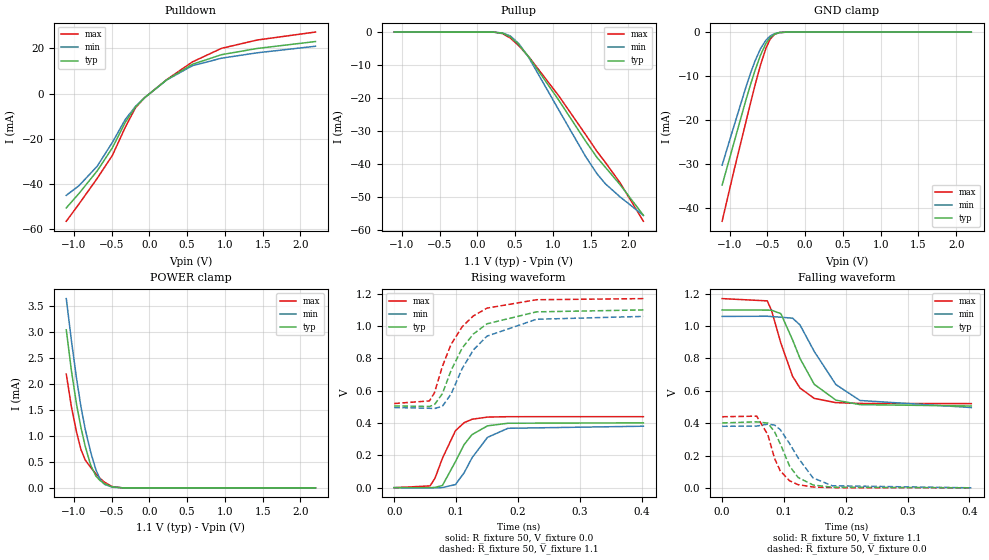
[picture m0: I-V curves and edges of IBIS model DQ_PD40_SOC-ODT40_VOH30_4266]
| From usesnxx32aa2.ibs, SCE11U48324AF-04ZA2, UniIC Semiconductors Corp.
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| DQ_PD40_SOC-ODT40_VOH30_4266
| (40 Ohm Pulldown, 40 Ohm System ODT Setting, VOH=VDDQ/3.0, 3200-4266Mbps)
[Model]   DQ_PD40_SOC-ODT40_VOH30_4266
Model_type   I/O
Vinl = 123.333mV
Vinh = 243.333mV
Vmeas = 183.333mV
Vref = 0.0mV
Cref = 0.0pF
Rref = 40.000Ohm
|   typ   min   max
|C_comp   0.797pF   0.747pF   0.847pF
C_comp_pullup   0.3985pF   0.3735pF   0.4235pF
C_comp_pulldown   0.3985pF   0.3735pF   0.4235pF
| Note: C_comp changes when the ODT circuit is enabled.
[Model Spec]
| Input threshold voltage corners
Vinl   0.1233V   0.1167V   0.1350V
Vinh   0.2433V   0.2367V   0.2550V
| Measurement voltage corners
Vmeas   0.1833V   0.1767V   0.1950V
| Timing spec test load voltage corners
Vref   0.0000V   0.0000V   0.0000V
| Dynamic Overshoot Parameters from LPDDR4 Specification
D_overshoot_ampl_h   0.30   NA   NA
D_overshoot_ampl_l   0.30   NA   NA
D_overshoot_area_h   0.1n   NA   NA
D_overshoot_area_l   0.1n   NA   NA
[Receiver Thresholds]
Vth   = 0.1833V
Vth_min  = 0.1800V
Vth_max  = 0.1866V
Vinh_ac  = 0.060V
Vinh_dc  = 0.060V
Vinl_ac  = -0.060V
Vinl_dc  = -0.060V
Tslew_ac = 5.000ns |Not specified, so set to high value
Threshold_sensitivity = 0.1667
Reference_supply Pullup_ref
[Voltage Range]   1.1000V   1.0600V   1.1700V
[Pullup Reference]   1.1000V   1.0600V   1.1700V
| Junction Temperature (Ambient temp is 35C typ 95C min -40C max)
[Temperature Range]   50.0   110.0   -40.0
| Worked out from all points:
|   slope of the pulldown table from 0 to 0.165 V, typ, clamps not added: 36.9 ohm
|   slope of the pullup table from 0 to 0.165 V, typ, clamps not added: 13 kohm
|   GND clamp passes 1 mA (typ) near -0.45 V on its own axis
|   POWER clamp passes 1 mA (typ) near -0.88 V on its own axis
|   rising waveform, R_fixture 50, V_fixture 0.0: 20-80 % time 34.1ps typ, 38.1ps min, 29.6ps max; typ from 0.001 V to 0.401 V
|   falling waveform, R_fixture 50, V_fixture 1.1: 20-80 % time 45ps typ, 56.8ps min, 35.2ps max; typ from 1.1 V to 0.506 V
|   rising waveform, R_fixture 50, V_fixture 1.1: 20-80 % time 54.7ps typ, 58ps min, 50.4ps max; typ from 0.506 V to 1.1 V
|   falling waveform, R_fixture 50, V_fixture 0.0: 20-80 % time 30.5ps typ, 38.6ps min, 25.1ps max; typ from 0.402 V to 0.001 V
[Pulldown]
|   Voltage   I(typ)   I(min)   I(max)
-1.1V     -50.63mA   -45.08mA   -56.55mA
-931.7mV  -44.24mA   -40.8mA    -48.89mA
-690.8mV  -34.25mA   -32.2mA    -37.57mA
-489.5mV  -24.03mA   -21.64mA   -27.4mA
-317.9mV  -12.7mA    -11.44mA   -14.85mA
-182.6mV  -5.878mA   -5.686mA   -6.271mA
-63.8mV   -1.902mA   -1.889mA   -1.878mA
229.9mV   6.074mA    5.999mA    6.158mA
569.8mV   12.93mA    12.3mA     13.98mA
955.9mV   17.19mA    15.64mA    20mA
1.428V    19.94mA    18.02mA    23.68mA
2.2V      23.01mA    20.92mA    27.21mA
[GND Clamp]
|   Voltage   I(typ)   I(min)   I(max)
-1.1V     -34.88mA   -30.34mA   -43.13mA
-938.3mV  -24.92mA   -21.15mA   -31.24mA
-786.5mV  -15.59mA   -12.65mA   -20.59mA
-723.8mV  -11.98mA   -9.381mA   -16.18mA
-664.4mV  -8.768mA   -6.598mA   -12.12mA
-591.8mV  -5.271mA   -3.798mA   -7.524mA
-519.2mV  -2.572mA   -1.839mA   -3.672mA
-466.4mV  -1.299mA   -945.1uA   -1.693mA
-407mV    -503.4uA   -374.2uA   -541.5uA
-341mV    -134.1uA   -102.3uA   -114.6uA
-232.1mV  -7.507uA   -7.153uA   -3.987uA
2.2V      0A         0A         0A
[Pullup]
|   Voltage   I(typ)   I(min)   I(max)
-1.1V     6.284uA    9.684uA    2.832uA
226.6mV   -42.49uA   -43.11uA   -42.83uA
335.5mV   -341.1uA   -283.4uA   -469.8uA
437.8mV   -1.438mA   -1.179mA   -1.809mA
550mV     -3.801mA   -3.492mA   -4.138mA
682mV     -7.523mA   -7.706mA   -7.473mA
1.078V    -20.57mA   -23.52mA   -19.26mA
1.434V    -32.99mA   -37.64mA   -31.01mA
1.586V    -37.97mA   -42.9mA    -36.14mA
1.698V    -40.96mA   -45.96mA   -39.5mA
1.893V    -46.24mA   -49.93mA   -45.68mA
2.2V      -55.46mA   -55.5mA    -57.28mA
[POWER Clamp]
|   Voltage   I(typ)   I(min)   I(max)
-1.1V     3.036mA    3.636mA    2.186mA
-1.031V   2.241mA    2.818mA    1.547mA
-964.7mV  1.61mA     2.107mA    1.073mA
-905.3mV  1.155mA    1.555mA    732.4uA
-849.2mV  799.3uA    1.126mA    535.5uA
-776.6mV  434.2uA    683.5uA    390.2uA
-707.3mV  225.6uA    345.4uA    267.6uA
-654.5mV  142.7uA    170.5uA    185.9uA
-595.1mV  80.77uA    68.3uA     109.3uA
-492.8mV  18.95uA    11.55uA    24.07uA
-360.8mV  1.023uA    778nA      803.1nA
2.2V      0A         0A         0A
[Ramp]
|   typ   min   max
| 20% - 80%
dV/dt_r   240.53m/34.08p   228.08m/38.10p   263.57m/29.60p
dV/dt_f   356.25m/45.04p   337.96m/56.80p   389.47m/35.24p
| 25% - 75%
|dV/dt_r   200.44m/27.14p   190.07m/30.34p   219.65m/23.43p
|dV/dt_f   296.88m/35.94p   281.63m/45.36p   324.56m/28.04p
R_load = 50
[Rising Waveform]
R_fixture = 50
V_fixture = 0.0
|   Time   V(typ)   V(min)   V(max)
0s        552uV      472.8uV    402uV
58ps      324.9uV    -47.1uV    11.28mV
66ps      2.285mV    -594.8uV   58.93mV
78ps      13.98mV    984.2uV    182.4mV
99ps      161mV      19.65mV    352.3mV
113ps     266.6mV    92mV       402.2mV
126ps     329.2mV    186mV      423.8mV
151ps     382.9mV    311.9mV    437.1mV
184ps     399mV      367.7mV    439.5mV
403ps     401.4mV    380.6mV    439.7mV
[Falling Waveform]
R_fixture   = 50
V_fixture   = 1.1
V_fixture_min = 1.06
V_fixture_max = 1.17
|   Time   V(typ)   V(min)   V(max)
0s        1.1V       1.06V      1.17V
73ps      1.099V     1.061V     1.156V
80ps      1.098V     1.059V     1.096V
95ps      1.077V     1.055V     894.7mV
114ps     914.4mV    1.049V     689.6mV
126ps     799.7mV    1.007V     617.1mV
149ps     640.4mV    843.4mV    553.2mV
184ps     542.5mV    638.7mV    527mV
223ps     514.6mV    540.3mV    521.9mV
403ps     506.2mV    496.7mV    520.9mV
[Rising Waveform]
R_fixture   = 50
V_fixture   = 1.1
V_fixture_min = 1.06
V_fixture_max = 1.17
|   Time   V(typ)   V(min)   V(max)
0s        506.1mV    496.4mV    520.9mV
57ps      502.9mV    491.6mV    537.1mV
65ps      513mV      489.4mV    586.4mV
78ps      582.2mV    504.2mV    751.5mV
92ps      725.8mV    579.7mV    887.1mV
110ps     864.4mV    737.4mV    996.2mV
128ps     950.8mV    852.1mV    1.063V
150ps     1.014V     937.6mV    1.111V
230ps     1.088V     1.042V     1.163V
403ps     1.1V       1.06V      1.17V
[Falling Waveform]
R_fixture = 50
V_fixture = 0.0
|   Time   V(typ)   V(min)   V(max)
0s        401.5mV    380.8mV    439.8mV
56ps      408.2mV    382.1mV    443.5mV
74ps      400.5mV    394.3mV    328.1mV
85ps      345.4mV    388.2mV    180.8mV
94ps      273mV      360.3mV    105.9mV
109ps     135.8mV    274.6mV    44.05mV
123ps     64.01mV    185.3mV    19.98mV
147ps     18mV       62mV       5.51mV
178ps     4.155mV    13.24mV    1.377mV
403ps     604uV      548.3uV    424.2uV
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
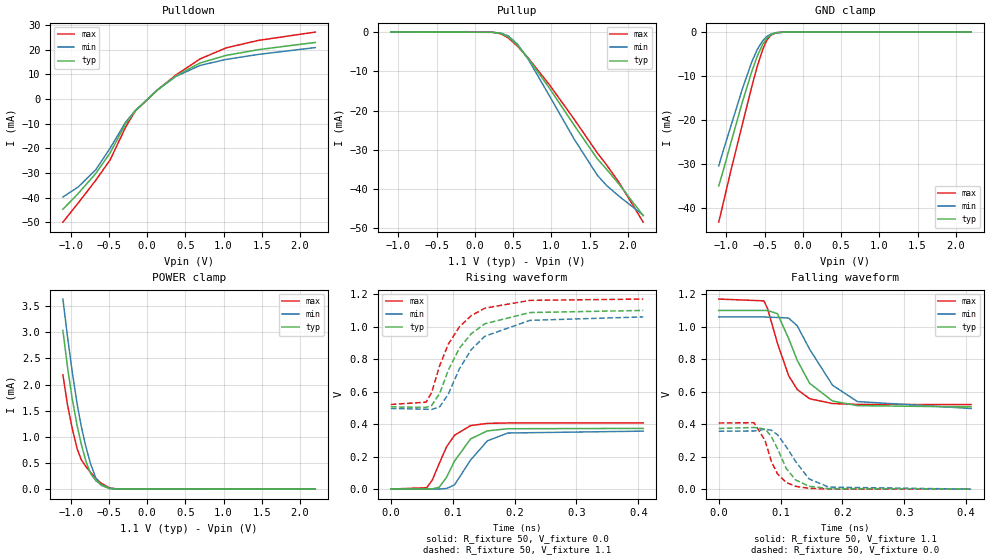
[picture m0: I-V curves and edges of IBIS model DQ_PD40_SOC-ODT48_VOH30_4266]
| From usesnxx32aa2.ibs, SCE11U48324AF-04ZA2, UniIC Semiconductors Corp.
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| DQ_PD40_SOC-ODT48_VOH30_4266
| (40 Ohm Pulldown, 48 Ohm System ODT Setting, VOH=VDDQ/3.0, 3200-4266Mbps)
[Model]   DQ_PD40_SOC-ODT48_VOH30_4266
Model_type   I/O
Vinl = 123.333mV
Vinh = 243.333mV
Vmeas = 183.333mV
Vref = 0.0mV
Cref = 0.0pF
Rref = 48.000Ohm
|   typ   min   max
|C_comp   0.797pF   0.747pF   0.847pF
C_comp_pullup   0.3985pF   0.3735pF   0.4235pF
C_comp_pulldown   0.3985pF   0.3735pF   0.4235pF
| Note: C_comp changes when the ODT circuit is enabled.
[Model Spec]
| Input threshold voltage corners
Vinl   0.1233V   0.1167V   0.1350V
Vinh   0.2433V   0.2367V   0.2550V
| Measurement voltage corners
Vmeas   0.1833V   0.1767V   0.1950V
| Timing spec test load voltage corners
Vref   0.0000V   0.0000V   0.0000V
| Dynamic Overshoot Parameters from LPDDR4 Specification
D_overshoot_ampl_h   0.30   NA   NA
D_overshoot_ampl_l   0.30   NA   NA
D_overshoot_area_h   0.1n   NA   NA
D_overshoot_area_l   0.1n   NA   NA
[Receiver Thresholds]
Vth   = 0.1833V
Vth_min  = 0.1800V
Vth_max  = 0.1866V
Vinh_ac  = 0.060V
Vinh_dc  = 0.060V
Vinl_ac  = -0.060V
Vinl_dc  = -0.060V
Tslew_ac = 5.000ns |Not specified, so set to high value
Threshold_sensitivity = 0.1667
Reference_supply Pullup_ref
[Voltage Range]   1.1000V   1.0600V   1.1700V
[Pullup Reference]   1.1000V   1.0600V   1.1700V
| Junction Temperature (Ambient temp is 35C typ 95C min -40C max)
[Temperature Range]   50.0   110.0   -40.0
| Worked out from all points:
|   slope of the pulldown table from 0 to 0.165 V, typ, clamps not added: 36.9 ohm
|   slope of the pullup table from 0 to 0.165 V, typ, clamps not added: 15.6 kohm
|   GND clamp passes 1 mA (typ) near -0.45 V on its own axis
|   POWER clamp passes 1 mA (typ) near -0.88 V on its own axis
|   rising waveform, R_fixture 50, V_fixture 0.0: 20-80 % time 35.5ps typ, 39.8ps min, 31.3ps max; typ from 0 V to 0.374 V
|   falling waveform, R_fixture 50, V_fixture 1.1: 20-80 % time 44.9ps typ, 56.6ps min, 35.1ps max; typ from 1.1 V to 0.506 V
|   rising waveform, R_fixture 50, V_fixture 1.1: 20-80 % time 54.9ps typ, 58.4ps min, 50.5ps max; typ from 0.506 V to 1.1 V
|   falling waveform, R_fixture 50, V_fixture 0.0: 20-80 % time 30.3ps typ, 38.5ps min, 24.9ps max; typ from 0.374 V to 0.001 V
[Pulldown]
|   Voltage   I(typ)   I(min)   I(max)
-1.1V     -44.75mA   -39.77mA   -50mA
-902mV    -38.42mA   -35.75mA   -42.29mA
-671mV    -30.26mA   -28.72mA   -33.02mA
-482.9mV  -21.87mA   -19.96mA   -24.7mA
-278.3mV  -9.972mA   -9.272mA   -11.31mA
-156.2mV  -4.822mA   -4.735mA   -4.963mA
137.5mV   3.741mA    3.714mA    3.748mA
375.1mV   9.367mA    9.149mA    9.729mA
695.2mV   14.68mA    13.69mA    16.33mA
1.035V    17.75mA    16.11mA    20.81mA
1.458V    20.08mA    18.15mA    23.85mA
2.2V      23.01mA    20.92mA    27.21mA
[GND Clamp]
|   Voltage   I(typ)   I(min)   I(max)
-1.1V     -34.88mA   -30.35mA   -43.13mA
-1.047V   -31.79mA   -27.25mA   -39.23mA
-941.6mV  -25.13mA   -21.34mA   -31.48mA
-789.8mV  -15.79mA   -12.83mA   -20.82mA
-667.7mV  -8.939mA   -6.742mA   -12.34mA
-595.1mV  -5.415mA   -3.908mA   -7.721mA
-525.8mV  -2.776mA   -1.982mA   -3.978mA
-473mV    -1.427mA   -1.034mA   -1.891mA
-416.9mV  -602.3uA   -443.1uA   -664.2uA
-350.9mV  -167uA     -127uA     -146.8uA
-235.4mV  -8.314uA   -7.865uA   -4.406uA
2.2V      0A         0A         0A
[Pullup]
|   Voltage   I(typ)   I(min)   I(max)
-1.1V     5.237uA    8.07uA     2.361uA
229.9mV   -37.74uA   -38.67uA   -38.87uA
345.4mV   -338.1uA   -276.7uA   -463.3uA
441.1mV   -1.249mA   -1.027mA   -1.564mA
556.6mV   -3.33mA    -3.082mA   -3.598mA
698.5mV   -6.745mA   -6.992mA   -6.645mA
975.7mV   -14.36mA   -16.29mA   -13.47mA
1.302V    -23.86mA   -27.41mA   -22.33mA
1.599V    -32.26mA   -36.44mA   -30.76mA
1.718V    -34.88mA   -39.02mA   -33.75mA
1.89V     -38.9mA    -41.91mA   -38.47mA
2.2V      -46.77mA   -46.64mA   -48.43mA
[POWER Clamp]
|   Voltage   I(typ)   I(min)   I(max)
-1.1V     3.036mA    3.636mA    2.186mA
-1.041V   2.347mA    2.931mA    1.626mA
-977.9mV  1.724mA    2.242mA    1.161mA
-911.9mV  1.201mA    1.612mA    764.9uA
-859.1mV  857.7uA    1.196mA    561.5uA
-799.7mV  537uA      814.2uA    433.5uA
-740.3mV  306uA      494.6uA    324.3uA
-667.7mV  159.9uA    206.1uA    205.2uA
-598.4mV  83.69uA    71.98uA    113.1uA
-489.5mV  17.77uA    10.88uA    22.46uA
-367.4mV  1.206uA    882.7nA    945.9nA
2.2V      0A         0A         0A
[Ramp]
|   typ   min   max
| 20% - 80%
dV/dt_r   223.90m/35.46p   213.85m/39.83p   244.14m/31.25p
dV/dt_f   356.25m/44.91p   337.96m/56.63p   389.46m/35.14p
| 25% - 75%
|dV/dt_r   186.58m/28.28p   178.21m/31.81p   203.45m/24.74p
|dV/dt_f   296.88m/35.84p   281.63m/45.22p   324.55m/27.97p
R_load = 50
[Rising Waveform]
R_fixture = 50
V_fixture = 0.0
|   Time   V(typ)   V(min)   V(max)
0s        456.7uV    387.9uV    333.9uV
58ps      167.4uV    71.29uV    8.2mV
67ps      1.536mV    -515.2uV   55.39mV
78ps      10.94mV    268.4uV    155.1mV
90ps      71.57mV    3.334mV    259.2mV
103ps     172.9mV    26.05mV    331.8mV
129ps     309.1mV    179.2mV    391.1mV
156ps     358.2mV    296.8mV    404.6mV
189ps     371.6mV    345.2mV    407mV
408ps     373.6mV    356.8mV    407.2mV
[Falling Waveform]
R_fixture   = 50
V_fixture   = 1.1
V_fixture_min = 1.06
V_fixture_max = 1.17
|   Time   V(typ)   V(min)   V(max)
0s        1.1V       1.06V      1.17V
73ps      1.1V       1.06V      1.159V
79ps      1.1V       1.059V     1.111V
95ps      1.08V      1.057V     896.9mV
113ps     926.9mV    1.053V     698.6mV
127ps     792.4mV    1.005V     613.2mV
147ps     651.4mV    861mV      556.6mV
184ps     542.7mV    639.8mV    527.1mV
224ps     514.3mV    539.4mV    521.9mV
408ps     506.2mV    496.7mV    520.9mV
[Rising Waveform]
R_fixture   = 50
V_fixture   = 1.1
V_fixture_min = 1.06
V_fixture_max = 1.17
|   Time   V(typ)   V(min)   V(max)
0s        506.1mV    496.4mV    520.9mV
57ps      502.9mV    491.8mV    535.3mV
66ps      514.7mV    489.7mV    593.9mV
79ps      589mV      506.5mV    760.5mV
93ps      732.6mV    585.3mV    892.6mV
111ps     868mV      741.6mV    999.6mV
130ps     956.5mV    858.8mV    1.068V
152ps     1.018V     941.2mV    1.114V
225ps     1.087V     1.039V     1.162V
408ps     1.1V       1.06V      1.17V
[Falling Waveform]
R_fixture = 50
V_fixture = 0.0
|   Time   V(typ)   V(min)   V(max)
0s        373.7mV    356.9mV    407.3mV
57ps      379.9mV    358.4mV    409.5mV
75ps      370.5mV    368.6mV    298.9mV
85ps      324.8mV    363.4mV    171.1mV
95ps      249.6mV    335.5mV    94.45mV
109ps     128.8mV    262.5mV    41.88mV
124ps     57.68mV    172.2mV    17.96mV
146ps     18.11mV    63.28mV    5.508mV
178ps     3.943mV    12.94mV    1.272mV
408ps     517.9uV    474uV      357.5uV
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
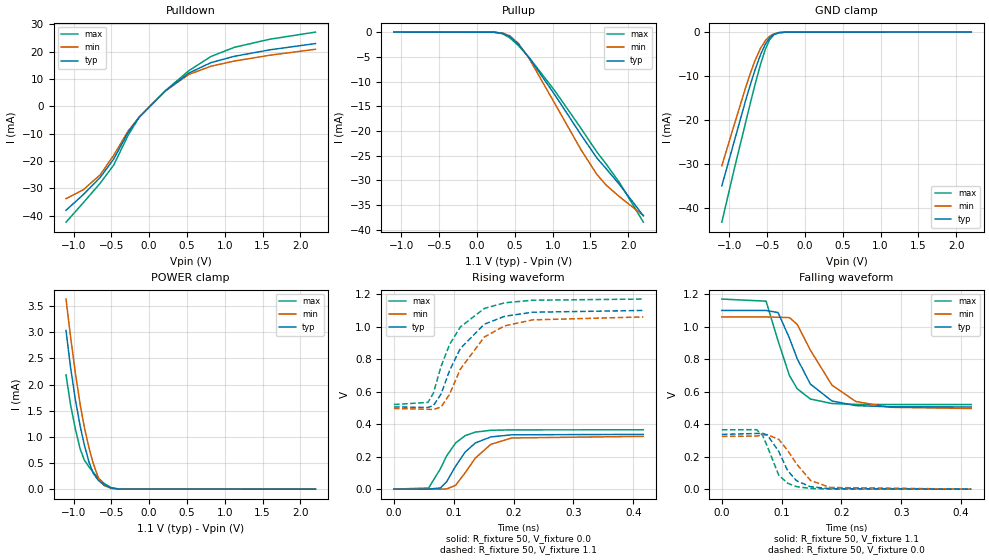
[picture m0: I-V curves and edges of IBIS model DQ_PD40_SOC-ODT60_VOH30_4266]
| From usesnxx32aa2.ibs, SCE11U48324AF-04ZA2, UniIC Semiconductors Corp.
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| DQ_PD40_SOC-ODT60_VOH30_4266
| (40 Ohm Pulldown, 60 Ohm System ODT Setting, VOH=VDDQ/3.0, 3200-4266Mbps)
[Model]   DQ_PD40_SOC-ODT60_VOH30_4266
Model_type   I/O
Vinl = 123.333mV
Vinh = 243.333mV
Vmeas = 183.333mV
Vref = 0.0mV
Cref = 0.0pF
Rref = 60.000Ohm
|   typ   min   max
|C_comp   0.797pF   0.747pF   0.847pF
C_comp_pullup   0.3985pF   0.3735pF   0.4235pF
C_comp_pulldown   0.3985pF   0.3735pF   0.4235pF
| Note: C_comp changes when the ODT circuit is enabled.
[Model Spec]
| Input threshold voltage corners
Vinl   0.1233V   0.1167V   0.1350V
Vinh   0.2433V   0.2367V   0.2550V
| Measurement voltage corners
Vmeas   0.1833V   0.1767V   0.1950V
| Timing spec test load voltage corners
Vref   0.0000V   0.0000V   0.0000V
| Dynamic Overshoot Parameters from LPDDR4 Specification
D_overshoot_ampl_h   0.30   NA   NA
D_overshoot_ampl_l   0.30   NA   NA
D_overshoot_area_h   0.1n   NA   NA
D_overshoot_area_l   0.1n   NA   NA
[Receiver Thresholds]
Vth   = 0.1833V
Vth_min  = 0.1800V
Vth_max  = 0.1866V
Vinh_ac  = 0.060V
Vinh_dc  = 0.060V
Vinl_ac  = -0.060V
Vinl_dc  = -0.060V
Tslew_ac = 5.000ns |Not specified, so set to high value
Threshold_sensitivity = 0.1667
Reference_supply Pullup_ref
[Voltage Range]   1.1000V   1.0600V   1.1700V
[Pullup Reference]   1.1000V   1.0600V   1.1700V
| Junction Temperature (Ambient temp is 35C typ 95C min -40C max)
[Temperature Range]   50.0   110.0   -40.0
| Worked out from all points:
|   slope of the pulldown table from 0 to 0.165 V, typ, clamps not added: 36.9 ohm
|   slope of the pullup table from 0 to 0.165 V, typ, clamps not added: 19.5 kohm
|   GND clamp passes 1 mA (typ) near -0.45 V on its own axis
|   POWER clamp passes 1 mA (typ) near -0.88 V on its own axis
|   rising waveform, R_fixture 50, V_fixture 0.0: 20-80 % time 38.7ps typ, 42.6ps min, 34ps max; typ from 0 V to 0.337 V
|   falling waveform, R_fixture 50, V_fixture 1.1: 20-80 % time 44.8ps typ, 56.5ps min, 35ps max; typ from 1.1 V to 0.506 V
|   rising waveform, R_fixture 50, V_fixture 1.1: 20-80 % time 55.1ps typ, 59ps min, 50.6ps max; typ from 0.506 V to 1.1 V
|   falling waveform, R_fixture 50, V_fixture 0.0: 20-80 % time 29.9ps typ, 38.5ps min, 24.7ps max; typ from 0.337 V to 0 V
[Pulldown]
|   Voltage   I(typ)   I(min)   I(max)
-1.1V     -38.06mA   -33.82mA   -42.42mA
-872.3mV  -32.35mA   -30.55mA   -35.34mA
-647.9mV  -26.03mA   -25.08mA   -28.14mA
-469.7mV  -19.32mA   -17.94mA   -21.52mA
-278.3mV  -9.551mA   -9.031mA   -10.59mA
-133.1mV  -3.99mA    -3.961mA   -4.019mA
213.4mV   5.67mA     5.605mA    5.735mA
523.6mV   12.17mA    11.67mA    13.04mA
817.3mV   16.02mA    14.71mA    18.26mA
1.127V    18.34mA    16.61mA    21.63mA
1.599V    20.72mA    18.74mA    24.61mA
2.2V      23.01mA    20.92mA    27.21mA
[GND Clamp]
|   Voltage   I(typ)   I(min)   I(max)
-1.1V     -34.88mA   -30.34mA   -43.13mA
-941.6mV  -25.13mA   -21.34mA   -31.48mA
-786.5mV  -15.59mA   -12.65mA   -20.59mA
-720.5mV  -11.79mA   -9.218mA   -15.95mA
-661.1mV  -8.597mA   -6.455mA   -11.9mA
-588.5mV  -5.128mA   -3.689mA   -7.328mA
-522.5mV  -2.673mA   -1.908mA   -3.822mA
-469.7mV  -1.361mA   -989uA     -1.79mA
-413.6mV  -565.3uA   -419uA     -621.8uA
-347.6mV  -154.7uA   -117.8uA   -135.4uA
-251.9mV  -13.27uA   -12.05uA   -7.883uA
2.2V      0A         0A         0A
[Pullup]
|   Voltage   I(typ)   I(min)   I(max)
-1.1V     4.189uA    6.456uA    1.888uA
226.6mV   -28.16uA   -28.72uA   -28.57uA
338.8mV   -240.5uA   -199uA     -331.4uA
434.5mV   -926.4uA   -757uA     -1.172mA
546.7mV   -2.491mA   -2.281mA   -2.719mA
688.6mV   -5.181mA   -5.337mA   -5.127mA
1.032V    -12.75mA   -14.54mA   -11.93mA
1.375V    -20.76mA   -23.78mA   -19.46mA
1.586V    -25.47mA   -28.79mA   -24.26mA
1.708V    -27.61mA   -30.94mA   -26.67mA
1.887V    -30.87mA   -33.32mA   -30.49mA
2.2V      -37.14mA   -37.08mA   -38.43mA
[POWER Clamp]
|   Voltage   I(typ)   I(min)   I(max)
-1.1V     3.036mA    3.636mA    2.186mA
-1.041V   2.347mA    2.931mA    1.626mA
-977.9mV  1.724mA    2.242mA    1.161mA
-911.9mV  1.201mA    1.612mA    765uA
-855.8mV  838.1uA    1.172mA    552.2uA
-793.1mV  506.1uA    776.1uA    421uA
-740.3mV  306.1uA    494.5uA    324.3uA
-671mV    164.5uA    215.9uA    210.2uA
-598.4mV  83.67uA    71.97uA    113uA
-502.7mV  22.59uA    14.08uA    29.27uA
-397.1mV  2.384uA    1.603uA    2.113uA
2.2V      0A         0A         0A
[Ramp]
|   typ   min   max
| 20% - 80%
dV/dt_r   202.04m/38.70p   194.78m/42.60p   219.09m/34.00p
dV/dt_f   356.26m/44.80p   337.98m/56.46p   389.46m/35.05p
| 25% - 75%
|dV/dt_r   168.37m/30.87p   162.32m/34.03p   182.58m/26.96p
|dV/dt_f   296.88m/35.75p   281.65m/45.09p   324.55m/27.89p
R_load = 50
[Rising Waveform]
R_fixture = 50
V_fixture = 0.0
|   Time   V(typ)   V(min)   V(max)
0s        358.8uV    298.7uV    264.1uV
58ps      85.48uV    119uV      7.079mV
78ps      7.978mV    -35.59uV   127.3mV
88ps      45.03mV    1.331mV    204mV
103ps     140.8mV    23.2mV     283.8mV
119ps     227.9mV    100.5mV    329.2mV
136ps     284mV      190.9mV    351.1mV
162ps     321.6mV    275.8mV    362.3mV
197ps     334.6mV    315.2mV    365mV
417ps     337.1mV    324.9mV    365.4mV
[Falling Waveform]
R_fixture   = 50
V_fixture   = 1.1
V_fixture_min = 1.06
V_fixture_max = 1.17
|   Time   V(typ)   V(min)   V(max)
0s        1.1V       1.06V      1.17V
74ps      1.1V       1.06V      1.157V
94ps      1.087V     1.058V     912.5mV
113ps     929.3mV    1.056V     699.5mV
126ps     803.1mV    1.014V     618.1mV
148ps     647mV      855.8mV    555.1mV
184ps     542.9mV    640.7mV    527.1mV
224ps     514.4mV    539.6mV    521.9mV
281ps     507.2mV    503.9mV    521mV
417ps     506.2mV    496.7mV    520.9mV
[Rising Waveform]
R_fixture   = 50
V_fixture   = 1.1
V_fixture_min = 1.06
V_fixture_max = 1.17
|   Time   V(typ)   V(min)   V(max)
0s        506.1mV    496.4mV    520.9mV
57ps      502.9mV    491.9mV    534.1mV
66ps      514.1mV    489.8mV    591.5mV
79ps      587mV      506.2mV    757.5mV
93ps      729.8mV    583.7mV    889.9mV
111ps     865.6mV    738.4mV    998mV
151ps     1.015V     936mV      1.112V
185ps     1.064V     1.005V     1.147V
232ps     1.089V     1.042V     1.163V
417ps     1.1V       1.06V      1.17V
[Falling Waveform]
R_fixture = 50
V_fixture = 0.0
|   Time   V(typ)   V(min)   V(max)
0s        337.2mV    325mV      365.5mV
58ps      343mV      327mV      366.5mV
68ps      344.1mV    332.5mV    332mV
76ps      333.7mV    335.3mV    263.8mV
95ps      233.6mV    307mV      87.28mV
110ps     114.8mV    238.7mV    36.71mV
125ps     51.58mV    155.6mV    15.81mV
148ps     15.49mV    54.34mV    4.619mV
181ps     3.261mV    10.79mV    1.047mV
417ps     428.1uV    394.6uV    289.9uV
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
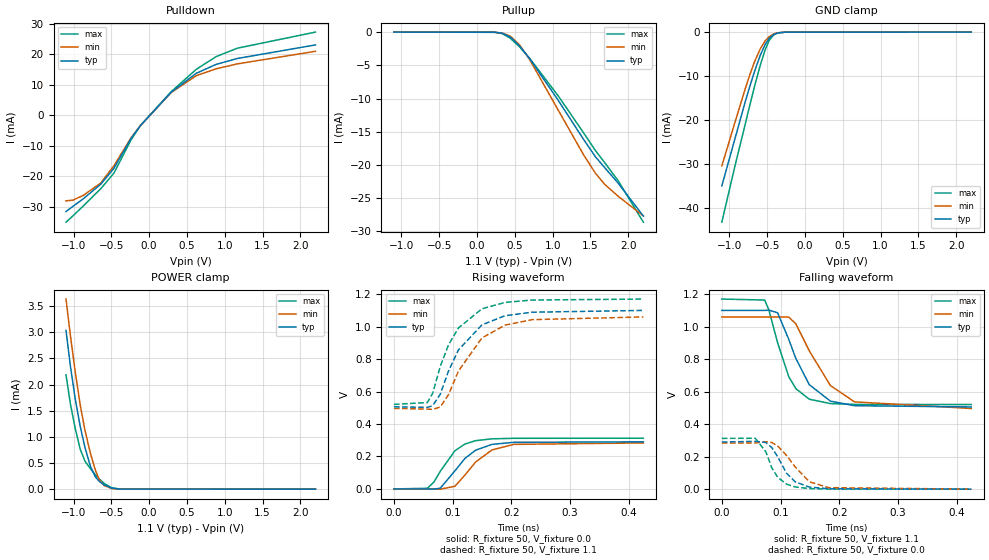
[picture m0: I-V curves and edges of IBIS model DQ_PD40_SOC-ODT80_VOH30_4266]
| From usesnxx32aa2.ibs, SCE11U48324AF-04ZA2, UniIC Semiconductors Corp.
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| DQ_PD40_SOC-ODT80_VOH30_4266
| (40 Ohm Pulldown, 80 Ohm System ODT Setting, VOH=VDDQ/3.0, 3200-4266Mbps)
[Model]   DQ_PD40_SOC-ODT80_VOH30_4266
Model_type   I/O
Vinl = 123.333mV
Vinh = 243.333mV
Vmeas = 183.333mV
Vref = 0.0mV
Cref = 0.0pF
Rref = 80.000Ohm
|   typ   min   max
|C_comp   0.797pF   0.747pF   0.847pF
C_comp_pullup   0.3985pF   0.3735pF   0.4235pF
C_comp_pulldown   0.3985pF   0.3735pF   0.4235pF
| Note: C_comp changes when the ODT circuit is enabled.
[Model Spec]
| Input threshold voltage corners
Vinl   0.1233V   0.1167V   0.1350V
Vinh   0.2433V   0.2367V   0.2550V
| Measurement voltage corners
Vmeas   0.1833V   0.1767V   0.1950V
| Timing spec test load voltage corners
Vref   0.0000V   0.0000V   0.0000V
| Dynamic Overshoot Parameters from LPDDR4 Specification
D_overshoot_ampl_h   0.30   NA   NA
D_overshoot_ampl_l   0.30   NA   NA
D_overshoot_area_h   0.1n   NA   NA
D_overshoot_area_l   0.1n   NA   NA
[Receiver Thresholds]
Vth   = 0.1833V
Vth_min  = 0.1800V
Vth_max  = 0.1866V
Vinh_ac  = 0.060V
Vinh_dc  = 0.060V
Vinl_ac  = -0.060V
Vinl_dc  = -0.060V
Tslew_ac = 5.000ns |Not specified, so set to high value
Threshold_sensitivity = 0.1667
Reference_supply Pullup_ref
[Voltage Range]   1.1000V   1.0600V   1.1700V
[Pullup Reference]   1.1000V   1.0600V   1.1700V
| Junction Temperature (Ambient temp is 35C typ 95C min -40C max)
[Temperature Range]   50.0   110.0   -40.0
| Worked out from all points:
|   slope of the pulldown table from 0 to 0.165 V, typ, clamps not added: 36.9 ohm
|   slope of the pullup table from 0 to 0.165 V, typ, clamps not added: 26 kohm
|   GND clamp passes 1 mA (typ) near -0.45 V on its own axis
|   POWER clamp passes 1 mA (typ) near -0.88 V on its own axis
|   rising waveform, R_fixture 50, V_fixture 0.0: 20-80 % time 42.1ps typ, 45.2ps min, 36.8ps max; typ from 0 V to 0.29 V
|   falling waveform, R_fixture 50, V_fixture 1.1: 20-80 % time 44.7ps typ, 56.3ps min, 35ps max; typ from 1.1 V to 0.506 V
|   rising waveform, R_fixture 50, V_fixture 1.1: 20-80 % time 55.3ps typ, 59.5ps min, 50.7ps max; typ from 0.506 V to 1.1 V
|   falling waveform, R_fixture 50, V_fixture 0.0: 20-80 % time 30.3ps typ, 39ps min, 25.2ps max; typ from 0.29 V to 0 V
[Pulldown]
|   Voltage   I(typ)   I(min)   I(max)
-1.1V     -31.52mA   -28.01mA   -35mA
-1.011V   -29.86mA   -27.81mA   -33mA
-872.3mV  -27.36mA   -26.24mA   -29.72mA
-641.3mV  -22.59mA   -22.22mA   -24.08mA
-466.4mV  -17.39mA   -16.53mA   -18.96mA
-235.4mV  -7.426mA   -7.242mA   -7.866mA
-113.3mV  -3.331mA   -3.326mA   -3.314mA
289.3mV   7.482mA    7.359mA    7.654mA
622.6mV   13.72mA    12.94mA    15.01mA
886.6mV   16.64mA    15.2mA     19.19mA
1.167V    18.57mA    16.81mA    21.94mA
2.2V      23.01mA    20.92mA    27.21mA
[GND Clamp]
|   Voltage   I(typ)   I(min)   I(max)
-1.1V     -34.88mA   -30.35mA   -43.13mA
-938.3mV  -24.92mA   -21.15mA   -31.24mA
-793.1mV  -15.98mA   -13.01mA   -21.06mA
-727.1mV  -12.16mA   -9.546mA   -16.41mA
-667.7mV  -8.939mA   -6.743mA   -12.34mA
-591.8mV  -5.272mA   -3.798mA   -7.524mA
-525.8mV  -2.773mA   -1.977mA   -3.976mA
-473mV    -1.423mA   -1.032mA   -1.891mA
-416.9mV  -597.6uA   -441.4uA   -666.1uA
-360.8mV  -205.8uA   -155.5uA   -188.7uA
-261.8mV  -17.63uA   -15.56uA   -10.94uA
2.2V      0A         0A         0A
[Pullup]
|   Voltage   I(typ)   I(min)   I(max)
-1.1V     3.142uA    4.844uA    1.416uA
229.9mV   -22.58uA   -22.99uA   -23.29uA
332.2mV   -161.5uA   -135.6uA   -221.5uA
437.8mV   -720.8uA   -590.6uA   -907.1uA
556.6mV   -1.993mA   -1.844mA   -2.153mA
691.9mV   -3.931mA   -4.057mA   -3.886mA
1.075V    -10.29mA   -11.77mA   -9.621mA
1.411V    -16.18mA   -18.5mA    -15.19mA
1.566V    -18.77mA   -21.24mA   -17.83mA
1.688V    -20.39mA   -22.91mA   -19.64mA
1.867V    -22.74mA   -24.71mA   -22.38mA
2.2V      -27.69mA   -27.67mA   -28.61mA
[POWER Clamp]
|   Voltage   I(typ)   I(min)   I(max)
-1.1V     3.036mA    3.636mA    2.186mA
-1.041V   2.347mA    2.931mA    1.626mA
-977.9mV  1.724mA    2.243mA    1.161mA
-911.9mV  1.201mA    1.612mA    764.9uA
-849.2mV  799.3uA    1.127mA    535.5uA
-776.6mV  434.2uA    683.5uA    390.2uA
-710.6mV  232.2uA    359.2uA    273.1uA
-657.8mV  146.8uA    178.8uA    190.7uA
-595.1mV  80.78uA    68.29uA    109.3uA
-492.8mV  18.89uA    11.55uA    24.07uA
-383.9mV  1.738uA    1.217uA    1.471uA
2.2V      0A         0A         0A
[Ramp]
|   typ   min   max
| 20% - 80%
dV/dt_r   174.06m/42.09p   170.01m/45.16p   187.44m/36.77p
dV/dt_f   356.25m/44.68p   337.97m/56.30p   389.46m/34.97p
| 25% - 75%
|dV/dt_r   145.05m/33.59p   141.68m/36.05p   156.20m/29.14p
|dV/dt_f   296.88m/35.66p   281.65m/44.96p   324.55m/27.84p
R_load = 50
[Rising Waveform]
R_fixture = 50
V_fixture = 0.0
|   Time   V(typ)   V(min)   V(max)
0s        261.1uV    209.1uV    195.1uV
57ps      -182.7uV   324uV      3.944mV
68ps      -926.9uV   -621.4uV   41.94mV
79ps      4.783mV    -1.343mV   108.8mV
104ps     111.7mV    16.52mV    235.8mV
121ps     188mV      85.57mV    276.8mV
139ps     238.6mV    165.1mV    297.4mV
167ps     274.4mV    240.2mV    308.8mV
204ps     287.4mV    274.6mV    312mV
425ps     290.4mV    283.6mV    312.6mV
[Falling Waveform]
R_fixture   = 50
V_fixture   = 1.1
V_fixture_min = 1.06
V_fixture_max = 1.17
|   Time   V(typ)   V(min)   V(max)
0s        1.1V       1.06V      1.17V
73ps      1.1V       1.06V      1.164V
80ps      1.102V     1.059V     1.105V
95ps      1.086V     1.06V      901.7mV
114ps     922.3mV    1.059V     692.8mV
126ps     805.3mV    1.018V     619mV
149ps     643.1mV    851.2mV    553.8mV
185ps     541.9mV    637.9mV    526.8mV
226ps     513.9mV    537.4mV    521.8mV
425ps     506.2mV    496.7mV    520.9mV
[Rising Waveform]
R_fixture   = 50
V_fixture   = 1.1
V_fixture_min = 1.06
V_fixture_max = 1.17
|   Time   V(typ)   V(min)   V(max)
0s        506.1mV    496.4mV    520.9mV
57ps      502.8mV    492.1mV    532.4mV
66ps      512.8mV    489.8mV    588.7mV
79ps      584.1mV    504.9mV    755.1mV
93ps      726.5mV    580.9mV    887.9mV
110ps     856.9mV    726.9mV    992.1mV
150ps     1.011V     930.5mV    1.11V
189ps     1.067V     1.009V     1.149V
235ps     1.089V     1.043V     1.164V
425ps     1.1V       1.06V      1.17V
[Falling Waveform]
R_fixture = 50
V_fixture = 0.0
|   Time   V(typ)   V(min)   V(max)
0s        290.4mV    283.7mV    312.7mV
57ps      294.6mV    284.8mV    313.3mV
75ps      287.6mV    291.8mV    230.2mV
85ps      256.6mV    287.4mV    132.1mV
95ps      201mV      266.7mV    74mV
110ps     99.62mV    208.7mV    31.57mV
125ps     45.43mV    136.8mV    13.76mV
149ps     13.16mV    46.22mV    3.833mV
182ps     2.793mV    9.541mV    842.8uV
425ps     335.1uV    312.9uV    222.2uV
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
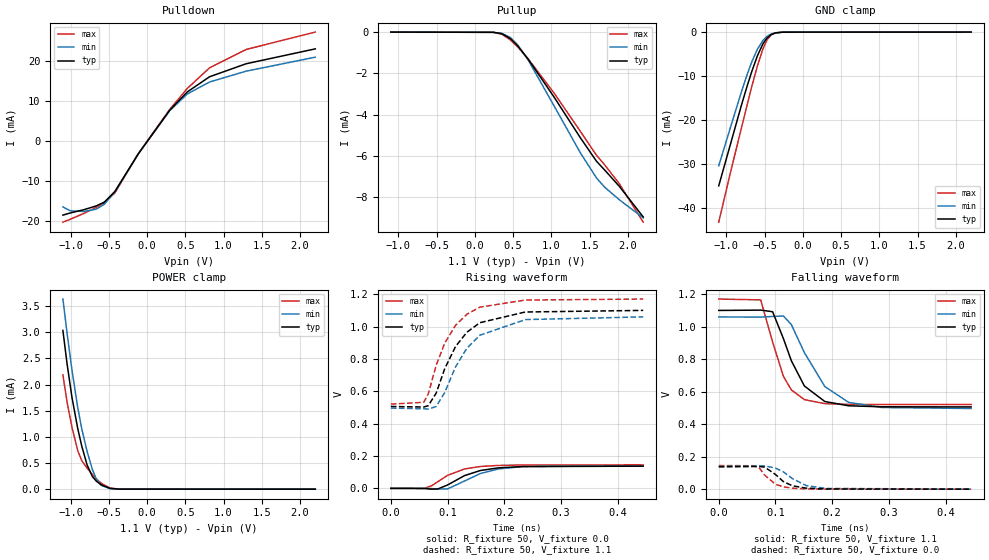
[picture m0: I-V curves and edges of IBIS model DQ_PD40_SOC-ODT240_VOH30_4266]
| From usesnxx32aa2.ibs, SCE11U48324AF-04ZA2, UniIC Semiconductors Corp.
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| DQ_PD40_SOC-ODT240_VOH30_4266
| (40 Ohm Pulldown, 240 Ohm System ODT Setting, VOH=VDDQ/3.0, 3200-4266Mbps)
[Model]   DQ_PD40_SOC-ODT240_VOH30_4266
Model_type   I/O
Vinl = 123.333mV
Vinh = 243.333mV
Vmeas = 183.333mV
Vref = 0.0mV
Cref = 0.0pF
Rref = 240.000Ohm
|   typ   min   max
|C_comp   0.797pF   0.747pF   0.847pF
C_comp_pullup   0.3985pF   0.3735pF   0.4235pF
C_comp_pulldown   0.3985pF   0.3735pF   0.4235pF
| Note: C_comp changes when the ODT circuit is enabled.
[Model Spec]
| Input threshold voltage corners
Vinl   0.1233V   0.1167V   0.1350V
Vinh   0.2433V   0.2367V   0.2550V
| Measurement voltage corners
Vmeas   0.1833V   0.1767V   0.1950V
| Timing spec test load voltage corners
Vref   0.0000V   0.0000V   0.0000V
| Dynamic Overshoot Parameters from LPDDR4 Specification
D_overshoot_ampl_h   0.30   NA   NA
D_overshoot_ampl_l   0.30   NA   NA
D_overshoot_area_h   0.1n   NA   NA
D_overshoot_area_l   0.1n   NA   NA
[Receiver Thresholds]
Vth   = 0.1833V
Vth_min  = 0.1800V
Vth_max  = 0.1866V
Vinh_ac  = 0.060V
Vinh_dc  = 0.060V
Vinl_ac  = -0.060V
Vinl_dc  = -0.060V
Tslew_ac = 5.000ns |Not specified, so set to high value
Threshold_sensitivity = 0.1667
Reference_supply Pullup_ref
[Voltage Range]   1.1000V   1.0600V   1.1700V
[Pullup Reference]   1.1000V   1.0600V   1.1700V
| Junction Temperature (Ambient temp is 35C typ 95C min -40C max)
[Temperature Range]   50.0   110.0   -40.0
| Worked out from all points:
|   slope of the pulldown table from 0 to 0.165 V, typ, clamps not added: 37 ohm
|   slope of the pullup table from 0 to 0.165 V, typ, clamps not added: 80.5 kohm
|   GND clamp passes 1 mA (typ) near -0.45 V on its own axis
|   POWER clamp passes 1 mA (typ) near -0.88 V on its own axis
|   rising waveform, R_fixture 50, V_fixture 0.0: 20-80 % time 54.2ps typ, 56.9ps min, 47.6ps max; typ from 0 V to 0.137 V
|   falling waveform, R_fixture 50, V_fixture 1.1: 20-80 % time 44.5ps typ, 55.9ps min, 34.8ps max; typ from 1.1 V to 0.506 V
|   rising waveform, R_fixture 50, V_fixture 1.1: 20-80 % time 55.6ps typ, 60.3ps min, 50.9ps max; typ from 0.506 V to 1.1 V
|   falling waveform, R_fixture 50, V_fixture 0.0: 20-80 % time 29.7ps typ, 37.9ps min, 25.6ps max; typ from 0.137 V to 0 V
[Pulldown]
|   Voltage   I(typ)   I(min)   I(max)
-1.1V     -18.63mA   -16.57mA   -20.4mA
-1.004V   -18.09mA   -17.55mA   -19.67mA
-829.4mV  -17.29mA   -17.71mA   -18.23mA
-667.7mV  -16.35mA   -17.15mA   -16.75mA
-558.8mV  -15.38mA   -15.93mA   -15.59mA
-420.2mV  -12.71mA   -12.75mA   -13.08mA
-113.3mV  -3.258mA   -3.277mA   -3.214mA
295.9mV   7.634mA    7.504mA    7.817mA
526.9mV   12.23mA    11.72mA    13.11mA
817.3mV   16.02mA    14.71mA    18.26mA
1.296V    19.28mA    17.43mA    22.86mA
2.2V      23.01mA    20.92mA    27.21mA
[GND Clamp]
|   Voltage   I(typ)   I(min)   I(max)
-1.1V     -34.88mA   -30.33mA   -43.13mA
-938.3mV  -24.92mA   -21.15mA   -31.24mA
-803mV    -16.57mA   -13.55mA   -21.76mA
-727.1mV  -12.16mA   -9.546mA   -16.41mA
-667.7mV  -8.939mA   -6.742mA   -12.34mA
-595.1mV  -5.415mA   -3.908mA   -7.721mA
-522.5mV  -2.672mA   -1.906mA   -3.823mA
-469.7mV  -1.36mA    -991.6uA   -1.79mA
-413.6mV  -565.6uA   -417.5uA   -621.3uA
-357.5mV  -191.4uA   -145.5uA   -173.5uA
-258.5mV  -16.16uA   -14.27uA   -9.827uA
2.2V      0A         0A         0A
[Pullup]
|   Voltage   I(typ)   I(min)   I(max)
-1.1V     1.047uA    1.615uA    471.8nA
239.8mV   -9.276uA   -9.187uA   -9.966uA
352mV     -74.44uA   -61.05uA   -102.7uA
464.2mV   -314.6uA   -264uA     -380.9uA
563.2mV   -685.4uA   -637.7uA   -737.4uA
698.5mV   -1.328mA   -1.371mA   -1.312mA
1.032V    -3.138mA   -3.566mA   -2.945mA
1.378V    -5.127mA   -5.857mA   -4.815mA
1.589V    -6.266mA   -7.078mA   -5.978mA
1.698V    -6.702mA   -7.534mA   -6.451mA
1.887V    -7.482mA   -8.134mA   -7.355mA
2.2V      -8.971mA   -9.016mA   -9.226mA
[POWER Clamp]
|   Voltage   I(typ)   I(min)   I(max)
-1.1V     3.036mA    3.636mA    2.186mA
-1.044V   2.383mA    2.969mA    1.654mA
-981.2mV  1.754mA    2.277mA    1.183mA
-905.3mV  1.155mA    1.554mA    732.6uA
-852.5mV  818.5uA    1.149mA    544uA
-783.2mV  462.1uA    720.1uA    402.5uA
-713.9mV  239.2uA    373.1uA    278.6uA
-661.1mV  151.1uA    187.6uA    195.5uA
-598.4mV  83.66uA    71.97uA    113.1uA
-482.9mV  15.72uA    9.5uA      19.49uA
-360.8mV  1.024uA    770.9nA    797nA
2.2V      0A         0A         0A
[Ramp]
|   typ   min   max
| 20% - 80%
dV/dt_r   82.42m/54.16p   84.18m/56.89p   87.18m/47.58p
dV/dt_f   356.26m/44.46p   338.03m/55.93p   389.46m/34.79p
| 25% - 75%
|dV/dt_r   68.68m/43.14p   70.15m/45.39p   72.65m/37.77p
|dV/dt_f   296.88m/35.52p   281.69m/44.71p   324.55m/27.71p
R_load = 50
[Rising Waveform]
R_fixture = 50
V_fixture = 0.0
|   Time   V(typ)   V(min)   V(max)
0s        63.94uV    30.42uV    54.25uV
60ps      -1.158mV   289.1uV    1.076mV
72ps      -4.876mV   -1.418mV   16.22mV
83ps      -3.362mV   -4.179mV   41.51mV
100ps     20.98mV    -3.552mV   80.37mV
130ps     79.04mV    45.68mV    120.1mV
158ps     110.5mV    91.85mV    135.3mV
190ps     127mV      120.3mV    141.9mV
233ps     134.7mV    134.8mV    144.5mV
445ps     137.4mV    140.3mV    145.4mV
[Falling Waveform]
R_fixture   = 50
V_fixture   = 1.1
V_fixture_min = 1.06
V_fixture_max = 1.17
|   Time   V(typ)   V(min)   V(max)
0s        1.1V       1.06V      1.17V
74ps      1.102V     1.059V     1.165V
95ps      1.092V     1.063V     905.7mV
114ps     927mV      1.066V     694.7mV
128ps     790.7mV    1.013V     610.9mV
151ps     635mV      840.5mV    551.2mV
187ps     539.6mV    631.6mV    526.4mV
229ps     513.2mV    534.2mV    521.7mV
287ps     507.1mV    502.8mV    521mV
445ps     506.2mV    496.6mV    520.9mV
[Rising Waveform]
R_fixture   = 50
V_fixture   = 1.1
V_fixture_min = 1.06
V_fixture_max = 1.17
|   Time   V(typ)   V(min)   V(max)
0s        506.1mV    496.4mV    520.9mV
58ps      502.8mV    492mV      531.8mV
66ps      511mV      490.1mV    583.4mV
80ps      588.7mV    506.1mV    760.2mV
95ps      739.5mV    592.3mV    897.5mV
114ps     876mV      750.2mV    1.007V
134ps     964.6mV    865.3mV    1.076V
157ps     1.024V     946.5mV    1.12V
237ps     1.09V      1.043V     1.164V
445ps     1.1V       1.06V      1.17V
[Falling Waveform]
R_fixture = 50
V_fixture = 0.0
|   Time   V(typ)   V(min)   V(max)
0s        137.5mV    140.4mV    145.4mV
62ps      139.4mV    141.7mV    144.3mV
72ps      139.6mV    143.1mV    128.7mV
81ps      135.8mV    142.9mV    86.5mV
100ps     90.59mV    130.1mV    30.41mV
114ps     46.69mV    106.6mV    14.28mV
130ps     20.88mV    64.95mV    6.078mV
154ps     6.468mV    22.4mV     1.757mV
189ps     1.313mV    4.653mV    355.9uV
445ps     130.9uV    129.1uV    79.28uV
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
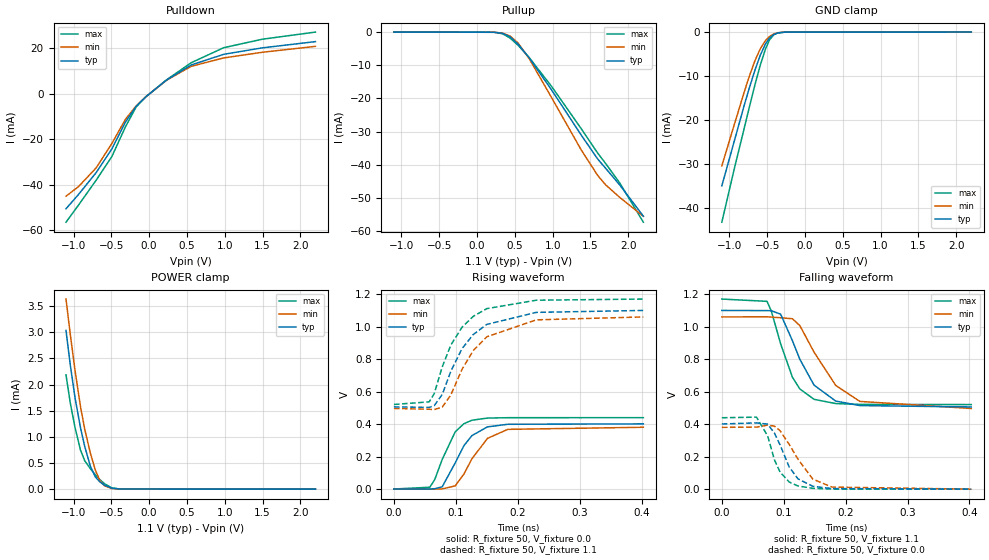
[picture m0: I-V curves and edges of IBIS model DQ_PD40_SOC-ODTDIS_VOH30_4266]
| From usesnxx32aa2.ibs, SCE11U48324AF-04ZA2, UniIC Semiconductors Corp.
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| DQ_PD40_SOC-ODTDIS_VOH30_4266
| (40 Ohm Pulldown, SOC ODT disabled setting, VOH=VDDQ/3.0 cal. point, 3200-4266Mbps)
[Model]   DQ_PD40_SOC-ODTDIS_VOH30_4266
Model_type   I/O
Vinl = 123.333mV
Vinh = 243.333mV
Vmeas = 183.333mV
Vref = 0.0mV
Cref = 0.0pF
|   typ   min   max
|C_comp   0.797pF   0.747pF   0.847pF
C_comp_pullup   0.3985pF   0.3735pF   0.4235pF
C_comp_pulldown   0.3985pF   0.3735pF   0.4235pF
| Note: C_comp changes when the ODT circuit is enabled.
[Model Spec]
| Input threshold voltage corners
Vinl   0.1233V   0.1167V   0.1350V
Vinh   0.2433V   0.2367V   0.2550V
| Measurement voltage corners
Vmeas   0.1833V   0.1767V   0.1950V
| Timing spec test load voltage corners
Vref   0.0000V   0.0000V   0.0000V
| Dynamic Overshoot Parameters from LPDDR4 Specification
D_overshoot_ampl_h   0.30   NA   NA
D_overshoot_ampl_l   0.30   NA   NA
D_overshoot_area_h   0.1n   NA   NA
D_overshoot_area_l   0.1n   NA   NA
[Receiver Thresholds]
Vth   = 0.1833V
Vth_min  = 0.1800V
Vth_max  = 0.1866V
Vinh_ac  = 0.060V
Vinh_dc  = 0.060V
Vinl_ac  = -0.060V
Vinl_dc  = -0.060V
Tslew_ac = 5.000ns |Not specified, so set to high value
Threshold_sensitivity = 0.1667
Reference_supply Pullup_ref
[Voltage Range]   1.1000V   1.0600V   1.1700V
[Pullup Reference]   1.1000V   1.0600V   1.1700V
| Junction Temperature (Ambient temp is 35C typ 95C min -40C max)
[Temperature Range]   50.0   110.0   -40.0
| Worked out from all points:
|   slope of the pulldown table from 0 to 0.165 V, typ, clamps not added: 36.9 ohm
|   slope of the pullup table from 0 to 0.165 V, typ, clamps not added: 13 kohm
|   GND clamp passes 1 mA (typ) near -0.45 V on its own axis
|   POWER clamp passes 1 mA (typ) near -0.88 V on its own axis
|   rising waveform, R_fixture 50, V_fixture 0.0: 20-80 % time 34.1ps typ, 38.1ps min, 29.6ps max; typ from 0.001 V to 0.401 V
|   falling waveform, R_fixture 50, V_fixture 1.1: 20-80 % time 45ps typ, 56.8ps min, 35.2ps max; typ from 1.1 V to 0.506 V
|   rising waveform, R_fixture 50, V_fixture 1.1: 20-80 % time 54.7ps typ, 58ps min, 50.4ps max; typ from 0.506 V to 1.1 V
|   falling waveform, R_fixture 50, V_fixture 0.0: 20-80 % time 30.5ps typ, 38.6ps min, 25.1ps max; typ from 0.402 V to 0.001 V
[Pulldown]
|   Voltage   I(typ)   I(min)   I(max)
-1.1V     -50.62mA   -45.08mA   -56.55mA
-938.3mV  -44.49mA   -41mA      -49.2mA
-700.7mV  -34.69mA   -32.61mA   -38.03mA
-492.8mV  -24.23mA   -21.84mA   -27.6mA
-314.6mV  -12.49mA   -11.27mA   -14.6mA
-172.7mV  -5.499mA   -5.344mA   -5.806mA
-44mV     -1.312mA   -1.304mA   -1.289mA
229.9mV   6.075mA    5.999mA    6.158mA
556.6mV   12.72mA    12.13mA    13.72mA
985.6mV   17.41mA    15.82mA    20.32mA
1.497V    20.26mA    18.32mA    24.07mA
2.2V      23.01mA    20.92mA    27.21mA
[GND Clamp]
|   Voltage   I(typ)   I(min)   I(max)
-1.1V     -34.88mA   -30.34mA   -43.13mA
-935mV    -24.71mA   -20.97mA   -31mA
-799.7mV  -16.37mA   -13.37mA   -21.52mA
-730.4mV  -12.35mA   -9.712mA   -16.64mA
-661.1mV  -8.597mA   -6.455mA   -11.9mA
-591.8mV  -5.271mA   -3.798mA   -7.524mA
-522.5mV  -2.671mA   -1.905mA   -3.824mA
-469.7mV  -1.359mA   -993.7uA   -1.79mA
-413.6mV  -565uA     -419uA     -621.3uA
-357.5mV  -191.7uA   -146uA     -173.7uA
-265.1mV  -19.39uA   -17.02uA   -12.35uA
2.2V      0A         0A         0A
[Pullup]
|   Voltage   I(typ)   I(min)   I(max)
-1.1V     6.284uA    9.684uA    2.832uA
226.6mV   -42.01uA   -43.23uA   -42.77uA
338.8mV   -360.8uA   -300.3uA   -496.4uA
437.8mV   -1.438mA   -1.181mA   -1.809mA
543.4mV   -3.636mA   -3.318mA   -3.984mA
688.6mV   -7.724mA   -7.945mA   -7.651mA
985.6mV   -17.42mA   -19.73mA   -16.35mA
1.378V    -31.03mA   -35.51mA   -29.11mA
1.596V    -38.25mA   -43.2mA    -36.46mA
1.698V    -40.96mA   -45.96mA   -39.5mA
1.887V    -46.05mA   -49.8mA    -45.45mA
2.2V      -55.46mA   -55.5mA    -57.28mA
[POWER Clamp]
|   Voltage   I(typ)   I(min)   I(max)
-1.1V     3.036mA    3.636mA    2.186mA
-1.044V   2.383mA    2.969mA    1.654mA
-981.2mV  1.754mA    2.277mA    1.183mA
-908.6mV  1.178mA    1.583mA    748.5uA
-852.5mV  818.6uA    1.149mA    543.6uA
-776.6mV  434.2uA    683.6uA    390.2uA
-710.6mV  232.3uA    359.1uA    273.1uA
-651.2mV  138.6uA    162.3uA    181.2uA
-591.8mV  77.92uA    64.88uA    105.5uA
-492.8mV  18.91uA    11.57uA    24.03uA
-377.3mV  1.489uA    1.071uA    1.229uA
2.2V      0A         0A         0A
[Ramp]
|   typ   min   max
| 20% - 80%
dV/dt_r   240.53m/34.08p   228.08m/38.10p   263.57m/29.60p
dV/dt_f   356.25m/45.04p   337.96m/56.80p   389.47m/35.24p
| 25% - 75%
|dV/dt_r   200.44m/27.14p   190.07m/30.34p   219.65m/23.43p
|dV/dt_f   296.88m/35.94p   281.63m/45.36p   324.56m/28.04p
R_load = 50
[Rising Waveform]
R_fixture = 50
V_fixture = 0.0
|   Time   V(typ)   V(min)   V(max)
0s        552uV      472.8uV    402uV
58ps      324.9uV    -47.1uV    11.28mV
66ps      2.285mV    -594.8uV   58.93mV
78ps      13.98mV    984.2uV    182.4mV
99ps      161mV      19.65mV    352.3mV
113ps     266.6mV    92mV       402.2mV
126ps     329.2mV    186mV      423.8mV
151ps     382.9mV    311.9mV    437.1mV
184ps     399mV      367.7mV    439.5mV
403ps     401.4mV    380.6mV    439.7mV
[Falling Waveform]
R_fixture   = 50
V_fixture   = 1.1
V_fixture_min = 1.06
V_fixture_max = 1.17
|   Time   V(typ)   V(min)   V(max)
0s        1.1V       1.06V      1.17V
73ps      1.099V     1.061V     1.156V
80ps      1.098V     1.059V     1.096V
95ps      1.077V     1.055V     894.7mV
114ps     914.4mV    1.049V     689.6mV
126ps     799.7mV    1.007V     617.1mV
149ps     640.4mV    843.4mV    553.2mV
184ps     542.5mV    638.7mV    527mV
223ps     514.6mV    540.3mV    521.9mV
403ps     506.2mV    496.7mV    520.9mV
[Rising Waveform]
R_fixture   = 50
V_fixture   = 1.1
V_fixture_min = 1.06
V_fixture_max = 1.17
|   Time   V(typ)   V(min)   V(max)
0s        506.1mV    496.4mV    520.9mV
57ps      502.9mV    491.6mV    537.1mV
65ps      513mV      489.4mV    586.4mV
78ps      582.2mV    504.2mV    751.5mV
92ps      725.8mV    579.7mV    887.1mV
110ps     864.4mV    737.4mV    996.2mV
128ps     950.8mV    852.1mV    1.063V
150ps     1.014V     937.6mV    1.111V
230ps     1.088V     1.042V     1.163V
403ps     1.1V       1.06V      1.17V
[Falling Waveform]
R_fixture = 50
V_fixture = 0.0
|   Time   V(typ)   V(min)   V(max)
0s        401.5mV    380.8mV    439.8mV
56ps      408.2mV    382.1mV    443.5mV
74ps      400.5mV    394.3mV    328.1mV
85ps      345.4mV    388.2mV    180.8mV
94ps      273mV      360.3mV    105.9mV
109ps     135.8mV    274.6mV    44.05mV
123ps     64.01mV    185.3mV    19.98mV
147ps     18mV       62mV       5.51mV
178ps     4.155mV    13.24mV    1.377mV
403ps     604uV      548.3uV    424.2uV
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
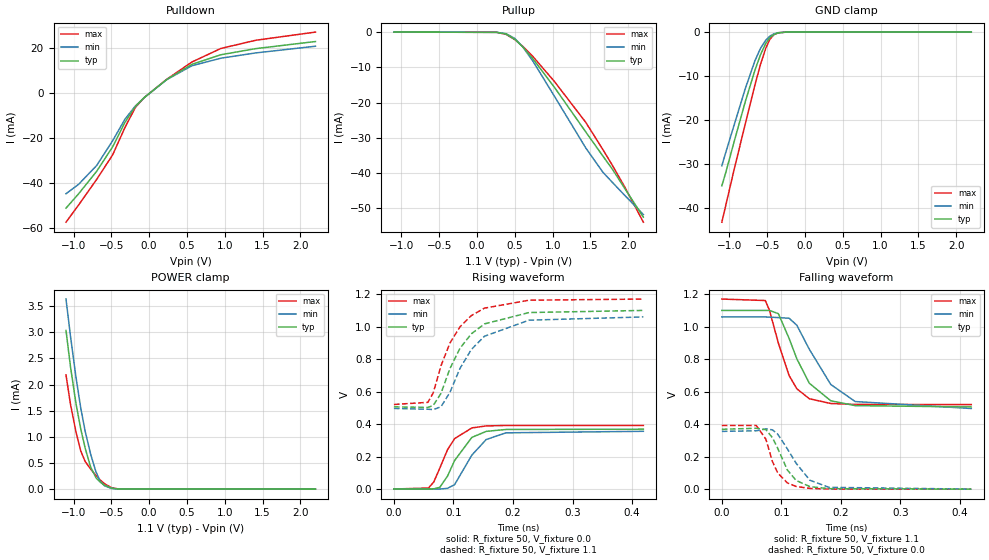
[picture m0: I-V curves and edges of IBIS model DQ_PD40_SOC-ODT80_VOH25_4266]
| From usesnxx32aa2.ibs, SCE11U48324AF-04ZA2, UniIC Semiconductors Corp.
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| DQ_PD40_SOC-ODT80_VOH25_4266
| (40 Ohm Pulldown, 80 Ohm System ODT Setting, VOH=VDDQ/2.5, 3200-4266Mbps)
[Model]   DQ_PD40_SOC-ODT80_VOH25_4266
Model_type   I/O
Vinl = 160.000mV
Vinh = 280.000mV
Vmeas = 220.000mV
Vref = 0.0mV
Cref = 0.0pF
Rref = 80.000Ohm
|   typ   min   max
|C_comp   0.797pF   0.747pF   0.847pF
C_comp_pullup   0.3985pF   0.3735pF   0.4235pF
C_comp_pulldown   0.3985pF   0.3735pF   0.4235pF
| Note: C_comp changes when the ODT circuit is enabled.
[Model Spec]
| Input threshold voltage corners
Vinl   0.1600V   0.1520V   0.1740V
Vinh   0.2800V   0.2720V   0.2940V
| Measurement voltage corners
Vmeas   0.2200V   0.2120V   0.2340V
| Timing spec test load voltage corners
Vref   0.0000V   0.0000V   0.0000V
| Dynamic Overshoot Parameters from LPDDR4 Specification
D_overshoot_ampl_h   0.30   NA   NA
D_overshoot_ampl_l   0.30   NA   NA
D_overshoot_area_h   0.1n   NA   NA
D_overshoot_area_l   0.1n   NA   NA
[Receiver Thresholds]
Vth   = 0.2200V
Vth_min  = 0.2167V
Vth_max  = 0.2233V
Vinh_ac  = 0.060V
Vinh_dc  = 0.060V
Vinl_ac  = -0.060V
Vinl_dc  = -0.060V
Tslew_ac = 5.000ns |Not specified, so set to high value
Threshold_sensitivity = 0.2000
Reference_supply Pullup_ref
[Voltage Range]   1.1000V   1.0600V   1.1700V
[Pullup Reference]   1.1000V   1.0600V   1.1700V
| Junction Temperature (Ambient temp is 35C typ 95C min -40C max)
[Temperature Range]   50.0   110.0   -40.0
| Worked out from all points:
|   slope of the pulldown table from 0 to 0.165 V, typ, clamps not added: 36.9 ohm
|   slope of the pullup table from 0 to 0.165 V, typ, clamps not added: 17.5 kohm
|   GND clamp passes 1 mA (typ) near -0.45 V on its own axis
|   POWER clamp passes 1 mA (typ) near -0.88 V on its own axis
|   rising waveform, R_fixture 50, V_fixture 0.0: 20-80 % time 34.1ps typ, 37.7ps min, 31ps max; typ from 0.001 V to 0.369 V
|   falling waveform, R_fixture 50, V_fixture 1.1: 20-80 % time 44.9ps typ, 56.9ps min, 35.1ps max; typ from 1.1 V to 0.506 V
|   rising waveform, R_fixture 50, V_fixture 1.1: 20-80 % time 55ps typ, 58.7ps min, 50.3ps max; typ from 0.506 V to 1.1 V
|   falling waveform, R_fixture 50, V_fixture 0.0: 20-80 % time 30.7ps typ, 38.7ps min, 24.5ps max; typ from 0.369 V to 0.001 V
[Pulldown]
|   Voltage   I(typ)   I(min)   I(max)
-1.1V     -51.08mA   -44.67mA   -57.33mA
-935mV    -44.77mA   -40.55mA   -49.76mA
-694.1mV  -34.69mA   -32.1mA    -38.29mA
-482.9mV  -23.8mA    -21.1mA    -27.39mA
-321.2mV  -12.98mA   -11.57mA   -15.28mA
-182.6mV  -5.895mA   -5.674mA   -6.313mA
-63.8mV   -1.905mA   -1.887mA   -1.882mA
229.9mV   6.074mA    5.998mA    6.158mA
566.5mV   12.87mA    12.26mA    13.92mA
949.3mV   17.14mA    15.6mA     19.93mA
1.411V    19.86mA    17.95mA    23.58mA
2.2V      23.01mA    20.92mA    27.21mA
[GND Clamp]
|   Voltage   I(typ)   I(min)   I(max)
-1.1V     -34.89mA   -30.33mA   -43.14mA
-1.05V    -32mA      -27.43mA   -39.48mA
-938.3mV  -24.93mA   -21.15mA   -31.25mA
-789.8mV  -15.79mA   -12.83mA   -20.84mA
-661.1mV  -8.6mA     -6.453mA   -11.91mA
-588.5mV  -5.13mA    -3.689mA   -7.336mA
-519.2mV  -2.574mA   -1.836mA   -3.676mA
-466.4mV  -1.298mA   -944.6uA   -1.695mA
-413.6mV  -568.2uA   -418.6uA   -621.4uA
-354.2mV  -178.5uA   -135.2uA   -160.3uA
-251.9mV  -13.31uA   -11.94uA   -7.942uA
2.2V      0A         0A         0A
[Pullup]
|   Voltage   I(typ)   I(min)   I(max)
-1.1V     4.112uA    7.441uA    1.363uA
259.6mV   -60.68uA   -59.84uA   -61.42uA
385mV     -550uA     -457uA     -658uA
500.5mV   -2.042mA   -1.832mA   -2.144mA
602.8mV   -4.15mA    -4.129mA   -4.001mA
738.1mV   -7.554mA   -8.212mA   -6.91mA
1.022V    -15.61mA   -18.14mA   -13.97mA
1.438V    -28.31mA   -32.85mA   -25.59mA
1.665V    -35.16mA   -39.75mA   -33.34mA
1.794V    -39mA      -42.7mA    -37.92mA
1.956V    -44.42mA   -46.36mA   -44.02mA
2.2V      -52.46mA   -51.74mA   -53.91mA
[POWER Clamp]
|   Voltage   I(typ)   I(min)   I(max)
-1.1V     3.036mA    3.636mA    2.186mA
-1.041V   2.347mA    2.931mA    1.626mA
-968mV    1.637mA    2.141mA    1.095mA
-905.3mV  1.155mA    1.555mA    732.4uA
-845.9mV  780.3uA    1.104mA    527.6uA
-773.3mV  421uA      665.6uA    384.1uA
-704mV    219uA      332uA      262.2uA
-647.9mV  134.6uA    154.5uA    176.6uA
-591.8mV  77.94uA    64.82uA    105.5uA
-496.1mV  20.16uA    12.38uA    25.75uA
-397.1mV  2.407uA    1.595uA    2.12uA
2.2V      0A         0A         0A
[Ramp]
|   typ   min   max
| 20% - 80%
dV/dt_r   220.85m/34.09p   213.18m/37.70p   234.91m/31.01p
dV/dt_f   356.25m/44.92p   337.98m/56.85p   389.47m/35.10p
| 25% - 75%
|dV/dt_r   184.04m/27.13p   177.65m/30.05p   195.75m/24.59p
|dV/dt_f   296.88m/35.85p   281.65m/45.40p   324.56m/27.94p
R_load = 50
[Rising Waveform]
R_fixture = 50
V_fixture = 0.0
|   Time   V(typ)   V(min)   V(max)
0s        572.9uV    457uV      423.1uV
58ps      250.1uV    60.4uV     6.266mV
67ps      1.69mV     -579.3uV   43.99mV
77ps      10.44mV    247.6uV    128.4mV
90ps      79.63mV    4.381mV    242.1mV
102ps     176.2mV    27.66mV    310.7mV
131ps     318.5mV    209.6mV    376.7mV
155ps     355.2mV    305mV      388.8mV
188ps     366.9mV    346.3mV    391.6mV
419ps     368.7mV    355.8mV    391.9mV
[Falling Waveform]
R_fixture   = 50
V_fixture   = 1.1
V_fixture_min = 1.06
V_fixture_max = 1.17
|   Time   V(typ)   V(min)   V(max)
0s        1.1V       1.06V      1.17V
73ps      1.1V       1.06V      1.161V
80ps      1.1V       1.059V     1.101V
95ps      1.08V      1.056V     898.5mV
113ps     928mV      1.052V     699.4mV
126ps     802.3mV    1.009V     618mV
147ps     652mV      860.8mV    556.7mV
183ps     544.2mV    644.4mV    527.4mV
224ps     514.4mV    539.5mV    521.8mV
419ps     506.2mV    496.7mV    520.9mV
[Rising Waveform]
R_fixture   = 50
V_fixture   = 1.1
V_fixture_min = 1.06
V_fixture_max = 1.17
|   Time   V(typ)   V(min)   V(max)
0s        506.1mV    496.4mV    520.9mV
57ps      502.8mV    491.7mV    534.1mV
66ps      514.6mV    489.5mV    592.1mV
79ps      588.7mV    506.6mV    758.3mV
94ps      741mV      594.8mV    898.7mV
111ps     867.2mV    743.1mV    999.2mV
130ps     956mV      859.2mV    1.068V
152ps     1.017V     940.9mV    1.114V
227ps     1.087V     1.04V      1.163V
419ps     1.1V       1.06V      1.17V
[Falling Waveform]
R_fixture = 50
V_fixture = 0.0
|   Time   V(typ)   V(min)   V(max)
0s        368.8mV    355.9mV    392mV
58ps      375.1mV    359.8mV    392mV
74ps      366.8mV    371mV      307.8mV
85ps      317mV      365.5mV    170.3mV
94ps      250.6mV    338.3mV    99.56mV
110ps     118.9mV    248.8mV    39.17mV
125ps     53.47mV    158.7mV    16.84mV
148ps     16.06mV    55.2mV     4.974mV
180ps     3.634mV    11.82mV    1.24mV
419ps     621.5uV    528.7uV    445.4uV
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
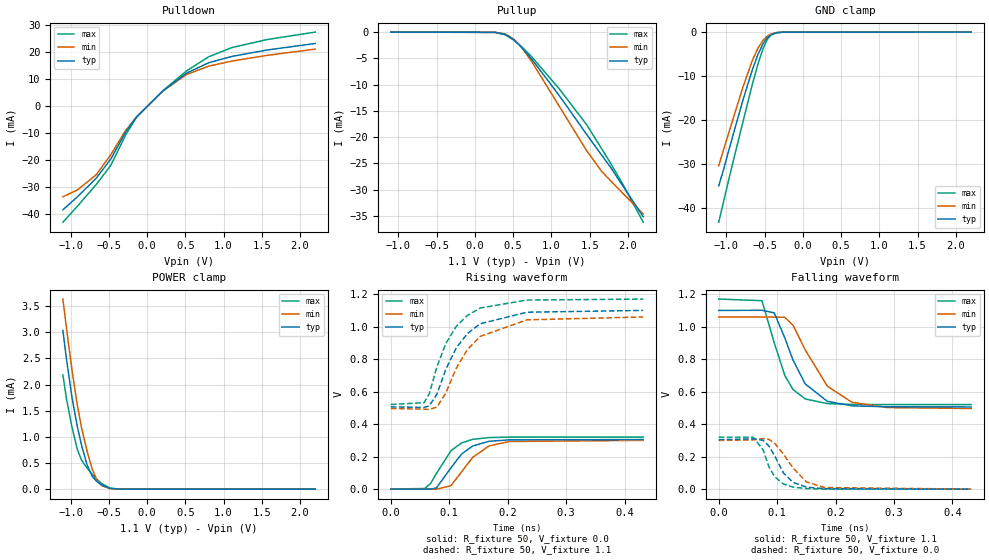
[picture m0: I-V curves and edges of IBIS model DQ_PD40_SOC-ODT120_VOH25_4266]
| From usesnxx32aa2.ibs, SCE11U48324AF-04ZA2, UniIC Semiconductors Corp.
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| DQ_PD40_SOC-ODT120_VOH25_4266
| (40 Ohm Pulldown, 120 Ohm System ODT Setting, VOH=VDDQ/2.5, 3200-4266Mbps)
[Model]   DQ_PD40_SOC-ODT120_VOH25_4266
Model_type   I/O
Vinl = 160.000mV
Vinh = 280.000mV
Vmeas = 220.000mV
Vref = 0.0mV
Cref = 0.0pF
Rref = 120.000Ohm
|   typ   min   max
|C_comp   0.797pF   0.747pF   0.847pF
C_comp_pullup   0.3985pF   0.3735pF   0.4235pF
C_comp_pulldown   0.3985pF   0.3735pF   0.4235pF
| Note: C_comp changes when the ODT circuit is enabled.
[Model Spec]
| Input threshold voltage corners
Vinl   0.1600V   0.1520V   0.1740V
Vinh   0.2800V   0.2720V   0.2940V
| Measurement voltage corners
Vmeas   0.2200V   0.2120V   0.2340V
| Timing spec test load voltage corners
Vref   0.0000V   0.0000V   0.0000V
| Dynamic Overshoot Parameters from LPDDR4 Specification
D_overshoot_ampl_h   0.30   NA   NA
D_overshoot_ampl_l   0.30   NA   NA
D_overshoot_area_h   0.1n   NA   NA
D_overshoot_area_l   0.1n   NA   NA
[Receiver Thresholds]
Vth   = 0.2200V
Vth_min  = 0.2167V
Vth_max  = 0.2233V
Vinh_ac  = 0.060V
Vinh_dc  = 0.060V
Vinl_ac  = -0.060V
Vinl_dc  = -0.060V
Tslew_ac = 5.000ns |Not specified, so set to high value
Threshold_sensitivity = 0.2000
Reference_supply Pullup_ref
[Voltage Range]   1.1000V   1.0600V   1.1700V
[Pullup Reference]   1.1000V   1.0600V   1.1700V
| Junction Temperature (Ambient temp is 35C typ 95C min -40C max)
[Temperature Range]   50.0   110.0   -40.0
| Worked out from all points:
|   slope of the pulldown table from 0 to 0.165 V, typ, clamps not added: 36.9 ohm
|   slope of the pullup table from 0 to 0.165 V, typ, clamps not added: 26.5 kohm
|   GND clamp passes 1 mA (typ) near -0.45 V on its own axis
|   POWER clamp passes 1 mA (typ) near -0.88 V on its own axis
|   rising waveform, R_fixture 50, V_fixture 0.0: 20-80 % time 38.9ps typ, 42.3ps min, 35.5ps max; typ from 0 V to 0.305 V
|   falling waveform, R_fixture 50, V_fixture 1.1: 20-80 % time 44.7ps typ, 56.5ps min, 35ps max; typ from 1.1 V to 0.506 V
|   rising waveform, R_fixture 50, V_fixture 1.1: 20-80 % time 55.2ps typ, 59.4ps min, 50.5ps max; typ from 0.506 V to 1.1 V
|   falling waveform, R_fixture 50, V_fixture 0.0: 20-80 % time 30ps typ, 38.4ps min, 24.3ps max; typ from 0.305 V to 0 V
[Pulldown]
|   Voltage   I(typ)   I(min)   I(max)
-1.1V     -38.36mA   -33.55mA   -42.94mA
-908.6mV  -33.54mA   -31.02mA   -37mA
-661.1mV  -26.62mA   -25.34mA   -28.93mA
-473mV    -19.6mA    -18.02mA   -21.92mA
-278.3mV  -9.59mA    -9.008mA   -10.68mA
-136.4mV  -4.103mA   -4.06mA    -4.148mA
206.8mV   5.507mA    5.446mA    5.565mA
517mV     12.06mA    11.58mA    12.9mA
807.4mV   15.92mA    14.64mA    18.12mA
1.111V    18.24mA    16.52mA    21.49mA
1.566V    20.58mA    18.61mA    24.44mA
2.2V      23.01mA    20.92mA    27.21mA
[GND Clamp]
|   Voltage   I(typ)   I(min)   I(max)
-1.1V     -34.88mA   -30.33mA   -43.14mA
-1.047V   -31.8mA    -27.25mA   -39.23mA
-941.6mV  -25.14mA   -21.33mA   -31.48mA
-786.5mV  -15.6mA    -12.65mA   -20.6mA
-661.1mV  -8.601mA   -6.453mA   -11.91mA
-588.5mV  -5.129mA   -3.689mA   -7.334mA
-519.2mV  -2.572mA   -1.836mA   -3.674mA
-463.1mV  -1.235mA   -899.6uA   -1.601mA
-413.6mV  -564.8uA   -417.1uA   -621.3uA
-344.3mV  -143.8uA   -109.5uA   -124.4uA
-238.7mV  -9.08uA    -8.383uA   -5.005uA
2.2V      0A         0A         0A
[Pullup]
|   Voltage   I(typ)   I(min)   I(max)
-1.1V     2.741uA    4.961uA    908.6nA
266.2mV   -46.36uA   -44.63uA   -47.92uA
398.2mV   -442uA     -366.7uA   -523.5uA
507.1mV   -1.445mA   -1.306mA   -1.506mA
606.1mV   -2.831mA   -2.827mA   -2.721mA
741.4mV   -5.122mA   -5.585mA   -4.678mA
1.098V    -11.99mA   -14.01mA   -10.72mA
1.461V    -19.48mA   -22.58mA   -17.63mA
1.655V    -23.39mA   -26.48mA   -22.16mA
1.771V    -25.67mA   -28.25mA   -24.89mA
1.933V    -29.26mA   -30.67mA   -28.95mA
2.2V      -35.14mA   -34.59mA   -36.18mA
[POWER Clamp]
|   Voltage   I(typ)   I(min)   I(max)
-1.1V     3.036mA    3.636mA    2.186mA
-1.054V   2.493mA    3.085mA    1.737mA
-981.2mV  1.754mA    2.277mA    1.183mA
-911.9mV  1.201mA    1.612mA    764.9uA
-855.8mV  837.9uA    1.172mA    552.3uA
-783.2mV  462uA      720.1uA    402.5uA
-713.9mV  239.3uA    373.1uA    278.6uA
-657.8mV  146.8uA    178.9uA    190.7uA
-595.1mV  80.8uA     68.31uA    109.2uA
-486.2mV  16.73uA    10.16uA    20.95uA
-367.4mV  1.185uA    872.9nA    944.8nA
2.2V      0A         0A         0A
[Ramp]
|   typ   min   max
| 20% - 80%
dV/dt_r   182.76m/38.89p   179.81m/42.32p   192.01m/35.49p
dV/dt_f   356.26m/44.72p   338.00m/56.52p   389.46m/34.95p
| 25% - 75%
|dV/dt_r   152.30m/31.00p   149.84m/33.75p   160.01m/28.19p
|dV/dt_f   296.88m/35.68p   281.67m/45.18p   324.55m/27.83p
R_load = 50
[Rising Waveform]
R_fixture = 50
V_fixture = 0.0
|   Time   V(typ)   V(min)   V(max)
0s        372.8uV    287.9uV    278.3uV
58ps      1.738uV    198.1uV    3.491mV
68ps      -6.571uV   -489.5uV   34.31mV
78ps      7.093mV    -495.2uV   95.82mV
103ps     130.7mV    20.92mV    236.6mV
121ps     215.5mV    105.8mV    284.1mV
140ps     265mV      194.9mV    306.3mV
168ps     294.2mV    265.6mV    317.1mV
203ps     303.2mV    293mV      319.9mV
432ps     305mV      300mV      320.3mV
[Falling Waveform]
R_fixture   = 50
V_fixture   = 1.1
V_fixture_min = 1.06
V_fixture_max = 1.17
|   Time   V(typ)   V(min)   V(max)
0s        1.1V       1.06V      1.17V
74ps      1.101V     1.06V      1.16V
95ps      1.085V     1.059V     901.4mV
113ps     931.8mV    1.058V     700.7mV
127ps     796mV      1.01V      614.2mV
148ps     647.9mV    857.4mV    555.4mV
186ps     540.4mV    633.7mV    526.6mV
228ps     513.3mV    534.9mV    521.7mV
289ps     507mV      502.4mV    521mV
432ps     506.2mV    496.7mV    520.9mV
[Rising Waveform]
R_fixture   = 50
V_fixture   = 1.1
V_fixture_min = 1.06
V_fixture_max = 1.17
|   Time   V(typ)   V(min)   V(max)
0s        506.1mV    496.4mV    520.9mV
57ps      502.8mV    492mV      532.1mV
66ps      513.4mV    489.8mV    588.5mV
79ps      585.1mV    505.7mV    754.3mV
94ps      736.5mV    590.8mV    895.1mV
112ps     869.4mV    744.5mV    1.002V
131ps     957.3mV    858.7mV    1.069V
153ps     1.018V     940.1mV    1.115V
233ps     1.089V     1.042V     1.164V
432ps     1.1V       1.06V      1.17V
[Falling Waveform]
R_fixture = 50
V_fixture = 0.0
|   Time   V(typ)   V(min)   V(max)
0s        305.1mV    300.1mV    320.4mV
59ps      309.8mV    303.5mV    320.2mV
76ps      301mV      311.6mV    241.9mV
86ps      265.8mV    306.4mV    136.9mV
96ps      203.4mV    281.9mV    75.89mV
111ps     98.84mV    214.8mV    31.98mV
127ps     42.49mV    131.3mV    13.09mV
150ps     12.91mV    45.39mV    3.908mV
181ps     3.051mV    10.4mV     991.4uV
432ps     437.4uV    379uV      305.8uV
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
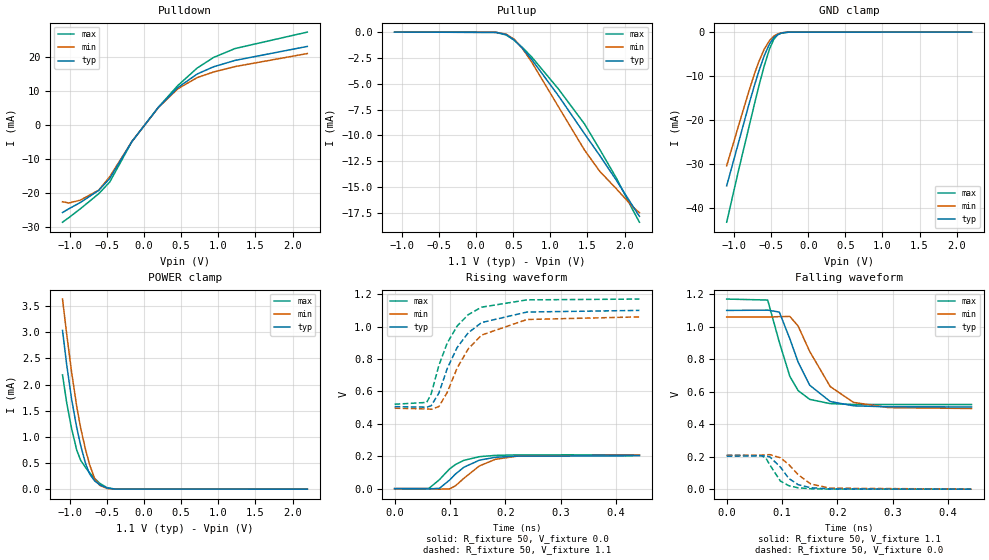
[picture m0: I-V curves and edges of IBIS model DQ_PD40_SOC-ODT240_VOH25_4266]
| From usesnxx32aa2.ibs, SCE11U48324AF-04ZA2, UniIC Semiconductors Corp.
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| DQ_PD40_SOC-ODT240_VOH25_4266
| (40 Ohm Pulldown, 240 Ohm System ODT Setting, VOH=VDDQ/2.5, 3200-4266Mbps)
[Model]   DQ_PD40_SOC-ODT240_VOH25_4266
Model_type   I/O
Vinl = 160.000mV
Vinh = 280.000mV
Vmeas = 220.000mV
Vref = 0.0mV
Cref = 0.0pF
Rref = 240.000Ohm
|   typ   min   max
|C_comp   0.797pF   0.747pF   0.847pF
C_comp_pullup   0.3985pF   0.3735pF   0.4235pF
C_comp_pulldown   0.3985pF   0.3735pF   0.4235pF
| Note: C_comp changes when the ODT circuit is enabled.
[Model Spec]
| Input threshold voltage corners
Vinl   0.1600V   0.1520V   0.1740V
Vinh   0.2800V   0.2720V   0.2940V
| Measurement voltage corners
Vmeas   0.2200V   0.2120V   0.2340V
| Timing spec test load voltage corners
Vref   0.0000V   0.0000V   0.0000V
| Dynamic Overshoot Parameters from LPDDR4 Specification
D_overshoot_ampl_h   0.30   NA   NA
D_overshoot_ampl_l   0.30   NA   NA
D_overshoot_area_h   0.1n   NA   NA
D_overshoot_area_l   0.1n   NA   NA
[Receiver Thresholds]
Vth   = 0.2200V
Vth_min  = 0.2167V
Vth_max  = 0.2233V
Vinh_ac  = 0.060V
Vinh_dc  = 0.060V
Vinl_ac  = -0.060V
Vinl_dc  = -0.060V
Tslew_ac = 5.000ns |Not specified, so set to high value
Threshold_sensitivity = 0.2000
Reference_supply Pullup_ref
[Voltage Range]   1.1000V   1.0600V   1.1700V
[Pullup Reference]   1.1000V   1.0600V   1.1700V
| Junction Temperature (Ambient temp is 35C typ 95C min -40C max)
[Temperature Range]   50.0   110.0   -40.0
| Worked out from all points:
|   slope of the pulldown table from 0 to 0.165 V, typ, clamps not added: 37 ohm
|   slope of the pullup table from 0 to 0.165 V, typ, clamps not added: 54 kohm
|   GND clamp passes 1 mA (typ) near -0.45 V on its own axis
|   POWER clamp passes 1 mA (typ) near -0.88 V on its own axis
|   rising waveform, R_fixture 50, V_fixture 0.0: 20-80 % time 45.9ps typ, 49.8ps min, 42.3ps max; typ from 0 V to 0.203 V
|   falling waveform, R_fixture 50, V_fixture 1.1: 20-80 % time 44.5ps typ, 56.1ps min, 34.8ps max; typ from 1.1 V to 0.506 V
|   rising waveform, R_fixture 50, V_fixture 1.1: 20-80 % time 55.5ps typ, 60ps min, 50.7ps max; typ from 0.506 V to 1.1 V
|   falling waveform, R_fixture 50, V_fixture 0.0: 20-80 % time 30ps typ, 38.5ps min, 24.6ps max; typ from 0.203 V to 0 V
[Pulldown]
|   Voltage   I(typ)   I(min)   I(max)
-1.1V     -25.68mA   -22.53mA   -28.52mA
-1.014V   -24.58mA   -22.89mA   -27.17mA
-862.4mV  -22.78mA   -22.08mA   -24.64mA
-611.6mV  -19.18mA   -19.12mA   -20.17mA
-463.1mV  -15.68mA   -15.18mA   -16.74mA
-166.1mV  -4.908mA   -4.896mA   -4.943mA
193.6mV   5.178mA    5.123mA    5.223mA
454.3mV   10.94mA    10.59mA    11.54mA
715mV     14.92mA    13.87mA    16.67mA
936.1mV   17.04mA    15.52mA    19.78mA
1.226V    18.91mA    17.1mA     22.39mA
2.2V      23.01mA    20.92mA    27.21mA
[GND Clamp]
|   Voltage   I(typ)   I(min)   I(max)
-1.1V     -34.88mA   -30.33mA   -43.14mA
-941.6mV  -25.14mA   -21.33mA   -31.48mA
-803mV    -16.57mA   -13.55mA   -21.77mA
-727.1mV  -12.17mA   -9.543mA   -16.42mA
-667.7mV  -8.943mA   -6.74mA    -12.35mA
-595.1mV  -5.418mA   -3.907mA   -7.728mA
-522.5mV  -2.673mA   -1.908mA   -3.826mA
-466.4mV  -1.297mA   -945.2uA   -1.694mA
-413.6mV  -565.7uA   -419.4uA   -621.5uA
-357.5mV  -191.6uA   -144.1uA   -173.8uA
-261.8mV  -17.63uA   -15.46uA   -10.98uA
2.2V      0A         0A         0A
[Pullup]
|   Voltage   I(typ)   I(min)   I(max)
-1.1V     1.371uA    2.481uA    454.5nA
269.5mV   -24.65uA   -23.68uA   -25.92uA
404.8mV   -242.8uA   -201.7uA   -285.4uA
510.4mV   -747.7uA   -678.3uA   -775.9uA
622.6mV   -1.56mA    -1.582mA   -1.483mA
748mV     -2.647mA   -2.903mA   -2.409mA
1.108V    -6.162mA   -7.223mA   -5.503mA
1.461V    -9.856mA   -11.44mA   -8.909mA
1.665V    -11.95mA   -13.48mA   -11.36mA
1.887V    -14.33mA   -15.16mA   -14.11mA
2.114V    -16.89mA   -16.95mA   -17.27mA
2.2V      -17.84mA   -17.49mA   -18.41mA
[POWER Clamp]
|   Voltage   I(typ)   I(min)   I(max)
-1.1V     3.036mA    3.636mA    2.186mA
-1.044V   2.383mA    2.969mA    1.654mA
-977.9mV  1.724mA    2.242mA    1.161mA
-908.6mV  1.178mA    1.582mA    748.4uA
-855.8mV  838uA      1.172mA    552.9uA
-789.8mV  491.1uA    757.2uA    414.8uA
-737mV    296.6uA    478.4uA    318.4uA
-667.7mV  159.9uA    206.1uA    205.2uA
-598.4mV  83.65uA    71.98uA    113.1uA
-499.4mV  21.31uA    13.18uA    27.45uA
-393.8mV  2.21uA     1.495uA    1.93uA
2.2V      0A         0A         0A
[Ramp]
|   typ   min   max
| 20% - 80%
dV/dt_r   121.61m/45.90p   123.92m/49.79p   125.39m/42.30p
dV/dt_f   356.25m/44.51p   338.02m/56.11p   389.46m/34.85p
| 25% - 75%
|dV/dt_r   101.34m/36.55p   103.27m/39.73p   104.49m/33.63p
|dV/dt_f   296.88m/35.54p   281.69m/44.83p   324.55m/27.76p
R_load = 50
[Rising Waveform]
R_fixture = 50
V_fixture = 0.0
|   Time   V(typ)   V(min)   V(max)
0s        170.9uV    116.3uV    132.5uV
62ps      -1.369mV   37.3uV     1.741mV
81ps      2.105mV    -3.132mV   55.7mV
99ps      52.27mV    -1.735mV   121.1mV
110ps     90.45mV    17.75mV    149.2mV
125ps     132mV      63.88mV    174.6mV
153ps     175.7mV    140.2mV    197.3mV
182ps     193.5mV    181.1mV    205.3mV
221ps     200.7mV    200.5mV    208.3mV
442ps     202.9mV    206.6mV    209.1mV
[Falling Waveform]
R_fixture   = 50
V_fixture   = 1.1
V_fixture_min = 1.06
V_fixture_max = 1.17
|   Time   V(typ)   V(min)   V(max)
0s        1.1V       1.06V      1.17V
74ps      1.102V     1.059V     1.164V
95ps      1.09V      1.062V     905mV
114ps     925.9mV    1.063V     694.6mV
129ps     781.6mV    1.004V     606.7mV
150ps     639.3mV    846.6mV    552.6mV
187ps     539.5mV    631.2mV    526.5mV
229ps     513.1mV    534.1mV    521.7mV
292ps     506.9mV    502mV      520.9mV
442ps     506.2mV    496.6mV    520.9mV
[Rising Waveform]
R_fixture   = 50
V_fixture   = 1.1
V_fixture_min = 1.06
V_fixture_max = 1.17
|   Time   V(typ)   V(min)   V(max)
0s        506.1mV    496.4mV    520.9mV
58ps      502.8mV    491.9mV    532.2mV
66ps      511.4mV    489.9mV    584.3mV
80ps      590.1mV    506.5mV    761.1mV
95ps      741mV      594mV      898.6mV
113ps     871.6mV    745.4mV    1.004V
133ps     961.9mV    862.8mV    1.074V
157ps     1.025V     947.8mV    1.12V
239ps     1.09V      1.044V     1.165V
442ps     1.1V       1.06V      1.17V
[Falling Waveform]
R_fixture = 50
V_fixture = 0.0
|   Time   V(typ)   V(min)   V(max)
0s        202.9mV    206.7mV    209.2mV
62ps      205.5mV    209.2mV    207.7mV
71ps      204.6mV    211.8mV    190.4mV
78ps      198.5mV    212.6mV    148.7mV
97ps      135.9mV    193.6mV    49.97mV
112ps     66.59mV    152mV      21.67mV
129ps     27.93mV    89.46mV    8.544mV
152ps     8.788mV    31.51mV    2.569mV
187ps     1.786mV    6.304mV    548.1uV
442ps     239.6uV    215.5uV    158.7uV
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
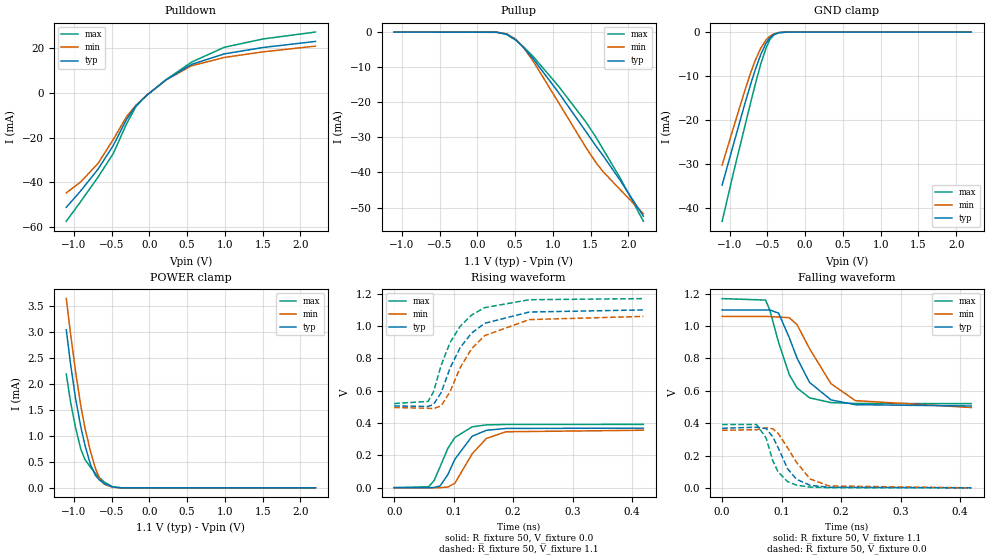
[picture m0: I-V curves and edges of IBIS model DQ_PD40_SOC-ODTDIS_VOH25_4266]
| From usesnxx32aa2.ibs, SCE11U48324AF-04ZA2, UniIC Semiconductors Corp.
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| DQ_PD40_SOC-ODTDIS_VOH25_4266
| (40 Ohm Pulldown, SOC ODT disabled setting, VOH=VDDQ/2.5 cal. point, 3200-4266Mbps)
[Model]   DQ_PD40_SOC-ODTDIS_VOH25_4266
Model_type   I/O
Vinl = 160.000mV
Vinh = 280.000mV
Vmeas = 220.000mV
Vref = 0.0mV
Cref = 0.0pF
|   typ   min   max
|C_comp   0.797pF   0.747pF   0.847pF
C_comp_pullup   0.3985pF   0.3735pF   0.4235pF
C_comp_pulldown   0.3985pF   0.3735pF   0.4235pF
| Note: C_comp changes when the ODT circuit is enabled.
[Model Spec]
| Input threshold voltage corners
Vinl   0.1600V   0.1520V   0.1740V
Vinh   0.2800V   0.2720V   0.2940V
| Measurement voltage corners
Vmeas   0.2200V   0.2120V   0.2340V
| Timing spec test load voltage corners
Vref   0.0000V   0.0000V   0.0000V
| Dynamic Overshoot Parameters from LPDDR4 Specification
D_overshoot_ampl_h   0.30   NA   NA
D_overshoot_ampl_l   0.30   NA   NA
D_overshoot_area_h   0.1n   NA   NA
D_overshoot_area_l   0.1n   NA   NA
[Receiver Thresholds]
Vth   = 0.2200V
Vth_min  = 0.2167V
Vth_max  = 0.2233V
Vinh_ac  = 0.060V
Vinh_dc  = 0.060V
Vinl_ac  = -0.060V
Vinl_dc  = -0.060V
Tslew_ac = 5.000ns |Not specified, so set to high value
Threshold_sensitivity = 0.2000
Reference_supply Pullup_ref
[Voltage Range]   1.1000V   1.0600V   1.1700V
[Pullup Reference]   1.1000V   1.0600V   1.1700V
| Junction Temperature (Ambient temp is 35C typ 95C min -40C max)
[Temperature Range]   50.0   110.0   -40.0
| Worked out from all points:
|   slope of the pulldown table from 0 to 0.165 V, typ, clamps not added: 36.8 ohm
|   slope of the pullup table from 0 to 0.165 V, typ, clamps not added: 17.4 kohm
|   GND clamp passes 1 mA (typ) near -0.45 V on its own axis
|   POWER clamp passes 1 mA (typ) near -0.88 V on its own axis
|   rising waveform, R_fixture 50, V_fixture 0.0: 20-80 % time 34.1ps typ, 37.7ps min, 31ps max; typ from 0.001 V to 0.369 V
|   falling waveform, R_fixture 50, V_fixture 1.1: 20-80 % time 44.9ps typ, 56.9ps min, 35.1ps max; typ from 1.1 V to 0.506 V
|   rising waveform, R_fixture 50, V_fixture 1.1: 20-80 % time 55ps typ, 58.7ps min, 50.3ps max; typ from 0.506 V to 1.1 V
|   falling waveform, R_fixture 50, V_fixture 0.0: 20-80 % time 30.7ps typ, 38.7ps min, 24.5ps max; typ from 0.369 V to 0.001 V
[Pulldown]
|   Voltage   I(typ)   I(min)   I(max)
-1.1V     -51.08mA   -44.66mA   -57.33mA
-915.2mV  -43.99mA   -39.94mA   -48.81mA
-680.9mV  -34.11mA   -31.54mA   -37.67mA
-479.6mV  -23.59mA   -20.9mA    -27.18mA
-298.1mV  -11.57mA   -10.41mA   -13.54mA
-176mV    -5.64mA    -5.443mA   -5.998mA
-44mV     -1.314mA   -1.301mA   -1.292mA
223.3mV   5.913mA    5.841mA    5.989mA
559.9mV   12.77mA    12.17mA    13.79mA
992.2mV   17.45mA    15.86mA    20.39mA
1.504V    20.3mA     18.35mA    24.11mA
2.2V      23.01mA    20.92mA    27.21mA
[GND Clamp]
|   Voltage   I(typ)   I(min)   I(max)
-1.1V     -34.89mA   -30.35mA   -43.14mA
-935mV    -24.72mA   -20.96mA   -31.01mA
-789.8mV  -15.79mA   -12.83mA   -20.84mA
-720.5mV  -11.8mA    -9.214mA   -15.96mA
-661.1mV  -8.6mA     -6.453mA   -11.91mA
-588.5mV  -5.13mA    -3.689mA   -7.335mA
-519.2mV  -2.573mA   -1.839mA   -3.674mA
-469.7mV  -1.36mA    -990.4uA   -1.791mA
-413.6mV  -566.5uA   -417.1uA   -622.6uA
-344.3mV  -143.9uA   -110.1uA   -124.3uA
-228.8mV  -6.701uA   -6.589uA   -3.536uA
2.2V      0A         0A         0A
[Pullup]
|   Voltage   I(typ)   I(min)   I(max)
-1.1V     4.112uA    7.441uA    1.363uA
259.6mV   -60.43uA   -59.44uA   -61.41uA
388.3mV   -575.6uA   -478.1uA   -688.8uA
513.7mV   -2.281mA   -2.075mA   -2.361mA
616mV     -4.459mA   -4.485mA   -4.266mA
744.7mV   -7.731mA   -8.43mA    -7.062mA
1.075V    -17.18mA   -20.03mA   -15.38mA
1.441V    -28.41mA   -32.96mA   -25.69mA
1.566V    -32.29mA   -37.01mA   -29.76mA
1.665V    -35.16mA   -39.75mA   -33.34mA
1.89V     -42.15mA   -44.83mA   -41.48mA
2.2V      -52.46mA   -51.75mA   -53.91mA
[POWER Clamp]
|   Voltage   I(typ)   I(min)   I(max)
-1.1V     3.036mA    3.636mA    2.186mA
-1.044V   2.383mA    2.969mA    1.654mA
-977.9mV  1.724mA    2.242mA    1.161mA
-908.6mV  1.178mA    1.583mA    748.4uA
-852.5mV  818.5uA    1.149mA    543.8uA
-779.9mV  448uA      701.8uA    396.3uA
-713.9mV  239.2uA    373.1uA    278.6uA
-657.8mV  146.8uA    178.8uA    190.7uA
-595.1mV  80.75uA    68.31uA    109.2uA
-489.5mV  17.8uA     10.88uA    22.46uA
-380.6mV  1.613uA    1.129uA    1.341uA
2.2V      0A         0A         0A
[Ramp]
|   typ   min   max
| 20% - 80%
dV/dt_r   220.85m/34.09p   213.18m/37.70p   234.91m/31.01p
dV/dt_f   356.25m/44.92p   337.98m/56.85p   389.47m/35.10p
| 25% - 75%
|dV/dt_r   184.04m/27.13p   177.65m/30.05p   195.75m/24.59p
|dV/dt_f   296.88m/35.85p   281.65m/45.40p   324.56m/27.94p
R_load = 50
[Rising Waveform]
R_fixture = 50
V_fixture = 0.0
|   Time   V(typ)   V(min)   V(max)
0s        572.9uV    457uV      423.1uV
58ps      250.1uV    60.4uV     6.266mV
67ps      1.69mV     -579.3uV   43.99mV
77ps      10.44mV    247.6uV    128.4mV
90ps      79.63mV    4.381mV    242.1mV
102ps     176.2mV    27.66mV    310.7mV
131ps     318.5mV    209.6mV    376.7mV
155ps     355.2mV    305mV      388.8mV
188ps     366.9mV    346.3mV    391.6mV
419ps     368.7mV    355.8mV    391.9mV
[Falling Waveform]
R_fixture   = 50
V_fixture   = 1.1
V_fixture_min = 1.06
V_fixture_max = 1.17
|   Time   V(typ)   V(min)   V(max)
0s        1.1V       1.06V      1.17V
73ps      1.1V       1.06V      1.161V
80ps      1.1V       1.059V     1.101V
95ps      1.08V      1.056V     898.5mV
113ps     928mV      1.052V     699.4mV
126ps     802.3mV    1.009V     618mV
147ps     652mV      860.8mV    556.7mV
183ps     544.2mV    644.4mV    527.4mV
224ps     514.4mV    539.5mV    521.8mV
419ps     506.2mV    496.7mV    520.9mV
[Rising Waveform]
R_fixture   = 50
V_fixture   = 1.1
V_fixture_min = 1.06
V_fixture_max = 1.17
|   Time   V(typ)   V(min)   V(max)
0s        506.1mV    496.4mV    520.9mV
57ps      502.8mV    491.7mV    534.1mV
66ps      514.6mV    489.5mV    592.1mV
79ps      588.7mV    506.6mV    758.3mV
94ps      741mV      594.8mV    898.7mV
111ps     867.2mV    743.1mV    999.2mV
130ps     956mV      859.2mV    1.068V
152ps     1.017V     940.9mV    1.114V
227ps     1.087V     1.04V      1.163V
419ps     1.1V       1.06V      1.17V
[Falling Waveform]
R_fixture = 50
V_fixture = 0.0
|   Time   V(typ)   V(min)   V(max)
0s        368.8mV    355.9mV    392mV
58ps      375.1mV    359.8mV    392mV
74ps      366.8mV    371mV      307.8mV
85ps      317mV      365.5mV    170.3mV
94ps      250.6mV    338.3mV    99.56mV
110ps     118.9mV    248.8mV    39.17mV
125ps     53.47mV    158.7mV    16.84mV
148ps     16.06mV    55.2mV     4.974mV
180ps     3.634mV    11.82mV    1.24mV
419ps     621.5uV    528.7uV    445.4uV
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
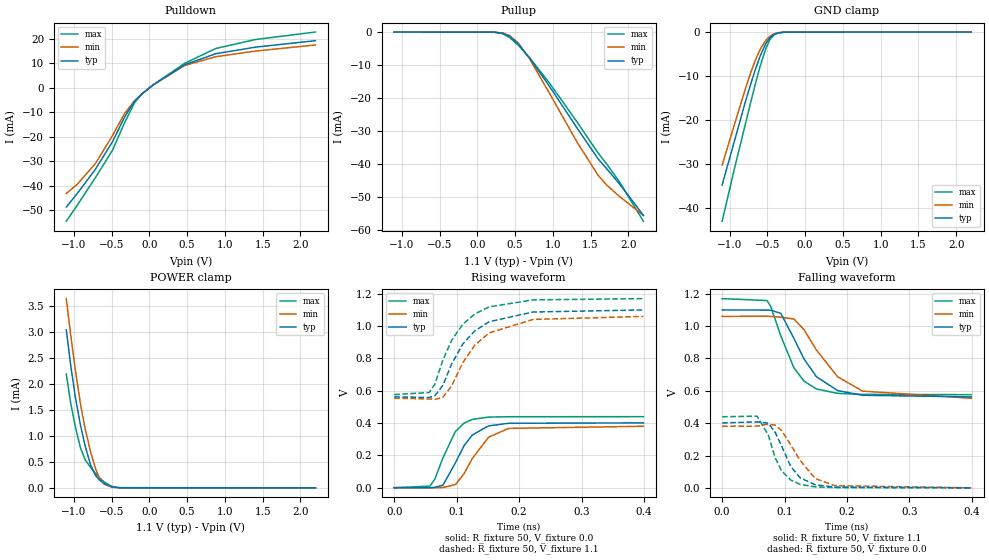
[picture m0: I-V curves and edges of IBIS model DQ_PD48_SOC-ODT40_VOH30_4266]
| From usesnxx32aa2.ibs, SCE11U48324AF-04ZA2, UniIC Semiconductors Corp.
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| DQ_PD48_SOC-ODT40_VOH30_4266
| (48 Ohm Pulldown, 40 Ohm System ODT Setting, VOH=VDDQ/3.0, 3200-4266Mbps)
[Model]   DQ_PD48_SOC-ODT40_VOH30_4266
Model_type   I/O
Vinl = 123.333mV
Vinh = 243.333mV
Vmeas = 183.333mV
Vref = 0.0mV
Cref = 0.0pF
Rref = 40.000Ohm
|   typ   min   max
|C_comp   0.797pF   0.747pF   0.847pF
C_comp_pullup   0.3985pF   0.3735pF   0.4235pF
C_comp_pulldown   0.3985pF   0.3735pF   0.4235pF
| Note: C_comp changes when the ODT circuit is enabled.
[Model Spec]
| Input threshold voltage corners
Vinl   0.1233V   0.1167V   0.1350V
Vinh   0.2433V   0.2367V   0.2550V
| Measurement voltage corners
Vmeas   0.1833V   0.1767V   0.1950V
| Timing spec test load voltage corners
Vref   0.0000V   0.0000V   0.0000V
| Dynamic Overshoot Parameters from LPDDR4 Specification
D_overshoot_ampl_h   0.30   NA   NA
D_overshoot_ampl_l   0.30   NA   NA
D_overshoot_area_h   0.1n   NA   NA
D_overshoot_area_l   0.1n   NA   NA
[Receiver Thresholds]
Vth   = 0.1833V
Vth_min  = 0.1800V
Vth_max  = 0.1866V
Vinh_ac  = 0.060V
Vinh_dc  = 0.060V
Vinl_ac  = -0.060V
Vinl_dc  = -0.060V
Tslew_ac = 5.000ns |Not specified, so set to high value
Threshold_sensitivity = 0.1667
Reference_supply Pullup_ref
[Voltage Range]   1.1000V   1.0600V   1.1700V
[Pullup Reference]   1.1000V   1.0600V   1.1700V
| Junction Temperature (Ambient temp is 35C typ 95C min -40C max)
[Temperature Range]   50.0   110.0   -40.0
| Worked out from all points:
|   slope of the pulldown table from 0 to 0.165 V, typ, clamps not added: 43.8 ohm
|   slope of the pullup table from 0 to 0.165 V, typ, clamps not added: 13 kohm
|   GND clamp passes 1 mA (typ) near -0.45 V on its own axis
|   POWER clamp passes 1 mA (typ) near -0.88 V on its own axis
|   rising waveform, R_fixture 50, V_fixture 0.0: 20-80 % time 34.3ps typ, 38.4ps min, 29.7ps max; typ from 0.001 V to 0.401 V
|   falling waveform, R_fixture 50, V_fixture 1.1: 20-80 % time 48.6ps typ, 60.9ps min, 38.4ps max; typ from 1.1 V to 0.563 V
|   rising waveform, R_fixture 50, V_fixture 1.1: 20-80 % time 54.4ps typ, 57.3ps min, 50.7ps max; typ from 0.562 V to 1.1 V
|   falling waveform, R_fixture 50, V_fixture 0.0: 20-80 % time 31.8ps typ, 39.3ps min, 26.8ps max; typ from 0.402 V to 0.001 V
[Pulldown]
|   Voltage   I(typ)   I(min)   I(max)
-1.1V     -48.63mA   -43.1mA    -54.44mA
-961.4mV  -43.38mA   -39.57mA   -48.2mA
-713.9mV  -33.22mA   -30.9mA    -36.63mA
-486.2mV  -21.92mA   -19.41mA   -25.37mA
-327.8mV  -11.9mA    -10.49mA   -14.22mA
-199.1mV  -5.655mA   -5.373mA   -6.24mA
-103.4mV  -2.659mA   -2.626mA   -2.674mA
48.4mV    1.126mA    1.123mA    1.124mA
467.5mV   9.39mA     9.064mA    9.962mA
880mV     13.87mA    12.66mA    16.02mA
1.405V    16.56mA    14.96mA    19.68mA
2.2V      19.2mA     17.45mA    22.72mA
[GND Clamp]
|   Voltage   I(typ)   I(min)   I(max)
-1.1V     -34.88mA   -30.35mA   -43.13mA
-941.6mV  -25.13mA   -21.34mA   -31.48mA
-793.1mV  -15.98mA   -13.01mA   -21.06mA
-723.8mV  -11.98mA   -9.381mA   -16.18mA
-664.4mV  -8.768mA   -6.598mA   -12.12mA
-595.1mV  -5.416mA   -3.908mA   -7.721mA
-522.5mV  -2.674mA   -1.905mA   -3.823mA
-469.7mV  -1.362mA   -986.5uA   -1.792mA
-416.9mV  -600uA     -442uA     -665.6uA
-360.8mV  -206uA     -155uA     -189uA
-265.1mV  -19.66uA   -16.92uA   -12.32uA
2.2V      0A         0A         0A
[Pullup]
|   Voltage   I(typ)   I(min)   I(max)
-1.1V     6.284uA    9.684uA    2.832uA
226.6mV   -42.43uA   -42.99uA   -42.86uA
338.8mV   -361.7uA   -298.3uA   -496.4uA
431.2mV   -1.334mA   -1.088mA   -1.697mA
546.7mV   -3.719mA   -3.404mA   -4.061mA
695.2mV   -7.926mA   -8.185mA   -7.83mA
955.9mV   -16.41mA   -18.52mA   -15.43mA
1.322V    -29.06mA   -33.32mA   -27.23mA
1.599V    -38.35mA   -43.31mA   -36.57mA
1.718V    -41.46mA   -46.41mA   -40.06mA
1.893V    -46.24mA   -49.93mA   -45.68mA
2.2V      -55.46mA   -55.5mA    -57.28mA
[POWER Clamp]
|   Voltage   I(typ)   I(min)   I(max)
-1.1V     3.036mA    3.636mA    2.186mA
-1.041V   2.347mA    2.931mA    1.626mA
-981.2mV  1.754mA    2.277mA    1.184mA
-911.9mV  1.201mA    1.612mA    764.9uA
-849.2mV  799.5uA    1.126mA    535.7uA
-776.6mV  434.5uA    683.6uA    390.2uA
-713.9mV  239.4uA    373.1uA    278.6uA
-657.8mV  146.8uA    178.8uA    190.7uA
-598.4mV  83.72uA    71.97uA    113.1uA
-499.4mV  21.34uA    13.12uA    27.5uA
-393.8mV  2.215uA    1.484uA    1.93uA
2.2V      0A         0A         0A
[Ramp]
|   typ   min   max
| 20% - 80%
dV/dt_r   240.49m/34.27p   228.04m/38.36p   263.55m/29.73p
dV/dt_f   322.46m/48.60p   303.57m/60.92p   356.23m/38.44p
| 25% - 75%
|dV/dt_r   200.41m/27.27p   190.04m/30.53p   219.62m/23.52p
|dV/dt_f   268.71m/38.78p   252.98m/48.55p   296.85m/30.59p
R_load = 50
[Rising Waveform]
R_fixture = 50
V_fixture = 0.0
|   Time   V(typ)   V(min)   V(max)
0s        617uV      534.7uV    447.3uV
57ps      579.7uV    45.81uV    10.1mV
65ps      2.881mV    -370.2uV   52.71mV
78ps      15.94mV    1.864mV    185mV
98ps      154.1mV    19.35mV    348mV
112ps     261.3mV    87.5mV     400.1mV
125ps     326mV      180.5mV    422.8mV
151ps     382.9mV    312.3mV    437.1mV
183ps     398.8mV    367.2mV    439.5mV
399ps     401.4mV    380.6mV    439.7mV
[Falling Waveform]
R_fixture   = 50
V_fixture   = 1.1
V_fixture_min = 1.06
V_fixture_max = 1.17
|   Time   V(typ)   V(min)   V(max)
0s        1.1V       1.06V      1.17V
72ps      1.099V     1.061V     1.158V
78ps      1.098V     1.06V      1.12V
94ps      1.079V     1.055V     939.2mV
115ps     923.2mV    1.044V     741.8mV
131ps     797.7mV    978.5mV    660.3mV
151ps     687.3mV    852.5mV    611.5mV
185ps     601.5mV    686.8mV    584.4mV
225ps     572.4mV    598.1mV    577.8mV
399ps     562.6mV    554mV      576.3mV
[Rising Waveform]
R_fixture   = 50
V_fixture   = 1.1
V_fixture_min = 1.06
V_fixture_max = 1.17
|   Time   V(typ)   V(min)   V(max)
0s        562.5mV    553.6mV    576.3mV
56ps      558.4mV    549.5mV    589.4mV
65ps      568.1mV    546.4mV    639.4mV
78ps      633.7mV    560.1mV    790.4mV
92ps      765.7mV    630.7mV    912.3mV
110ps     890mV      774.7mV    1.012V
129ps     970.4mV    881.4mV    1.075V
152ps     1.027V     957.7mV    1.119V
222ps     1.087V     1.041V     1.162V
399ps     1.1V       1.06V      1.17V
[Falling Waveform]
R_fixture = 50
V_fixture = 0.0
|   Time   V(typ)   V(min)   V(max)
0s        401.6mV    380.8mV    439.8mV
56ps      408.3mV    382.1mV    443.4mV
74ps      400.1mV    394.4mV    326.3mV
85ps      344mV      388.2mV    185.8mV
95ps      261.2mV    355.2mV    107.3mV
110ps     131.9mV    266.5mV    48.01mV
125ps     62.48mV    169.4mV    21.89mV
149ps     19.48mV    58.78mV    6.577mV
180ps     4.915mV    14.02mV    1.726mV
399ps     666.8uV    606.2uV    467.7uV
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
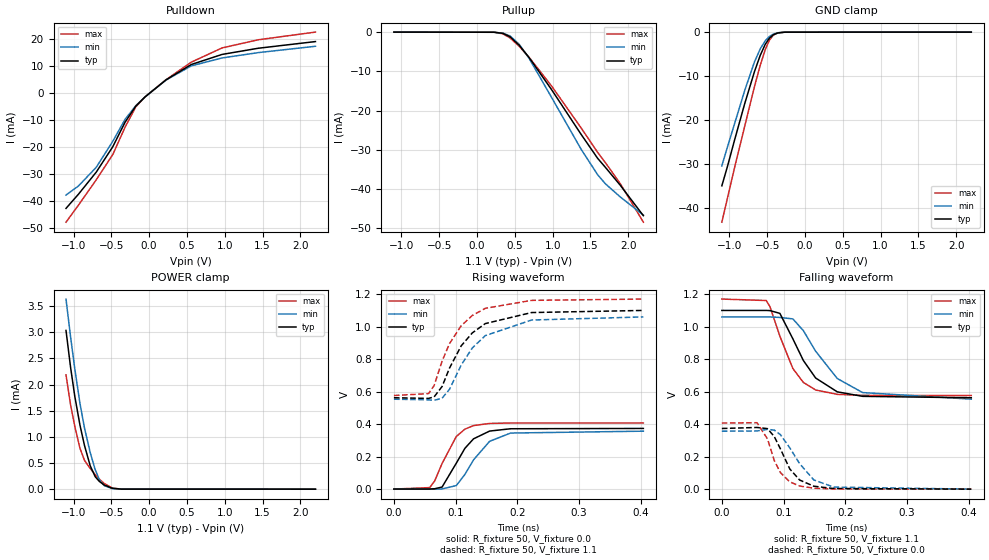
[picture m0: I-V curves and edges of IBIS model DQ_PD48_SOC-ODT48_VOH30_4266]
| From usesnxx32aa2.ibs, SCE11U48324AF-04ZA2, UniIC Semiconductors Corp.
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| DQ_PD48_SOC-ODT48_VOH30_4266
| (48 Ohm Pulldown, 48 Ohm System ODT Setting, VOH=VDDQ/3.0, 3200-4266Mbps)
[Model]   DQ_PD48_SOC-ODT48_VOH30_4266
Model_type   I/O
Vinl = 123.333mV
Vinh = 243.333mV
Vmeas = 183.333mV
Vref = 0.0mV
Cref = 0.0pF
Rref = 48.000Ohm
|   typ   min   max
|C_comp   0.797pF   0.747pF   0.847pF
C_comp_pullup   0.3985pF   0.3735pF   0.4235pF
C_comp_pulldown   0.3985pF   0.3735pF   0.4235pF
| Note: C_comp changes when the ODT circuit is enabled.
[Model Spec]
| Input threshold voltage corners
Vinl   0.1233V   0.1167V   0.1350V
Vinh   0.2433V   0.2367V   0.2550V
| Measurement voltage corners
Vmeas   0.1833V   0.1767V   0.1950V
| Timing spec test load voltage corners
Vref   0.0000V   0.0000V   0.0000V
| Dynamic Overshoot Parameters from LPDDR4 Specification
D_overshoot_ampl_h   0.30   NA   NA
D_overshoot_ampl_l   0.30   NA   NA
D_overshoot_area_h   0.1n   NA   NA
D_overshoot_area_l   0.1n   NA   NA
[Receiver Thresholds]
Vth   = 0.1833V
Vth_min  = 0.1800V
Vth_max  = 0.1866V
Vinh_ac  = 0.060V
Vinh_dc  = 0.060V
Vinl_ac  = -0.060V
Vinl_dc  = -0.060V
Tslew_ac = 5.000ns |Not specified, so set to high value
Threshold_sensitivity = 0.1667
Reference_supply Pullup_ref
[Voltage Range]   1.1000V   1.0600V   1.1700V
[Pullup Reference]   1.1000V   1.0600V   1.1700V
| Junction Temperature (Ambient temp is 35C typ 95C min -40C max)
[Temperature Range]   50.0   110.0   -40.0
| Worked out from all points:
|   slope of the pulldown table from 0 to 0.165 V, typ, clamps not added: 43.8 ohm
|   slope of the pullup table from 0 to 0.165 V, typ, clamps not added: 15.5 kohm
|   GND clamp passes 1 mA (typ) near -0.45 V on its own axis
|   POWER clamp passes 1 mA (typ) near -0.88 V on its own axis
|   rising waveform, R_fixture 50, V_fixture 0.0: 20-80 % time 35.7ps typ, 40.1ps min, 31.4ps max; typ from 0.001 V to 0.374 V
|   falling waveform, R_fixture 50, V_fixture 1.1: 20-80 % time 48.4ps typ, 60.7ps min, 38.3ps max; typ from 1.1 V to 0.563 V
|   rising waveform, R_fixture 50, V_fixture 1.1: 20-80 % time 54.6ps typ, 57.8ps min, 50.8ps max; typ from 0.562 V to 1.1 V
|   falling waveform, R_fixture 50, V_fixture 0.0: 20-80 % time 31.7ps typ, 39.3ps min, 26.6ps max; typ from 0.374 V to 0.001 V
[Pulldown]
|   Voltage   I(typ)   I(min)   I(max)
-1.1V     -42.75mA   -37.8mA    -47.88mA
-935mV    -37.48mA   -34.43mA   -41.54mA
-700.7mV  -29.32mA   -27.52mA   -32.18mA
-479.6mV  -19.79mA   -17.77mA   -22.68mA
-317.9mV  -10.72mA   -9.649mA   -12.56mA
-176mV    -4.739mA   -4.594mA   -5.024mA
-53.9mV   -1.352mA   -1.343mA   -1.333mA
223.3mV   4.975mA    4.912mA    5.047mA
556.6mV   10.67mA    10.16mA    11.54mA
965.8mV   14.43mA    13.12mA    16.85mA
1.444V    16.72mA    15.1mA     19.87mA
2.2V      19.2mA     17.45mA    22.72mA
[GND Clamp]
|   Voltage   I(typ)   I(min)   I(max)
-1.1V     -34.88mA   -30.35mA   -43.13mA
-1.027V   -30.57mA   -26.14mA   -37.76mA
-935mV    -24.71mA   -20.97mA   -31mA
-796.4mV  -16.18mA   -13.19mA   -21.29mA
-667.7mV  -8.939mA   -6.743mA   -12.34mA
-591.8mV  -5.271mA   -3.798mA   -7.524mA
-525.8mV  -2.772mA   -1.979mA   -3.977mA
-469.7mV  -1.358mA   -988.1uA   -1.794mA
-416.9mV  -599.8uA   -441.5uA   -666.2uA
-357.5mV  -193.2uA   -144.8uA   -173.4uA
-265.1mV  -19.58uA   -16.71uA   -12.27uA
2.2V      0A         0A         0A
[Pullup]
|   Voltage   I(typ)   I(min)   I(max)
-1.1V     5.237uA    8.07uA     2.361uA
226.6mV   -35.36uA   -35.86uA   -35.66uA
342.1mV   -317.6uA   -262.2uA   -438.6uA
434.5mV   -1.159mA   -947.9uA   -1.466mA
556.6mV   -3.33mA    -3.082mA   -3.598mA
688.6mV   -6.489mA   -6.687mA   -6.42mA
985.6mV   -14.65mA   -16.63mA   -13.73mA
1.375V    -26.01mA   -29.8mA    -24.37mA
1.596V    -32.18mA   -36.36mA   -30.67mA
1.698V    -34.46mA   -38.65mA   -33.26mA
1.893V    -38.98mA   -41.97mA   -38.57mA
2.2V      -46.77mA   -46.63mA   -48.43mA
[POWER Clamp]
|   Voltage   I(typ)   I(min)   I(max)
-1.1V     3.036mA    3.636mA    2.186mA
-1.041V   2.347mA    2.931mA    1.626mA
-984.5mV  1.783mA    2.311mA    1.206mA
-915.2mV  1.224mA    1.64mA     782uA
-855.8mV  838.2uA    1.172mA    552.3uA
-779.9mV  448.1uA    701.7uA    396.3uA
-713.9mV  239.3uA    373.1uA    278.6uA
-657.8mV  146.8uA    178.9uA    190.7uA
-595.1mV  80.79uA    68.3uA     109.3uA
-486.2mV  16.71uA    10.13uA    20.94uA
-367.4mV  1.19uA     875.5nA    943.7nA
2.2V      0A         0A         0A
[Ramp]
|   typ   min   max
| 20% - 80%
dV/dt_r   223.87m/35.68p   213.82m/40.12p   244.12m/31.38p
dV/dt_f   322.46m/48.44p   303.56m/60.67p   356.22m/38.33p
| 25% - 75%
|dV/dt_r   186.55m/28.43p   178.18m/31.99p   203.43m/24.85p
|dV/dt_f   268.72m/38.61p   252.97m/48.37p   296.85m/30.51p
R_load = 50
[Rising Waveform]
R_fixture = 50
V_fixture = 0.0
|   Time   V(typ)   V(min)   V(max)
0s        512.1uV    441.1uV    372.2uV
58ps      601.1uV    88.12uV    9.379mV
66ps      2.318mV    -248.7uV   50.24mV
78ps      12.81mV    1.13mV     157.8mV
101ps     159.5mV    21.89mV    324mV
115ps     251.2mV    90.63mV    369.4mV
129ps     309.7mV    180.5mV    391.2mV
155ps     357.4mV    294.4mV    404.4mV
189ps     371.6mV    345.2mV    407mV
404ps     373.6mV    356.8mV    407.2mV
[Falling Waveform]
R_fixture   = 50
V_fixture   = 1.1
V_fixture_min = 1.06
V_fixture_max = 1.17
|   Time   V(typ)   V(min)   V(max)
0s        1.1V       1.06V      1.17V
72ps      1.1V       1.06V      1.161V
78ps      1.099V     1.06V      1.123V
94ps      1.082V     1.057V     941.5mV
115ps     925.7mV    1.048V     742.9mV
132ps     792.3mV    976mV      657.2mV
152ps     684.1mV    848.8mV    610.4mV
187ps     599.1mV    681mV      583.7mV
228ps     571.5mV    594.7mV    577.5mV
404ps     562.6mV    554.1mV    576.3mV
[Rising Waveform]
R_fixture   = 50
V_fixture   = 1.1
V_fixture_min = 1.06
V_fixture_max = 1.17
|   Time   V(typ)   V(min)   V(max)
0s        562.5mV    553.6mV    576.3mV
56ps      558.5mV    549.6mV    587.7mV
65ps      567.4mV    546.6mV    636.7mV
78ps      631.5mV    559.5mV    787.7mV
90ps      744.8mV    614.4mV    895.7mV
109ps     882.1mV    763.9mV    1.006V
127ps     961.9mV    869.3mV    1.069V
148ps     1.019V     945mV      1.113V
223ps     1.087V     1.041V     1.162V
404ps     1.1V       1.06V      1.17V
[Falling Waveform]
R_fixture = 50
V_fixture = 0.0
|   Time   V(typ)   V(min)   V(max)
0s        373.7mV    357mV      407.3mV
57ps      380mV      358.4mV    409.3mV
74ps      372.7mV    368.5mV    309mV
85ps      323.5mV    363.6mV    175.8mV
95ps      247.2mV    335.2mV    101.8mV
110ps     125.1mV    255mV      45.59mV
126ps     56.66mV    157.2mV    19.8mV
149ps     18.47mV    57.09mV    6.29mV
181ps     4.432mV    13.13mV    1.563mV
404ps     571.6uV    524.7uV    394.4uV
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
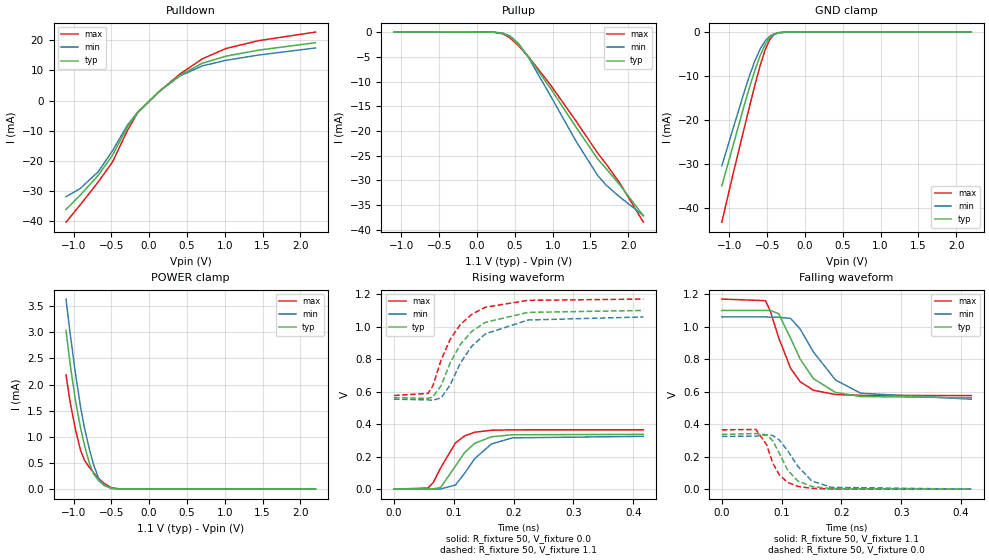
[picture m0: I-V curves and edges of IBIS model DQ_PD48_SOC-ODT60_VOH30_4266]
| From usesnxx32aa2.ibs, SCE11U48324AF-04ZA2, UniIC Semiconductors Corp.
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| DQ_PD48_SOC-ODT60_VOH30_4266
| (48 Ohm Pulldown, 60 Ohm System ODT Setting, VOH=VDDQ/3.0, 3200-4266Mbps)
[Model]   DQ_PD48_SOC-ODT60_VOH30_4266
Model_type   I/O
Vinl = 123.333mV
Vinh = 243.333mV
Vmeas = 183.333mV
Vref = 0.0mV
Cref = 0.0pF
Rref = 60.000Ohm
|   typ   min   max
|C_comp   0.797pF   0.747pF   0.847pF
C_comp_pullup   0.3985pF   0.3735pF   0.4235pF
C_comp_pulldown   0.3985pF   0.3735pF   0.4235pF
| Note: C_comp changes when the ODT circuit is enabled.
[Model Spec]
| Input threshold voltage corners
Vinl   0.1233V   0.1167V   0.1350V
Vinh   0.2433V   0.2367V   0.2550V
| Measurement voltage corners
Vmeas   0.1833V   0.1767V   0.1950V
| Timing spec test load voltage corners
Vref   0.0000V   0.0000V   0.0000V
| Dynamic Overshoot Parameters from LPDDR4 Specification
D_overshoot_ampl_h   0.30   NA   NA
D_overshoot_ampl_l   0.30   NA   NA
D_overshoot_area_h   0.1n   NA   NA
D_overshoot_area_l   0.1n   NA   NA
[Receiver Thresholds]
Vth   = 0.1833V
Vth_min  = 0.1800V
Vth_max  = 0.1866V
Vinh_ac  = 0.060V
Vinh_dc  = 0.060V
Vinl_ac  = -0.060V
Vinl_dc  = -0.060V
Tslew_ac = 5.000ns |Not specified, so set to high value
Threshold_sensitivity = 0.1667
Reference_supply Pullup_ref
[Voltage Range]   1.1000V   1.0600V   1.1700V
[Pullup Reference]   1.1000V   1.0600V   1.1700V
| Junction Temperature (Ambient temp is 35C typ 95C min -40C max)
[Temperature Range]   50.0   110.0   -40.0
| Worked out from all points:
|   slope of the pulldown table from 0 to 0.165 V, typ, clamps not added: 43.8 ohm
|   slope of the pullup table from 0 to 0.165 V, typ, clamps not added: 19.6 kohm
|   GND clamp passes 1 mA (typ) near -0.45 V on its own axis
|   POWER clamp passes 1 mA (typ) near -0.88 V on its own axis
|   rising waveform, R_fixture 50, V_fixture 0.0: 20-80 % time 38.9ps typ, 42.9ps min, 34.1ps max; typ from 0 V to 0.337 V
|   falling waveform, R_fixture 50, V_fixture 1.1: 20-80 % time 48.3ps typ, 60.5ps min, 38.2ps max; typ from 1.1 V to 0.563 V
|   rising waveform, R_fixture 50, V_fixture 1.1: 20-80 % time 54.8ps typ, 58.5ps min, 50.6ps max; typ from 0.562 V to 1.1 V
|   falling waveform, R_fixture 50, V_fixture 0.0: 20-80 % time 31.4ps typ, 39.4ps min, 26.5ps max; typ from 0.337 V to 0 V
[Pulldown]
|   Voltage   I(typ)   I(min)   I(max)
-1.1V     -36.05mA   -31.84mA   -40.29mA
-915.2mV  -31.42mA   -29.19mA   -34.65mA
-674.3mV  -24.77mA   -23.6mA    -26.97mA
-482.9mV  -18.02mA   -16.53mA   -20.26mA
-288.2mV  -8.747mA   -8.13mA    -9.916mA
-152.9mV  -3.951mA   -3.891mA   -4.057mA
134.2mV   3.076mA    3.052mA    3.086mA
408.1mV   8.436mA    8.203mA    8.84mA
705.1mV   12.4mA     11.52mA    13.87mA
1.015V    14.73mA    13.36mA    17.27mA
1.444V    16.72mA    15.1mA     19.87mA
2.2V      19.2mA     17.45mA    22.72mA
[GND Clamp]
|   Voltage   I(typ)   I(min)   I(max)
-1.1V     -34.88mA   -30.35mA   -43.13mA
-944.9mV  -25.34mA   -21.53mA   -31.71mA
-799.7mV  -16.37mA   -13.37mA   -21.52mA
-727.1mV  -12.16mA   -9.546mA   -16.41mA
-664.4mV  -8.768mA   -6.598mA   -12.12mA
-591.8mV  -5.272mA   -3.798mA   -7.524mA
-525.8mV  -2.773mA   -1.979mA   -3.976mA
-473mV    -1.424mA   -1.034mA   -1.893mA
-416.9mV  -597.8uA   -441.8uA   -667.2uA
-354.2mV  -179uA     -135.6uA   -160.9uA
-255.2mV  -14.63uA   -13.07uA   -8.91uA
2.2V      0A         0A         0A
[Pullup]
|   Voltage   I(typ)   I(min)   I(max)
-1.1V     4.189uA    6.459uA    1.888uA
223.3mV   -26.24uA   -27.36uA   -26.24uA
338.8mV   -240.6uA   -199.3uA   -331.6uA
434.5mV   -926.2uA   -757.2uA   -1.172mA
546.7mV   -2.491mA   -2.282mA   -2.719mA
678.7mV   -4.978mA   -5.096mA   -4.948mA
962.5mV   -11.17mA   -12.63mA   -10.48mA
1.312V    -19.28mA   -22.13mA   -18.05mA
1.596V    -25.66mA   -28.99mA   -24.47mA
1.708V    -27.61mA   -30.94mA   -26.67mA
1.887V    -30.87mA   -33.32mA   -30.49mA
2.2V      -37.14mA   -37.08mA   -38.43mA
[POWER Clamp]
|   Voltage   I(typ)   I(min)   I(max)
-1.1V     3.036mA    3.636mA    2.186mA
-1.044V   2.383mA    2.969mA    1.654mA
-977.9mV  1.724mA    2.242mA    1.161mA
-908.6mV  1.178mA    1.583mA    747.7uA
-855.8mV  838uA      1.172mA    552.1uA
-789.8mV  491.2uA    757.5uA    414.8uA
-737mV    296.6uA    478.5uA    318.4uA
-667.7mV  159.9uA    206.1uA    205.2uA
-598.4mV  83.69uA    71.97uA    113.1uA
-496.1mV  20.06uA    12.37uA    25.78uA
-364.1mV  1.103uA    822.4nA    870.4nA
2.2V      0A         0A         0A
[Ramp]
|   typ   min   max
| 20% - 80%
dV/dt_r   202.01m/38.92p   194.75m/42.89p   219.07m/34.15p
dV/dt_f   322.44m/48.30p   303.63m/60.51p   356.22m/38.22p
| 25% - 75%
|dV/dt_r   168.34m/31.05p   162.29m/34.23p   182.56m/27.07p
|dV/dt_f   268.70m/38.52p   253.03m/48.25p   296.85m/30.43p
R_load = 50
[Rising Waveform]
R_fixture = 50
V_fixture = 0.0
|   Time   V(typ)   V(min)   V(max)
0s        404.5uV    343.2uV    295.5uV
57ps      433.5uV    182.9uV    6.548mV
66ps      1.588mV    -159uV     42.03mV
78ps      9.836mV    834.4uV    130.1mV
103ps     142.7mV    25.65mV    284.8mV
118ps     224.5mV    97mV       327.6mV
135ps     281.9mV    187.5mV    350.4mV
163ps     322.4mV    278.2mV    362.5mV
198ps     334.8mV    315.7mV    365.1mV
417ps     337.1mV    324.9mV    365.4mV
[Falling Waveform]
R_fixture   = 50
V_fixture   = 1.1
V_fixture_min = 1.06
V_fixture_max = 1.17
|   Time   V(typ)   V(min)   V(max)
0s        1.1V       1.06V      1.17V
73ps      1.1V       1.06V      1.16V
81ps      1.1V       1.059V     1.096V
95ps      1.08V      1.058V     932.1mV
115ps     928.1mV    1.051V     743.8mV
131ps     800.8mV    985.2mV    661.2mV
153ps     680.8mV    844.8mV    609mV
190ps     595.7mV    672.2mV    582.8mV
232ps     570.4mV    590.7mV    577.4mV
417ps     562.6mV    553.9mV    576.3mV
[Rising Waveform]
R_fixture   = 50
V_fixture   = 1.1
V_fixture_min = 1.06
V_fixture_max = 1.17
|   Time   V(typ)   V(min)   V(max)
0s        562.5mV    553.6mV    576.3mV
57ps      558.8mV    549.3mV    589.3mV
65ps      566.9mV    546.8mV    634.4mV
79ps      637.8mV    561.9mV    795.7mV
94ps      777mV      641.5mV    921.9mV
111ps     890.6mV    774.9mV    1.013V
130ps     970.5mV    879.5mV    1.076V
153ps     1.027V     955.7mV    1.12V
224ps     1.088V     1.041V     1.162V
417ps     1.1V       1.06V      1.17V
[Falling Waveform]
R_fixture = 50
V_fixture = 0.0
|   Time   V(typ)   V(min)   V(max)
0s        337.2mV    325mV      365.5mV
57ps      342.6mV    326.6mV    367.5mV
75ps      335.5mV    335.4mV    273.4mV
85ps      298.1mV    330.8mV    162.1mV
96ps      223mV      302.9mV    89.03mV
110ps     117.6mV    236.9mV    42.26mV
127ps     50.88mV    141.8mV    17.42mV
150ps     16.72mV    51.73mV    5.502mV
183ps     3.859mV    11.53mV    1.291mV
417ps     474uV      435.8uV    319.8uV
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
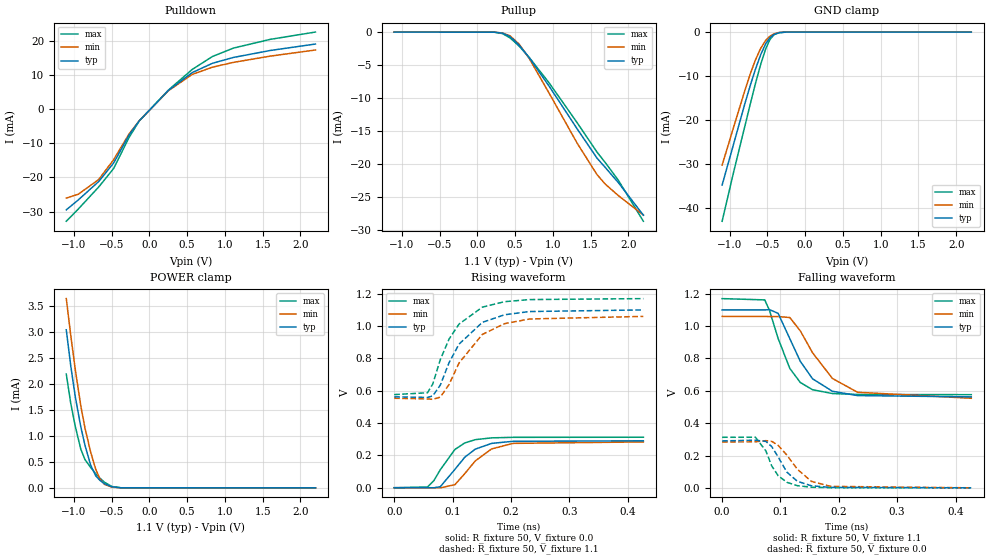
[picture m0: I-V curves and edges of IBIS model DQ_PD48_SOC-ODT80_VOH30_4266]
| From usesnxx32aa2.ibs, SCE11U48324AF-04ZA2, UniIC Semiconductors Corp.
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| DQ_PD48_SOC-ODT80_VOH30_4266
| (48 Ohm Pulldown, 80 Ohm System ODT Setting, VOH=VDDQ/3.0, 3200-4266Mbps)
[Model]   DQ_PD48_SOC-ODT80_VOH30_4266
Model_type   I/O
Vinl = 123.333mV
Vinh = 243.333mV
Vmeas = 183.333mV
Vref = 0.0mV
Cref = 0.0pF
Rref = 80.000Ohm
|   typ   min   max
|C_comp   0.797pF   0.747pF   0.847pF
C_comp_pullup   0.3985pF   0.3735pF   0.4235pF
C_comp_pulldown   0.3985pF   0.3735pF   0.4235pF
| Note: C_comp changes when the ODT circuit is enabled.
[Model Spec]
| Input threshold voltage corners
Vinl   0.1233V   0.1167V   0.1350V
Vinh   0.2433V   0.2367V   0.2550V
| Measurement voltage corners
Vmeas   0.1833V   0.1767V   0.1950V
| Timing spec test load voltage corners
Vref   0.0000V   0.0000V   0.0000V
| Dynamic Overshoot Parameters from LPDDR4 Specification
D_overshoot_ampl_h   0.30   NA   NA
D_overshoot_ampl_l   0.30   NA   NA
D_overshoot_area_h   0.1n   NA   NA
D_overshoot_area_l   0.1n   NA   NA
[Receiver Thresholds]
Vth   = 0.1833V
Vth_min  = 0.1800V
Vth_max  = 0.1866V
Vinh_ac  = 0.060V
Vinh_dc  = 0.060V
Vinl_ac  = -0.060V
Vinl_dc  = -0.060V
Tslew_ac = 5.000ns |Not specified, so set to high value
Threshold_sensitivity = 0.1667
Reference_supply Pullup_ref
[Voltage Range]   1.1000V   1.0600V   1.1700V
[Pullup Reference]   1.1000V   1.0600V   1.1700V
| Junction Temperature (Ambient temp is 35C typ 95C min -40C max)
[Temperature Range]   50.0   110.0   -40.0
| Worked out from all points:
|   slope of the pulldown table from 0 to 0.165 V, typ, clamps not added: 43.9 ohm
|   slope of the pullup table from 0 to 0.165 V, typ, clamps not added: 25.8 kohm
|   GND clamp passes 1 mA (typ) near -0.45 V on its own axis
|   POWER clamp passes 1 mA (typ) near -0.88 V on its own axis
|   rising waveform, R_fixture 50, V_fixture 0.0: 20-80 % time 42.3ps typ, 45.5ps min, 36.9ps max; typ from 0 V to 0.29 V
|   falling waveform, R_fixture 50, V_fixture 1.1: 20-80 % time 48.2ps typ, 60.3ps min, 38.2ps max; typ from 1.1 V to 0.563 V
|   rising waveform, R_fixture 50, V_fixture 1.1: 20-80 % time 55.1ps typ, 59.1ps min, 50.8ps max; typ from 0.562 V to 1.1 V
|   falling waveform, R_fixture 50, V_fixture 0.0: 20-80 % time 31.9ps typ, 39.9ps min, 27.1ps max; typ from 0.29 V to 0 V
[Pulldown]
|   Voltage   I(typ)   I(min)   I(max)
-1.1V     -29.51mA   -26.05mA   -32.86mA
-941.6mV  -26.6mA    -24.92mA   -29.28mA
-671mV    -21.19mA   -20.61mA   -22.8mA
-473mV    -15.74mA   -14.78mA   -17.36mA
-268.4mV  -7.537mA   -7.202mA   -8.239mA
-133.1mV  -3.344mA   -3.325mA   -3.363mA
253mV     5.577mA    5.496mA    5.683mA
566.5mV   10.8mA     10.26mA    11.71mA
837.1mV   13.56mA    12.41mA    15.56mA
1.114V    15.26mA    13.81mA    18.01mA
1.603V    17.31mA    15.65mA    20.58mA
2.2V      19.2mA     17.45mA    22.72mA
[GND Clamp]
|   Voltage   I(typ)   I(min)   I(max)
-1.1V     -34.88mA   -30.34mA   -43.13mA
-948.2mV  -25.55mA   -21.71mA   -31.95mA
-796.4mV  -16.18mA   -13.19mA   -21.29mA
-723.8mV  -11.98mA   -9.382mA   -16.18mA
-661.1mV  -8.597mA   -6.455mA   -11.9mA
-588.5mV  -5.128mA   -3.689mA   -7.329mA
-522.5mV  -2.672mA   -1.906mA   -3.822mA
-466.4mV  -1.296mA   -943.6uA   -1.695mA
-413.6mV  -565.2uA   -416.7uA   -622.2uA
-344.3mV  -145.2uA   -109.1uA   -124uA
-248.6mV  -12.15uA   -10.93uA   -7.038uA
2.2V      0A         0A         0A
[Pullup]
|   Voltage   I(typ)   I(min)   I(max)
-1.1V     3.142uA    4.844uA    1.416uA
229.9mV   -22.65uA   -22.9uA    -23.35uA
335.5mV   -170.6uA   -141.7uA   -234.7uA
437.8mV   -720.4uA   -590.6uA   -907.3uA
556.6mV   -1.993mA   -1.844mA   -2.153mA
688.6mV   -3.881mA   -3.997mA   -3.841mA
955.9mV   -8.251mA   -9.322mA   -7.75mA
1.325V    -14.67mA   -16.84mA   -13.74mA
1.586V    -19.06mA   -21.55mA   -18.15mA
1.695V    -20.47mA   -22.99mA   -19.73mA
1.867V    -22.74mA   -24.71mA   -22.38mA
2.2V      -27.69mA   -27.67mA   -28.61mA
[POWER Clamp]
|   Voltage   I(typ)   I(min)   I(max)
-1.1V     3.036mA    3.636mA    2.186mA
-1.041V   2.347mA    2.932mA    1.626mA
-981.2mV  1.754mA    2.277mA    1.183mA
-908.6mV  1.178mA    1.583mA    748.3uA
-852.5mV  818.7uA    1.149mA    543.7uA
-776.6mV  434.3uA    683.6uA    390.2uA
-710.6mV  232.2uA    359.1uA    273.1uA
-654.5mV  142.7uA    170.4uA    185.9uA
-595.1mV  80.75uA    68.33uA    109.3uA
-496.1mV  20.08uA    12.34uA    25.73uA
-380.6mV  1.618uA    1.133uA    1.341uA
2.2V      0A         0A         0A
[Ramp]
|   typ   min   max
| 20% - 80%
dV/dt_r   174.04m/42.34p   169.99m/45.46p   187.43m/36.93p
dV/dt_f   322.47m/48.21p   303.66m/60.31p   356.22m/38.17p
| 25% - 75%
|dV/dt_r   145.03m/33.79p   141.66m/36.28p   156.19m/29.26p
|dV/dt_f   268.72m/38.42p   253.05m/48.12p   296.85m/30.37p
R_load = 50
[Rising Waveform]
R_fixture = 50
V_fixture = 0.0
|   Time   V(typ)   V(min)   V(max)
0s        297.1uV    244.7uV    219.5uV
57ps      193.3uV    317.9uV    4.989mV
68ps      161.2uV    -283.7uV   44.27mV
79ps      6.636mV    -427.9uV   111.5mV
104ps     113.6mV    18.95mV    236.9mV
121ps     189.2mV    87.73mV    277.3mV
139ps     239.1mV    166.4mV    297.6mV
167ps     274.5mV    240.5mV    308.8mV
204ps     287.5mV    274.6mV    312mV
427ps     290.4mV    283.6mV    312.6mV
[Falling Waveform]
R_fixture   = 50
V_fixture   = 1.1
V_fixture_min = 1.06
V_fixture_max = 1.17
|   Time   V(typ)   V(min)   V(max)
0s        1.1V       1.06V      1.17V
73ps      1.1V       1.06V      1.162V
81ps      1.102V     1.059V     1.099V
96ps      1.079V     1.059V     923.4mV
116ps     922.4mV    1.053V     738.5mV
134ps     782.3mV    970.5mV    651.5mV
155ps     674.2mV    835.3mV    606.6mV
189ps     597.3mV    676.5mV    583.2mV
232ps     570.5mV    591mV      577.4mV
427ps     562.5mV    553.9mV    576.3mV
[Rising Waveform]
R_fixture   = 50
V_fixture   = 1.1
V_fixture_min = 1.06
V_fixture_max = 1.17
|   Time   V(typ)   V(min)   V(max)
0s        562.4mV    553.6mV    576.3mV
57ps      558.7mV    549.5mV    587.6mV
66ps      567.7mV    546.8mV    641mV
79ps      635mV      560.6mV    792.8mV
94ps      773.7mV    638.6mV    919.8mV
111ps     887.9mV    771.2mV    1.012V
151ps     1.023V     948.2mV    1.117V
189ps     1.07V      1.015V     1.151V
232ps     1.09V      1.044V     1.164V
427ps     1.1V       1.06V      1.17V
[Falling Waveform]
R_fixture = 50
V_fixture = 0.0
|   Time   V(typ)   V(min)   V(max)
0s        290.4mV    283.7mV    312.7mV
57ps      294.7mV    284.8mV    313.1mV
75ps      287.2mV    291.9mV    228.3mV
85ps      255.3mV    287.5mV    135.7mV
96ps      191.6mV    263.2mV    75.44mV
111ps     97.1mV     202.3mV    34.33mV
129ps     40.49mV    114.9mV    13.61mV
153ps     12.93mV    40.27mV    4.153mV
186ps     3.049mV    9.334mV    986.9uV
427ps     369.6uV    344.9uV    245uV
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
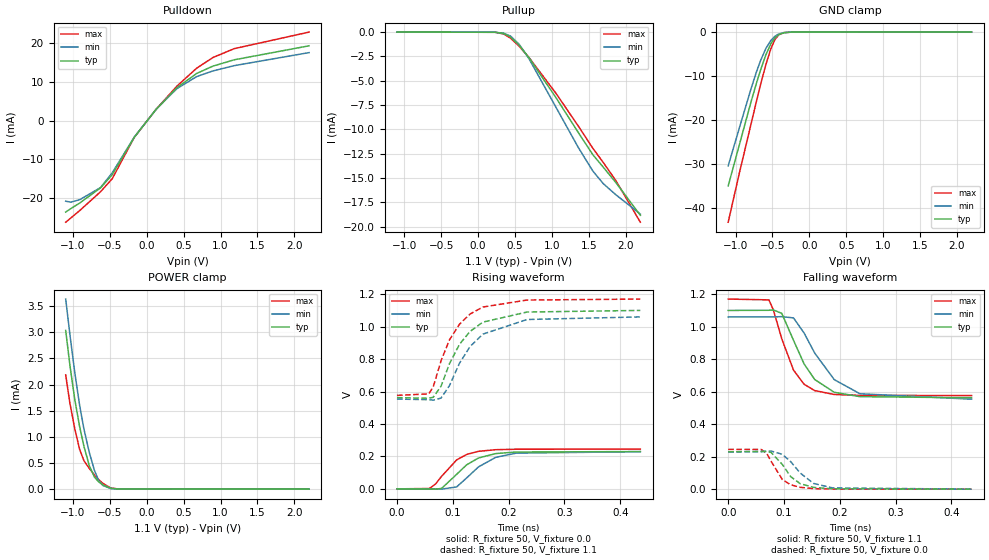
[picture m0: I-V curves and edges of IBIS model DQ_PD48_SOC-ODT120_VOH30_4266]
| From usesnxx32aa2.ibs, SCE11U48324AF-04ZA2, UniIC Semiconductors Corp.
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| DQ_PD48_SOC-ODT120_VOH30_4266
| (48 Ohm Pulldown, 120 Ohm System ODT Setting, VOH=VDDQ/3.0, 3200-4266Mbps)
[Model]   DQ_PD48_SOC-ODT120_VOH30_4266
Model_type   I/O
Vinl = 123.333mV
Vinh = 243.333mV
Vmeas = 183.333mV
Vref = 0.0mV
Cref = 0.0pF
Rref = 120.000Ohm
|   typ   min   max
|C_comp   0.797pF   0.747pF   0.847pF
C_comp_pullup   0.3985pF   0.3735pF   0.4235pF
C_comp_pulldown   0.3985pF   0.3735pF   0.4235pF
| Note: C_comp changes when the ODT circuit is enabled.
[Model Spec]
| Input threshold voltage corners
Vinl   0.1233V   0.1167V   0.1350V
Vinh   0.2433V   0.2367V   0.2550V
| Measurement voltage corners
Vmeas   0.1833V   0.1767V   0.1950V
| Timing spec test load voltage corners
Vref   0.0000V   0.0000V   0.0000V
| Dynamic Overshoot Parameters from LPDDR4 Specification
D_overshoot_ampl_h   0.30   NA   NA
D_overshoot_ampl_l   0.30   NA   NA
D_overshoot_area_h   0.1n   NA   NA
D_overshoot_area_l   0.1n   NA   NA
[Receiver Thresholds]
Vth   = 0.1833V
Vth_min  = 0.1800V
Vth_max  = 0.1866V
Vinh_ac  = 0.060V
Vinh_dc  = 0.060V
Vinl_ac  = -0.060V
Vinl_dc  = -0.060V
Tslew_ac = 5.000ns |Not specified, so set to high value
Threshold_sensitivity = 0.1667
Reference_supply Pullup_ref
[Voltage Range]   1.1000V   1.0600V   1.1700V
[Pullup Reference]   1.1000V   1.0600V   1.1700V
| Junction Temperature (Ambient temp is 35C typ 95C min -40C max)
[Temperature Range]   50.0   110.0   -40.0
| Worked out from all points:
|   slope of the pulldown table from 0 to 0.165 V, typ, clamps not added: 43.9 ohm
|   slope of the pullup table from 0 to 0.165 V, typ, clamps not added: 38.9 kohm
|   GND clamp passes 1 mA (typ) near -0.45 V on its own axis
|   POWER clamp passes 1 mA (typ) near -0.88 V on its own axis
|   rising waveform, R_fixture 50, V_fixture 0.0: 20-80 % time 46ps typ, 50.2ps min, 40.9ps max; typ from 0 V to 0.23 V
|   falling waveform, R_fixture 50, V_fixture 1.1: 20-80 % time 48.1ps typ, 60.1ps min, 38.1ps max; typ from 1.1 V to 0.563 V
|   rising waveform, R_fixture 50, V_fixture 1.1: 20-80 % time 55.2ps typ, 59.5ps min, 50.8ps max; typ from 0.562 V to 1.1 V
|   falling waveform, R_fixture 50, V_fixture 0.0: 20-80 % time 31.5ps typ, 39.1ps min, 26.9ps max; typ from 0.23 V to 0 V
[Pulldown]
|   Voltage   I(typ)   I(min)   I(max)
-1.1V     -23.5mA    -20.7mA    -26.1mA
-1.031V   -22.61mA   -20.96mA   -25.04mA
-908.6mV  -21.16mA   -20.31mA   -23.09mA
-628.1mV  -17.3mA    -17.22mA   -18.29mA
-469.7mV  -13.91mA   -13.43mA   -14.95mA
-169.4mV  -4.248mA   -4.232mA   -4.304mA
127.6mV   2.931mA    2.91mA     2.937mA
408.1mV   8.437mA    8.203mA    8.84mA
675.4mV   12.09mA    11.29mA    13.44mA
896.5mV   13.98mA    12.75mA    16.19mA
1.184V    15.6mA     14.1mA     18.46mA
2.2V      19.2mA     17.45mA    22.72mA
[GND Clamp]
|   Voltage   I(typ)   I(min)   I(max)
-1.1V     -34.88mA   -30.34mA   -43.13mA
-948.2mV  -25.55mA   -21.71mA   -31.95mA
-796.4mV  -16.18mA   -13.19mA   -21.29mA
-720.5mV  -11.79mA   -9.217mA   -15.95mA
-661.1mV  -8.597mA   -6.455mA   -11.9mA
-588.5mV  -5.129mA   -3.689mA   -7.329mA
-522.5mV  -2.67mA    -1.907mA   -3.823mA
-466.4mV  -1.296mA   -944.9uA   -1.694mA
-413.6mV  -566.1uA   -418.5uA   -621.9uA
-344.3mV  -143.3uA   -109.5uA   -124.7uA
-242mV    -9.986uA   -9.216uA   -5.624uA
2.2V      0A         0A         0A
[Pullup]
|   Voltage   I(typ)   I(min)   I(max)
-1.1V     2.095uA    3.229uA    944.4nA
229.9mV   -15.06uA   -15.37uA   -15.54uA
345.4mV   -134.6uA   -110.6uA   -185.9uA
441.1mV   -502uA     -412uA     -628.6uA
556.6mV   -1.343mA   -1.244mA   -1.449mA
688.6mV   -2.62mA    -2.707mA   -2.588mA
1.055V    -6.724mA   -7.711mA   -6.28mA
1.362V    -10.36mA   -11.9mA    -9.692mA
1.556V    -12.6mA    -14.28mA   -11.94mA
1.698V    -13.89mA   -15.58mA   -13.41mA
1.867V    -15.45mA   -16.71mA   -15.25mA
2.2V      -18.83mA   -18.71mA   -19.54mA
[POWER Clamp]
|   Voltage   I(typ)   I(min)   I(max)
-1.1V     3.036mA    3.636mA    2.186mA
-1.044V   2.383mA    2.969mA    1.653mA
-977.9mV  1.724mA    2.242mA    1.161mA
-911.9mV  1.201mA    1.611mA    764.9uA
-852.5mV  818.5uA    1.149mA    543.7uA
-779.9mV  448.2uA    701.7uA    396.3uA
-710.6mV  232.2uA    359.3uA    273.1uA
-654.5mV  142.7uA    170.4uA    185.9uA
-598.4mV  83.7uA     71.97uA    113uA
-489.5mV  17.77uA    10.87uA    22.46uA
-374mV    1.382uA    999.2nA    1.121uA
2.2V      0A         0A         0A
[Ramp]
|   typ   min   max
| 20% - 80%
dV/dt_r   137.86m/46.01p   137.42m/50.19p   147.05m/40.90p
dV/dt_f   322.47m/48.05p   303.67m/60.10p   356.22m/38.04p
| 25% - 75%
|dV/dt_r   114.88m/36.71p   114.52m/40.09p   122.55m/32.44p
|dV/dt_f   268.72m/38.31p   253.06m/47.95p   296.85m/30.29p
R_load = 50
[Rising Waveform]
R_fixture = 50
V_fixture = 0.0
|   Time   V(typ)   V(min)   V(max)
0s        189.9uV    148.5uV    142.9uV
58ps      -162.6uV   393.6uV    2.191mV
69ps      -1.599mV   -499uV     29.52mV
80ps      2.574mV    -1.816mV   77.31mV
107ps     90.05mV    12.26mV    178.7mV
125ps     148.5mV    67.84mV    212.4mV
146ps     190.3mV    135.3mV    231.4mV
177ps     217.6mV    194.4mV    241.5mV
214ps     227.2mV    220.4mV    244.4mV
436ps     230mV      229.2mV    245.2mV
[Falling Waveform]
R_fixture   = 50
V_fixture   = 1.1
V_fixture_min = 1.06
V_fixture_max = 1.17
|   Time   V(typ)   V(min)   V(max)
0s        1.1V       1.06V      1.17V
73ps      1.101V     1.06V      1.165V
81ps      1.103V     1.06V      1.102V
96ps      1.082V     1.062V     925.3mV
117ps     916.2mV    1.054V     732.9mV
136ps     770.7mV    960.9mV    645.6mV
155ps     674.9mV    837.5mV    606.7mV
190ps     596.3mV    674.2mV    582.9mV
236ps     569.5mV    587.3mV    577.2mV
436ps     562.5mV    553.9mV    576.3mV
[Rising Waveform]
R_fixture   = 50
V_fixture   = 1.1
V_fixture_min = 1.06
V_fixture_max = 1.17
|   Time   V(typ)   V(min)   V(max)
0s        562.4mV    553.6mV    576.3mV
57ps      558.6mV    549.7mV    585.5mV
65ps      564.8mV    547mV      628.8mV
79ps      632.5mV    559.5mV    790.1mV
94ps      770.9mV    635.8mV    917.9mV
112ps     891mV      774.4mV    1.015V
131ps     970.6mV    877.5mV    1.078V
154ps     1.028V     953.9mV    1.121V
233ps     1.09V      1.044V     1.164V
436ps     1.1V       1.06V      1.17V
[Falling Waveform]
R_fixture = 50
V_fixture = 0.0
|   Time   V(typ)   V(min)   V(max)
0s        230mV      229.3mV    245.3mV
59ps      232.9mV    230.2mV    244.5mV
69ps      232.9mV    233.2mV    220.6mV
77ps      225.9mV    234.5mV    171mV
97ps      152.4mV    214.7mV    59.13mV
112ps     77.19mV    169.3mV    27.12mV
129ps     34.01mV    99.52mV    11.37mV
153ps     10.95mV    35.25mV    3.46mV
187ps     2.467mV    7.906mV    767uV
436ps     262uV      249.7uV    168.4uV
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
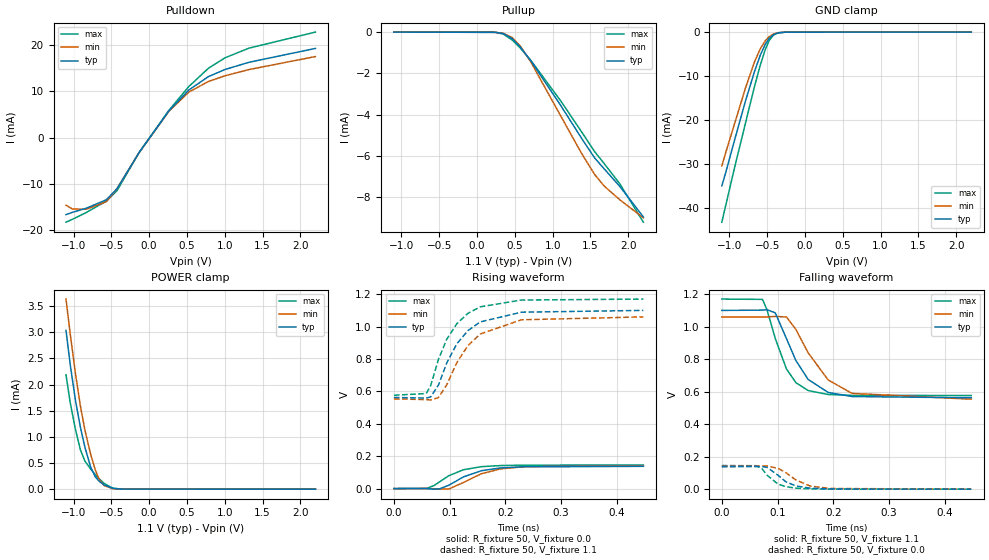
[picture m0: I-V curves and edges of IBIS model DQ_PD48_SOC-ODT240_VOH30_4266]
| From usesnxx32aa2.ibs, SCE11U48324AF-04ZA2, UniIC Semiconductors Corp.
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| DQ_PD48_SOC-ODT240_VOH30_4266
| (48 Ohm Pulldown, 240 Ohm System ODT Setting, VOH=VDDQ/3.0, 3200-4266Mbps)
[Model]   DQ_PD48_SOC-ODT240_VOH30_4266
Model_type   I/O
Vinl = 123.333mV
Vinh = 243.333mV
Vmeas = 183.333mV
Vref = 0.0mV
Cref = 0.0pF
Rref = 240.000Ohm
|   typ   min   max
|C_comp   0.797pF   0.747pF   0.847pF
C_comp_pullup   0.3985pF   0.3735pF   0.4235pF
C_comp_pulldown   0.3985pF   0.3735pF   0.4235pF
| Note: C_comp changes when the ODT circuit is enabled.
[Model Spec]
| Input threshold voltage corners
Vinl   0.1233V   0.1167V   0.1350V
Vinh   0.2433V   0.2367V   0.2550V
| Measurement voltage corners
Vmeas   0.1833V   0.1767V   0.1950V
| Timing spec test load voltage corners
Vref   0.0000V   0.0000V   0.0000V
| Dynamic Overshoot Parameters from LPDDR4 Specification
D_overshoot_ampl_h   0.30   NA   NA
D_overshoot_ampl_l   0.30   NA   NA
D_overshoot_area_h   0.1n   NA   NA
D_overshoot_area_l   0.1n   NA   NA
[Receiver Thresholds]
Vth   = 0.1833V
Vth_min  = 0.1800V
Vth_max  = 0.1866V
Vinh_ac  = 0.060V
Vinh_dc  = 0.060V
Vinl_ac  = -0.060V
Vinl_dc  = -0.060V
Tslew_ac = 5.000ns |Not specified, so set to high value
Threshold_sensitivity = 0.1667
Reference_supply Pullup_ref
[Voltage Range]   1.1000V   1.0600V   1.1700V
[Pullup Reference]   1.1000V   1.0600V   1.1700V
| Junction Temperature (Ambient temp is 35C typ 95C min -40C max)
[Temperature Range]   50.0   110.0   -40.0
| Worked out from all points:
|   slope of the pulldown table from 0 to 0.165 V, typ, clamps not added: 44 ohm
|   slope of the pullup table from 0 to 0.165 V, typ, clamps not added: 80.3 kohm
|   GND clamp passes 1 mA (typ) near -0.45 V on its own axis
|   POWER clamp passes 1 mA (typ) near -0.88 V on its own axis
|   rising waveform, R_fixture 50, V_fixture 0.0: 20-80 % time 54.6ps typ, 57.3ps min, 47.9ps max; typ from 0 V to 0.137 V
|   falling waveform, R_fixture 50, V_fixture 1.1: 20-80 % time 47.9ps typ, 59.9ps min, 38ps max; typ from 1.1 V to 0.563 V
|   rising waveform, R_fixture 50, V_fixture 1.1: 20-80 % time 55.4ps typ, 60.1ps min, 50.9ps max; typ from 0.562 V to 1.1 V
|   falling waveform, R_fixture 50, V_fixture 0.0: 20-80 % time 31.7ps typ, 39.5ps min, 27.6ps max; typ from 0.137 V to 0 V
[Pulldown]
|   Voltage   I(typ)   I(min)   I(max)
-1.1V     -16.6mA    -14.59mA   -18.24mA
-1.014V   -16.11mA   -15.4mA    -17.61mA
-832.7mV  -15.24mA   -15.45mA   -16.16mA
-565.4mV  -13.4mA    -13.8mA    -13.69mA
-423.5mV  -10.99mA   -10.97mA   -11.41mA
-133.1mV  -3.241mA   -3.259mA   -3.21mA
262.9mV   5.775mA    5.687mA    5.893mA
523.6mV   10.22mA    9.779mA    10.97mA
784.3mV   13.13mA    12.08mA    14.93mA
1.005V    14.67mA    13.31mA    17.19mA
1.325V    16.23mA    14.66mA    19.28mA
2.2V      19.2mA     17.45mA    22.72mA
[GND Clamp]
|   Voltage   I(typ)   I(min)   I(max)
-1.1V     -34.88mA   -30.35mA   -43.13mA
-1.047V   -31.79mA   -27.25mA   -39.23mA
-941.6mV  -25.13mA   -21.34mA   -31.48mA
-786.5mV  -15.59mA   -12.65mA   -20.59mA
-667.7mV  -8.94mA    -6.742mA   -12.34mA
-591.8mV  -5.273mA   -3.798mA   -7.523mA
-525.8mV  -2.772mA   -1.977mA   -3.977mA
-473mV    -1.425mA   -1.032mA   -1.891mA
-416.9mV  -597.5uA   -441.6uA   -665.5uA
-354.2mV  -179.1uA   -135.1uA   -159.7uA
-251.9mV  -13.26uA   -12.18uA   -7.885uA
2.2V      0A         0A         0A
[Pullup]
|   Voltage   I(typ)   I(min)   I(max)
-1.1V     1.047uA    1.615uA    471.8nA
239.8mV   -9.315uA   -9.231uA   -9.968uA
345.4mV   -66.89uA   -55.15uA   -92.21uA
464.2mV   -314.7uA   -264uA     -380.9uA
569.8mV   -714uA     -668.3uA   -763.5uA
711.7mV   -1.395mA   -1.451mA   -1.372mA
1.108V    -3.568mA   -4.077mA   -3.344mA
1.388V    -5.184mA   -5.92mA    -4.87mA
1.556V    -6.109mA   -6.911mA   -5.805mA
1.682V    -6.64mA    -7.474mA   -6.383mA
1.887V    -7.482mA   -8.134mA   -7.355mA
2.2V      -8.971mA   -9.014mA   -9.226mA
[POWER Clamp]
|   Voltage   I(typ)   I(min)   I(max)
-1.1V     3.036mA    3.636mA    2.186mA
-1.044V   2.383mA    2.97mA     1.654mA
-974.6mV  1.695mA    2.208mA    1.139mA
-908.6mV  1.178mA    1.583mA    747.8uA
-849.2mV  799.3uA    1.126mA    535.5uA
-773.3mV  420.8uA    665.6uA    384.1uA
-710.6mV  232.3uA    359.1uA    273.1uA
-657.8mV  146.8uA    178.8uA    190.7uA
-595.1mV  80.8uA     68.3uA     109.2uA
-482.9mV  15.75uA    9.494uA    19.52uA
-360.8mV  1.024uA    769.9nA    793.9nA
2.2V      0A         0A         0A
[Ramp]
|   typ   min   max
| 20% - 80%
dV/dt_r   82.40m/54.58p   84.17m/57.34p   87.17m/47.88p
dV/dt_f   322.45m/47.89p   303.69m/59.92p   356.22m/37.96p
| 25% - 75%
|dV/dt_r   68.67m/43.50p   70.14m/45.73p   72.64m/37.99p
|dV/dt_f   268.71m/38.21p   253.08m/47.89p   296.85m/30.20p
R_load = 50
[Rising Waveform]
R_fixture = 50
V_fixture = 0.0
|   Time   V(typ)   V(min)   V(max)
0s        80.08uV    48.31uV    64.6uV
59ps      -449.2uV   398.8uV    1.426mV
72ps      -3.569mV   -898.3uV   18.69mV
82ps      -1.835mV   -2.853mV   41.6mV
99ps      21.48mV    -2.008mV   80.17mV
125ps     72.4mV     38.01mV    116.4mV
157ps     110.3mV    91.68mV    135.3mV
191ps     127.5mV    121.3mV    142.1mV
233ps     134.7mV    134.9mV    144.6mV
448ps     137.4mV    140.3mV    145.4mV
[Falling Waveform]
R_fixture   = 50
V_fixture   = 1.1
V_fixture_min = 1.06
V_fixture_max = 1.17
|   Time   V(typ)   V(min)   V(max)
0s        1.1V       1.06V      1.17V
73ps      1.102V     1.059V     1.168V
81ps      1.105V     1.06V      1.105V
96ps      1.085V     1.063V     927.5mV
116ps     927.1mV    1.06V      740.3mV
133ps     791.9mV    983.1mV    655.7mV
155ps     675.5mV    839.5mV    607mV
191ps     595.3mV    671.8mV    582.7mV
234ps     570mV      589.5mV    577.3mV
448ps     562.6mV    553.8mV    576.3mV
[Rising Waveform]
R_fixture   = 50
V_fixture   = 1.1
V_fixture_min = 1.06
V_fixture_max = 1.17
|   Time   V(typ)   V(min)   V(max)
0s        562.4mV    553.6mV    576.3mV
58ps      558.7mV    549.4mV    586.8mV
66ps      565.8mV    547.1mV    635.6mV
80ps      638.8mV    561.7mV    797.6mV
95ps      776.4mV    641.3mV    922.3mV
113ps     894mV      777.7mV    1.018V
133ps     975.5mV    882.9mV    1.082V
155ps     1.029V     954.3mV    1.122V
229ps     1.089V     1.042V     1.164V
448ps     1.1V       1.06V      1.17V
[Falling Waveform]
R_fixture = 50
V_fixture = 0.0
|   Time   V(typ)   V(min)   V(max)
0s        137.5mV    140.4mV    145.4mV
61ps      139.4mV    141.6mV    144.5mV
72ps      139.4mV    143.2mV    126.8mV
81ps      134.8mV    143mV      86.57mV
101ps     85.45mV    127.8mV    31.28mV
115ps     45.57mV    102mV      15.42mV
133ps     19.66mV    56.35mV    6.266mV
159ps     5.961mV    18.81mV    1.775mV
195ps     1.278mV    4.168mV    378.1uV
448ps     145uV      142.6uV    87.51uV
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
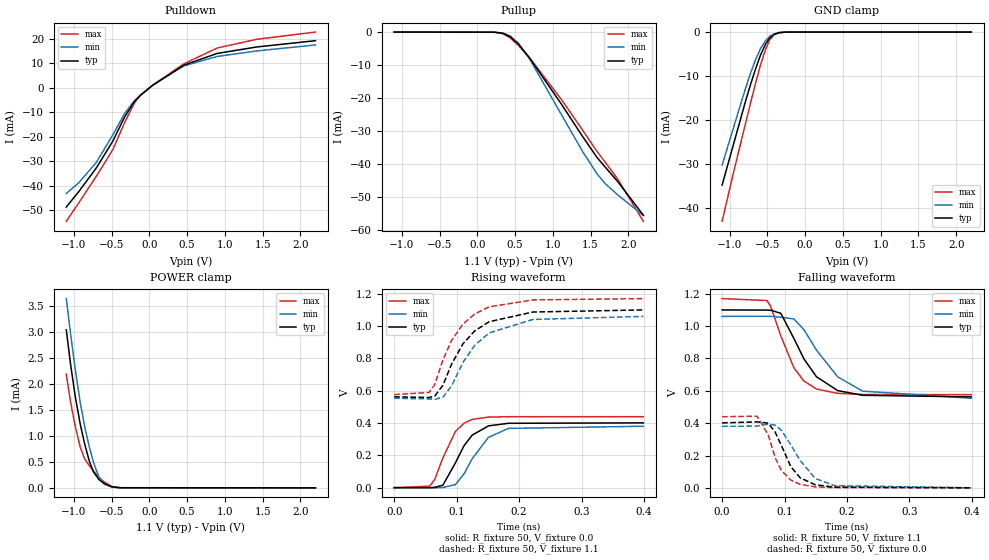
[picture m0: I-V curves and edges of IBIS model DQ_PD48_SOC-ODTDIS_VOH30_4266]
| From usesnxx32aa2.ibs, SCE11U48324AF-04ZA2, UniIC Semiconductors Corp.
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| DQ_PD48_SOC-ODTDIS_VOH30_4266
| (48 Ohm Pulldown, SOC ODT disabled setting, VOH=VDDQ/3.0 cal. point, 3200-4266Mbps)
[Model]   DQ_PD48_SOC-ODTDIS_VOH30_4266
Model_type   I/O
Vinl = 123.333mV
Vinh = 243.333mV
Vmeas = 183.333mV
Vref = 0.0mV
Cref = 0.0pF
|   typ   min   max
|C_comp   0.797pF   0.747pF   0.847pF
C_comp_pullup   0.3985pF   0.3735pF   0.4235pF
C_comp_pulldown   0.3985pF   0.3735pF   0.4235pF
| Note: C_comp changes when the ODT circuit is enabled.
[Model Spec]
| Input threshold voltage corners
Vinl   0.1233V   0.1167V   0.1350V
Vinh   0.2433V   0.2367V   0.2550V
| Measurement voltage corners
Vmeas   0.1833V   0.1767V   0.1950V
| Timing spec test load voltage corners
Vref   0.0000V   0.0000V   0.0000V
| Dynamic Overshoot Parameters from LPDDR4 Specification
D_overshoot_ampl_h   0.30   NA   NA
D_overshoot_ampl_l   0.30   NA   NA
D_overshoot_area_h   0.1n   NA   NA
D_overshoot_area_l   0.1n   NA   NA
[Receiver Thresholds]
Vth   = 0.1833V
Vth_min  = 0.1800V
Vth_max  = 0.1866V
Vinh_ac  = 0.060V
Vinh_dc  = 0.060V
Vinl_ac  = -0.060V
Vinl_dc  = -0.060V
Tslew_ac = 5.000ns |Not specified, so set to high value
Threshold_sensitivity = 0.1667
Reference_supply Pullup_ref
[Voltage Range]   1.1000V   1.0600V   1.1700V
[Pullup Reference]   1.1000V   1.0600V   1.1700V
| Junction Temperature (Ambient temp is 35C typ 95C min -40C max)
[Temperature Range]   50.0   110.0   -40.0
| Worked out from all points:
|   slope of the pulldown table from 0 to 0.165 V, typ, clamps not added: 43.8 ohm
|   slope of the pullup table from 0 to 0.165 V, typ, clamps not added: 13.1 kohm
|   GND clamp passes 1 mA (typ) near -0.45 V on its own axis
|   POWER clamp passes 1 mA (typ) near -0.88 V on its own axis
|   rising waveform, R_fixture 50, V_fixture 0.0: 20-80 % time 34.3ps typ, 38.4ps min, 29.7ps max; typ from 0.001 V to 0.401 V
|   falling waveform, R_fixture 50, V_fixture 1.1: 20-80 % time 48.6ps typ, 60.9ps min, 38.4ps max; typ from 1.1 V to 0.563 V
|   rising waveform, R_fixture 50, V_fixture 1.1: 20-80 % time 54.4ps typ, 57.3ps min, 50.7ps max; typ from 0.562 V to 1.1 V
|   falling waveform, R_fixture 50, V_fixture 0.0: 20-80 % time 31.8ps typ, 39.3ps min, 26.8ps max; typ from 0.402 V to 0.001 V
[Pulldown]
|   Voltage   I(typ)   I(min)   I(max)
-1.1V     -48.63mA   -43.11mA   -54.44mA
-938.3mV  -42.49mA   -38.85mA   -47.12mA
-704mV    -32.79mA   -30.49mA   -36.17mA
-482.9mV  -21.72mA   -19.22mA   -25.17mA
-327.8mV  -11.9mA    -10.49mA   -14.22mA
-195.8mV  -5.533mA   -5.265mA   -6.079mA
-116.6mV  -3.025mA   -2.977mA   -3.066mA
45.1mV    1.049mA    1.046mA    1.047mA
454.3mV   9.185mA    8.882mA    9.718mA
899.8mV   14.01mA    12.77mA    16.23mA
1.425V    16.64mA    15.03mA    19.77mA
2.2V      19.2mA     17.45mA    22.72mA
[GND Clamp]
|   Voltage   I(typ)   I(min)   I(max)
-1.1V     -34.88mA   -30.34mA   -43.13mA
-935mV    -24.71mA   -20.97mA   -31mA
-796.4mV  -16.18mA   -13.19mA   -21.29mA
-720.5mV  -11.79mA   -9.217mA   -15.95mA
-661.1mV  -8.596mA   -6.454mA   -11.9mA
-591.8mV  -5.271mA   -3.797mA   -7.525mA
-522.5mV  -2.67mA    -1.906mA   -3.824mA
-466.4mV  -1.297mA   -942.9uA   -1.696mA
-413.6mV  -564.8uA   -417.3uA   -623.3uA
-347.6mV  -154.3uA   -117.7uA   -134.7uA
-248.6mV  -12.11uA   -10.87uA   -6.998uA
2.2V      0A         0A         0A
[Pullup]
|   Voltage   I(typ)   I(min)   I(max)
-1.1V     6.284uA    9.684uA    2.832uA
223.3mV   -39.19uA   -40.62uA   -39.36uA
335.5mV   -341uA     -283.4uA   -469.1uA
434.5mV   -1.386mA   -1.133mA   -1.752mA
546.7mV   -3.719mA   -3.404mA   -4.061mA
688.6mV   -7.724mA   -7.946mA   -7.651mA
1.118V    -21.94mA   -25.13mA   -20.53mA
1.395V    -31.61mA   -36.14mA   -29.67mA
1.586V    -37.97mA   -42.9mA    -36.14mA
1.695V    -40.88mA   -45.88mA   -39.4mA
1.867V    -45.46mA   -49.42mA   -44.76mA
2.2V      -55.46mA   -55.5mA    -57.28mA
[POWER Clamp]
|   Voltage   I(typ)   I(min)   I(max)
-1.1V     3.036mA    3.636mA    2.186mA
-1.044V   2.383mA    2.969mA    1.654mA
-981.2mV  1.754mA    2.277mA    1.183mA
-915.2mV  1.224mA    1.64mA     781.7uA
-855.8mV  838.1uA    1.172mA    552.5uA
-793.1mV  506.4uA    776.1uA    421uA
-740.3mV  306.1uA    494.5uA    324.3uA
-667.7mV  159.9uA    206.1uA    205.2uA
-598.4mV  83.68uA    71.96uA    113.1uA
-496.1mV  20.06uA    12.36uA    25.74uA
-390.5mV  2.036uA    1.387uA    1.776uA
2.2V      0A         0A         0A
[Ramp]
|   typ   min   max
| 20% - 80%
dV/dt_r   240.49m/34.27p   228.04m/38.36p   263.55m/29.73p
dV/dt_f   322.46m/48.60p   303.57m/60.92p   356.23m/38.44p
| 25% - 75%
|dV/dt_r   200.41m/27.27p   190.04m/30.53p   219.62m/23.52p
|dV/dt_f   268.71m/38.78p   252.98m/48.55p   296.85m/30.59p
R_load = 50
[Rising Waveform]
R_fixture = 50
V_fixture = 0.0
|   Time   V(typ)   V(min)   V(max)
0s        617uV      534.7uV    447.3uV
57ps      579.7uV    45.81uV    10.1mV
65ps      2.881mV    -370.2uV   52.71mV
78ps      15.94mV    1.864mV    185mV
98ps      154.1mV    19.35mV    348mV
112ps     261.3mV    87.5mV     400.1mV
125ps     326mV      180.5mV    422.8mV
151ps     382.9mV    312.3mV    437.1mV
183ps     398.8mV    367.2mV    439.5mV
399ps     401.4mV    380.6mV    439.7mV
[Falling Waveform]
R_fixture   = 50
V_fixture   = 1.1
V_fixture_min = 1.06
V_fixture_max = 1.17
|   Time   V(typ)   V(min)   V(max)
0s        1.1V       1.06V      1.17V
72ps      1.099V     1.061V     1.158V
78ps      1.098V     1.06V      1.12V
94ps      1.079V     1.055V     939.2mV
115ps     923.2mV    1.044V     741.8mV
131ps     797.7mV    978.5mV    660.3mV
151ps     687.3mV    852.5mV    611.5mV
185ps     601.5mV    686.8mV    584.4mV
225ps     572.4mV    598.1mV    577.8mV
399ps     562.6mV    554mV      576.3mV
[Rising Waveform]
R_fixture   = 50
V_fixture   = 1.1
V_fixture_min = 1.06
V_fixture_max = 1.17
|   Time   V(typ)   V(min)   V(max)
0s        562.5mV    553.6mV    576.3mV
56ps      558.4mV    549.5mV    589.4mV
65ps      568.1mV    546.4mV    639.4mV
78ps      633.7mV    560.1mV    790.4mV
92ps      765.7mV    630.7mV    912.3mV
110ps     890mV      774.7mV    1.012V
129ps     970.4mV    881.4mV    1.075V
152ps     1.027V     957.7mV    1.119V
222ps     1.087V     1.041V     1.162V
399ps     1.1V       1.06V      1.17V
[Falling Waveform]
R_fixture = 50
V_fixture = 0.0
|   Time   V(typ)   V(min)   V(max)
0s        401.6mV    380.8mV    439.8mV
56ps      408.3mV    382.1mV    443.4mV
74ps      400.1mV    394.4mV    326.3mV
85ps      344mV      388.2mV    185.8mV
95ps      261.2mV    355.2mV    107.3mV
110ps     131.9mV    266.5mV    48.01mV
125ps     62.48mV    169.4mV    21.89mV
149ps     19.48mV    58.78mV    6.577mV
180ps     4.915mV    14.02mV    1.726mV
399ps     666.8uV    606.2uV    467.7uV
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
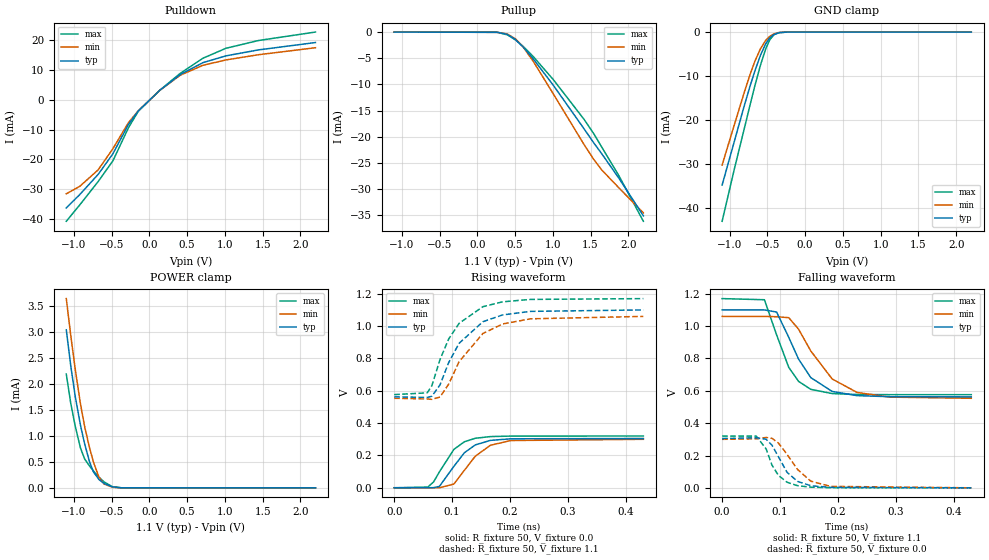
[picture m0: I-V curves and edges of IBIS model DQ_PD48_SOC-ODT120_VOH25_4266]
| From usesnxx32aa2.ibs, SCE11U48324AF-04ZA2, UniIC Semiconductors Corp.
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| DQ_PD48_SOC-ODT120_VOH25_4266
| (48 Ohm Pulldown, 120 Ohm System ODT Setting, VOH=VDDQ/2.5, 3200-4266Mbps)
[Model]   DQ_PD48_SOC-ODT120_VOH25_4266
Model_type   I/O
Vinl = 160.000mV
Vinh = 280.000mV
Vmeas = 220.000mV
Vref = 0.0mV
Cref = 0.0pF
Rref = 120.000Ohm
|   typ   min   max
|C_comp   0.797pF   0.747pF   0.847pF
C_comp_pullup   0.3985pF   0.3735pF   0.4235pF
C_comp_pulldown   0.3985pF   0.3735pF   0.4235pF
| Note: C_comp changes when the ODT circuit is enabled.
[Model Spec]
| Input threshold voltage corners
Vinl   0.1600V   0.1520V   0.1740V
Vinh   0.2800V   0.2720V   0.2940V
| Measurement voltage corners
Vmeas   0.2200V   0.2120V   0.2340V
| Timing spec test load voltage corners
Vref   0.0000V   0.0000V   0.0000V
| Dynamic Overshoot Parameters from LPDDR4 Specification
D_overshoot_ampl_h   0.30   NA   NA
D_overshoot_ampl_l   0.30   NA   NA
D_overshoot_area_h   0.1n   NA   NA
D_overshoot_area_l   0.1n   NA   NA
[Receiver Thresholds]
Vth   = 0.2200V
Vth_min  = 0.2167V
Vth_max  = 0.2233V
Vinh_ac  = 0.060V
Vinh_dc  = 0.060V
Vinl_ac  = -0.060V
Vinl_dc  = -0.060V
Tslew_ac = 5.000ns |Not specified, so set to high value
Threshold_sensitivity = 0.2000
Reference_supply Pullup_ref
[Voltage Range]   1.1000V   1.0600V   1.1700V
[Pullup Reference]   1.1000V   1.0600V   1.1700V
| Junction Temperature (Ambient temp is 35C typ 95C min -40C max)
[Temperature Range]   50.0   110.0   -40.0
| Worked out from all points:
|   slope of the pulldown table from 0 to 0.165 V, typ, clamps not added: 43.9 ohm
|   slope of the pullup table from 0 to 0.165 V, typ, clamps not added: 26.7 kohm
|   GND clamp passes 1 mA (typ) near -0.45 V on its own axis
|   POWER clamp passes 1 mA (typ) near -0.88 V on its own axis
|   rising waveform, R_fixture 50, V_fixture 0.0: 20-80 % time 39.1ps typ, 42.6ps min, 35.7ps max; typ from 0 V to 0.305 V
|   falling waveform, R_fixture 50, V_fixture 1.1: 20-80 % time 48.2ps typ, 60.5ps min, 38.2ps max; typ from 1.1 V to 0.563 V
|   rising waveform, R_fixture 50, V_fixture 1.1: 20-80 % time 55.1ps typ, 59ps min, 50.7ps max; typ from 0.562 V to 1.1 V
|   falling waveform, R_fixture 50, V_fixture 0.0: 20-80 % time 31.6ps typ, 39.3ps min, 26.3ps max; typ from 0.305 V to 0 V
[Pulldown]
|   Voltage   I(typ)   I(min)   I(max)
-1.1V     -36.35mA   -31.58mA   -40.81mA
-921.8mV  -31.85mA   -29.09mA   -35.33mA
-677.6mV  -25.06mA   -23.54mA   -27.46mA
-482.9mV  -18.15mA   -16.45mA   -20.53mA
-275mV    -8.221mA   -7.631mA   -9.314mA
-146.3mV  -3.77mA    -3.708mA   -3.861mA
137.5mV   3.149mA    3.124mA    3.16mA
408.1mV   8.436mA    8.203mA    8.84mA
708.4mV   12.43mA    11.55mA    13.91mA
1.015V    14.73mA    13.36mA    17.27mA
1.444V    16.72mA    15.1mA     19.87mA
2.2V      19.2mA     17.45mA    22.72mA
[GND Clamp]
|   Voltage   I(typ)   I(min)   I(max)
-1.1V     -34.89mA   -30.33mA   -43.14mA
-938.3mV  -24.93mA   -21.15mA   -31.25mA
-803mV    -16.58mA   -13.55mA   -21.77mA
-727.1mV  -12.17mA   -9.543mA   -16.42mA
-667.7mV  -8.943mA   -6.74mA    -12.35mA
-591.8mV  -5.273mA   -3.797mA   -7.531mA
-522.5mV  -2.675mA   -1.905mA   -3.827mA
-469.7mV  -1.359mA   -987.7uA   -1.792mA
-413.6mV  -565.2uA   -416.4uA   -622uA
-344.3mV  -143.7uA   -109.4uA   -124.9uA
-238.7mV  -9.047uA   -8.466uA   -5.015uA
2.2V      0A         0A         0A
[Pullup]
|   Voltage   I(typ)   I(min)   I(max)
-1.1V     2.741uA    4.961uA    908.5nA
266.2mV   -46.12uA   -44.97uA   -47.89uA
398.2mV   -441.6uA   -368.3uA   -523.4uA
507.1mV   -1.446mA   -1.305mA   -1.506mA
606.1mV   -2.831mA   -2.826mA   -2.722mA
744.7mV   -5.181mA   -5.658mA   -4.729mA
1.009V    -10.21mA   -11.87mA   -9.127mA
1.415V    -18.51mA   -21.52mA   -16.7mA
1.543V    -21.19mA   -24.36mA   -19.43mA
1.649V    -23.27mA   -26.37mA   -22mA
1.877V    -27.97mA   -29.81mA   -27.5mA
2.2V      -35.14mA   -34.58mA   -36.18mA
[POWER Clamp]
|   Voltage   I(typ)   I(min)   I(max)
-1.1V     3.036mA    3.636mA    2.186mA
-1.041V   2.347mA    2.931mA    1.626mA
-981.2mV  1.754mA    2.277mA    1.183mA
-911.9mV  1.201mA    1.611mA    763.8uA
-855.8mV  838.1uA    1.172mA    552.3uA
-793.1mV  506.1uA    776uA      421uA
-740.3mV  306.2uA    494.4uA    324.2uA
-667.7mV  159.9uA    206.1uA    205.2uA
-598.4mV  83.66uA    71.98uA    113uA
-489.5mV  17.85uA    10.89uA    22.49uA
-374mV    1.383uA    994nA      1.124uA
2.2V      0A         0A         0A
[Ramp]
|   typ   min   max
| 20% - 80%
dV/dt_r   182.73m/39.11p   179.78m/42.58p   191.99m/35.65p
dV/dt_f   322.45m/48.22p   303.66m/60.53p   356.22m/38.16p
| 25% - 75%
|dV/dt_r   152.28m/31.15p   149.82m/33.95p   160.00m/28.31p
|dV/dt_f   268.71m/38.43p   253.05m/48.29p   296.85m/30.35p
R_load = 50
[Rising Waveform]
R_fixture = 50
V_fixture = 0.0
|   Time   V(typ)   V(min)   V(max)
0s        420uV      331.2uV    311.1uV
58ps      445.1uV    213.1uV    4.626mV
68ps      1.105mV    -153.5uV   36.53mV
78ps      8.915mV    362.9uV    98.53mV
103ps     132.7mV    23.28mV    237.7mV
121ps     216.5mV    107.8mV    284.5mV
140ps     265.4mV    195.9mV    306.4mV
166ps     293.2mV    262.8mV    316.8mV
201ps     303mV      292.4mV    319.8mV
430ps     305mV      300mV      320.3mV
[Falling Waveform]
R_fixture   = 50
V_fixture   = 1.1
V_fixture_min = 1.06
V_fixture_max = 1.17
|   Time   V(typ)   V(min)   V(max)
0s        1.1V       1.06V      1.17V
73ps      1.1V       1.06V      1.163V
94ps      1.087V     1.058V     946.3mV
115ps     930.5mV    1.052V     745mV
132ps     795.5mV    980.7mV    658.2mV
153ps     681.7mV    846.3mV    609.3mV
190ps     596mV      673mV      582.9mV
233ps     570.2mV    589.9mV    577.3mV
289ps     563.7mV    561.1mV    576.4mV
430ps     562.6mV    553.9mV    576.3mV
[Rising Waveform]
R_fixture   = 50
V_fixture   = 1.1
V_fixture_min = 1.06
V_fixture_max = 1.17
|   Time   V(typ)   V(min)   V(max)
0s        562.5mV    553.6mV    576.3mV
57ps      558.8mV    549.4mV    587.3mV
65ps      566.3mV    546.8mV    631.5mV
79ps      635.9mV    561.4mV    792.7mV
94ps      774.4mV    640.6mV    920.1mV
112ps     893.7mV    780.2mV    1.017V
153ps     1.027V     954.2mV    1.12V
187ps     1.069V     1.013V     1.15V
235ps     1.091V     1.045V     1.165V
430ps     1.1V       1.06V      1.17V
[Falling Waveform]
R_fixture = 50
V_fixture = 0.0
|   Time   V(typ)   V(min)   V(max)
0s        305.1mV    300.1mV    320.4mV
59ps      309.9mV    303.5mV    319.9mV
76ps      300.6mV    311.7mV    240.3mV
86ps      264.4mV    306.5mV    141.4mV
97ps      193.5mV    277.7mV    77.76mV
112ps     96.69mV    207.8mV    35.07mV
130ps     40.12mV    114.4mV    13.82mV
153ps     13.35mV    41.53mV    4.44mV
187ps     3.061mV    9.303mV    1.08mV
430ps     483.7uV    418.6uV    337.1uV
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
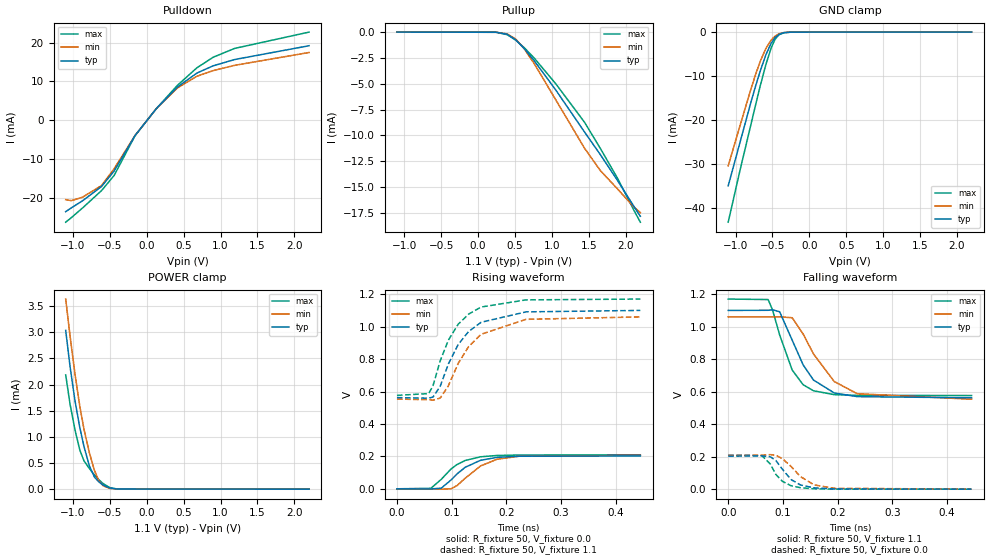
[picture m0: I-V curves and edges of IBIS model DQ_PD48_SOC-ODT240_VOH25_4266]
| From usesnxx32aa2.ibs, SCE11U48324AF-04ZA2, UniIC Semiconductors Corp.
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| DQ_PD48_SOC-ODT240_VOH25_4266
| (48 Ohm Pulldown, 240 Ohm System ODT Setting, VOH=VDDQ/2.5, 3200-4266Mbps)
[Model]   DQ_PD48_SOC-ODT240_VOH25_4266
Model_type   I/O
Vinl = 160.000mV
Vinh = 280.000mV
Vmeas = 220.000mV
Vref = 0.0mV
Cref = 0.0pF
Rref = 240.000Ohm
|   typ   min   max
|C_comp   0.797pF   0.747pF   0.847pF
C_comp_pullup   0.3985pF   0.3735pF   0.4235pF
C_comp_pulldown   0.3985pF   0.3735pF   0.4235pF
| Note: C_comp changes when the ODT circuit is enabled.
[Model Spec]
| Input threshold voltage corners
Vinl   0.1600V   0.1520V   0.1740V
Vinh   0.2800V   0.2720V   0.2940V
| Measurement voltage corners
Vmeas   0.2200V   0.2120V   0.2340V
| Timing spec test load voltage corners
Vref   0.0000V   0.0000V   0.0000V
| Dynamic Overshoot Parameters from LPDDR4 Specification
D_overshoot_ampl_h   0.30   NA   NA
D_overshoot_ampl_l   0.30   NA   NA
D_overshoot_area_h   0.1n   NA   NA
D_overshoot_area_l   0.1n   NA   NA
[Receiver Thresholds]
Vth   = 0.2200V
Vth_min  = 0.2167V
Vth_max  = 0.2233V
Vinh_ac  = 0.060V
Vinh_dc  = 0.060V
Vinl_ac  = -0.060V
Vinl_dc  = -0.060V
Tslew_ac = 5.000ns |Not specified, so set to high value
Threshold_sensitivity = 0.2000
Reference_supply Pullup_ref
[Voltage Range]   1.1000V   1.0600V   1.1700V
[Pullup Reference]   1.1000V   1.0600V   1.1700V
| Junction Temperature (Ambient temp is 35C typ 95C min -40C max)
[Temperature Range]   50.0   110.0   -40.0
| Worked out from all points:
|   slope of the pulldown table from 0 to 0.165 V, typ, clamps not added: 43.9 ohm
|   slope of the pullup table from 0 to 0.165 V, typ, clamps not added: 56.2 kohm
|   GND clamp passes 1 mA (typ) near -0.45 V on its own axis
|   POWER clamp passes 1 mA (typ) near -0.88 V on its own axis
|   rising waveform, R_fixture 50, V_fixture 0.0: 20-80 % time 46.1ps typ, 50.1ps min, 42.5ps max; typ from 0 V to 0.203 V
|   falling waveform, R_fixture 50, V_fixture 1.1: 20-80 % time 48ps typ, 60.2ps min, 38ps max; typ from 1.1 V to 0.563 V
|   rising waveform, R_fixture 50, V_fixture 1.1: 20-80 % time 55.3ps typ, 59.7ps min, 50.7ps max; typ from 0.562 V to 1.1 V
|   falling waveform, R_fixture 50, V_fixture 0.0: 20-80 % time 31.8ps typ, 39.7ps min, 26.6ps max; typ from 0.203 V to 0 V
[Pulldown]
|   Voltage   I(typ)   I(min)   I(max)
-1.1V     -23.65mA   -20.55mA   -26.37mA
-1.024V   -22.68mA   -20.81mA   -25.2mA
-872.3mV  -20.85mA   -19.92mA   -22.71mA
-614.9mV  -17.17mA   -16.92mA   -18.23mA
-443.3mV  -13.17mA   -12.57mA   -14.3mA
-159.5mV  -3.987mA   -3.972mA   -4.027mA
127.6mV   2.931mA    2.91mA     2.937mA
414.7mV   8.546mA    8.304mA    8.967mA
678.7mV   12.13mA    11.32mA    13.49mA
899.8mV   14.01mA    12.77mA    16.23mA
1.19V     15.63mA    14.13mA    18.5mA
2.2V      19.2mA     17.45mA    22.72mA
[GND Clamp]
|   Voltage   I(typ)   I(min)   I(max)
-1.1V     -34.89mA   -30.35mA   -43.14mA
-938.3mV  -24.93mA   -21.15mA   -31.25mA
-793.1mV  -15.99mA   -13.01mA   -21.07mA
-723.8mV  -11.98mA   -9.379mA   -16.19mA
-664.4mV  -8.771mA   -6.596mA   -12.13mA
-588.5mV  -5.131mA   -3.688mA   -7.335mA
-519.2mV  -2.57mA    -1.835mA   -3.675mA
-466.4mV  -1.296mA   -943.1uA   -1.696mA
-413.6mV  -565.1uA   -416.3uA   -621.9uA
-344.3mV  -143.2uA   -110.1uA   -124.3uA
-242mV    -9.996uA   -9.424uA   -5.61uA
2.2V      0A         0A         0A
[Pullup]
|   Voltage   I(typ)   I(min)   I(max)
-1.1V     1.371uA    2.481uA    454.4nA
246.4mV   -15.54uA   -15.59uA   -14.91uA
394.9mV   -211.7uA   -175.7uA   -251.7uA
510.4mV   -747.6uA   -678.5uA   -775.6uA
625.9mV   -1.587mA   -1.613mA   -1.506mA
757.9mV   -2.738mA   -3.016mA   -2.487mA
1.052V    -5.592mA   -6.54mA    -4.991mA
1.444V    -9.68mA    -11.25mA   -8.737mA
1.659V    -11.88mA   -13.42mA   -11.28mA
1.887V    -14.33mA   -15.16mA   -14.11mA
2.114V    -16.89mA   -16.95mA   -17.27mA
2.2V      -17.84mA   -17.48mA   -18.41mA
[POWER Clamp]
|   Voltage   I(typ)   I(min)   I(max)
-1.1V     3.036mA    3.636mA    2.186mA
-1.041V   2.347mA    2.931mA    1.626mA
-974.6mV  1.695mA    2.208mA    1.139mA
-908.6mV  1.178mA    1.583mA    747.9uA
-852.5mV  818.6uA    1.149mA    543.8uA
-779.9mV  448uA      701.7uA    396.3uA
-710.6mV  232.2uA    359.3uA    273.1uA
-651.2mV  138.6uA    162.3uA    181.2uA
-591.8mV  77.92uA    64.82uA    105.6uA
-502.7mV  22.59uA    13.96uA    29.26uA
-397.1mV  2.383uA    1.584uA    2.118uA
2.2V      0A         0A         0A
[Ramp]
|   typ   min   max
| 20% - 80%
dV/dt_r   121.60m/46.13p   123.90m/50.12p   125.38m/42.52p
dV/dt_f   322.47m/48.01p   303.70m/60.18p   356.22m/37.99p
| 25% - 75%
|dV/dt_r   101.33m/36.73p   103.25m/39.99p   104.48m/33.79p
|dV/dt_f   268.72m/38.27p   253.08m/48.03p   296.85m/30.29p
R_load = 50
[Rising Waveform]
R_fixture = 50
V_fixture = 0.0
|   Time   V(typ)   V(min)   V(max)
0s        197.7uV    142.5uV    150.7uV
62ps      -698.1uV   149.9uV    3.125mV
81ps      4.064mV    -2.118mV   58.28mV
99ps      54.76mV    449.6uV    122.7mV
110ps     92.4mV     20.36mV    150.2mV
125ps     133.2mV    66.13mV    175.2mV
153ps     176.1mV    141.3mV    197.5mV
183ps     194mV      182.3mV    205.6mV
223ps     200.9mV    201mV      208.4mV
445ps     202.9mV    206.6mV    209.1mV
[Falling Waveform]
R_fixture   = 50
V_fixture   = 1.1
V_fixture_min = 1.06
V_fixture_max = 1.17
|   Time   V(typ)   V(min)   V(max)
0s        1.1V       1.06V      1.17V
73ps      1.101V     1.06V      1.167V
81ps      1.104V     1.06V      1.104V
94ps      1.092V     1.061V     950.1mV
117ps     917.3mV    1.055V     733.3mV
137ps     765mV      955.2mV    642.9mV
156ps     671.5mV    832.1mV    605.5mV
194ps     592mV      662.3mV    581.8mV
236ps     569.5mV    587.4mV    577.2mV
445ps     562.5mV    553.8mV    576.3mV
[Rising Waveform]
R_fixture   = 50
V_fixture   = 1.1
V_fixture_min = 1.06
V_fixture_max = 1.17
|   Time   V(typ)   V(min)   V(max)
0s        562.4mV    553.6mV    576.3mV
58ps      558.7mV    549.3mV    587.1mV
66ps      566.3mV    547mV      636.5mV
79ps      631.6mV    559.3mV    788.4mV
94ps      769.7mV    635.4mV    916.6mV
112ps     890mV      773.6mV    1.015V
131ps     969.9mV    876.6mV    1.077V
154ps     1.027V     953.2mV    1.121V
236ps     1.091V     1.045V     1.165V
445ps     1.1V       1.06V      1.17V
[Falling Waveform]
R_fixture = 50
V_fixture = 0.0
|   Time   V(typ)   V(min)   V(max)
0s        202.9mV    206.7mV    209.2mV
61ps      205.4mV    209mV      207.9mV
77ps      199.2mV    212.8mV    155.1mV
87ps      176.9mV    208.8mV    91.61mV
99ps      123.1mV    188.3mV    48.57mV
115ps     59.13mV    139.7mV    21.31mV
132ps     26.35mV    77.93mV    8.948mV
157ps     8.221mV    26.46mV    2.63mV
194ps     1.704mV    5.465mV    560.4uV
445ps     264.5uV    237.8uV    175uV
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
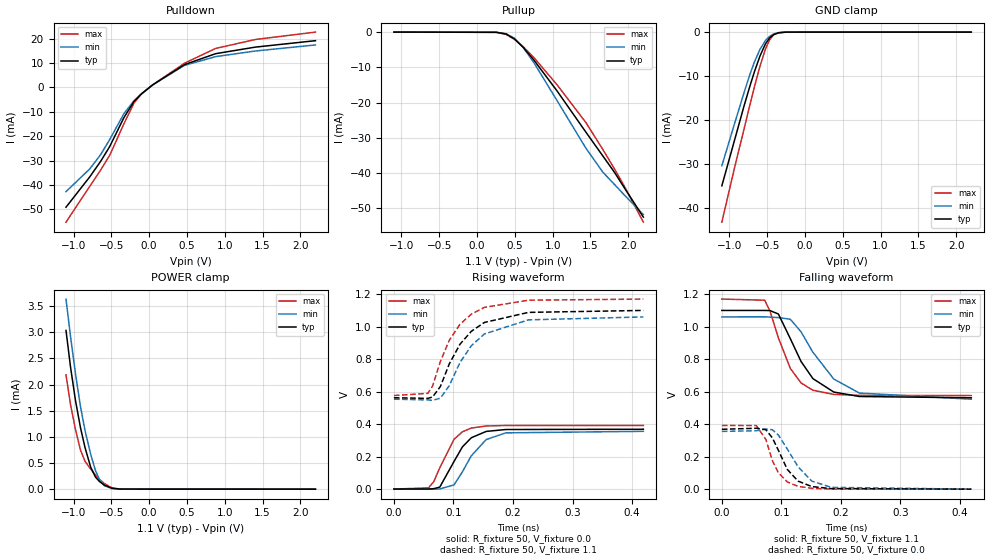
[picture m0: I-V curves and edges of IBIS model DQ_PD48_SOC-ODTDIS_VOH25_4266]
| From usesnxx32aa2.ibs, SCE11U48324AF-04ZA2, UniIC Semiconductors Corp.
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| DQ_PD48_SOC-ODTDIS_VOH25_4266
| (48 Ohm Pulldown, SOC ODT disabled setting, VOH=VDDQ/2.5 cal. point, 3200-4266Mbps)
[Model]   DQ_PD48_SOC-ODTDIS_VOH25_4266
Model_type   I/O
Vinl = 160.000mV
Vinh = 280.000mV
Vmeas = 220.000mV
Vref = 0.0mV
Cref = 0.0pF
|   typ   min   max
|C_comp   0.797pF   0.747pF   0.847pF
C_comp_pullup   0.3985pF   0.3735pF   0.4235pF
C_comp_pulldown   0.3985pF   0.3735pF   0.4235pF
| Note: C_comp changes when the ODT circuit is enabled.
[Model Spec]
| Input threshold voltage corners
Vinl   0.1600V   0.1520V   0.1740V
Vinh   0.2800V   0.2720V   0.2940V
| Measurement voltage corners
Vmeas   0.2200V   0.2120V   0.2340V
| Timing spec test load voltage corners
Vref   0.0000V   0.0000V   0.0000V
| Dynamic Overshoot Parameters from LPDDR4 Specification
D_overshoot_ampl_h   0.30   NA   NA
D_overshoot_ampl_l   0.30   NA   NA
D_overshoot_area_h   0.1n   NA   NA
D_overshoot_area_l   0.1n   NA   NA
[Receiver Thresholds]
Vth   = 0.2200V
Vth_min  = 0.2167V
Vth_max  = 0.2233V
Vinh_ac  = 0.060V
Vinh_dc  = 0.060V
Vinl_ac  = -0.060V
Vinl_dc  = -0.060V
Tslew_ac = 5.000ns |Not specified, so set to high value
Threshold_sensitivity = 0.2000
Reference_supply Pullup_ref
[Voltage Range]   1.1000V   1.0600V   1.1700V
[Pullup Reference]   1.1000V   1.0600V   1.1700V
| Junction Temperature (Ambient temp is 35C typ 95C min -40C max)
[Temperature Range]   50.0   110.0   -40.0
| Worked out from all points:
|   slope of the pulldown table from 0 to 0.165 V, typ, clamps not added: 43.7 ohm
|   slope of the pullup table from 0 to 0.165 V, typ, clamps not added: 18.1 kohm
|   GND clamp passes 1 mA (typ) near -0.45 V on its own axis
|   POWER clamp passes 1 mA (typ) near -0.88 V on its own axis
|   rising waveform, R_fixture 50, V_fixture 0.0: 20-80 % time 34.2ps typ, 37.9ps min, 31.2ps max; typ from 0.001 V to 0.369 V
|   falling waveform, R_fixture 50, V_fixture 1.1: 20-80 % time 48.4ps typ, 61ps min, 38.3ps max; typ from 1.1 V to 0.563 V
|   rising waveform, R_fixture 50, V_fixture 1.1: 20-80 % time 54.7ps typ, 58.1ps min, 50.6ps max; typ from 0.562 V to 1.1 V
|   falling waveform, R_fixture 50, V_fixture 0.0: 20-80 % time 32ps typ, 39.4ps min, 26.4ps max; typ from 0.369 V to 0.001 V
[Pulldown]
|   Voltage   I(typ)   I(min)   I(max)
-1.1V     -49.08mA   -42.68mA   -55.23mA
-786.5mV  -36.67mA   -33.42mA   -40.58mA
-641.3mV  -30.26mA   -27.51mA   -33.81mA
-522.5mV  -24.24mA   -21.38mA   -27.85mA
-334.4mV  -12.38mA   -10.77mA   -14.9mA
-199.1mV  -5.68mA    -5.361mA   -6.295mA
-103.4mV  -2.668mA   -2.622mA   -2.685mA
45.1mV    1.049mA    1.046mA    1.047mA
467.5mV   9.39mA     9.064mA    9.963mA
880mV     13.87mA    12.66mA    16.02mA
1.405V    16.56mA    14.96mA    19.68mA
2.2V      19.2mA     17.45mA    22.72mA
[GND Clamp]
|   Voltage   I(typ)   I(min)   I(max)
-1.1V     -34.89mA   -30.35mA   -43.14mA
-938.3mV  -24.93mA   -21.15mA   -31.25mA
-803mV    -16.57mA   -13.55mA   -21.77mA
-727.1mV  -12.17mA   -9.543mA   -16.42mA
-667.7mV  -8.943mA   -6.741mA   -12.35mA
-595.1mV  -5.418mA   -3.907mA   -7.727mA
-522.5mV  -2.67mA    -1.908mA   -3.825mA
-466.4mV  -1.296mA   -945uA     -1.697mA
-413.6mV  -565uA     -418.7uA   -622.8uA
-350.9mV  -167.2uA   -126.1uA   -147.1uA
-251.9mV  -13.55uA   -12.1uA    -8.035uA
2.2V      0A         0A         0A
[Pullup]
|   Voltage   I(typ)   I(min)   I(max)
-1.1V     4.112uA    7.441uA    1.363uA
256.3mV   -56.73uA   -56.34uA   -56.81uA
385mV     -549.6uA   -458.8uA   -658.1uA
497.2mV   -1.985mA   -1.773mA   -2.091mA
609.4mV   -4.304mA   -4.305mA   -4.133mA
751.3mV   -7.908mA   -8.649mA   -7.214mA
1.055V    -16.59mA   -19.32mA   -14.85mA
1.441V    -28.41mA   -32.96mA   -25.69mA
1.662V    -35.07mA   -39.67mA   -33.22mA
1.824V    -39.95mA   -43.35mA   -39.01mA
1.956V    -44.42mA   -46.36mA   -44.02mA
2.2V      -52.46mA   -51.75mA   -53.91mA
[POWER Clamp]
|   Voltage   I(typ)   I(min)   I(max)
-1.1V     3.036mA    3.636mA    2.186mA
-1.041V   2.347mA    2.931mA    1.626mA
-974.6mV  1.695mA    2.208mA    1.139mA
-908.6mV  1.178mA    1.582mA    748uA
-849.2mV  799.4uA    1.126mA    535.6uA
-773.3mV  421uA      665.7uA    384.1uA
-710.6mV  232.2uA    359.1uA    273.1uA
-654.5mV  142.7uA    170.4uA    185.9uA
-595.1mV  80.76uA    68.31uA    109.2uA
-492.8mV  18.9uA     11.62uA    24.03uA
-383.9mV  1.747uA    1.216uA    1.478uA
2.2V      0A         0A         0A
[Ramp]
|   typ   min   max
| 20% - 80%
dV/dt_r   220.81m/34.25p   213.14m/37.95p   234.88m/31.16p
dV/dt_f   322.45m/48.44p   303.64m/60.98p   356.23m/38.27p
| 25% - 75%
|dV/dt_r   184.01m/27.26p   177.62m/30.23p   195.73m/24.71p
|dV/dt_f   268.71m/38.64p   253.04m/48.62p   296.86m/30.47p
R_load = 50
[Rising Waveform]
R_fixture = 50
V_fixture = 0.0
|   Time   V(typ)   V(min)   V(max)
0s        640uV      516.9uV    470.5uV
58ps      699.9uV    85.29uV    7.425mV
67ps      2.747mV    -292.1uV   46.13mV
77ps      12.23mV    1.048mV    131.1mV
101ps     170.4mV    26.22mV    306.9mV
115ps     259.7mV    106.2mV    352.8mV
130ps     316.3mV    205.1mV    375.9mV
155ps     355.2mV    305.2mV    388.8mV
188ps     366.9mV    346.4mV    391.6mV
419ps     368.7mV    355.8mV    391.9mV
[Falling Waveform]
R_fixture   = 50
V_fixture   = 1.1
V_fixture_min = 1.06
V_fixture_max = 1.17
|   Time   V(typ)   V(min)   V(max)
0s        1.1V       1.06V      1.17V
72ps      1.1V       1.061V     1.163V
81ps      1.099V     1.059V     1.095V
95ps      1.078V     1.056V     931.4mV
115ps     926.7mV    1.046V     743.5mV
133ps     786.4mV    968.9mV    654.1mV
153ps     680.5mV    842.6mV    608.9mV
188ps     598mV      678.1mV    583.5mV
231ps     570.6mV    591.7mV    577.4mV
419ps     562.6mV    553.9mV    576.3mV
[Rising Waveform]
R_fixture   = 50
V_fixture   = 1.1
V_fixture_min = 1.06
V_fixture_max = 1.17
|   Time   V(typ)   V(min)   V(max)
0s        562.5mV    553.6mV    576.3mV
57ps      558.7mV    549.1mV    589.3mV
65ps      567.3mV    546.5mV    634.9mV
78ps      631.2mV    559.5mV    785.8mV
93ps      770.5mV    636.8mV    916.2mV
111ps     892.1mV    779.5mV    1.015V
130ps     971.5mV    883mV      1.077V
152ps     1.026V     955.2mV    1.119V
226ps     1.088V     1.042V     1.163V
419ps     1.1V       1.06V      1.17V
[Falling Waveform]
R_fixture = 50
V_fixture = 0.0
|   Time   V(typ)   V(min)   V(max)
0s        368.8mV    355.9mV    392mV
58ps      375.2mV    359.8mV    391.7mV
74ps      366.4mV    371.1mV    306mV
85ps      315.6mV    365.5mV    175mV
95ps      239.6mV    333.4mV    101.1mV
110ps     121.7mV    247.1mV    45.17mV
128ps     50.08mV    138.7mV    17.66mV
151ps     16.58mV    50.17mV    5.647mV
184ps     3.957mV    11.51mV    1.449mV
419ps     686.6uV    583.4uV    490.7uV
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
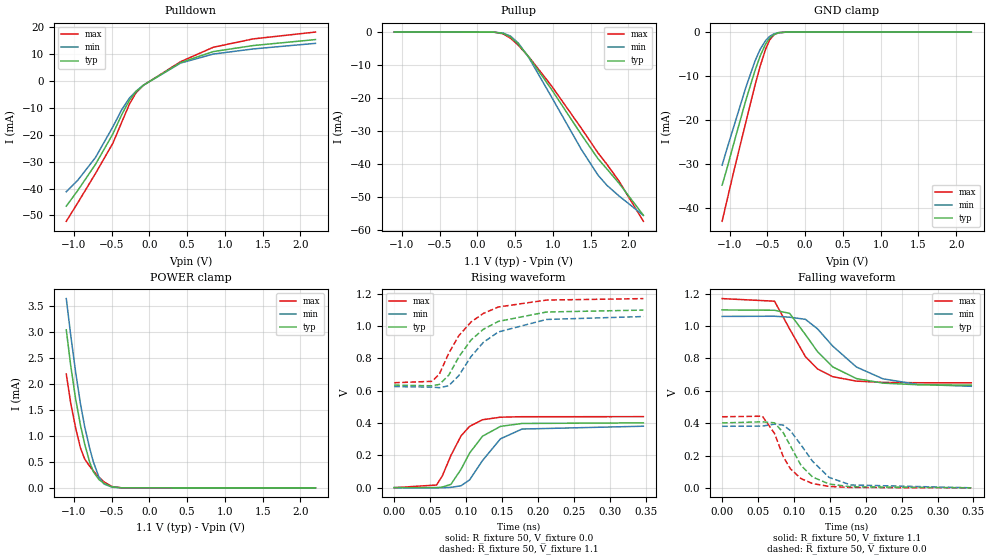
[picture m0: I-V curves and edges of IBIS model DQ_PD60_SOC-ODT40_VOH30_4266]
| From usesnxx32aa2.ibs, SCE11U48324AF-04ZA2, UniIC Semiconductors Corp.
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| DQ_PD60_SOC-ODT40_VOH30_4266
| (60 Ohm Pulldown, 40 Ohm System ODT Setting, VOH=VDDQ/3.0, 3200-4266Mbps)
[Model]   DQ_PD60_SOC-ODT40_VOH30_4266
Model_type   I/O
Vinl = 123.333mV
Vinh = 243.333mV
Vmeas = 183.333mV
Vref = 0.0mV
Cref = 0.0pF
Rref = 40.000Ohm
|   typ   min   max
|C_comp   0.797pF   0.747pF   0.847pF
C_comp_pullup   0.3985pF   0.3735pF   0.4235pF
C_comp_pulldown   0.3985pF   0.3735pF   0.4235pF
| Note: C_comp changes when the ODT circuit is enabled.
[Model Spec]
| Input threshold voltage corners
Vinl   0.1233V   0.1167V   0.1350V
Vinh   0.2433V   0.2367V   0.2550V
| Measurement voltage corners
Vmeas   0.1833V   0.1767V   0.1950V
| Timing spec test load voltage corners
Vref   0.0000V   0.0000V   0.0000V
| Dynamic Overshoot Parameters from LPDDR4 Specification
D_overshoot_ampl_h   0.30   NA   NA
D_overshoot_ampl_l   0.30   NA   NA
D_overshoot_area_h   0.1n   NA   NA
D_overshoot_area_l   0.1n   NA   NA
[Receiver Thresholds]
Vth   = 0.1833V
Vth_min  = 0.1800V
Vth_max  = 0.1866V
Vinh_ac  = 0.060V
Vinh_dc  = 0.060V
Vinl_ac  = -0.060V
Vinl_dc  = -0.060V
Tslew_ac = 5.000ns |Not specified, so set to high value
Threshold_sensitivity = 0.1667
Reference_supply Pullup_ref
[Voltage Range]   1.1000V   1.0600V   1.1700V
[Pullup Reference]   1.1000V   1.0600V   1.1700V
| Junction Temperature (Ambient temp is 35C typ 95C min -40C max)
[Temperature Range]   50.0   110.0   -40.0
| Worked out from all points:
|   slope of the pulldown table from 0 to 0.165 V, typ, clamps not added: 54.7 ohm
|   slope of the pullup table from 0 to 0.165 V, typ, clamps not added: 13 kohm
|   GND clamp passes 1 mA (typ) near -0.45 V on its own axis
|   POWER clamp passes 1 mA (typ) near -0.88 V on its own axis
|   rising waveform, R_fixture 50, V_fixture 0.0: 20-80 % time 34.5ps typ, 38.6ps min, 29.9ps max; typ from 0.001 V to 0.401 V
|   falling waveform, R_fixture 50, V_fixture 1.1: 20-80 % time 53.2ps typ, 65.2ps min, 42.7ps max; typ from 1.1 V to 0.635 V
|   rising waveform, R_fixture 50, V_fixture 1.1: 20-80 % time 53.6ps typ, 56.1ps min, 50.9ps max; typ from 0.635 V to 1.1 V
|   falling waveform, R_fixture 50, V_fixture 0.0: 20-80 % time 34.1ps typ, 41.3ps min, 29.4ps max; typ from 0.402 V to 0.001 V
[Pulldown]
|   Voltage   I(typ)   I(min)   I(max)
-1.1V     -46.55mA   -41.2mA    -52.18mA
-948.2mV  -40.75mA   -36.95mA   -45.34mA
-713.9mV  -31.04mA   -28.5mA    -34.44mA
-482.9mV  -19.69mA   -17.06mA   -23.17mA
-364.1mV  -12.46mA   -10.62mA   -15.25mA
-265.1mV  -7.232mA   -6.429mA   -8.721mA
-176mV    -3.995mA   -3.802mA   -4.37mA
-77mV     -1.588mA   -1.568mA   -1.58mA
414.7mV   6.827mA    6.638mA    7.153mA
847mV     10.89mA    9.975mA    12.5mA
1.375V    13.14mA    11.88mA    15.61mA
2.2V      15.36mA    13.96mA    18.16mA
[GND Clamp]
|   Voltage   I(typ)   I(min)   I(max)
-1.1V     -34.88mA   -30.35mA   -43.13mA
-1.047V   -31.79mA   -27.25mA   -39.23mA
-944.9mV  -25.34mA   -21.53mA   -31.71mA
-786.5mV  -15.59mA   -12.65mA   -20.59mA
-664.4mV  -8.768mA   -6.598mA   -12.12mA
-595.1mV  -5.418mA   -3.908mA   -7.72mA
-522.5mV  -2.674mA   -1.908mA   -3.823mA
-469.7mV  -1.362mA   -986.7uA   -1.79mA
-413.6mV  -567uA     -418uA     -620.7uA
-350.9mV  -166.9uA   -125.9uA   -146.9uA
-238.7mV  -9.051uA   -8.516uA   -4.978uA
2.2V      0A         0A         0A
[Pullup]
|   Voltage   I(typ)   I(min)   I(max)
-1.1V     6.284uA    9.684uA    2.832uA
226.6mV   -42.29uA   -43.33uA   -42.8uA
342.1mV   -380.9uA   -314.4uA   -525uA
441.1mV   -1.491mA   -1.225mA   -1.868mA
546.7mV   -3.719mA   -3.405mA   -4.061mA
685.3mV   -7.623mA   -7.826mA   -7.562mA
982.3mV   -17.31mA   -19.6mA    -16.25mA
1.378V    -31.03mA   -35.51mA   -29.11mA
1.599V    -38.35mA   -43.31mA   -36.57mA
1.718V    -41.46mA   -46.41mA   -40.06mA
1.88V     -45.85mA   -49.67mA   -45.22mA
2.2V      -55.46mA   -55.5mA    -57.28mA
[POWER Clamp]
|   Voltage   I(typ)   I(min)   I(max)
-1.1V     3.036mA    3.636mA    2.186mA
-1.041V   2.347mA    2.931mA    1.626mA
-977.9mV  1.724mA    2.242mA    1.161mA
-911.9mV  1.201mA    1.611mA    764.3uA
-855.8mV  838.1uA    1.172mA    552.2uA
-789.8mV  491.1uA    757.2uA    414.8uA
-740.3mV  306.1uA    494.4uA    324.3uA
-667.7mV  159.9uA    206.1uA    205.2uA
-598.4mV  83.68uA    71.99uA    113uA
-492.8mV  18.93uA    11.63uA    24.06uA
-374mV    1.394uA    1.002uA    1.122uA
2.2V      0A         0A         0A
[Ramp]
|   typ   min   max
| 20% - 80%
dV/dt_r   240.44m/34.52p   227.99m/38.63p   263.51m/29.86p
dV/dt_f   278.92m/53.19p   259.15m/65.20p   312.24m/42.72p
| 25% - 75%
|dV/dt_r   200.37m/27.47p   189.99m/30.75p   219.59m/23.69p
|dV/dt_f   232.44m/42.39p   215.96m/51.99p   260.20m/33.99p
R_load = 50
[Rising Waveform]
R_fixture = 50
V_fixture = 0.0
|   Time   V(typ)   V(min)   V(max)
0s        700.7uV    612.8uV    506.9uV
59ps      883.7uV    -277.5uV   16.78mV
67ps      4.215mV    -540.9uV   73.08mV
79ps      21.23mV    2.48mV     199.9mV
93ps      113.5mV    12.06mV    320.4mV
105ps     214.5mV    48.58mV    379.6mV
123ps     319mV      168.5mV    420.6mV
148ps     379.6mV    302.8mV    436.5mV
178ps     397.7mV    363.1mV    439.4mV
347ps     401.4mV    380.6mV    439.7mV
[Falling Waveform]
R_fixture   = 50
V_fixture   = 1.1
V_fixture_min = 1.06
V_fixture_max = 1.17
|   Time   V(typ)   V(min)   V(max)
0s        1.1V       1.06V      1.17V
73ps      1.098V     1.061V     1.154V
94ps      1.079V     1.055V     982.3mV
116ps     947.7mV    1.042V     811.1mV
133ps     841.3mV    982.5mV    735.1mV
154ps     748.3mV    876.7mV    687.5mV
187ps     675.7mV    747.4mV    660.1mV
224ps     647.6mV    674.3mV    652.1mV
272ps     637.7mV    639.8mV    650mV
347ps     635.1mV    628.1mV    649.6mV
[Rising Waveform]
R_fixture   = 50
V_fixture   = 1.1
V_fixture_min = 1.06
V_fixture_max = 1.17
|   Time   V(typ)   V(min)   V(max)
0s        634.8mV    625.9mV    649.6mV
53ps      630.6mV    622.4mV    658.3mV
63ps      639.3mV    618.8mV    704.4mV
76ps      696.5mV    631.1mV    832.2mV
90ps      809.7mV    693.9mV    940.8mV
107ps     914.1mV    811.6mV    1.025V
124ps     979.7mV    898.6mV    1.078V
145ps     1.029V     963.7mV    1.118V
212ps     1.087V     1.041V     1.161V
347ps     1.099V     1.059V     1.17V
[Falling Waveform]
R_fixture = 50
V_fixture = 0.0
|   Time   V(typ)   V(min)   V(max)
0s        401.6mV    380.8mV    439.8mV
56ps      408.5mV    382.1mV    443.2mV
73ps      402.3mV    394.1mV    337.1mV
85ps      342.4mV    388.1mV    194.3mV
95ps      260.3mV    354.5mV    118.5mV
110ps     138.4mV    264.8mV    57.25mV
126ps     67.16mV    164.4mV    26.79mV
149ps     24.35mV    64.84mV    9.335mV
179ps     7.034mV    18.35mV    2.702mV
347ps     759.6uV    719.9uV    528.5uV
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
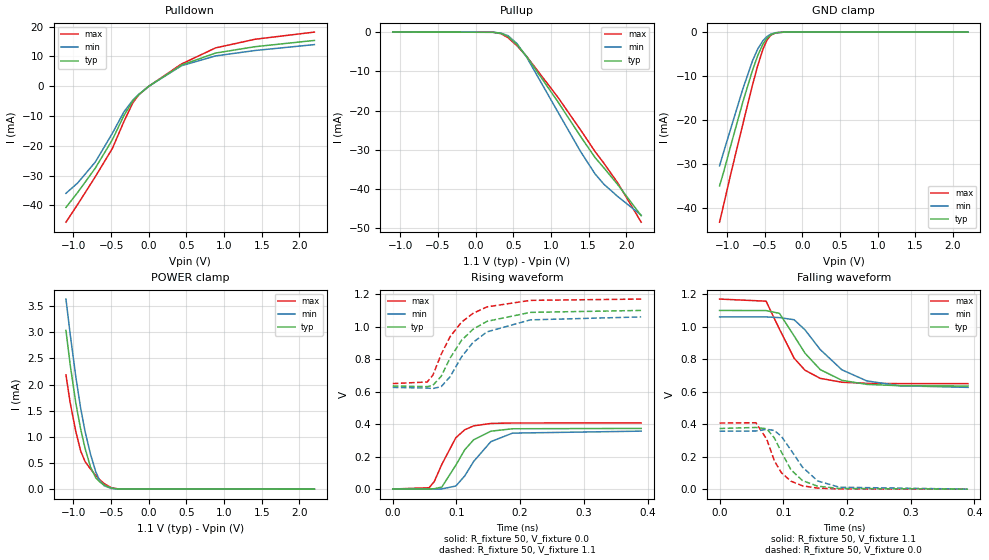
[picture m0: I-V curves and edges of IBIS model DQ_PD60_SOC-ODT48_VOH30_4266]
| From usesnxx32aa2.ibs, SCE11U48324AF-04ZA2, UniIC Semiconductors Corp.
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| DQ_PD60_SOC-ODT48_VOH30_4266
| (60 Ohm Pulldown, 48 Ohm System ODT Setting, VOH=VDDQ/3.0, 3200-4266Mbps)
[Model]   DQ_PD60_SOC-ODT48_VOH30_4266
Model_type   I/O
Vinl = 123.333mV
Vinh = 243.333mV
Vmeas = 183.333mV
Vref = 0.0mV
Cref = 0.0pF
Rref = 48.000Ohm
|   typ   min   max
|C_comp   0.797pF   0.747pF   0.847pF
C_comp_pullup   0.3985pF   0.3735pF   0.4235pF
C_comp_pulldown   0.3985pF   0.3735pF   0.4235pF
| Note: C_comp changes when the ODT circuit is enabled.
[Model Spec]
| Input threshold voltage corners
Vinl   0.1233V   0.1167V   0.1350V
Vinh   0.2433V   0.2367V   0.2550V
| Measurement voltage corners
Vmeas   0.1833V   0.1767V   0.1950V
| Timing spec test load voltage corners
Vref   0.0000V   0.0000V   0.0000V
| Dynamic Overshoot Parameters from LPDDR4 Specification
D_overshoot_ampl_h   0.30   NA   NA
D_overshoot_ampl_l   0.30   NA   NA
D_overshoot_area_h   0.1n   NA   NA
D_overshoot_area_l   0.1n   NA   NA
[Receiver Thresholds]
Vth   = 0.1833V
Vth_min  = 0.1800V
Vth_max  = 0.1866V
Vinh_ac  = 0.060V
Vinh_dc  = 0.060V
Vinl_ac  = -0.060V
Vinl_dc  = -0.060V
Tslew_ac = 5.000ns |Not specified, so set to high value
Threshold_sensitivity = 0.1667
Reference_supply Pullup_ref
[Voltage Range]   1.1000V   1.0600V   1.1700V
[Pullup Reference]   1.1000V   1.0600V   1.1700V
| Junction Temperature (Ambient temp is 35C typ 95C min -40C max)
[Temperature Range]   50.0   110.0   -40.0
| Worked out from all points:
|   slope of the pulldown table from 0 to 0.165 V, typ, clamps not added: 54.8 ohm
|   slope of the pullup table from 0 to 0.165 V, typ, clamps not added: 15.4 kohm
|   GND clamp passes 1 mA (typ) near -0.45 V on its own axis
|   POWER clamp passes 1 mA (typ) near -0.88 V on its own axis
|   rising waveform, R_fixture 50, V_fixture 0.0: 20-80 % time 35.9ps typ, 40.4ps min, 31.6ps max; typ from 0.001 V to 0.374 V
|   falling waveform, R_fixture 50, V_fixture 1.1: 20-80 % time 53ps typ, 65.4ps min, 42.6ps max; typ from 1.1 V to 0.635 V
|   rising waveform, R_fixture 50, V_fixture 1.1: 20-80 % time 54.2ps typ, 57.1ps min, 50.9ps max; typ from 0.635 V to 1.1 V
|   falling waveform, R_fixture 50, V_fixture 0.0: 20-80 % time 34.1ps typ, 41.4ps min, 29.3ps max; typ from 0.374 V to 0.001 V
[Pulldown]
|   Voltage   I(typ)   I(min)   I(max)
-1.1V     -40.65mA   -35.93mA   -45.61mA
-944.9mV  -35.66mA   -32.47mA   -39.67mA
-710.6mV  -27.49mA   -25.45mA   -30.37mA
-482.9mV  -17.92mA   -15.77mA   -20.85mA
-331.1mV  -9.879mA   -8.642mA   -11.9mA
-212.3mV  -4.968mA   -4.669mA   -5.599mA
-133.1mV  -2.807mA   -2.748mA   -2.886mA
0V        -23.83uA   -21.04uA   -16.99uA
434.5mV   7.085mA    6.873mA    7.455mA
886.6mV   11.12mA    10.16mA    12.85mA
1.411V    13.26mA    11.98mA    15.75mA
2.2V      15.36mA    13.96mA    18.16mA
[GND Clamp]
|   Voltage   I(typ)   I(min)   I(max)
-1.1V     -34.88mA   -30.34mA   -43.13mA
-1.05V    -31.99mA   -27.44mA   -39.47mA
-948.2mV  -25.55mA   -21.71mA   -31.95mA
-789.8mV  -15.79mA   -12.83mA   -20.82mA
-661.1mV  -8.597mA   -6.455mA   -11.9mA
-591.8mV  -5.272mA   -3.798mA   -7.524mA
-522.5mV  -2.672mA   -1.906mA   -3.823mA
-469.7mV  -1.359mA   -993.7uA   -1.79mA
-416.9mV  -597.2uA   -441.2uA   -665.6uA
-354.2mV  -178.5uA   -135uA     -159.7uA
-238.7mV  -9.075uA   -8.646uA   -5.057uA
2.2V      0A         0A         0A
[Pullup]
|   Voltage   I(typ)   I(min)   I(max)
-1.1V     5.237uA    8.07uA     2.361uA
229.9mV   -38.08uA   -38.22uA   -38.8uA
335.5mV   -286.3uA   -237.2uA   -391.7uA
431.2mV   -1.119mA   -911.6uA   -1.419mA
550mV     -3.189mA   -2.931mA   -3.468mA
678.7mV   -6.235mA   -6.386mA   -6.196mA
1.091V    -17.68mA   -20.27mA   -16.53mA
1.395V    -26.59mA   -30.44mA   -24.93mA
1.586V    -31.93mA   -36.1mA    -30.4mA
1.702V    -34.53mA   -38.71mA   -33.34mA
1.89V     -38.9mA    -41.91mA   -38.47mA
2.2V      -46.77mA   -46.65mA   -48.43mA
[POWER Clamp]
|   Voltage   I(typ)   I(min)   I(max)
-1.1V     3.036mA    3.636mA    2.186mA
-1.044V   2.383mA    2.969mA    1.654mA
-968mV    1.637mA    2.141mA    1.095mA
-905.3mV  1.155mA    1.554mA    732.7uA
-845.9mV  780.3uA    1.103mA    527.5uA
-773.3mV  420.8uA    665.5uA    384.1uA
-704mV    218.9uA    332uA      262.2uA
-651.2mV  138.6uA    162.3uA    181.2uA
-591.8mV  77.94uA    64.85uA    105.5uA
-496.1mV  20.07uA    12.34uA    25.69uA
-390.5mV  2.043uA    1.408uA    1.76uA
2.2V      0A         0A         0A
[Ramp]
|   typ   min   max
| 20% - 80%
dV/dt_r   223.82m/35.91p   213.78m/40.39p   244.09m/31.56p
dV/dt_f   279.03m/53.02p   259.99m/65.37p   312.25m/42.62p
| 25% - 75%
|dV/dt_r   186.52m/28.61p   178.15m/32.19p   203.41m/24.99p
|dV/dt_f   232.53m/42.26p   216.66m/52.08p   260.20m/33.88p
R_load = 50
[Rising Waveform]
R_fixture = 50
V_fixture = 0.0
|   Time   V(typ)   V(min)   V(max)
0s        582.9uV    507.9uV    422.6uV
57ps      330.3uV    -12.95uV   8.236mV
65ps      2.371mV    -478uV     45.36mV
77ps      12.34mV    1.03mV     151.9mV
99ps      147.2mV    18.81mV    316.1mV
113ps     242mV      81.09mV    365.4mV
127ps     303.8mV    170.3mV    389.3mV
154ps     356.5mV    292.1mV    404.2mV
188ps     371.4mV    344.6mV    407mV
390ps     373.6mV    356.8mV    407.2mV
[Falling Waveform]
R_fixture   = 50
V_fixture   = 1.1
V_fixture_min = 1.06
V_fixture_max = 1.17
|   Time   V(typ)   V(min)   V(max)
0s        1.1V       1.06V      1.17V
73ps      1.099V     1.06V      1.157V
94ps      1.082V     1.056V     984.8mV
117ps     943.4mV    1.043V     806.5mV
134ps     837.5mV    981mV      732.4mV
158ps     736.1mV    859.5mV    682.2mV
192ps     670mV      734.7mV    658.3mV
231ps     645.1mV    666.6mV    651.5mV
283ps     636.9mV    636.5mV    649.8mV
390ps     635mV      626.7mV    649.6mV
[Rising Waveform]
R_fixture   = 50
V_fixture   = 1.1
V_fixture_min = 1.06
V_fixture_max = 1.17
|   Time   V(typ)   V(min)   V(max)
0s        634.8mV    625.9mV    649.6mV
54ps      630.9mV    622.1mV    659.3mV
63ps      638.9mV    619mV      701.8mV
76ps      694.4mV    630.8mV    829.4mV
90ps      806.8mV    691.8mV    938.7mV
108ps     916.3mV    814.3mV    1.028V
126ps     983.9mV    903.1mV    1.082V
148ps     1.033V     968.1mV    1.122V
216ps     1.088V     1.042V     1.162V
390ps     1.1V       1.06V      1.17V
[Falling Waveform]
R_fixture = 50
V_fixture = 0.0
|   Time   V(typ)   V(min)   V(max)
0s        373.7mV    357mV      407.3mV
57ps      380.1mV    358.4mV    409.1mV
74ps      372.2mV    368.6mV    308.1mV
86ps      315.4mV    361.7mV    175mV
97ps      229.3mV    325.4mV    101.8mV
112ps     120.2mV    241.3mV    49.42mV
130ps     53.53mV    136.4mV    21.12mV
154ps     18.68mV    50.97mV    7.067mV
188ps     4.728mV    12.48mV    1.819mV
390ps     645uV      595.3uV    443.6uV
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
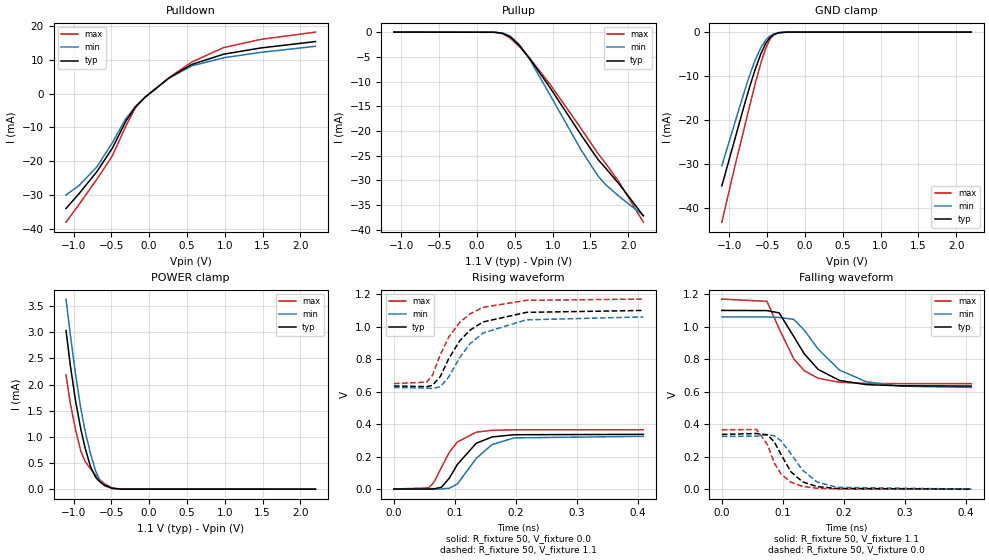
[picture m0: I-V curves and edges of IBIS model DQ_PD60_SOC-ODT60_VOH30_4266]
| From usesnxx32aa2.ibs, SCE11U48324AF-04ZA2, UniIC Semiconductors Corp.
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| DQ_PD60_SOC-ODT60_VOH30_4266
| (60 Ohm Pulldown, 60 Ohm System ODT Setting, VOH=VDDQ/3.0, 3200-4266Mbps)
[Model]   DQ_PD60_SOC-ODT60_VOH30_4266
Model_type   I/O
Vinl = 123.333mV
Vinh = 243.333mV
Vmeas = 183.333mV
Vref = 0.0mV
Cref = 0.0pF
Rref = 60.000Ohm
|   typ   min   max
|C_comp   0.797pF   0.747pF   0.847pF
C_comp_pullup   0.3985pF   0.3735pF   0.4235pF
C_comp_pulldown   0.3985pF   0.3735pF   0.4235pF
| Note: C_comp changes when the ODT circuit is enabled.
[Model Spec]
| Input threshold voltage corners
Vinl   0.1233V   0.1167V   0.1350V
Vinh   0.2433V   0.2367V   0.2550V
| Measurement voltage corners
Vmeas   0.1833V   0.1767V   0.1950V
| Timing spec test load voltage corners
Vref   0.0000V   0.0000V   0.0000V
| Dynamic Overshoot Parameters from LPDDR4 Specification
D_overshoot_ampl_h   0.30   NA   NA
D_overshoot_ampl_l   0.30   NA   NA
D_overshoot_area_h   0.1n   NA   NA
D_overshoot_area_l   0.1n   NA   NA
[Receiver Thresholds]
Vth   = 0.1833V
Vth_min  = 0.1800V
Vth_max  = 0.1866V
Vinh_ac  = 0.060V
Vinh_dc  = 0.060V
Vinl_ac  = -0.060V
Vinl_dc  = -0.060V
Tslew_ac = 5.000ns |Not specified, so set to high value
Threshold_sensitivity = 0.1667
Reference_supply Pullup_ref
[Voltage Range]   1.1000V   1.0600V   1.1700V
[Pullup Reference]   1.1000V   1.0600V   1.1700V
| Junction Temperature (Ambient temp is 35C typ 95C min -40C max)
[Temperature Range]   50.0   110.0   -40.0
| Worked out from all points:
|   slope of the pulldown table from 0 to 0.165 V, typ, clamps not added: 54.8 ohm
|   slope of the pullup table from 0 to 0.165 V, typ, clamps not added: 19.5 kohm
|   GND clamp passes 1 mA (typ) near -0.45 V on its own axis
|   POWER clamp passes 1 mA (typ) near -0.88 V on its own axis
|   rising waveform, R_fixture 50, V_fixture 0.0: 20-80 % time 39.2ps typ, 43.2ps min, 34.3ps max; typ from 0 V to 0.337 V
|   falling waveform, R_fixture 50, V_fixture 1.1: 20-80 % time 52.9ps typ, 65.1ps min, 42.4ps max; typ from 1.1 V to 0.635 V
|   rising waveform, R_fixture 50, V_fixture 1.1: 20-80 % time 54.8ps typ, 58ps min, 51ps max; typ from 0.635 V to 1.1 V
|   falling waveform, R_fixture 50, V_fixture 0.0: 20-80 % time 33.9ps typ, 41.6ps min, 29.2ps max; typ from 0.337 V to 0.001 V
[Pulldown]
|   Voltage   I(typ)   I(min)   I(max)
-1.1V     -33.95mA   -29.97mA   -38mA
-928.4mV  -29.6mA    -27.2mA    -32.8mA
-690.8mV  -23.05mA   -21.64mA   -25.29mA
-486.2mV  -16.1mA    -14.49mA   -18.38mA
-311.3mV  -8.311mA   -7.498mA   -9.723mA
-179.3mV  -3.875mA   -3.754mA   -4.123mA
-57.2mV   -1.146mA   -1.14mA    -1.128mA
266.2mV   4.665mA    4.595mA    4.757mA
563.2mV   8.593mA    8.177mA    9.297mA
985.6mV   11.63mA    10.57mA    13.59mA
1.477V    13.47mA    12.17mA    16mA
2.2V      15.36mA    13.96mA    18.16mA
[GND Clamp]
|   Voltage   I(typ)   I(min)   I(max)
-1.1V     -34.88mA   -30.34mA   -43.13mA
-944.9mV  -25.34mA   -21.53mA   -31.71mA
-786.5mV  -15.59mA   -12.65mA   -20.59mA
-717.2mV  -11.61mA   -9.055mA   -15.72mA
-657.8mV  -8.426mA   -6.313mA   -11.68mA
-585.2mV  -4.986mA   -3.582mA   -7.135mA
-519.2mV  -2.57mA    -1.836mA   -3.672mA
-463.1mV  -1.236mA   -903.7uA   -1.602mA
-410.3mV  -534.5uA   -396.6uA   -581uA
-347.6mV  -155.1uA   -117.2uA   -137uA
-242mV    -10.02uA   -9.32uA    -5.698uA
2.2V      0A         0A         0A
[Pullup]
|   Voltage   I(typ)   I(min)   I(max)
-1.1V     4.189uA    6.456uA    1.888uA
229.9mV   -30.09uA   -30.6uA    -31.02uA
335.5mV   -227.6uA   -188.8uA   -313.1uA
434.5mV   -926.3uA   -757.4uA   -1.172mA
556.6mV   -2.66mA    -2.46mA    -2.874mA
691.9mV   -5.249mA   -5.417mA   -5.187mA
965.8mV   -11.24mA   -12.72mA   -10.55mA
1.378V    -20.83mA   -23.86mA   -19.53mA
1.599V    -25.73mA   -29.06mA   -24.54mA
1.698V    -27.45mA   -30.79mA   -26.48mA
1.877V    -30.67mA   -33.19mA   -30.26mA
2.2V      -37.14mA   -37.09mA   -38.43mA
[POWER Clamp]
|   Voltage   I(typ)   I(min)   I(max)
-1.1V     3.036mA    3.636mA    2.186mA
-1.044V   2.383mA    2.969mA    1.654mA
-974.6mV  1.695mA    2.208mA    1.139mA
-905.3mV  1.155mA    1.554mA    732.7uA
-849.2mV  799.4uA    1.126mA    535.6uA
-776.6mV  434.2uA    683.6uA    390.2uA
-710.6mV  232.2uA    359.2uA    273.1uA
-651.2mV  138.6uA    162.4uA    181.2uA
-591.8mV  77.91uA    64.83uA    105.5uA
-489.5mV  17.77uA    10.9uA     22.46uA
-370.7mV  1.284uA    942.5nA    1.033uA
2.2V      0A         0A         0A
[Ramp]
|   typ   min   max
| 20% - 80%
dV/dt_r   201.98m/39.23p   194.72m/43.20p   219.05m/34.33p
dV/dt_f   279.05m/52.86p   260.14m/65.13p   312.24m/42.44p
| 25% - 75%
|dV/dt_r   168.32m/31.26p   162.27m/34.45p   182.54m/27.26p
|dV/dt_f   232.54m/42.11p   216.78m/51.90p   260.20m/33.77p
R_load = 50
[Rising Waveform]
R_fixture = 50
V_fixture = 0.0
|   Time   V(typ)   V(min)   V(max)
0s        462.5uV    398.5uV    336.8uV
57ps      274.7uV    12.33uV    7.266mV
66ps      1.976mV    -394.6uV   44.45mV
78ps      11.67mV    1.005mV    134mV
91ps      68.14mV    5.555mV    227.6mV
104ps     151.8mV    31.67mV    289.9mV
135ps     282.6mV    189.1mV    350.6mV
161ps     321mV      274.5mV    362.1mV
197ps     334.7mV    315.2mV    365mV
409ps     337.1mV    324.9mV    365.4mV
[Falling Waveform]
R_fixture   = 50
V_fixture   = 1.1
V_fixture_min = 1.06
V_fixture_max = 1.17
|   Time   V(typ)   V(min)   V(max)
0s        1.1V       1.06V      1.17V
74ps      1.099V     1.06V      1.156V
94ps      1.085V     1.057V     987.1mV
118ps     939mV      1.045V     801.9mV
135ps     833.6mV    979.3mV    729.8mV
158ps     736.9mV    861.8mV    682.4mV
193ps     669mV      732.9mV    658mV
237ps     643.4mV    661.1mV    651.1mV
293ps     636.4mV    634.1mV    649.8mV
409ps     634.9mV    626.4mV    649.6mV
[Rising Waveform]
R_fixture   = 50
V_fixture   = 1.1
V_fixture_min = 1.06
V_fixture_max = 1.17
|   Time   V(typ)   V(min)   V(max)
0s        634.8mV    625.9mV    649.6mV
54ps      631mV      622.2mV    658.7mV
63ps      638.6mV    619.2mV    699.7mV
76ps      692.6mV    630.7mV    826.7mV
90ps      803.9mV    690.4mV    936.5mV
108ps     913.8mV    811.1mV    1.027V
125ps     979mV      895.8mV    1.079V
146ps     1.029V     961mV      1.119V
217ps     1.088V     1.042V     1.162V
409ps     1.1V       1.06V      1.17V
[Falling Waveform]
R_fixture = 50
V_fixture = 0.0
|   Time   V(typ)   V(min)   V(max)
0s        337.2mV    325mV      365.5mV
57ps      342.7mV    326.6mV    367.3mV
75ps      335mV      335.4mV    273.1mV
86ps      290.9mV    329.1mV    161.5mV
97ps      214.5mV    298.1mV    94.11mV
113ps     108.2mV    219.1mV    43.63mV
132ps     46.18mV    118.7mV    17.81mV
156ps     16.23mV    44.48mV    6.015mV
189ps     4.242mV    11.47mV    1.584mV
409ps     532.6uV    493.7uV    359.9uV
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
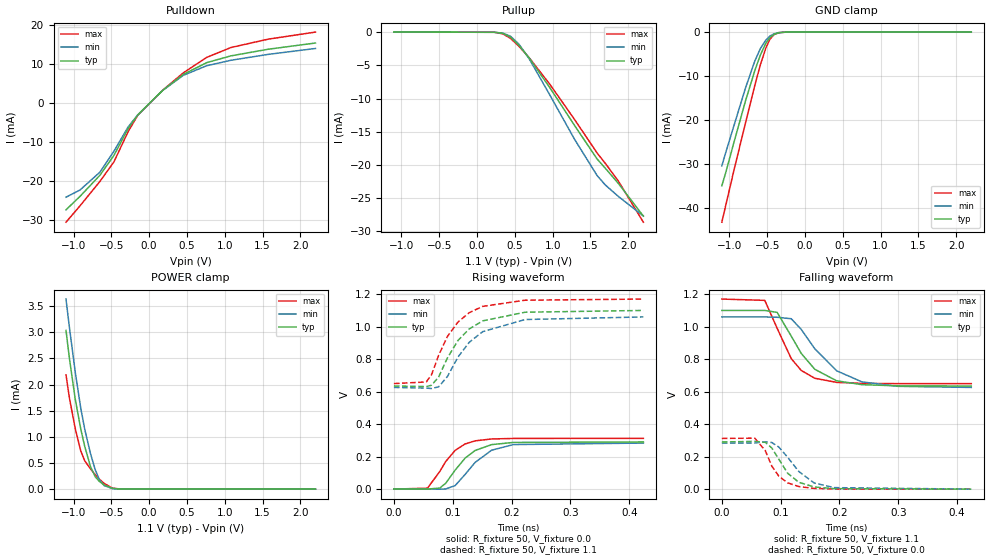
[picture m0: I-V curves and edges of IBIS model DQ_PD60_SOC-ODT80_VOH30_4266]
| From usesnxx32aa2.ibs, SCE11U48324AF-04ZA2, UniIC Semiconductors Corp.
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| DQ_PD60_SOC-ODT80_VOH30_4266
| (60 Ohm Pulldown, 80 Ohm System ODT Setting, VOH=VDDQ/3.0, 3200-4266Mbps)
[Model]   DQ_PD60_SOC-ODT80_VOH30_4266
Model_type   I/O
Vinl = 123.333mV
Vinh = 243.333mV
Vmeas = 183.333mV
Vref = 0.0mV
Cref = 0.0pF
Rref = 80.000Ohm
|   typ   min   max
|C_comp   0.797pF   0.747pF   0.847pF
C_comp_pullup   0.3985pF   0.3735pF   0.4235pF
C_comp_pulldown   0.3985pF   0.3735pF   0.4235pF
| Note: C_comp changes when the ODT circuit is enabled.
[Model Spec]
| Input threshold voltage corners
Vinl   0.1233V   0.1167V   0.1350V
Vinh   0.2433V   0.2367V   0.2550V
| Measurement voltage corners
Vmeas   0.1833V   0.1767V   0.1950V
| Timing spec test load voltage corners
Vref   0.0000V   0.0000V   0.0000V
| Dynamic Overshoot Parameters from LPDDR4 Specification
D_overshoot_ampl_h   0.30   NA   NA
D_overshoot_ampl_l   0.30   NA   NA
D_overshoot_area_h   0.1n   NA   NA
D_overshoot_area_l   0.1n   NA   NA
[Receiver Thresholds]
Vth   = 0.1833V
Vth_min  = 0.1800V
Vth_max  = 0.1866V
Vinh_ac  = 0.060V
Vinh_dc  = 0.060V
Vinl_ac  = -0.060V
Vinl_dc  = -0.060V
Tslew_ac = 5.000ns |Not specified, so set to high value
Threshold_sensitivity = 0.1667
Reference_supply Pullup_ref
[Voltage Range]   1.1000V   1.0600V   1.1700V
[Pullup Reference]   1.1000V   1.0600V   1.1700V
| Junction Temperature (Ambient temp is 35C typ 95C min -40C max)
[Temperature Range]   50.0   110.0   -40.0
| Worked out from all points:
|   slope of the pulldown table from 0 to 0.165 V, typ, clamps not added: 54.9 ohm
|   slope of the pullup table from 0 to 0.165 V, typ, clamps not added: 26 kohm
|   GND clamp passes 1 mA (typ) near -0.45 V on its own axis
|   POWER clamp passes 1 mA (typ) near -0.88 V on its own axis
|   rising waveform, R_fixture 50, V_fixture 0.0: 20-80 % time 42.6ps typ, 45.8ps min, 37.1ps max; typ from 0 V to 0.29 V
|   falling waveform, R_fixture 50, V_fixture 1.1: 20-80 % time 52.6ps typ, 64.9ps min, 42.4ps max; typ from 1.1 V to 0.635 V
|   rising waveform, R_fixture 50, V_fixture 1.1: 20-80 % time 54.9ps typ, 58.7ps min, 51ps max; typ from 0.635 V to 1.1 V
|   falling waveform, R_fixture 50, V_fixture 0.0: 20-80 % time 34.4ps typ, 42.2ps min, 29.8ps max; typ from 0.29 V to 0 V
[Pulldown]
|   Voltage   I(typ)   I(min)   I(max)
-1.1V     -27.4mA    -24.16mA   -30.57mA
-915.2mV  -23.96mA   -22.33mA   -26.39mA
-651.2mV  -18.54mA   -17.74mA   -20.12mA
-466.4mV  -13.46mA   -12.39mA   -15.12mA
-278.3mV  -6.578mA   -6.17mA    -7.377mA
-152.9mV  -3.144mA   -3.103mA   -3.218mA
180.4mV   3.257mA    3.226mA    3.281mA
451mV     7.295mA    7.062mA    7.703mA
761.2mV   10.33mA    9.539mA    11.67mA
1.081V    12.06mA    10.93mA    14.2mA
1.573V    13.76mA    12.44mA    16.34mA
2.2V      15.36mA    13.96mA    18.16mA
[GND Clamp]
|   Voltage   I(typ)   I(min)   I(max)
-1.1V     -34.88mA   -30.35mA   -43.13mA
-1.047V   -31.79mA   -27.25mA   -39.23mA
-938.3mV  -24.92mA   -21.15mA   -31.24mA
-786.5mV  -15.59mA   -12.65mA   -20.59mA
-664.4mV  -8.768mA   -6.598mA   -12.12mA
-591.8mV  -5.271mA   -3.798mA   -7.523mA
-519.2mV  -2.571mA   -1.839mA   -3.672mA
-466.4mV  -1.297mA   -942.7uA   -1.694mA
-410.3mV  -534.1uA   -395.9uA   -581.4uA
-344.3mV  -143.4uA   -109.5uA   -125.1uA
-251.9mV  -13.34uA   -12.06uA   -7.921uA
2.2V      0A         0A         0A
[Pullup]
|   Voltage   I(typ)   I(min)   I(max)
-1.1V     3.142uA    4.844uA    1.416uA
229.9mV   -22.58uA   -23.09uA   -23.3uA
342.1mV   -190.6uA   -157.8uA   -262.8uA
441.1mV   -747.9uA   -614.3uA   -936.2uA
550mV     -1.908mA   -1.754mA   -2.076mA
688.6mV   -3.881mA   -3.997mA   -3.841mA
962.5mV   -8.363mA   -9.458mA   -7.852mA
1.292V    -14.09mA   -16.18mA   -13.19mA
1.589V    -19.11mA   -21.6mA    -18.21mA
1.695V    -20.47mA   -22.99mA   -19.73mA
1.867V    -22.74mA   -24.71mA   -22.38mA
2.2V      -27.69mA   -27.68mA   -28.61mA
[POWER Clamp]
|   Voltage   I(typ)   I(min)   I(max)
-1.1V     3.036mA    3.636mA    2.186mA
-1.054V   2.493mA    3.084mA    1.737mA
-977.9mV  1.724mA    2.242mA    1.161mA
-905.3mV  1.155mA    1.554mA    732.9uA
-852.5mV  818.5uA    1.149mA    543.7uA
-776.6mV  434.2uA    683.5uA    390.2uA
-713.9mV  239.2uA    373.1uA    278.6uA
-657.8mV  146.8uA    178.8uA    190.7uA
-595.1mV  80.79uA    68.31uA    109.2uA
-486.2mV  16.73uA    10.22uA    21.06uA
-374mV    1.381uA    990.6nA    1.129uA
2.2V      0A         0A         0A
[Ramp]
|   typ   min   max
| 20% - 80%
dV/dt_r   174.01m/42.64p   169.96m/45.78p   187.41m/37.08p
dV/dt_f   279.06m/52.68p   260.21m/64.94p   312.24m/42.38p
| 25% - 75%
|dV/dt_r   145.01m/34.03p   141.64m/36.53p   156.18m/29.42p
|dV/dt_f   232.55m/41.99p   216.84m/51.75p   260.20m/33.68p
R_load = 50
[Rising Waveform]
R_fixture = 50
V_fixture = 0.0
|   Time   V(typ)   V(min)   V(max)
0s        342uV      288.5uV    251.4uV
57ps      32.86uV    146.3uV    5.657mV
78ps      6.763mV    -295.2uV   108.7mV
88ps      35.97mV    1.04mV     169.7mV
104ps     116.6mV    21.47mV    238.4mV
121ps     190.8mV    90.4mV     278.1mV
138ps     237.8mV    164.2mV    297.2mV
166ps     274mV      239.4mV    308.7mV
203ps     287.4mV    274.2mV    312mV
424ps     290.4mV    283.6mV    312.6mV
[Falling Waveform]
R_fixture   = 50
V_fixture   = 1.1
V_fixture_min = 1.06
V_fixture_max = 1.17
|   Time   V(typ)   V(min)   V(max)
0s        1.1V       1.06V      1.17V
73ps      1.1V       1.06V      1.162V
94ps      1.088V     1.058V     990.2mV
118ps     941.9mV    1.049V     803.5mV
135ps     835.5mV    983mV      730.6mV
158ps     737.9mV    864.3mV    682.7mV
195ps     667.3mV    729mV      657.4mV
238ps     643.2mV    660.6mV    651.1mV
299ps     636.1mV    633mV      649.7mV
424ps     634.9mV    626.3mV    649.6mV
[Rising Waveform]
R_fixture   = 50
V_fixture   = 1.1
V_fixture_min = 1.06
V_fixture_max = 1.17
|   Time   V(typ)   V(min)   V(max)
0s        634.8mV    625.9mV    649.6mV
55ps      631.2mV    621.9mV    659.7mV
64ps      639.6mV    619.3mV    704.6mV
76ps      690mV      629.8mV    823.5mV
91ps      808.1mV    693.8mV    940.3mV
109ps     915.6mV    813.3mV    1.029V
128ps     986mV      903.8mV    1.086V
151ps     1.036V     969.6mV    1.125V
223ps     1.089V     1.044V     1.163V
424ps     1.1V       1.06V      1.17V
[Falling Waveform]
R_fixture = 50
V_fixture = 0.0
|   Time   V(typ)   V(min)   V(max)
0s        290.5mV    283.7mV    312.7mV
56ps      294.4mV    284.5mV    314mV
74ps      288.4mV    291.9mV    236.4mV
85ps      253.5mV    287.3mV    142mV
97ps      184mV      258.9mV    79.6mV
112ps     97.89mV    195.9mV    39.05mV
131ps     42.34mV    108.4mV    16.05mV
157ps     13.75mV    38.17mV    4.941mV
191ps     3.467mV    9.682mV    1.253mV
424ps     416.3uV    389.6uV    275.9uV
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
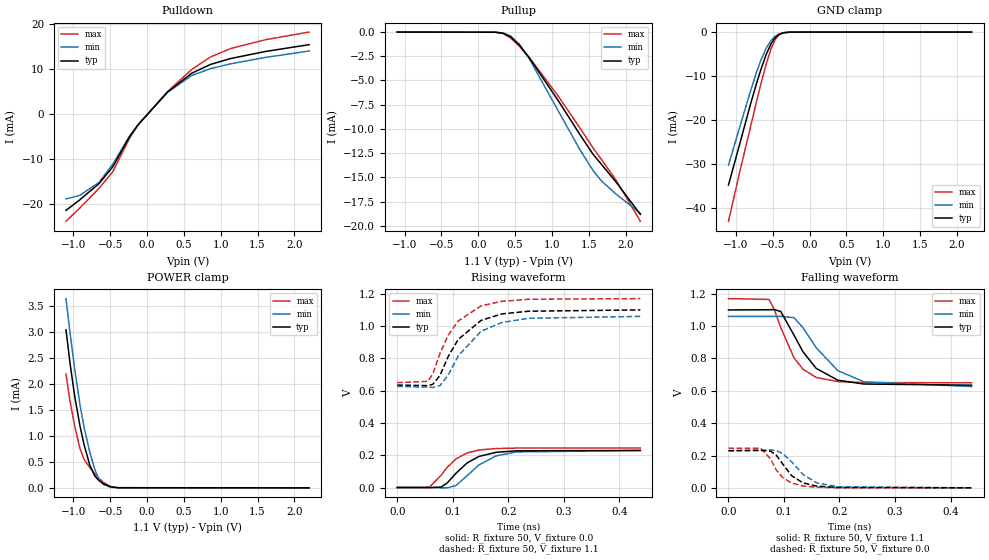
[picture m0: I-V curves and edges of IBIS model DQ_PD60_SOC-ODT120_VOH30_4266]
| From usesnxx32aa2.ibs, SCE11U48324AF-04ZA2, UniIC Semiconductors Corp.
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| DQ_PD60_SOC-ODT120_VOH30_4266
| (60 Ohm Pulldown, 120 Ohm System ODT Setting, VOH=VDDQ/3.0, 3200-4266Mbps)
[Model]   DQ_PD60_SOC-ODT120_VOH30_4266
Model_type   I/O
Vinl = 123.333mV
Vinh = 243.333mV
Vmeas = 183.333mV
Vref = 0.0mV
Cref = 0.0pF
Rref = 120.000Ohm
|   typ   min   max
|C_comp   0.797pF   0.747pF   0.847pF
C_comp_pullup   0.3985pF   0.3735pF   0.4235pF
C_comp_pulldown   0.3985pF   0.3735pF   0.4235pF
| Note: C_comp changes when the ODT circuit is enabled.
[Model Spec]
| Input threshold voltage corners
Vinl   0.1233V   0.1167V   0.1350V
Vinh   0.2433V   0.2367V   0.2550V
| Measurement voltage corners
Vmeas   0.1833V   0.1767V   0.1950V
| Timing spec test load voltage corners
Vref   0.0000V   0.0000V   0.0000V
| Dynamic Overshoot Parameters from LPDDR4 Specification
D_overshoot_ampl_h   0.30   NA   NA
D_overshoot_ampl_l   0.30   NA   NA
D_overshoot_area_h   0.1n   NA   NA
D_overshoot_area_l   0.1n   NA   NA
[Receiver Thresholds]
Vth   = 0.1833V
Vth_min  = 0.1800V
Vth_max  = 0.1866V
Vinh_ac  = 0.060V
Vinh_dc  = 0.060V
Vinl_ac  = -0.060V
Vinl_dc  = -0.060V
Tslew_ac = 5.000ns |Not specified, so set to high value
Threshold_sensitivity = 0.1667
Reference_supply Pullup_ref
[Voltage Range]   1.1000V   1.0600V   1.1700V
[Pullup Reference]   1.1000V   1.0600V   1.1700V
| Junction Temperature (Ambient temp is 35C typ 95C min -40C max)
[Temperature Range]   50.0   110.0   -40.0
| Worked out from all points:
|   slope of the pulldown table from 0 to 0.165 V, typ, clamps not added: 55 ohm
|   slope of the pullup table from 0 to 0.165 V, typ, clamps not added: 39.2 kohm
|   GND clamp passes 1 mA (typ) near -0.45 V on its own axis
|   POWER clamp passes 1 mA (typ) near -0.88 V on its own axis
|   rising waveform, R_fixture 50, V_fixture 0.0: 20-80 % time 46.3ps typ, 50.6ps min, 41ps max; typ from 0 V to 0.23 V
|   falling waveform, R_fixture 50, V_fixture 1.1: 20-80 % time 52.4ps typ, 64.8ps min, 42.2ps max; typ from 1.1 V to 0.635 V
|   rising waveform, R_fixture 50, V_fixture 1.1: 20-80 % time 55ps typ, 59.2ps min, 50.8ps max; typ from 0.635 V to 1.1 V
|   falling waveform, R_fixture 50, V_fixture 0.0: 20-80 % time 34.2ps typ, 41.7ps min, 29.6ps max; typ from 0.23 V to 0 V
[Pulldown]
|   Voltage   I(typ)   I(min)   I(max)
-1.1V     -21.38mA   -18.84mA   -23.8mA
-915.2mV  -19.08mA   -18.08mA   -20.91mA
-651.2mV  -15.44mA   -15.17mA   -16.49mA
-466.4mV  -11.77mA   -11.18mA   -12.85mA
-238.7mV  -5.091mA   -4.958mA   -5.414mA
-119.9mV  -2.378mA   -2.374mA   -2.368mA
279.4mV   4.872mA    4.795mA    4.979mA
606.1mV   9.029mA    8.529mA    9.862mA
863.5mV   10.99mA    10.05mA    12.65mA
1.134V    12.28mA    11.11mA    14.49mA
1.606V    13.85mA    12.53mA    16.46mA
2.2V      15.36mA    13.96mA    18.16mA
[GND Clamp]
|   Voltage   I(typ)   I(min)   I(max)
-1.1V     -34.88mA   -30.34mA   -43.13mA
-944.9mV  -25.34mA   -21.53mA   -31.71mA
-799.7mV  -16.37mA   -13.37mA   -21.52mA
-720.5mV  -11.79mA   -9.217mA   -15.95mA
-661.1mV  -8.596mA   -6.454mA   -11.9mA
-588.5mV  -5.128mA   -3.689mA   -7.329mA
-522.5mV  -2.671mA   -1.907mA   -3.823mA
-466.4mV  -1.296mA   -943.7uA   -1.693mA
-413.6mV  -564uA     -416.5uA   -622.2uA
-354.2mV  -178uA     -134.9uA   -160.1uA
-265.1mV  -19.36uA   -16.78uA   -12.28uA
2.2V      0A         0A         0A
[Pullup]
|   Voltage   I(typ)   I(min)   I(max)
-1.1V     2.095uA    3.229uA    944.4nA
233.2mV   -16.25uA   -16.28uA   -16.91uA
335.5mV   -114uA     -94.74uA   -157uA
437.8mV   -483.5uA   -396.4uA   -608.9uA
559.9mV   -1.371mA   -1.275mA   -1.475mA
695.2mV   -2.689mA   -2.789mA   -2.648mA
1.078V    -6.994mA   -8.033mA   -6.53mA
1.378V    -10.56mA   -12.12mA   -9.881mA
1.556V    -12.6mA    -14.28mA   -11.94mA
1.675V    -13.69mA   -15.4mA    -13.19mA
1.867V    -15.45mA   -16.71mA   -15.25mA
2.2V      -18.83mA   -18.72mA   -19.54mA
[POWER Clamp]
|   Voltage   I(typ)   I(min)   I(max)
-1.1V     3.036mA    3.636mA    2.186mA
-1.044V   2.383mA    2.97mA     1.654mA
-981.2mV  1.754mA    2.277mA    1.184mA
-908.6mV  1.178mA    1.583mA    748.4uA
-852.5mV  818.6uA    1.149mA    543.8uA
-776.6mV  434.3uA    683.6uA    390.2uA
-710.6mV  232.2uA    359.2uA    273.1uA
-657.8mV  146.8uA    178.8uA    190.7uA
-595.1mV  80.75uA    68.33uA    109.3uA
-499.4mV  21.28uA    13.16uA    27.48uA
-397.1mV  2.365uA    1.593uA    2.116uA
2.2V      0A         0A         0A
[Ramp]
|   typ   min   max
| 20% - 80%
dV/dt_r   137.84m/46.34p   137.40m/50.57p   147.04m/41.05p
dV/dt_f   279.05m/52.49p   260.28m/64.80p   312.24m/42.18p
| 25% - 75%
|dV/dt_r   114.87m/36.96p   114.50m/40.38p   122.53m/32.59p
|dV/dt_f   232.54m/41.84p   216.90m/51.54p   260.20m/33.58p
R_load = 50
[Rising Waveform]
R_fixture = 50
V_fixture = 0.0
|   Time   V(typ)   V(min)   V(max)
0s        221.8uV    180.7uV    165.3uV
58ps      -313.2uV   205.8uV    2.887mV
79ps      3.06mV     -1.523mV   76.11mV
90ps      28.4mV     -1.698mV   125.3mV
106ps     89.11mV    12.74mV    177.8mV
126ps     152.7mV    73.95mV    214.4mV
147ps     192.4mV    139.5mV    232.3mV
178ps     218.4mV    196mV      241.7mV
215ps     227.4mV    220.8mV    244.5mV
438ps     230mV      229.2mV    245.2mV
[Falling Waveform]
R_fixture   = 50
V_fixture   = 1.1
V_fixture_min = 1.06
V_fixture_max = 1.17
|   Time   V(typ)   V(min)   V(max)
0s        1.1V       1.06V      1.17V
73ps      1.101V     1.06V      1.165V
82ps      1.102V     1.06V      1.107V
94ps      1.091V     1.06V      992.5mV
118ps     944.4mV    1.052V     804.4mV
134ps     842.7mV    991.2mV    734.2mV
158ps     738.7mV    866.3mV    682.8mV
197ps     665.5mV    724.8mV    656.9mV
244ps     641.9mV    655.8mV    650.8mV
438ps     634.9mV    626.2mV    649.6mV
[Rising Waveform]
R_fixture   = 50
V_fixture   = 1.1
V_fixture_min = 1.06
V_fixture_max = 1.17
|   Time   V(typ)   V(min)   V(max)
0s        634.8mV    625.9mV    649.6mV
55ps      631.2mV    622.2mV    657.9mV
64ps      638.7mV    619.4mV    701.7mV
77ps      694.3mV    631.3mV    830.5mV
92ps      812.6mV    697.5mV    944.7mV
110ps     917.9mV    815.6mV    1.032V
151ps     1.035V     967.7mV    1.125V
188ps     1.075V     1.022V     1.153V
237ps     1.092V     1.048V     1.166V
438ps     1.1V       1.06V      1.17V
[Falling Waveform]
R_fixture = 50
V_fixture = 0.0
|   Time   V(typ)   V(min)   V(max)
0s        230mV      229.3mV    245.3mV
58ps      232.8mV    230mV      245mV
76ps      226.6mV    234.6mV    179.1mV
86ps      202.4mV    231.3mV    111.1mV
98ps      146.3mV    211.3mV    62.53mV
114ps     74.7mV     160mV      29.42mV
134ps     31.06mV    83.77mV    11.59mV
159ps     10.61mV    30.76mV    3.75mV
197ps     2.32mV     6.768mV    823.4uV
438ps     295.2uV    281uV      189.8uV
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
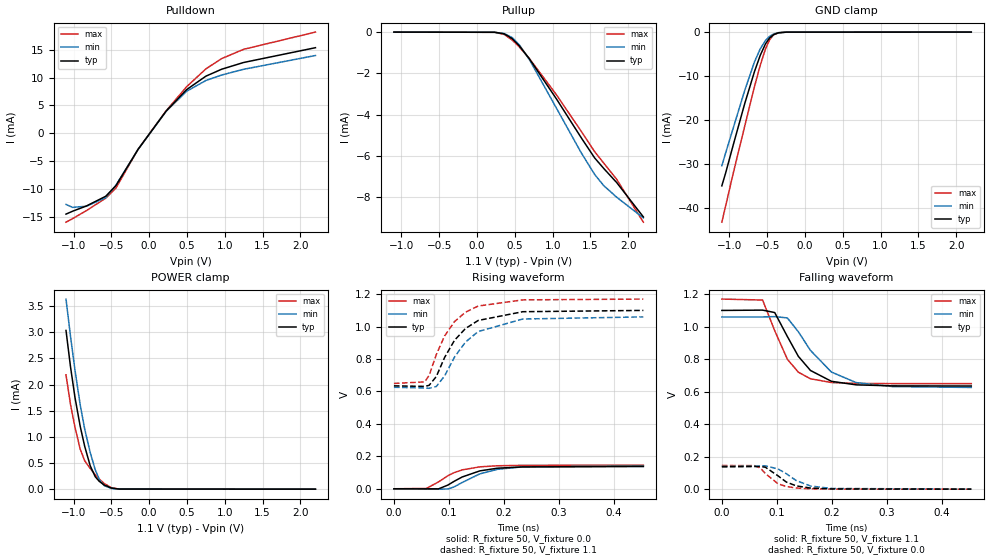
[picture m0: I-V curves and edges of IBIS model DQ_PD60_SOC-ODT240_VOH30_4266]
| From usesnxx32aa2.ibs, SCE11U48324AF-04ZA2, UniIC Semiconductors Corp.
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| DQ_PD60_SOC-ODT240_VOH30_4266
| (60 Ohm Pulldown, 240 Ohm System ODT Setting, VOH=VDDQ/3.0, 3200-4266Mbps)
[Model]   DQ_PD60_SOC-ODT240_VOH30_4266
Model_type   I/O
Vinl = 123.333mV
Vinh = 243.333mV
Vmeas = 183.333mV
Vref = 0.0mV
Cref = 0.0pF
Rref = 240.000Ohm
|   typ   min   max
|C_comp   0.797pF   0.747pF   0.847pF
C_comp_pullup   0.3985pF   0.3735pF   0.4235pF
C_comp_pulldown   0.3985pF   0.3735pF   0.4235pF
| Note: C_comp changes when the ODT circuit is enabled.
[Model Spec]
| Input threshold voltage corners
Vinl   0.1233V   0.1167V   0.1350V
Vinh   0.2433V   0.2367V   0.2550V
| Measurement voltage corners
Vmeas   0.1833V   0.1767V   0.1950V
| Timing spec test load voltage corners
Vref   0.0000V   0.0000V   0.0000V
| Dynamic Overshoot Parameters from LPDDR4 Specification
D_overshoot_ampl_h   0.30   NA   NA
D_overshoot_ampl_l   0.30   NA   NA
D_overshoot_area_h   0.1n   NA   NA
D_overshoot_area_l   0.1n   NA   NA
[Receiver Thresholds]
Vth   = 0.1833V
Vth_min  = 0.1800V
Vth_max  = 0.1866V
Vinh_ac  = 0.060V
Vinh_dc  = 0.060V
Vinl_ac  = -0.060V
Vinl_dc  = -0.060V
Tslew_ac = 5.000ns |Not specified, so set to high value
Threshold_sensitivity = 0.1667
Reference_supply Pullup_ref
[Voltage Range]   1.1000V   1.0600V   1.1700V
[Pullup Reference]   1.1000V   1.0600V   1.1700V
| Junction Temperature (Ambient temp is 35C typ 95C min -40C max)
[Temperature Range]   50.0   110.0   -40.0
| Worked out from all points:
|   slope of the pulldown table from 0 to 0.165 V, typ, clamps not added: 55.1 ohm
|   slope of the pullup table from 0 to 0.165 V, typ, clamps not added: 77.7 kohm
|   GND clamp passes 1 mA (typ) near -0.45 V on its own axis
|   POWER clamp passes 1 mA (typ) near -0.88 V on its own axis
|   rising waveform, R_fixture 50, V_fixture 0.0: 20-80 % time 55.3ps typ, 57.8ps min, 48.2ps max; typ from 0 V to 0.137 V
|   falling waveform, R_fixture 50, V_fixture 1.1: 20-80 % time 52.4ps typ, 64.5ps min, 42.1ps max; typ from 1.1 V to 0.635 V
|   rising waveform, R_fixture 50, V_fixture 1.1: 20-80 % time 55.2ps typ, 60ps min, 50.8ps max; typ from 0.635 V to 1.1 V
|   falling waveform, R_fixture 50, V_fixture 0.0: 20-80 % time 34.5ps typ, 42.5ps min, 30.4ps max; typ from 0.137 V to 0 V
[Pulldown]
|   Voltage   I(typ)   I(min)   I(max)
-1.1V     -14.48mA   -12.74mA   -15.93mA
-1.014V   -13.97mA   -13.27mA   -15.3mA
-829.4mV  -13.02mA   -13.07mA   -13.85mA
-575.3mV  -11.29mA   -11.53mA   -11.63mA
-440mV    -9.389mA   -9.306mA   -9.828mA
-146.3mV  -2.865mA   -2.877mA   -2.849mA
226.6mV   4.028mA    3.978mA    4.083mA
497.2mV   7.857mA    7.557mA    8.379mA
751.3mV   10.26mA    9.484mA    11.57mA
959.2mV   11.5mA     10.46mA    13.41mA
1.25V     12.71mA    11.49mA    15.07mA
2.2V      15.36mA    13.96mA    18.16mA
[GND Clamp]
|   Voltage   I(typ)   I(min)   I(max)
-1.1V     -34.88mA   -30.33mA   -43.13mA
-1.05V    -31.99mA   -27.44mA   -39.47mA
-948.2mV  -25.55mA   -21.71mA   -31.95mA
-796.4mV  -16.18mA   -13.19mA   -21.29mA
-667.7mV  -8.94mA    -6.742mA   -12.34mA
-591.8mV  -5.271mA   -3.798mA   -7.524mA
-522.5mV  -2.672mA   -1.906mA   -3.823mA
-466.4mV  -1.298mA   -945.2uA   -1.694mA
-413.6mV  -566.8uA   -418.4uA   -620.7uA
-350.9mV  -167uA     -126.8uA   -146.8uA
-242mV    -10.02uA   -9.164uA   -5.606uA
2.2V      0A         0A         0A
[Pullup]
|   Voltage   I(typ)   I(min)   I(max)
-1.1V     1.047uA    1.615uA    471.8nA
233.2mV   -8.147uA   -8.219uA   -8.43uA
358.6mV   -82.65uA   -67.24uA   -113.8uA
464.2mV   -314.5uA   -264uA     -381uA
559.9mV   -671.3uA   -622.3uA   -724.5uA
691.9mV   -1.294mA   -1.331mA   -1.282mA
1.048V    -3.231mA   -3.677mA   -3.031mA
1.378V    -5.127mA   -5.857mA   -4.815mA
1.556V    -6.109mA   -6.911mA   -5.805mA
1.675V    -6.614mA   -7.448mA   -6.356mA
1.847V    -7.302mA   -8.014mA   -7.145mA
2.2V      -8.971mA   -9.018mA   -9.226mA
[POWER Clamp]
|   Voltage   I(typ)   I(min)   I(max)
-1.1V     3.036mA    3.636mA    2.186mA
-1.041V   2.347mA    2.931mA    1.626mA
-981.2mV  1.754mA    2.277mA    1.183mA
-911.9mV  1.201mA    1.611mA    764.9uA
-852.5mV  818.5uA    1.149mA    543.6uA
-779.9mV  448.2uA    701.7uA    396.3uA
-713.9mV  239.3uA    373.1uA    278.6uA
-657.8mV  146.8uA    178.9uA    190.7uA
-595.1mV  80.76uA    68.32uA    109.3uA
-499.4mV  21.34uA    13.22uA    27.44uA
-400.4mV  2.587uA    1.704uA    2.312uA
2.2V      0A         0A         0A
[Ramp]
|   typ   min   max
| 20% - 80%
dV/dt_r   82.40m/55.29p   84.16m/57.77p   87.16m/48.24p
dV/dt_f   279.06m/52.40p   260.32m/64.46p   312.24m/42.10p
| 25% - 75%
|dV/dt_r   68.67m/43.96p   70.13m/46.06p   72.64m/38.25p
|dV/dt_f   232.55m/41.80p   216.94m/51.37p   260.20m/33.48p
R_load = 50
[Rising Waveform]
R_fixture = 50
V_fixture = 0.0
|   Time   V(typ)   V(min)   V(max)
0s        98.94uV    68.83uV    77.67uV
59ps      -581.4uV   192.8uV    2.194mV
81ps      -445.8uV   -2.366mV   42.52mV
98ps      22.88mV    -957uV     80.64mV
109ps     45.33mV    11.08mV    98.94mV
124ps     72.85mV    38.87mV    116.5mV
156ps     110.3mV    91.97mV    135.3mV
188ps     126.9mV    120.1mV    141.9mV
233ps     134.8mV    135mV      144.6mV
453ps     137.4mV    140.3mV    145.4mV
[Falling Waveform]
R_fixture   = 50
V_fixture   = 1.1
V_fixture_min = 1.06
V_fixture_max = 1.17
|   Time   V(typ)   V(min)   V(max)
0s        1.1V       1.06V      1.17V
74ps      1.102V     1.06V      1.164V
96ps      1.087V     1.062V     975.6mV
119ps     939.6mV    1.054V     799.7mV
139ps     817.2mV    968.4mV    719.9mV
161ps     730.5mV    853.9mV    679.4mV
199ps     663.9mV    720.8mV    656.4mV
244ps     642mV      656mV      650.8mV
310ps     635.8mV    631.4mV    649.7mV
453ps     634.9mV    626.1mV    649.6mV
[Rising Waveform]
R_fixture   = 50
V_fixture   = 1.1
V_fixture_min = 1.06
V_fixture_max = 1.17
|   Time   V(typ)   V(min)   V(max)
0s        634.8mV    625.9mV    649.6mV
56ps      631.4mV    621.9mV    659.2mV
64ps      638.2mV    619.6mV    699.4mV
77ps      692.3mV    631mV      827.7mV
92ps      809.7mV    695.7mV    942.6mV
110ps     915.6mV    812.2mV    1.031V
130ps     988.6mV    904.9mV    1.089V
153ps     1.038V     969.7mV    1.127V
234ps     1.092V     1.047V     1.165V
453ps     1.1V       1.06V      1.17V
[Falling Waveform]
R_fixture = 50
V_fixture = 0.0
|   Time   V(typ)   V(min)   V(max)
0s        137.5mV    140.4mV    145.4mV
59ps      139.3mV    141.4mV    145.1mV
70ps      139.4mV    143.1mV    130.2mV
79ps      135.3mV    143.3mV    96.47mV
102ps     82.19mV    124.8mV    33.23mV
117ps     44.16mV    95.31mV    16.7mV
135ps     20.47mV    53.32mV    7.34mV
161ps     6.9mV      19.48mV    2.289mV
199ps     1.528mV    4.5mV      493.7uV
453ps     162.8uV    160.2uV    98.54uV
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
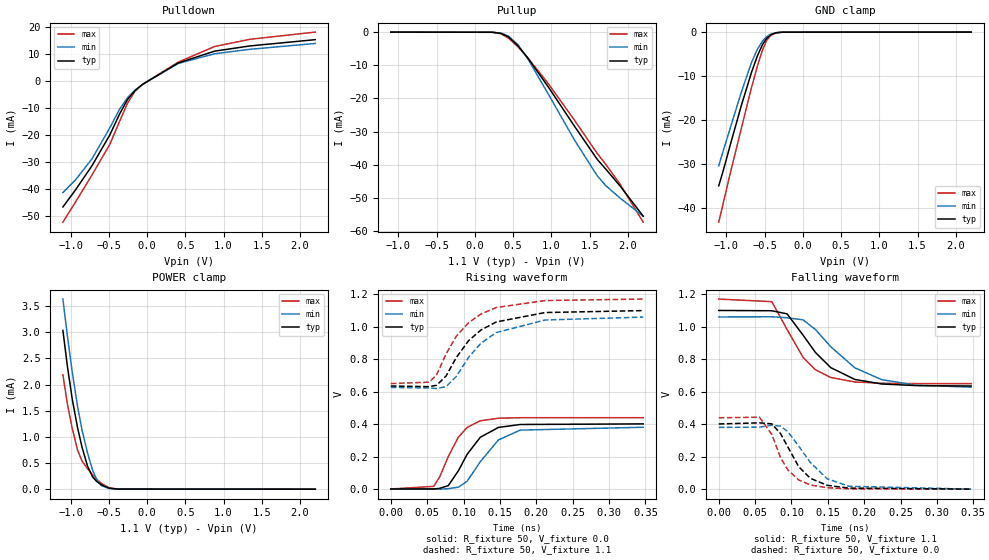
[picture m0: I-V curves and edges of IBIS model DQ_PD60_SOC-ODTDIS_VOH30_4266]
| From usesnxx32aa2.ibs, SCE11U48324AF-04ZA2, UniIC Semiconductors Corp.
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| DQ_PD60_SOC-ODTDIS_VOH30_4266
| (60 Ohm Pulldown, SOC ODT disabled setting, VOH=VDDQ/3.0 cal. point, 3200-4266Mbps)
[Model]   DQ_PD60_SOC-ODTDIS_VOH30_4266
Model_type   I/O
Vinl = 123.333mV
Vinh = 243.333mV
Vmeas = 183.333mV
Vref = 0.0mV
Cref = 0.0pF
|   typ   min   max
|C_comp   0.797pF   0.747pF   0.847pF
C_comp_pullup   0.3985pF   0.3735pF   0.4235pF
C_comp_pulldown   0.3985pF   0.3735pF   0.4235pF
| Note: C_comp changes when the ODT circuit is enabled.
[Model Spec]
| Input threshold voltage corners
Vinl   0.1233V   0.1167V   0.1350V
Vinh   0.2433V   0.2367V   0.2550V
| Measurement voltage corners
Vmeas   0.1833V   0.1767V   0.1950V
| Timing spec test load voltage corners
Vref   0.0000V   0.0000V   0.0000V
| Dynamic Overshoot Parameters from LPDDR4 Specification
D_overshoot_ampl_h   0.30   NA   NA
D_overshoot_ampl_l   0.30   NA   NA
D_overshoot_area_h   0.1n   NA   NA
D_overshoot_area_l   0.1n   NA   NA
[Receiver Thresholds]
Vth   = 0.1833V
Vth_min  = 0.1800V
Vth_max  = 0.1866V
Vinh_ac  = 0.060V
Vinh_dc  = 0.060V
Vinl_ac  = -0.060V
Vinl_dc  = -0.060V
Tslew_ac = 5.000ns |Not specified, so set to high value
Threshold_sensitivity = 0.1667
Reference_supply Pullup_ref
[Voltage Range]   1.1000V   1.0600V   1.1700V
[Pullup Reference]   1.1000V   1.0600V   1.1700V
| Junction Temperature (Ambient temp is 35C typ 95C min -40C max)
[Temperature Range]   50.0   110.0   -40.0
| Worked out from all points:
|   slope of the pulldown table from 0 to 0.165 V, typ, clamps not added: 54.7 ohm
|   slope of the pullup table from 0 to 0.165 V, typ, clamps not added: 13 kohm
|   GND clamp passes 1 mA (typ) near -0.45 V on its own axis
|   POWER clamp passes 1 mA (typ) near -0.88 V on its own axis
|   rising waveform, R_fixture 50, V_fixture 0.0: 20-80 % time 34.5ps typ, 38.6ps min, 29.9ps max; typ from 0.001 V to 0.401 V
|   falling waveform, R_fixture 50, V_fixture 1.1: 20-80 % time 53.2ps typ, 65.2ps min, 42.7ps max; typ from 1.1 V to 0.635 V
|   rising waveform, R_fixture 50, V_fixture 1.1: 20-80 % time 53.6ps typ, 56.1ps min, 50.9ps max; typ from 0.635 V to 1.1 V
|   falling waveform, R_fixture 50, V_fixture 0.0: 20-80 % time 34.1ps typ, 41.3ps min, 29.4ps max; typ from 0.402 V to 0.001 V
[Pulldown]
|   Voltage   I(typ)   I(min)   I(max)
-1.1V     -46.55mA   -41.21mA   -52.18mA
-935mV    -40.23mA   -36.52mA   -44.72mA
-720.5mV  -31.32mA   -28.77mA   -34.74mA
-486.2mV  -19.88mA   -17.25mA   -23.37mA
-357.5mV  -12.07mA   -10.3mA    -14.78mA
-255.2mV  -6.8mA     -6.091mA   -8.146mA
-159.5mV  -3.535mA   -3.397mA   -3.777mA
-57.2mV   -1.174mA   -1.161mA   -1.157mA
408.1mV   6.739mA    6.556mA    7.052mA
883.3mV   11.1mA     10.14mA    12.82mA
1.345V    13.04mA    11.79mA    15.49mA
2.2V      15.36mA    13.96mA    18.16mA
[GND Clamp]
|   Voltage   I(typ)   I(min)   I(max)
-1.1V     -34.88mA   -30.34mA   -43.13mA
-1.047V   -31.79mA   -27.25mA   -39.23mA
-938.3mV  -24.92mA   -21.15mA   -31.24mA
-803mV    -16.57mA   -13.55mA   -21.76mA
-671mV    -9.112mA   -6.888mA   -12.56mA
-595.1mV  -5.416mA   -3.908mA   -7.72mA
-525.8mV  -2.773mA   -1.978mA   -3.977mA
-473mV    -1.425mA   -1.032mA   -1.891mA
-416.9mV  -597.4uA   -440.8uA   -665uA
-350.9mV  -166.1uA   -125.6uA   -146.4uA
-261.8mV  -17.7uA    -15.44uA   -10.91uA
2.2V      0A         0A         0A
[Pullup]
|   Voltage   I(typ)   I(min)   I(max)
-1.1V     6.284uA    9.684uA    2.832uA
229.9mV   -45.24uA   -45.95uA   -46.56uA
342.1mV   -380.8uA   -315.5uA   -525.1uA
437.8mV   -1.438mA   -1.179mA   -1.81mA
559.9mV   -4.055mA   -3.762mA   -4.37mA
691.9mV   -7.825mA   -8.065mA   -7.74mA
969.1mV   -16.86mA   -19.06mA   -15.84mA
1.302V    -28.37mA   -32.54mA   -26.58mA
1.599V    -38.35mA   -43.31mA   -36.57mA
1.708V    -41.21mA   -46.19mA   -39.78mA
1.893V    -46.24mA   -49.93mA   -45.68mA
2.2V      -55.46mA   -55.5mA    -57.28mA
[POWER Clamp]
|   Voltage   I(typ)   I(min)   I(max)
-1.1V     3.036mA    3.636mA    2.186mA
-1.041V   2.347mA    2.931mA    1.626mA
-977.9mV  1.724mA    2.242mA    1.161mA
-908.6mV  1.178mA    1.583mA    748.8uA
-849.2mV  799.4uA    1.126mA    535.5uA
-776.6mV  434.2uA    683.5uA    390.2uA
-710.6mV  232.2uA    359.1uA    273.1uA
-657.8mV  146.8uA    178.8uA    190.7uA
-595.1mV  80.77uA    68.32uA    109.2uA
-496.1mV  20.04uA    12.32uA    25.73uA
-383.9mV  1.757uA    1.209uA    1.465uA
2.2V      0A         0A         0A
[Ramp]
|   typ   min   max
| 20% - 80%
dV/dt_r   240.44m/34.52p   227.99m/38.63p   263.51m/29.86p
dV/dt_f   278.92m/53.19p   259.15m/65.20p   312.24m/42.72p
| 25% - 75%
|dV/dt_r   200.37m/27.47p   189.99m/30.75p   219.59m/23.69p
|dV/dt_f   232.44m/42.39p   215.96m/51.99p   260.20m/33.99p
R_load = 50
[Rising Waveform]
R_fixture = 50
V_fixture = 0.0
|   Time   V(typ)   V(min)   V(max)
0s        700.7uV    612.8uV    506.9uV
59ps      883.7uV    -277.5uV   16.78mV
67ps      4.215mV    -540.9uV   73.08mV
79ps      21.23mV    2.48mV     199.9mV
93ps      113.5mV    12.06mV    320.4mV
105ps     214.5mV    48.58mV    379.6mV
123ps     319mV      168.5mV    420.6mV
148ps     379.6mV    302.8mV    436.5mV
178ps     397.7mV    363.1mV    439.4mV
347ps     401.4mV    380.6mV    439.7mV
[Falling Waveform]
R_fixture   = 50
V_fixture   = 1.1
V_fixture_min = 1.06
V_fixture_max = 1.17
|   Time   V(typ)   V(min)   V(max)
0s        1.1V       1.06V      1.17V
73ps      1.098V     1.061V     1.154V
94ps      1.079V     1.055V     982.3mV
116ps     947.7mV    1.042V     811.1mV
133ps     841.3mV    982.5mV    735.1mV
154ps     748.3mV    876.7mV    687.5mV
187ps     675.7mV    747.4mV    660.1mV
224ps     647.6mV    674.3mV    652.1mV
272ps     637.7mV    639.8mV    650mV
347ps     635.1mV    628.1mV    649.6mV
[Rising Waveform]
R_fixture   = 50
V_fixture   = 1.1
V_fixture_min = 1.06
V_fixture_max = 1.17
|   Time   V(typ)   V(min)   V(max)
0s        634.8mV    625.9mV    649.6mV
53ps      630.6mV    622.4mV    658.3mV
63ps      639.3mV    618.8mV    704.4mV
76ps      696.5mV    631.1mV    832.2mV
90ps      809.7mV    693.9mV    940.8mV
107ps     914.1mV    811.6mV    1.025V
124ps     979.7mV    898.6mV    1.078V
145ps     1.029V     963.7mV    1.118V
212ps     1.087V     1.041V     1.161V
347ps     1.099V     1.059V     1.17V
[Falling Waveform]
R_fixture = 50
V_fixture = 0.0
|   Time   V(typ)   V(min)   V(max)
0s        401.6mV    380.8mV    439.8mV
56ps      408.5mV    382.1mV    443.2mV
73ps      402.3mV    394.1mV    337.1mV
85ps      342.4mV    388.1mV    194.3mV
95ps      260.3mV    354.5mV    118.5mV
110ps     138.4mV    264.8mV    57.25mV
126ps     67.16mV    164.4mV    26.79mV
149ps     24.35mV    64.84mV    9.335mV
179ps     7.034mV    18.35mV    2.702mV
347ps     759.6uV    719.9uV    528.5uV
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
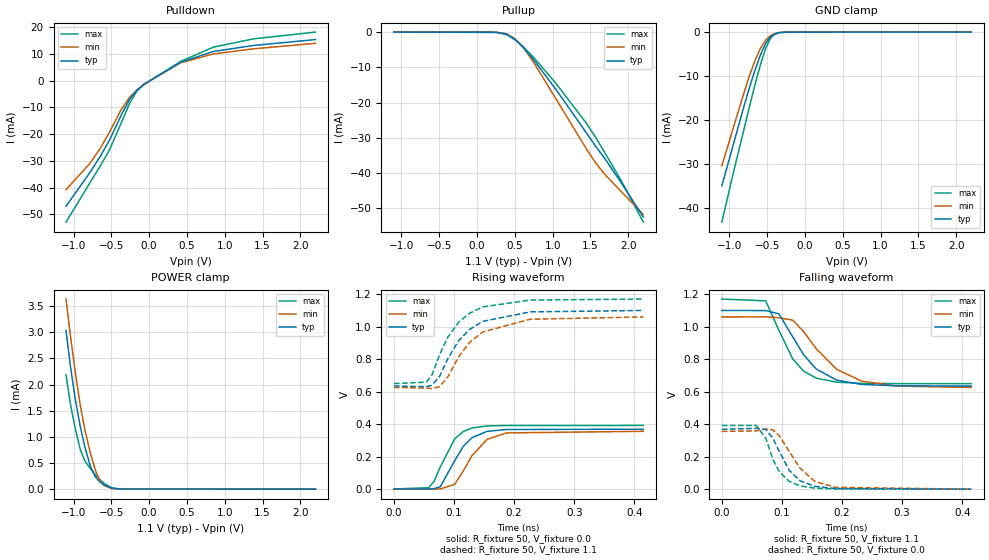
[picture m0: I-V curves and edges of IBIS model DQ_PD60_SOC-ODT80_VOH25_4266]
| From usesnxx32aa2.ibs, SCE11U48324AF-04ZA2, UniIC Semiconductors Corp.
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| DQ_PD60_SOC-ODT80_VOH25_4266
| (60 Ohm Pulldown, 80 Ohm System ODT Setting, VOH=VDDQ/2.5, 3200-4266Mbps)
[Model]   DQ_PD60_SOC-ODT80_VOH25_4266
Model_type   I/O
Vinl = 160.000mV
Vinh = 280.000mV
Vmeas = 220.000mV
Vref = 0.0mV
Cref = 0.0pF
Rref = 80.000Ohm
|   typ   min   max
|C_comp   0.797pF   0.747pF   0.847pF
C_comp_pullup   0.3985pF   0.3735pF   0.4235pF
C_comp_pulldown   0.3985pF   0.3735pF   0.4235pF
| Note: C_comp changes when the ODT circuit is enabled.
[Model Spec]
| Input threshold voltage corners
Vinl   0.1600V   0.1520V   0.1740V
Vinh   0.2800V   0.2720V   0.2940V
| Measurement voltage corners
Vmeas   0.2200V   0.2120V   0.2340V
| Timing spec test load voltage corners
Vref   0.0000V   0.0000V   0.0000V
| Dynamic Overshoot Parameters from LPDDR4 Specification
D_overshoot_ampl_h   0.30   NA   NA
D_overshoot_ampl_l   0.30   NA   NA
D_overshoot_area_h   0.1n   NA   NA
D_overshoot_area_l   0.1n   NA   NA
[Receiver Thresholds]
Vth   = 0.2200V
Vth_min  = 0.2167V
Vth_max  = 0.2233V
Vinh_ac  = 0.060V
Vinh_dc  = 0.060V
Vinl_ac  = -0.060V
Vinl_dc  = -0.060V
Tslew_ac = 5.000ns |Not specified, so set to high value
Threshold_sensitivity = 0.2000
Reference_supply Pullup_ref
[Voltage Range]   1.1000V   1.0600V   1.1700V
[Pullup Reference]   1.1000V   1.0600V   1.1700V
| Junction Temperature (Ambient temp is 35C typ 95C min -40C max)
[Temperature Range]   50.0   110.0   -40.0
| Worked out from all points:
|   slope of the pulldown table from 0 to 0.165 V, typ, clamps not added: 54.7 ohm
|   slope of the pullup table from 0 to 0.165 V, typ, clamps not added: 16.4 kohm
|   GND clamp passes 1 mA (typ) near -0.45 V on its own axis
|   POWER clamp passes 1 mA (typ) near -0.88 V on its own axis
|   rising waveform, R_fixture 50, V_fixture 0.0: 20-80 % time 34.5ps typ, 38.2ps min, 31.3ps max; typ from 0.001 V to 0.369 V
|   falling waveform, R_fixture 50, V_fixture 1.1: 20-80 % time 53.1ps typ, 65.9ps min, 42.5ps max; typ from 1.1 V to 0.635 V
|   rising waveform, R_fixture 50, V_fixture 1.1: 20-80 % time 54.5ps typ, 57.4ps min, 50.7ps max; typ from 0.635 V to 1.1 V
|   falling waveform, R_fixture 50, V_fixture 0.0: 20-80 % time 34.4ps typ, 41.3ps min, 29ps max; typ from 0.369 V to 0.001 V
[Pulldown]
|   Voltage   I(typ)   I(min)   I(max)
-1.1V     -46.99mA   -40.8mA    -52.96mA
-786.5mV  -34.49mA   -31.05mA   -38.36mA
-641.3mV  -28.08mA   -25.11mA   -31.66mA
-525.8mV  -22.32mA   -19.3mA    -25.97mA
-367.4mV  -12.77mA   -10.72mA   -15.73mA
-258.5mV  -6.989mA   -6.176mA   -8.45mA
-162.8mV  -3.638mA   -3.468mA   -3.924mA
-63.8mV   -1.314mA   -1.293mA   -1.298mA
414.7mV   6.826mA    6.638mA    7.153mA
847mV     10.89mA    9.975mA    12.5mA
1.375V    13.14mA    11.88mA    15.61mA
2.2V      15.36mA    13.96mA    18.16mA
[GND Clamp]
|   Voltage   I(typ)   I(min)   I(max)
-1.1V     -34.89mA   -30.34mA   -43.14mA
-935mV    -24.72mA   -20.96mA   -31.01mA
-803mV    -16.58mA   -13.55mA   -21.77mA
-733.7mV  -12.55mA   -9.876mA   -16.88mA
-667.7mV  -8.943mA   -6.74mA    -12.35mA
-591.8mV  -5.274mA   -3.797mA   -7.53mA
-519.2mV  -2.572mA   -1.835mA   -3.676mA
-463.1mV  -1.239mA   -899.6uA   -1.602mA
-410.3mV  -534.6uA   -395.8uA   -582.2uA
-341mV    -134.1uA   -102.7uA   -114.3uA
-242mV    -10.14uA   -9.274uA   -5.696uA
2.2V      0A         0A         0A
[Pullup]
|   Voltage   I(typ)   I(min)   I(max)
-1.1V     4.112uA    7.441uA    1.363uA
259.6mV   -60.64uA   -60.03uA   -61.53uA
388.3mV   -576.1uA   -480.7uA   -688.2uA
500.5mV   -2.042mA   -1.831mA   -2.144mA
609.4mV   -4.304mA   -4.305mA   -4.133mA
731.5mV   -7.378mA   -7.995mA   -6.76mA
1.045V    -16.3mA    -18.97mA   -14.58mA
1.448V    -28.62mA   -33.18mA   -25.89mA
1.573V    -32.49mA   -37.21mA   -29.99mA
1.695V    -36.01mA   -40.47mA   -34.38mA
1.91V     -42.82mA   -45.28mA   -42.24mA
2.2V      -52.46mA   -51.74mA   -53.91mA
[POWER Clamp]
|   Voltage   I(typ)   I(min)   I(max)
-1.1V     3.036mA    3.636mA    2.186mA
-1.041V   2.347mA    2.931mA    1.626mA
-981.2mV  1.754mA    2.277mA    1.183mA
-911.9mV  1.201mA    1.611mA    764.7uA
-852.5mV  818.9uA    1.149mA    543.6uA
-776.6mV  434.4uA    683.5uA    390.2uA
-710.6mV  232.2uA    359.1uA    273.1uA
-657.8mV  146.8uA    178.8uA    190.7uA
-595.1mV  80.84uA    68.31uA    109.3uA
-492.8mV  18.88uA    11.58uA    24.06uA
-380.6mV  1.613uA    1.137uA    1.355uA
2.2V      0A         0A         0A
[Ramp]
|   typ   min   max
| 20% - 80%
dV/dt_r   220.76m/34.45p   213.10m/38.18p   234.84m/31.31p
dV/dt_f   279.06m/53.10p   260.18m/65.93p   312.25m/42.55p
| 25% - 75%
|dV/dt_r   183.97m/27.42p   177.58m/30.41p   195.70m/24.82p
|dV/dt_f   232.55m/42.27p   216.82m/52.42p   260.21m/33.82p
R_load = 50
[Rising Waveform]
R_fixture = 50
V_fixture = 0.0
|   Time   V(typ)   V(min)   V(max)
0s        726.5uV    592.8uV    533uV
58ps      587.8uV    -78.52uV   8.289mV
67ps      3.282mV    -514.6uV   48.79mV
77ps      14.06mV    1.164mV    135mV
101ps     173.3mV    28.69mV    308.2mV
115ps     261.3mV    108.9mV    353.3mV
130ps     316.9mV    206.7mV    376.1mV
155ps     355.3mV    305.8mV    388.8mV
187ps     366.8mV    345.9mV    391.6mV
415ps     368.7mV    355.8mV    391.9mV
[Falling Waveform]
R_fixture   = 50
V_fixture   = 1.1
V_fixture_min = 1.06
V_fixture_max = 1.17
|   Time   V(typ)   V(min)   V(max)
0s        1.1V       1.06V      1.17V
73ps      1.099V     1.061V     1.159V
95ps      1.079V     1.055V     976.9mV
118ps     937.6mV    1.04V      801.6mV
136ps     827.5mV    970.3mV    726.7mV
157ps     739.9mV    864.5mV    683.6mV
191ps     671.3mV    737.7mV    658.6mV
233ps     644.6mV    664.8mV    651.4mV
291ps     636.5mV    634.5mV    649.8mV
415ps     634.9mV    626.4mV    649.6mV
[Rising Waveform]
R_fixture   = 50
V_fixture   = 1.1
V_fixture_min = 1.06
V_fixture_max = 1.17
|   Time   V(typ)   V(min)   V(max)
0s        634.8mV    625.9mV    649.6mV
54ps      630.8mV    622.1mV    658.5mV
63ps      638.8mV    618.9mV    700mV
76ps      694.2mV    630.8mV    827.5mV
90ps      805.9mV    692.7mV    937.6mV
108ps     915.3mV    815.8mV    1.028V
126ps     983.1mV    903.7mV    1.083V
148ps     1.033V     967.9mV    1.122V
227ps     1.091V     1.046V     1.164V
415ps     1.1V       1.06V      1.17V
[Falling Waveform]
R_fixture = 50
V_fixture = 0.0
|   Time   V(typ)   V(min)   V(max)
0s        368.8mV    355.9mV    392mV
57ps      374.7mV    359.2mV    392.6mV
73ps      368.3mV    370.8mV    315.2mV
85ps      313.9mV    365.4mV    183.1mV
96ps      230.2mV    327.7mV    106.3mV
112ps     116.8mV    233.1mV    49.02mV
130ps     52.26mV    130.3mV    20.92mV
155ps     17.58mV    47.19mV    6.762mV
190ps     4.405mV    11.53mV    1.759mV
415ps     771.1uV    658.5uV    552uV
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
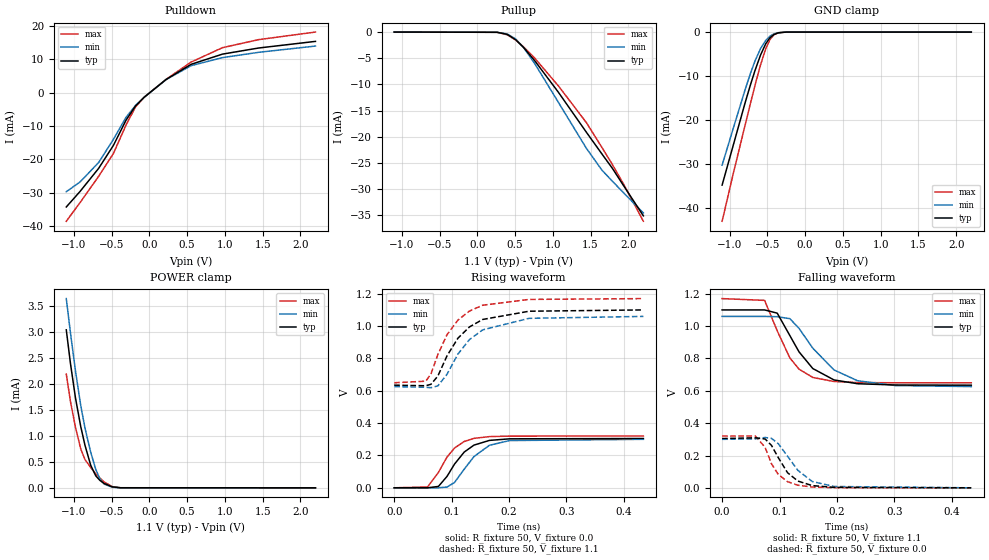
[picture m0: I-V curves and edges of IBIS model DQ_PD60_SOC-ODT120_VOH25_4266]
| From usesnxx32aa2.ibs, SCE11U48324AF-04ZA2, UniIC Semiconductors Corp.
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| DQ_PD60_SOC-ODT120_VOH25_4266
| (60 Ohm Pulldown, 120 Ohm System ODT Setting, VOH=VDDQ/2.5, 3200-4266Mbps)
[Model]   DQ_PD60_SOC-ODT120_VOH25_4266
Model_type   I/O
Vinl = 160.000mV
Vinh = 280.000mV
Vmeas = 220.000mV
Vref = 0.0mV
Cref = 0.0pF
Rref = 120.000Ohm
|   typ   min   max
|C_comp   0.797pF   0.747pF   0.847pF
C_comp_pullup   0.3985pF   0.3735pF   0.4235pF
C_comp_pulldown   0.3985pF   0.3735pF   0.4235pF
| Note: C_comp changes when the ODT circuit is enabled.
[Model Spec]
| Input threshold voltage corners
Vinl   0.1600V   0.1520V   0.1740V
Vinh   0.2800V   0.2720V   0.2940V
| Measurement voltage corners
Vmeas   0.2200V   0.2120V   0.2340V
| Timing spec test load voltage corners
Vref   0.0000V   0.0000V   0.0000V
| Dynamic Overshoot Parameters from LPDDR4 Specification
D_overshoot_ampl_h   0.30   NA   NA
D_overshoot_ampl_l   0.30   NA   NA
D_overshoot_area_h   0.1n   NA   NA
D_overshoot_area_l   0.1n   NA   NA
[Receiver Thresholds]
Vth   = 0.2200V
Vth_min  = 0.2167V
Vth_max  = 0.2233V
Vinh_ac  = 0.060V
Vinh_dc  = 0.060V
Vinl_ac  = -0.060V
Vinl_dc  = -0.060V
Tslew_ac = 5.000ns |Not specified, so set to high value
Threshold_sensitivity = 0.2000
Reference_supply Pullup_ref
[Voltage Range]   1.1000V   1.0600V   1.1700V
[Pullup Reference]   1.1000V   1.0600V   1.1700V
| Junction Temperature (Ambient temp is 35C typ 95C min -40C max)
[Temperature Range]   50.0   110.0   -40.0
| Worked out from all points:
|   slope of the pulldown table from 0 to 0.165 V, typ, clamps not added: 54.8 ohm
|   slope of the pullup table from 0 to 0.165 V, typ, clamps not added: 26.3 kohm
|   GND clamp passes 1 mA (typ) near -0.45 V on its own axis
|   POWER clamp passes 1 mA (typ) near -0.88 V on its own axis
|   rising waveform, R_fixture 50, V_fixture 0.0: 20-80 % time 39.4ps typ, 42.9ps min, 35.8ps max; typ from 0 V to 0.305 V
|   falling waveform, R_fixture 50, V_fixture 1.1: 20-80 % time 52.7ps typ, 65.3ps min, 42.3ps max; typ from 1.1 V to 0.635 V
|   rising waveform, R_fixture 50, V_fixture 1.1: 20-80 % time 55ps typ, 58.6ps min, 50.7ps max; typ from 0.635 V to 1.1 V
|   falling waveform, R_fixture 50, V_fixture 0.0: 20-80 % time 34.1ps typ, 41.5ps min, 29ps max; typ from 0.305 V to 0.001 V
[Pulldown]
|   Voltage   I(typ)   I(min)   I(max)
-1.1V     -34.25mA   -29.68mA   -38.53mA
-918.5mV  -29.62mA   -26.77mA   -32.96mA
-671mV    -22.66mA   -20.92mA   -25.05mA
-476.3mV  -15.81mA   -14mA      -18.23mA
-308mV    -8.225mA   -7.355mA   -9.672mA
-182.6mV  -3.974mA   -3.823mA   -4.259mA
-67.1mV   -1.349mA   -1.337mA   -1.333mA
223.3mV   3.974mA    3.926mA    4.026mA
553.3mV   8.488mA    8.09mA     9.162mA
969.1mV   11.55mA    10.5mA     13.48mA
1.448V    13.38mA    12.09mA    15.89mA
2.2V      15.36mA    13.96mA    18.16mA
[GND Clamp]
|   Voltage   I(typ)   I(min)   I(max)
-1.1V     -34.89mA   -30.35mA   -43.14mA
-944.9mV  -25.34mA   -21.52mA   -31.72mA
-793.1mV  -15.99mA   -13.01mA   -21.07mA
-723.8mV  -11.98mA   -9.378mA   -16.19mA
-664.4mV  -8.772mA   -6.596mA   -12.13mA
-591.8mV  -5.274mA   -3.797mA   -7.531mA
-522.5mV  -2.671mA   -1.905mA   -3.825mA
-466.4mV  -1.297mA   -942.2uA   -1.694mA
-413.6mV  -565.5uA   -417.2uA   -621.5uA
-357.5mV  -191.9uA   -144.5uA   -174.1uA
-258.5mV  -16.12uA   -14.14uA   -9.884uA
2.2V      0A         0A         0A
[Pullup]
|   Voltage   I(typ)   I(min)   I(max)
-1.1V     2.741uA    4.96uA     908.5nA
262.9mV   -43.02uA   -42.45uA   -44.32uA
398.2mV   -442.3uA   -366.6uA   -523.4uA
510.4mV   -1.485mA   -1.346mA   -1.542mA
616mV     -2.987mA   -3.007mA   -2.855mA
761.2mV   -5.48mA    -6.027mA   -4.984mA
1.075V    -11.52mA   -13.45mA   -10.3mA
1.444V    -19.13mA   -22.2mA    -17.29mA
1.652V    -23.33mA   -26.42mA   -22.08mA
1.788V    -26.02mA   -28.49mA   -25.29mA
1.933V    -29.26mA   -30.67mA   -28.95mA
2.2V      -35.14mA   -34.59mA   -36.18mA
[POWER Clamp]
|   Voltage   I(typ)   I(min)   I(max)
-1.1V     3.036mA    3.636mA    2.186mA
-1.044V   2.383mA    2.97mA     1.654mA
-977.9mV  1.724mA    2.243mA    1.161mA
-908.6mV  1.178mA    1.583mA    747.6uA
-852.5mV  818.6uA    1.149mA    544uA
-776.6mV  434.2uA    683.6uA    390.2uA
-710.6mV  232.2uA    359.1uA    273.1uA
-654.5mV  142.7uA    170.4uA    185.9uA
-598.4mV  83.68uA    71.96uA    113.1uA
-492.8mV  18.87uA    11.55uA    24.07uA
-383.9mV  1.745uA    1.209uA    1.464uA
2.2V      0A         0A         0A
[Ramp]
|   typ   min   max
| 20% - 80%
dV/dt_r   182.69m/39.36p   179.75m/42.90p   191.97m/35.84p
dV/dt_f   279.07m/52.72p   260.27m/65.27p   312.24m/42.30p
| 25% - 75%
|dV/dt_r   152.25m/31.32p   149.79m/34.15p   159.97m/28.47p
|dV/dt_f   232.56m/42.02p   216.90m/52.06p   260.20m/33.68p
R_load = 50
[Rising Waveform]
R_fixture = 50
V_fixture = 0.0
|   Time   V(typ)   V(min)   V(max)
0s        479.9uV    385.1uV    354.3uV
58ps      316.8uV    31.9uV     5.381mV
77ps      8.68mV     368.1uV    95.14mV
92ps      70.76mV    4.863mV    190.5mV
105ps     146.6mV    32.95mV    246.1mV
122ps     221.4mV    115.6mV    286.7mV
139ps     264.3mV    193.6mV    305.9mV
166ps     293.4mV    263.3mV    316.8mV
201ps     303mV      292.4mV    319.8mV
434ps     305mV      300mV      320.3mV
[Falling Waveform]
R_fixture   = 50
V_fixture   = 1.1
V_fixture_min = 1.06
V_fixture_max = 1.17
|   Time   V(typ)   V(min)   V(max)
0s        1.1V       1.06V      1.17V
74ps      1.1V       1.06V      1.159V
96ps      1.08V      1.058V     970.9mV
118ps     941.3mV    1.046V     803.3mV
134ps     840.6mV    985.8mV    733.6mV
158ps     737.6mV    863.3mV    682.6mV
195ps     667.1mV    728.8mV    657.5mV
236ps     643.8mV    662.3mV    651.2mV
302ps     636mV      632.5mV    649.7mV
434ps     634.9mV    626.2mV    649.6mV
[Rising Waveform]
R_fixture   = 50
V_fixture   = 1.1
V_fixture_min = 1.06
V_fixture_max = 1.17
|   Time   V(typ)   V(min)   V(max)
0s        634.8mV    625.9mV    649.6mV
55ps      631.2mV    621.8mV    659.4mV
64ps      640.1mV    619.2mV    704.4mV
76ps      690.9mV    630.4mV    823.5mV
92ps      816.3mV    702mV      947mV
111ps     925.3mV    827.3mV    1.037V
131ps     994.6mV    916.2mV    1.093V
154ps     1.041V     976.6mV    1.129V
235ps     1.092V     1.048V     1.165V
434ps     1.1V       1.06V      1.17V
[Falling Waveform]
R_fixture = 50
V_fixture = 0.0
|   Time   V(typ)   V(min)   V(max)
0s        305.1mV    300.1mV    320.4mV
58ps      309.6mV    303.1mV    320.4mV
75ps      302mV      311.6mV    249.8mV
86ps      262.6mV    306.2mV    148.8mV
98ps      186mV      272.7mV    82.6mV
114ps     93.67mV    195.8mV    38.46mV
132ps     42.11mV    108.1mV    16.44mV
157ps     14.26mV    39.5mV     5.303mV
195ps     3.157mV    8.693mV    1.239mV
434ps     542.8uV    470.3uV    379.3uV
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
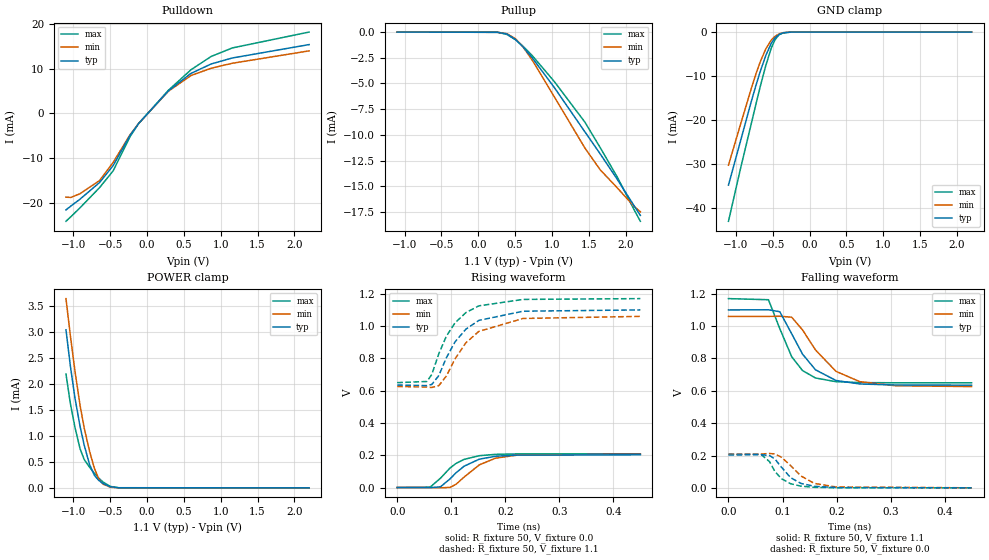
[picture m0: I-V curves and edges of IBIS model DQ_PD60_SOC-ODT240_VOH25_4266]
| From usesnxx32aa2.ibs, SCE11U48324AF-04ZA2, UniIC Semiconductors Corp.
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| DQ_PD60_SOC-ODT240_VOH25_4266
| (60 Ohm Pulldown, 240 Ohm System ODT Setting, VOH=VDDQ/2.5, 3200-4266Mbps)
[Model]   DQ_PD60_SOC-ODT240_VOH25_4266
Model_type   I/O
Vinl = 160.000mV
Vinh = 280.000mV
Vmeas = 220.000mV
Vref = 0.0mV
Cref = 0.0pF
Rref = 240.000Ohm
|   typ   min   max
|C_comp   0.797pF   0.747pF   0.847pF
C_comp_pullup   0.3985pF   0.3735pF   0.4235pF
C_comp_pulldown   0.3985pF   0.3735pF   0.4235pF
| Note: C_comp changes when the ODT circuit is enabled.
[Model Spec]
| Input threshold voltage corners
Vinl   0.1600V   0.1520V   0.1740V
Vinh   0.2800V   0.2720V   0.2940V
| Measurement voltage corners
Vmeas   0.2200V   0.2120V   0.2340V
| Timing spec test load voltage corners
Vref   0.0000V   0.0000V   0.0000V
| Dynamic Overshoot Parameters from LPDDR4 Specification
D_overshoot_ampl_h   0.30   NA   NA
D_overshoot_ampl_l   0.30   NA   NA
D_overshoot_area_h   0.1n   NA   NA
D_overshoot_area_l   0.1n   NA   NA
[Receiver Thresholds]
Vth   = 0.2200V
Vth_min  = 0.2167V
Vth_max  = 0.2233V
Vinh_ac  = 0.060V
Vinh_dc  = 0.060V
Vinl_ac  = -0.060V
Vinl_dc  = -0.060V
Tslew_ac = 5.000ns |Not specified, so set to high value
Threshold_sensitivity = 0.2000
Reference_supply Pullup_ref
[Voltage Range]   1.1000V   1.0600V   1.1700V
[Pullup Reference]   1.1000V   1.0600V   1.1700V
| Junction Temperature (Ambient temp is 35C typ 95C min -40C max)
[Temperature Range]   50.0   110.0   -40.0
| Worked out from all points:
|   slope of the pulldown table from 0 to 0.165 V, typ, clamps not added: 55 ohm
|   slope of the pullup table from 0 to 0.165 V, typ, clamps not added: 53.3 kohm
|   GND clamp passes 1 mA (typ) near -0.45 V on its own axis
|   POWER clamp passes 1 mA (typ) near -0.88 V on its own axis
|   rising waveform, R_fixture 50, V_fixture 0.0: 20-80 % time 46.5ps typ, 50.4ps min, 42.8ps max; typ from 0 V to 0.203 V
|   falling waveform, R_fixture 50, V_fixture 1.1: 20-80 % time 52.4ps typ, 64.7ps min, 42.1ps max; typ from 1.1 V to 0.635 V
|   rising waveform, R_fixture 50, V_fixture 1.1: 20-80 % time 55.4ps typ, 59.6ps min, 50.9ps max; typ from 0.635 V to 1.1 V
|   falling waveform, R_fixture 50, V_fixture 0.0: 20-80 % time 34.5ps typ, 42.2ps min, 29.4ps max; typ from 0.203 V to 0 V
[Pulldown]
|   Voltage   I(typ)   I(min)   I(max)
-1.1V     -21.54mA   -18.69mA   -24.07mA
-1.034V   -20.67mA   -18.75mA   -23.06mA
-911.9mV  -19.17mA   -17.94mA   -21.1mA
-644.6mV  -15.43mA   -14.99mA   -16.57mA
-459.8mV  -11.65mA   -10.95mA   -12.81mA
-232.1mV  -4.935mA   -4.797mA   -5.245mA
-113.3mV  -2.244mA   -2.239mA   -2.234mA
289.3mV   5.026mA    4.942mA    5.144mA
596.2mV   8.931mA    8.451mA    9.734mA
870.1mV   11.03mA    10.08mA    12.71mA
1.157V    12.37mA    11.19mA    14.61mA
2.2V      15.36mA    13.96mA    18.16mA
[GND Clamp]
|   Voltage   I(typ)   I(min)   I(max)
-1.1V     -34.89mA   -30.35mA   -43.14mA
-941.6mV  -25.14mA   -21.33mA   -31.48mA
-793.1mV  -15.99mA   -13.01mA   -21.07mA
-723.8mV  -11.98mA   -9.379mA   -16.19mA
-664.4mV  -8.771mA   -6.596mA   -12.13mA
-591.8mV  -5.273mA   -3.797mA   -7.531mA
-519.2mV  -2.573mA   -1.835mA   -3.675mA
-469.7mV  -1.358mA   -990.4uA   -1.792mA
-413.6mV  -564.1uA   -419.8uA   -621.1uA
-354.2mV  -178.9uA   -136.7uA   -159.7uA
-245.3mV  -11.05uA   -10.31uA   -6.361uA
2.2V      0A         0A         0A
[Pullup]
|   Voltage   I(typ)   I(min)   I(max)
-1.1V     1.371uA    2.481uA    454.5nA
266.2mV   -23.11uA   -22.31uA   -23.98uA
388.3mV   -192.7uA   -159.9uA   -230.6uA
503.8mV   -707.5uA   -637uA     -739.2uA
602.8mV   -1.402mA   -1.398mA   -1.348mA
734.8mV   -2.527mA   -2.755mA   -2.306mA
1.032V    -5.393mA   -6.298mA   -4.813mA
1.448V    -9.715mA   -11.29mA   -8.771mA
1.655V    -11.85mA   -13.4mA    -11.24mA
1.887V    -14.33mA   -15.16mA   -14.11mA
2.114V    -16.89mA   -16.95mA   -17.27mA
2.2V      -17.84mA   -17.49mA   -18.41mA
[POWER Clamp]
|   Voltage   I(typ)   I(min)   I(max)
-1.1V     3.036mA    3.636mA    2.186mA
-1.041V   2.347mA    2.931mA    1.626mA
-977.9mV  1.724mA    2.242mA    1.161mA
-908.6mV  1.178mA    1.583mA    748.7uA
-852.5mV  818.6uA    1.149mA    543.7uA
-779.9mV  448.2uA    701.7uA    396.3uA
-713.9mV  239.2uA    373.3uA    278.6uA
-657.8mV  146.8uA    178.8uA    190.7uA
-598.4mV  83.72uA    71.96uA    113.1uA
-499.4mV  21.32uA    13.27uA    27.46uA
-387.2mV  1.89uA     1.309uA    1.609uA
2.2V      0A         0A         0A
[Ramp]
|   typ   min   max
| 20% - 80%
dV/dt_r   121.58m/46.47p   123.88m/50.45p   125.36m/42.78p
dV/dt_f   279.06m/52.42p   260.32m/64.73p   312.24m/42.13p
| 25% - 75%
|dV/dt_r   101.31m/36.94p   103.24m/40.28p   104.47m/33.94p
|dV/dt_f   232.55m/41.79p   216.93m/51.57p   260.20m/33.57p
R_load = 50
[Rising Waveform]
R_fixture = 50
V_fixture = 0.0
|   Time   V(typ)   V(min)   V(max)
0s        230.6uV    174uV      174.1uV
61ps      -603.8uV   18.1uV     2.878mV
80ps      4.453mV    -1.756mV   57.6mV
98ps      54.56mV    1.247mV    121.9mV
109ps     91.95mV    20.6mV     149.6mV
124ps     132.7mV    65.63mV    174.7mV
152ps     175.8mV    140.6mV    197.3mV
182ps     193.8mV    181.9mV    205.5mV
223ps     201mV      201.2mV    208.4mV
450ps     202.9mV    206.6mV    209.1mV
[Falling Waveform]
R_fixture   = 50
V_fixture   = 1.1
V_fixture_min = 1.06
V_fixture_max = 1.17
|   Time   V(typ)   V(min)   V(max)
0s        1.1V       1.06V      1.17V
74ps      1.101V     1.06V      1.163V
95ps      1.089V     1.061V     984.2mV
117ps     952.5mV    1.055V     810.8mV
137ps     827.1mV    976.7mV    725.3mV
161ps     729.9mV    852.8mV    679.3mV
199ps     663.8mV    720.4mV    656.4mV
243ps     642.2mV    656.6mV    650.8mV
309ps     635.9mV    631.5mV    649.7mV
450ps     634.9mV    626.1mV    649.6mV
[Rising Waveform]
R_fixture   = 50
V_fixture   = 1.1
V_fixture_min = 1.06
V_fixture_max = 1.17
|   Time   V(typ)   V(min)   V(max)
0s        634.8mV    625.9mV    649.6mV
55ps      631.2mV    622.2mV    656.9mV
64ps      638.5mV    619.5mV    700.2mV
77ps      693.5mV    631.1mV    828.9mV
91ps      803.9mV    690.9mV    937.4mV
107ps     902.4mV    796.8mV    1.02V
127ps     980.6mV    896mV      1.083V
151ps     1.035V     966.9mV    1.125V
233ps     1.092V     1.047V     1.165V
450ps     1.1V       1.06V      1.17V
[Falling Waveform]
R_fixture = 50
V_fixture = 0.0
|   Time   V(typ)   V(min)   V(max)
0s        202.9mV    206.7mV    209.2mV
60ps      205.4mV    208.8mV    208mV
76ps      199.8mV    212.8mV    161.9mV
86ps      178.2mV    209.4mV    101.2mV
98ps      128.1mV    189.6mV    56.91mV
115ps     62.97mV    137.7mV    25.59mV
134ps     27.64mV    73.88mV    10.6mV
159ps     9.532mV    27.58mV    3.45mV
199ps     1.99mV     5.763mV    718.8uV
450ps     297.6uV    267.5uV    196.9uV
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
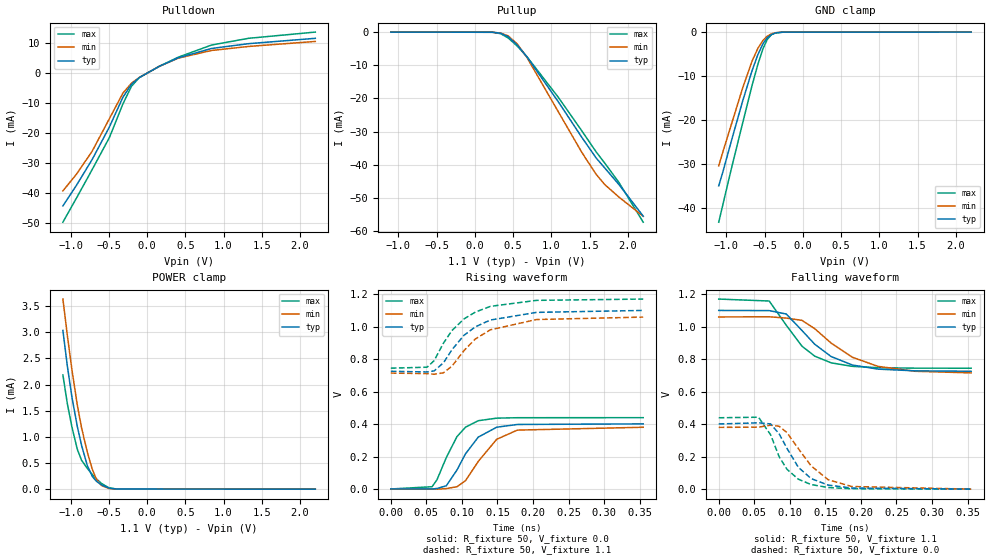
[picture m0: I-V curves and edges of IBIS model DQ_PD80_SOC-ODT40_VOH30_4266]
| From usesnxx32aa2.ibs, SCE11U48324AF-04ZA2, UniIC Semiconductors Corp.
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| DQ_PD80_SOC-ODT40_VOH30_4266
| (80 Ohm Pulldown, 40 Ohm System ODT Setting, VOH=VDDQ/3.0, 3200-4266Mbps)
[Model]   DQ_PD80_SOC-ODT40_VOH30_4266
Model_type   I/O
Vinl = 123.333mV
Vinh = 243.333mV
Vmeas = 183.333mV
Vref = 0.0mV
Cref = 0.0pF
Rref = 40.000Ohm
|   typ   min   max
|C_comp   0.797pF   0.747pF   0.847pF
C_comp_pullup   0.3985pF   0.3735pF   0.4235pF
C_comp_pulldown   0.3985pF   0.3735pF   0.4235pF
| Note: C_comp changes when the ODT circuit is enabled.
[Model Spec]
| Input threshold voltage corners
Vinl   0.1233V   0.1167V   0.1350V
Vinh   0.2433V   0.2367V   0.2550V
| Measurement voltage corners
Vmeas   0.1833V   0.1767V   0.1950V
| Timing spec test load voltage corners
Vref   0.0000V   0.0000V   0.0000V
| Dynamic Overshoot Parameters from LPDDR4 Specification
D_overshoot_ampl_h   0.30   NA   NA
D_overshoot_ampl_l   0.30   NA   NA
D_overshoot_area_h   0.1n   NA   NA
D_overshoot_area_l   0.1n   NA   NA
[Receiver Thresholds]
Vth   = 0.1833V
Vth_min  = 0.1800V
Vth_max  = 0.1866V
Vinh_ac  = 0.060V
Vinh_dc  = 0.060V
Vinl_ac  = -0.060V
Vinl_dc  = -0.060V
Tslew_ac = 5.000ns |Not specified, so set to high value
Threshold_sensitivity = 0.1667
Reference_supply Pullup_ref
[Voltage Range]   1.1000V   1.0600V   1.1700V
[Pullup Reference]   1.1000V   1.0600V   1.1700V
| Junction Temperature (Ambient temp is 35C typ 95C min -40C max)
[Temperature Range]   50.0   110.0   -40.0
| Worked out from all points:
|   slope of the pulldown table from 0 to 0.165 V, typ, clamps not added: 73.8 ohm
|   slope of the pullup table from 0 to 0.165 V, typ, clamps not added: 13 kohm
|   GND clamp passes 1 mA (typ) near -0.45 V on its own axis
|   POWER clamp passes 1 mA (typ) near -0.88 V on its own axis
|   rising waveform, R_fixture 50, V_fixture 0.0: 20-80 % time 34.7ps typ, 39ps min, 29.9ps max; typ from 0.001 V to 0.401 V
|   falling waveform, R_fixture 50, V_fixture 1.1: 20-80 % time 57.3ps typ, 68ps min, 46.6ps max; typ from 1.1 V to 0.726 V
|   rising waveform, R_fixture 50, V_fixture 1.1: 20-80 % time 52.9ps typ, 54ps min, 50.4ps max; typ from 0.725 V to 1.1 V
|   falling waveform, R_fixture 50, V_fixture 0.0: 20-80 % time 37.1ps typ, 43.4ps min, 32.2ps max; typ from 0.402 V to 0.001 V
[Pulldown]
|   Voltage   I(typ)   I(min)   I(max)
-1.1V     -44.43mA   -39.42mA   -49.86mA
-921.8mV  -37.52mA   -33.82mA   -41.78mA
-717.2mV  -28.93mA   -26.17mA   -32.3mA
-492.8mV  -18.13mA   -15.35mA   -21.65mA
-314.6mV  -8.133mA   -6.758mA   -10.35mA
-202.4mV  -3.803mA   -3.466mA   -4.465mA
-100.1mV  -1.589mA   -1.549mA   -1.61mA
160.6mV   2.153mA    2.137mA    2.157mA
411.4mV   5.021mA    4.895mA    5.234mA
843.7mV   8.104mA    7.438mA    9.251mA
1.329V    9.708mA    8.779mA    11.5mA
2.2V      11.49mA    10.45mA    13.57mA
[GND Clamp]
|   Voltage   I(typ)   I(min)   I(max)
-1.1V     -34.88mA   -30.35mA   -43.13mA
-1.047V   -31.79mA   -27.25mA   -39.23mA
-938.3mV  -24.92mA   -21.15mA   -31.24mA
-786.5mV  -15.59mA   -12.65mA   -20.59mA
-664.4mV  -8.768mA   -6.598mA   -12.12mA
-588.5mV  -5.129mA   -3.689mA   -7.328mA
-522.5mV  -2.677mA   -1.906mA   -3.822mA
-466.4mV  -1.302mA   -943.2uA   -1.695mA
-413.6mV  -567.6uA   -419.6uA   -620.4uA
-357.5mV  -191.9uA   -146.1uA   -173.2uA
-255.2mV  -14.58uA   -13.27uA   -8.748uA
2.2V      0A         0A         0A
[Pullup]
|   Voltage   I(typ)   I(min)   I(max)
-1.1V     6.284uA    9.684uA    2.833uA
229.9mV   -45.24uA   -45.98uA   -46.7uA
335.5mV   -340.6uA   -284.5uA   -469uA
434.5mV   -1.385mA   -1.133mA   -1.752mA
553.3mV   -3.885mA   -3.581mA   -4.215mA
678.7mV   -7.423mA   -7.588mA   -7.385mA
1.091V    -21.03mA   -24.05mA   -19.68mA
1.398V    -31.73mA   -36.27mA   -29.78mA
1.586V    -37.97mA   -42.9mA    -36.14mA
1.698V    -40.96mA   -45.96mA   -39.5mA
1.88V     -45.85mA   -49.67mA   -45.22mA
2.2V      -55.46mA   -55.5mA    -57.28mA
[POWER Clamp]
|   Voltage   I(typ)   I(min)   I(max)
-1.1V     3.036mA    3.636mA    2.186mA
-1.041V   2.347mA    2.931mA    1.626mA
-981.2mV  1.754mA    2.277mA    1.183mA
-911.9mV  1.201mA    1.612mA    764.7uA
-855.8mV  838.1uA    1.172mA    552.3uA
-779.9mV  448uA      701.7uA    396.3uA
-713.9mV  239.3uA    373.2uA    278.6uA
-661.1mV  151.1uA    187.6uA    195.5uA
-595.1mV  80.77uA    68.33uA    109.2uA
-499.4mV  21.4uA     13.13uA    27.45uA
-400.4mV  2.614uA    1.705uA    2.313uA
2.2V      0A         0A         0A
[Ramp]
|   typ   min   max
| 20% - 80%
dV/dt_r   240.38m/34.71p   227.94m/38.97p   263.47m/29.90p
dV/dt_f   224.50m/57.31p   206.45m/68.04p   255.27m/46.57p
| 25% - 75%
|dV/dt_r   200.32m/27.63p   189.95m/30.97p   219.55m/23.77p
|dV/dt_f   187.09m/45.61p   172.04m/54.13p   212.73m/37.02p
R_load = 50
[Rising Waveform]
R_fixture = 50
V_fixture = 0.0
|   Time   V(typ)   V(min)   V(max)
0s        806uV      708.5uV    581.8uV
58ps      643uV      -264.5uV   14.47mV
65ps      3.629mV    -603.3uV   57.7mV
78ps      20.02mV    2.787mV    193.8mV
93ps      116.9mV    14.36mV    322.7mV
105ps     216.8mV    51.61mV    380.8mV
123ps     320mV      170.4mV    421mV
149ps     381mV      306.7mV    436.7mV
178ps     397.8mV    363.1mV    439.4mV
355ps     401.4mV    380.6mV    439.7mV
[Falling Waveform]
R_fixture   = 50
V_fixture   = 1.1
V_fixture_min = 1.06
V_fixture_max = 1.17
|   Time   V(typ)   V(min)   V(max)
0s        1.1V       1.06V      1.17V
71ps      1.099V     1.061V     1.158V
95ps      1.078V     1.053V     1.009V
117ps     977mV      1.039V     880.5mV
135ps     892.2mV    988.1mV    818.8mV
158ps     816.6mV    899.4mV    777.8mV
188ps     764.4mV    811.9mV    756mV
224ps     739mV      756mV      747.7mV
276ps     728.5mV    725.8mV    745mV
355ps     725.8mV    715.9mV    744.6mV
[Rising Waveform]
R_fixture   = 50
V_fixture   = 1.1
V_fixture_min = 1.06
V_fixture_max = 1.17
|   Time   V(typ)   V(min)   V(max)
0s        725.4mV    714.2mV    744.5mV
51ps      721mV      710.9mV    750.3mV
61ps      727.9mV    707.1mV    791.2mV
74ps      777.2mV    715.9mV    898.6mV
86ps      857.9mV    756.8mV    976.2mV
103ps     947.3mV    853.1mV    1.048V
119ps     999.3mV    924.8mV    1.09V
140ps     1.041V     980.7mV    1.125V
205ps     1.088V     1.044V     1.162V
355ps     1.1V       1.059V     1.17V
[Falling Waveform]
R_fixture = 50
V_fixture = 0.0
|   Time   V(typ)   V(min)   V(max)
0s        401.6mV    380.8mV    439.8mV
56ps      408.6mV    382.1mV    443.2mV
73ps      401.9mV    394.3mV    335mV
85ps      340.7mV    387.8mV    199.8mV
96ps      251.5mV    348.4mV    122.9mV
112ps     135.1mV    249.8mV    61.81mV
130ps     65.52mV    143.5mV    28.97mV
154ps     25.56mV    58.44mV    10.85mV
187ps     7.571mV    17.05mV    3.16mV
355ps     879.9uV    834.9uV    608.6uV
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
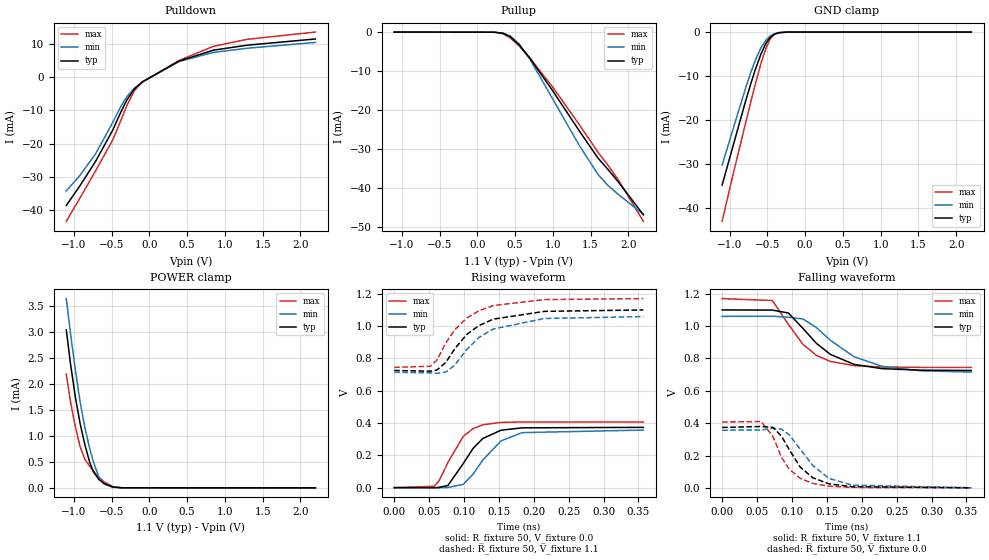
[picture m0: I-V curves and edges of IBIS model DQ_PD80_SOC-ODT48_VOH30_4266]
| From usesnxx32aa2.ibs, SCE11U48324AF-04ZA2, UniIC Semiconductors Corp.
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| DQ_PD80_SOC-ODT48_VOH30_4266
| (80 Ohm Pulldown, 48 Ohm System ODT Setting, VOH=VDDQ/3.0, 3200-4266Mbps)
[Model]   DQ_PD80_SOC-ODT48_VOH30_4266
Model_type   I/O
Vinl = 123.333mV
Vinh = 243.333mV
Vmeas = 183.333mV
Vref = 0.0mV
Cref = 0.0pF
Rref = 48.000Ohm
|   typ   min   max
|C_comp   0.797pF   0.747pF   0.847pF
C_comp_pullup   0.3985pF   0.3735pF   0.4235pF
C_comp_pulldown   0.3985pF   0.3735pF   0.4235pF
| Note: C_comp changes when the ODT circuit is enabled.
[Model Spec]
| Input threshold voltage corners
Vinl   0.1233V   0.1167V   0.1350V
Vinh   0.2433V   0.2367V   0.2550V
| Measurement voltage corners
Vmeas   0.1833V   0.1767V   0.1950V
| Timing spec test load voltage corners
Vref   0.0000V   0.0000V   0.0000V
| Dynamic Overshoot Parameters from LPDDR4 Specification
D_overshoot_ampl_h   0.30   NA   NA
D_overshoot_ampl_l   0.30   NA   NA
D_overshoot_area_h   0.1n   NA   NA
D_overshoot_area_l   0.1n   NA   NA
[Receiver Thresholds]
Vth   = 0.1833V
Vth_min  = 0.1800V
Vth_max  = 0.1866V
Vinh_ac  = 0.060V
Vinh_dc  = 0.060V
Vinl_ac  = -0.060V
Vinl_dc  = -0.060V
Tslew_ac = 5.000ns |Not specified, so set to high value
Threshold_sensitivity = 0.1667
Reference_supply Pullup_ref
[Voltage Range]   1.1000V   1.0600V   1.1700V
[Pullup Reference]   1.1000V   1.0600V   1.1700V
| Junction Temperature (Ambient temp is 35C typ 95C min -40C max)
[Temperature Range]   50.0   110.0   -40.0
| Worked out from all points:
|   slope of the pulldown table from 0 to 0.165 V, typ, clamps not added: 73.9 ohm
|   slope of the pullup table from 0 to 0.165 V, typ, clamps not added: 15.6 kohm
|   GND clamp passes 1 mA (typ) near -0.45 V on its own axis
|   POWER clamp passes 1 mA (typ) near -0.88 V on its own axis
|   rising waveform, R_fixture 50, V_fixture 0.0: 20-80 % time 36.1ps typ, 40.7ps min, 31.6ps max; typ from 0.001 V to 0.374 V
|   falling waveform, R_fixture 50, V_fixture 1.1: 20-80 % time 57.1ps typ, 67.6ps min, 46.4ps max; typ from 1.1 V to 0.726 V
|   rising waveform, R_fixture 50, V_fixture 1.1: 20-80 % time 53.5ps typ, 55ps min, 50.6ps max; typ from 0.725 V to 1.1 V
|   falling waveform, R_fixture 50, V_fixture 0.0: 20-80 % time 37.2ps typ, 43.6ps min, 32.1ps max; typ from 0.374 V to 0.001 V
[Pulldown]
|   Voltage   I(typ)   I(min)   I(max)
-1.1V     -38.53mA   -34.15mA   -43.28mA
-925.1mV  -32.82mA   -29.67mA   -36.55mA
-713.9mV  -25.35mA   -23.09mA   -28.21mA
-486.2mV  -15.96mA   -13.67mA   -18.92mA
-380.6mV  -10.64mA   -8.91mA    -13.17mA
-298.1mV  -6.842mA   -5.853mA   -8.518mA
-199.1mV  -3.563mA   -3.302mA   -4.081mA
-90.2mV   -1.396mA   -1.37mA    -1.397mA
394.9mV   4.856mA    4.742mA    5.045mA
850.3mV   8.134mA    7.462mA    9.296mA
1.296V    9.622mA    8.703mA    11.39mA
2.2V      11.49mA    10.45mA    13.57mA
[GND Clamp]
|   Voltage   I(typ)   I(min)   I(max)
-1.1V     -34.88mA   -30.35mA   -43.13mA
-941.6mV  -25.13mA   -21.34mA   -31.48mA
-793.1mV  -15.98mA   -13.01mA   -21.06mA
-717.2mV  -11.61mA   -9.056mA   -15.72mA
-661.1mV  -8.597mA   -6.455mA   -11.9mA
-585.2mV  -4.99mA    -3.583mA   -7.136mA
-519.2mV  -2.57mA    -1.835mA   -3.672mA
-463.1mV  -1.239mA   -901.9uA   -1.601mA
-413.6mV  -565.8uA   -418.1uA   -622.4uA
-354.2mV  -179.3uA   -135.3uA   -160.7uA
-248.6mV  -12.12uA   -10.94uA   -7.138uA
2.2V      0A         0A         0A
[Pullup]
|   Voltage   I(typ)   I(min)   I(max)
-1.1V     5.237uA    8.07uA     2.361uA
226.6mV   -35.36uA   -35.94uA   -35.68uA
342.1mV   -317.5uA   -261.3uA   -439.1uA
437.8mV   -1.204mA   -986.3uA   -1.515mA
556.6mV   -3.33mA    -3.082mA   -3.599mA
695.2mV   -6.659mA   -6.89mA    -6.57mA
998.8mV   -15.02mA   -17.09mA   -14.08mA
1.349V    -25.23mA   -28.94mA   -23.63mA
1.599V    -32.26mA   -36.44mA   -30.76mA
1.731V    -35.17mA   -39.27mA   -34.08mA
1.867V    -38.32mA   -41.54mA   -37.79mA
2.2V      -46.77mA   -46.65mA   -48.43mA
[POWER Clamp]
|   Voltage   I(typ)   I(min)   I(max)
-1.1V     3.036mA    3.636mA    2.186mA
-1.044V   2.383mA    2.969mA    1.654mA
-981.2mV  1.754mA    2.277mA    1.183mA
-918.5mV  1.248mA    1.669mA    798.5uA
-855.8mV  838uA      1.173mA    552.3uA
-789.8mV  491.2uA    757.6uA    414.8uA
-740.3mV  306.2uA    494.6uA    324.3uA
-667.7mV  159.9uA    206.2uA    205.2uA
-598.4mV  83.65uA    71.96uA    113.1uA
-482.9mV  15.79uA    9.506uA    19.54uA
-364.1mV  1.112uA    824.5nA    869.8nA
2.2V      0A         0A         0A
[Ramp]
|   typ   min   max
| 20% - 80%
dV/dt_r   223.77m/36.09p   213.73m/40.73p   244.05m/31.61p
dV/dt_f   224.55m/57.06p   206.46m/67.57p   255.27m/46.44p
| 25% - 75%
|dV/dt_r   186.47m/28.77p   178.11m/32.44p   203.38m/25.10p
|dV/dt_f   187.12m/45.45p   172.05m/53.85p   212.72m/36.88p
R_load = 50
[Rising Waveform]
R_fixture = 50
V_fixture = 0.0
|   Time   V(typ)   V(min)   V(max)
0s        671.2uV    588.2uV    485.4uV
57ps      299.1uV    -91.7uV    9.032mV
64ps      2.334mV    -486.1uV   40.25mV
77ps      14.11mV    1.665mV    156.7mV
99ps      150.1mV    21.4mV     318mV
113ps     243.8mV    83.85mV    366.1mV
127ps     304.9mV    172mV      389.6mV
153ps     355.8mV    289.7mV    404.1mV
183ps     370.6mV    340.9mV    406.9mV
357ps     373.6mV    356.8mV    407.2mV
[Falling Waveform]
R_fixture   = 50
V_fixture   = 1.1
V_fixture_min = 1.06
V_fixture_max = 1.17
|   Time   V(typ)   V(min)   V(max)
0s        1.1V       1.06V      1.17V
72ps      1.099V     1.061V     1.158V
95ps      1.081V     1.055V     1.011V
116ps     984.8mV    1.044V     886.2mV
135ps     894mV      991.4mV    819.4mV
155ps     825.5mV    912.7mV    781.8mV
189ps     763.5mV    810.8mV    755.7mV
229ps     737.2mV    751.6mV    747.3mV
284ps     727.8mV    723.8mV    744.9mV
357ps     725.8mV    715.9mV    744.6mV
[Rising Waveform]
R_fixture   = 50
V_fixture   = 1.1
V_fixture_min = 1.06
V_fixture_max = 1.17
|   Time   V(typ)   V(min)   V(max)
0s        725.4mV    714.2mV    744.5mV
52ps      721.2mV    710.6mV    751.5mV
61ps      727.7mV    707.3mV    788.7mV
74ps      775.3mV    715.8mV    895.7mV
87ps      861.6mV    759.9mV    979.2mV
104ps     948.5mV    855.2mV    1.05V
121ps     1.002V     928.1mV    1.094V
142ps     1.043V     981.9mV    1.127V
215ps     1.091V     1.047V     1.164V
357ps     1.1V       1.059V     1.17V
[Falling Waveform]
R_fixture = 50
V_fixture = 0.0
|   Time   V(typ)   V(min)   V(max)
0s        373.7mV    357mV      407.3mV
56ps      379.6mV    357.9mV    410.4mV
73ps      374mV      368.4mV    316.7mV
85ps      320.1mV    363.2mV    189.3mV
96ps      237.9mV    328.8mV    116.5mV
112ps     128.3mV    239.1mV    58.65mV
130ps     62.47mV    138.4mV    27.47mV
153ps     25.27mV    58.9mV     10.69mV
186ps     7.473mV    17.22mV    3.048mV
357ps     751.4uV    726.9uV    513.5uV
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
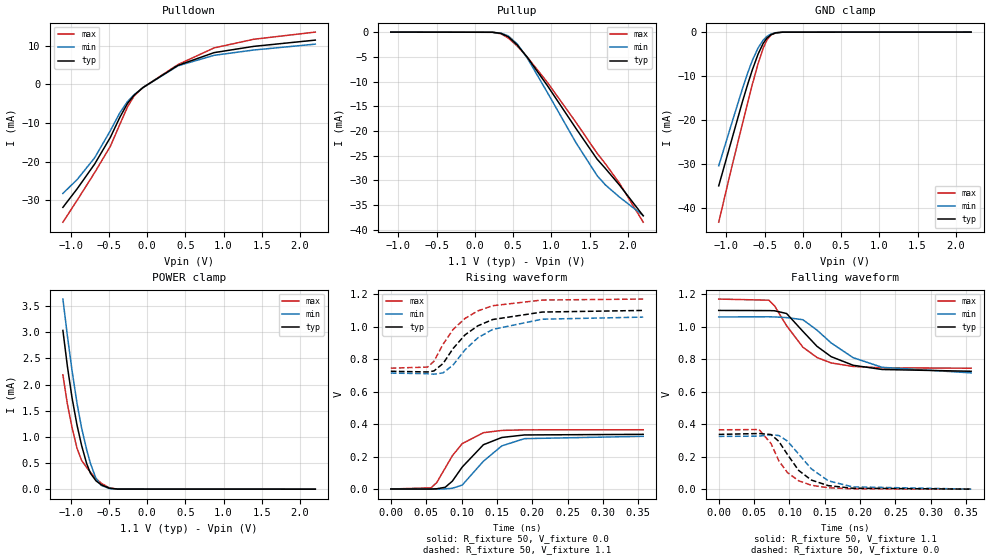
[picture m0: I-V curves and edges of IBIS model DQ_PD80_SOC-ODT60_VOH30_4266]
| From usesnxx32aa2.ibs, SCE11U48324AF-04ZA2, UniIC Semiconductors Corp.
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| DQ_PD80_SOC-ODT60_VOH30_4266
| (80 Ohm Pulldown, 60 Ohm System ODT Setting, VOH=VDDQ/3.0, 3200-4266Mbps)
[Model]   DQ_PD80_SOC-ODT60_VOH30_4266
Model_type   I/O
Vinl = 123.333mV
Vinh = 243.333mV
Vmeas = 183.333mV
Vref = 0.0mV
Cref = 0.0pF
Rref = 60.000Ohm
|   typ   min   max
|C_comp   0.797pF   0.747pF   0.847pF
C_comp_pullup   0.3985pF   0.3735pF   0.4235pF
C_comp_pulldown   0.3985pF   0.3735pF   0.4235pF
| Note: C_comp changes when the ODT circuit is enabled.
[Model Spec]
| Input threshold voltage corners
Vinl   0.1233V   0.1167V   0.1350V
Vinh   0.2433V   0.2367V   0.2550V
| Measurement voltage corners
Vmeas   0.1833V   0.1767V   0.1950V
| Timing spec test load voltage corners
Vref   0.0000V   0.0000V   0.0000V
| Dynamic Overshoot Parameters from LPDDR4 Specification
D_overshoot_ampl_h   0.30   NA   NA
D_overshoot_ampl_l   0.30   NA   NA
D_overshoot_area_h   0.1n   NA   NA
D_overshoot_area_l   0.1n   NA   NA
[Receiver Thresholds]
Vth   = 0.1833V
Vth_min  = 0.1800V
Vth_max  = 0.1866V
Vinh_ac  = 0.060V
Vinh_dc  = 0.060V
Vinl_ac  = -0.060V
Vinl_dc  = -0.060V
Tslew_ac = 5.000ns |Not specified, so set to high value
Threshold_sensitivity = 0.1667
Reference_supply Pullup_ref
[Voltage Range]   1.1000V   1.0600V   1.1700V
[Pullup Reference]   1.1000V   1.0600V   1.1700V
| Junction Temperature (Ambient temp is 35C typ 95C min -40C max)
[Temperature Range]   50.0   110.0   -40.0
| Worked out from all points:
|   slope of the pulldown table from 0 to 0.165 V, typ, clamps not added: 74.1 ohm
|   slope of the pullup table from 0 to 0.165 V, typ, clamps not added: 19.3 kohm
|   GND clamp passes 1 mA (typ) near -0.45 V on its own axis
|   POWER clamp passes 1 mA (typ) near -0.88 V on its own axis
|   rising waveform, R_fixture 50, V_fixture 0.0: 20-80 % time 39.4ps typ, 43.5ps min, 34.4ps max; typ from 0.001 V to 0.337 V
|   falling waveform, R_fixture 50, V_fixture 1.1: 20-80 % time 56.8ps typ, 67.1ps min, 46.2ps max; typ from 1.1 V to 0.726 V
|   rising waveform, R_fixture 50, V_fixture 1.1: 20-80 % time 53.7ps typ, 56.3ps min, 50.8ps max; typ from 0.725 V to 1.1 V
|   falling waveform, R_fixture 50, V_fixture 0.0: 20-80 % time 37.2ps typ, 44ps min, 32.2ps max; typ from 0.337 V to 0.001 V
[Pulldown]
|   Voltage   I(typ)   I(min)   I(max)
-1.1V     -31.82mA   -28.22mA   -35.66mA
-911.9mV  -26.97mA   -24.58mA   -29.93mA
-684.2mV  -20.58mA   -18.96mA   -22.8mA
-479.6mV  -13.7mA    -11.96mA   -16.01mA
-354.2mV  -8.452mA   -7.282mA   -10.26mA
-255.2mV  -4.899mA   -4.423mA   -5.802mA
-169.4mV  -2.773mA   -2.658mA   -2.979mA
-53.9mV   -810.7uA   -802.3uA   -796.1uA
404.8mV   4.955mA    4.835mA    5.159mA
876.7mV   8.251mA    7.554mA    9.471mA
1.395V    9.872mA    8.928mA    11.71mA
2.2V      11.49mA    10.45mA    13.57mA
[GND Clamp]
|   Voltage   I(typ)   I(min)   I(max)
-1.1V     -34.88mA   -30.34mA   -43.13mA
-935mV    -24.71mA   -20.97mA   -31mA
-793.1mV  -15.98mA   -13.01mA   -21.06mA
-720.5mV  -11.79mA   -9.217mA   -15.95mA
-661.1mV  -8.597mA   -6.454mA   -11.9mA
-585.2mV  -4.987mA   -3.583mA   -7.136mA
-519.2mV  -2.57mA    -1.838mA   -3.672mA
-469.7mV  -1.359mA   -986.6uA   -1.794mA
-416.9mV  -597.1uA   -442uA     -666.7uA
-357.5mV  -191.5uA   -144.1uA   -174.1uA
-265.1mV  -19.5uA    -17uA      -12.35uA
2.2V      0A         0A         0A
[Pullup]
|   Voltage   I(typ)   I(min)   I(max)
-1.1V     4.189uA    6.456uA    1.888uA
229.9mV   -30.49uA   -30.57uA   -31.15uA
342.1mV   -255.9uA   -210.1uA   -350.4uA
437.8mV   -961.1uA   -787.8uA   -1.21mA
553.3mV   -2.604mA   -2.4mA     -2.822mA
685.3mV   -5.113mA   -5.256mA   -5.067mA
949.3mV   -10.87mA   -12.27mA   -10.21mA
1.319V    -19.44mA   -22.31mA   -18.2mA
1.596V    -25.66mA   -28.99mA   -24.47mA
1.705V    -27.56mA   -30.89mA   -26.61mA
1.89V     -30.93mA   -33.36mA   -30.56mA
2.2V      -37.14mA   -37.08mA   -38.43mA
[POWER Clamp]
|   Voltage   I(typ)   I(min)   I(max)
-1.1V     3.036mA    3.636mA    2.186mA
-1.041V   2.347mA    2.931mA    1.626mA
-981.2mV  1.754mA    2.277mA    1.183mA
-915.2mV  1.224mA    1.64mA     781.4uA
-855.8mV  838uA      1.173mA    552.1uA
-789.8mV  491.1uA    757.5uA    414.8uA
-740.3mV  306.2uA    494.6uA    324.3uA
-667.7mV  159.9uA    206.2uA    205.2uA
-598.4mV  83.65uA    71.98uA    113.1uA
-492.8mV  18.9uA     11.62uA    24.07uA
-383.9mV  1.737uA    1.212uA    1.469uA
2.2V      0A         0A         0A
[Ramp]
|   typ   min   max
| 20% - 80%
dV/dt_r   201.93m/39.39p   194.68m/43.50p   219.02m/34.40p
dV/dt_f   224.51m/56.80p   206.45m/67.13p   255.26m/46.22p
| 25% - 75%
|dV/dt_r   168.28m/31.39p   162.23m/34.70p   182.51m/27.33p
|dV/dt_f   187.09m/45.20p   172.05m/53.55p   212.72m/36.74p
R_load = 50
[Rising Waveform]
R_fixture = 50
V_fixture = 0.0
|   Time   V(typ)   V(min)   V(max)
0s        533.6uV    463.5uV    387.1uV
57ps      235uV      -80.8uV    8.018mV
65ps      2.118mV    -413.2uV   40.67mV
77ps      11.4mV     1.429mV    130.3mV
87ps      48.75mV    5.014mV    205.3mV
101ps     135.8mV    24.66mV    280mV
131ps     273.3mV    171.7mV    347.3mV
157ps     317.8mV    266.1mV    361.3mV
189ps     333.4mV    310.7mV    364.8mV
357ps     337.1mV    324.9mV    365.4mV
[Falling Waveform]
R_fixture   = 50
V_fixture   = 1.1
V_fixture_min = 1.06
V_fixture_max = 1.17
|   Time   V(typ)   V(min)   V(max)
0s        1.1V       1.06V      1.17V
71ps      1.099V     1.061V     1.163V
79ps      1.098V     1.06V      1.128V
96ps      1.081V     1.056V     1.006V
119ps     971.6mV    1.043V     874.1mV
139ps     879.2mV    978.9mV    810.3mV
159ps     815.7mV    900.1mV    777.1mV
190ps     762.8mV    809.7mV    755.4mV
231ps     736.7mV    750.2mV    747.1mV
357ps     725.8mV    715.9mV    744.6mV
[Rising Waveform]
R_fixture   = 50
V_fixture   = 1.1
V_fixture_min = 1.06
V_fixture_max = 1.17
|   Time   V(typ)   V(min)   V(max)
0s        725.4mV    714.2mV    744.5mV
52ps      721.3mV    710.6mV    751.2mV
61ps      727.5mV    707.5mV    786.9mV
74ps      773.7mV    715.8mV    892.8mV
88ps      865.1mV    763.7mV    982.1mV
105ps     949.7mV    857.5mV    1.051V
123ps     1.005V     931.1mV    1.097V
144ps     1.044V     983mV      1.129V
214ps     1.09V      1.046V     1.164V
357ps     1.1V       1.059V     1.17V
[Falling Waveform]
R_fixture = 50
V_fixture = 0.0
|   Time   V(typ)   V(min)   V(max)
0s        337.2mV    325mV      365.5mV
57ps      342.8mV    326.7mV    367.2mV
74ps      336.4mV    335.4mV    280.9mV
85ps      294.6mV    330.4mV    174.7mV
97ps      215.2mV    296.8mV    103.2mV
113ps     115.9mV    216.8mV    52.08mV
131ps     56.52mV    125.5mV    24.41mV
155ps     22.15mV    51.79mV    9.118mV
189ps     6.288mV    14.73mV    2.504mV
357ps     629.2uV    614.4uV    417.9uV
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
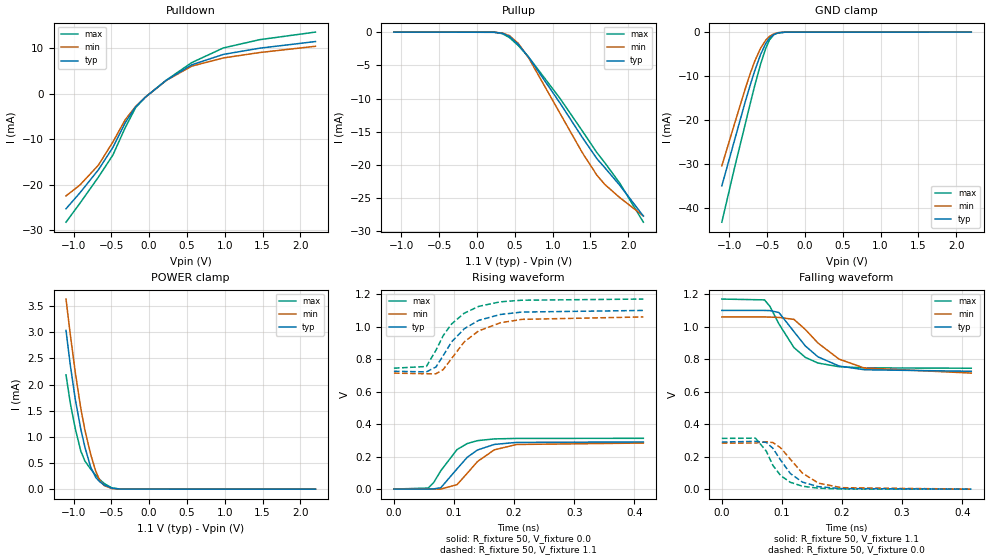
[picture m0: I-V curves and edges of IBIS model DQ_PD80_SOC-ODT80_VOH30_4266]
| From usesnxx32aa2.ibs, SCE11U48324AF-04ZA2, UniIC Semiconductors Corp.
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| DQ_PD80_SOC-ODT80_VOH30_4266
| (80 Ohm Pulldown, 80 Ohm System ODT Setting, VOH=VDDQ/3.0, 3200-4266Mbps)
[Model]   DQ_PD80_SOC-ODT80_VOH30_4266
Model_type   I/O
Vinl = 123.333mV
Vinh = 243.333mV
Vmeas = 183.333mV
Vref = 0.0mV
Cref = 0.0pF
Rref = 80.000Ohm
|   typ   min   max
|C_comp   0.797pF   0.747pF   0.847pF
C_comp_pullup   0.3985pF   0.3735pF   0.4235pF
C_comp_pulldown   0.3985pF   0.3735pF   0.4235pF
| Note: C_comp changes when the ODT circuit is enabled.
[Model Spec]
| Input threshold voltage corners
Vinl   0.1233V   0.1167V   0.1350V
Vinh   0.2433V   0.2367V   0.2550V
| Measurement voltage corners
Vmeas   0.1833V   0.1767V   0.1950V
| Timing spec test load voltage corners
Vref   0.0000V   0.0000V   0.0000V
| Dynamic Overshoot Parameters from LPDDR4 Specification
D_overshoot_ampl_h   0.30   NA   NA
D_overshoot_ampl_l   0.30   NA   NA
D_overshoot_area_h   0.1n   NA   NA
D_overshoot_area_l   0.1n   NA   NA
[Receiver Thresholds]
Vth   = 0.1833V
Vth_min  = 0.1800V
Vth_max  = 0.1866V
Vinh_ac  = 0.060V
Vinh_dc  = 0.060V
Vinl_ac  = -0.060V
Vinl_dc  = -0.060V
Tslew_ac = 5.000ns |Not specified, so set to high value
Threshold_sensitivity = 0.1667
Reference_supply Pullup_ref
[Voltage Range]   1.1000V   1.0600V   1.1700V
[Pullup Reference]   1.1000V   1.0600V   1.1700V
| Junction Temperature (Ambient temp is 35C typ 95C min -40C max)
[Temperature Range]   50.0   110.0   -40.0
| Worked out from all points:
|   slope of the pulldown table from 0 to 0.165 V, typ, clamps not added: 74.3 ohm
|   slope of the pullup table from 0 to 0.165 V, typ, clamps not added: 25.9 kohm
|   GND clamp passes 1 mA (typ) near -0.45 V on its own axis
|   POWER clamp passes 1 mA (typ) near -0.88 V on its own axis
|   rising waveform, R_fixture 50, V_fixture 0.0: 20-80 % time 42.8ps typ, 46.1ps min, 37.1ps max; typ from 0 V to 0.29 V
|   falling waveform, R_fixture 50, V_fixture 1.1: 20-80 % time 56.7ps typ, 67.4ps min, 46.1ps max; typ from 1.1 V to 0.726 V
|   rising waveform, R_fixture 50, V_fixture 1.1: 20-80 % time 54.3ps typ, 57.7ps min, 50.9ps max; typ from 0.725 V to 1.1 V
|   falling waveform, R_fixture 50, V_fixture 0.0: 20-80 % time 37.9ps typ, 44.7ps min, 32.8ps max; typ from 0.29 V to 0 V
[Pulldown]
|   Voltage   I(typ)   I(min)   I(max)
-1.1V     -25.26mA   -22.43mA   -28.21mA
-918.5mV  -21.81mA   -20.09mA   -24.11mA
-671mV    -16.69mA   -15.67mA   -18.3mA
-479.6mV  -11.77mA   -10.57mA   -13.45mA
-317.9mV  -6.38mA    -5.728mA   -7.478mA
-179.3mV  -2.865mA   -2.772mA   -3.048mA
-50.6mV   -748.6uA   -743.9uA   -734.9uA
226.6mV   2.976mA    2.943mA    3.006mA
563.2mV   6.375mA    6.087mA    6.861mA
982.3mV   8.669mA    7.889mA    10.09mA
1.461V    10.03mA    9.072mA    11.9mA
2.2V      11.49mA    10.45mA    13.57mA
[GND Clamp]
|   Voltage   I(typ)   I(min)   I(max)
-1.1V     -34.88mA   -30.35mA   -43.13mA
-938.3mV  -24.92mA   -21.15mA   -31.24mA
-793.1mV  -15.98mA   -13.01mA   -21.06mA
-720.5mV  -11.8mA    -9.217mA   -15.95mA
-664.4mV  -8.768mA   -6.598mA   -12.12mA
-588.5mV  -5.127mA   -3.689mA   -7.328mA
-519.2mV  -2.578mA   -1.836mA   -3.672mA
-469.7mV  -1.364mA   -986.6uA   -1.79mA
-413.6mV  -569.2uA   -417.2uA   -621.2uA
-354.2mV  -178.3uA   -134.7uA   -160uA
-255.2mV  -14.67uA   -13.01uA   -8.795uA
2.2V      0A         0A         0A
[Pullup]
|   Voltage   I(typ)   I(min)   I(max)
-1.1V     3.142uA    4.844uA    1.416uA
229.9mV   -22.59uA   -22.99uA   -23.3uA
335.5mV   -170.6uA   -141.9uA   -234.8uA
427.9mV   -643.3uA   -523.7uA   -821.8uA
546.7mV   -1.867mA   -1.71mA    -2.037mA
682mV     -3.779mA   -3.877mA   -3.751mA
1.098V    -10.69mA   -12.24mA   -9.991mA
1.391V    -15.83mA   -18.12mA   -14.85mA
1.586V    -19.06mA   -21.55mA   -18.15mA
1.692V    -20.43mA   -22.95mA   -19.69mA
1.887V    -23.04mA   -24.9mA    -22.72mA
2.2V      -27.69mA   -27.67mA   -28.61mA
[POWER Clamp]
|   Voltage   I(typ)   I(min)   I(max)
-1.1V     3.036mA    3.636mA    2.186mA
-1.044V   2.383mA    2.969mA    1.654mA
-977.9mV  1.724mA    2.242mA    1.161mA
-905.3mV  1.155mA    1.554mA    732.4uA
-849.2mV  799.4uA    1.126mA    535.5uA
-773.3mV  420.9uA    665.7uA    384.1uA
-707.3mV  225.5uA    345.5uA    267.6uA
-651.2mV  138.6uA    162.3uA    181.2uA
-595.1mV  80.78uA    68.3uA     109.2uA
-492.8mV  18.88uA    11.57uA    24.05uA
-377.3mV  1.518uA    1.061uA    1.226uA
2.2V      0A         0A         0A
[Ramp]
|   typ   min   max
| 20% - 80%
dV/dt_r   173.98m/42.83p   169.93m/46.11p   187.39m/37.11p
dV/dt_f   224.66m/56.63p   207.22m/67.36p   255.28m/46.09p
| 25% - 75%
|dV/dt_r   144.98m/34.16p   141.61m/36.75p   156.16m/29.49p
|dV/dt_f   187.22m/45.07p   172.69m/53.62p   212.73m/36.64p
R_load = 50
[Rising Waveform]
R_fixture = 50
V_fixture = 0.0
|   Time   V(typ)   V(min)   V(max)
0s        395.8uV    338.2uV    289.2uV
57ps      -16.1uV    49.49uV    6.35mV
66ps      965.5uV    -425.8uV   39.36mV
78ps      8.448mV    399uV      113.1mV
105ps     124.5mV    27.24mV    243.4mV
122ps     196mV      97.57mV    280.5mV
139ps     240.7mV    169.6mV    298.3mV
167ps     275mV      241.6mV    309mV
204ps     287.5mV    274.7mV    312mV
415ps     290.4mV    283.6mV    312.6mV
[Falling Waveform]
R_fixture   = 50
V_fixture   = 1.1
V_fixture_min = 1.06
V_fixture_max = 1.17
|   Time   V(typ)   V(min)   V(max)
0s        1.1V       1.06V      1.17V
71ps      1.1V       1.06V      1.165V
80ps      1.099V     1.059V     1.125V
95ps      1.087V     1.057V     1.017V
120ps     969.4mV    1.045V     871.4mV
139ps     881.2mV    982.6mV    811.1mV
160ps     814.3mV    899.2mV    776.3mV
195ps     758.1mV    800.6mV    753.7mV
237ps     735mV      745.7mV    746.6mV
415ps     725.6mV    714.6mV    744.5mV
[Rising Waveform]
R_fixture   = 50
V_fixture   = 1.1
V_fixture_min = 1.06
V_fixture_max = 1.17
|   Time   V(typ)   V(min)   V(max)
0s        725.4mV    714.2mV    744.5mV
54ps      721.7mV    710mV      754.8mV
70ps      751.9mV    710.2mV    855.5mV
82ps      821.9mV    736mV      945.3mV
96ps      906.6mV    804mV      1.017V
117ps     987.1mV    906.5mV    1.083V
141ps     1.039V     974.1mV    1.125V
177ps     1.075V     1.024V     1.153V
213ps     1.09V      1.045V     1.163V
415ps     1.1V       1.06V      1.17V
[Falling Waveform]
R_fixture = 50
V_fixture = 0.0
|   Time   V(typ)   V(min)   V(max)
0s        290.5mV    283.7mV    312.7mV
56ps      294.5mV    284.5mV    314mV
74ps      287.8mV    292mV      234.2mV
85ps      251.7mV    287.1mV    146.2mV
98ps      178.1mV    253.9mV    83.49mV
114ps     96.47mV    184.4mV    42.61mV
134ps     43.97mV    99.22mV    18.39mV
161ps     15.49mV    37.04mV    6.139mV
199ps     3.908mV    9.433mV    1.531mV
415ps     480.5uV    450.2uV    318.2uV
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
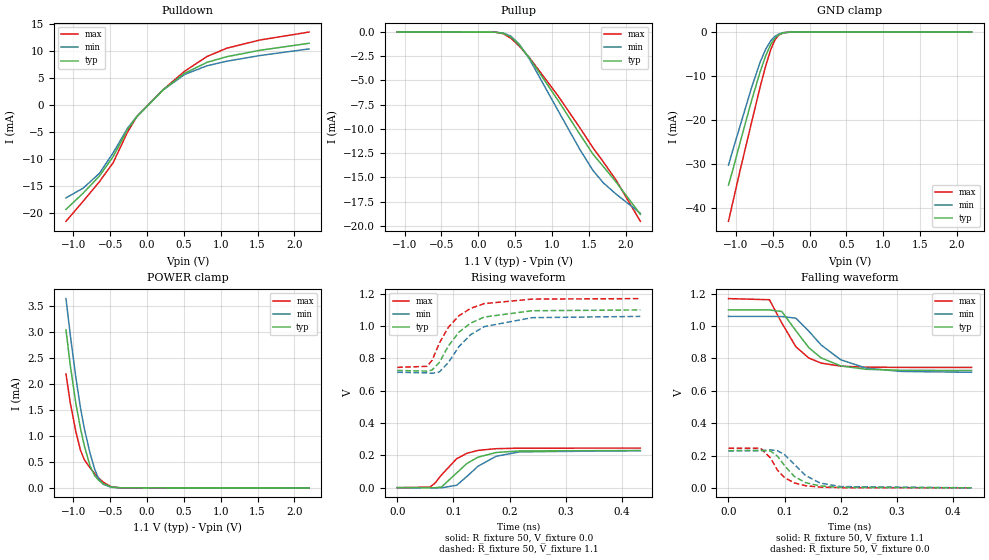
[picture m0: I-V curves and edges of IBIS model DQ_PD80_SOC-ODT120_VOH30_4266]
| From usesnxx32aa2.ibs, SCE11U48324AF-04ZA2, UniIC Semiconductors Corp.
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| DQ_PD80_SOC-ODT120_VOH30_4266
| (80 Ohm Pulldown, 120 Ohm System ODT Setting, VOH=VDDQ/3.0, 3200-4266Mbps)
[Model]   DQ_PD80_SOC-ODT120_VOH30_4266
Model_type   I/O
Vinl = 123.333mV
Vinh = 243.333mV
Vmeas = 183.333mV
Vref = 0.0mV
Cref = 0.0pF
Rref = 120.000Ohm
|   typ   min   max
|C_comp   0.797pF   0.747pF   0.847pF
C_comp_pullup   0.3985pF   0.3735pF   0.4235pF
C_comp_pulldown   0.3985pF   0.3735pF   0.4235pF
| Note: C_comp changes when the ODT circuit is enabled.
[Model Spec]
| Input threshold voltage corners
Vinl   0.1233V   0.1167V   0.1350V
Vinh   0.2433V   0.2367V   0.2550V
| Measurement voltage corners
Vmeas   0.1833V   0.1767V   0.1950V
| Timing spec test load voltage corners
Vref   0.0000V   0.0000V   0.0000V
| Dynamic Overshoot Parameters from LPDDR4 Specification
D_overshoot_ampl_h   0.30   NA   NA
D_overshoot_ampl_l   0.30   NA   NA
D_overshoot_area_h   0.1n   NA   NA
D_overshoot_area_l   0.1n   NA   NA
[Receiver Thresholds]
Vth   = 0.1833V
Vth_min  = 0.1800V
Vth_max  = 0.1866V
Vinh_ac  = 0.060V
Vinh_dc  = 0.060V
Vinl_ac  = -0.060V
Vinl_dc  = -0.060V
Tslew_ac = 5.000ns |Not specified, so set to high value
Threshold_sensitivity = 0.1667
Reference_supply Pullup_ref
[Voltage Range]   1.1000V   1.0600V   1.1700V
[Pullup Reference]   1.1000V   1.0600V   1.1700V
| Junction Temperature (Ambient temp is 35C typ 95C min -40C max)
[Temperature Range]   50.0   110.0   -40.0
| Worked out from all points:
|   slope of the pulldown table from 0 to 0.165 V, typ, clamps not added: 74.4 ohm
|   slope of the pullup table from 0 to 0.165 V, typ, clamps not added: 39 kohm
|   GND clamp passes 1 mA (typ) near -0.45 V on its own axis
|   POWER clamp passes 1 mA (typ) near -0.88 V on its own axis
|   rising waveform, R_fixture 50, V_fixture 0.0: 20-80 % time 46.5ps typ, 50.9ps min, 41.1ps max; typ from 0 V to 0.23 V
|   falling waveform, R_fixture 50, V_fixture 1.1: 20-80 % time 56.4ps typ, 67.1ps min, 45.9ps max; typ from 1.1 V to 0.726 V
|   rising waveform, R_fixture 50, V_fixture 1.1: 20-80 % time 54.9ps typ, 58.5ps min, 50.6ps max; typ from 0.725 V to 1.1 V
|   falling waveform, R_fixture 50, V_fixture 0.0: 20-80 % time 37.7ps typ, 44.6ps min, 32.8ps max; typ from 0.23 V to 0 V
[Pulldown]
|   Voltage   I(typ)   I(min)   I(max)
-1.1V     -19.24mA   -17.11mA   -21.44mA
-865.7mV  -16.22mA   -15.3mA    -17.72mA
-644.6mV  -13.04mA   -12.55mA   -14.09mA
-459.8mV  -9.488mA   -8.773mA   -10.6mA
-265.1mV  -4.476mA   -4.242mA   -4.946mA
-139.7mV  -2.089mA   -2.071mA   -2.11mA
220mV     2.896mA    2.865mA    2.922mA
510.4mV   5.938mA    5.717mA    6.318mA
814mV     7.963mA    7.329mA    9.042mA
1.081V    9.006mA    8.169mA    10.57mA
1.53V     10.19mA    9.219mA    12.09mA
2.2V      11.49mA    10.45mA    13.57mA
[GND Clamp]
|   Voltage   I(typ)   I(min)   I(max)
-1.1V     -34.88mA   -30.35mA   -43.13mA
-1.047V   -31.79mA   -27.25mA   -39.23mA
-941.6mV  -25.13mA   -21.34mA   -31.48mA
-789.8mV  -15.79mA   -12.83mA   -20.82mA
-671mV    -9.112mA   -6.888mA   -12.56mA
-595.1mV  -5.416mA   -3.908mA   -7.721mA
-525.8mV  -2.773mA   -1.979mA   -3.977mA
-473mV    -1.423mA   -1.034mA   -1.892mA
-416.9mV  -598uA     -440.6uA   -667uA
-350.9mV  -165.9uA   -125.6uA   -147.6uA
-255.2mV  -14.7uA    -13.08uA   -8.885uA
2.2V      0A         0A         0A
[Pullup]
|   Voltage   I(typ)   I(min)   I(max)
-1.1V     2.095uA    3.229uA    944.4nA
233.2mV   -16.29uA   -16.25uA   -16.91uA
338.8mV   -120.6uA   -99.95uA   -166.3uA
441.1mV   -503uA     -412.9uA   -628.7uA
553.3mV   -1.314mA   -1.213mA   -1.423mA
691.9mV   -2.655mA   -2.748mA   -2.618mA
1.081V    -7.033mA   -8.079mA   -6.566mA
1.382V    -10.59mA   -12.16mA   -9.919mA
1.556V    -12.6mA    -14.28mA   -11.94mA
1.695V    -13.86mA   -15.55mA   -13.38mA
1.867V    -15.45mA   -16.71mA   -15.25mA
2.2V      -18.83mA   -18.71mA   -19.54mA
[POWER Clamp]
|   Voltage   I(typ)   I(min)   I(max)
-1.1V     3.036mA    3.636mA    2.186mA
-1.041V   2.347mA    2.931mA    1.626mA
-964.7mV  1.61mA     2.107mA    1.073mA
-902mV    1.133mA    1.526mA    717.2uA
-849.2mV  799.4uA    1.127mA    535.7uA
-773.3mV  421.1uA    665.4uA    384.1uA
-710.6mV  232.2uA    359.1uA    273.1uA
-657.8mV  146.8uA    178.8uA    190.7uA
-595.1mV  80.76uA    68.3uA     109.3uA
-486.2mV  16.71uA    10.19uA    20.94uA
-367.4mV  1.184uA    877.8nA    953.8nA
2.2V      0A         0A         0A
[Ramp]
|   typ   min   max
| 20% - 80%
dV/dt_r   137.82m/46.54p   137.38m/50.92p   147.02m/41.09p
dV/dt_f   224.68m/56.38p   207.32m/67.06p   255.27m/45.93p
| 25% - 75%
|dV/dt_r   114.85m/37.13p   114.48m/40.65p   122.52m/32.63p
|dV/dt_f   187.23m/44.89p   172.77m/53.38p   212.73m/36.49p
R_load = 50
[Rising Waveform]
R_fixture = 50
V_fixture = 0.0
|   Time   V(typ)   V(min)   V(max)
0s        257.9uV    214.8uV    190.4uV
58ps      -345.4uV   100uV      3.631mV
67ps      -420uV     -503.4uV   27.21mV
79ps      4.691mV    -776.5uV   79.87mV
106ps     91.97mV    15.54mV    179.7mV
124ps     149.4mV    69.52mV    212.8mV
144ps     189.2mV    133.1mV    231mV
176ps     217.6mV    194.3mV    241.5mV
218ps     227.7mV    221.8mV    244.6mV
433ps     230mV      229.2mV    245.2mV
[Falling Waveform]
R_fixture   = 50
V_fixture   = 1.1
V_fixture_min = 1.06
V_fixture_max = 1.17
|   Time   V(typ)   V(min)   V(max)
0s        1.1V       1.06V      1.17V
73ps      1.1V       1.06V      1.163V
95ps      1.09V      1.059V     1.019V
120ps     971.8mV    1.049V     872.5mV
143ps     867.2mV    969.1mV    802.9mV
165ps     803.4mV    883.3mV    771.4mV
200ps     753.9mV    791.8mV    752.3mV
245ps     733mV      740.3mV    746.1mV
308ps     726.7mV    719.6mV    744.7mV
433ps     725.5mV    714.5mV    744.5mV
[Rising Waveform]
R_fixture   = 50
V_fixture   = 1.1
V_fixture_min = 1.06
V_fixture_max = 1.17
|   Time   V(typ)   V(min)   V(max)
0s        725.4mV    714.2mV    744.5mV
53ps      721.6mV    710.6mV    750.9mV
62ps      728mV      707.7mV    788mV
75ps      774.7mV    716.3mV    894.4mV
91ps      876.6mV    773.7mV    992.3mV
110ps     962.6mV    873.9mV    1.064V
131ps     1.019V     947.7mV    1.11V
155ps     1.056V     996.7mV    1.139V
240ps     1.095V     1.052V     1.167V
433ps     1.1V       1.06V      1.17V
[Falling Waveform]
R_fixture = 50
V_fixture = 0.0
|   Time   V(typ)   V(min)   V(max)
0s        230mV      229.3mV    245.3mV
57ps      232.7mV    229.7mV    245.7mV
75ps      227.3mV    234.7mV    184.3mV
87ps      196.9mV    230mV      110mV
100ps     136.7mV    204.5mV    63.15mV
117ps     71.24mV    146.5mV    30.94mV
137ps     32.61mV    77.31mV    13.47mV
163ps     12.03mV    30.06mV    4.706mV
200ps     3.138mV    7.986mV    1.196mV
433ps     339.7uV    324.5uV    219.6uV
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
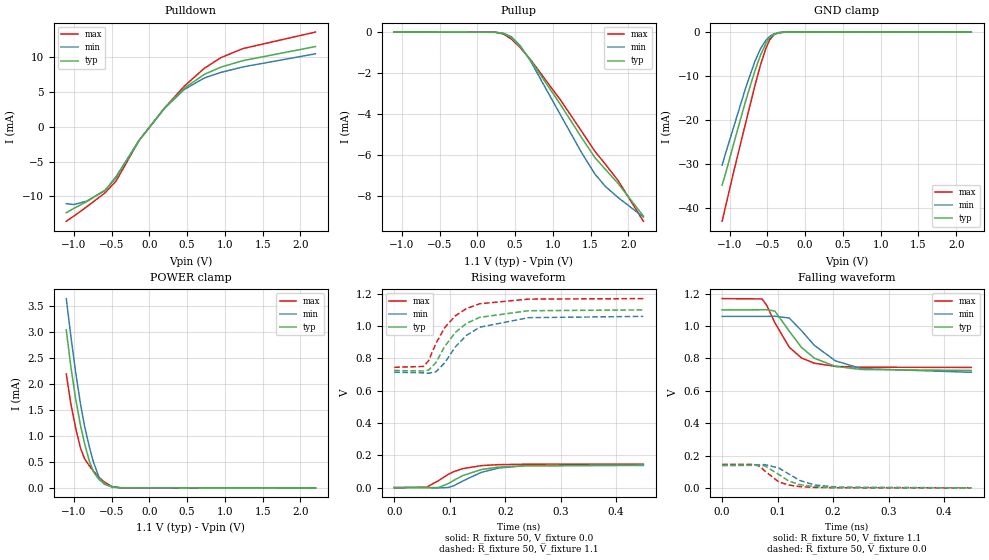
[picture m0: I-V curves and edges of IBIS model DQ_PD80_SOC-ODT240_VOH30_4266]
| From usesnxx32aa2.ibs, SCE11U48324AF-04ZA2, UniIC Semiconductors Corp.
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| DQ_PD80_SOC-ODT240_VOH30_4266
| (80 Ohm Pulldown, 240 Ohm System ODT Setting, VOH=VDDQ/3.0, 3200-4266Mbps)
[Model]   DQ_PD80_SOC-ODT240_VOH30_4266
Model_type   I/O
Vinl = 123.333mV
Vinh = 243.333mV
Vmeas = 183.333mV
Vref = 0.0mV
Cref = 0.0pF
Rref = 240.000Ohm
|   typ   min   max
|C_comp   0.797pF   0.747pF   0.847pF
C_comp_pullup   0.3985pF   0.3735pF   0.4235pF
C_comp_pulldown   0.3985pF   0.3735pF   0.4235pF
| Note: C_comp changes when the ODT circuit is enabled.
[Model Spec]
| Input threshold voltage corners
Vinl   0.1233V   0.1167V   0.1350V
Vinh   0.2433V   0.2367V   0.2550V
| Measurement voltage corners
Vmeas   0.1833V   0.1767V   0.1950V
| Timing spec test load voltage corners
Vref   0.0000V   0.0000V   0.0000V
| Dynamic Overshoot Parameters from LPDDR4 Specification
D_overshoot_ampl_h   0.30   NA   NA
D_overshoot_ampl_l   0.30   NA   NA
D_overshoot_area_h   0.1n   NA   NA
D_overshoot_area_l   0.1n   NA   NA
[Receiver Thresholds]
Vth   = 0.1833V
Vth_min  = 0.1800V
Vth_max  = 0.1866V
Vinh_ac  = 0.060V
Vinh_dc  = 0.060V
Vinl_ac  = -0.060V
Vinl_dc  = -0.060V
Tslew_ac = 5.000ns |Not specified, so set to high value
Threshold_sensitivity = 0.1667
Reference_supply Pullup_ref
[Voltage Range]   1.1000V   1.0600V   1.1700V
[Pullup Reference]   1.1000V   1.0600V   1.1700V
| Junction Temperature (Ambient temp is 35C typ 95C min -40C max)
[Temperature Range]   50.0   110.0   -40.0
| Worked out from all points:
|   slope of the pulldown table from 0 to 0.165 V, typ, clamps not added: 74.5 ohm
|   slope of the pullup table from 0 to 0.165 V, typ, clamps not added: 78.1 kohm
|   GND clamp passes 1 mA (typ) near -0.45 V on its own axis
|   POWER clamp passes 1 mA (typ) near -0.88 V on its own axis
|   rising waveform, R_fixture 50, V_fixture 0.0: 20-80 % time 55.6ps typ, 58.1ps min, 48.2ps max; typ from 0 V to 0.137 V
|   falling waveform, R_fixture 50, V_fixture 1.1: 20-80 % time 56.1ps typ, 66.8ps min, 45.7ps max; typ from 1.1 V to 0.726 V
|   rising waveform, R_fixture 50, V_fixture 1.1: 20-80 % time 55ps typ, 59.5ps min, 50.7ps max; typ from 0.725 V to 1.1 V
|   falling waveform, R_fixture 50, V_fixture 0.0: 20-80 % time 38.3ps typ, 45.8ps min, 33.6ps max; typ from 0.137 V to 0 V
[Pulldown]
|   Voltage   I(typ)   I(min)   I(max)
-1.1V     -12.33mA   -11.04mA   -13.56mA
-1.001V   -11.72mA   -11.16mA   -12.83mA
-832.7mV  -10.77mA   -10.68mA   -11.51mA
-585.2mV  -9.089mA   -9.146mA   -9.464mA
-440mV    -7.326mA   -7.142mA   -7.785mA
-136.4mV  -1.98mA    -1.983mA   -1.968mA
203.5mV   2.693mA    2.667mA    2.712mA
464.2mV   5.526mA    5.355mA    5.823mA
728.2mV   7.506mA    6.978mA    8.376mA
949.3mV   8.546mA    7.789mA    9.909mA
1.24V     9.472mA    8.571mA    11.2mA
2.2V      11.49mA    10.45mA    13.57mA
[GND Clamp]
|   Voltage   I(typ)   I(min)   I(max)
-1.1V     -34.88mA   -30.34mA   -43.13mA
-1.047V   -31.79mA   -27.25mA   -39.23mA
-944.9mV  -25.34mA   -21.53mA   -31.71mA
-789.8mV  -15.79mA   -12.83mA   -20.82mA
-667.7mV  -8.939mA   -6.742mA   -12.34mA
-591.8mV  -5.272mA   -3.798mA   -7.524mA
-519.2mV  -2.575mA   -1.835mA   -3.671mA
-469.7mV  -1.363mA   -988.1uA   -1.791mA
-413.6mV  -567.6uA   -417.6uA   -621uA
-350.9mV  -168uA     -125.9uA   -147.2uA
-265.1mV  -19.28uA   -16.78uA   -12.22uA
2.2V      0A         0A         0A
[Pullup]
|   Voltage   I(typ)   I(min)   I(max)
-1.1V     1.047uA    1.615uA    471.9nA
239.8mV   -9.375uA   -9.202uA   -9.98uA
348.7mV   -70.59uA   -58.02uA   -97.33uA
454.3mV   -284.8uA   -236.9uA   -350uA
569.8mV   -714uA     -668.5uA   -763.5uA
705.1mV   -1.361mA   -1.411mA   -1.342mA
1.098V    -3.512mA   -4.011mA   -3.291mA
1.385V    -5.165mA   -5.899mA   -4.852mA
1.556V    -6.109mA   -6.911mA   -5.805mA
1.695V    -6.689mA   -7.522mA   -6.437mA
1.867V    -7.391mA   -8.074mA   -7.248mA
2.2V      -8.971mA   -9.018mA   -9.226mA
[POWER Clamp]
|   Voltage   I(typ)   I(min)   I(max)
-1.1V     3.036mA    3.636mA    2.186mA
-1.041V   2.347mA    2.931mA    1.626mA
-977.9mV  1.724mA    2.242mA    1.161mA
-911.9mV  1.201mA    1.612mA    764.4uA
-855.8mV  838uA      1.172mA    552.2uA
-793.1mV  506.2uA    776.1uA    421uA
-740.3mV  306.1uA    494.5uA    324.3uA
-667.7mV  159.9uA    206.1uA    205.2uA
-598.4mV  83.67uA    71.97uA    113.1uA
-489.5mV  17.78uA    10.85uA    22.46uA
-377.3mV  1.49uA     1.056uA    1.228uA
2.2V      0A         0A         0A
[Ramp]
|   typ   min   max
| 20% - 80%
dV/dt_r   82.39m/55.64p   84.15m/58.10p   87.16m/48.19p
dV/dt_f   224.69m/56.17p   207.35m/66.76p   255.28m/45.76p
| 25% - 75%
|dV/dt_r   68.66m/44.24p   70.13m/46.28p   72.63m/38.23p
|dV/dt_f   187.24m/44.71p   172.79m/53.18p   212.73m/36.38p
R_load = 50
[Rising Waveform]
R_fixture = 50
V_fixture = 0.0
|   Time   V(typ)   V(min)   V(max)
0s        117.4uV    87.19uV    90.08uV
58ps      -507.7uV   133.5uV    2.071mV
80ps      623uV      -1.406mV   43.52mV
97ps      24.08mV    585.9uV    81.42mV
108ps     46.23mV    12.4mV     99.58mV
124ps     74.99mV    41.65mV    117.8mV
157ps     111.9mV    94.65mV    136.1mV
188ps     127.2mV    120.8mV    142.1mV
234ps     134.9mV    135.3mV    144.6mV
449ps     137.4mV    140.3mV    145.4mV
[Falling Waveform]
R_fixture   = 50
V_fixture   = 1.1
V_fixture_min = 1.06
V_fixture_max = 1.17
|   Time   V(typ)   V(min)   V(max)
0s        1.1V       1.06V      1.17V
72ps      1.101V     1.06V      1.168V
80ps      1.102V     1.06V      1.131V
95ps      1.093V     1.061V     1.021V
121ps     968.7mV    1.05V      869.2mV
143ps     868.4mV    972mV      803.2mV
166ps     801.9mV    881.6mV    770.6mV
204ps     751mV      785.5mV    751.3mV
251ps     731.8mV    736.9mV    745.8mV
449ps     725.5mV    714.4mV    744.5mV
[Rising Waveform]
R_fixture   = 50
V_fixture   = 1.1
V_fixture_min = 1.06
V_fixture_max = 1.17
|   Time   V(typ)   V(min)   V(max)
0s        725.4mV    714.2mV    744.5mV
53ps      721.8mV    710.7mV    750.2mV
62ps      727.7mV    707.9mV    785.9mV
75ps      772.8mV    716.3mV    891.6mV
91ps      873.7mV    772mV      990.3mV
110ps     960.2mV    870.5mV    1.063V
130ps     1.016V     941.8mV    1.108V
154ps     1.054V     992.9mV    1.138V
242ps     1.095V     1.052V     1.167V
449ps     1.1V       1.06V      1.17V
[Falling Waveform]
R_fixture = 50
V_fixture = 0.0
|   Time   V(typ)   V(min)   V(max)
0s        137.5mV    140.4mV    145.4mV
58ps      139.3mV    141.3mV    145.5mV
69ps      139.5mV    143.1mV    130.8mV
77ps      135.8mV    143.6mV    104mV
102ps     83.06mV    122.9mV    36.69mV
120ps     42.34mV    86.19mV    17.44mV
140ps     19.72mV    45.61mV    7.642mV
167ps     7.121mV    17.56mV    2.559mV
209ps     1.589mV    4.053mV    551.5uV
449ps     187.6uV    185.2uV    113.5uV
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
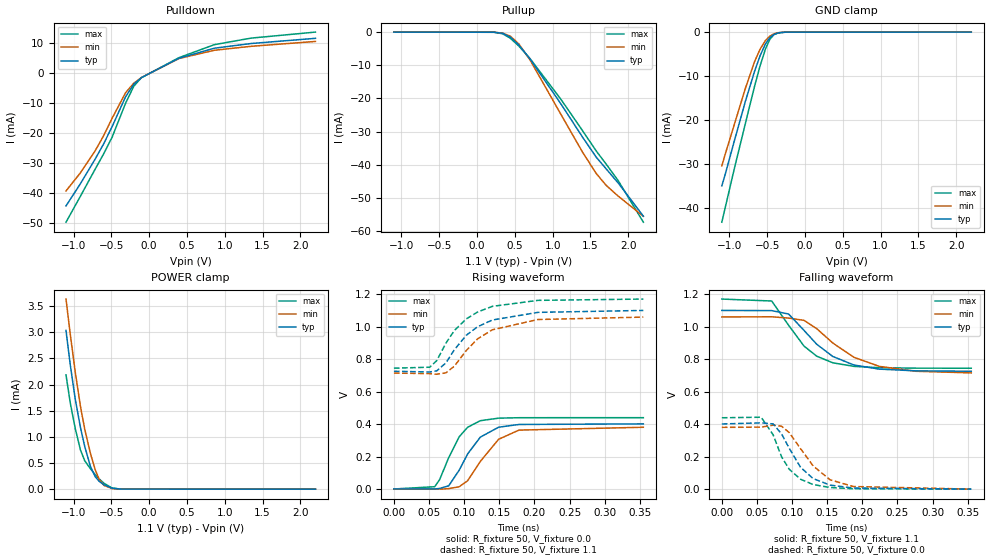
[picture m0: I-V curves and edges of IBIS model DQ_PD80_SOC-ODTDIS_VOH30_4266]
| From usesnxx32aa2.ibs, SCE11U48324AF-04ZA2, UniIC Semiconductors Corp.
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| DQ_PD80_SOC-ODTDIS_VOH30_4266
| (80 Ohm Pulldown, SOC ODT disabled setting, VOH=VDDQ/3.0 cal. point, 3200-4266Mbps)
[Model]   DQ_PD80_SOC-ODTDIS_VOH30_4266
Model_type   I/O
Vinl = 123.333mV
Vinh = 243.333mV
Vmeas = 183.333mV
Vref = 0.0mV
Cref = 0.0pF
|   typ   min   max
|C_comp   0.797pF   0.747pF   0.847pF
C_comp_pullup   0.3985pF   0.3735pF   0.4235pF
C_comp_pulldown   0.3985pF   0.3735pF   0.4235pF
| Note: C_comp changes when the ODT circuit is enabled.
[Model Spec]
| Input threshold voltage corners
Vinl   0.1233V   0.1167V   0.1350V
Vinh   0.2433V   0.2367V   0.2550V
| Measurement voltage corners
Vmeas   0.1833V   0.1767V   0.1950V
| Timing spec test load voltage corners
Vref   0.0000V   0.0000V   0.0000V
| Dynamic Overshoot Parameters from LPDDR4 Specification
D_overshoot_ampl_h   0.30   NA   NA
D_overshoot_ampl_l   0.30   NA   NA
D_overshoot_area_h   0.1n   NA   NA
D_overshoot_area_l   0.1n   NA   NA
[Receiver Thresholds]
Vth   = 0.1833V
Vth_min  = 0.1800V
Vth_max  = 0.1866V
Vinh_ac  = 0.060V
Vinh_dc  = 0.060V
Vinl_ac  = -0.060V
Vinl_dc  = -0.060V
Tslew_ac = 5.000ns |Not specified, so set to high value
Threshold_sensitivity = 0.1667
Reference_supply Pullup_ref
[Voltage Range]   1.1000V   1.0600V   1.1700V
[Pullup Reference]   1.1000V   1.0600V   1.1700V
| Junction Temperature (Ambient temp is 35C typ 95C min -40C max)
[Temperature Range]   50.0   110.0   -40.0
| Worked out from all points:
|   slope of the pulldown table from 0 to 0.165 V, typ, clamps not added: 73.8 ohm
|   slope of the pullup table from 0 to 0.165 V, typ, clamps not added: 13 kohm
|   GND clamp passes 1 mA (typ) near -0.45 V on its own axis
|   POWER clamp passes 1 mA (typ) near -0.88 V on its own axis
|   rising waveform, R_fixture 50, V_fixture 0.0: 20-80 % time 34.7ps typ, 39ps min, 29.9ps max; typ from 0.001 V to 0.401 V
|   falling waveform, R_fixture 50, V_fixture 1.1: 20-80 % time 57.3ps typ, 68ps min, 46.6ps max; typ from 1.1 V to 0.726 V
|   rising waveform, R_fixture 50, V_fixture 1.1: 20-80 % time 52.9ps typ, 54ps min, 50.4ps max; typ from 0.725 V to 1.1 V
|   falling waveform, R_fixture 50, V_fixture 0.0: 20-80 % time 37.1ps typ, 43.4ps min, 32.2ps max; typ from 0.402 V to 0.001 V
[Pulldown]
|   Voltage   I(typ)   I(min)   I(max)
-1.1V     -44.43mA   -39.43mA   -49.86mA
-915.2mV  -37.26mA   -33.59mA   -41.47mA
-717.2mV  -28.93mA   -26.17mA   -32.3mA
-605mV    -23.87mA   -21.13mA   -27.21mA
-489.5mV  -17.95mA   -15.17mA   -21.47mA
-311.3mV  -7.971mA   -6.634mA   -10.14mA
-202.4mV  -3.802mA   -3.463mA   -4.468mA
-103.4mV  -1.646mA   -1.602mA   -1.673mA
394.9mV   4.856mA    4.742mA    5.045mA
863.5mV   8.193mA    7.508mA    9.384mA
1.349V    9.758mA    8.824mA    11.56mA
2.2V      11.49mA    10.45mA    13.57mA
[GND Clamp]
|   Voltage   I(typ)   I(min)   I(max)
-1.1V     -34.88mA   -30.35mA   -43.13mA
-1.057V   -32.39mA   -27.81mA   -39.96mA
-938.3mV  -24.92mA   -21.15mA   -31.24mA
-789.8mV  -15.79mA   -12.83mA   -20.82mA
-667.7mV  -8.939mA   -6.743mA   -12.34mA
-595.1mV  -5.416mA   -3.908mA   -7.721mA
-522.5mV  -2.673mA   -1.905mA   -3.824mA
-466.4mV  -1.298mA   -943.6uA   -1.694mA
-413.6mV  -564.9uA   -417.5uA   -621.4uA
-354.2mV  -178.1uA   -134.6uA   -160.4uA
-248.6mV  -12.07uA   -10.97uA   -7.149uA
2.2V      0A         0A         0A
[Pullup]
|   Voltage   I(typ)   I(min)   I(max)
-1.1V     6.284uA    9.684uA    2.832uA
226.6mV   -42.1uA    -43.38uA   -42.76uA
338.8mV   -362.1uA   -299.2uA   -496.7uA
441.1mV   -1.492mA   -1.225mA   -1.867mA
553.3mV   -3.885mA   -3.58mA    -4.215mA
701.8mV   -8.13mA    -8.428mA   -8.01mA
1.108V    -21.59mA   -24.73mA   -20.21mA
1.398V    -31.73mA   -36.27mA   -29.78mA
1.576V    -37.67mA   -42.59mA   -35.81mA
1.708V    -41.21mA   -46.19mA   -39.78mA
1.867V    -45.46mA   -49.42mA   -44.76mA
2.2V      -55.46mA   -55.5mA    -57.28mA
[POWER Clamp]
|   Voltage   I(typ)   I(min)   I(max)
-1.1V     3.036mA    3.636mA    2.186mA
-1.044V   2.383mA    2.969mA    1.654mA
-977.9mV  1.724mA    2.242mA    1.161mA
-908.6mV  1.178mA    1.583mA    748.7uA
-852.5mV  818.6uA    1.149mA    543.7uA
-776.6mV  434.2uA    683.6uA    390.2uA
-713.9mV  239.3uA    373.1uA    278.6uA
-661.1mV  151.1uA    187.6uA    195.5uA
-598.4mV  83.65uA    71.97uA    113.1uA
-489.5mV  17.82uA    10.82uA    22.5uA
-377.3mV  1.486uA    1.061uA    1.229uA
2.2V      0A         0A         0A
[Ramp]
|   typ   min   max
| 20% - 80%
dV/dt_r   240.38m/34.71p   227.94m/38.97p   263.47m/29.90p
dV/dt_f   224.50m/57.31p   206.45m/68.04p   255.27m/46.57p
| 25% - 75%
|dV/dt_r   200.32m/27.63p   189.95m/30.97p   219.55m/23.77p
|dV/dt_f   187.09m/45.61p   172.04m/54.13p   212.73m/37.02p
R_load = 50
[Rising Waveform]
R_fixture = 50
V_fixture = 0.0
|   Time   V(typ)   V(min)   V(max)
0s        806uV      708.5uV    581.8uV
58ps      643uV      -264.5uV   14.47mV
65ps      3.629mV    -603.3uV   57.7mV
78ps      20.02mV    2.787mV    193.8mV
93ps      116.9mV    14.36mV    322.7mV
105ps     216.8mV    51.61mV    380.8mV
123ps     320mV      170.4mV    421mV
149ps     381mV      306.7mV    436.7mV
178ps     397.8mV    363.1mV    439.4mV
355ps     401.4mV    380.6mV    439.7mV
[Falling Waveform]
R_fixture   = 50
V_fixture   = 1.1
V_fixture_min = 1.06
V_fixture_max = 1.17
|   Time   V(typ)   V(min)   V(max)
0s        1.1V       1.06V      1.17V
71ps      1.099V     1.061V     1.158V
95ps      1.078V     1.053V     1.009V
117ps     977mV      1.039V     880.5mV
135ps     892.2mV    988.1mV    818.8mV
158ps     816.6mV    899.4mV    777.8mV
188ps     764.4mV    811.9mV    756mV
224ps     739mV      756mV      747.7mV
276ps     728.5mV    725.8mV    745mV
355ps     725.8mV    715.9mV    744.6mV
[Rising Waveform]
R_fixture   = 50
V_fixture   = 1.1
V_fixture_min = 1.06
V_fixture_max = 1.17
|   Time   V(typ)   V(min)   V(max)
0s        725.4mV    714.2mV    744.5mV
51ps      721mV      710.9mV    750.3mV
61ps      727.9mV    707.1mV    791.2mV
74ps      777.2mV    715.9mV    898.6mV
86ps      857.9mV    756.8mV    976.2mV
103ps     947.3mV    853.1mV    1.048V
119ps     999.3mV    924.8mV    1.09V
140ps     1.041V     980.7mV    1.125V
205ps     1.088V     1.044V     1.162V
355ps     1.1V       1.059V     1.17V
[Falling Waveform]
R_fixture = 50
V_fixture = 0.0
|   Time   V(typ)   V(min)   V(max)
0s        401.6mV    380.8mV    439.8mV
56ps      408.6mV    382.1mV    443.2mV
73ps      401.9mV    394.3mV    335mV
85ps      340.7mV    387.8mV    199.8mV
96ps      251.5mV    348.4mV    122.9mV
112ps     135.1mV    249.8mV    61.81mV
130ps     65.52mV    143.5mV    28.97mV
154ps     25.56mV    58.44mV    10.85mV
187ps     7.571mV    17.05mV    3.16mV
355ps     879.9uV    834.9uV    608.6uV
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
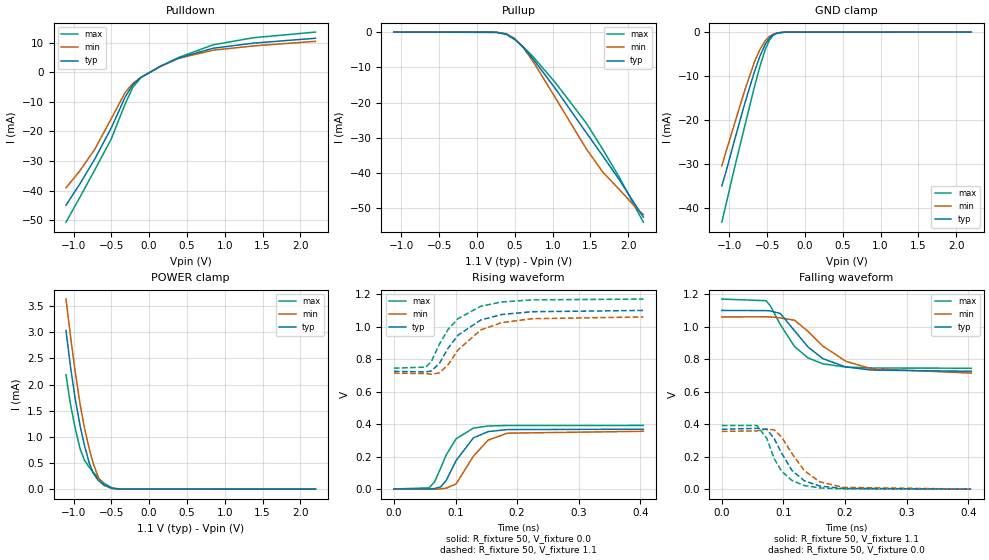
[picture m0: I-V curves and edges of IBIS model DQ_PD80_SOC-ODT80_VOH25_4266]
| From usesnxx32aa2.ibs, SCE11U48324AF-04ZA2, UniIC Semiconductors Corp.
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| DQ_PD80_SOC-ODT80_VOH25_4266
| (80 Ohm Pulldown, 80 Ohm System ODT Setting, VOH=VDDQ/2.5, 3200-4266Mbps)
[Model]   DQ_PD80_SOC-ODT80_VOH25_4266
Model_type   I/O
Vinl = 160.000mV
Vinh = 280.000mV
Vmeas = 220.000mV
Vref = 0.0mV
Cref = 0.0pF
Rref = 80.000Ohm
|   typ   min   max
|C_comp   0.797pF   0.747pF   0.847pF
C_comp_pullup   0.3985pF   0.3735pF   0.4235pF
C_comp_pulldown   0.3985pF   0.3735pF   0.4235pF
| Note: C_comp changes when the ODT circuit is enabled.
[Model Spec]
| Input threshold voltage corners
Vinl   0.1600V   0.1520V   0.1740V
Vinh   0.2800V   0.2720V   0.2940V
| Measurement voltage corners
Vmeas   0.2200V   0.2120V   0.2340V
| Timing spec test load voltage corners
Vref   0.0000V   0.0000V   0.0000V
| Dynamic Overshoot Parameters from LPDDR4 Specification
D_overshoot_ampl_h   0.30   NA   NA
D_overshoot_ampl_l   0.30   NA   NA
D_overshoot_area_h   0.1n   NA   NA
D_overshoot_area_l   0.1n   NA   NA
[Receiver Thresholds]
Vth   = 0.2200V
Vth_min  = 0.2167V
Vth_max  = 0.2233V
Vinh_ac  = 0.060V
Vinh_dc  = 0.060V
Vinl_ac  = -0.060V
Vinl_dc  = -0.060V
Tslew_ac = 5.000ns |Not specified, so set to high value
Threshold_sensitivity = 0.2000
Reference_supply Pullup_ref
[Voltage Range]   1.1000V   1.0600V   1.1700V
[Pullup Reference]   1.1000V   1.0600V   1.1700V
| Junction Temperature (Ambient temp is 35C typ 95C min -40C max)
[Temperature Range]   50.0   110.0   -40.0
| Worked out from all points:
|   slope of the pulldown table from 0 to 0.165 V, typ, clamps not added: 73.8 ohm
|   slope of the pullup table from 0 to 0.165 V, typ, clamps not added: 17.4 kohm
|   GND clamp passes 1 mA (typ) near -0.45 V on its own axis
|   POWER clamp passes 1 mA (typ) near -0.88 V on its own axis
|   rising waveform, R_fixture 50, V_fixture 0.0: 20-80 % time 34.6ps typ, 38.4ps min, 31.4ps max; typ from 0.001 V to 0.369 V
|   falling waveform, R_fixture 50, V_fixture 1.1: 20-80 % time 57.1ps typ, 68.5ps min, 46.3ps max; typ from 1.1 V to 0.726 V
|   rising waveform, R_fixture 50, V_fixture 1.1: 20-80 % time 54ps typ, 55.8ps min, 50.4ps max; typ from 0.725 V to 1.1 V
|   falling waveform, R_fixture 50, V_fixture 0.0: 20-80 % time 37.5ps typ, 43.4ps min, 32ps max; typ from 0.369 V to 0.001 V
[Pulldown]
|   Voltage   I(typ)   I(min)   I(max)
-1.1V     -44.88mA   -39.03mA   -50.64mA
-918.5mV  -37.79mA   -33.36mA   -42.33mA
-720.5mV  -29.38mA   -26.05mA   -33.04mA
-502.7mV  -18.88mA   -15.74mA   -22.6mA
-317.9mV  -8.372mA   -6.836mA   -10.74mA
-215.6mV  -4.22mA    -3.747mA   -5.086mA
-110mV    -1.769mA   -1.706mA   -1.818mA
150.7mV   2.026mA    2.012mA    2.028mA
391.6mV   4.822mA    4.711mA    5.007mA
843.7mV   8.104mA    7.438mA    9.251mA
1.378V    9.832mA    8.891mA    11.66mA
2.2V      11.49mA    10.45mA    13.57mA
[GND Clamp]
|   Voltage   I(typ)   I(min)   I(max)
-1.1V     -34.88mA   -30.33mA   -43.14mA
-1.05V    -32mA      -27.43mA   -39.48mA
-935mV    -24.72mA   -20.96mA   -31.01mA
-793.1mV  -15.99mA   -13.01mA   -21.07mA
-667.7mV  -8.943mA   -6.741mA   -12.35mA
-595.1mV  -5.417mA   -3.907mA   -7.727mA
-522.5mV  -2.672mA   -1.905mA   -3.827mA
-469.7mV  -1.359mA   -986.5uA   -1.792mA
-416.9mV  -598.5uA   -440.5uA   -665.6uA
-360.8mV  -205.1uA   -154.9uA   -188.3uA
-265.1mV  -19.43uA   -16.83uA   -12.58uA
2.2V      0A         0A         0A
[Pullup]
|   Voltage   I(typ)   I(min)   I(max)
-1.1V     4.112uA    7.441uA    1.363uA
259.6mV   -60.6uA    -59.72uA   -61.4uA
388.3mV   -575.8uA   -480uA     -688.1uA
500.5mV   -2.043mA   -1.831mA   -2.145mA
609.4mV   -4.304mA   -4.306mA   -4.133mA
751.3mV   -7.908mA   -8.648mA   -7.214mA
1.042V    -16.2mA    -18.85mA   -14.5mA
1.444V    -28.51mA   -33.07mA   -25.79mA
1.662V    -35.07mA   -39.67mA   -33.22mA
1.887V    -42.03mA   -44.75mA   -41.35mA
2.114V    -49.67mA   -50.08mA   -50.51mA
2.2V      -52.46mA   -51.75mA   -53.91mA
[POWER Clamp]
|   Voltage   I(typ)   I(min)   I(max)
-1.1V     3.036mA    3.636mA    2.186mA
-1.041V   2.347mA    2.931mA    1.626mA
-977.9mV  1.724mA    2.242mA    1.161mA
-911.9mV  1.201mA    1.612mA    765uA
-855.8mV  838.1uA    1.172mA    552.2uA
-793.1mV  506.1uA    776.1uA    421uA
-740.3mV  306.1uA    494.5uA    324.3uA
-667.7mV  159.9uA    206.1uA    205.2uA
-598.4mV  83.7uA     71.95uA    113.1uA
-489.5mV  17.77uA    10.84uA    22.48uA
-380.6mV  1.61uA     1.136uA    1.335uA
2.2V      0A         0A         0A
[Ramp]
|   typ   min   max
| 20% - 80%
dV/dt_r   220.69m/34.60p   213.04m/38.43p   234.79m/31.41p
dV/dt_f   224.66m/57.13p   207.18m/68.53p   255.29m/46.30p
| 25% - 75%
|dV/dt_r   183.91m/27.55p   177.54m/30.60p   195.66m/24.94p
|dV/dt_f   187.22m/45.46p   172.65m/54.51p   212.74m/36.82p
R_load = 50
[Rising Waveform]
R_fixture = 50
V_fixture = 0.0
|   Time   V(typ)   V(min)   V(max)
0s        835.6uV    685.5uV    611.7uV
57ps      431.4uV    -59.04uV   7.433mV
66ps      3.407mV    -506.3uV   44.5mV
76ps      13.4mV     1.413mV    129.8mV
85ps      53.46mV    5.833mV    210.9mV
101ps     176mV      31.53mV    309.7mV
129ps     315mV      202.6mV    375.4mV
153ps     354mV      301.3mV    388.4mV
184ps     366.4mV    344.3mV    391.5mV
405ps     368.7mV    355.8mV    391.9mV
[Falling Waveform]
R_fixture   = 50
V_fixture   = 1.1
V_fixture_min = 1.06
V_fixture_max = 1.17
|   Time   V(typ)   V(min)   V(max)
0s        1.1V       1.06V      1.17V
72ps      1.099V     1.061V     1.16V
79ps      1.097V     1.06V      1.127V
95ps      1.081V     1.054V     1.013V
118ps     975.3mV    1.04V      878.1mV
140ps     874.7mV    971.3mV    807.8mV
164ps     803.7mV    880.8mV    771.8mV
201ps     752.5mV    787.8mV    751.9mV
243ps     733.3mV    740.9mV    746.2mV
405ps     725.6mV    714.7mV    744.5mV
[Rising Waveform]
R_fixture   = 50
V_fixture   = 1.1
V_fixture_min = 1.06
V_fixture_max = 1.17
|   Time   V(typ)   V(min)   V(max)
0s        725.4mV    714.2mV    744.5mV
52ps      721.1mV    710.6mV    750.9mV
61ps      727.6mV    707.2mV    787.1mV
74ps      775.1mV    715.7mV    893.7mV
88ps      867.3mV    765.6mV    983.1mV
104ps     947.5mV    856.7mV    1.049V
141ps     1.041V     980mV      1.126V
175ps     1.075V     1.025V     1.152V
224ps     1.092V     1.049V     1.165V
405ps     1.1V       1.06V      1.17V
[Falling Waveform]
R_fixture = 50
V_fixture = 0.0
|   Time   V(typ)   V(min)   V(max)
0s        368.8mV    355.9mV    392mV
57ps      374.8mV    359.2mV    392.5mV
73ps      367.9mV    371mV      313.1mV
85ps      312.1mV    365.1mV    188.5mV
97ps      222.6mV    321.4mV    111mV
114ps     115.1mV    218.9mV    53.55mV
134ps     52mV       114.5mV    23.08mV
159ps     19.75mV    45.44mV    8.412mV
197ps     5.106mV    11.64mV    2.214mV
405ps     887.6uV    760.7uV    634uV
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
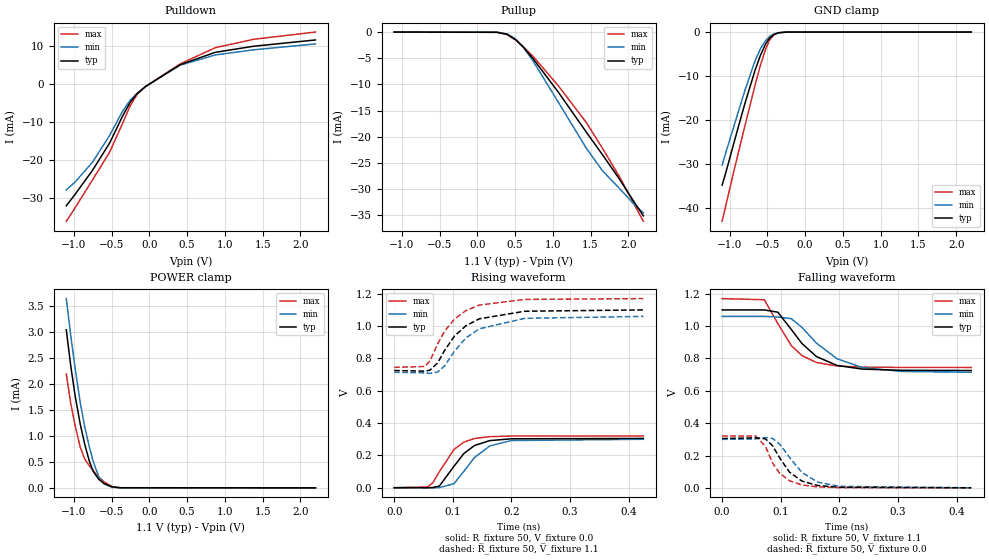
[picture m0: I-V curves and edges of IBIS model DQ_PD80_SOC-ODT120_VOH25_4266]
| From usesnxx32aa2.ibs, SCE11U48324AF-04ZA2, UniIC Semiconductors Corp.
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| DQ_PD80_SOC-ODT120_VOH25_4266
| (80 Ohm Pulldown, 120 Ohm System ODT Setting, VOH=VDDQ/2.5, 3200-4266Mbps)
[Model]   DQ_PD80_SOC-ODT120_VOH25_4266
Model_type   I/O
Vinl = 160.000mV
Vinh = 280.000mV
Vmeas = 220.000mV
Vref = 0.0mV
Cref = 0.0pF
Rref = 120.000Ohm
|   typ   min   max
|C_comp   0.797pF   0.747pF   0.847pF
C_comp_pullup   0.3985pF   0.3735pF   0.4235pF
C_comp_pulldown   0.3985pF   0.3735pF   0.4235pF
| Note: C_comp changes when the ODT circuit is enabled.
[Model Spec]
| Input threshold voltage corners
Vinl   0.1600V   0.1520V   0.1740V
Vinh   0.2800V   0.2720V   0.2940V
| Measurement voltage corners
Vmeas   0.2200V   0.2120V   0.2340V
| Timing spec test load voltage corners
Vref   0.0000V   0.0000V   0.0000V
| Dynamic Overshoot Parameters from LPDDR4 Specification
D_overshoot_ampl_h   0.30   NA   NA
D_overshoot_ampl_l   0.30   NA   NA
D_overshoot_area_h   0.1n   NA   NA
D_overshoot_area_l   0.1n   NA   NA
[Receiver Thresholds]
Vth   = 0.2200V
Vth_min  = 0.2167V
Vth_max  = 0.2233V
Vinh_ac  = 0.060V
Vinh_dc  = 0.060V
Vinl_ac  = -0.060V
Vinl_dc  = -0.060V
Tslew_ac = 5.000ns |Not specified, so set to high value
Threshold_sensitivity = 0.2000
Reference_supply Pullup_ref
[Voltage Range]   1.1000V   1.0600V   1.1700V
[Pullup Reference]   1.1000V   1.0600V   1.1700V
| Junction Temperature (Ambient temp is 35C typ 95C min -40C max)
[Temperature Range]   50.0   110.0   -40.0
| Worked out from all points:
|   slope of the pulldown table from 0 to 0.165 V, typ, clamps not added: 74.1 ohm
|   slope of the pullup table from 0 to 0.165 V, typ, clamps not added: 26.3 kohm
|   GND clamp passes 1 mA (typ) near -0.45 V on its own axis
|   POWER clamp passes 1 mA (typ) near -0.88 V on its own axis
|   rising waveform, R_fixture 50, V_fixture 0.0: 20-80 % time 39.5ps typ, 43.2ps min, 35.9ps max; typ from 0.001 V to 0.305 V
|   falling waveform, R_fixture 50, V_fixture 1.1: 20-80 % time 56.7ps typ, 67.8ps min, 46.1ps max; typ from 1.1 V to 0.726 V
|   rising waveform, R_fixture 50, V_fixture 1.1: 20-80 % time 54.4ps typ, 57.5ps min, 50.4ps max; typ from 0.725 V to 1.1 V
|   falling waveform, R_fixture 50, V_fixture 0.0: 20-80 % time 37.4ps typ, 43.9ps min, 32.1ps max; typ from 0.305 V to 0.001 V
[Pulldown]
|   Voltage   I(typ)   I(min)   I(max)
-1.1V     -32.12mA   -27.95mA   -36.19mA
-984.5mV  -29.13mA   -25.9mA    -32.69mA
-753.5mV  -22.82mA   -20.66mA   -25.33mA
-525.8mV  -15.61mA   -13.62mA   -18.02mA
-357.5mV  -8.657mA   -7.351mA   -10.57mA
-251.9mV  -4.83mA    -4.329mA   -5.74mA
-162.8mV  -2.65mA    -2.538mA   -2.836mA
-50.6mV   -762.4uA   -752uA     -748.7uA
408.1mV   4.988mA    4.865mA    5.197mA
873.4mV   8.237mA    7.542mA    9.449mA
1.382V    9.84mA     8.898mA    11.67mA
2.2V      11.49mA    10.45mA    13.57mA
[GND Clamp]
|   Voltage   I(typ)   I(min)   I(max)
-1.1V     -34.89mA   -30.33mA   -43.14mA
-1.05V    -32mA      -27.43mA   -39.48mA
-938.3mV  -24.93mA   -21.15mA   -31.25mA
-799.7mV  -16.38mA   -13.37mA   -21.53mA
-667.7mV  -8.943mA   -6.741mA   -12.35mA
-595.1mV  -5.418mA   -3.907mA   -7.725mA
-522.5mV  -2.675mA   -1.905mA   -3.826mA
-469.7mV  -1.362mA   -990.9uA   -1.792mA
-416.9mV  -600.1uA   -443.6uA   -665.9uA
-357.5mV  -191.2uA   -144.8uA   -174.2uA
-251.9mV  -13.33uA   -12.15uA   -7.885uA
2.2V      0A         0A         0A
[Pullup]
|   Voltage   I(typ)   I(min)   I(max)
-1.1V     2.741uA    4.961uA    908.6nA
262.9mV   -43.18uA   -41.87uA   -44.29uA
394.9mV   -422.2uA   -350.8uA   -502.1uA
510.4mV   -1.485mA   -1.346mA   -1.542mA
612.7mV   -2.934mA   -2.947mA   -2.81mA
738.1mV   -5.063mA   -5.512mA   -4.627mA
1.075V    -11.52mA   -13.45mA   -10.3mA
1.444V    -19.13mA   -22.2mA    -17.29mA
1.659V    -23.46mA   -26.53mA   -22.23mA
1.887V    -28.2mA    -29.96mA   -27.75mA
2.094V    -32.85mA   -33.2mA    -33.38mA
2.2V      -35.14mA   -34.58mA   -36.18mA
[POWER Clamp]
|   Voltage   I(typ)   I(min)   I(max)
-1.1V     3.036mA    3.636mA    2.186mA
-1.041V   2.347mA    2.931mA    1.626mA
-984.5mV  1.784mA    2.311mA    1.206mA
-915.2mV  1.224mA    1.64mA     781.3uA
-855.8mV  838.1uA    1.172mA    552.4uA
-796.4mV  521.3uA    795.3uA    427.2uA
-743.6mV  316uA      510.8uA    330.1uA
-671mV    164.5uA    215.9uA    210.2uA
-598.4mV  83.65uA    71.99uA    113uA
-496.1mV  20.14uA    12.33uA    25.74uA
-387.2mV  1.891uA    1.31uA     1.604uA
2.2V      0A         0A         0A
[Ramp]
|   typ   min   max
| 20% - 80%
dV/dt_r   182.65m/39.45p   179.71m/43.17p   191.94m/35.91p
dV/dt_f   224.68m/56.69p   207.27m/67.76p   255.28m/46.06p
| 25% - 75%
|dV/dt_r   152.21m/31.42p   149.76m/34.33p   159.95m/28.55p
|dV/dt_f   187.24m/45.11p   172.72m/53.95p   212.73m/36.61p
R_load = 50
[Rising Waveform]
R_fixture = 50
V_fixture = 0.0
|   Time   V(typ)   V(min)   V(max)
0s        553.6uV    448uV      407.3uV
57ps      220.8uV    5.443uV    4.907mV
66ps      1.808mV    -368.5uV   31.6mV
77ps      10.35mV    996.5uV    99.24mV
102ps     133mV      25.31mV    237.3mV
119ps     212.5mV    102.4mV    282.4mV
137ps     261.4mV    187.4mV    304.7mV
163ps     291.8mV    258.9mV    316.3mV
200ps     303mV      292.2mV    319.8mV
425ps     305mV      300mV      320.3mV
[Falling Waveform]
R_fixture   = 50
V_fixture   = 1.1
V_fixture_min = 1.06
V_fixture_max = 1.17
|   Time   V(typ)   V(min)   V(max)
0s        1.1V       1.06V      1.17V
72ps      1.1V       1.06V      1.163V
95ps      1.086V     1.056V     1.016V
118ps     979.2mV    1.046V     879.7mV
136ps     892.9mV    992.5mV    818.1mV
161ps     811.6mV    894.5mV    775.2mV
196ps     757mV      798.2mV    753.4mV
239ps     734.4mV    744.1mV    746.5mV
306ps     726.8mV    719.8mV    744.7mV
425ps     725.5mV    714.5mV    744.5mV
[Rising Waveform]
R_fixture   = 50
V_fixture   = 1.1
V_fixture_min = 1.06
V_fixture_max = 1.17
|   Time   V(typ)   V(min)   V(max)
0s        725.4mV    714.2mV    744.5mV
52ps      721.4mV    710.7mV    750mV
61ps      727.3mV    707.5mV    784.1mV
74ps      772.2mV    715.6mV    889.5mV
86ps      849.7mV    753.4mV    969mV
103ps     939.2mV    845.6mV    1.044V
122ps     1.001V     926.1mV    1.095V
145ps     1.045V     983.1mV    1.13V
223ps     1.092V     1.048V     1.165V
425ps     1.1V       1.06V      1.17V
[Falling Waveform]
R_fixture = 50
V_fixture = 0.0
|   Time   V(typ)   V(min)   V(max)
0s        305.1mV    300.1mV    320.4mV
57ps      309.3mV    302.6mV    321.2mV
74ps      303.3mV    311.6mV    256.2mV
86ps      260.7mV    305.9mV    154.1mV
98ps      186.9mV    271.3mV    91.04mV
115ps     96.89mV    188.6mV    44.17mV
136ps     42.25mV    95.7mV     18.26mV
163ps     14.93mV    35.61mV    6.165mV
200ps     3.976mV    9.52mV     1.667mV
425ps     624.3uV    545.4uV    436.6uV
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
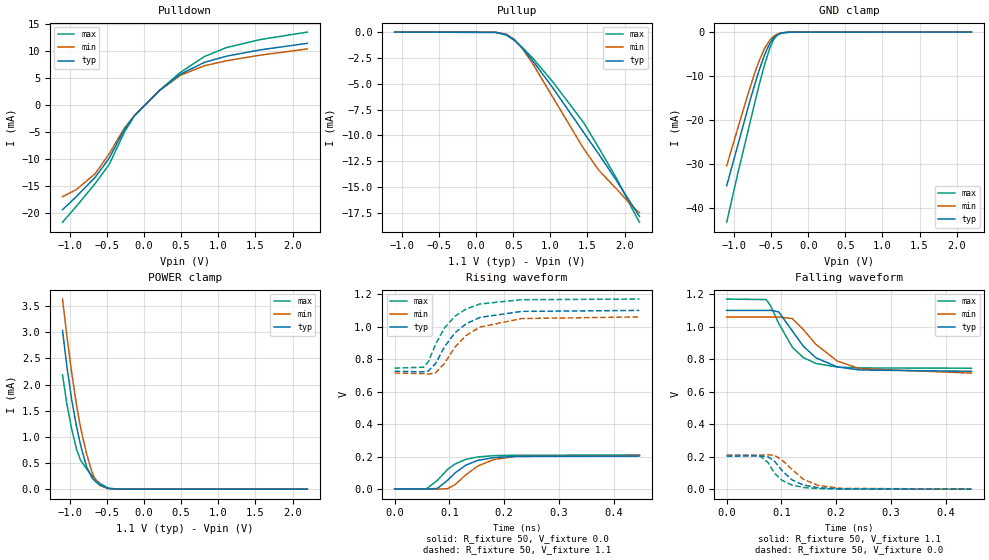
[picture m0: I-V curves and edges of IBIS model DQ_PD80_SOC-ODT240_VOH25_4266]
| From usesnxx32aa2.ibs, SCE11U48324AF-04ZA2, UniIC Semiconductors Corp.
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| DQ_PD80_SOC-ODT240_VOH25_4266
| (80 Ohm Pulldown, 240 Ohm System ODT Setting, VOH=VDDQ/2.5, 3200-4266Mbps)
[Model]   DQ_PD80_SOC-ODT240_VOH25_4266
Model_type   I/O
Vinl = 160.000mV
Vinh = 280.000mV
Vmeas = 220.000mV
Vref = 0.0mV
Cref = 0.0pF
Rref = 240.000Ohm
|   typ   min   max
|C_comp   0.797pF   0.747pF   0.847pF
C_comp_pullup   0.3985pF   0.3735pF   0.4235pF
C_comp_pulldown   0.3985pF   0.3735pF   0.4235pF
| Note: C_comp changes when the ODT circuit is enabled.
[Model Spec]
| Input threshold voltage corners
Vinl   0.1600V   0.1520V   0.1740V
Vinh   0.2800V   0.2720V   0.2940V
| Measurement voltage corners
Vmeas   0.2200V   0.2120V   0.2340V
| Timing spec test load voltage corners
Vref   0.0000V   0.0000V   0.0000V
| Dynamic Overshoot Parameters from LPDDR4 Specification
D_overshoot_ampl_h   0.30   NA   NA
D_overshoot_ampl_l   0.30   NA   NA
D_overshoot_area_h   0.1n   NA   NA
D_overshoot_area_l   0.1n   NA   NA
[Receiver Thresholds]
Vth   = 0.2200V
Vth_min  = 0.2167V
Vth_max  = 0.2233V
Vinh_ac  = 0.060V
Vinh_dc  = 0.060V
Vinl_ac  = -0.060V
Vinl_dc  = -0.060V
Tslew_ac = 5.000ns |Not specified, so set to high value
Threshold_sensitivity = 0.2000
Reference_supply Pullup_ref
[Voltage Range]   1.1000V   1.0600V   1.1700V
[Pullup Reference]   1.1000V   1.0600V   1.1700V
| Junction Temperature (Ambient temp is 35C typ 95C min -40C max)
[Temperature Range]   50.0   110.0   -40.0
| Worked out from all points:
|   slope of the pulldown table from 0 to 0.165 V, typ, clamps not added: 74.4 ohm
|   slope of the pullup table from 0 to 0.165 V, typ, clamps not added: 53 kohm
|   GND clamp passes 1 mA (typ) near -0.45 V on its own axis
|   POWER clamp passes 1 mA (typ) near -0.88 V on its own axis
|   rising waveform, R_fixture 50, V_fixture 0.0: 20-80 % time 46.5ps typ, 50.7ps min, 42.8ps max; typ from 0 V to 0.203 V
|   falling waveform, R_fixture 50, V_fixture 1.1: 20-80 % time 56.2ps typ, 67.2ps min, 45.9ps max; typ from 1.1 V to 0.726 V
|   rising waveform, R_fixture 50, V_fixture 1.1: 20-80 % time 54.8ps typ, 58.9ps min, 50.7ps max; typ from 0.725 V to 1.1 V
|   falling waveform, R_fixture 50, V_fixture 0.0: 20-80 % time 38.1ps typ, 45ps min, 32.7ps max; typ from 0.203 V to 0 V
[Pulldown]
|   Voltage   I(typ)   I(min)   I(max)
-1.1V     -19.4mA    -16.97mA   -21.71mA
-915.2mV  -16.99mA   -15.68mA   -18.79mA
-657.8mV  -13.34mA   -12.68mA   -14.5mA
-473mV    -9.87mA    -9.049mA   -11.04mA
-268.4mV  -4.569mA   -4.295mA   -5.081mA
-129.8mV  -1.932mA   -1.916mA   -1.945mA
210.1mV   2.774mA    2.746mA    2.796mA
487.3mV   5.736mA    5.541mA    6.073mA
810.7mV   7.947mA    7.317mA    9.018mA
1.111V    9.1mA      8.248mA    10.7mA
1.556V    10.25mA    9.273mA    12.16mA
2.2V      11.49mA    10.45mA    13.57mA
[GND Clamp]
|   Voltage   I(typ)   I(min)   I(max)
-1.1V     -34.89mA   -30.35mA   -43.14mA
-951.5mV  -25.76mA   -21.89mA   -32.2mA
-799.7mV  -16.38mA   -13.37mA   -21.53mA
-723.8mV  -11.99mA   -9.379mA   -16.19mA
-664.4mV  -8.772mA   -6.596mA   -12.13mA
-591.8mV  -5.274mA   -3.797mA   -7.53mA
-522.5mV  -2.671mA   -1.905mA   -3.826mA
-469.7mV  -1.36mA    -986.9uA   -1.791mA
-416.9mV  -597.8uA   -440.2uA   -665.5uA
-357.5mV  -191.7uA   -144.2uA   -173.3uA
-242mV    -10.02uA   -9.177uA   -5.633uA
2.2V      0A         0A         0A
[Pullup]
|   Voltage   I(typ)   I(min)   I(max)
-1.1V     1.371uA    2.481uA    454.4nA
266.2mV   -23.09uA   -22.26uA   -23.96uA
408.1mV   -253.3uA   -210.9uA   -297.2uA
513.7mV   -768.2uA   -699.3uA   -794.8uA
619.3mV   -1.533mA   -1.551mA   -1.46mA
761.2mV   -2.768mA   -3.054mA   -2.513mA
1.032V    -5.393mA   -6.298mA   -4.813mA
1.448V    -9.715mA   -11.29mA   -8.771mA
1.655V    -11.85mA   -13.4mA    -11.24mA
1.887V    -14.33mA   -15.16mA   -14.11mA
2.114V    -16.89mA   -16.95mA   -17.27mA
2.2V      -17.84mA   -17.49mA   -18.41mA
[POWER Clamp]
|   Voltage   I(typ)   I(min)   I(max)
-1.1V     3.036mA    3.636mA    2.186mA
-1.041V   2.347mA    2.931mA    1.626mA
-977.9mV  1.724mA    2.243mA    1.161mA
-911.9mV  1.201mA    1.612mA    765uA
-855.8mV  838uA      1.172mA    552.2uA
-776.6mV  434.2uA    683.6uA    390.2uA
-707.3mV  225.5uA    345.5uA    267.6uA
-651.2mV  138.6uA    162.4uA    181.2uA
-595.1mV  80.77uA    68.32uA    109.2uA
-482.9mV  15.68uA    9.499uA    19.5uA
-360.8mV  1.018uA    769nA      795.6nA
2.2V      0A         0A         0A
[Ramp]
|   typ   min   max
| 20% - 80%
dV/dt_r   121.55m/46.49p   123.86m/50.71p   125.34m/42.75p
dV/dt_f   224.68m/56.30p   207.34m/67.15p   255.27m/45.93p
| 25% - 75%
|dV/dt_r   101.29m/37.01p   103.22m/40.45p   104.45m/34.02p
|dV/dt_f   187.23m/44.80p   172.78m/53.44p   212.72m/36.43p
R_load = 50
[Rising Waveform]
R_fixture = 50
V_fixture = 0.0
|   Time   V(typ)   V(min)   V(max)
0s        268uV      207.1uV    200.6uV
58ps      -376.8uV   133.2uV    1.075mV
78ps      3.401mV    -940.4uV   52.99mV
97ps      54.29mV    2.586mV    121.3mV
110ps     97.82mV    26.04mV    153.3mV
130ps     146.8mV    86.75mV    182.4mV
151ps     175.7mV    140mV      197.2mV
181ps     193.8mV    181.6mV    205.4mV
221ps     200.9mV    200.8mV    208.3mV
447ps     202.9mV    206.6mV    209.1mV
[Falling Waveform]
R_fixture   = 50
V_fixture   = 1.1
V_fixture_min = 1.06
V_fixture_max = 1.17
|   Time   V(typ)   V(min)   V(max)
0s        1.1V       1.06V      1.17V
72ps      1.1V       1.06V      1.167V
80ps      1.101V     1.06V      1.13V
95ps      1.091V     1.059V     1.02V
120ps     973mV      1.05V      873mV
140ps     879.4mV    982.4mV    809.6mV
163ps     808.3mV    890.9mV    773.5mV
202ps     752.4mV    788.6mV    751.8mV
243ps     733.5mV    741.7mV    746.2mV
447ps     725.5mV    714.4mV    744.6mV
[Rising Waveform]
R_fixture   = 50
V_fixture   = 1.1
V_fixture_min = 1.06
V_fixture_max = 1.17
|   Time   V(typ)   V(min)   V(max)
0s        725.4mV    714.2mV    744.5mV
53ps      721.7mV    710.6mV    750.1mV
62ps      727.8mV    707.8mV    786.5mV
75ps      773.9mV    716.3mV    892.8mV
91ps      875.4mV    773.4mV    991.4mV
110ps     961.5mV    873.2mV    1.064V
131ps     1.019V     946.8mV    1.11V
156ps     1.057V     997.4mV    1.14V
232ps     1.094V     1.05V      1.166V
447ps     1.1V       1.06V      1.17V
[Falling Waveform]
R_fixture = 50
V_fixture = 0.0
|   Time   V(typ)   V(min)   V(max)
0s        202.9mV    206.7mV    209.2mV
59ps      205.4mV    208.5mV    208.3mV
75ps      200.3mV    212.9mV    166mV
88ps      169.6mV    207mV      95.86mV
101ps     115.2mV    180mV      55.04mV
119ps     57.99mV    121.9mV    25.9mV
140ps     25.74mV    61.18mV    10.83mV
167ps     9.25mV     23.22mV    3.681mV
209ps     2.099mV    5.365mV    835.6uV
447ps     343uV      308.7uV    228uV
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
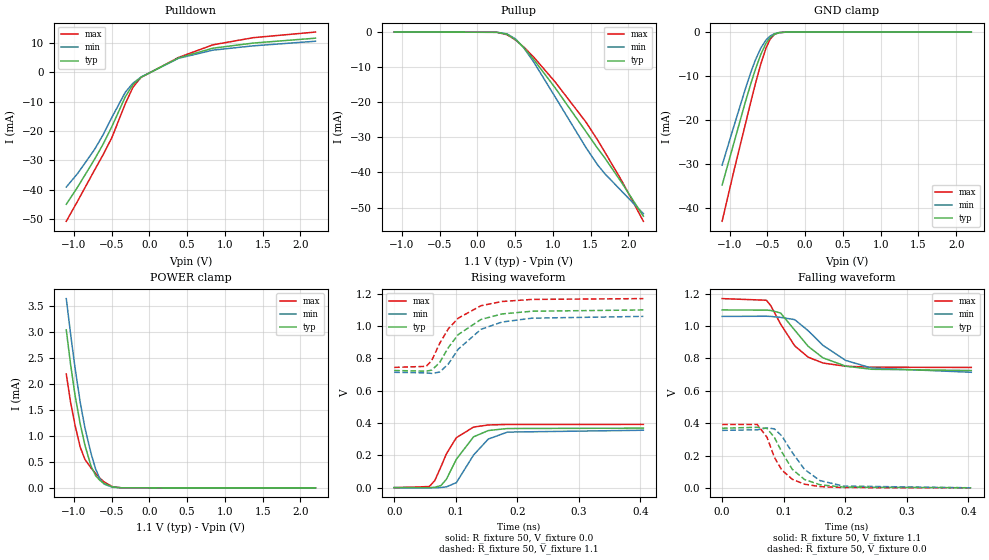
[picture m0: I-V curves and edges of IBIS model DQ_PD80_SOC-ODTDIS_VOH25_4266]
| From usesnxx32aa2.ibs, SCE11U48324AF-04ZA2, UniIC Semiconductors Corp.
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| DQ_PD80_SOC-ODTDIS_VOH25_4266
| (80 Ohm Pulldown, SOC ODT disabled setting, VOH=VDDQ/2.5 cal. point, 3200-4266Mbps)
[Model]   DQ_PD80_SOC-ODTDIS_VOH25_4266
Model_type   I/O
Vinl = 160.000mV
Vinh = 280.000mV
Vmeas = 220.000mV
Vref = 0.0mV
Cref = 0.0pF
|   typ   min   max
|C_comp   0.797pF   0.747pF   0.847pF
C_comp_pullup   0.3985pF   0.3735pF   0.4235pF
C_comp_pulldown   0.3985pF   0.3735pF   0.4235pF
| Note: C_comp changes when the ODT circuit is enabled.
[Model Spec]
| Input threshold voltage corners
Vinl   0.1600V   0.1520V   0.1740V
Vinh   0.2800V   0.2720V   0.2940V
| Measurement voltage corners
Vmeas   0.2200V   0.2120V   0.2340V
| Timing spec test load voltage corners
Vref   0.0000V   0.0000V   0.0000V
| Dynamic Overshoot Parameters from LPDDR4 Specification
D_overshoot_ampl_h   0.30   NA   NA
D_overshoot_ampl_l   0.30   NA   NA
D_overshoot_area_h   0.1n   NA   NA
D_overshoot_area_l   0.1n   NA   NA
[Receiver Thresholds]
Vth   = 0.2200V
Vth_min  = 0.2167V
Vth_max  = 0.2233V
Vinh_ac  = 0.060V
Vinh_dc  = 0.060V
Vinl_ac  = -0.060V
Vinl_dc  = -0.060V
Tslew_ac = 5.000ns |Not specified, so set to high value
Threshold_sensitivity = 0.2000
Reference_supply Pullup_ref
[Voltage Range]   1.1000V   1.0600V   1.1700V
[Pullup Reference]   1.1000V   1.0600V   1.1700V
| Junction Temperature (Ambient temp is 35C typ 95C min -40C max)
[Temperature Range]   50.0   110.0   -40.0
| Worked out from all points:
|   slope of the pulldown table from 0 to 0.165 V, typ, clamps not added: 73.8 ohm
|   slope of the pullup table from 0 to 0.165 V, typ, clamps not added: 17.5 kohm
|   GND clamp passes 1 mA (typ) near -0.45 V on its own axis
|   POWER clamp passes 1 mA (typ) near -0.88 V on its own axis
|   rising waveform, R_fixture 50, V_fixture 0.0: 20-80 % time 34.6ps typ, 38.4ps min, 31.4ps max; typ from 0.001 V to 0.369 V
|   falling waveform, R_fixture 50, V_fixture 1.1: 20-80 % time 57.1ps typ, 68.5ps min, 46.3ps max; typ from 1.1 V to 0.726 V
|   rising waveform, R_fixture 50, V_fixture 1.1: 20-80 % time 54ps typ, 55.8ps min, 50.4ps max; typ from 0.725 V to 1.1 V
|   falling waveform, R_fixture 50, V_fixture 0.0: 20-80 % time 37.5ps typ, 43.4ps min, 32ps max; typ from 0.369 V to 0.001 V
[Pulldown]
|   Voltage   I(typ)   I(min)   I(max)
-1.1V     -44.88mA   -39.02mA   -50.64mA
-948.2mV  -38.97mA   -34.38mA   -43.73mA
-723.8mV  -29.53mA   -26.19mA   -33.19mA
-611.6mV  -24.44mA   -21.26mA   -28.03mA
-496.1mV  -18.51mA   -15.39mA   -22.23mA
-317.9mV  -8.375mA   -6.836mA   -10.74mA
-215.6mV  -4.219mA   -3.747mA   -5.086mA
-110mV    -1.768mA   -1.706mA   -1.813mA
385mV     4.755mA    4.648mA    4.931mA
840.4mV   8.088mA    7.426mA    9.228mA
1.375V    9.824mA    8.884mA    11.65mA
2.2V      11.49mA    10.45mA    13.57mA
[GND Clamp]
|   Voltage   I(typ)   I(min)   I(max)
-1.1V     -34.89mA   -30.35mA   -43.14mA
-941.6mV  -25.14mA   -21.33mA   -31.48mA
-793.1mV  -15.99mA   -13.01mA   -21.07mA
-720.5mV  -11.8mA    -9.215mA   -15.96mA
-661.1mV  -8.6mA     -6.453mA   -11.91mA
-588.5mV  -5.13mA    -3.689mA   -7.336mA
-519.2mV  -2.579mA   -1.835mA   -3.674mA
-466.4mV  -1.302mA   -943.2uA   -1.695mA
-410.3mV  -533.8uA   -393.2uA   -578.9uA
-344.3mV  -144.4uA   -109.5uA   -124uA
-242mV    -10.13uA   -9.161uA   -5.671uA
2.2V      0A         0A         0A
[Pullup]
|   Voltage   I(typ)   I(min)   I(max)
-1.1V     4.112uA    7.441uA    1.363uA
259.6mV   -60.48uA   -59.43uA   -61.39uA
394.9mV   -632.8uA   -526.4uA   -751uA
510.4mV   -2.22mA    -2.012mA   -2.306mA
619.3mV   -4.537mA   -4.575mA   -4.333mA
748mV     -7.82mA    -8.539mA   -7.138mA
1.032V    -15.9mA    -18.5mA    -14.23mA
1.441V    -28.41mA   -32.96mA   -25.69mA
1.589V    -32.98mA   -37.7mA    -30.6mA
1.688V    -35.82mA   -40.32mA   -34.15mA
1.91V     -42.82mA   -45.28mA   -42.24mA
2.2V      -52.46mA   -51.74mA   -53.91mA
[POWER Clamp]
|   Voltage   I(typ)   I(min)   I(max)
-1.1V     3.036mA    3.636mA    2.186mA
-1.044V   2.383mA    2.969mA    1.654mA
-984.5mV  1.784mA    2.311mA    1.206mA
-915.2mV  1.225mA    1.641mA    781.2uA
-852.5mV  818.6uA    1.149mA    543.8uA
-773.3mV  420.9uA    665.5uA    384.1uA
-710.6mV  232.4uA    359.1uA    273.1uA
-654.5mV  142.7uA    170.4uA    185.9uA
-598.4mV  83.65uA    71.96uA    113.1uA
-489.5mV  17.84uA    10.83uA    22.44uA
-374mV    1.397uA    995nA      1.126uA
2.2V      0A         0A         0A
[Ramp]
|   typ   min   max
| 20% - 80%
dV/dt_r   220.69m/34.60p   213.04m/38.43p   234.79m/31.41p
dV/dt_f   224.66m/57.13p   207.18m/68.53p   255.29m/46.30p
| 25% - 75%
|dV/dt_r   183.91m/27.55p   177.54m/30.60p   195.66m/24.94p
|dV/dt_f   187.22m/45.46p   172.65m/54.51p   212.74m/36.82p
R_load = 50
[Rising Waveform]
R_fixture = 50
V_fixture = 0.0
|   Time   V(typ)   V(min)   V(max)
0s        835.6uV    685.5uV    611.7uV
57ps      431.4uV    -59.04uV   7.433mV
66ps      3.407mV    -506.3uV   44.5mV
76ps      13.4mV     1.413mV    129.8mV
85ps      53.46mV    5.833mV    210.9mV
101ps     176mV      31.53mV    309.7mV
129ps     315mV      202.6mV    375.4mV
153ps     354mV      301.3mV    388.4mV
184ps     366.4mV    344.3mV    391.5mV
405ps     368.7mV    355.8mV    391.9mV
[Falling Waveform]
R_fixture   = 50
V_fixture   = 1.1
V_fixture_min = 1.06
V_fixture_max = 1.17
|   Time   V(typ)   V(min)   V(max)
0s        1.1V       1.06V      1.17V
72ps      1.099V     1.061V     1.16V
79ps      1.097V     1.06V      1.127V
95ps      1.081V     1.054V     1.013V
118ps     975.3mV    1.04V      878.1mV
140ps     874.7mV    971.3mV    807.8mV
164ps     803.7mV    880.8mV    771.8mV
201ps     752.5mV    787.8mV    751.9mV
243ps     733.3mV    740.9mV    746.2mV
405ps     725.6mV    714.7mV    744.5mV
[Rising Waveform]
R_fixture   = 50
V_fixture   = 1.1
V_fixture_min = 1.06
V_fixture_max = 1.17
|   Time   V(typ)   V(min)   V(max)
0s        725.4mV    714.2mV    744.5mV
52ps      721.1mV    710.6mV    750.9mV
61ps      727.6mV    707.2mV    787.1mV
74ps      775.1mV    715.7mV    893.7mV
88ps      867.3mV    765.6mV    983.1mV
104ps     947.5mV    856.7mV    1.049V
141ps     1.041V     980mV      1.126V
175ps     1.075V     1.025V     1.152V
224ps     1.092V     1.049V     1.165V
405ps     1.1V       1.06V      1.17V
[Falling Waveform]
R_fixture = 50
V_fixture = 0.0
|   Time   V(typ)   V(min)   V(max)
0s        368.8mV    355.9mV    392mV
57ps      374.8mV    359.2mV    392.5mV
73ps      367.9mV    371mV      313.1mV
85ps      312.1mV    365.1mV    188.5mV
97ps      222.6mV    321.4mV    111mV
114ps     115.1mV    218.9mV    53.55mV
134ps     52mV       114.5mV    23.08mV
159ps     19.75mV    45.44mV    8.412mV
197ps     5.106mV    11.64mV    2.214mV
405ps     887.6uV    760.7uV    634uV
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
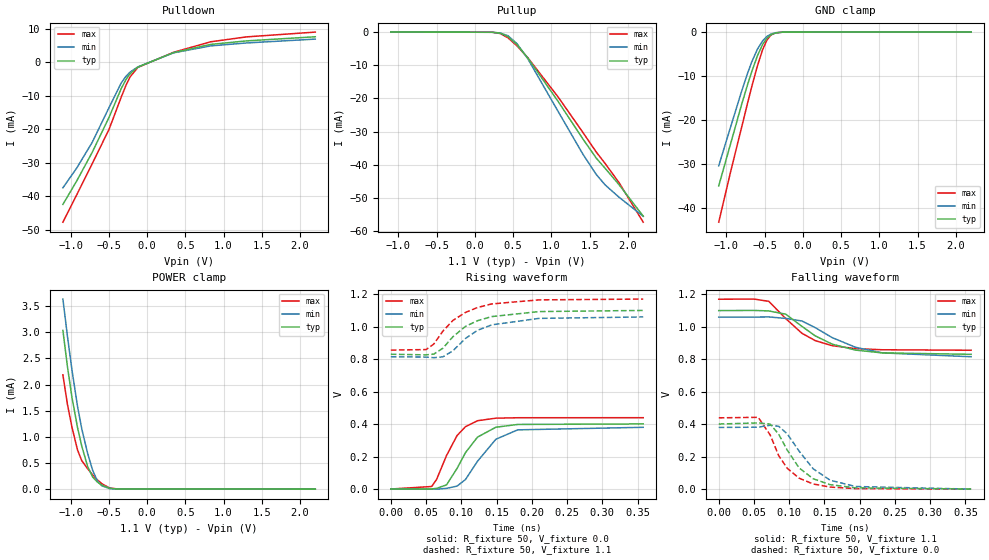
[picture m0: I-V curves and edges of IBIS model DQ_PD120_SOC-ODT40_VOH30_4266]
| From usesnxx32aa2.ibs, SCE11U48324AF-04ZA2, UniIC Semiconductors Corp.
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| DQ_PD120_SOC-ODT40_VOH30_4266
| (120 Ohm Pulldown, 40 Ohm System ODT Setting, VOH=VDDQ/3.0, 3200-4266Mbps)
[Model]   DQ_PD120_SOC-ODT40_VOH30_4266
Model_type   I/O
Vinl = 123.333mV
Vinh = 243.333mV
Vmeas = 183.333mV
Vref = 0.0mV
Cref = 0.0pF
Rref = 40.000Ohm
|   typ   min   max
|C_comp   0.797pF   0.747pF   0.847pF
C_comp_pullup   0.3985pF   0.3735pF   0.4235pF
C_comp_pulldown   0.3985pF   0.3735pF   0.4235pF
| Note: C_comp changes when the ODT circuit is enabled.
[Model Spec]
| Input threshold voltage corners
Vinl   0.1233V   0.1167V   0.1350V
Vinh   0.2433V   0.2367V   0.2550V
| Measurement voltage corners
Vmeas   0.1833V   0.1767V   0.1950V
| Timing spec test load voltage corners
Vref   0.0000V   0.0000V   0.0000V
| Dynamic Overshoot Parameters from LPDDR4 Specification
D_overshoot_ampl_h   0.30   NA   NA
D_overshoot_ampl_l   0.30   NA   NA
D_overshoot_area_h   0.1n   NA   NA
D_overshoot_area_l   0.1n   NA   NA
[Receiver Thresholds]
Vth   = 0.1833V
Vth_min  = 0.1800V
Vth_max  = 0.1866V
Vinh_ac  = 0.060V
Vinh_dc  = 0.060V
Vinl_ac  = -0.060V
Vinl_dc  = -0.060V
Tslew_ac = 5.000ns |Not specified, so set to high value
Threshold_sensitivity = 0.1667
Reference_supply Pullup_ref
[Voltage Range]   1.1000V   1.0600V   1.1700V
[Pullup Reference]   1.1000V   1.0600V   1.1700V
| Junction Temperature (Ambient temp is 35C typ 95C min -40C max)
[Temperature Range]   50.0   110.0   -40.0
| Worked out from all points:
|   slope of the pulldown table from 0 to 0.165 V, typ, clamps not added: 109 ohm
|   slope of the pullup table from 0 to 0.165 V, typ, clamps not added: 13 kohm
|   GND clamp passes 1 mA (typ) near -0.45 V on its own axis
|   POWER clamp passes 1 mA (typ) near -0.88 V on its own axis
|   rising waveform, R_fixture 50, V_fixture 0.0: 20-80 % time 35ps typ, 39.3ps min, 30ps max; typ from 0.001 V to 0.401 V
|   falling waveform, R_fixture 50, V_fixture 1.1: 20-80 % time 61.2ps typ, 71.3ps min, 51.4ps max; typ from 1.1 V to 0.831 V
|   rising waveform, R_fixture 50, V_fixture 1.1: 20-80 % time 51.6ps typ, 51.8ps min, 50ps max; typ from 0.83 V to 1.1 V
|   falling waveform, R_fixture 50, V_fixture 0.0: 20-80 % time 40.2ps typ, 45.3ps min, 35.8ps max; typ from 0.402 V to 0.001 V
[Pulldown]
|   Voltage   I(typ)   I(min)   I(max)
-1.1V     -42.44mA   -37.48mA   -47.75mA
-918.5mV  -35.39mA   -31.54mA   -39.55mA
-717.2mV  -26.89mA   -23.9mA    -30.29mA
-496.1mV  -16.38mA   -13.46mA   -19.96mA
-337.7mV  -7.822mA   -6.138mA   -10.38mA
-275mV    -5.103mA   -4.125mA   -6.813mA
-222.2mV  -3.395mA   -2.899mA   -4.341mA
-119.9mV  -1.395mA   -1.326mA   -1.477mA
345.4mV   2.928mA    2.867mA    3.023mA
833.8mV   5.403mA    4.954mA    6.183mA
1.299V    6.441mA    5.821mA    7.639mA
2.2V      7.677mA    6.979mA    9.076mA
[GND Clamp]
|   Voltage   I(typ)   I(min)   I(max)
-1.1V     -34.88mA   -30.34mA   -43.13mA
-944.9mV  -25.34mA   -21.53mA   -31.71mA
-803mV    -16.57mA   -13.55mA   -21.76mA
-723.8mV  -11.98mA   -9.382mA   -16.18mA
-667.7mV  -8.939mA   -6.742mA   -12.34mA
-595.1mV  -5.416mA   -3.908mA   -7.72mA
-525.8mV  -2.776mA   -1.978mA   -3.977mA
-469.7mV  -1.358mA   -987.6uA   -1.794mA
-416.9mV  -599.4uA   -441.4uA   -665.6uA
-357.5mV  -192.1uA   -144.7uA   -174uA
-261.8mV  -17.76uA   -15.5uA    -11.08uA
2.2V      0A         0A         0A
[Pullup]
|   Voltage   I(typ)   I(min)   I(max)
-1.1V     6.284uA    9.684uA    2.832uA
226.6mV   -42.23uA   -43.5uA    -42.78uA
328.9mV   -304.2uA   -255.9uA   -417uA
431.2mV   -1.334mA   -1.088mA   -1.696mA
550mV     -3.801mA   -3.492mA   -4.138mA
691.9mV   -7.825mA   -8.065mA   -7.741mA
1.088V    -20.91mA   -23.92mA   -19.57mA
1.411V    -32.18mA   -36.77mA   -30.22mA
1.586V    -37.97mA   -42.9mA    -36.14mA
1.702V    -41.04mA   -46.04mA   -39.59mA
1.883V    -45.95mA   -49.74mA   -45.33mA
2.2V      -55.46mA   -55.5mA    -57.28mA
[POWER Clamp]
|   Voltage   I(typ)   I(min)   I(max)
-1.1V     3.036mA    3.636mA    2.186mA
-1.041V   2.347mA    2.931mA    1.626mA
-981.2mV  1.754mA    2.277mA    1.183mA
-908.6mV  1.178mA    1.583mA    748.9uA
-852.5mV  818.5uA    1.149mA    543.6uA
-776.6mV  434.4uA    683.6uA    390.2uA
-710.6mV  232.2uA    359.1uA    273.1uA
-651.2mV  138.6uA    162.4uA    181.2uA
-591.8mV  77.93uA    64.83uA    105.5uA
-489.5mV  17.84uA    10.84uA    22.51uA
-370.7mV  1.283uA    931.4nA    1.034uA
2.2V      0A         0A         0A
[Ramp]
|   typ   min   max
| 20% - 80%
dV/dt_r   240.30m/34.96p   227.86m/39.26p   263.41m/30.04p
dV/dt_f   161.61m/61.13p   146.50m/71.31p   188.44m/51.39p
| 25% - 75%
|dV/dt_r   200.25m/27.82p   189.88m/31.22p   219.51m/23.89p
|dV/dt_f   134.67m/48.58p   122.08m/56.59p   157.04m/40.84p
R_load = 50
[Rising Waveform]
R_fixture = 50
V_fixture = 0.0
|   Time   V(typ)   V(min)   V(max)
0s        939.1uV    832.6uV    675.4uV
58ps      1.266mV    -183.9uV   16.12mV
65ps      4.892mV    -272.5uV   60.23mV
79ps      25.97mV    4.634mV    206.6mV
94ps      127.7mV    18.5mV     329.9mV
106ps     225.3mV    59.54mV    384.8mV
123ps     320.3mV    171.9mV    421mV
149ps     381mV      307.1mV    436.8mV
180ps     398.2mV    364.9mV    439.4mV
358ps     401.4mV    380.6mV    439.7mV
[Falling Waveform]
R_fixture   = 50
V_fixture   = 1.1
V_fixture_min = 1.06
V_fixture_max = 1.17
|   Time   V(typ)   V(min)   V(max)
0s        1.1V       1.06V      1.17V
50ps      1.101V     1.06V      1.171V
71ps      1.098V     1.061V     1.157V
95ps      1.078V     1.052V     1.051V
118ps     1.003V     1.036V     960.3mV
137ps     944.2mV    994.8mV    915mV
161ps     893.3mV    933.5mV    883.9mV
194ps     856.8mV    874.2mV    865.8mV
232ps     839.7mV    839.7mV    858.9mV
358ps     830.7mV    815.8mV    855.9mV
[Rising Waveform]
R_fixture   = 50
V_fixture   = 1.1
V_fixture_min = 1.06
V_fixture_max = 1.17
|   Time   V(typ)   V(min)   V(max)
0s        830.3mV    814.6mV    855.9mV
50ps      826.5mV    812.9mV    859.1mV
61ps      831.2mV    809.1mV    893.1mV
74ps      867.9mV    814.5mV    973.4mV
88ps      937.9mV    851.2mV    1.038V
106ps     1.002V     927.8mV    1.088V
123ps     1.037V     977.7mV    1.118V
143ps     1.062V     1.011V     1.14V
210ps     1.093V     1.051V     1.165V
358ps     1.1V       1.06V      1.17V
[Falling Waveform]
R_fixture = 50
V_fixture = 0.0
|   Time   V(typ)   V(min)   V(max)
0s        401.6mV    380.8mV    439.8mV
56ps      408.6mV    382.2mV    442.9mV
73ps      401.3mV    394.3mV    334.1mV
85ps      339.3mV    387.7mV    207.8mV
97ps      242.5mV    342.2mV    130mV
114ps     131.7mV    235mV      68.42mV
134ps     64.77mV    126mV      32.58mV
158ps     28.32mV    55.8mV     13.63mV
194ps     8.792mV    17.11mV    4.081mV
358ps     1.029mV    987.9uV    705.7uV
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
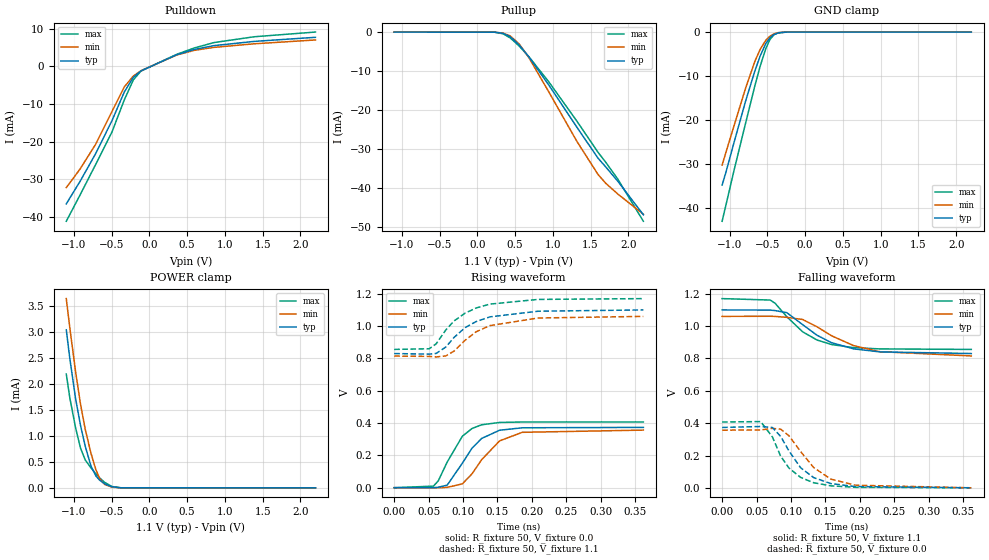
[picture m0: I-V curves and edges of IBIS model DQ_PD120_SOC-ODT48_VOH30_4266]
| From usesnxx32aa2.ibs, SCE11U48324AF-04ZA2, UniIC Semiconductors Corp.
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| DQ_PD120_SOC-ODT48_VOH30_4266
| (120 Ohm Pulldown, 48 Ohm System ODT Setting, VOH=VDDQ/3.0, 3200-4266Mbps)
[Model]   DQ_PD120_SOC-ODT48_VOH30_4266
Model_type   I/O
Vinl = 123.333mV
Vinh = 243.333mV
Vmeas = 183.333mV
Vref = 0.0mV
Cref = 0.0pF
Rref = 48.000Ohm
|   typ   min   max
|C_comp   0.797pF   0.747pF   0.847pF
C_comp_pullup   0.3985pF   0.3735pF   0.4235pF
C_comp_pulldown   0.3985pF   0.3735pF   0.4235pF
| Note: C_comp changes when the ODT circuit is enabled.
[Model Spec]
| Input threshold voltage corners
Vinl   0.1233V   0.1167V   0.1350V
Vinh   0.2433V   0.2367V   0.2550V
| Measurement voltage corners
Vmeas   0.1833V   0.1767V   0.1950V
| Timing spec test load voltage corners
Vref   0.0000V   0.0000V   0.0000V
| Dynamic Overshoot Parameters from LPDDR4 Specification
D_overshoot_ampl_h   0.30   NA   NA
D_overshoot_ampl_l   0.30   NA   NA
D_overshoot_area_h   0.1n   NA   NA
D_overshoot_area_l   0.1n   NA   NA
[Receiver Thresholds]
Vth   = 0.1833V
Vth_min  = 0.1800V
Vth_max  = 0.1866V
Vinh_ac  = 0.060V
Vinh_dc  = 0.060V
Vinl_ac  = -0.060V
Vinl_dc  = -0.060V
Tslew_ac = 5.000ns |Not specified, so set to high value
Threshold_sensitivity = 0.1667
Reference_supply Pullup_ref
[Voltage Range]   1.1000V   1.0600V   1.1700V
[Pullup Reference]   1.1000V   1.0600V   1.1700V
| Junction Temperature (Ambient temp is 35C typ 95C min -40C max)
[Temperature Range]   50.0   110.0   -40.0
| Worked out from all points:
|   slope of the pulldown table from 0 to 0.165 V, typ, clamps not added: 109 ohm
|   slope of the pullup table from 0 to 0.165 V, typ, clamps not added: 15.7 kohm
|   GND clamp passes 1 mA (typ) near -0.45 V on its own axis
|   POWER clamp passes 1 mA (typ) near -0.88 V on its own axis
|   rising waveform, R_fixture 50, V_fixture 0.0: 20-80 % time 36.4ps typ, 41.1ps min, 31.8ps max; typ from 0.001 V to 0.374 V
|   falling waveform, R_fixture 50, V_fixture 1.1: 20-80 % time 60.8ps typ, 70.7ps min, 51.3ps max; typ from 1.1 V to 0.831 V
|   rising waveform, R_fixture 50, V_fixture 1.1: 20-80 % time 52.1ps typ, 53.2ps min, 50.2ps max; typ from 0.83 V to 1.1 V
|   falling waveform, R_fixture 50, V_fixture 0.0: 20-80 % time 40.4ps typ, 45.7ps min, 35.9ps max; typ from 0.374 V to 0.001 V
[Pulldown]
|   Voltage   I(typ)   I(min)   I(max)
-1.1V     -36.53mA   -32.22mA   -41.15mA
-918.5mV  -30.59mA   -27.31mA   -34.21mA
-710.6mV  -23.18mA   -20.7mA    -26.06mA
-496.1mV  -14.5mA    -12.05mA   -17.51mA
-331.1mV  -6.813mA   -5.465mA   -8.908mA
-212.3mV  -2.95mA    -2.603mA   -3.634mA
-110mV    -1.227mA   -1.181mA   -1.268mA
361.9mV   3.046mA    2.979mA    3.155mA
596.2mV   4.46mA     4.223mA    4.855mA
856.9mV   5.472mA    5.009mA    6.287mA
1.391V    6.596mA    5.961mA    7.831mA
2.2V      7.677mA    6.979mA    9.076mA
[GND Clamp]
|   Voltage   I(typ)   I(min)   I(max)
-1.1V     -34.88mA   -30.33mA   -43.13mA
-1.05V    -31.99mA   -27.44mA   -39.47mA
-941.6mV  -25.13mA   -21.34mA   -31.48mA
-789.8mV  -15.79mA   -12.83mA   -20.82mA
-667.7mV  -8.939mA   -6.743mA   -12.34mA
-595.1mV  -5.416mA   -3.908mA   -7.719mA
-522.5mV  -2.671mA   -1.905mA   -3.822mA
-466.4mV  -1.297mA   -943.1uA   -1.694mA
-413.6mV  -565.4uA   -416.9uA   -621.8uA
-354.2mV  -178.2uA   -134.6uA   -160.2uA
-242mV    -10.03uA   -9.194uA   -5.69uA
2.2V      0A         0A         0A
[Pullup]
|   Voltage   I(typ)   I(min)   I(max)
-1.1V     5.237uA    8.07uA     2.361uA
233.2mV   -40.28uA   -41.14uA   -42.31uA
342.1mV   -318.3uA   -262.7uA   -438.8uA
437.8mV   -1.205mA   -986uA     -1.515mA
556.6mV   -3.33mA    -3.082mA   -3.598mA
685.3mV   -6.404mA   -6.586mA   -6.345mA
949.3mV   -13.61mA   -15.38mA   -12.79mA
1.319V    -24.35mA   -27.96mA   -22.79mA
1.599V    -32.26mA   -36.44mA   -30.76mA
1.702V    -34.53mA   -38.71mA   -33.34mA
1.86V     -38.15mA   -41.43mA   -37.6mA
2.2V      -46.77mA   -46.64mA   -48.43mA
[POWER Clamp]
|   Voltage   I(typ)   I(min)   I(max)
-1.1V     3.036mA    3.636mA    2.186mA
-1.054V   2.493mA    3.084mA    1.737mA
-977.9mV  1.724mA    2.242mA    1.161mA
-911.9mV  1.201mA    1.612mA    764.8uA
-849.2mV  799.3uA    1.126mA    535.5uA
-773.3mV  420.8uA    665.5uA    384.1uA
-707.3mV  225.5uA    345.5uA    267.6uA
-654.5mV  142.7uA    170.4uA    185.9uA
-591.8mV  77.94uA    64.83uA    105.5uA
-496.1mV  20.09uA    12.31uA    25.71uA
-380.6mV  1.606uA    1.129uA    1.34uA
2.2V      0A         0A         0A
[Ramp]
|   typ   min   max
| 20% - 80%
dV/dt_r   223.70m/36.37p   213.67m/41.07p   244.01m/31.75p
dV/dt_f   161.64m/60.80p   146.52m/70.58p   188.45m/51.22p
| 25% - 75%
|dV/dt_r   186.42m/28.94p   178.06m/32.70p   203.34m/25.23p
|dV/dt_f   134.70m/48.30p   122.10m/56.12p   157.04m/40.61p
R_load = 50
[Rising Waveform]
R_fixture = 50
V_fixture = 0.0
|   Time   V(typ)   V(min)   V(max)
0s        784.2uV    693.9uV    564.2uV
57ps      835.5uV    -50.31uV   10.47mV
64ps      3.487mV    -211.1uV   42.59mV
77ps      16.55mV    2.811mV    159.3mV
99ps      152.1mV    24.25mV    318.8mV
113ps     244.7mV    86.18mV    366.6mV
127ps     305.2mV    173.3mV    389.7mV
153ps     355.9mV    289.9mV    404.1mV
186ps     371.1mV    343.1mV    406.9mV
362ps     373.6mV    356.8mV    407.2mV
[Falling Waveform]
R_fixture   = 50
V_fixture   = 1.1
V_fixture_min = 1.06
V_fixture_max = 1.17
|   Time   V(typ)   V(min)   V(max)
0s        1.1V       1.06V      1.17V
70ps      1.099V     1.061V     1.161V
77ps      1.096V     1.06V      1.141V
94ps      1.083V     1.054V     1.058V
117ps     1.009V     1.041V     964.7mV
138ps     943.2mV    995.5mV    913.9mV
159ps     897.5mV    940.4mV    886.1mV
191ps     859.5mV    879.4mV    866.9mV
229ps     840.7mV    841.9mV    859.2mV
362ps     830.6mV    815.8mV    855.9mV
[Rising Waveform]
R_fixture   = 50
V_fixture   = 1.1
V_fixture_min = 1.06
V_fixture_max = 1.17
|   Time   V(typ)   V(min)   V(max)
0s        830.3mV    814.6mV    855.9mV
51ps      826.6mV    812.6mV    859.9mV
61ps      830.9mV    809.3mV    890.6mV
75ps      870.3mV    815.7mV    976.3mV
87ps      930.1mV    845.7mV    1.032V
103ps     990.5mV    912.3mV    1.08V
119ps     1.028V     964.7mV    1.112V
139ps     1.057V     1.003V     1.136V
209ps     1.092V     1.05V      1.165V
362ps     1.1V       1.06V      1.17V
[Falling Waveform]
R_fixture = 50
V_fixture = 0.0
|   Time   V(typ)   V(min)   V(max)
0s        373.7mV    357mV      407.3mV
56ps      379.7mV    358mV      410.1mV
73ps      373.5mV    368.5mV    315.6mV
85ps      318.7mV    363mV      197mV
97ps      229.3mV    323.2mV    123.3mV
114ps     125.1mV    225.2mV    65.07mV
133ps     63.84mV    125.9mV    32.08mV
158ps     26.93mV    54.29mV    12.95mV
194ps     8.323mV    16.71mV    3.825mV
362ps     876.7uV    861.7uV    595.4uV
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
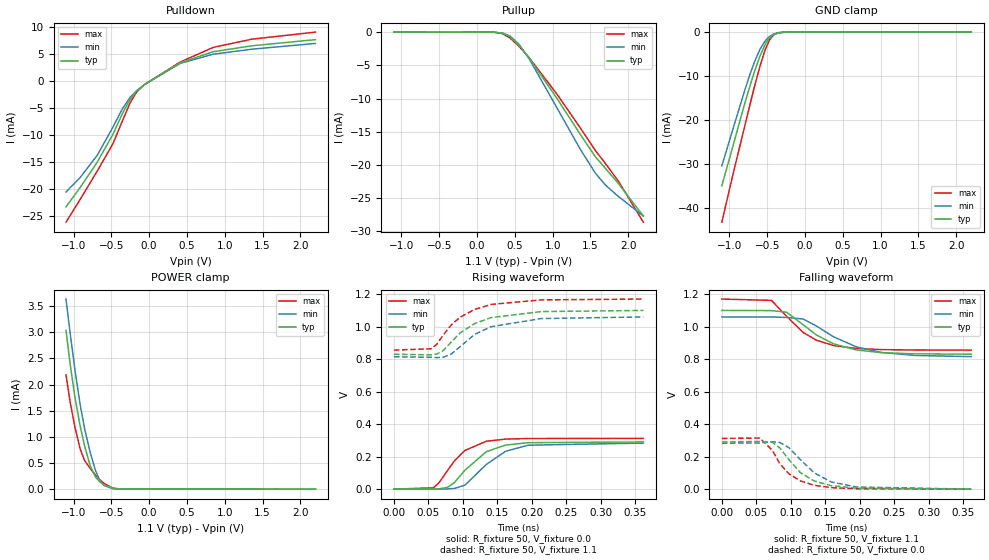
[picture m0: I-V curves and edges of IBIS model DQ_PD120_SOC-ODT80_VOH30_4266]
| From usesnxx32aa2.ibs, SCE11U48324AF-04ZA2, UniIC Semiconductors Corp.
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| DQ_PD120_SOC-ODT80_VOH30_4266
| (120 Ohm Pulldown, 80 Ohm System ODT Setting, VOH=VDDQ/3.0, 3200-4266Mbps)
[Model]   DQ_PD120_SOC-ODT80_VOH30_4266
Model_type   I/O
Vinl = 123.333mV
Vinh = 243.333mV
Vmeas = 183.333mV
Vref = 0.0mV
Cref = 0.0pF
Rref = 80.000Ohm
|   typ   min   max
|C_comp   0.797pF   0.747pF   0.847pF
C_comp_pullup   0.3985pF   0.3735pF   0.4235pF
C_comp_pulldown   0.3985pF   0.3735pF   0.4235pF
| Note: C_comp changes when the ODT circuit is enabled.
[Model Spec]
| Input threshold voltage corners
Vinl   0.1233V   0.1167V   0.1350V
Vinh   0.2433V   0.2367V   0.2550V
| Measurement voltage corners
Vmeas   0.1833V   0.1767V   0.1950V
| Timing spec test load voltage corners
Vref   0.0000V   0.0000V   0.0000V
| Dynamic Overshoot Parameters from LPDDR4 Specification
D_overshoot_ampl_h   0.30   NA   NA
D_overshoot_ampl_l   0.30   NA   NA
D_overshoot_area_h   0.1n   NA   NA
D_overshoot_area_l   0.1n   NA   NA
[Receiver Thresholds]
Vth   = 0.1833V
Vth_min  = 0.1800V
Vth_max  = 0.1866V
Vinh_ac  = 0.060V
Vinh_dc  = 0.060V
Vinl_ac  = -0.060V
Vinl_dc  = -0.060V
Tslew_ac = 5.000ns |Not specified, so set to high value
Threshold_sensitivity = 0.1667
Reference_supply Pullup_ref
[Voltage Range]   1.1000V   1.0600V   1.1700V
[Pullup Reference]   1.1000V   1.0600V   1.1700V
| Junction Temperature (Ambient temp is 35C typ 95C min -40C max)
[Temperature Range]   50.0   110.0   -40.0
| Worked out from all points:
|   slope of the pulldown table from 0 to 0.165 V, typ, clamps not added: 110 ohm
|   slope of the pullup table from 0 to 0.165 V, typ, clamps not added: 25.8 kohm
|   GND clamp passes 1 mA (typ) near -0.45 V on its own axis
|   POWER clamp passes 1 mA (typ) near -0.88 V on its own axis
|   rising waveform, R_fixture 50, V_fixture 0.0: 20-80 % time 43.2ps typ, 46.5ps min, 37.3ps max; typ from 0 V to 0.29 V
|   falling waveform, R_fixture 50, V_fixture 1.1: 20-80 % time 60.1ps typ, 69.5ps min, 50.7ps max; typ from 1.1 V to 0.831 V
|   rising waveform, R_fixture 50, V_fixture 1.1: 20-80 % time 54ps typ, 56.1ps min, 50.7ps max; typ from 0.83 V to 1.1 V
|   falling waveform, R_fixture 50, V_fixture 0.0: 20-80 % time 41.3ps typ, 47.1ps min, 36.7ps max; typ from 0.29 V to 0.001 V
[Pulldown]
|   Voltage   I(typ)   I(min)   I(max)
-1.1V     -23.24mA   -20.49mA   -26.08mA
-915.2mV  -19.72mA   -17.86mA   -21.93mA
-687.5mV  -14.99mA   -13.72mA   -16.65mA
-479.6mV  -9.837mA   -8.514mA   -11.58mA
-354.2mV  -5.997mA   -5.106mA   -7.363mA
-251.9mV  -3.347mA   -2.996mA   -4.013mA
-169.4mV  -1.906mA   -1.817mA   -2.065mA
-63.8mV   -654.6uA   -646.8uA   -646.6uA
411.4mV   3.386mA    3.295mA    3.541mA
847mV     5.443mA    4.985mA    6.243mA
1.359V    6.542mA    5.912mA    7.765mA
2.2V      7.677mA    6.979mA    9.076mA
[GND Clamp]
|   Voltage   I(typ)   I(min)   I(max)
-1.1V     -34.88mA   -30.34mA   -43.13mA
-944.9mV  -25.34mA   -21.53mA   -31.71mA
-799.7mV  -16.37mA   -13.37mA   -21.52mA
-727.1mV  -12.16mA   -9.546mA   -16.41mA
-664.4mV  -8.768mA   -6.598mA   -12.12mA
-595.1mV  -5.416mA   -3.908mA   -7.72mA
-525.8mV  -2.776mA   -1.977mA   -3.976mA
-469.7mV  -1.36mA    -986.9uA   -1.791mA
-416.9mV  -597.9uA   -441.2uA   -665.6uA
-354.2mV  -178.7uA   -135.3uA   -159.2uA
-265.1mV  -19.44uA   -16.69uA   -12.19uA
2.2V      0A         0A         0A
[Pullup]
|   Voltage   I(typ)   I(min)   I(max)
-1.1V     3.142uA    4.844uA    1.416uA
229.9mV   -22.65uA   -22.95uA   -23.28uA
332.2mV   -161.3uA   -134.8uA   -221.6uA
431.2mV   -668.7uA   -545.4uA   -849.8uA
546.7mV   -1.867mA   -1.71mA    -2.037mA
685.3mV   -3.83mA    -3.936mA   -3.796mA
1.055V    -9.944mA   -11.36mA   -9.304mA
1.368V    -15.43mA   -17.68mA   -14.46mA
1.566V    -18.77mA   -21.24mA   -17.83mA
1.698V    -20.51mA   -23.02mA   -19.78mA
1.87V     -22.79mA   -24.74mA   -22.44mA
2.2V      -27.69mA   -27.68mA   -28.61mA
[POWER Clamp]
|   Voltage   I(typ)   I(min)   I(max)
-1.1V     3.036mA    3.636mA    2.186mA
-1.044V   2.383mA    2.969mA    1.653mA
-981.2mV  1.754mA    2.277mA    1.183mA
-911.9mV  1.201mA    1.611mA    764.9uA
-852.5mV  818.6uA    1.149mA    543.8uA
-779.9mV  448.1uA    701.7uA    396.3uA
-710.6mV  232.2uA    359.2uA    273.1uA
-654.5mV  142.7uA    170.4uA    185.9uA
-598.4mV  83.65uA    71.97uA    113uA
-482.9mV  15.74uA    9.492uA    19.5uA
-360.8mV  1.027uA    771.1nA    792.4nA
2.2V      0A         0A         0A
[Ramp]
|   typ   min   max
| 20% - 80%
dV/dt_r   173.93m/43.19p   169.89m/46.46p   187.36m/37.30p
dV/dt_f   161.62m/60.00p   146.52m/69.57p   188.44m/50.69p
| 25% - 75%
|dV/dt_r   144.94m/34.39p   141.58m/37.04p   156.13m/29.62p
|dV/dt_f   134.68m/47.69p   122.10m/55.31p   157.04m/40.28p
R_load = 50
[Rising Waveform]
R_fixture = 50
V_fixture = 0.0
|   Time   V(typ)   V(min)   V(max)
0s        467.1uV    406.8uV    338.8uV
57ps      500.6uV    62.33uV    7.788mV
65ps      2.008mV    -88.99uV   36.75mV
78ps      10.87mV    1.61mV     115.9mV
88ps      41.82mV    4.683mV    175.1mV
103ps     116.4mV    24.42mV    238.1mV
134ps     230.4mV    151.7mV    294.7mV
162ps     271.3mV    233.2mV    308.1mV
195ps     286.1mV    270.5mV    311.7mV
362ps     290.4mV    283.6mV    312.6mV
[Falling Waveform]
R_fixture   = 50
V_fixture   = 1.1
V_fixture_min = 1.06
V_fixture_max = 1.17
|   Time   V(typ)   V(min)   V(max)
0s        1.1V       1.06V      1.17V
72ps      1.099V     1.06V      1.162V
94ps      1.089V     1.057V     1.064V
118ps     1.012V     1.047V     964.6mV
137ps     949.8mV    1.005V     917.3mV
162ps     894.5mV    938.1mV    884.1mV
195ps     857.1mV    876.3mV    865.9mV
232ps     840.1mV    841.1mV    859mV
281ps     832.9mV    822.9mV    856.6mV
362ps     830.6mV    815.8mV    855.9mV
[Rising Waveform]
R_fixture   = 50
V_fixture   = 1.1
V_fixture_min = 1.06
V_fixture_max = 1.17
|   Time   V(typ)   V(min)   V(max)
0s        830.3mV    814.6mV    855.9mV
54ps      826.8mV    811.8mV    864mV
62ps      831.4mV    809.6mV    890.9mV
71ps      851.1mV    811.3mV    945.2mV
83ps      904mV      830.5mV    1.01V
96ps      961.3mV    876.7mV    1.058V
117ps     1.019V     951.9mV    1.106V
141ps     1.056V     1V         1.137V
214ps     1.093V     1.05V      1.165V
362ps     1.1V       1.06V      1.17V
[Falling Waveform]
R_fixture = 50
V_fixture = 0.0
|   Time   V(typ)   V(min)   V(max)
0s        290.5mV    283.7mV    312.7mV
55ps      294.2mV    284.2mV    314.7mV
73ps      289.1mV    292mV      241mV
84ps      254.7mV    288.2mV    158.1mV
97ps      183.8mV    256.6mV    96.18mV
114ps     101.8mV    182.3mV    51.06mV
134ps     50.81mV    100.6mV    24.35mV
159ps     21.56mV    44.33mV    9.851mV
195ps     6.594mV    13.92mV    2.92mV
362ps     580uV      591.1uV    372.8uV
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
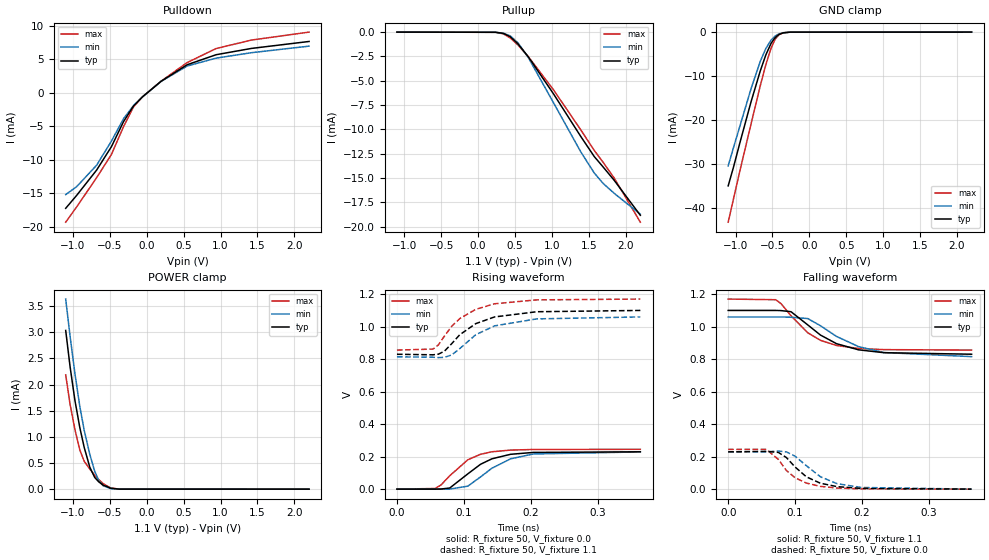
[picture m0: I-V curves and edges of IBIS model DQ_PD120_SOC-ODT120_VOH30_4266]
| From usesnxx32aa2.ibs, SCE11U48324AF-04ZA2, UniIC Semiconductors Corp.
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| DQ_PD120_SOC-ODT120_VOH30_4266
| (120 Ohm Pulldown, 120 Ohm System ODT Setting, VOH=VDDQ/3.0, 3200-4266Mbps)
[Model]   DQ_PD120_SOC-ODT120_VOH30_4266
Model_type   I/O
Vinl = 123.333mV
Vinh = 243.333mV
Vmeas = 183.333mV
Vref = 0.0mV
Cref = 0.0pF
Rref = 120.000Ohm
|   typ   min   max
|C_comp   0.797pF   0.747pF   0.847pF
C_comp_pullup   0.3985pF   0.3735pF   0.4235pF
C_comp_pulldown   0.3985pF   0.3735pF   0.4235pF
| Note: C_comp changes when the ODT circuit is enabled.
[Model Spec]
| Input threshold voltage corners
Vinl   0.1233V   0.1167V   0.1350V
Vinh   0.2433V   0.2367V   0.2550V
| Measurement voltage corners
Vmeas   0.1833V   0.1767V   0.1950V
| Timing spec test load voltage corners
Vref   0.0000V   0.0000V   0.0000V
| Dynamic Overshoot Parameters from LPDDR4 Specification
D_overshoot_ampl_h   0.30   NA   NA
D_overshoot_ampl_l   0.30   NA   NA
D_overshoot_area_h   0.1n   NA   NA
D_overshoot_area_l   0.1n   NA   NA
[Receiver Thresholds]
Vth   = 0.1833V
Vth_min  = 0.1800V
Vth_max  = 0.1866V
Vinh_ac  = 0.060V
Vinh_dc  = 0.060V
Vinl_ac  = -0.060V
Vinl_dc  = -0.060V
Tslew_ac = 5.000ns |Not specified, so set to high value
Threshold_sensitivity = 0.1667
Reference_supply Pullup_ref
[Voltage Range]   1.1000V   1.0600V   1.1700V
[Pullup Reference]   1.1000V   1.0600V   1.1700V
| Junction Temperature (Ambient temp is 35C typ 95C min -40C max)
[Temperature Range]   50.0   110.0   -40.0
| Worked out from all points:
|   slope of the pulldown table from 0 to 0.165 V, typ, clamps not added: 110 ohm
|   slope of the pullup table from 0 to 0.165 V, typ, clamps not added: 39.3 kohm
|   GND clamp passes 1 mA (typ) near -0.45 V on its own axis
|   POWER clamp passes 1 mA (typ) near -0.88 V on its own axis
|   rising waveform, R_fixture 50, V_fixture 0.0: 20-80 % time 47ps typ, 51.4ps min, 41.3ps max; typ from 0 V to 0.23 V
|   falling waveform, R_fixture 50, V_fixture 1.1: 20-80 % time 59.8ps typ, 69.1ps min, 50.5ps max; typ from 1.1 V to 0.831 V
|   rising waveform, R_fixture 50, V_fixture 1.1: 20-80 % time 54.4ps typ, 57.3ps min, 50.7ps max; typ from 0.83 V to 1.1 V
|   falling waveform, R_fixture 50, V_fixture 0.0: 20-80 % time 41.4ps typ, 47.3ps min, 36.8ps max; typ from 0.23 V to 0 V
[Pulldown]
|   Voltage   I(typ)   I(min)   I(max)
-1.1V     -17.22mA   -15.17mA   -19.29mA
-951.5mV  -15.29mA   -13.99mA   -17.01mA
-680.9mV  -11.52mA   -10.79mA   -12.65mA
-479.6mV  -8.015mA   -7.184mA   -9.175mA
-314.6mV  -4.26mA    -3.822mA   -5.007mA
-179.3mV  -1.94mA    -1.875mA   -2.067mA
-60.5mV   -606uA     -602uA     -596.1uA
193.6mV   1.737mA    1.719mA    1.751mA
546.7mV   4.202mA    4.013mA    4.524mA
939.4mV   5.699mA    5.189mA    6.623mA
1.418V    6.638mA    6mA        7.883mA
2.2V      7.677mA    6.979mA    9.076mA
[GND Clamp]
|   Voltage   I(typ)   I(min)   I(max)
-1.1V     -34.88mA   -30.34mA   -43.13mA
-1.027V   -30.57mA   -26.14mA   -37.76mA
-941.6mV  -25.13mA   -21.34mA   -31.48mA
-789.8mV  -15.79mA   -12.83mA   -20.82mA
-664.4mV  -8.768mA   -6.598mA   -12.12mA
-588.5mV  -5.129mA   -3.689mA   -7.328mA
-519.2mV  -2.57mA    -1.835mA   -3.672mA
-463.1mV  -1.235mA   -900.7uA   -1.601mA
-410.3mV  -533.9uA   -394.1uA   -581.6uA
-354.2mV  -177.4uA   -135uA     -161.5uA
-258.5mV  -16.16uA   -14.33uA   -9.97uA
2.2V      0A         0A         0A
[Pullup]
|   Voltage   I(typ)   I(min)   I(max)
-1.1V     2.095uA    3.229uA    944.4nA
236.5mV   -17.43uA   -17.3uA    -18.36uA
342.1mV   -127.5uA   -105.3uA   -176uA
437.8mV   -483.9uA   -396.3uA   -608.9uA
543.4mV   -1.23mA    -1.123mA   -1.345mA
682mV     -2.552mA   -2.625mA   -2.527mA
1.022V    -6.34mA    -7.25mA    -5.926mA
1.391V    -10.71mA   -12.29mA   -10.03mA
1.576V    -12.8mA    -14.49mA   -12.17mA
1.695V    -13.86mA   -15.55mA   -13.38mA
1.844V    -15.22mA   -16.56mA   -14.98mA
2.2V      -18.83mA   -18.72mA   -19.54mA
[POWER Clamp]
|   Voltage   I(typ)   I(min)   I(max)
-1.1V     3.036mA    3.636mA    2.186mA
-1.041V   2.347mA    2.931mA    1.626mA
-974.6mV  1.695mA    2.208mA    1.139mA
-908.6mV  1.178mA    1.583mA    748.5uA
-849.2mV  799.3uA    1.126mA    535.4uA
-773.3mV  420.8uA    665.5uA    384.1uA
-707.3mV  225.6uA    345.6uA    267.6uA
-651.2mV  138.6uA    162.3uA    181.2uA
-591.8mV  77.96uA    64.82uA    105.5uA
-489.5mV  17.79uA    10.84uA    22.53uA
-374mV    1.384uA    993.6nA    1.129uA
2.2V      0A         0A         0A
[Ramp]
|   typ   min   max
| 20% - 80%
dV/dt_r   137.79m/46.97p   137.35m/51.42p   147.00m/41.33p
dV/dt_f   161.62m/59.71p   146.51m/68.95p   188.43m/50.48p
| 25% - 75%
|dV/dt_r   114.82m/37.40p   114.45m/41.02p   122.50m/32.80p
|dV/dt_f   134.68m/47.44p   122.09m/54.88p   157.02m/40.15p
R_load = 50
[Rising Waveform]
R_fixture = 50
V_fixture = 0.0
|   Time   V(typ)   V(min)   V(max)
0s        308.3uV    264.8uV    225uV
57ps      205uV      159.3uV    3.992mV
66ps      847.8uV    -78.29uV   26.11mV
79ps      7.149mV    496.6uV    82.63mV
106ps     94.12mV    18.48mV    180.8mV
125ps     153.1mV    75.15mV    214.6mV
142ps     186.7mV    128.8mV    230mV
170ps     214.6mV    186.8mV    240.5mV
204ps     226mV      216.6mV    244.1mV
364ps     230mV      229.2mV    245.2mV
[Falling Waveform]
R_fixture   = 50
V_fixture   = 1.1
V_fixture_min = 1.06
V_fixture_max = 1.17
|   Time   V(typ)   V(min)   V(max)
0s        1.1V       1.06V      1.17V
71ps      1.1V       1.06V      1.166V
79ps      1.099V     1.06V      1.142V
94ps      1.092V     1.058V     1.067V
119ps     1.011V     1.05V      962.7mV
138ps     948.5mV    1.006V     916.1mV
162ps     895.4mV    940.2mV    884.4mV
195ps     857.6mV    877.2mV    866mV
233ps     840mV      840.9mV    858.9mV
364ps     830.6mV    815.8mV    856mV
[Rising Waveform]
R_fixture   = 50
V_fixture   = 1.1
V_fixture_min = 1.06
V_fixture_max = 1.17
|   Time   V(typ)   V(min)   V(max)
0s        830.3mV    814.6mV    855.9mV
54ps      826.9mV    812mV      862.2mV
62ps      830.7mV    809.8mV    888mV
71ps      849.2mV    811.1mV    942.1mV
82ps      896mV      826.4mV    1.003V
94ps      950.7mV    865.4mV    1.05V
118ps     1.019V     950.9mV    1.107V
146ps     1.06V      1.005V     1.141V
209ps     1.092V     1.048V     1.165V
364ps     1.1V       1.06V      1.17V
[Falling Waveform]
R_fixture = 50
V_fixture = 0.0
|   Time   V(typ)   V(min)   V(max)
0s        230mV      229.3mV    245.3mV
57ps      232.8mV    229.8mV    245.3mV
75ps      226.5mV    234.8mV    183.6mV
87ps      195mV      229.7mV    115.4mV
100ps     136.7mV    203.2mV    70.6mV
117ps     75.83mV    144.3mV    37.59mV
138ps     36.65mV    76.41mV    17.34mV
163ps     15.72mV    33.86mV    7.03mV
199ps     4.846mV    10.72mV    2.07mV
364ps     413uV      442.2uV    262uV
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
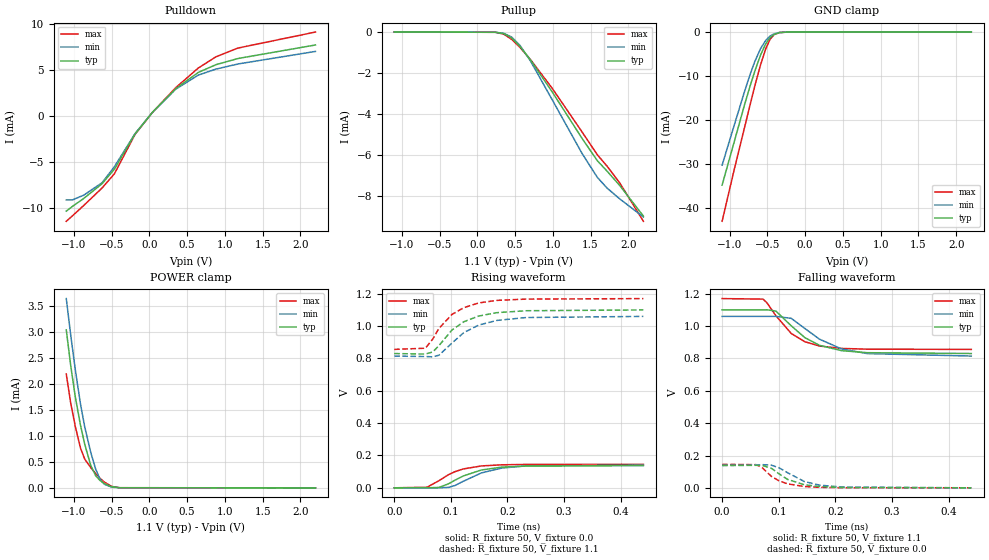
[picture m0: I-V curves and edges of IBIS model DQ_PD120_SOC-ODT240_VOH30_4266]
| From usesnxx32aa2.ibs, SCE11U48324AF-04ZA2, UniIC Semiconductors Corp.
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| DQ_PD120_SOC-ODT240_VOH30_4266
| (120 Ohm Pulldown, 240 Ohm System ODT Setting, VOH=VDDQ/3.0, 3200-4266Mbps)
[Model]   DQ_PD120_SOC-ODT240_VOH30_4266
Model_type   I/O
Vinl = 123.333mV
Vinh = 243.333mV
Vmeas = 183.333mV
Vref = 0.0mV
Cref = 0.0pF
Rref = 240.000Ohm
|   typ   min   max
|C_comp   0.797pF   0.747pF   0.847pF
C_comp_pullup   0.3985pF   0.3735pF   0.4235pF
C_comp_pulldown   0.3985pF   0.3735pF   0.4235pF
| Note: C_comp changes when the ODT circuit is enabled.
[Model Spec]
| Input threshold voltage corners
Vinl   0.1233V   0.1167V   0.1350V
Vinh   0.2433V   0.2367V   0.2550V
| Measurement voltage corners
Vmeas   0.1833V   0.1767V   0.1950V
| Timing spec test load voltage corners
Vref   0.0000V   0.0000V   0.0000V
| Dynamic Overshoot Parameters from LPDDR4 Specification
D_overshoot_ampl_h   0.30   NA   NA
D_overshoot_ampl_l   0.30   NA   NA
D_overshoot_area_h   0.1n   NA   NA
D_overshoot_area_l   0.1n   NA   NA
[Receiver Thresholds]
Vth   = 0.1833V
Vth_min  = 0.1800V
Vth_max  = 0.1866V
Vinh_ac  = 0.060V
Vinh_dc  = 0.060V
Vinl_ac  = -0.060V
Vinl_dc  = -0.060V
Tslew_ac = 5.000ns |Not specified, so set to high value
Threshold_sensitivity = 0.1667
Reference_supply Pullup_ref
[Voltage Range]   1.1000V   1.0600V   1.1700V
[Pullup Reference]   1.1000V   1.0600V   1.1700V
| Junction Temperature (Ambient temp is 35C typ 95C min -40C max)
[Temperature Range]   50.0   110.0   -40.0
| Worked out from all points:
|   slope of the pulldown table from 0 to 0.165 V, typ, clamps not added: 110 ohm
|   slope of the pullup table from 0 to 0.165 V, typ, clamps not added: 80.8 kohm
|   GND clamp passes 1 mA (typ) near -0.45 V on its own axis
|   POWER clamp passes 1 mA (typ) near -0.88 V on its own axis
|   rising waveform, R_fixture 50, V_fixture 0.0: 20-80 % time 56.2ps typ, 58.8ps min, 48.6ps max; typ from 0 V to 0.137 V
|   falling waveform, R_fixture 50, V_fixture 1.1: 20-80 % time 59.3ps typ, 69ps min, 50.3ps max; typ from 1.1 V to 0.83 V
|   rising waveform, R_fixture 50, V_fixture 1.1: 20-80 % time 54.6ps typ, 58.8ps min, 50.7ps max; typ from 0.83 V to 1.1 V
|   falling waveform, R_fixture 50, V_fixture 0.0: 20-80 % time 42.3ps typ, 48.7ps min, 37.7ps max; typ from 0.137 V to 0 V
[Pulldown]
|   Voltage   I(typ)   I(min)   I(max)
-1.1V     -10.3mA    -9.096mA   -11.4mA
-1.021V   -9.804mA   -9.096mA   -10.83mA
-869mV    -8.932mA   -8.575mA   -9.693mA
-624.8mV  -7.325mA   -7.221mA   -7.789mA
-463.1mV  -5.763mA   -5.495mA   -6.266mA
-189.2mV  -1.938mA   -1.915mA   -1.998mA
41.8mV    390.2uA    389.2uA    387.4uA
348.7mV   2.951mA    2.889mA    3.049mA
649mV     4.711mA    4.421mA    5.188mA
883.3mV   5.548mA    5.069mA    6.4mA
1.174V    6.213mA    5.621mA    7.344mA
2.2V      7.677mA    6.979mA    9.076mA
[GND Clamp]
|   Voltage   I(typ)   I(min)   I(max)
-1.1V     -34.88mA   -30.34mA   -43.13mA
-941.6mV  -25.13mA   -21.34mA   -31.48mA
-803mV    -16.57mA   -13.55mA   -21.76mA
-730.4mV  -12.35mA   -9.712mA   -16.64mA
-667.7mV  -8.939mA   -6.742mA   -12.34mA
-591.8mV  -5.271mA   -3.798mA   -7.524mA
-522.5mV  -2.671mA   -1.906mA   -3.822mA
-466.4mV  -1.3mA     -942.9uA   -1.694mA
-413.6mV  -566uA     -416.5uA   -621.4uA
-341mV    -133.9uA   -101.9uA   -113.8uA
-232.1mV  -7.48uA    -7.211uA   -3.94uA
2.2V      0A         0A         0A
[Pullup]
|   Voltage   I(typ)   I(min)   I(max)
-1.1V     1.047uA    1.615uA    471.8nA
239.8mV   -9.309uA   -9.166uA   -9.951uA
348.7mV   -70.62uA   -58.36uA   -97.39uA
457.6mV   -294.6uA   -245.6uA   -360.1uA
566.5mV   -699.7uA   -652.8uA   -750.5uA
705.1mV   -1.361mA   -1.411mA   -1.342mA
992.2mV   -2.916mA   -3.298mA   -2.74mA
1.388V    -5.184mA   -5.919mA   -4.87mA
1.589V    -6.266mA   -7.078mA   -5.978mA
1.718V    -6.777mA   -7.604mA   -6.534mA
1.887V    -7.482mA   -8.134mA   -7.355mA
2.2V      -8.971mA   -9.018mA   -9.226mA
[POWER Clamp]
|   Voltage   I(typ)   I(min)   I(max)
-1.1V     3.036mA    3.636mA    2.186mA
-1.041V   2.347mA    2.931mA    1.626mA
-981.2mV  1.754mA    2.277mA    1.183mA
-911.9mV  1.202mA    1.611mA    765uA
-855.8mV  838.1uA    1.172mA    552.2uA
-776.6mV  434.2uA    683.6uA    390.2uA
-710.6mV  232.2uA    359.2uA    273.1uA
-654.5mV  142.7uA    170.4uA    185.9uA
-595.1mV  80.78uA    68.3uA     109.3uA
-499.4mV  21.4uA     13.11uA    27.46uA
-393.8mV  2.226uA    1.481uA    1.93uA
2.2V      0A         0A         0A
[Ramp]
|   typ   min   max
| 20% - 80%
dV/dt_r   82.36m/56.25p   84.13m/58.77p   87.14m/48.60p
dV/dt_f   161.72m/59.39p   147.10m/69.06p   188.45m/50.32p
| 25% - 75%
|dV/dt_r   68.64m/44.74p   70.11m/46.81p   72.62m/38.52p
|dV/dt_f   134.77m/47.23p   122.58m/54.98p   157.04m/39.88p
R_load = 50
[Rising Waveform]
R_fixture = 50
V_fixture = 0.0
|   Time   V(typ)   V(min)   V(max)
0s        146.6uV    118.3uV    109.6uV
58ps      63.55uV    144.1uV    3.52mV
79ps      2.465mV    -56.68uV   43.96mV
96ps      25mV       2.682mV    81.45mV
107ps     46.59mV    13.99mV    99.52mV
122ps     73.39mV    40.48mV    116.8mV
154ps     110.3mV    92.25mV    135.4mV
190ps     128mV      122.3mV    142.3mV
231ps     134.7mV    135mV      144.6mV
440ps     137.4mV    140.3mV    145.3mV
[Falling Waveform]
R_fixture   = 50
V_fixture   = 1.1
V_fixture_min = 1.06
V_fixture_max = 1.17
|   Time   V(typ)   V(min)   V(max)
0s        1.1V       1.06V      1.17V
72ps      1.1V       1.06V      1.167V
79ps      1.101V     1.06V      1.145V
95ps      1.093V     1.06V      1.064V
122ps     1.002V     1.048V     954.7mV
146ps     928.9mV    985.7mV    903.5mV
172ps     881mV      918.9mV    876.9mV
211ps     848.1mV    858.9mV    862mV
256ps     835.6mV    830.1mV    857.4mV
440ps     830.5mV    814.8mV    855.9mV
[Rising Waveform]
R_fixture   = 50
V_fixture   = 1.1
V_fixture_min = 1.06
V_fixture_max = 1.17
|   Time   V(typ)   V(min)   V(max)
0s        830.3mV    814.6mV    855.9mV
55ps      827.1mV    811.8mV    863.2mV
68ps      839.9mV    810.1mV    919.6mV
79ps      879.1mV    819.8mV    985.7mV
102ps     975.8mV    895.2mV    1.072V
123ps     1.027V     960mV      1.114V
149ps     1.062V     1.006V     1.143V
181ps     1.083V     1.035V     1.159V
233ps     1.095V     1.053V     1.167V
440ps     1.1V       1.06V      1.17V
[Falling Waveform]
R_fixture = 50
V_fixture = 0.0
|   Time   V(typ)   V(min)   V(max)
0s        137.5mV    140.4mV    145.4mV
60ps      139.6mV    141.7mV    143.4mV
71ps      138.6mV    143.5mV    124mV
87ps      121mV      140.3mV    71.16mV
101ps     85.58mV    123.2mV    42.36mV
116ps     51.71mV    92.93mV    24.46mV
145ps     19.25mV    39.49mV    8.469mV
172ps     7.779mV    16.73mV    3.221mV
212ps     2.152mV    4.813mV    859.5uV
440ps     222.6uV    217.3uV    133.7uV
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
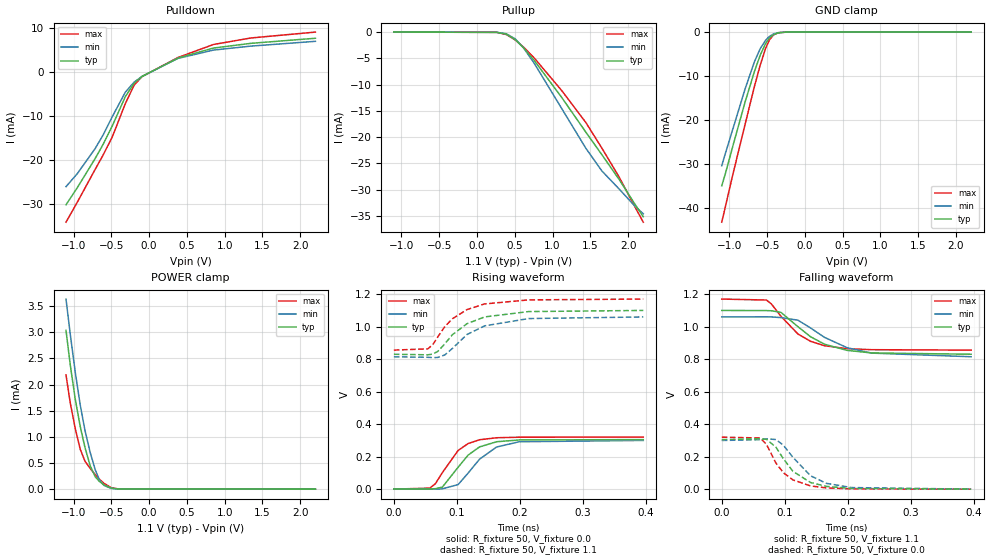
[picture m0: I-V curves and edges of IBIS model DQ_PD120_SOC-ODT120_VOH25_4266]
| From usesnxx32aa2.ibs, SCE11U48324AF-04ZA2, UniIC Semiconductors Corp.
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| DQ_PD120_SOC-ODT120_VOH25_4266
| (120 Ohm Pulldown, 120 Ohm System ODT Setting, VOH=VDDQ/2.5, 3200-4266Mbps)
[Model]   DQ_PD120_SOC-ODT120_VOH25_4266
Model_type   I/O
Vinl = 160.000mV
Vinh = 280.000mV
Vmeas = 220.000mV
Vref = 0.0mV
Cref = 0.0pF
Rref = 120.000Ohm
|   typ   min   max
|C_comp   0.797pF   0.747pF   0.847pF
C_comp_pullup   0.3985pF   0.3735pF   0.4235pF
C_comp_pulldown   0.3985pF   0.3735pF   0.4235pF
| Note: C_comp changes when the ODT circuit is enabled.
[Model Spec]
| Input threshold voltage corners
Vinl   0.1600V   0.1520V   0.1740V
Vinh   0.2800V   0.2720V   0.2940V
| Measurement voltage corners
Vmeas   0.2200V   0.2120V   0.2340V
| Timing spec test load voltage corners
Vref   0.0000V   0.0000V   0.0000V
| Dynamic Overshoot Parameters from LPDDR4 Specification
D_overshoot_ampl_h   0.30   NA   NA
D_overshoot_ampl_l   0.30   NA   NA
D_overshoot_area_h   0.1n   NA   NA
D_overshoot_area_l   0.1n   NA   NA
[Receiver Thresholds]
Vth   = 0.2200V
Vth_min  = 0.2167V
Vth_max  = 0.2233V
Vinh_ac  = 0.060V
Vinh_dc  = 0.060V
Vinl_ac  = -0.060V
Vinl_dc  = -0.060V
Tslew_ac = 5.000ns |Not specified, so set to high value
Threshold_sensitivity = 0.2000
Reference_supply Pullup_ref
[Voltage Range]   1.1000V   1.0600V   1.1700V
[Pullup Reference]   1.1000V   1.0600V   1.1700V
| Junction Temperature (Ambient temp is 35C typ 95C min -40C max)
[Temperature Range]   50.0   110.0   -40.0
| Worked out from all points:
|   slope of the pulldown table from 0 to 0.165 V, typ, clamps not added: 109 ohm
|   slope of the pullup table from 0 to 0.165 V, typ, clamps not added: 26.3 kohm
|   GND clamp passes 1 mA (typ) near -0.45 V on its own axis
|   POWER clamp passes 1 mA (typ) near -0.88 V on its own axis
|   rising waveform, R_fixture 50, V_fixture 0.0: 20-80 % time 39.7ps typ, 43.5ps min, 36.1ps max; typ from 0.001 V to 0.305 V
|   falling waveform, R_fixture 50, V_fixture 1.1: 20-80 % time 60.2ps typ, 70.7ps min, 50.6ps max; typ from 1.1 V to 0.83 V
|   rising waveform, R_fixture 50, V_fixture 1.1: 20-80 % time 53.7ps typ, 56.1ps min, 50.2ps max; typ from 0.83 V to 1.1 V
|   falling waveform, R_fixture 50, V_fixture 0.0: 20-80 % time 40.9ps typ, 46.1ps min, 36.1ps max; typ from 0.305 V to 0.001 V
[Pulldown]
|   Voltage   I(typ)   I(min)   I(max)
-1.1V     -30.11mA   -26mA      -34.06mA
-951.5mV  -26.26mA   -23.06mA   -29.56mA
-717.2mV  -19.7mA    -17.43mA   -22.17mA
-611.6mV  -16.49mA   -14.35mA   -18.91mA
-489.5mV  -12.27mA   -10.18mA   -14.79mA
-314.6mV  -5.562mA   -4.543mA   -7.142mA
-199.1mV  -2.525mA   -2.284mA   -2.976mA
-93.5mV   -1.001mA   -972.5uA   -1.012mA
381.7mV   3.184mA    3.109mA    3.311mA
850.3mV   5.453mA    4.993mA    6.257mA
1.345V    6.52mA     5.892mA    7.737mA
2.2V      7.677mA    6.979mA    9.076mA
[GND Clamp]
|   Voltage   I(typ)   I(min)   I(max)
-1.1V     -34.88mA   -30.33mA   -43.14mA
-1.05V    -32mA      -27.43mA   -39.48mA
-948.2mV  -25.55mA   -21.71mA   -31.96mA
-789.8mV  -15.79mA   -12.83mA   -20.84mA
-667.7mV  -8.943mA   -6.74mA    -12.35mA
-591.8mV  -5.273mA   -3.797mA   -7.531mA
-519.2mV  -2.57mA    -1.834mA   -3.675mA
-469.7mV  -1.364mA   -988uA     -1.791mA
-413.6mV  -565.9uA   -417.4uA   -619.8uA
-350.9mV  -166.1uA   -126.2uA   -147.5uA
-248.6mV  -12.38uA   -10.9uA    -7.11uA
2.2V      0A         0A         0A
[Pullup]
|   Voltage   I(typ)   I(min)   I(max)
-1.1V     2.741uA    4.961uA    908.6nA
262.9mV   -43.11uA   -42.51uA   -44.35uA
388.3mV   -384.2uA   -319uA     -459.6uA
507.1mV   -1.445mA   -1.305mA   -1.506mA
616mV     -2.987mA   -3.007mA   -2.855mA
757.9mV   -5.42mA    -5.953mA   -4.933mA
1.118V    -12.38mA   -14.48mA   -11.08mA
1.441V    -19.06mA   -22.13mA   -17.22mA
1.652V    -23.33mA   -26.42mA   -22.08mA
1.877V    -27.97mA   -29.81mA   -27.5mA
2.094V    -32.85mA   -33.2mA    -33.38mA
2.2V      -35.14mA   -34.58mA   -36.18mA
[POWER Clamp]
|   Voltage   I(typ)   I(min)   I(max)
-1.1V     3.036mA    3.636mA    2.186mA
-1.044V   2.383mA    2.969mA    1.654mA
-977.9mV  1.724mA    2.242mA    1.161mA
-911.9mV  1.201mA    1.611mA    764.5uA
-849.2mV  799.3uA    1.126mA    535.6uA
-779.9mV  447.9uA    701.9uA    396.3uA
-713.9mV  239.2uA    373.1uA    278.6uA
-661.1mV  151.1uA    187.5uA    195.5uA
-598.4mV  83.64uA    71.96uA    113.1uA
-502.7mV  22.68uA    14.02uA    29.27uA
-400.4mV  2.576uA    1.697uA    2.316uA
2.2V      0A         0A         0A
[Ramp]
|   typ   min   max
| 20% - 80%
dV/dt_r   182.59m/39.72p   179.66m/43.49p   191.90m/36.13p
dV/dt_f   161.72m/60.18p   146.92m/70.60p   188.44m/50.63p
| 25% - 75%
|dV/dt_r   152.16m/31.62p   149.72m/34.68p   159.91m/28.74p
|dV/dt_f   134.77m/47.84p   122.43m/56.19p   157.03m/40.22p
R_load = 50
[Rising Waveform]
R_fixture = 50
V_fixture = 0.0
|   Time   V(typ)   V(min)   V(max)
0s        649.1uV    533uV      474.7uV
57ps      760.4uV    29.04uV    6.335mV
66ps      3.147mV    6.685uV    34.14mV
77ps      12.72mV    2.143mV    102mV
102ps     134.9mV    28.18mV    238.2mV
118ps     209.9mV    99.49mV    280.9mV
136ps     259.9mV    184.5mV    304.1mV
163ps     291.9mV    259.2mV    316.4mV
199ps     302.9mV    291.8mV    319.8mV
396ps     305mV      300mV      320.3mV
[Falling Waveform]
R_fixture   = 50
V_fixture   = 1.1
V_fixture_min = 1.06
V_fixture_max = 1.17
|   Time   V(typ)   V(min)   V(max)
0s        1.1V       1.06V      1.17V
71ps      1.099V     1.061V     1.164V
79ps      1.098V     1.06V      1.139V
94ps      1.088V     1.056V     1.064V
121ps     1V         1.04V      955.1mV
141ps     938.3mV    992.2mV    910.1mV
163ps     892.5mV    934.7mV    883.1mV
199ps     854.3mV    870.7mV    864.6mV
238ps     838.6mV    837.5mV    858.5mV
396ps     830.5mV    815.1mV    855.9mV
[Rising Waveform]
R_fixture   = 50
V_fixture   = 1.1
V_fixture_min = 1.06
V_fixture_max = 1.17
|   Time   V(typ)   V(min)   V(max)
0s        830.3mV    814.6mV    855.9mV
54ps      826.8mV    811.7mV    863.6mV
62ps      831.7mV    809.4mV    890.6mV
70ps      848.7mV    810.8mV    938.6mV
81ps      895.1mV    826.5mV    1.001V
93ps      950.8mV    866.4mV    1.049V
116ps     1.018V     951.5mV    1.105V
144ps     1.06V      1.005V     1.14V
214ps     1.093V     1.05V      1.165V
396ps     1.1V       1.06V      1.17V
[Falling Waveform]
R_fixture = 50
V_fixture = 0.0
|   Time   V(typ)   V(min)   V(max)
0s        305.1mV    300.1mV    320.4mV
61ps      310.8mV    304.8mV    315.4mV
71ps      307.2mV    310.6mV    276.2mV
86ps      259.1mV    305.8mV    161.1mV
98ps      186.6mV    270.4mV    101.2mV
113ps     110.2mV    196.5mV    57.5mV
141ps     41.4mV     82.87mV    20.42mV
166ps     17.68mV    36.56mV    8.386mV
206ps     5.001mV    10.4mV     2.299mV
396ps     729.9uV    651.5uV    512.5uV
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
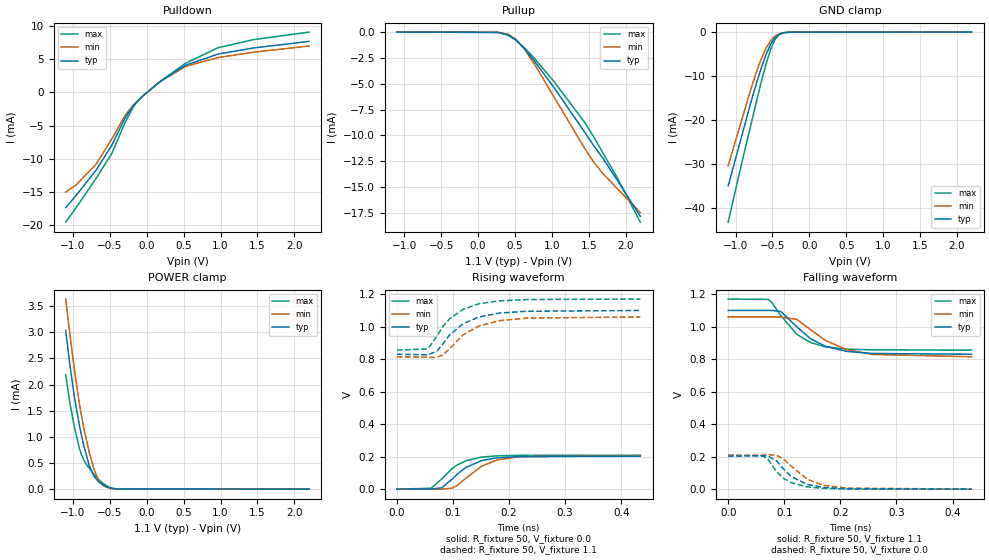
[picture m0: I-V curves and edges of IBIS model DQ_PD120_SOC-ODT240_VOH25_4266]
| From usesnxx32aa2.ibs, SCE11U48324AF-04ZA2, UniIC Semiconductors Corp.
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| DQ_PD120_SOC-ODT240_VOH25_4266
| (120 Ohm Pulldown, 240 Ohm System ODT Setting, VOH=VDDQ/2.5, 3200-4266Mbps)
[Model]   DQ_PD120_SOC-ODT240_VOH25_4266
Model_type   I/O
Vinl = 160.000mV
Vinh = 280.000mV
Vmeas = 220.000mV
Vref = 0.0mV
Cref = 0.0pF
Rref = 240.000Ohm
|   typ   min   max
|C_comp   0.797pF   0.747pF   0.847pF
C_comp_pullup   0.3985pF   0.3735pF   0.4235pF
C_comp_pulldown   0.3985pF   0.3735pF   0.4235pF
| Note: C_comp changes when the ODT circuit is enabled.
[Model Spec]
| Input threshold voltage corners
Vinl   0.1600V   0.1520V   0.1740V
Vinh   0.2800V   0.2720V   0.2940V
| Measurement voltage corners
Vmeas   0.2200V   0.2120V   0.2340V
| Timing spec test load voltage corners
Vref   0.0000V   0.0000V   0.0000V
| Dynamic Overshoot Parameters from LPDDR4 Specification
D_overshoot_ampl_h   0.30   NA   NA
D_overshoot_ampl_l   0.30   NA   NA
D_overshoot_area_h   0.1n   NA   NA
D_overshoot_area_l   0.1n   NA   NA
[Receiver Thresholds]
Vth   = 0.2200V
Vth_min  = 0.2167V
Vth_max  = 0.2233V
Vinh_ac  = 0.060V
Vinh_dc  = 0.060V
Vinl_ac  = -0.060V
Vinl_dc  = -0.060V
Tslew_ac = 5.000ns |Not specified, so set to high value
Threshold_sensitivity = 0.2000
Reference_supply Pullup_ref
[Voltage Range]   1.1000V   1.0600V   1.1700V
[Pullup Reference]   1.1000V   1.0600V   1.1700V
| Junction Temperature (Ambient temp is 35C typ 95C min -40C max)
[Temperature Range]   50.0   110.0   -40.0
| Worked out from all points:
|   slope of the pulldown table from 0 to 0.165 V, typ, clamps not added: 110 ohm
|   slope of the pullup table from 0 to 0.165 V, typ, clamps not added: 53.3 kohm
|   GND clamp passes 1 mA (typ) near -0.45 V on its own axis
|   POWER clamp passes 1 mA (typ) near -0.88 V on its own axis
|   rising waveform, R_fixture 50, V_fixture 0.0: 20-80 % time 46.8ps typ, 51.2ps min, 43ps max; typ from 0 V to 0.203 V
|   falling waveform, R_fixture 50, V_fixture 1.1: 20-80 % time 59.6ps typ, 69.8ps min, 50.4ps max; typ from 1.1 V to 0.83 V
|   rising waveform, R_fixture 50, V_fixture 1.1: 20-80 % time 54.3ps typ, 58.2ps min, 50.4ps max; typ from 0.83 V to 1.1 V
|   falling waveform, R_fixture 50, V_fixture 0.0: 20-80 % time 41.7ps typ, 47.5ps min, 36.8ps max; typ from 0.203 V to 0 V
[Pulldown]
|   Voltage   I(typ)   I(min)   I(max)
-1.1V     -17.37mA   -15.03mA   -19.56mA
-951.5mV  -15.43mA   -13.87mA   -17.26mA
-684.2mV  -11.67mA   -10.76mA   -12.9mA
-473mV    -7.935mA   -7.001mA   -9.171mA
-294.8mV  -3.872mA   -3.471mA   -4.556mA
-176mV    -1.902mA   -1.833mA   -2.028mA
-57.2mV   -573.4uA   -568.2uA   -564.8uA
183.7mV   1.653mA    1.637mA    1.664mA
523.6mV   4.075mA    3.906mA    4.365mA
969.1mV   5.773mA    5.25mA     6.731mA
1.448V    6.686mA    6.043mA    7.941mA
2.2V      7.677mA    6.979mA    9.076mA
[GND Clamp]
|   Voltage   I(typ)   I(min)   I(max)
-1.1V     -34.89mA   -30.33mA   -43.14mA
-948.2mV  -25.55mA   -21.71mA   -31.96mA
-796.4mV  -16.18mA   -13.19mA   -21.3mA
-720.5mV  -11.8mA    -9.215mA   -15.96mA
-661.1mV  -8.6mA     -6.453mA   -11.91mA
-588.5mV  -5.13mA    -3.689mA   -7.335mA
-522.5mV  -2.671mA   -1.906mA   -3.827mA
-469.7mV  -1.359mA   -987.4uA   -1.792mA
-413.6mV  -564uA     -418.3uA   -622.3uA
-350.9mV  -166.4uA   -126.2uA   -147.6uA
-261.8mV  -17.75uA   -15.44uA   -11.06uA
2.2V      0A         0A         0A
[Pullup]
|   Voltage   I(typ)   I(min)   I(max)
-1.1V     1.371uA    2.481uA    454.5nA
269.5mV   -24.65uA   -23.81uA   -25.87uA
411.4mV   -264.6uA   -220.2uA   -309.3uA
513.7mV   -768.1uA   -699.5uA   -794.3uA
625.9mV   -1.587mA   -1.614mA   -1.506mA
757.9mV   -2.738mA   -3.016mA   -2.487mA
1.032V    -5.393mA   -6.298mA   -4.813mA
1.448V    -9.715mA   -11.29mA   -8.771mA
1.566V    -10.97mA   -12.58mA   -10.12mA
1.688V    -12.17mA   -13.66mA   -11.64mA
1.887V    -14.33mA   -15.16mA   -14.11mA
2.2V      -17.84mA   -17.48mA   -18.41mA
[POWER Clamp]
|   Voltage   I(typ)   I(min)   I(max)
-1.1V     3.036mA    3.636mA    2.186mA
-1.044V   2.383mA    2.969mA    1.654mA
-981.2mV  1.754mA    2.277mA    1.183mA
-911.9mV  1.201mA    1.612mA    764.8uA
-855.8mV  838.1uA    1.172mA    552.2uA
-779.9mV  448.2uA    701.7uA    396.3uA
-713.9mV  239.3uA    373.1uA    278.6uA
-654.5mV  142.7uA    170.4uA    185.9uA
-591.8mV  77.91uA    64.89uA    105.5uA
-499.4mV  21.27uA    13.16uA    27.44uA
-397.1mV  2.388uA    1.591uA    2.114uA
2.2V      0A         0A         0A
[Ramp]
|   typ   min   max
| 20% - 80%
dV/dt_r   121.52m/46.83p   123.83m/51.20p   125.32m/43.03p
dV/dt_f   161.72m/59.60p   147.07m/69.70p   188.45m/50.44p
| 25% - 75%
|dV/dt_r   101.27m/37.25p   103.20m/40.81p   104.43m/34.17p
|dV/dt_f   134.76m/47.41p   122.56m/55.29p   157.04m/39.99p
R_load = 50
[Rising Waveform]
R_fixture = 50
V_fixture = 0.0
|   Time   V(typ)   V(min)   V(max)
0s        319.9uV    255.8uV    236.7uV
61ps      304.6uV    58.7uV     5.603mV
80ps      8.717mV    420.2uV    63.66mV
98ps      60.5mV     6.237mV    125.8mV
108ps     93.71mV    23.94mV    150.3mV
123ps     133.7mV    67.46mV    175mV
151ps     176mV      141mV      197.4mV
178ps     192.8mV    179.3mV    205mV
219ps     200.7mV    200.4mV    208.3mV
434ps     202.9mV    206.6mV    209.1mV
[Falling Waveform]
R_fixture   = 50
V_fixture   = 1.1
V_fixture_min = 1.06
V_fixture_max = 1.17
|   Time   V(typ)   V(min)   V(max)
0s        1.1V       1.06V      1.17V
71ps      1.1V       1.06V      1.168V
78ps      1.1V       1.06V      1.148V
94ps      1.093V     1.059V     1.068V
122ps     1.001V     1.046V     954.3mV
146ps     928.2mV    983.9mV    903.3mV
173ps     879.4mV    916mV      876.2mV
211ps     848mV      858.6mV    862mV
257ps     835.4mV    829.6mV    857.3mV
434ps     830.5mV    814.9mV    855.9mV
[Rising Waveform]
R_fixture   = 50
V_fixture   = 1.1
V_fixture_min = 1.06
V_fixture_max = 1.17
|   Time   V(typ)   V(min)   V(max)
0s        830.3mV    814.6mV    855.9mV
55ps      827mV      811.7mV    863.2mV
71ps      848.7mV    811mV      940.4mV
82ps      895mV      826.1mV    1.001V
94ps      949.4mV    865mV      1.049V
118ps     1.018V     950.1mV    1.107V
146ps     1.06V      1.004V     1.141V
183ps     1.084V     1.037V     1.159V
232ps     1.095V     1.053V     1.167V
434ps     1.1V       1.06V      1.17V
[Falling Waveform]
R_fixture = 50
V_fixture = 0.0
|   Time   V(typ)   V(min)   V(max)
0s        202.9mV    206.7mV    209.2mV
61ps      205.8mV    209.2mV    205.9mV
71ps      203.6mV    212.4mV    183.2mV
86ps      174.4mV    208.9mV    109mV
98ps      127.4mV    187mV      69.06mV
113ps     76.34mV    139.9mV    39.51mV
141ps     29.18mV    60.82mV    14.1mV
170ps     10.95mV    23.98mV    5.035mV
211ps     2.985mV    6.678mV    1.324mV
434ps     404.2uV    364.1uV    265.4uV
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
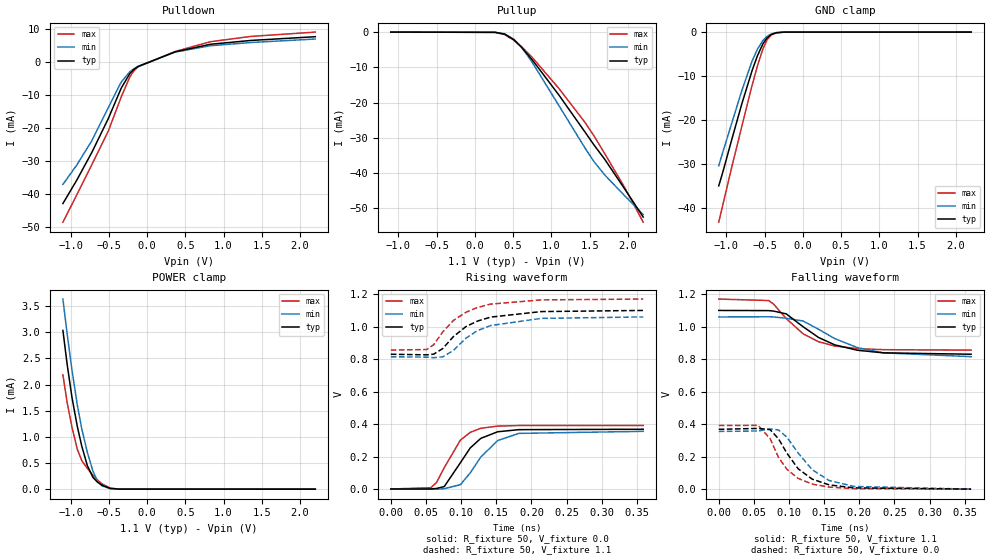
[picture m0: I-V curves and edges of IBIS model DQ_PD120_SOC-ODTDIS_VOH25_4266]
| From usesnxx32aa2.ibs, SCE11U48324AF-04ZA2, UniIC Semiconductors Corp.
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| DQ_PD120_SOC-ODTDIS_VOH25_4266
| (120 Ohm Pulldown, SOC ODT disabled setting, VOH=VDDQ/2.5 cal. point, 3200-4266Mbps)
[Model]   DQ_PD120_SOC-ODTDIS_VOH25_4266
Model_type   I/O
Vinl = 160.000mV
Vinh = 280.000mV
Vmeas = 220.000mV
Vref = 0.0mV
Cref = 0.0pF
|   typ   min   max
|C_comp   0.797pF   0.747pF   0.847pF
C_comp_pullup   0.3985pF   0.3735pF   0.4235pF
C_comp_pulldown   0.3985pF   0.3735pF   0.4235pF
| Note: C_comp changes when the ODT circuit is enabled.
[Model Spec]
| Input threshold voltage corners
Vinl   0.1600V   0.1520V   0.1740V
Vinh   0.2800V   0.2720V   0.2940V
| Measurement voltage corners
Vmeas   0.2200V   0.2120V   0.2340V
| Timing spec test load voltage corners
Vref   0.0000V   0.0000V   0.0000V
| Dynamic Overshoot Parameters from LPDDR4 Specification
D_overshoot_ampl_h   0.30   NA   NA
D_overshoot_ampl_l   0.30   NA   NA
D_overshoot_area_h   0.1n   NA   NA
D_overshoot_area_l   0.1n   NA   NA
[Receiver Thresholds]
Vth   = 0.2200V
Vth_min  = 0.2167V
Vth_max  = 0.2233V
Vinh_ac  = 0.060V
Vinh_dc  = 0.060V
Vinl_ac  = -0.060V
Vinl_dc  = -0.060V
Tslew_ac = 5.000ns |Not specified, so set to high value
Threshold_sensitivity = 0.2000
Reference_supply Pullup_ref
[Voltage Range]   1.1000V   1.0600V   1.1700V
[Pullup Reference]   1.1000V   1.0600V   1.1700V
| Junction Temperature (Ambient temp is 35C typ 95C min -40C max)
[Temperature Range]   50.0   110.0   -40.0
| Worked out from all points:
|   slope of the pulldown table from 0 to 0.165 V, typ, clamps not added: 108 ohm
|   slope of the pullup table from 0 to 0.165 V, typ, clamps not added: 17.6 kohm
|   GND clamp passes 1 mA (typ) near -0.45 V on its own axis
|   POWER clamp passes 1 mA (typ) near -0.88 V on its own axis
|   rising waveform, R_fixture 50, V_fixture 0.0: 20-80 % time 34.8ps typ, 38.7ps min, 31.6ps max; typ from 0.001 V to 0.369 V
|   falling waveform, R_fixture 50, V_fixture 1.1: 20-80 % time 60.7ps typ, 71.4ps min, 51.1ps max; typ from 1.1 V to 0.831 V
|   rising waveform, R_fixture 50, V_fixture 1.1: 20-80 % time 53ps typ, 53.5ps min, 49.9ps max; typ from 0.83 V to 1.1 V
|   falling waveform, R_fixture 50, V_fixture 0.0: 20-80 % time 40.6ps typ, 45.4ps min, 35.8ps max; typ from 0.369 V to 0.001 V
[Pulldown]
|   Voltage   I(typ)   I(min)   I(max)
-1.1V     -42.88mA   -37.08mA   -48.53mA
-921.8mV  -35.92mA   -31.32mA   -40.41mA
-720.5mV  -27.34mA   -23.79mA   -31.03mA
-506mV    -17.11mA   -13.82mA   -20.9mA
-337.7mV  -7.915mA   -6.081mA   -10.6mA
-225.5mV  -3.514mA   -2.947mA   -4.556mA
-176mV    -2.333mA   -2.082mA   -2.775mA
-116.6mV  -1.357mA   -1.28mA    -1.435mA
368.5mV   3.092mA    3.022mA    3.207mA
827.2mV   5.382mA    4.938mA    6.152mA
1.355V    6.536mA    5.907mA    7.758mA
2.2V      7.677mA    6.979mA    9.076mA
[GND Clamp]
|   Voltage   I(typ)   I(min)   I(max)
-1.1V     -34.89mA   -30.33mA   -43.14mA
-1.05V    -32mA      -27.43mA   -39.48mA
-935mV    -24.72mA   -20.96mA   -31.01mA
-796.4mV  -16.18mA   -13.19mA   -21.3mA
-664.4mV  -8.771mA   -6.596mA   -12.13mA
-595.1mV  -5.419mA   -3.907mA   -7.727mA
-522.5mV  -2.67mA    -1.904mA   -3.825mA
-469.7mV  -1.359mA   -988.2uA   -1.791mA
-413.6mV  -564.6uA   -417.4uA   -622.2uA
-347.6mV  -154.6uA   -117.4uA   -135.8uA
-245.3mV  -10.96uA   -10.12uA   -6.337uA
2.2V      0A         0A         0A
[Pullup]
|   Voltage   I(typ)   I(min)   I(max)
-1.1V     4.112uA    7.441uA    1.363uA
262.9mV   -64.99uA   -63.29uA   -66.46uA
388.3mV   -575.5uA   -479.6uA   -688.1uA
510.4mV   -2.219mA   -2.013mA   -2.307mA
609.4mV   -4.304mA   -4.306mA   -4.133mA
744.7mV   -7.731mA   -8.429mA   -7.062mA
1.095V    -17.77mA   -20.74mA   -15.91mA
1.438V    -28.31mA   -32.84mA   -25.59mA
1.556V    -31.99mA   -36.71mA   -29.41mA
1.698V    -36.11mA   -40.55mA   -34.5mA
1.956V    -44.42mA   -46.36mA   -44.02mA
2.2V      -52.46mA   -51.75mA   -53.91mA
[POWER Clamp]
|   Voltage   I(typ)   I(min)   I(max)
-1.1V     3.036mA    3.636mA    2.186mA
-1.044V   2.383mA    2.969mA    1.654mA
-981.2mV  1.754mA    2.277mA    1.183mA
-911.9mV  1.201mA    1.612mA    764.9uA
-852.5mV  818.5uA    1.149mA    544uA
-779.9mV  448uA      701.7uA    396.3uA
-707.3mV  225.5uA    345.4uA    267.6uA
-651.2mV  138.6uA    162.3uA    181.2uA
-591.8mV  77.97uA    64.81uA    105.5uA
-482.9mV  15.73uA    9.523uA    19.49uA
-360.8mV  1.023uA    769.8nA    796.4nA
2.2V      0A         0A         0A
[Ramp]
|   typ   min   max
| 20% - 80%
dV/dt_r   220.61m/34.82p   212.97m/38.74p   234.73m/31.59p
dV/dt_f   161.63m/60.82p   146.50m/71.34p   188.45m/51.05p
| 25% - 75%
|dV/dt_r   183.84m/27.70p   177.47m/30.83p   195.61m/25.07p
|dV/dt_f   134.69m/48.29p   122.08m/56.72p   157.04m/40.49p
R_load = 50
[Rising Waveform]
R_fixture = 50
V_fixture = 0.0
|   Time   V(typ)   V(min)   V(max)
0s        973.2uV    806.1uV    709.8uV
57ps      998.1uV    -47.84nV   8.908mV
65ps      4.213mV    -188.4uV   40.41mV
76ps      15.78mV    2.477mV    132.3mV
99ps      162.7mV    27.49mV    301.6mV
113ps     253.6mV    100.3mV    349.8mV
128ps     312.6mV    197.8mV    374.5mV
152ps     353.2mV    298.9mV    388.1mV
182ps     366.1mV    343.1mV    391.5mV
359ps     368.7mV    355.8mV    391.9mV
[Falling Waveform]
R_fixture   = 50
V_fixture   = 1.1
V_fixture_min = 1.06
V_fixture_max = 1.17
|   Time   V(typ)   V(min)   V(max)
0s        1.1V       1.06V      1.17V
71ps      1.099V     1.061V     1.161V
78ps      1.096V     1.06V      1.139V
96ps      1.079V     1.052V     1.05V
120ps     999.8mV    1.035V     956.3mV
142ps     933.6mV    984.1mV    907.6mV
165ps     888.4mV    926.8mV    881.1mV
197ps     855.3mV    871.7mV    865.1mV
234ps     839.3mV    839.2mV    858.7mV
359ps     830.6mV    815.8mV    855.9mV
[Rising Waveform]
R_fixture   = 50
V_fixture   = 1.1
V_fixture_min = 1.06
V_fixture_max = 1.17
|   Time   V(typ)   V(min)   V(max)
0s        830.3mV    814.6mV    855.9mV
51ps      826.6mV    812.6mV    859.4mV
61ps      830.9mV    809.2mV    889mV
74ps      865.8mV    814.3mV    968.5mV
89ps      938.8mV    853.9mV    1.038V
107ps     1.001V     929.5mV    1.089V
123ps     1.034V     975.1mV    1.118V
142ps     1.059V     1.007V     1.139V
214ps     1.093V     1.051V     1.165V
359ps     1.1V       1.06V      1.17V
[Falling Waveform]
R_fixture = 50
V_fixture = 0.0
|   Time   V(typ)   V(min)   V(max)
0s        368.8mV    355.9mV    392mV
56ps      374.3mV    358.6mV    393.3mV
73ps      367.3mV    371.1mV    312.1mV
85ps      310.7mV    365mV      196.3mV
97ps      222mV      320.4mV    122.8mV
113ps     126mV      222.7mV    66.98mV
133ps     62.26mV    120.1mV    31.86mV
157ps     27.28mV    54.08mV    13.35mV
192ps     8.729mV    17.59mV    4.138mV
359ps     1.048mV    958.1uV    738.7uV
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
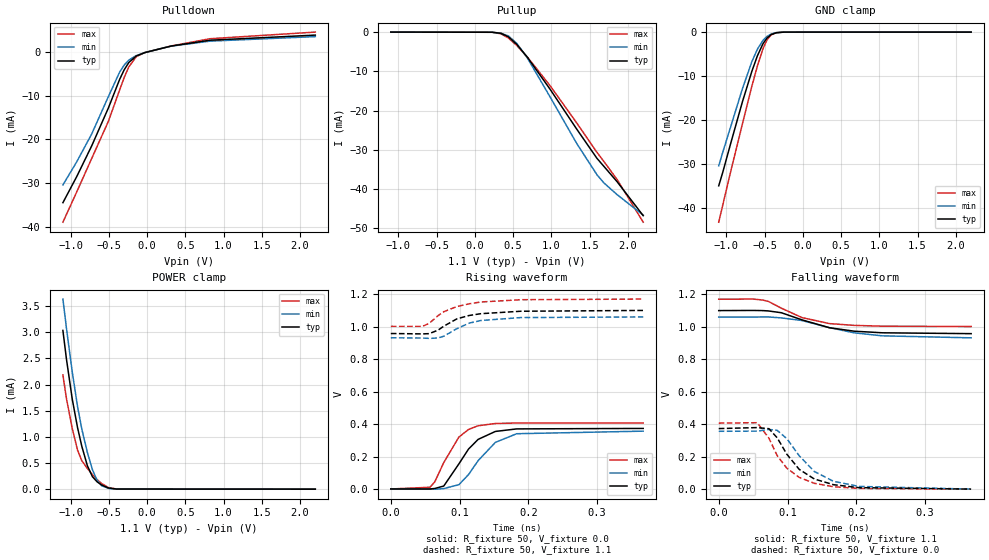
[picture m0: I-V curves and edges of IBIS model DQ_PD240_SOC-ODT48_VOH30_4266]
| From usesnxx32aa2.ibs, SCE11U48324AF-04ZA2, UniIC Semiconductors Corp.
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| DQ_PD240_SOC-ODT48_VOH30_4266
| (240 Ohm Pulldown, 48 Ohm System ODT Setting, VOH=VDDQ/3.0, 3200-4266Mbps)
[Model]   DQ_PD240_SOC-ODT48_VOH30_4266
Model_type   I/O
Vinl = 123.333mV
Vinh = 243.333mV
Vmeas = 183.333mV
Vref = 0.0mV
Cref = 0.0pF
Rref = 48.000Ohm
|   typ   min   max
|C_comp   0.797pF   0.747pF   0.847pF
C_comp_pullup   0.3985pF   0.3735pF   0.4235pF
C_comp_pulldown   0.3985pF   0.3735pF   0.4235pF
| Note: C_comp changes when the ODT circuit is enabled.
[Model Spec]
| Input threshold voltage corners
Vinl   0.1233V   0.1167V   0.1350V
Vinh   0.2433V   0.2367V   0.2550V
| Measurement voltage corners
Vmeas   0.1833V   0.1767V   0.1950V
| Timing spec test load voltage corners
Vref   0.0000V   0.0000V   0.0000V
| Dynamic Overshoot Parameters from LPDDR4 Specification
D_overshoot_ampl_h   0.30   NA   NA
D_overshoot_ampl_l   0.30   NA   NA
D_overshoot_area_h   0.1n   NA   NA
D_overshoot_area_l   0.1n   NA   NA
[Receiver Thresholds]
Vth   = 0.1833V
Vth_min  = 0.1800V
Vth_max  = 0.1866V
Vinh_ac  = 0.060V
Vinh_dc  = 0.060V
Vinl_ac  = -0.060V
Vinl_dc  = -0.060V
Tslew_ac = 5.000ns |Not specified, so set to high value
Threshold_sensitivity = 0.1667
Reference_supply Pullup_ref
[Voltage Range]   1.1000V   1.0600V   1.1700V
[Pullup Reference]   1.1000V   1.0600V   1.1700V
| Junction Temperature (Ambient temp is 35C typ 95C min -40C max)
[Temperature Range]   50.0   110.0   -40.0
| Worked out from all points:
|   slope of the pulldown table from 0 to 0.165 V, typ, clamps not added: 221 ohm
|   slope of the pullup table from 0 to 0.165 V, typ, clamps not added: 15.5 kohm
|   GND clamp passes 1 mA (typ) near -0.45 V on its own axis
|   POWER clamp passes 1 mA (typ) near -0.88 V on its own axis
|   rising waveform, R_fixture 50, V_fixture 0.0: 20-80 % time 36.6ps typ, 41.5ps min, 31.9ps max; typ from 0.001 V to 0.374 V
|   falling waveform, R_fixture 50, V_fixture 1.1: 20-80 % time 68.4ps typ, 79.3ps min, 57.6ps max; typ from 1.1 V to 0.958 V
|   rising waveform, R_fixture 50, V_fixture 1.1: 20-80 % time 46.1ps typ, 42ps min, 48.2ps max; typ from 0.958 V to 1.1 V
|   falling waveform, R_fixture 50, V_fixture 0.0: 20-80 % time 45.5ps typ, 49.7ps min, 41.6ps max; typ from 0.374 V to 0.001 V
[Pulldown]
|   Voltage   I(typ)   I(min)   I(max)
-1.1V     -34.43mA   -30.37mA   -38.88mA
-918.5mV  -28.45mA   -25.08mA   -31.95mA
-723.8mV  -21.48mA   -18.76mA   -24.35mA
-506mV    -12.84mA   -10.24mA   -15.89mA
-357.5mV  -6.264mA   -4.601mA   -8.662mA
-298.1mV  -4.083mA   -3.007mA   -5.834mA
-238.7mV  -2.452mA   -1.899mA   -3.46mA
-139.7mV  -941.2uA   -844.2uA   -1.083mA
-27.5mV   -166.6uA   -159.8uA   -157.8uA
315.7mV   1.316mA    1.297mA    1.34mA
823.9mV   2.649mA    2.443mA    2.993mA
2.2V      3.818mA    3.475mA    4.505mA
[GND Clamp]
|   Voltage   I(typ)   I(min)   I(max)
-1.1V     -34.88mA   -30.34mA   -43.13mA
-1.047V   -31.79mA   -27.25mA   -39.23mA
-941.6mV  -25.13mA   -21.34mA   -31.48mA
-789.8mV  -15.79mA   -12.83mA   -20.82mA
-667.7mV  -8.939mA   -6.743mA   -12.34mA
-595.1mV  -5.415mA   -3.908mA   -7.72mA
-522.5mV  -2.671mA   -1.907mA   -3.824mA
-469.7mV  -1.36mA    -988uA     -1.791mA
-413.6mV  -565.2uA   -417.9uA   -621.4uA
-347.6mV  -154.8uA   -117.8uA   -135uA
-251.9mV  -13.35uA   -12.01uA   -7.85uA
2.2V      0A         0A         0A
[Pullup]
|   Voltage   I(typ)   I(min)   I(max)
-1.1V     5.237uA    8.07uA     2.361uA
226.6mV   -35.33uA   -36.24uA   -35.78uA
342.1mV   -317.8uA   -263.3uA   -438.5uA
437.8mV   -1.204mA   -986.9uA   -1.515mA
546.7mV   -3.119mA   -2.858mA   -3.404mA
685.3mV   -6.404mA   -6.586mA   -6.345mA
979mV     -14.46mA   -16.4mA    -13.56mA
1.335V    -24.84mA   -28.51mA   -23.26mA
1.596V    -32.18mA   -36.36mA   -30.67mA
1.688V    -34.25mA   -38.45mA   -33.01mA
1.86V     -38.15mA   -41.43mA   -37.6mA
2.2V      -46.77mA   -46.64mA   -48.43mA
[POWER Clamp]
|   Voltage   I(typ)   I(min)   I(max)
-1.1V     3.036mA    3.636mA    2.186mA
-1.054V   2.493mA    3.084mA    1.737mA
-977.9mV  1.724mA    2.242mA    1.161mA
-908.6mV  1.178mA    1.582mA    747.9uA
-852.5mV  818.9uA    1.148mA    543.8uA
-779.9mV  447.9uA    701.7uA    396.3uA
-713.9mV  239.2uA    373.2uA    278.6uA
-654.5mV  142.7uA    170.4uA    185.9uA
-595.1mV  80.75uA    68.3uA     109.2uA
-502.7mV  22.54uA    13.98uA    29.25uA
-397.1mV  2.384uA    1.595uA    2.115uA
2.2V      0A         0A         0A
[Ramp]
|   typ   min   max
| 20% - 80%
dV/dt_r   223.60m/36.64p   213.58m/41.47p   243.94m/31.88p
dV/dt_f   85.17m/68.44p   76.65m/79.20p   100.81m/57.81p
| 25% - 75%
|dV/dt_r   186.34m/29.20p   177.98m/32.98p   203.28m/25.40p
|dV/dt_f   70.97m/54.46p   63.87m/62.61p   84.01m/45.98p
R_load = 50
[Rising Waveform]
R_fixture = 50
V_fixture = 0.0
|   Time   V(typ)   V(min)   V(max)
0s        946.5uV    843.3uV    679.6uV
57ps      732.2uV    -180.7uV   11.47mV
64ps      3.836mV    -424.6uV   45.09mV
77ps      18.92mV    3.039mV    163.6mV
99ps      155.3mV    27.11mV    320.3mV
113ps     246.5mV    89.3mV     367.2mV
127ps     306.2mV    175.4mV    390mV
152ps     355mV      287.5mV    403.9mV
183ps     370.6mV    340.9mV    406.9mV
367ps     373.6mV    356.8mV    407.2mV
[Falling Waveform]
R_fixture   = 50
V_fixture   = 1.1
V_fixture_min = 1.06
V_fixture_max = 1.17
|   Time   V(typ)   V(min)   V(max)
0s        1.1V       1.06V      1.17V
50ps      1.101V     1.06V      1.171V
64ps      1.1V       1.061V     1.165V
72ps      1.098V     1.061V     1.157V
91ps      1.087V     1.055V     1.115V
121ps     1.043V     1.039V     1.057V
161ps     994.5mV    994.8mV    1.02V
197ps     973.2mV    963.1mV    1.009V
238ps     963.3mV    944.6mV    1.004V
367ps     958.1mV    932.3mV    1.002V
[Rising Waveform]
R_fixture   = 50
V_fixture   = 1.1
V_fixture_min = 1.06
V_fixture_max = 1.17
|   Time   V(typ)   V(min)   V(max)
0s        957.9mV    931.6mV    1.002V
46ps      955.5mV    930.1mV    1.002V
56ps      957.2mV    927.7mV    1.021V
69ps      979.4mV    930.6mV    1.069V
77ps      1.003V     941.2mV    1.092V
96ps      1.048V     987.5mV    1.124V
114ps     1.069V     1.022V     1.141V
131ps     1.08V      1.038V     1.152V
189ps     1.095V     1.056V     1.166V
367ps     1.1V       1.06V      1.17V
[Falling Waveform]
R_fixture = 50
V_fixture = 0.0
|   Time   V(typ)   V(min)   V(max)
0s        373.7mV    357mV      407.3mV
56ps      379.8mV    358mV      409.8mV
73ps      372.9mV    368.6mV    314.7mV
85ps      317mV      362.7mV    207mV
99ps      216mV      311.8mV    130mV
117ps     122.7mV    206.4mV    73.26mV
139ps     63.39mV    109.5mV    36.71mV
167ps     28.12mV    48.8mV     15.59mV
204ps     10.09mV    17.65mV    5.339mV
367ps     1.093mV    1.116mV    733.3uV
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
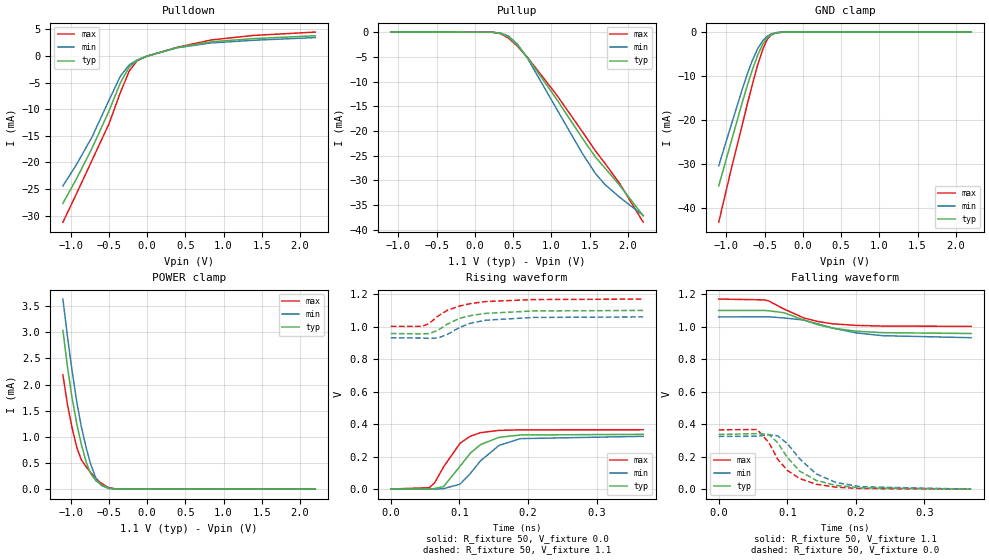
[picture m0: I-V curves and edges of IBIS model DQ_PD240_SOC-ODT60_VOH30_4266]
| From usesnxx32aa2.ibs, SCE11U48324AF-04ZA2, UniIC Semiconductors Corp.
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| DQ_PD240_SOC-ODT60_VOH30_4266
| (240 Ohm Pulldown, 60 Ohm System ODT Setting, VOH=VDDQ/3.0, 3200-4266Mbps)
[Model]   DQ_PD240_SOC-ODT60_VOH30_4266
Model_type   I/O
Vinl = 123.333mV
Vinh = 243.333mV
Vmeas = 183.333mV
Vref = 0.0mV
Cref = 0.0pF
Rref = 60.000Ohm
|   typ   min   max
|C_comp   0.797pF   0.747pF   0.847pF
C_comp_pullup   0.3985pF   0.3735pF   0.4235pF
C_comp_pulldown   0.3985pF   0.3735pF   0.4235pF
| Note: C_comp changes when the ODT circuit is enabled.
[Model Spec]
| Input threshold voltage corners
Vinl   0.1233V   0.1167V   0.1350V
Vinh   0.2433V   0.2367V   0.2550V
| Measurement voltage corners
Vmeas   0.1833V   0.1767V   0.1950V
| Timing spec test load voltage corners
Vref   0.0000V   0.0000V   0.0000V
| Dynamic Overshoot Parameters from LPDDR4 Specification
D_overshoot_ampl_h   0.30   NA   NA
D_overshoot_ampl_l   0.30   NA   NA
D_overshoot_area_h   0.1n   NA   NA
D_overshoot_area_l   0.1n   NA   NA
[Receiver Thresholds]
Vth   = 0.1833V
Vth_min  = 0.1800V
Vth_max  = 0.1866V
Vinh_ac  = 0.060V
Vinh_dc  = 0.060V
Vinl_ac  = -0.060V
Vinl_dc  = -0.060V
Tslew_ac = 5.000ns |Not specified, so set to high value
Threshold_sensitivity = 0.1667
Reference_supply Pullup_ref
[Voltage Range]   1.1000V   1.0600V   1.1700V
[Pullup Reference]   1.1000V   1.0600V   1.1700V
| Junction Temperature (Ambient temp is 35C typ 95C min -40C max)
[Temperature Range]   50.0   110.0   -40.0
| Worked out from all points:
|   slope of the pulldown table from 0 to 0.165 V, typ, clamps not added: 223 ohm
|   slope of the pullup table from 0 to 0.165 V, typ, clamps not added: 19.4 kohm
|   GND clamp passes 1 mA (typ) near -0.45 V on its own axis
|   POWER clamp passes 1 mA (typ) near -0.88 V on its own axis
|   rising waveform, R_fixture 50, V_fixture 0.0: 20-80 % time 40ps typ, 44.3ps min, 34.7ps max; typ from 0.001 V to 0.337 V
|   falling waveform, R_fixture 50, V_fixture 1.1: 20-80 % time 67.4ps typ, 76.7ps min, 57.2ps max; typ from 1.1 V to 0.958 V
|   rising waveform, R_fixture 50, V_fixture 1.1: 20-80 % time 48.6ps typ, 45.7ps min, 48.5ps max; typ from 0.958 V to 1.1 V
|   falling waveform, R_fixture 50, V_fixture 0.0: 20-80 % time 46ps typ, 50.5ps min, 41.9ps max; typ from 0.337 V to 0.001 V
[Pulldown]
|   Voltage   I(typ)   I(min)   I(max)
-1.1V     -27.71mA   -24.44mA   -31.25mA
-918.5mV  -22.98mA   -20.31mA   -25.78mA
-720.5mV  -17.39mA   -15.27mA   -19.65mA
-499.4mV  -10.41mA   -8.375mA   -12.82mA
-347.6mV  -5.002mA   -3.762mA   -6.827mA
-232.1mV  -2.055mA   -1.662mA   -2.791mA
-129.8mV  -798.7uA   -738.7uA   -879.6uA
0V        -19.07uA   -16.89uA   -13.69uA
394.9mV   1.594mA    1.561mA    1.646mA
843.7mV   2.68mA     2.468mA    3.039mA
1.395V    3.278mA    2.967mA    3.877mA
2.2V      3.818mA    3.475mA    4.505mA
[GND Clamp]
|   Voltage   I(typ)   I(min)   I(max)
-1.1V     -34.88mA   -30.34mA   -43.13mA
-944.9mV  -25.34mA   -21.53mA   -31.71mA
-789.8mV  -15.79mA   -12.83mA   -20.82mA
-723.8mV  -11.98mA   -9.381mA   -16.18mA
-664.4mV  -8.768mA   -6.598mA   -12.12mA
-588.5mV  -5.128mA   -3.689mA   -7.33mA
-522.5mV  -2.67mA    -1.906mA   -3.822mA
-466.4mV  -1.297mA   -942.8uA   -1.695mA
-413.6mV  -567.5uA   -419uA     -621.4uA
-354.2mV  -179.7uA   -135.9uA   -159.4uA
-258.5mV  -16.1uA    -14.2uA    -9.795uA
2.2V      0A         0A         0A
[Pullup]
|   Voltage   I(typ)   I(min)   I(max)
-1.1V     4.189uA    6.456uA    1.888uA
229.9mV   -30.52uA   -30.79uA   -31.1uA
332.2mV   -215.1uA   -179.7uA   -295.5uA
437.8mV   -961.7uA   -787.6uA   -1.21mA
553.3mV   -2.603mA   -2.4mA     -2.822mA
691.9mV   -5.249mA   -5.417mA   -5.187mA
1.075V    -13.73mA   -15.72mA   -12.85mA
1.411V    -21.61mA   -24.71mA   -20.28mA
1.576V    -25.28mA   -28.59mA   -24.04mA
1.695V    -27.39mA   -30.74mA   -26.42mA
1.89V     -30.93mA   -33.36mA   -30.56mA
2.2V      -37.14mA   -37.08mA   -38.43mA
[POWER Clamp]
|   Voltage   I(typ)   I(min)   I(max)
-1.1V     3.036mA    3.636mA    2.186mA
-1.041V   2.347mA    2.931mA    1.626mA
-981.2mV  1.754mA    2.277mA    1.183mA
-918.5mV  1.248mA    1.669mA    798.4uA
-859.1mV  857.6uA    1.195mA    561uA
-793.1mV  506.3uA    776.1uA    421uA
-740.3mV  306.1uA    494.5uA    324.3uA
-667.7mV  159.9uA    206.2uA    205.2uA
-598.4mV  83.67uA    71.98uA    113.1uA
-502.7mV  22.64uA    13.95uA    29.28uA
-400.4mV  2.596uA    1.715uA    2.318uA
2.2V      0A         0A         0A
[Ramp]
|   typ   min   max
| 20% - 80%
dV/dt_r   201.80m/40.04p   194.55m/44.31p   218.92m/34.74p
dV/dt_f   85.16m/67.38p   76.64m/77.09p   100.80m/57.22p
| 25% - 75%
|dV/dt_r   168.17m/31.89p   162.13m/35.31p   182.43m/27.66p
|dV/dt_f   70.97m/53.64p   63.87m/61.25p   84.00m/45.48p
R_load = 50
[Rising Waveform]
R_fixture = 50
V_fixture = 0.0
|   Time   V(typ)   V(min)   V(max)
0s        758uV      673uV      545.1uV
56ps      426.3uV    -151.5uV   8.666mV
64ps      3.259mV    -388.2uV   39.39mV
77ps      16.04mV    2.793mV    137.4mV
101ps     141mV      30.48mV    282.6mV
116ps     221.7mV    96.52mV    326.1mV
131ps     274.5mV    175mV      347.7mV
158ps     319mV      269.4mV    361.6mV
189ps     333.3mV    310.8mV    364.8mV
368ps     337.1mV    324.9mV    365.4mV
[Falling Waveform]
R_fixture   = 50
V_fixture   = 1.1
V_fixture_min = 1.06
V_fixture_max = 1.17
|   Time   V(typ)   V(min)   V(max)
0s        1.1V       1.06V      1.17V
66ps      1.1V       1.061V     1.165V
73ps      1.098V     1.061V     1.158V
95ps      1.086V     1.054V     1.109V
124ps     1.041V     1.041V     1.054V
144ps     1.013V     1.018V     1.032V
166ps     991.3mV    991.5mV    1.018V
200ps     972.4mV    962.1mV    1.008V
239ps     963.3mV    944.7mV    1.004V
368ps     958.1mV    932.3mV    1.002V
[Rising Waveform]
R_fixture   = 50
V_fixture   = 1.1
V_fixture_min = 1.06
V_fixture_max = 1.17
|   Time   V(typ)   V(min)   V(max)
0s        957.9mV    931.6mV    1.002V
46ps      955.6mV    930.1mV    1.002V
56ps      957.4mV    927.9mV    1.02V
69ps      978.4mV    930.8mV    1.066V
82ps      1.015V     951.2mV    1.1V
100ps     1.051V     994.5mV    1.127V
116ps     1.068V     1.021V     1.142V
139ps     1.082V     1.04V      1.155V
209ps     1.097V     1.057V     1.167V
368ps     1.1V       1.06V      1.17V
[Falling Waveform]
R_fixture = 50
V_fixture = 0.0
|   Time   V(typ)   V(min)   V(max)
0s        337.2mV    325.1mV    365.5mV
56ps      342.5mV    326.3mV    367.7mV
73ps      337.3mV    335.3mV    288.1mV
86ps      285.7mV    328.4mV    184.7mV
100ps     196.1mV    281mV      116.3mV
118ps     112.1mV    187.3mV    65.61mV
142ps     54.74mV    94.69mV    30.89mV
171ps     23.64mV    41.44mV    12.71mV
207ps     8.745mV    15.49mV    4.525mV
368ps     914.8uV    953.1uV    601.5uV
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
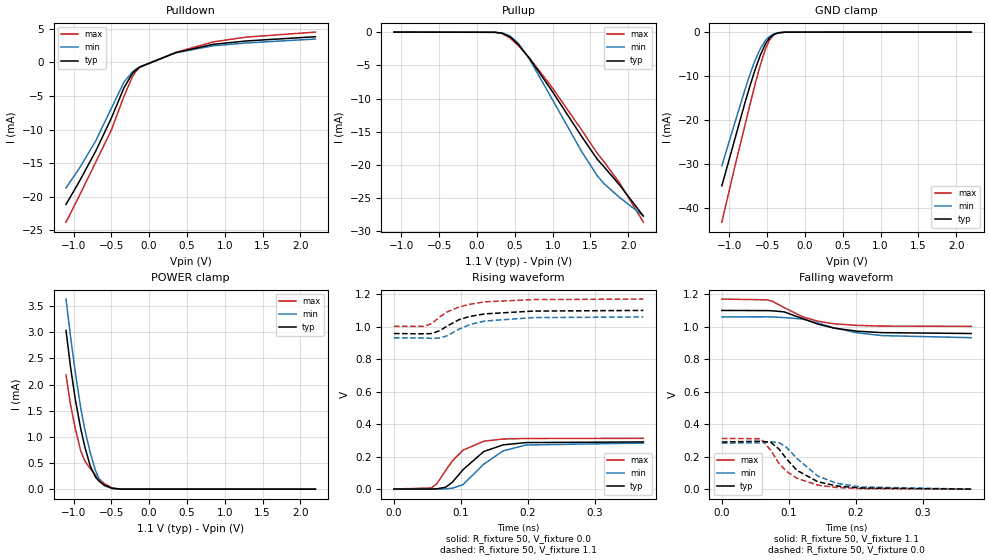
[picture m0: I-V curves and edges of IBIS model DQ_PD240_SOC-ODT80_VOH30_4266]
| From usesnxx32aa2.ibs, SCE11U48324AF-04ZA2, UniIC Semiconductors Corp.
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| DQ_PD240_SOC-ODT80_VOH30_4266
| (240 Ohm Pulldown, 80 Ohm System ODT Setting, VOH=VDDQ/3.0, 3200-4266Mbps)
[Model]   DQ_PD240_SOC-ODT80_VOH30_4266
Model_type   I/O
Vinl = 123.333mV
Vinh = 243.333mV
Vmeas = 183.333mV
Vref = 0.0mV
Cref = 0.0pF
Rref = 80.000Ohm
|   typ   min   max
|C_comp   0.797pF   0.747pF   0.847pF
C_comp_pullup   0.3985pF   0.3735pF   0.4235pF
C_comp_pulldown   0.3985pF   0.3735pF   0.4235pF
| Note: C_comp changes when the ODT circuit is enabled.
[Model Spec]
| Input threshold voltage corners
Vinl   0.1233V   0.1167V   0.1350V
Vinh   0.2433V   0.2367V   0.2550V
| Measurement voltage corners
Vmeas   0.1833V   0.1767V   0.1950V
| Timing spec test load voltage corners
Vref   0.0000V   0.0000V   0.0000V
| Dynamic Overshoot Parameters from LPDDR4 Specification
D_overshoot_ampl_h   0.30   NA   NA
D_overshoot_ampl_l   0.30   NA   NA
D_overshoot_area_h   0.1n   NA   NA
D_overshoot_area_l   0.1n   NA   NA
[Receiver Thresholds]
Vth   = 0.1833V
Vth_min  = 0.1800V
Vth_max  = 0.1866V
Vinh_ac  = 0.060V
Vinh_dc  = 0.060V
Vinl_ac  = -0.060V
Vinl_dc  = -0.060V
Tslew_ac = 5.000ns |Not specified, so set to high value
Threshold_sensitivity = 0.1667
Reference_supply Pullup_ref
[Voltage Range]   1.1000V   1.0600V   1.1700V
[Pullup Reference]   1.1000V   1.0600V   1.1700V
| Junction Temperature (Ambient temp is 35C typ 95C min -40C max)
[Temperature Range]   50.0   110.0   -40.0
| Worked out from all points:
|   slope of the pulldown table from 0 to 0.165 V, typ, clamps not added: 224 ohm
|   slope of the pullup table from 0 to 0.165 V, typ, clamps not added: 25.5 kohm
|   GND clamp passes 1 mA (typ) near -0.45 V on its own axis
|   POWER clamp passes 1 mA (typ) near -0.88 V on its own axis
|   rising waveform, R_fixture 50, V_fixture 0.0: 20-80 % time 43.6ps typ, 47ps min, 37.4ps max; typ from 0.001 V to 0.29 V
|   falling waveform, R_fixture 50, V_fixture 1.1: 20-80 % time 66.3ps typ, 75.7ps min, 56.6ps max; typ from 1.1 V to 0.958 V
|   rising waveform, R_fixture 50, V_fixture 1.1: 20-80 % time 50.7ps typ, 49.7ps min, 49.9ps max; typ from 0.958 V to 1.1 V
|   falling waveform, R_fixture 50, V_fixture 0.0: 20-80 % time 46.8ps typ, 51.4ps min, 42.5ps max; typ from 0.29 V to 0.001 V
[Pulldown]
|   Voltage   I(typ)   I(min)   I(max)
-1.1V     -21.14mA   -18.67mA   -23.78mA
-925.1mV  -17.75mA   -15.79mA   -19.88mA
-707.3mV  -13.21mA   -11.7mA    -14.87mA
-499.4mV  -8.288mA   -6.808mA   -10.06mA
-334.4mV  -3.815mA   -2.975mA   -5.09mA
-222.2mV  -1.668mA   -1.418mA   -2.148mA
-176mV    -1.135mA   -1.021mA   -1.342mA
-119.9mV  -679.6uA   -644.8uA   -718.5uA
352mV     1.447mA    1.422mA    1.482mA
843.7mV   2.68mA     2.468mA    3.039mA
1.283V    3.182mA    2.882mA    3.756mA
2.2V      3.818mA    3.475mA    4.505mA
[GND Clamp]
|   Voltage   I(typ)   I(min)   I(max)
-1.1V     -34.88mA   -30.34mA   -43.13mA
-938.3mV  -24.92mA   -21.15mA   -31.24mA
-793.1mV  -15.98mA   -13.01mA   -21.06mA
-723.8mV  -11.98mA   -9.381mA   -16.18mA
-664.4mV  -8.768mA   -6.598mA   -12.12mA
-591.8mV  -5.271mA   -3.798mA   -7.523mA
-522.5mV  -2.673mA   -1.906mA   -3.823mA
-469.7mV  -1.36mA    -986.7uA   -1.792mA
-413.6mV  -566.4uA   -417.2uA   -621.7uA
-357.5mV  -191.6uA   -144.3uA   -174uA
-258.5mV  -16.3uA    -14.32uA   -9.912uA
2.2V      0A         0A         0A
[Pullup]
|   Voltage   I(typ)   I(min)   I(max)
-1.1V     3.142uA    4.844uA    1.416uA
233.2mV   -24.2uA    -24.4uA    -25.34uA
332.2mV   -161.4uA   -134.8uA   -221.7uA
434.5mV   -694.4uA   -568.1uA   -878.7uA
543.4mV   -1.825mA   -1.666mA   -1.999mA
691.9mV   -3.931mA   -4.057mA   -3.885mA
975.7mV   -8.587mA   -9.731mA   -8.057mA
1.388V    -15.78mA   -18.06mA   -14.8mA
1.589V    -19.11mA   -21.6mA    -18.21mA
1.685V    -20.35mA   -22.87mA   -19.6mA
1.887V    -23.04mA   -24.9mA    -22.72mA
2.2V      -27.69mA   -27.67mA   -28.61mA
[POWER Clamp]
|   Voltage   I(typ)   I(min)   I(max)
-1.1V     3.036mA    3.636mA    2.186mA
-1.041V   2.347mA    2.931mA    1.626mA
-977.9mV  1.724mA    2.242mA    1.161mA
-905.3mV  1.155mA    1.554mA    731.9uA
-849.2mV  799.6uA    1.126mA    535.5uA
-779.9mV  448uA      701.9uA    396.3uA
-710.6mV  232.2uA    359.1uA    273.1uA
-657.8mV  146.8uA    178.9uA    190.7uA
-595.1mV  80.77uA    68.33uA    109.3uA
-489.5mV  17.79uA    10.82uA    22.47uA
-374mV    1.388uA    992.4nA    1.121uA
2.2V      0A         0A         0A
[Ramp]
|   typ   min   max
| 20% - 80%
dV/dt_r   173.87m/43.55p   169.83m/46.96p   187.31m/37.43p
dV/dt_f   85.16m/66.35p   76.64m/75.48p   100.80m/56.76p
| 25% - 75%
|dV/dt_r   144.90m/34.70p   141.53m/37.35p   156.09m/29.81p
|dV/dt_f   70.97m/52.71p   63.87m/60.02p   84.00m/45.02p
R_load = 50
[Rising Waveform]
R_fixture = 50
V_fixture = 0.0
|   Time   V(typ)   V(min)   V(max)
0s        568.2uV    501.3uV    410.2uV
56ps      229.4uV    -53.09uV   7.043mV
64ps      2.04mV     -349.7uV   33.98mV
77ps      11.33mV    1.558mV    113.7mV
87ps      41.43mV    5.384mV    173mV
103ps     119.5mV    27.36mV    239.9mV
134ps     231.5mV    153.7mV    295mV
163ps     272.4mV    235.6mV    308.4mV
197ps     286.5mV    271.6mV    311.8mV
372ps     290.4mV    283.6mV    312.6mV
[Falling Waveform]
R_fixture   = 50
V_fixture   = 1.1
V_fixture_min = 1.06
V_fixture_max = 1.17
|   Time   V(typ)   V(min)   V(max)
0s        1.1V       1.06V      1.17V
68ps      1.099V     1.061V     1.165V
75ps      1.098V     1.06V      1.157V
93ps      1.091V     1.056V     1.117V
121ps     1.049V     1.047V     1.06V
143ps     1.016V     1.023V     1.034V
167ps     991.6mV    993mV      1.018V
202ps     972.1mV    962.2mV    1.008V
239ps     963.4mV    945.2mV    1.004V
372ps     958.1mV    932.3mV    1.002V
[Rising Waveform]
R_fixture   = 50
V_fixture   = 1.1
V_fixture_min = 1.06
V_fixture_max = 1.17
|   Time   V(typ)   V(min)   V(max)
0s        957.9mV    931.6mV    1.002V
46ps      955.8mV    930.3mV    1.002V
57ps      958mV      928mV      1.021V
69ps      976.7mV    930.7mV    1.062V
79ps      1.003V     943.6mV    1.09V
97ps      1.043V     984.2mV    1.121V
113ps     1.063V     1.013V     1.138V
136ps     1.079V     1.035V     1.153V
208ps     1.096V     1.056V     1.167V
372ps     1.1V       1.06V      1.17V
[Falling Waveform]
R_fixture = 50
V_fixture = 0.0
|   Time   V(typ)   V(min)   V(max)
0s        290.5mV    283.7mV    312.7mV
58ps      295.5mV    285.4mV    310.4mV
73ps      288.5mV    292.1mV    239.9mV
85ps      248.3mV    286.7mV    159.8mV
96ps      189.4mV    259.1mV    111.5mV
112ps     116.2mV    189.6mV    67.09mV
143ps     46.28mV    81.06mV    25.42mV
171ps     20.62mV    36.98mV    10.86mV
207ps     7.576mV    13.94mV    3.828mV
372ps     725.2uV    776.2uV    465.4uV
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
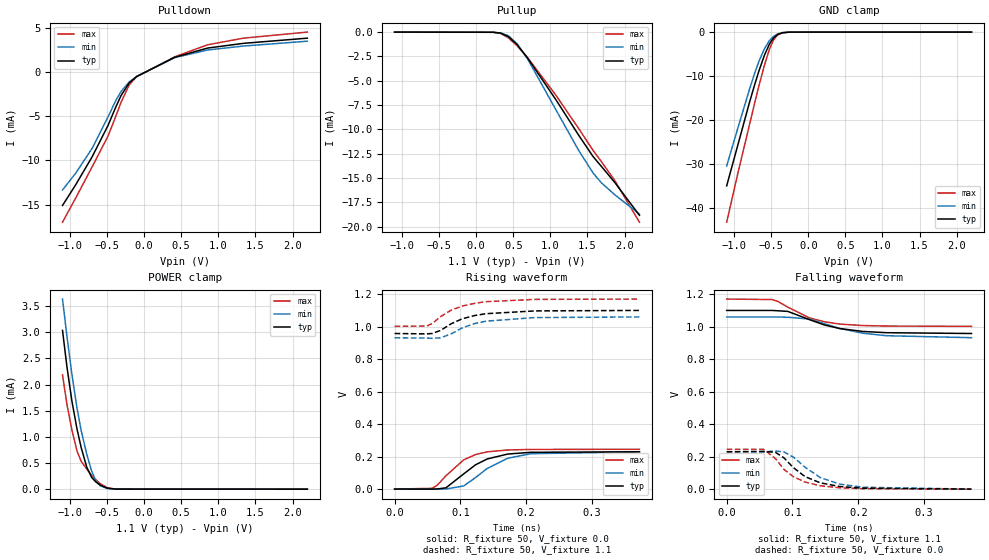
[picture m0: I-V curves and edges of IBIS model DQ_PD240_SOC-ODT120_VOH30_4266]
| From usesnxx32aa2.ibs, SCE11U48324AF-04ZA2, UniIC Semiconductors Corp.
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| DQ_PD240_SOC-ODT120_VOH30_4266
| (240 Ohm Pulldown, 120 Ohm System ODT Setting, VOH=VDDQ/3.0, 3200-4266Mbps)
[Model]   DQ_PD240_SOC-ODT120_VOH30_4266
Model_type   I/O
Vinl = 123.333mV
Vinh = 243.333mV
Vmeas = 183.333mV
Vref = 0.0mV
Cref = 0.0pF
Rref = 120.000Ohm
|   typ   min   max
|C_comp   0.797pF   0.747pF   0.847pF
C_comp_pullup   0.3985pF   0.3735pF   0.4235pF
C_comp_pulldown   0.3985pF   0.3735pF   0.4235pF
| Note: C_comp changes when the ODT circuit is enabled.
[Model Spec]
| Input threshold voltage corners
Vinl   0.1233V   0.1167V   0.1350V
Vinh   0.2433V   0.2367V   0.2550V
| Measurement voltage corners
Vmeas   0.1833V   0.1767V   0.1950V
| Timing spec test load voltage corners
Vref   0.0000V   0.0000V   0.0000V
| Dynamic Overshoot Parameters from LPDDR4 Specification
D_overshoot_ampl_h   0.30   NA   NA
D_overshoot_ampl_l   0.30   NA   NA
D_overshoot_area_h   0.1n   NA   NA
D_overshoot_area_l   0.1n   NA   NA
[Receiver Thresholds]
Vth   = 0.1833V
Vth_min  = 0.1800V
Vth_max  = 0.1866V
Vinh_ac  = 0.060V
Vinh_dc  = 0.060V
Vinl_ac  = -0.060V
Vinl_dc  = -0.060V
Tslew_ac = 5.000ns |Not specified, so set to high value
Threshold_sensitivity = 0.1667
Reference_supply Pullup_ref
[Voltage Range]   1.1000V   1.0600V   1.1700V
[Pullup Reference]   1.1000V   1.0600V   1.1700V
| Junction Temperature (Ambient temp is 35C typ 95C min -40C max)
[Temperature Range]   50.0   110.0   -40.0
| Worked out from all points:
|   slope of the pulldown table from 0 to 0.165 V, typ, clamps not added: 225 ohm
|   slope of the pullup table from 0 to 0.165 V, typ, clamps not added: 39 kohm
|   GND clamp passes 1 mA (typ) near -0.45 V on its own axis
|   POWER clamp passes 1 mA (typ) near -0.88 V on its own axis
|   rising waveform, R_fixture 50, V_fixture 0.0: 20-80 % time 47.4ps typ, 52ps min, 41.5ps max; typ from 0 V to 0.23 V
|   falling waveform, R_fixture 50, V_fixture 1.1: 20-80 % time 65.5ps typ, 74ps min, 56.2ps max; typ from 1.1 V to 0.958 V
|   rising waveform, R_fixture 50, V_fixture 1.1: 20-80 % time 51.9ps typ, 53.8ps min, 50ps max; typ from 0.958 V to 1.1 V
|   falling waveform, R_fixture 50, V_fixture 0.0: 20-80 % time 47.1ps typ, 52.2ps min, 42.8ps max; typ from 0.23 V to 0.001 V
[Pulldown]
|   Voltage   I(typ)   I(min)   I(max)
-1.1V     -15.1mA    -13.35mA   -16.99mA
-921.8mV  -12.75mA   -11.44mA   -14.25mA
-700.7mV  -9.595mA   -8.632mA   -10.73mA
-486.2mV  -6.044mA   -5.079mA   -7.243mA
-383.9mV  -4.009mA   -3.269mA   -5.062mA
-311.3mV  -2.678mA   -2.21mA    -3.436mA
-202.4mV  -1.258mA   -1.14mA    -1.488mA
-100.1mV  -521.3uA   -507.7uA   -527.5uA
414.7mV   1.659mA    1.622mA    1.72mA
856.9mV   2.701mA    2.483mA    3.07mA
1.342V    3.234mA    2.928mA    3.822mA
2.2V      3.818mA    3.475mA    4.505mA
[GND Clamp]
|   Voltage   I(typ)   I(min)   I(max)
-1.1V     -34.88mA   -30.35mA   -43.13mA
-944.9mV  -25.34mA   -21.53mA   -31.71mA
-793.1mV  -15.98mA   -13.01mA   -21.06mA
-723.8mV  -11.98mA   -9.381mA   -16.18mA
-664.4mV  -8.768mA   -6.598mA   -12.12mA
-591.8mV  -5.271mA   -3.798mA   -7.525mA
-522.5mV  -2.67mA    -1.909mA   -3.823mA
-469.7mV  -1.359mA   -987.9uA   -1.791mA
-413.6mV  -564.7uA   -417.3uA   -621.3uA
-347.6mV  -155uA     -118.1uA   -135.6uA
-251.9mV  -13.3uA    -12.08uA   -8.062uA
2.2V      0A         0A         0A
[Pullup]
|   Voltage   I(typ)   I(min)   I(max)
-1.1V     2.095uA    3.229uA    944.4nA
229.9mV   -15.22uA   -15.27uA   -15.54uA
332.2mV   -107.8uA   -90.07uA   -148.2uA
434.5mV   -465.8uA   -380.7uA   -589.4uA
550mV     -1.286mA   -1.183mA   -1.397mA
691.9mV   -2.655mA   -2.748mA   -2.618mA
1.078V    -6.994mA   -8.033mA   -6.53mA
1.378V    -10.56mA   -12.12mA   -9.881mA
1.576V    -12.8mA    -14.49mA   -12.17mA
1.688V    -13.81mA   -15.5mA    -13.32mA
1.867V    -15.45mA   -16.71mA   -15.25mA
2.2V      -18.83mA   -18.71mA   -19.54mA
[POWER Clamp]
|   Voltage   I(typ)   I(min)   I(max)
-1.1V     3.036mA    3.636mA    2.186mA
-1.041V   2.347mA    2.931mA    1.626mA
-974.6mV  1.695mA    2.208mA    1.139mA
-905.3mV  1.155mA    1.554mA    732.5uA
-849.2mV  799.3uA    1.126mA    535.5uA
-773.3mV  420.9uA    665.5uA    384.1uA
-707.3mV  225.5uA    345.5uA    267.6uA
-651.2mV  138.6uA    162.3uA    181.2uA
-591.8mV  77.91uA    64.82uA    105.6uA
-496.1mV  20.09uA    12.4uA     25.73uA
-387.2mV  1.888uA    1.305uA    1.608uA
2.2V      0A         0A         0A
[Ramp]
|   typ   min   max
| 20% - 80%
dV/dt_r   137.74m/47.41p   137.31m/51.95p   146.97m/41.47p
dV/dt_f   85.15m/65.38p   76.64m/74.01p   100.78m/56.03p
| 25% - 75%
|dV/dt_r   114.79m/37.73p   114.43m/41.37p   122.47m/33.01p
|dV/dt_f   70.95m/51.99p   63.87m/58.86p   83.98m/44.52p
R_load = 50
[Rising Waveform]
R_fixture = 50
V_fixture = 0.0
|   Time   V(typ)   V(min)   V(max)
0s        378uV      331.3uV    274uV
57ps      29.79uV    -34.21uV   4.752mV
65ps      1.076mV    -328.4uV   24.79mV
78ps      7.965mV    621.6uV    81.98mV
105ps     93.59mV    19.41mV    180.1mV
123ps     149.8mV    71.25mV    212.9mV
141ps     186mV      127.9mV    229.7mV
172ps     216mV      190.2mV    241mV
207ps     226.5mV    218.1mV    244.3mV
372ps     230mV      229.2mV    245.2mV
[Falling Waveform]
R_fixture   = 50
V_fixture   = 1.1
V_fixture_min = 1.06
V_fixture_max = 1.17
|   Time   V(typ)   V(min)   V(max)
0s        1.1V       1.06V      1.17V
69ps      1.1V       1.06V      1.167V
78ps      1.098V     1.06V      1.155V
93ps      1.094V     1.058V     1.12V
126ps     1.043V     1.047V     1.054V
149ps     1.01V      1.018V     1.03V
172ps     988.4mV    989.2mV    1.016V
207ps     970.8mV    959.9mV    1.007V
243ps     963mV      944.4mV    1.004V
372ps     958.1mV    932.3mV    1.002V
[Rising Waveform]
R_fixture   = 50
V_fixture   = 1.1
V_fixture_min = 1.06
V_fixture_max = 1.17
|   Time   V(typ)   V(min)   V(max)
0s        957.9mV    931.6mV    1.002V
49ps      955.7mV    929.7mV    1.004V
57ps      957.9mV    928.2mV    1.019V
70ps      977.2mV    931.4mV    1.062V
86ps      1.018V     956.1mV    1.102V
103ps     1.049V     992.8mV    1.127V
122ps     1.069V     1.02V      1.144V
139ps     1.08V      1.034V     1.154V
213ps     1.097V     1.056V     1.168V
372ps     1.1V       1.06V      1.17V
[Falling Waveform]
R_fixture = 50
V_fixture = 0.0
|   Time   V(typ)   V(min)   V(max)
0s        230mV      229.3mV    245.3mV
56ps      232.7mV    229.6mV    245.8mV
74ps      227.2mV    234.8mV    189mV
87ps      193.1mV    229.3mV    122.4mV
101ps     133.9mV    198.7mV    77.88mV
119ps     77.67mV    135.8mV    44.17mV
142ps     39.51mV    72.03mV    21.54mV
172ps     16.58mV    31.23mV    8.585mV
207ps     6.319mV    12.12mV    3.097mV
372ps     531.9uV    584uV      342.5uV
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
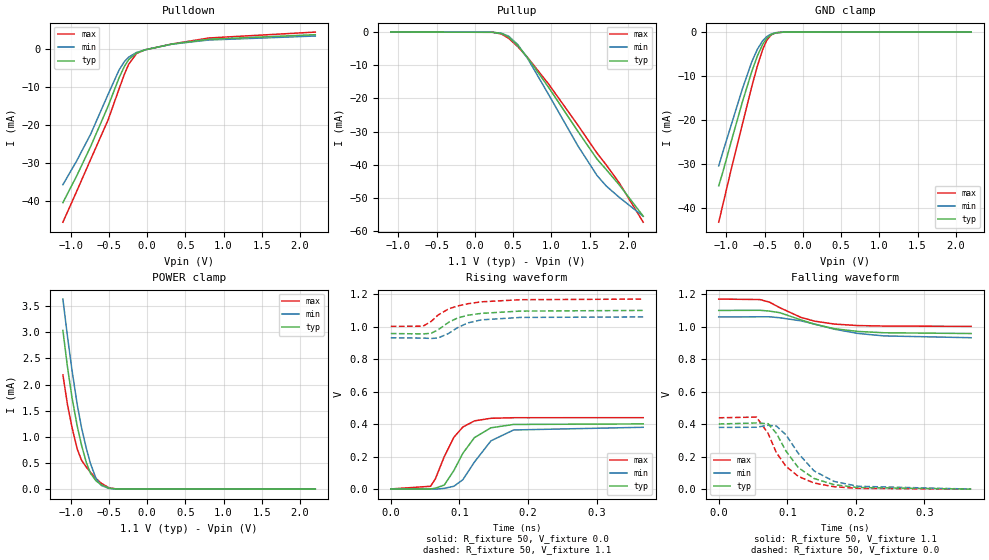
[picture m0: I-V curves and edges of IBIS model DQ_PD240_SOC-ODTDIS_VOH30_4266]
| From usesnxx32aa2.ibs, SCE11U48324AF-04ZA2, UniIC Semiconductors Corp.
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| DQ_PD240_SOC-ODTDIS_VOH30_4266
| (240 Ohm Pulldown, SOC ODT disabled setting, VOH=VDDQ/3.0 cal. point, 3200-4266Mbps)
[Model]   DQ_PD240_SOC-ODTDIS_VOH30_4266
Model_type   I/O
Vinl = 123.333mV
Vinh = 243.333mV
Vmeas = 183.333mV
Vref = 0.0mV
Cref = 0.0pF
|   typ   min   max
|C_comp   0.797pF   0.747pF   0.847pF
C_comp_pullup   0.3985pF   0.3735pF   0.4235pF
C_comp_pulldown   0.3985pF   0.3735pF   0.4235pF
| Note: C_comp changes when the ODT circuit is enabled.
[Model Spec]
| Input threshold voltage corners
Vinl   0.1233V   0.1167V   0.1350V
Vinh   0.2433V   0.2367V   0.2550V
| Measurement voltage corners
Vmeas   0.1833V   0.1767V   0.1950V
| Timing spec test load voltage corners
Vref   0.0000V   0.0000V   0.0000V
| Dynamic Overshoot Parameters from LPDDR4 Specification
D_overshoot_ampl_h   0.30   NA   NA
D_overshoot_ampl_l   0.30   NA   NA
D_overshoot_area_h   0.1n   NA   NA
D_overshoot_area_l   0.1n   NA   NA
[Receiver Thresholds]
Vth   = 0.1833V
Vth_min  = 0.1800V
Vth_max  = 0.1866V
Vinh_ac  = 0.060V
Vinh_dc  = 0.060V
Vinl_ac  = -0.060V
Vinl_dc  = -0.060V
Tslew_ac = 5.000ns |Not specified, so set to high value
Threshold_sensitivity = 0.1667
Reference_supply Pullup_ref
[Voltage Range]   1.1000V   1.0600V   1.1700V
[Pullup Reference]   1.1000V   1.0600V   1.1700V
| Junction Temperature (Ambient temp is 35C typ 95C min -40C max)
[Temperature Range]   50.0   110.0   -40.0
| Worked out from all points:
|   slope of the pulldown table from 0 to 0.165 V, typ, clamps not added: 220 ohm
|   slope of the pullup table from 0 to 0.165 V, typ, clamps not added: 12.9 kohm
|   GND clamp passes 1 mA (typ) near -0.45 V on its own axis
|   POWER clamp passes 1 mA (typ) near -0.88 V on its own axis
|   rising waveform, R_fixture 50, V_fixture 0.0: 20-80 % time 35.3ps typ, 39.7ps min, 30.2ps max; typ from 0.001 V to 0.401 V
|   falling waveform, R_fixture 50, V_fixture 1.1: 20-80 % time 69.3ps typ, 81.7ps min, 58.1ps max; typ from 1.1 V to 0.958 V
|   rising waveform, R_fixture 50, V_fixture 1.1: 20-80 % time 43.6ps typ, 38.5ps min, 46.7ps max; typ from 0.958 V to 1.1 V
|   falling waveform, R_fixture 50, V_fixture 0.0: 20-80 % time 45.1ps typ, 49.1ps min, 41.4ps max; typ from 0.402 V to 0.001 V
[Pulldown]
|   Voltage   I(typ)   I(min)   I(max)
-1.1V     -40.34mA   -35.62mA   -45.48mA
-921.8mV  -33.39mA   -29.43mA   -37.46mA
-737mV    -25.57mA   -22.32mA   -28.97mA
-509.3mV  -14.99mA   -11.88mA   -18.6mA
-364.1mV  -7.443mA   -5.397mA   -10.35mA
-294.8mV  -4.472mA   -3.229mA   -6.501mA
-238.7mV  -2.708mA   -2.052mA   -3.916mA
-136.4mV  -964.9uA   -856.7uA   -1.123mA
-24.2mV   -156.3uA   -149.3uA   -146.4uA
325.6mV   1.352mA    1.331mA    1.379mA
807.4mV   2.622mA    2.422mA    2.952mA
2.2V      3.818mA    3.475mA    4.505mA
[GND Clamp]
|   Voltage   I(typ)   I(min)   I(max)
-1.1V     -34.88mA   -30.35mA   -43.13mA
-1.047V   -31.79mA   -27.25mA   -39.23mA
-938.3mV  -24.92mA   -21.15mA   -31.24mA
-789.8mV  -15.79mA   -12.83mA   -20.82mA
-667.7mV  -8.94mA    -6.743mA   -12.34mA
-595.1mV  -5.419mA   -3.908mA   -7.721mA
-525.8mV  -2.776mA   -1.977mA   -3.977mA
-473mV    -1.426mA   -1.033mA   -1.891mA
-413.6mV  -565.1uA   -417.1uA   -621.3uA
-354.2mV  -179.7uA   -134.8uA   -160.1uA
-251.9mV  -13.31uA   -11.89uA   -7.929uA
2.2V      0A         0A         0A
[Pullup]
|   Voltage   I(typ)   I(min)   I(max)
-1.1V     6.284uA    9.684uA    2.832uA
229.9mV   -45.54uA   -46.48uA   -46.57uA
345.4mV   -402uA     -331.8uA   -555.7uA
441.1mV   -1.491mA   -1.229mA   -1.868mA
559.9mV   -4.054mA   -3.762mA   -4.37mA
688.6mV   -7.724mA   -7.945mA   -7.651mA
965.8mV   -16.75mA   -18.92mA   -15.73mA
1.345V    -29.87mA   -34.23mA   -28.01mA
1.596V    -38.26mA   -43.21mA   -36.46mA
1.718V    -41.46mA   -46.41mA   -40.06mA
1.887V    -46.05mA   -49.8mA    -45.44mA
2.2V      -55.46mA   -55.5mA    -57.28mA
[POWER Clamp]
|   Voltage   I(typ)   I(min)   I(max)
-1.1V     3.036mA    3.636mA    2.186mA
-1.041V   2.347mA    2.931mA    1.626mA
-981.2mV  1.754mA    2.277mA    1.183mA
-911.9mV  1.201mA    1.611mA    764.5uA
-855.8mV  838.1uA    1.172mA    552.2uA
-793.1mV  506.1uA    776.1uA    421uA
-740.3mV  306.2uA    494.5uA    324.3uA
-667.7mV  159.9uA    206.2uA    205.2uA
-598.4mV  83.71uA    71.96uA    113uA
-496.1mV  20.1uA     12.32uA    25.72uA
-390.5mV  2.041uA    1.385uA    1.76uA
2.2V      0A         0A         0A
[Ramp]
|   typ   min   max
| 20% - 80%
dV/dt_r   240.18m/35.28p   227.76m/39.69p   263.33m/30.17p
dV/dt_f   85.17m/69.56p   76.65m/81.77p   100.81m/58.38p
| 25% - 75%
|dV/dt_r   200.15m/28.07p   189.80m/31.50p   219.44m/24.07p
|dV/dt_f   70.97m/55.35p   63.87m/64.43p   84.01m/46.53p
R_load = 50
[Rising Waveform]
R_fixture = 50
V_fixture = 0.0
|   Time   V(typ)   V(min)   V(max)
0s        1.132mV    1.009mV    812.7uV
58ps      1.206mV    -307.2uV   17.37mV
65ps      5.394mV    -472.8uV   63.31mV
78ps      25.16mV    4.355mV    200.3mV
92ps      114.6mV    17.57mV    319.3mV
105ps     220.4mV    57.63mV    382mV
122ps     317.2mV    167.1mV    420mV
146ps     377.5mV    297.1mV    436mV
179ps     398mV      364mV      439.4mV
368ps     401.4mV    380.6mV    439.7mV
[Falling Waveform]
R_fixture   = 50
V_fixture   = 1.1
V_fixture_min = 1.06
V_fixture_max = 1.17
|   Time   V(typ)   V(min)   V(max)
0s        1.1V       1.06V      1.17V
60ps      1.101V     1.061V     1.167V
74ps      1.096V     1.061V     1.151V
89ps      1.086V     1.055V     1.117V
120ps     1.042V     1.036V     1.057V
140ps     1.015V     1.016V     1.034V
169ps     987.5mV    984.3mV    1.016V
203ps     970.8mV    958.5mV    1.007V
241ps     962.8mV    943.4mV    1.004V
368ps     958.1mV    932.2mV    1.002V
[Rising Waveform]
R_fixture   = 50
V_fixture   = 1.1
V_fixture_min = 1.06
V_fixture_max = 1.17
|   Time   V(typ)   V(min)   V(max)
0s        957.9mV    931.6mV    1.002V
47ps      955.2mV    929.9mV    1.003V
59ps      960mV      927.2mV    1.033V
69ps      980.7mV    930.5mV    1.072V
84ps      1.026V     957.8mV    1.109V
97ps      1.053V     993mV      1.127V
112ps     1.07V      1.023V     1.141V
132ps     1.082V     1.042V     1.153V
189ps     1.096V     1.057V     1.166V
368ps     1.1V       1.06V      1.17V
[Falling Waveform]
R_fixture = 50
V_fixture = 0.0
|   Time   V(typ)   V(min)   V(max)
0s        401.6mV    380.8mV    439.8mV
55ps      408mV      381.6mV    444.1mV
72ps      403.3mV    394mV      343.6mV
84ps      344.8mV    389.2mV    225.9mV
98ps      235.5mV    335.4mV    141.5mV
116ps     133.2mV    221mV      79.54mV
139ps     66.53mV    113.2mV    38.66mV
168ps     28.67mV    48.7mV     15.89mV
203ps     10.95mV    18.62mV    5.804mV
368ps     1.267mV    1.269mV    856.9uV
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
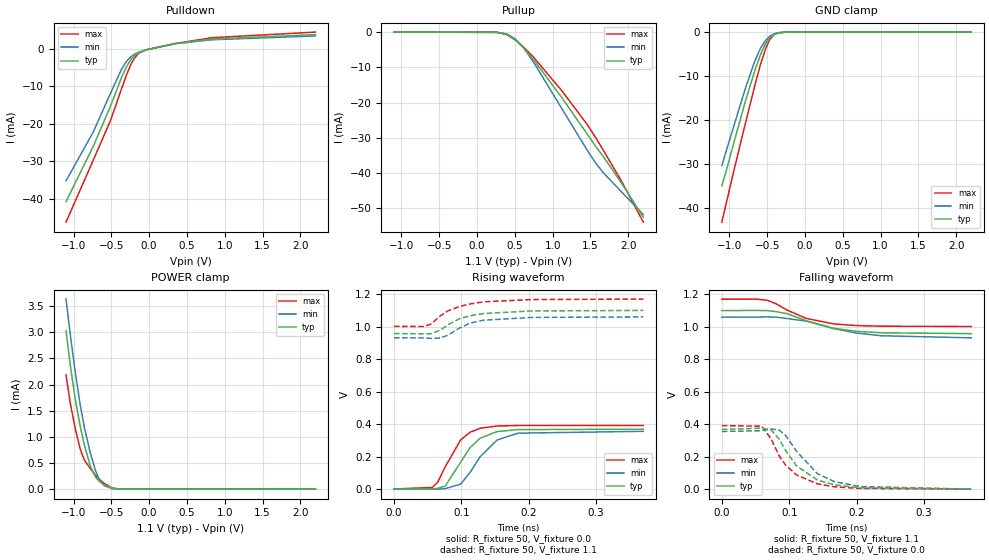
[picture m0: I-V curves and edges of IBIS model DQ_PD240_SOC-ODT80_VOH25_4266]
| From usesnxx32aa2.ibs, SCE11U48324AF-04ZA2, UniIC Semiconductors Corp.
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| DQ_PD240_SOC-ODT80_VOH25_4266
| (240 Ohm Pulldown, 80 Ohm System ODT Setting, VOH=VDDQ/2.5, 3200-4266Mbps)
[Model]   DQ_PD240_SOC-ODT80_VOH25_4266
Model_type   I/O
Vinl = 160.000mV
Vinh = 280.000mV
Vmeas = 220.000mV
Vref = 0.0mV
Cref = 0.0pF
Rref = 80.000Ohm
|   typ   min   max
|C_comp   0.797pF   0.747pF   0.847pF
C_comp_pullup   0.3985pF   0.3735pF   0.4235pF
C_comp_pulldown   0.3985pF   0.3735pF   0.4235pF
| Note: C_comp changes when the ODT circuit is enabled.
[Model Spec]
| Input threshold voltage corners
Vinl   0.1600V   0.1520V   0.1740V
Vinh   0.2800V   0.2720V   0.2940V
| Measurement voltage corners
Vmeas   0.2200V   0.2120V   0.2340V
| Timing spec test load voltage corners
Vref   0.0000V   0.0000V   0.0000V
| Dynamic Overshoot Parameters from LPDDR4 Specification
D_overshoot_ampl_h   0.30   NA   NA
D_overshoot_ampl_l   0.30   NA   NA
D_overshoot_area_h   0.1n   NA   NA
D_overshoot_area_l   0.1n   NA   NA
[Receiver Thresholds]
Vth   = 0.2200V
Vth_min  = 0.2167V
Vth_max  = 0.2233V
Vinh_ac  = 0.060V
Vinh_dc  = 0.060V
Vinl_ac  = -0.060V
Vinl_dc  = -0.060V
Tslew_ac = 5.000ns |Not specified, so set to high value
Threshold_sensitivity = 0.2000
Reference_supply Pullup_ref
[Voltage Range]   1.1000V   1.0600V   1.1700V
[Pullup Reference]   1.1000V   1.0600V   1.1700V
| Junction Temperature (Ambient temp is 35C typ 95C min -40C max)
[Temperature Range]   50.0   110.0   -40.0
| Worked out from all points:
|   slope of the pulldown table from 0 to 0.165 V, typ, clamps not added: 220 ohm
|   slope of the pullup table from 0 to 0.165 V, typ, clamps not added: 17.6 kohm
|   GND clamp passes 1 mA (typ) near -0.45 V on its own axis
|   POWER clamp passes 1 mA (typ) near -0.88 V on its own axis
|   rising waveform, R_fixture 50, V_fixture 0.0: 20-80 % time 35.1ps typ, 39ps min, 31.7ps max; typ from 0.001 V to 0.369 V
|   falling waveform, R_fixture 50, V_fixture 1.1: 20-80 % time 68.3ps typ, 81ps min, 57.6ps max; typ from 1.1 V to 0.958 V
|   rising waveform, R_fixture 50, V_fixture 1.1: 20-80 % time 47ps typ, 41.2ps min, 47.7ps max; typ from 0.958 V to 1.1 V
|   falling waveform, R_fixture 50, V_fixture 0.0: 20-80 % time 45.6ps typ, 49.1ps min, 41.6ps max; typ from 0.369 V to 0.001 V
[Pulldown]
|   Voltage   I(typ)   I(min)   I(max)
-1.1V     -40.8mA    -35.23mA   -46.27mA
-740.3mV  -26.04mA   -22.2mA    -29.72mA
-512.6mV  -15.36mA   -11.9mA    -19.19mA
-360.8mV  -7.395mA   -5.211mA   -10.4mA
-298.1mV  -4.666mA   -3.278mA   -6.834mA
-242mV    -2.834mA   -2.085mA   -4.146mA
-195.8mV  -1.801mA   -1.425mA   -2.472mA
-139.7mV  -1.012mA   -877.1uA   -1.195mA
-37.4mV   -231.8uA   -217.8uA   -222.9uA
345.4mV   1.423mA    1.4mA      1.457mA
830.5mV   2.659mA    2.451mA    3.008mA
2.2V      3.818mA    3.475mA    4.505mA
[GND Clamp]
|   Voltage   I(typ)   I(min)   I(max)
-1.1V     -34.88mA   -30.33mA   -43.14mA
-1.047V   -31.8mA    -27.25mA   -39.23mA
-938.3mV  -24.93mA   -21.15mA   -31.25mA
-786.5mV  -15.6mA    -12.65mA   -20.6mA
-661.1mV  -8.6mA     -6.453mA   -11.91mA
-585.2mV  -4.988mA   -3.582mA   -7.142mA
-519.2mV  -2.574mA   -1.836mA   -3.675mA
-466.4mV  -1.296mA   -945.5uA   -1.695mA
-410.3mV  -534.8uA   -393.7uA   -580.4uA
-354.2mV  -179.1uA   -135.8uA   -160.8uA
-248.6mV  -12.21uA   -11.14uA   -7.144uA
2.2V      0A         0A         0A
[Pullup]
|   Voltage   I(typ)   I(min)   I(max)
-1.1V     4.112uA    7.441uA    1.363uA
262.9mV   -65.04uA   -63.31uA   -66.39uA
394.9mV   -631.7uA   -525uA     -751.7uA
510.4mV   -2.22mA    -2.012mA   -2.307mA
616mV     -4.459mA   -4.485mA   -4.266mA
748mV     -7.819mA   -8.539mA   -7.138mA
1.121V    -18.57mA   -21.68mA   -16.63mA
1.464V    -29.13mA   -33.73mA   -26.39mA
1.589V    -32.98mA   -37.7mA    -30.6mA
1.675V    -35.44mA   -40mA      -33.69mA
1.91V     -42.82mA   -45.28mA   -42.24mA
2.2V      -52.46mA   -51.75mA   -53.91mA
[POWER Clamp]
|   Voltage   I(typ)   I(min)   I(max)
-1.1V     3.036mA    3.636mA    2.186mA
-1.041V   2.347mA    2.931mA    1.626mA
-977.9mV  1.724mA    2.242mA    1.161mA
-911.9mV  1.201mA    1.611mA    764.6uA
-855.8mV  838uA      1.172mA    552.2uA
-779.9mV  448.1uA    702.1uA    396.3uA
-710.6mV  232.3uA    359.2uA    273.1uA
-657.8mV  146.8uA    178.9uA    190.7uA
-595.1mV  80.81uA    68.31uA    109.3uA
-486.2mV  16.75uA    10.14uA    20.98uA
-374mV    1.39uA     1.002uA    1.123uA
2.2V      0A         0A         0A
[Ramp]
|   typ   min   max
| 20% - 80%
dV/dt_r   220.49m/35.08p   212.87m/39.00p   234.65m/31.75p
dV/dt_f   85.17m/68.39p   76.65m/81.39p   100.81m/57.38p
| 25% - 75%
|dV/dt_r   183.74m/27.93p   177.39m/31.05p   195.54m/25.24p
|dV/dt_f   70.97m/54.36p   63.87m/64.30p   84.01m/45.67p
R_load = 50
[Rising Waveform]
R_fixture = 50
V_fixture = 0.0
|   Time   V(typ)   V(min)   V(max)
0s        1.172mV    977.1uV    853.7uV
57ps      931.7uV    -101.8uV   9.88mV
65ps      4.713mV    -382.5uV   43.01mV
76ps      17.99mV    2.644mV    136.6mV
99ps      165.8mV    30.42mV    303mV
113ps     255.3mV    103.4mV    350.2mV
128ps     313.4mV    199.6mV    374.7mV
153ps     354.1mV    302.1mV    388.5mV
184ps     366.4mV    344.4mV    391.5mV
370ps     368.7mV    355.8mV    391.9mV
[Falling Waveform]
R_fixture   = 50
V_fixture   = 1.1
V_fixture_min = 1.06
V_fixture_max = 1.17
|   Time   V(typ)   V(min)   V(max)
0s        1.1V       1.06V      1.17V
50ps      1.101V     1.06V      1.171V
67ps      1.1V       1.061V     1.164V
80ps      1.094V     1.06V      1.143V
97ps      1.081V     1.051V     1.103V
125ps     1.038V     1.035V     1.052V
166ps     990.9mV    989.6mV    1.018V
199ps     972.6mV    962.2mV    1.008V
237ps     963.5mV    945.1mV    1.004V
370ps     958.1mV    932.3mV    1.002V
[Rising Waveform]
R_fixture   = 50
V_fixture   = 1.1
V_fixture_min = 1.06
V_fixture_max = 1.17
|   Time   V(typ)   V(min)   V(max)
0s        957.9mV    931.6mV    1.002V
45ps      955.7mV    930.4mV    1.001V
55ps      956.6mV    927.9mV    1.017V
69ps      979.3mV    930.5mV    1.067V
80ps      1.011V     947.4mV    1.097V
97ps      1.049V     991.4mV    1.124V
113ps     1.067V     1.022V     1.14V
133ps     1.081V     1.04V      1.153V
205ps     1.097V     1.057V     1.167V
370ps     1.1V       1.06V      1.17V
[Falling Waveform]
R_fixture = 50
V_fixture = 0.0
|   Time   V(typ)   V(min)   V(max)
0s        368.8mV    355.9mV    392mV
59ps      376.1mV    360.8mV    388.4mV
73ps      366.7mV    371.1mV    311.3mV
85ps      308.9mV    364.7mV    206.1mV
95ps      236.4mV    329.8mV    147.4mV
111ps     143.4mV    233.1mV    87.93mV
142ps     56.6mV     95.82mV    33.2mV
167ps     27.48mV    47.25mV    15.47mV
205ps     9.692mV    17.03mV    5.238mV
370ps     1.289mV    1.224mV    903.9uV
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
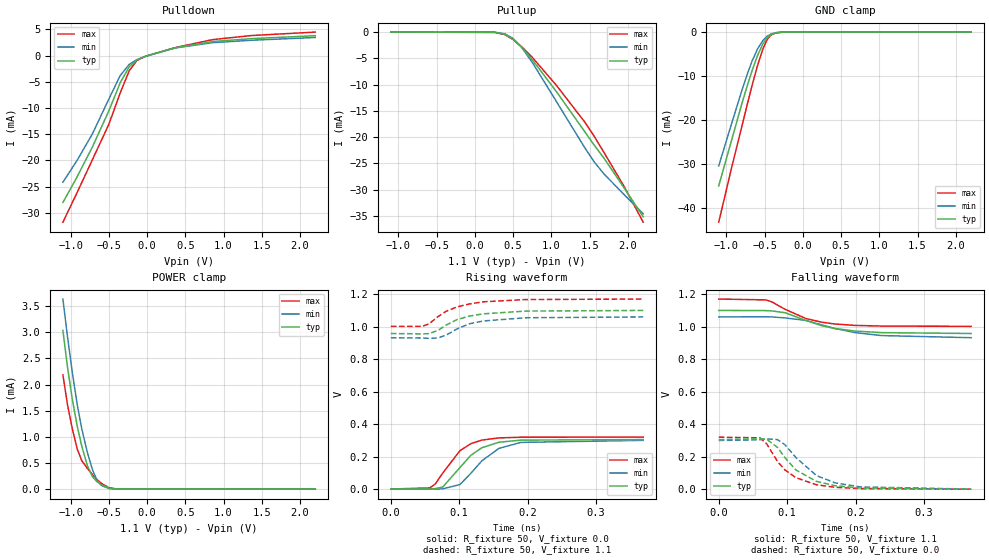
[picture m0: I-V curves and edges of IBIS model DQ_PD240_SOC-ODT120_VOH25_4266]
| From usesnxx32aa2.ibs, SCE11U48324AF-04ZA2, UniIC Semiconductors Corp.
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| DQ_PD240_SOC-ODT120_VOH25_4266
| (240 Ohm Pulldown, 120 Ohm System ODT Setting, VOH=VDDQ/2.5, 3200-4266Mbps)
[Model]   DQ_PD240_SOC-ODT120_VOH25_4266
Model_type   I/O
Vinl = 160.000mV
Vinh = 280.000mV
Vmeas = 220.000mV
Vref = 0.0mV
Cref = 0.0pF
Rref = 120.000Ohm
|   typ   min   max
|C_comp   0.797pF   0.747pF   0.847pF
C_comp_pullup   0.3985pF   0.3735pF   0.4235pF
C_comp_pulldown   0.3985pF   0.3735pF   0.4235pF
| Note: C_comp changes when the ODT circuit is enabled.
[Model Spec]
| Input threshold voltage corners
Vinl   0.1600V   0.1520V   0.1740V
Vinh   0.2800V   0.2720V   0.2940V
| Measurement voltage corners
Vmeas   0.2200V   0.2120V   0.2340V
| Timing spec test load voltage corners
Vref   0.0000V   0.0000V   0.0000V
| Dynamic Overshoot Parameters from LPDDR4 Specification
D_overshoot_ampl_h   0.30   NA   NA
D_overshoot_ampl_l   0.30   NA   NA
D_overshoot_area_h   0.1n   NA   NA
D_overshoot_area_l   0.1n   NA   NA
[Receiver Thresholds]
Vth   = 0.2200V
Vth_min  = 0.2167V
Vth_max  = 0.2233V
Vinh_ac  = 0.060V
Vinh_dc  = 0.060V
Vinl_ac  = -0.060V
Vinl_dc  = -0.060V
Tslew_ac = 5.000ns |Not specified, so set to high value
Threshold_sensitivity = 0.2000
Reference_supply Pullup_ref
[Voltage Range]   1.1000V   1.0600V   1.1700V
[Pullup Reference]   1.1000V   1.0600V   1.1700V
| Junction Temperature (Ambient temp is 35C typ 95C min -40C max)
[Temperature Range]   50.0   110.0   -40.0
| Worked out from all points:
|   slope of the pulldown table from 0 to 0.165 V, typ, clamps not added: 222 ohm
|   slope of the pullup table from 0 to 0.165 V, typ, clamps not added: 26.4 kohm
|   GND clamp passes 1 mA (typ) near -0.45 V on its own axis
|   POWER clamp passes 1 mA (typ) near -0.88 V on its own axis
|   rising waveform, R_fixture 50, V_fixture 0.0: 20-80 % time 40ps typ, 43.8ps min, 36.3ps max; typ from 0.001 V to 0.305 V
|   falling waveform, R_fixture 50, V_fixture 1.1: 20-80 % time 66.3ps typ, 77.3ps min, 56.6ps max; typ from 1.1 V to 0.958 V
|   rising waveform, R_fixture 50, V_fixture 1.1: 20-80 % time 50.1ps typ, 48.3ps min, 48.7ps max; typ from 0.958 V to 1.1 V
|   falling waveform, R_fixture 50, V_fixture 0.0: 20-80 % time 46.2ps typ, 50.4ps min, 42.1ps max; typ from 0.305 V to 0.001 V
[Pulldown]
|   Voltage   I(typ)   I(min)   I(max)
-1.1V     -28.01mA   -24.15mA   -31.78mA
-921.8mV  -23.33mA   -20.16mA   -26.36mA
-713.9mV  -17.41mA   -14.92mA   -19.85mA
-499.4mV  -10.54mA   -8.281mA   -13.1mA
-350.9mV  -5.177mA   -3.801mA   -7.118mA
-232.1mV  -2.078mA   -1.646mA   -2.853mA
-133.1mV  -833.1uA   -756.2uA   -927.7uA
-14.3mV   -91.58uA   -86.5uA    -84.72uA
368.5mV   1.504mA    1.477mA    1.546mA
856.9mV   2.701mA    2.483mA    3.07mA
1.372V    3.259mA    2.95mA     3.853mA
2.2V      3.818mA    3.475mA    4.505mA
[GND Clamp]
|   Voltage   I(typ)   I(min)   I(max)
-1.1V     -34.89mA   -30.35mA   -43.14mA
-935mV    -24.72mA   -20.96mA   -31.01mA
-799.7mV  -16.38mA   -13.37mA   -21.53mA
-723.8mV  -11.98mA   -9.378mA   -16.19mA
-664.4mV  -8.771mA   -6.596mA   -12.13mA
-591.8mV  -5.275mA   -3.797mA   -7.53mA
-522.5mV  -2.67mA    -1.905mA   -3.825mA
-466.4mV  -1.296mA   -943.6uA   -1.694mA
-413.6mV  -564.3uA   -416.5uA   -620.8uA
-347.6mV  -154.3uA   -117.6uA   -135.2uA
-248.6mV  -12.13uA   -10.9uA    -7.04uA
2.2V      0A         0A         0A
[Pullup]
|   Voltage   I(typ)   I(min)   I(max)
-1.1V     2.741uA    4.96uA     908.5nA
262.9mV   -43.26uA   -41.96uA   -44.33uA
391.6mV   -402.7uA   -334.2uA   -480.6uA
500.5mV   -1.366mA   -1.225mA   -1.434mA
609.4mV   -2.883mA   -2.886mA   -2.766mA
754.6mV   -5.36mA    -5.879mA   -4.882mA
1.065V    -11.32mA   -13.21mA   -10.13mA
1.441V    -19.06mA   -22.13mA   -17.22mA
1.556V    -21.46mA   -24.64mA   -19.74mA
1.688V    -24.02mA   -27.01mA   -22.93mA
1.943V    -29.49mA   -30.82mA   -29.2mA
2.2V      -35.14mA   -34.59mA   -36.18mA
[POWER Clamp]
|   Voltage   I(typ)   I(min)   I(max)
-1.1V     3.036mA    3.636mA    2.186mA
-1.041V   2.347mA    2.931mA    1.626mA
-977.9mV  1.724mA    2.242mA    1.161mA
-911.9mV  1.201mA    1.611mA    764.8uA
-852.5mV  818.5uA    1.149mA    543.7uA
-779.9mV  448uA      701.8uA    396.3uA
-713.9mV  239.2uA    373.2uA    278.6uA
-654.5mV  142.7uA    170.4uA    185.9uA
-595.1mV  80.81uA    68.33uA    109.2uA
-496.1mV  20.1uA     12.34uA    25.7uA
-387.2mV  1.89uA     1.297uA    1.609uA
2.2V      0A         0A         0A
[Ramp]
|   typ   min   max
| 20% - 80%
dV/dt_r   182.51m/40.02p   179.59m/43.83p   191.84m/36.32p
dV/dt_f   85.15m/66.56p   76.64m/77.16p   100.80m/56.56p
| 25% - 75%
|dV/dt_r   152.09m/31.88p   149.66m/34.88p   159.86m/28.92p
|dV/dt_f   70.96m/52.96p   63.87m/61.21p   84.00m/44.92p
R_load = 50
[Rising Waveform]
R_fixture = 50
V_fixture = 0.0
|   Time   V(typ)   V(min)   V(max)
0s        785.5uV    651.6uV    572.9uV
57ps      639.8uV    -127.2uV   7.202mV
65ps      3.242mV    -290.1uV   31.76mV
76ps      12.89mV    1.964mV    99.21mV
101ps     132.6mV    27.97mV    236.2mV
117ps     207.9mV    97.29mV    279.8mV
133ps     254.5mV    173.8mV    301.8mV
158ps     288.5mV    250.6mV    315.3mV
190ps     301.6mV    287.6mV    319.4mV
369ps     305mV      300mV      320.3mV
[Falling Waveform]
R_fixture   = 50
V_fixture   = 1.1
V_fixture_min = 1.06
V_fixture_max = 1.17
|   Time   V(typ)   V(min)   V(max)
0s        1.1V       1.06V      1.17V
69ps      1.099V     1.061V     1.165V
78ps      1.097V     1.06V      1.152V
97ps      1.086V     1.054V     1.107V
127ps     1.039V     1.039V     1.051V
150ps     1.007V     1.012V     1.028V
169ps     989.7mV    989.8mV    1.017V
199ps     973.2mV    963.8mV    1.008V
238ps     963.5mV    945.4mV    1.004V
369ps     958.1mV    932.3mV    1.002V
[Rising Waveform]
R_fixture   = 50
V_fixture   = 1.1
V_fixture_min = 1.06
V_fixture_max = 1.17
|   Time   V(typ)   V(min)   V(max)
0s        957.9mV    931.6mV    1.002V
46ps      955.7mV    930.2mV    1.002V
56ps      957.4mV    928mV      1.018V
69ps      977.4mV    930.8mV    1.062V
81ps      1.01V      948.4mV    1.095V
97ps      1.044V     986.6mV    1.122V
115ps     1.065V     1.018V     1.14V
135ps     1.079V     1.035V     1.153V
197ps     1.096V     1.055V     1.167V
369ps     1.1V       1.06V      1.17V
[Falling Waveform]
R_fixture = 50
V_fixture = 0.0
|   Time   V(typ)   V(min)   V(max)
0s        305.1mV    300.1mV    320.4mV
60ps      310.6mV    304.3mV    316.4mV
70ps      308mV      310.2mV    280.4mV
86ps      257.3mV    305.5mV    170.3mV
97ps      193.3mV    273.3mV    118.2mV
113ps     118mV      194.6mV    70.86mV
143ps     48.27mV    83.87mV    27.61mV
170ps     22.16mV    39.41mV    12.14mV
207ps     8.056mV    14.61mV    4.171mV
369ps     934.2uV    913uV      630.6uV
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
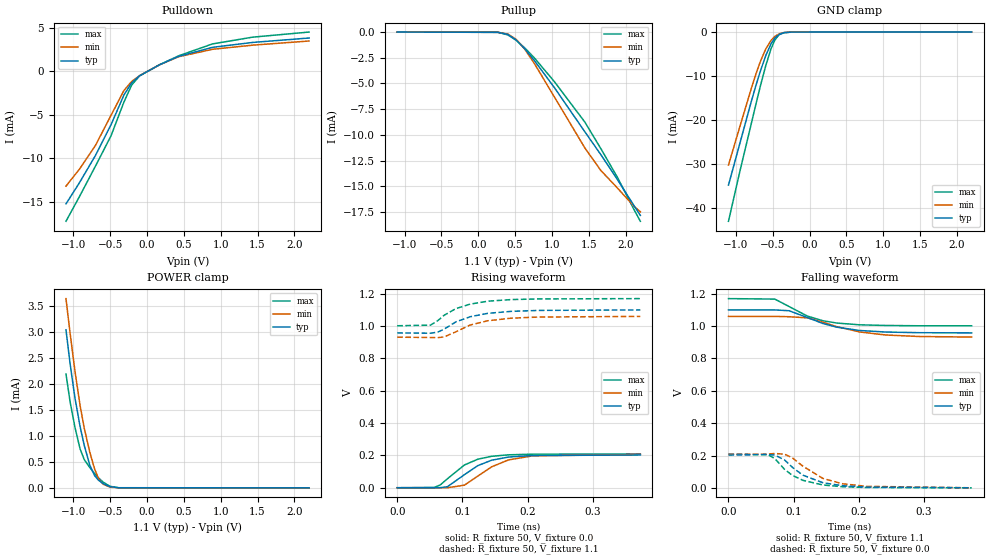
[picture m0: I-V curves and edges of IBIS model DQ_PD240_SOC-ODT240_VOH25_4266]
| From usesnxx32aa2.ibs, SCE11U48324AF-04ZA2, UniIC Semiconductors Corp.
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| DQ_PD240_SOC-ODT240_VOH25_4266
| (240 Ohm Pulldown, 240 Ohm System ODT Setting, VOH=VDDQ/2.5, 3200-4266Mbps)
[Model]   DQ_PD240_SOC-ODT240_VOH25_4266
Model_type   I/O
Vinl = 160.000mV
Vinh = 280.000mV
Vmeas = 220.000mV
Vref = 0.0mV
Cref = 0.0pF
Rref = 240.000Ohm
|   typ   min   max
|C_comp   0.797pF   0.747pF   0.847pF
C_comp_pullup   0.3985pF   0.3735pF   0.4235pF
C_comp_pulldown   0.3985pF   0.3735pF   0.4235pF
| Note: C_comp changes when the ODT circuit is enabled.
[Model Spec]
| Input threshold voltage corners
Vinl   0.1600V   0.1520V   0.1740V
Vinh   0.2800V   0.2720V   0.2940V
| Measurement voltage corners
Vmeas   0.2200V   0.2120V   0.2340V
| Timing spec test load voltage corners
Vref   0.0000V   0.0000V   0.0000V
| Dynamic Overshoot Parameters from LPDDR4 Specification
D_overshoot_ampl_h   0.30   NA   NA
D_overshoot_ampl_l   0.30   NA   NA
D_overshoot_area_h   0.1n   NA   NA
D_overshoot_area_l   0.1n   NA   NA
[Receiver Thresholds]
Vth   = 0.2200V
Vth_min  = 0.2167V
Vth_max  = 0.2233V
Vinh_ac  = 0.060V
Vinh_dc  = 0.060V
Vinl_ac  = -0.060V
Vinl_dc  = -0.060V
Tslew_ac = 5.000ns |Not specified, so set to high value
Threshold_sensitivity = 0.2000
Reference_supply Pullup_ref
[Voltage Range]   1.1000V   1.0600V   1.1700V
[Pullup Reference]   1.1000V   1.0600V   1.1700V
| Junction Temperature (Ambient temp is 35C typ 95C min -40C max)
[Temperature Range]   50.0   110.0   -40.0
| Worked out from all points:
|   slope of the pulldown table from 0 to 0.165 V, typ, clamps not added: 225 ohm
|   slope of the pullup table from 0 to 0.165 V, typ, clamps not added: 53.3 kohm
|   GND clamp passes 1 mA (typ) near -0.45 V on its own axis
|   POWER clamp passes 1 mA (typ) near -0.88 V on its own axis
|   rising waveform, R_fixture 50, V_fixture 0.0: 20-80 % time 47.2ps typ, 51.6ps min, 43.3ps max; typ from 0 V to 0.203 V
|   falling waveform, R_fixture 50, V_fixture 1.1: 20-80 % time 65.1ps typ, 73.8ps min, 55.6ps max; typ from 1.1 V to 0.958 V
|   rising waveform, R_fixture 50, V_fixture 1.1: 20-80 % time 52.6ps typ, 54.7ps min, 49.5ps max; typ from 0.958 V to 1.1 V
|   falling waveform, R_fixture 50, V_fixture 0.0: 20-80 % time 47.3ps typ, 52.1ps min, 43ps max; typ from 0.203 V to 0.001 V
[Pulldown]
|   Voltage   I(typ)   I(min)   I(max)
-1.1V     -15.26mA   -13.22mA   -17.26mA
-915.2mV  -12.8mA    -11.24mA   -14.39mA
-700.7mV  -9.701mA   -8.547mA   -10.93mA
-489.5mV  -6.173mA   -5.093mA   -7.445mA
-314.6mV  -2.761mA   -2.235mA   -3.572mA
-209mV    -1.332mA   -1.185mA   -1.601mA
-100.1mV  -523.2uA   -506.5uA   -530.7uA
170.5mV   746.3uA    741.4uA    745uA
427.9mV   1.702mA    1.662mA    1.769mA
889.9mV   2.749mA    2.521mA    3.143mA
1.434V    3.31mA     2.996mA    3.917mA
2.2V      3.818mA    3.475mA    4.505mA
[GND Clamp]
|   Voltage   I(typ)   I(min)   I(max)
-1.1V     -34.89mA   -30.33mA   -43.14mA
-944.9mV  -25.34mA   -21.52mA   -31.72mA
-793.1mV  -15.99mA   -13.01mA   -21.07mA
-723.8mV  -11.98mA   -9.379mA   -16.19mA
-664.4mV  -8.772mA   -6.596mA   -12.13mA
-591.8mV  -5.273mA   -3.797mA   -7.531mA
-522.5mV  -2.679mA   -1.904mA   -3.826mA
-469.7mV  -1.366mA   -988.3uA   -1.793mA
-413.6mV  -570.1uA   -416.8uA   -623.3uA
-347.6mV  -154.3uA   -117.7uA   -135.1uA
-238.7mV  -9.037uA   -8.394uA   -5.027uA
2.2V      0A         0A         0A
[Pullup]
|   Voltage   I(typ)   I(min)   I(max)
-1.1V     1.371uA    2.481uA    454.5nA
269.5mV   -24.58uA   -23.65uA   -25.87uA
401.5mV   -232.2uA   -192.7uA   -274uA
517mV     -788.9uA   -720.9uA   -813.2uA
629.2mV   -1.613mA   -1.645mA   -1.529mA
761.2mV   -2.768mA   -3.054mA   -2.513mA
1.032V    -5.393mA   -6.298mA   -4.813mA
1.448V    -9.715mA   -11.29mA   -8.771mA
1.662V    -11.91mA   -13.45mA   -11.32mA
1.887V    -14.33mA   -15.16mA   -14.11mA
2.114V    -16.89mA   -16.95mA   -17.27mA
2.2V      -17.84mA   -17.49mA   -18.41mA
[POWER Clamp]
|   Voltage   I(typ)   I(min)   I(max)
-1.1V     3.036mA    3.636mA    2.186mA
-1.044V   2.383mA    2.969mA    1.654mA
-977.9mV  1.724mA    2.242mA    1.161mA
-908.6mV  1.178mA    1.583mA    748.1uA
-852.5mV  818.4uA    1.149mA    543.8uA
-776.6mV  434.5uA    683.8uA    390.2uA
-710.6mV  232.3uA    359.2uA    273.1uA
-657.8mV  146.8uA    178.8uA    190.7uA
-595.1mV  80.8uA     68.3uA     109.2uA
-502.7mV  22.71uA    14.04uA    29.29uA
-387.2mV  1.893uA    1.293uA    1.618uA
2.2V      0A         0A         0A
[Ramp]
|   typ   min   max
| 20% - 80%
dV/dt_r   121.48m/47.16p   123.79m/51.63p   125.29m/43.31p
dV/dt_f   85.16m/65.00p   76.65m/73.78p   100.80m/55.85p
| 25% - 75%
|dV/dt_r   101.23m/37.55p   103.16m/41.13p   104.41m/34.39p
|dV/dt_f   70.97m/51.73p   63.87m/58.75p   84.00m/44.40p
R_load = 50
[Rising Waveform]
R_fixture = 50
V_fixture = 0.0
|   Time   V(typ)   V(min)   V(max)
0s        392uV      320.6uV    288.1uV
57ps      31.37uV    -897nV     2.638mV
66ps      1.002mV    -324.7uV   17.64mV
77ps      6.535mV    326uV      55.69mV
103ps     80.83mV    15.97mV    140.9mV
124ps     137.7mV    73.37mV    177.2mV
145ps     170.7mV    129.9mV    194.8mV
171ps     190.2mV    172.7mV    203.9mV
207ps     199.6mV    197.1mV    207.8mV
373ps     202.9mV    206.6mV    209.1mV
[Falling Waveform]
R_fixture   = 50
V_fixture   = 1.1
V_fixture_min = 1.06
V_fixture_max = 1.17
|   Time   V(typ)   V(min)   V(max)
0s        1.1V       1.06V      1.17V
71ps      1.1V       1.06V      1.167V
93ps      1.095V     1.058V     1.121V
121ps     1.053V     1.051V     1.062V
145ps     1.016V     1.024V     1.033V
166ps     993.6mV    996.8mV    1.019V
201ps     973mV      964.1mV    1.008V
241ps     963.3mV    945.1mV    1.004V
293ps     959.3mV    935.7mV    1.002V
373ps     958.1mV    932.3mV    1.002V
[Rising Waveform]
R_fixture   = 50
V_fixture   = 1.1
V_fixture_min = 1.06
V_fixture_max = 1.17
|   Time   V(typ)   V(min)   V(max)
0s        957.9mV    931.6mV    1.002V
51ps      955.9mV    929.3mV    1.006V
62ps      962.5mV    928.2mV    1.033V
72ps      981.4mV    933.1mV    1.067V
90ps      1.026V     964.7mV    1.108V
112ps     1.058V     1.007V     1.136V
139ps     1.079V     1.033V     1.154V
175ps     1.091V     1.049V     1.164V
217ps     1.097V     1.056V     1.168V
373ps     1.1V       1.06V      1.17V
[Falling Waveform]
R_fixture = 50
V_fixture = 0.0
|   Time   V(typ)   V(min)   V(max)
0s        202.9mV    206.7mV    209.2mV
60ps      205.8mV    209mV      206.2mV
71ps      203.2mV    212.5mV    181.4mV
86ps      172.4mV    208.6mV    114.9mV
98ps      127.5mV    185.8mV    77.67mV
114ps     78.87mV    134.6mV    46.84mV
145ps     31.74mV    58.04mV    17.79mV
175ps     13.44mV    25.44mV    7.132mV
212ps     4.879mV    9.475mV    2.478mV
373ps     519.9uV    548.8uV    330.8uV
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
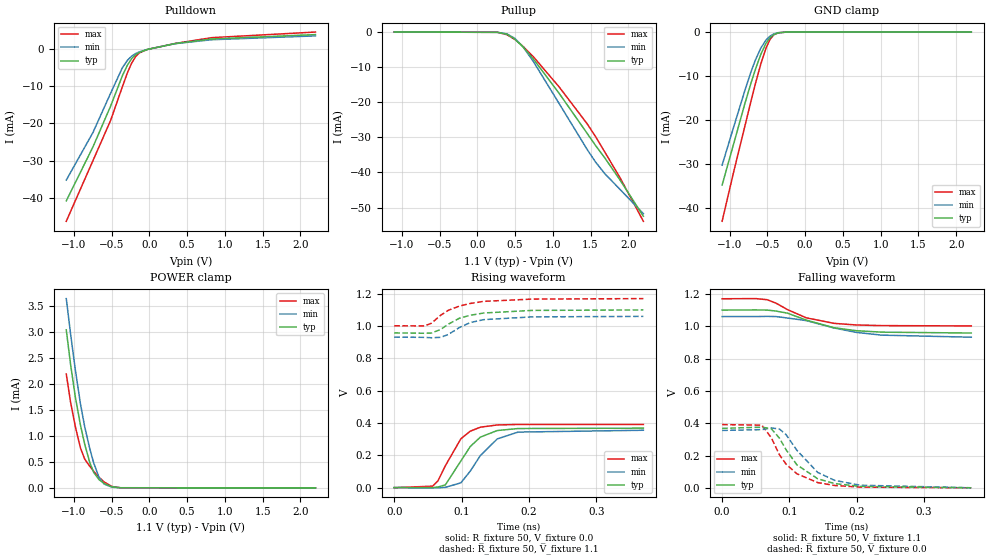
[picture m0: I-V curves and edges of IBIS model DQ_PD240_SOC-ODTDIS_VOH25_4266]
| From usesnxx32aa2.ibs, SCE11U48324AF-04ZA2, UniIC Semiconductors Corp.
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| DQ_PD240_SOC-ODTDIS_VOH25_4266
| (240 Ohm Pulldown, SOC ODT disabled setting, VOH=VDDQ/2.5 cal. point, 3200-4266Mbps)
[Model]   DQ_PD240_SOC-ODTDIS_VOH25_4266
Model_type   I/O
Vinl = 160.000mV
Vinh = 280.000mV
Vmeas = 220.000mV
Vref = 0.0mV
Cref = 0.0pF
|   typ   min   max
|C_comp   0.797pF   0.747pF   0.847pF
C_comp_pullup   0.3985pF   0.3735pF   0.4235pF
C_comp_pulldown   0.3985pF   0.3735pF   0.4235pF
| Note: C_comp changes when the ODT circuit is enabled.
[Model Spec]
| Input threshold voltage corners
Vinl   0.1600V   0.1520V   0.1740V
Vinh   0.2800V   0.2720V   0.2940V
| Measurement voltage corners
Vmeas   0.2200V   0.2120V   0.2340V
| Timing spec test load voltage corners
Vref   0.0000V   0.0000V   0.0000V
| Dynamic Overshoot Parameters from LPDDR4 Specification
D_overshoot_ampl_h   0.30   NA   NA
D_overshoot_ampl_l   0.30   NA   NA
D_overshoot_area_h   0.1n   NA   NA
D_overshoot_area_l   0.1n   NA   NA
[Receiver Thresholds]
Vth   = 0.2200V
Vth_min  = 0.2167V
Vth_max  = 0.2233V
Vinh_ac  = 0.060V
Vinh_dc  = 0.060V
Vinl_ac  = -0.060V
Vinl_dc  = -0.060V
Tslew_ac = 5.000ns |Not specified, so set to high value
Threshold_sensitivity = 0.2000
Reference_supply Pullup_ref
[Voltage Range]   1.1000V   1.0600V   1.1700V
[Pullup Reference]   1.1000V   1.0600V   1.1700V
| Junction Temperature (Ambient temp is 35C typ 95C min -40C max)
[Temperature Range]   50.0   110.0   -40.0
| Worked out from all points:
|   slope of the pulldown table from 0 to 0.165 V, typ, clamps not added: 220 ohm
|   slope of the pullup table from 0 to 0.165 V, typ, clamps not added: 17.8 kohm
|   GND clamp passes 1 mA (typ) near -0.45 V on its own axis
|   POWER clamp passes 1 mA (typ) near -0.88 V on its own axis
|   rising waveform, R_fixture 50, V_fixture 0.0: 20-80 % time 35.1ps typ, 39ps min, 31.7ps max; typ from 0.001 V to 0.369 V
|   falling waveform, R_fixture 50, V_fixture 1.1: 20-80 % time 68.3ps typ, 81ps min, 57.6ps max; typ from 1.1 V to 0.958 V
|   rising waveform, R_fixture 50, V_fixture 1.1: 20-80 % time 47ps typ, 41.2ps min, 47.7ps max; typ from 0.958 V to 1.1 V
|   falling waveform, R_fixture 50, V_fixture 0.0: 20-80 % time 45.6ps typ, 49.1ps min, 41.6ps max; typ from 0.369 V to 0.001 V
[Pulldown]
|   Voltage   I(typ)   I(min)   I(max)
-1.1V     -40.79mA   -35.22mA   -46.27mA
-746.9mV  -26.33mA   -22.46mA   -30.01mA
-512.6mV  -15.36mA   -11.9mA    -19.19mA
-357.5mV  -7.236mA   -5.092mA   -10.2mA
-291.5mV  -4.419mA   -3.109mA   -6.486mA
-235.4mV  -2.662mA   -1.978mA   -3.873mA
-182.6mV  -1.576mA   -1.276mA   -2.098mA
-133.1mV  -941.2uA   -823.5uA   -1.092mA
-24.2mV   -157.9uA   -147.9uA   -148.5uA
338.8mV   1.4mA      1.377mA    1.431mA
823.9mV   2.649mA    2.443mA    2.993mA
2.2V      3.818mA    3.475mA    4.505mA
[GND Clamp]
|   Voltage   I(typ)   I(min)   I(max)
-1.1V     -34.89mA   -30.35mA   -43.14mA
-948.2mV  -25.55mA   -21.71mA   -31.96mA
-796.4mV  -16.18mA   -13.19mA   -21.3mA
-720.5mV  -11.8mA    -9.215mA   -15.96mA
-661.1mV  -8.6mA     -6.453mA   -11.91mA
-588.5mV  -5.129mA   -3.689mA   -7.336mA
-519.2mV  -2.574mA   -1.839mA   -3.676mA
-466.4mV  -1.3mA     -942.5uA   -1.694mA
-416.9mV  -597.8uA   -442uA     -666.4uA
-357.5mV  -191.9uA   -144.8uA   -173.5uA
-248.6mV  -12.13uA   -11.13uA   -7.05uA
2.2V      0A         0A         0A
[Pullup]
|   Voltage   I(typ)   I(min)   I(max)
-1.1V     4.112uA    7.441uA    1.363uA
266.2mV   -69.32uA   -66.81uA   -71.88uA
394.9mV   -631.7uA   -529.2uA   -751.2uA
500.5mV   -2.042mA   -1.832mA   -2.145mA
609.4mV   -4.304mA   -4.305mA   -4.133mA
741.4mV   -7.642mA   -8.32mA    -6.986mA
1.085V    -17.48mA   -20.39mA   -15.65mA
1.454V    -28.82mA   -33.4mA    -26.09mA
1.566V    -32.29mA   -37.01mA   -29.76mA
1.688V    -35.82mA   -40.32mA   -34.15mA
1.887V    -42.03mA   -44.75mA   -41.35mA
2.2V      -52.46mA   -51.75mA   -53.91mA
[POWER Clamp]
|   Voltage   I(typ)   I(min)   I(max)
-1.1V     3.036mA    3.636mA    2.186mA
-1.044V   2.383mA    2.969mA    1.654mA
-981.2mV  1.754mA    2.277mA    1.183mA
-911.9mV  1.201mA    1.611mA    764.3uA
-855.8mV  838.1uA    1.172mA    552.1uA
-789.8mV  491.2uA    757.5uA    414.8uA
-737mV    296.7uA    478.5uA    318.4uA
-667.7mV  159.9uA    206.2uA    205.2uA
-598.4mV  83.65uA    71.98uA    113.1uA
-496.1mV  20.15uA    12.38uA    25.72uA
-383.9mV  1.754uA    1.219uA    1.465uA
2.2V      0A         0A         0A
[Ramp]
|   typ   min   max
| 20% - 80%
dV/dt_r   220.49m/35.08p   212.87m/39.00p   234.65m/31.75p
dV/dt_f   85.17m/68.39p   76.65m/81.39p   100.81m/57.38p
| 25% - 75%
|dV/dt_r   183.74m/27.93p   177.39m/31.05p   195.54m/25.24p
|dV/dt_f   70.97m/54.36p   63.87m/64.30p   84.01m/45.67p
R_load = 50
[Rising Waveform]
R_fixture = 50
V_fixture = 0.0
|   Time   V(typ)   V(min)   V(max)
0s        1.172mV    977.1uV    853.7uV
57ps      931.7uV    -101.8uV   9.88mV
65ps      4.713mV    -382.5uV   43.01mV
76ps      17.99mV    2.644mV    136.6mV
99ps      165.8mV    30.42mV    303mV
113ps     255.3mV    103.4mV    350.2mV
128ps     313.4mV    199.6mV    374.7mV
153ps     354.1mV    302.1mV    388.5mV
184ps     366.4mV    344.4mV    391.5mV
370ps     368.7mV    355.8mV    391.9mV
[Falling Waveform]
R_fixture   = 50
V_fixture   = 1.1
V_fixture_min = 1.06
V_fixture_max = 1.17
|   Time   V(typ)   V(min)   V(max)
0s        1.1V       1.06V      1.17V
50ps      1.101V     1.06V      1.171V
67ps      1.1V       1.061V     1.164V
80ps      1.094V     1.06V      1.143V
97ps      1.081V     1.051V     1.103V
125ps     1.038V     1.035V     1.052V
166ps     990.9mV    989.6mV    1.018V
199ps     972.6mV    962.2mV    1.008V
237ps     963.5mV    945.1mV    1.004V
370ps     958.1mV    932.3mV    1.002V
[Rising Waveform]
R_fixture   = 50
V_fixture   = 1.1
V_fixture_min = 1.06
V_fixture_max = 1.17
|   Time   V(typ)   V(min)   V(max)
0s        957.9mV    931.6mV    1.002V
45ps      955.7mV    930.4mV    1.001V
55ps      956.6mV    927.9mV    1.017V
69ps      979.3mV    930.5mV    1.067V
80ps      1.011V     947.4mV    1.097V
97ps      1.049V     991.4mV    1.124V
113ps     1.067V     1.022V     1.14V
133ps     1.081V     1.04V      1.153V
205ps     1.097V     1.057V     1.167V
370ps     1.1V       1.06V      1.17V
[Falling Waveform]
R_fixture = 50
V_fixture = 0.0
|   Time   V(typ)   V(min)   V(max)
0s        368.8mV    355.9mV    392mV
59ps      376.1mV    360.8mV    388.4mV
73ps      366.7mV    371.1mV    311.3mV
85ps      308.9mV    364.7mV    206.1mV
95ps      236.4mV    329.8mV    147.4mV
111ps     143.4mV    233.1mV    87.93mV
142ps     56.6mV     95.82mV    33.2mV
167ps     27.48mV    47.25mV    15.47mV
205ps     9.692mV    17.03mV    5.238mV
370ps     1.289mV    1.224mV    903.9uV
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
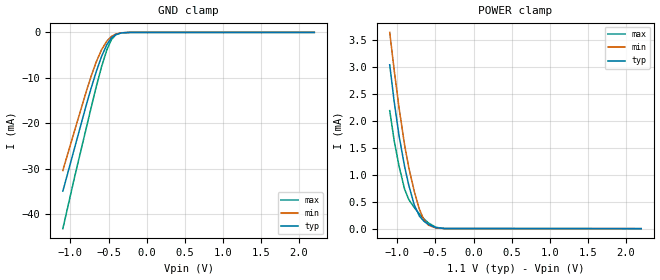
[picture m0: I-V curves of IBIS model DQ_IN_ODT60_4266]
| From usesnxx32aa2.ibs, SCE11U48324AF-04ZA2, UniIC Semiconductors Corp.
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| DQ_IN_ODT60_4266 (with 60ohm ODT, 3200-4266Mbps)
[Model]   DQ_IN_ODT60_4266
Model_type   Input
Vinl = 123.333mV
Vinh = 243.333mV
|   typ   min   max
|C_comp   0.771pF   0.724pF   0.823pF
C_comp_power_clamp   0.3855pF   0.3620pF   0.4115pF
C_comp_gnd_clamp   0.3855pF   0.3620pF   0.4115pF
| Note: C_comp changes when the ODT circuit is enabled.
[Model Spec]
| Input threshold voltage corners
Vinl   0.1233V   0.1167V   0.1350V
Vinh   0.2433V   0.2367V   0.2550V
| Dynamic Overshoot Parameters from LPDDR4 Specification
D_overshoot_ampl_h   0.30   NA   NA
D_overshoot_ampl_l   0.30   NA   NA
D_overshoot_area_h   0.1n   NA   NA
D_overshoot_area_l   0.1n   NA   NA
[Receiver Thresholds]
Vth   = 0.1833V
Vth_min  = 0.1800V
Vth_max  = 0.1866V
Vinh_ac  = 0.060V
Vinh_dc  = 0.060V
Vinl_ac  = -0.060V
Vinl_dc  = -0.060V
Tslew_ac = 5.000ns |Not specified, so set to high value
Threshold_sensitivity = 0.1667
Reference_supply Power_clamp_ref
[Voltage Range]   1.1000V   1.0600V   1.1700V
[POWER Clamp Reference]   1.1000V   1.0600V   1.1700V
| Junction Temperature (Ambient temp is 35C typ 95C min -40C max)
[Temperature Range]   50.0   110.0   -40.0
[Add Submodel]
| Submodel Name   Mode
60ohm_ODT_4266   Non-Driving
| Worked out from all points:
|   GND clamp passes 1 mA (typ) near -0.45 V on its own axis
|   POWER clamp passes 1 mA (typ) near -0.88 V on its own axis
[GND Clamp]
|   Voltage   I(typ)   I(min)   I(max)
-1.1V     -34.88mA   -30.34mA   -43.13mA
-941.6mV  -25.13mA   -21.34mA   -31.47mA
-789.8mV  -15.79mA   -12.83mA   -20.82mA
-727.1mV  -12.17mA   -9.549mA   -16.41mA
-661.1mV  -8.598mA   -6.455mA   -11.9mA
-591.8mV  -5.273mA   -3.798mA   -7.529mA
-522.5mV  -2.672mA   -1.912mA   -3.822mA
-463.1mV  -1.24mA    -904.9uA   -1.604mA
-407mV    -507uA     -377.3uA   -542.1uA
-334.4mV  -115.1uA   -86.84uA   -97.76uA
-218.9mV  -5.347uA   -5.058uA   -2.413uA
2.2V      0A         0A         0A
[POWER Clamp]
|   Voltage   I(typ)   I(min)   I(max)
-1.1V     3.036mA    3.636mA    2.186mA
-1.041V   2.347mA    2.931mA    1.626mA
-977.9mV  1.724mA    2.242mA    1.161mA
-905.3mV  1.155mA    1.554mA    733uA
-849.2mV  799.6uA    1.127mA    536.8uA
-776.6mV  434.3uA    683.8uA    390.2uA
-710.6mV  233.6uA    359.2uA    273.1uA
-651.2mV  137.4uA    162.5uA    181.2uA
-591.8mV  78.18uA    65.06uA    105.7uA
-496.1mV  17.57uA    12.35uA    25.98uA
-377.3mV  3.689uA    1.066uA    1.269uA
2.2V      0A         0A         0A
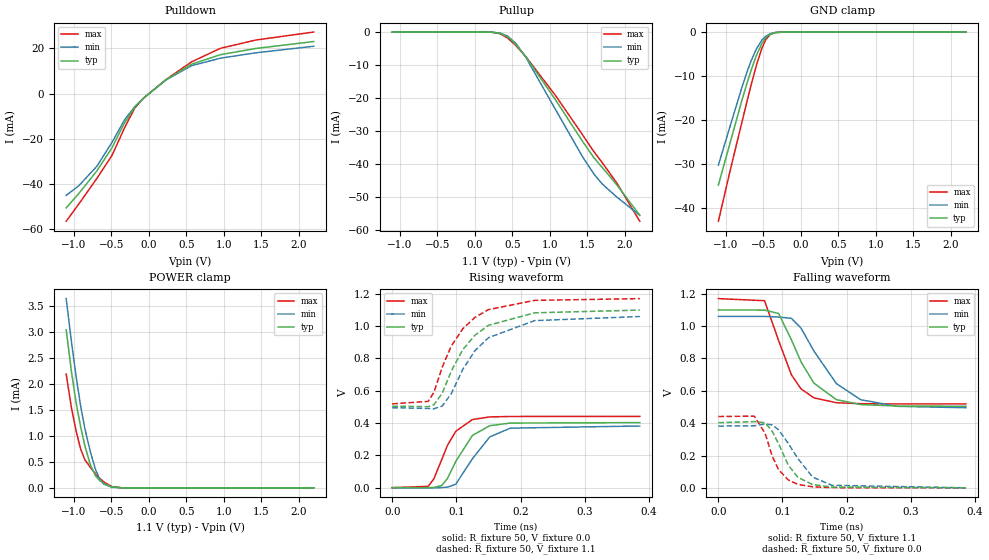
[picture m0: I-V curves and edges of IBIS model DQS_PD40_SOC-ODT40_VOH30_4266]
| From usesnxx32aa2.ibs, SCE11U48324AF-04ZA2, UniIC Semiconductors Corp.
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| DQS_PD40_SOC-ODT40_VOH30_4266
| (40 Ohm Pulldown, 40 Ohm System ODT Setting, VOH=VDDQ/3.0, 3200-4266Mbps)
[Model]   DQS_PD40_SOC-ODT40_VOH30_4266
Model_type   I/O
Vinl = 123.333mV
Vinh = 243.333mV
Vmeas = 183.333mV
Vref = 0.0mV
Cref = 0.0pF
Rref = 40.000Ohm
|   typ   min   max
|C_comp   0.838pF   0.788pF   0.888pF
C_comp_pullup   0.4190pF   0.3940pF   0.4440pF
C_comp_pulldown   0.4190pF   0.3940pF   0.4440pF
| Note: C_comp changes when the ODT circuit is enabled.
[Model Spec]
| Input threshold voltage corners
Vinl   0.1233V   0.1167V   0.1350V
Vinh   0.2433V   0.2367V   0.2550V
| Measurement voltage corners
Vmeas   0.1833V   0.1767V   0.1950V
| Timing spec test load voltage corners
Vref   0.0000V   0.0000V   0.0000V
| Dynamic Overshoot Parameters from LPDDR4 Specification
D_overshoot_ampl_h   0.30   NA   NA
D_overshoot_ampl_l   0.30   NA   NA
D_overshoot_area_h   0.1n   NA   NA
D_overshoot_area_l   0.1n   NA   NA
[Receiver Thresholds]
Vcross_low   = 123.3mV
Vcross_high  = 243.3mV
Vdiff_ac   = 120mV
Vdiff_dc   = 120mV
Tdiffslew_ac = 10.000ns |Not specified, so set to high value
[Voltage Range]   1.1000V   1.0600V   1.1700V
[Pullup Reference]   1.1000V   1.0600V   1.1700V
| Junction Temperature (Ambient temp is 35C typ 95C min -40C max)
[Temperature Range]   50.0   110.0   -40.0
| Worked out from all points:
|   slope of the pulldown table from 0 to 0.165 V, typ, clamps not added: 36.9 ohm
|   slope of the pullup table from 0 to 0.165 V, typ, clamps not added: 13 kohm
|   GND clamp passes 1 mA (typ) near -0.45 V on its own axis
|   POWER clamp passes 1 mA (typ) near -0.88 V on its own axis
|   rising waveform, R_fixture 50, V_fixture 0.0: 20-80 % time 35.3ps typ, 39.1ps min, 30.9ps max; typ from 0.001 V to 0.403 V
|   falling waveform, R_fixture 50, V_fixture 1.1: 20-80 % time 47.2ps typ, 59ps min, 37.1ps max; typ from 1.1 V to 0.505 V
|   rising waveform, R_fixture 50, V_fixture 1.1: 20-80 % time 58.2ps typ, 61.4ps min, 54.2ps max; typ from 0.505 V to 1.1 V
|   falling waveform, R_fixture 50, V_fixture 0.0: 20-80 % time 32ps typ, 40.2ps min, 26.8ps max; typ from 0.403 V to 0.001 V
[Pulldown]
|   Voltage   I(typ)   I(min)   I(max)
-1.1V     -50.63mA   -45.08mA   -56.55mA
-931.7mV  -44.24mA   -40.8mA    -48.89mA
-690.8mV  -34.25mA   -32.2mA    -37.57mA
-489.5mV  -24.03mA   -21.64mA   -27.4mA
-317.9mV  -12.7mA    -11.44mA   -14.85mA
-182.6mV  -5.878mA   -5.686mA   -6.271mA
-63.8mV   -1.902mA   -1.889mA   -1.878mA
229.9mV   6.074mA    5.999mA    6.158mA
569.8mV   12.93mA    12.3mA     13.98mA
955.9mV   17.19mA    15.64mA    20mA
1.428V    19.94mA    18.02mA    23.68mA
2.2V      23.01mA    20.92mA    27.21mA
[GND Clamp]
|   Voltage   I(typ)   I(min)   I(max)
-1.1V     -34.88mA   -30.34mA   -43.13mA
-938.3mV  -24.92mA   -21.15mA   -31.24mA
-786.5mV  -15.59mA   -12.65mA   -20.59mA
-723.8mV  -11.98mA   -9.381mA   -16.18mA
-664.4mV  -8.768mA   -6.598mA   -12.12mA
-591.8mV  -5.271mA   -3.798mA   -7.524mA
-519.2mV  -2.572mA   -1.839mA   -3.672mA
-466.4mV  -1.299mA   -945.1uA   -1.693mA
-407mV    -503.4uA   -374.2uA   -541.5uA
-341mV    -134.1uA   -102.3uA   -114.6uA
-232.1mV  -7.507uA   -7.153uA   -3.987uA
2.2V      0A         0A         0A
[Pullup]
|   Voltage   I(typ)   I(min)   I(max)
-1.1V     6.284uA    9.684uA    2.832uA
226.6mV   -42.49uA   -43.11uA   -42.83uA
335.5mV   -341.1uA   -283.4uA   -469.8uA
437.8mV   -1.438mA   -1.179mA   -1.809mA
550mV     -3.801mA   -3.492mA   -4.138mA
682mV     -7.523mA   -7.706mA   -7.473mA
1.078V    -20.57mA   -23.52mA   -19.26mA
1.434V    -32.99mA   -37.64mA   -31.01mA
1.586V    -37.97mA   -42.9mA    -36.14mA
1.698V    -40.96mA   -45.96mA   -39.5mA
1.893V    -46.24mA   -49.93mA   -45.68mA
2.2V      -55.46mA   -55.5mA    -57.28mA
[POWER Clamp]
|   Voltage   I(typ)   I(min)   I(max)
-1.1V     3.036mA    3.636mA    2.186mA
-1.031V   2.241mA    2.818mA    1.547mA
-964.7mV  1.61mA     2.107mA    1.073mA
-905.3mV  1.155mA    1.555mA    732.4uA
-849.2mV  799.3uA    1.126mA    535.5uA
-776.6mV  434.2uA    683.5uA    390.2uA
-707.3mV  225.6uA    345.4uA    267.6uA
-654.5mV  142.7uA    170.5uA    185.9uA
-595.1mV  80.77uA    68.3uA     109.3uA
-492.8mV  18.95uA    11.55uA    24.07uA
-360.8mV  1.023uA    778nA      803.1nA
2.2V      0A         0A         0A
[Ramp]
|   typ   min   max
| 20% - 80%
dV/dt_r   241.38m/35.31p   228.93m/39.10p   264.47m/30.86p
dV/dt_f   357.20m/47.15p   338.68m/58.98p   390.62m/37.17p
| 25% - 75%
|dV/dt_r   201.15m/28.12p   190.77m/31.16p   220.39m/24.50p
|dV/dt_f   297.67m/37.61p   282.23m/47.10p   325.52m/29.59p
R_load = 50
[Rising Waveform]
R_fixture = 50
V_fixture = 0.0
|   Time   V(typ)   V(min)   V(max)
0s        552.8uV    474.5uV    400.4uV
56ps      258.6uV    77.34uV    8.735mV
65ps      2.198mV    -528.4uV   56mV
77ps      13.87mV    932.1uV    173.7mV
86ps      57.05mV    3.892mV    261.7mV
99ps      162.8mV    21.92mV    349.5mV
125ps     323.9mV    179.7mV    421.9mV
152ps     383.9mV    314.4mV    438.2mV
184ps     400.1mV    368.6mV    440.9mV
386ps     402.9mV    382mV      441.2mV
[Falling Waveform]
R_fixture   = 50
V_fixture   = 1.1
V_fixture_min = 1.06
V_fixture_max = 1.17
|   Time   V(typ)   V(min)   V(max)
0s        1.1V       1.06V      1.17V
72ps      1.099V     1.06V      1.157V
94ps      1.078V     1.056V     910.1mV
114ps     914.3mV    1.048V     698.2mV
129ps     778.6mV    987mV      611.4mV
149ps     647.3mV    846mV      556.5mV
184ps     545.6mV    644.9mV    526.6mV
222ps     515.1mV    545.1mV    520.4mV
279ps     506mV      504.2mV    519.1mV
386ps     504.7mV    495.5mV    519mV
[Rising Waveform]
R_fixture   = 50
V_fixture   = 1.1
V_fixture_min = 1.06
V_fixture_max = 1.17
|   Time   V(typ)   V(min)   V(max)
0s        504.5mV    495.1mV    518.9mV
56ps      501.5mV    490.5mV    534.3mV
65ps      513.6mV    488.4mV    590.6mV
78ps      585.4mV    505.4mV    747.2mV
92ps      722.1mV    582.1mV    876.9mV
110ps     854.7mV    732.8mV    984.1mV
129ps     943.7mV    848.1mV    1.054V
150ps     1.005V     928.1mV    1.102V
222ps     1.082V     1.034V     1.159V
386ps     1.099V     1.059V     1.17V
[Falling Waveform]
R_fixture = 50
V_fixture = 0.0
|   Time   V(typ)   V(min)   V(max)
0s        403mV      382.2mV    441.3mV
56ps      409.9mV    383.9mV    443.3mV
73ps      402mV      395mV      336.2mV
84ps      350mV      389.3mV    195.9mV
94ps      271.9mV    358.5mV    112.1mV
109ps     140.4mV    275mV      49.05mV
124ps     65.67mV    181.5mV    21.9mV
147ps     20.62mV    66.94mV    6.654mV
177ps     5.121mV    16.1mV     1.719mV
386ps     607.7uV    554.5uV    426.3uV
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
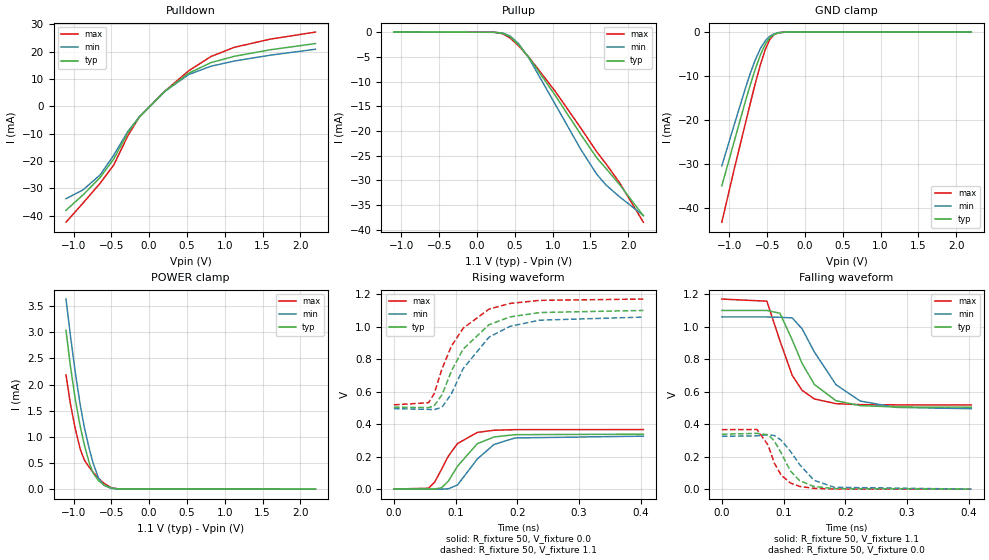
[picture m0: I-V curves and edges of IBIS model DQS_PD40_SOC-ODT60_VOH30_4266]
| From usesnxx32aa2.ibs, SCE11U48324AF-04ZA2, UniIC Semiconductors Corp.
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| DQS_PD40_SOC-ODT60_VOH30_4266
| (40 Ohm Pulldown, 60 Ohm System ODT Setting, VOH=VDDQ/3.0, 3200-4266Mbps)
[Model]   DQS_PD40_SOC-ODT60_VOH30_4266
Model_type   I/O
Vinl = 123.333mV
Vinh = 243.333mV
Vmeas = 183.333mV
Vref = 0.0mV
Cref = 0.0pF
Rref = 60.000Ohm
|   typ   min   max
|C_comp   0.838pF   0.788pF   0.888pF
C_comp_pullup   0.4190pF   0.3940pF   0.4440pF
C_comp_pulldown   0.4190pF   0.3940pF   0.4440pF
| Note: C_comp changes when the ODT circuit is enabled.
[Model Spec]
| Input threshold voltage corners
Vinl   0.1233V   0.1167V   0.1350V
Vinh   0.2433V   0.2367V   0.2550V
| Measurement voltage corners
Vmeas   0.1833V   0.1767V   0.1950V
| Timing spec test load voltage corners
Vref   0.0000V   0.0000V   0.0000V
| Dynamic Overshoot Parameters from LPDDR4 Specification
D_overshoot_ampl_h   0.30   NA   NA
D_overshoot_ampl_l   0.30   NA   NA
D_overshoot_area_h   0.1n   NA   NA
D_overshoot_area_l   0.1n   NA   NA
[Receiver Thresholds]
Vcross_low   = 123.3mV
Vcross_high  = 243.3mV
Vdiff_ac   = 120mV
Vdiff_dc   = 120mV
Tdiffslew_ac = 10.000ns |Not specified, so set to high value
[Voltage Range]   1.1000V   1.0600V   1.1700V
[Pullup Reference]   1.1000V   1.0600V   1.1700V
| Junction Temperature (Ambient temp is 35C typ 95C min -40C max)
[Temperature Range]   50.0   110.0   -40.0
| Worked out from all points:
|   slope of the pulldown table from 0 to 0.165 V, typ, clamps not added: 36.9 ohm
|   slope of the pullup table from 0 to 0.165 V, typ, clamps not added: 19.5 kohm
|   GND clamp passes 1 mA (typ) near -0.45 V on its own axis
|   POWER clamp passes 1 mA (typ) near -0.88 V on its own axis
|   rising waveform, R_fixture 50, V_fixture 0.0: 20-80 % time 40.2ps typ, 43.9ps min, 35.6ps max; typ from 0 V to 0.338 V
|   falling waveform, R_fixture 50, V_fixture 1.1: 20-80 % time 46.9ps typ, 58.6ps min, 37ps max; typ from 1.1 V to 0.505 V
|   rising waveform, R_fixture 50, V_fixture 1.1: 20-80 % time 58.8ps typ, 62.4ps min, 54.5ps max; typ from 0.505 V to 1.1 V
|   falling waveform, R_fixture 50, V_fixture 0.0: 20-80 % time 31.4ps typ, 40ps min, 26.3ps max; typ from 0.338 V to 0 V
[Pulldown]
|   Voltage   I(typ)   I(min)   I(max)
-1.1V     -38.06mA   -33.82mA   -42.42mA
-872.3mV  -32.35mA   -30.55mA   -35.34mA
-647.9mV  -26.03mA   -25.08mA   -28.14mA
-469.7mV  -19.32mA   -17.94mA   -21.52mA
-278.3mV  -9.551mA   -9.031mA   -10.59mA
-133.1mV  -3.99mA    -3.961mA   -4.019mA
213.4mV   5.67mA     5.605mA    5.735mA
523.6mV   12.17mA    11.67mA    13.04mA
817.3mV   16.02mA    14.71mA    18.26mA
1.127V    18.34mA    16.61mA    21.63mA
1.599V    20.72mA    18.74mA    24.61mA
2.2V      23.01mA    20.92mA    27.21mA
[GND Clamp]
|   Voltage   I(typ)   I(min)   I(max)
-1.1V     -34.88mA   -30.34mA   -43.13mA
-941.6mV  -25.13mA   -21.34mA   -31.48mA
-786.5mV  -15.59mA   -12.65mA   -20.59mA
-720.5mV  -11.79mA   -9.218mA   -15.95mA
-661.1mV  -8.597mA   -6.455mA   -11.9mA
-588.5mV  -5.128mA   -3.689mA   -7.328mA
-522.5mV  -2.673mA   -1.908mA   -3.822mA
-469.7mV  -1.361mA   -989uA     -1.79mA
-413.6mV  -565.3uA   -419uA     -621.8uA
-347.6mV  -154.7uA   -117.8uA   -135.4uA
-251.9mV  -13.27uA   -12.05uA   -7.883uA
2.2V      0A         0A         0A
[Pullup]
|   Voltage   I(typ)   I(min)   I(max)
-1.1V     4.189uA    6.456uA    1.888uA
226.6mV   -28.16uA   -28.72uA   -28.57uA
338.8mV   -240.5uA   -199uA     -331.4uA
434.5mV   -926.4uA   -757uA     -1.172mA
546.7mV   -2.491mA   -2.281mA   -2.719mA
688.6mV   -5.181mA   -5.337mA   -5.127mA
1.032V    -12.75mA   -14.54mA   -11.93mA
1.375V    -20.76mA   -23.78mA   -19.46mA
1.586V    -25.47mA   -28.79mA   -24.26mA
1.708V    -27.61mA   -30.94mA   -26.67mA
1.887V    -30.87mA   -33.32mA   -30.49mA
2.2V      -37.14mA   -37.08mA   -38.43mA
[POWER Clamp]
|   Voltage   I(typ)   I(min)   I(max)
-1.1V     3.036mA    3.636mA    2.186mA
-1.041V   2.347mA    2.931mA    1.626mA
-977.9mV  1.724mA    2.242mA    1.161mA
-911.9mV  1.201mA    1.612mA    765uA
-855.8mV  838.1uA    1.172mA    552.2uA
-793.1mV  506.1uA    776.1uA    421uA
-740.3mV  306.1uA    494.5uA    324.3uA
-671mV    164.5uA    215.9uA    210.2uA
-598.4mV  83.67uA    71.97uA    113uA
-502.7mV  22.59uA    14.08uA    29.27uA
-397.1mV  2.384uA    1.603uA    2.113uA
2.2V      0A         0A         0A
[Ramp]
|   typ   min   max
| 20% - 80%
dV/dt_r   202.65m/40.24p   195.41m/43.90p   219.72m/35.61p
dV/dt_f   357.20m/46.91p   338.78m/58.63p   390.62m/36.98p
| 25% - 75%
|dV/dt_r   168.87m/32.08p   162.84m/35.06p   183.10m/28.31p
|dV/dt_f   297.66m/37.41p   282.31m/46.83p   325.51m/29.44p
R_load = 50
[Rising Waveform]
R_fixture = 50
V_fixture = 0.0
|   Time   V(typ)   V(min)   V(max)
0s        357.1uV    298uV      259.2uV
56ps      105.3uV    204.4uV    5.361mV
66ps      671.6uV    -386.6uV   43.11mV
77ps      7.927mV    -51.42uV   120.7mV
88ps      48.07mV    1.568mV    202.2mV
103ps     141mV      25.38mV    280.3mV
135ps     279.4mV    185.2mV    348.9mV
162ps     320.9mV    274.5mV    362.4mV
196ps     335.1mV    314.9mV    365.9mV
404ps     338.1mV    326mV      366.5mV
[Falling Waveform]
R_fixture   = 50
V_fixture   = 1.1
V_fixture_min = 1.06
V_fixture_max = 1.17
|   Time   V(typ)   V(min)   V(max)
0s        1.1V       1.06V      1.17V
73ps      1.1V       1.06V      1.157V
94ps      1.083V     1.058V     914.4mV
114ps     918.9mV    1.054V     700.2mV
130ps     773.7mV    987.2mV    608.2mV
150ps     643.9mV    843.5mV    555.2mV
185ps     544.5mV    642.7mV    526.4mV
224ps     514.4mV    542.7mV    520.3mV
282ps     505.9mV    503.5mV    519.1mV
404ps     504.7mV    495.4mV    519mV
[Rising Waveform]
R_fixture   = 50
V_fixture   = 1.1
V_fixture_min = 1.06
V_fixture_max = 1.17
|   Time   V(typ)   V(min)   V(max)
0s        504.5mV    495.1mV    518.9mV
56ps      501.6mV    490.8mV    531.6mV
65ps      512.2mV    488.8mV    585.8mV
78ps      581.3mV    504.5mV    741.5mV
93ps      725.6mV    586.1mV    879.3mV
112ps     861.6mV    741mV      990.2mV
154ps     1.012V     935.3mV    1.108V
188ps     1.06V      1.002V     1.143V
236ps     1.087V     1.04V      1.162V
404ps     1.1V       1.059V     1.17V
[Falling Waveform]
R_fixture = 50
V_fixture = 0.0
|   Time   V(typ)   V(min)   V(max)
0s        338.2mV    326.1mV    366.5mV
57ps      343.6mV    328mV      367.5mV
75ps      335mV      335.8mV    270.7mV
85ps      297.7mV    330.2mV    161.1mV
96ps      224mV      302mV      87.45mV
111ps     112.8mV    233.9mV    38.57mV
126ps     52.92mV    151.9mV    17.29mV
149ps     16.82mV    55.53mV    5.304mV
182ps     3.681mV    11.89mV    1.2mV
404ps     430.9uV    397.8uV    291.3uV
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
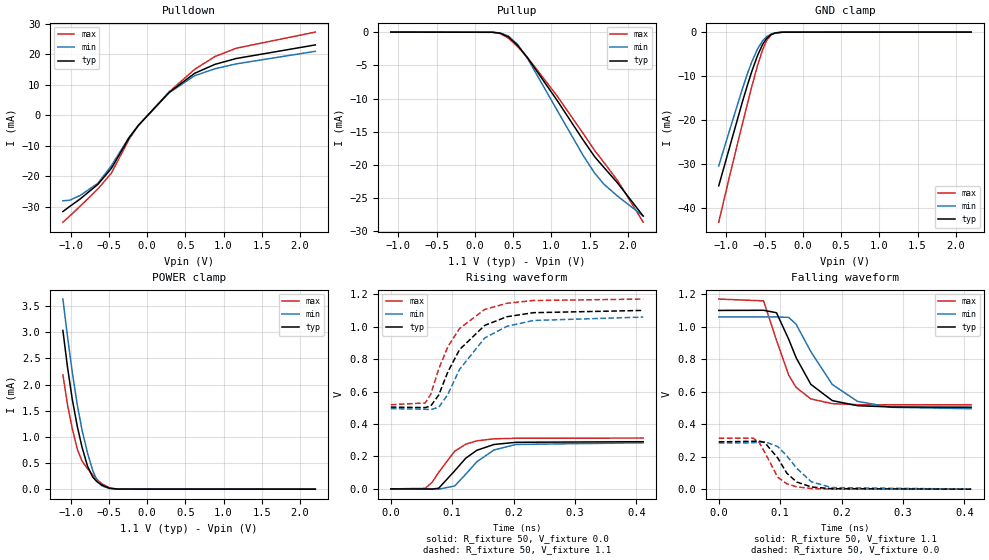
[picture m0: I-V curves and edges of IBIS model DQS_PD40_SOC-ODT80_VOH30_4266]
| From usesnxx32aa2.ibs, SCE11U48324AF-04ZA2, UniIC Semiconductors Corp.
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| DQS_PD40_SOC-ODT80_VOH30_4266
| (40 Ohm Pulldown, 80 Ohm System ODT Setting, VOH=VDDQ/3.0, 3200-4266Mbps)
[Model]   DQS_PD40_SOC-ODT80_VOH30_4266
Model_type   I/O
Vinl = 123.333mV
Vinh = 243.333mV
Vmeas = 183.333mV
Vref = 0.0mV
Cref = 0.0pF
Rref = 80.000Ohm
|   typ   min   max
|C_comp   0.838pF   0.788pF   0.888pF
C_comp_pullup   0.4190pF   0.3940pF   0.4440pF
C_comp_pulldown   0.4190pF   0.3940pF   0.4440pF
| Note: C_comp changes when the ODT circuit is enabled.
[Model Spec]
| Input threshold voltage corners
Vinl   0.1233V   0.1167V   0.1350V
Vinh   0.2433V   0.2367V   0.2550V
| Measurement voltage corners
Vmeas   0.1833V   0.1767V   0.1950V
| Timing spec test load voltage corners
Vref   0.0000V   0.0000V   0.0000V
| Dynamic Overshoot Parameters from LPDDR4 Specification
D_overshoot_ampl_h   0.30   NA   NA
D_overshoot_ampl_l   0.30   NA   NA
D_overshoot_area_h   0.1n   NA   NA
D_overshoot_area_l   0.1n   NA   NA
[Receiver Thresholds]
Vcross_low   = 123.3mV
Vcross_high  = 243.3mV
Vdiff_ac   = 120mV
Vdiff_dc   = 120mV
Tdiffslew_ac = 10.000ns |Not specified, so set to high value
[Voltage Range]   1.1000V   1.0600V   1.1700V
[Pullup Reference]   1.1000V   1.0600V   1.1700V
| Junction Temperature (Ambient temp is 35C typ 95C min -40C max)
[Temperature Range]   50.0   110.0   -40.0
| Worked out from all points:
|   slope of the pulldown table from 0 to 0.165 V, typ, clamps not added: 36.9 ohm
|   slope of the pullup table from 0 to 0.165 V, typ, clamps not added: 26 kohm
|   GND clamp passes 1 mA (typ) near -0.45 V on its own axis
|   POWER clamp passes 1 mA (typ) near -0.88 V on its own axis
|   rising waveform, R_fixture 50, V_fixture 0.0: 20-80 % time 43.9ps typ, 46.7ps min, 38.6ps max; typ from 0 V to 0.291 V
|   falling waveform, R_fixture 50, V_fixture 1.1: 20-80 % time 46.8ps typ, 58.5ps min, 36.9ps max; typ from 1.1 V to 0.505 V
|   rising waveform, R_fixture 50, V_fixture 1.1: 20-80 % time 59ps typ, 62.9ps min, 54.3ps max; typ from 0.505 V to 1.1 V
|   falling waveform, R_fixture 50, V_fixture 0.0: 20-80 % time 31.8ps typ, 40.5ps min, 26.9ps max; typ from 0.291 V to 0 V
[Pulldown]
|   Voltage   I(typ)   I(min)   I(max)
-1.1V     -31.52mA   -28.01mA   -35mA
-1.011V   -29.86mA   -27.81mA   -33mA
-872.3mV  -27.36mA   -26.24mA   -29.72mA
-641.3mV  -22.59mA   -22.22mA   -24.08mA
-466.4mV  -17.39mA   -16.53mA   -18.96mA
-235.4mV  -7.426mA   -7.242mA   -7.866mA
-113.3mV  -3.331mA   -3.326mA   -3.314mA
289.3mV   7.482mA    7.359mA    7.654mA
622.6mV   13.72mA    12.94mA    15.01mA
886.6mV   16.64mA    15.2mA     19.19mA
1.167V    18.57mA    16.81mA    21.94mA
2.2V      23.01mA    20.92mA    27.21mA
[GND Clamp]
|   Voltage   I(typ)   I(min)   I(max)
-1.1V     -34.88mA   -30.35mA   -43.13mA
-938.3mV  -24.92mA   -21.15mA   -31.24mA
-793.1mV  -15.98mA   -13.01mA   -21.06mA
-727.1mV  -12.16mA   -9.546mA   -16.41mA
-667.7mV  -8.939mA   -6.743mA   -12.34mA
-591.8mV  -5.272mA   -3.798mA   -7.524mA
-525.8mV  -2.773mA   -1.977mA   -3.976mA
-473mV    -1.423mA   -1.032mA   -1.891mA
-416.9mV  -597.6uA   -441.4uA   -666.1uA
-360.8mV  -205.8uA   -155.5uA   -188.7uA
-261.8mV  -17.63uA   -15.56uA   -10.94uA
2.2V      0A         0A         0A
[Pullup]
|   Voltage   I(typ)   I(min)   I(max)
-1.1V     3.142uA    4.844uA    1.416uA
229.9mV   -22.58uA   -22.99uA   -23.29uA
332.2mV   -161.5uA   -135.6uA   -221.5uA
437.8mV   -720.8uA   -590.6uA   -907.1uA
556.6mV   -1.993mA   -1.844mA   -2.153mA
691.9mV   -3.931mA   -4.057mA   -3.886mA
1.075V    -10.29mA   -11.77mA   -9.621mA
1.411V    -16.18mA   -18.5mA    -15.19mA
1.566V    -18.77mA   -21.24mA   -17.83mA
1.688V    -20.39mA   -22.91mA   -19.64mA
1.867V    -22.74mA   -24.71mA   -22.38mA
2.2V      -27.69mA   -27.67mA   -28.61mA
[POWER Clamp]
|   Voltage   I(typ)   I(min)   I(max)
-1.1V     3.036mA    3.636mA    2.186mA
-1.041V   2.347mA    2.931mA    1.626mA
-977.9mV  1.724mA    2.243mA    1.161mA
-911.9mV  1.201mA    1.612mA    764.9uA
-849.2mV  799.3uA    1.127mA    535.5uA
-776.6mV  434.2uA    683.5uA    390.2uA
-710.6mV  232.2uA    359.2uA    273.1uA
-657.8mV  146.8uA    178.8uA    190.7uA
-595.1mV  80.78uA    68.29uA    109.3uA
-492.8mV  18.89uA    11.55uA    24.07uA
-383.9mV  1.738uA    1.217uA    1.471uA
2.2V      0A         0A         0A
[Ramp]
|   typ   min   max
| 20% - 80%
dV/dt_r   174.52m/43.86p   170.50m/46.69p   187.91m/38.64p
dV/dt_f   357.21m/46.78p   338.79m/58.49p   390.61m/36.92p
| 25% - 75%
|dV/dt_r   145.43m/34.99p   142.08m/37.29p   156.59m/30.68p
|dV/dt_f   297.68m/37.33p   282.33m/46.73p   325.51m/29.39p
R_load = 50
[Rising Waveform]
R_fixture = 50
V_fixture = 0.0
|   Time   V(typ)   V(min)   V(max)
0s        258.4uV    207.6uV    188.9uV
56ps      -134uV     329.4uV    3.935mV
67ps      -862.1uV   -571uV     39.46mV
78ps      4.768mV    -1.293mV   103mV
104ps     111.6mV    18.35mV    232.4mV
122ps     189.4mV    90.8mV     275.7mV
140ps     238.2mV    167.3mV    296.5mV
168ps     274mV      240.1mV    308.8mV
204ps     287.6mV    274.3mV    312.5mV
411ps     291.1mV    284.4mV    313.4mV
[Falling Waveform]
R_fixture   = 50
V_fixture   = 1.1
V_fixture_min = 1.06
V_fixture_max = 1.17
|   Time   V(typ)   V(min)   V(max)
0s        1.1V       1.06V      1.17V
73ps      1.101V     1.06V      1.159V
94ps      1.086V     1.06V      917.1mV
114ps     922mV      1.057V     701.5mV
126ps     809.4mV    1.015V     626.6mV
150ps     645.1mV    846.2mV    555.5mV
185ps     545mV      644mV      526.5mV
226ps     513.9mV    540.4mV    520.1mV
281ps     505.9mV    503.9mV    519.1mV
411ps     504.6mV    495.3mV    519mV
[Rising Waveform]
R_fixture   = 50
V_fixture   = 1.1
V_fixture_min = 1.06
V_fixture_max = 1.17
|   Time   V(typ)   V(min)   V(max)
0s        504.5mV    495mV      518.9mV
56ps      501.4mV    491mV      530mV
65ps      511mV      488.8mV    583.1mV
78ps      578.6mV    503.3mV    739mV
93ps      722.4mV    583.3mV    877.2mV
112ps     859mV      737.4mV    989mV
153ps     1.008V     930.2mV    1.106V
189ps     1.061V     1.002V     1.144V
232ps     1.086V     1.038V     1.161V
411ps     1.1V       1.059V     1.17V
[Falling Waveform]
R_fixture = 50
V_fixture = 0.0
|   Time   V(typ)   V(min)   V(max)
0s        291.2mV    284.5mV    313.4mV
56ps      295mV      285.5mV    314mV
66ps      296mV      289.7mV    287.3mV
75ps      286.7mV    292.2mV    226.5mV
96ps      192.7mV    262.4mV    74.19mV
111ps     97.88mV    204.7mV    33.12mV
127ps     44.17mV    128.5mV    14.18mV
151ps     13.58mV    45.17mV    4.169mV
184ps     3.028mV    10.01mV    949.3uV
411ps     336.6uV    315.1uV    223.2uV
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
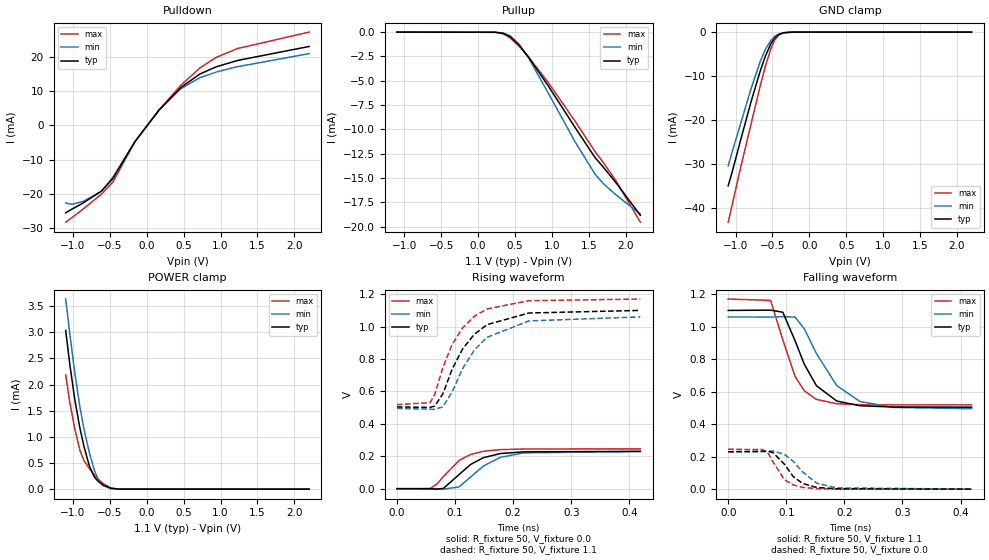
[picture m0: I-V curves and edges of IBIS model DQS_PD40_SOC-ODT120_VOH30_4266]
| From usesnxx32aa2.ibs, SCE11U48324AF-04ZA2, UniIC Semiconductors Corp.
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| DQS_PD40_SOC-ODT120_VOH30_4266
| (40 Ohm Pulldown, 120 Ohm System ODT Setting, VOH=VDDQ/3.0, 3200-4266Mbps)
[Model]   DQS_PD40_SOC-ODT120_VOH30_4266
Model_type   I/O
Vinl = 123.333mV
Vinh = 243.333mV
Vmeas = 183.333mV
Vref = 0.0mV
Cref = 0.0pF
Rref = 120.000Ohm
|   typ   min   max
|C_comp   0.838pF   0.788pF   0.888pF
C_comp_pullup   0.4190pF   0.3940pF   0.4440pF
C_comp_pulldown   0.4190pF   0.3940pF   0.4440pF
| Note: C_comp changes when the ODT circuit is enabled.
[Model Spec]
| Input threshold voltage corners
Vinl   0.1233V   0.1167V   0.1350V
Vinh   0.2433V   0.2367V   0.2550V
| Measurement voltage corners
Vmeas   0.1833V   0.1767V   0.1950V
| Timing spec test load voltage corners
Vref   0.0000V   0.0000V   0.0000V
| Dynamic Overshoot Parameters from LPDDR4 Specification
D_overshoot_ampl_h   0.30   NA   NA
D_overshoot_ampl_l   0.30   NA   NA
D_overshoot_area_h   0.1n   NA   NA
D_overshoot_area_l   0.1n   NA   NA
[Receiver Thresholds]
Vcross_low   = 123.3mV
Vcross_high  = 243.3mV
Vdiff_ac   = 120mV
Vdiff_dc   = 120mV
Tdiffslew_ac = 10.000ns |Not specified, so set to high value
[Voltage Range]   1.1000V   1.0600V   1.1700V
[Pullup Reference]   1.1000V   1.0600V   1.1700V
| Junction Temperature (Ambient temp is 35C typ 95C min -40C max)
[Temperature Range]   50.0   110.0   -40.0
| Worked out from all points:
|   slope of the pulldown table from 0 to 0.165 V, typ, clamps not added: 37 ohm
|   slope of the pullup table from 0 to 0.165 V, typ, clamps not added: 39.2 kohm
|   GND clamp passes 1 mA (typ) near -0.45 V on its own axis
|   POWER clamp passes 1 mA (typ) near -0.88 V on its own axis
|   rising waveform, R_fixture 50, V_fixture 0.0: 20-80 % time 47.8ps typ, 51.7ps min, 42.9ps max; typ from 0 V to 0.23 V
|   falling waveform, R_fixture 50, V_fixture 1.1: 20-80 % time 46.7ps typ, 58.3ps min, 36.8ps max; typ from 1.1 V to 0.505 V
|   rising waveform, R_fixture 50, V_fixture 1.1: 20-80 % time 59.2ps typ, 63.5ps min, 54.4ps max; typ from 0.505 V to 1.1 V
|   falling waveform, R_fixture 50, V_fixture 0.0: 20-80 % time 31.3ps typ, 39.4ps min, 26.6ps max; typ from 0.231 V to 0 V
[Pulldown]
|   Voltage   I(typ)   I(min)   I(max)
-1.1V     -25.52mA   -22.67mA   -28.25mA
-1.018V   -24.47mA   -23.02mA   -26.96mA
-869mV    -22.73mA   -22.24mA   -24.52mA
-614.9mV  -19.15mA   -19.26mA   -20.05mA
-459.8mV  -15.51mA   -15.11mA   -16.51mA
-159.5mV  -4.698mA   -4.697mA   -4.713mA
163.9mV   4.425mA    4.387mA    4.447mA
457.6mV   11mA       10.65mA    11.62mA
721.6mV   15mA       13.93mA    16.78mA
942.7mV   17.09mA    15.56mA    19.86mA
1.233V    18.95mA    17.13mA    22.43mA
2.2V      23.01mA    20.92mA    27.21mA
[GND Clamp]
|   Voltage   I(typ)   I(min)   I(max)
-1.1V     -34.88mA   -30.34mA   -43.13mA
-1.047V   -31.79mA   -27.25mA   -39.23mA
-938.3mV  -24.92mA   -21.15mA   -31.24mA
-789.8mV  -15.79mA   -12.83mA   -20.82mA
-664.4mV  -8.768mA   -6.598mA   -12.12mA
-595.1mV  -5.416mA   -3.908mA   -7.721mA
-522.5mV  -2.672mA   -1.905mA   -3.823mA
-469.7mV  -1.358mA   -986.2uA   -1.793mA
-413.6mV  -565.2uA   -417.3uA   -622.1uA
-350.9mV  -166.3uA   -125.9uA   -147.8uA
-228.8mV  -6.714uA   -6.472uA   -3.562uA
2.2V      0A         0A         0A
[Pullup]
|   Voltage   I(typ)   I(min)   I(max)
-1.1V     2.095uA    3.229uA    944.5nA
233.2mV   -16.16uA   -16.42uA   -16.87uA
342.1mV   -127.3uA   -105.3uA   -175.8uA
437.8mV   -483.6uA   -396.2uA   -609uA
556.6mV   -1.343mA   -1.244mA   -1.449mA
685.3mV   -2.586mA   -2.666mA   -2.557mA
952.6mV   -5.54mA    -6.28mA    -5.194mA
1.319V    -9.846mA   -11.33mA   -9.205mA
1.586V    -12.9mA    -14.6mA    -12.28mA
1.692V    -13.83mA   -15.53mA   -13.35mA
1.867V    -15.45mA   -16.71mA   -15.25mA
2.2V      -18.83mA   -18.71mA   -19.54mA
[POWER Clamp]
|   Voltage   I(typ)   I(min)   I(max)
-1.1V     3.036mA    3.636mA    2.186mA
-1.044V   2.383mA    2.969mA    1.653mA
-977.9mV  1.724mA    2.242mA    1.161mA
-908.6mV  1.178mA    1.582mA    748.6uA
-852.5mV  818.7uA    1.149mA    543.7uA
-779.9mV  448.2uA    701.9uA    396.3uA
-713.9mV  239.3uA    373.1uA    278.6uA
-661.1mV  151.1uA    187.6uA    195.5uA
-598.4mV  83.65uA    71.97uA    113.1uA
-489.5mV  17.8uA     10.83uA    22.45uA
-377.3mV  1.498uA    1.063uA    1.232uA
2.2V      0A         0A         0A
[Ramp]
|   typ   min   max
| 20% - 80%
dV/dt_r   138.17m/47.83p   137.76m/51.68p   147.36m/42.89p
dV/dt_f   357.21m/46.66p   338.79m/58.31p   390.61m/36.82p
| 25% - 75%
|dV/dt_r   115.14m/38.14p   114.80m/41.27p   122.80m/34.06p
|dV/dt_f   297.67m/37.22p   282.33m/46.57p   325.51m/29.32p
R_load = 50
[Rising Waveform]
R_fixture = 50
V_fixture = 0.0
|   Time   V(typ)   V(min)   V(max)
0s        159.9uV    119.4uV    117.9uV
57ps      -530.1uV   379.3uV    1.245mV
69ps      -2.744mV   -973.9uV   28.76mV
80ps      2.058mV    -2.824mV   75mV
107ps     87.47mV    11.13mV    174.4mV
127ps     150.1mV    72.72mV    211.7mV
149ps     191.6mV    140.2mV    231.2mV
178ps     216.8mV    193.4mV    241.1mV
218ps     227.5mV    221.1mV    244.8mV
419ps     230.4mV    229.7mV    245.7mV
[Falling Waveform]
R_fixture   = 50
V_fixture   = 1.1
V_fixture_min = 1.06
V_fixture_max = 1.17
|   Time   V(typ)   V(min)   V(max)
0s        1.1V       1.06V      1.17V
73ps      1.102V     1.059V     1.162V
94ps      1.089V     1.062V     919.3mV
115ps     914.5mV    1.059V     694.8mV
131ps     769mV      987.5mV    605.4mV
152ps     636.3mV    834mV      552.5mV
187ps     542.3mV    637mV      525.8mV
227ps     513.5mV    539.4mV    520.1mV
284ps     505.8mV    503.2mV    519.1mV
419ps     504.6mV    495.3mV    519mV
[Rising Waveform]
R_fixture   = 50
V_fixture   = 1.1
V_fixture_min = 1.06
V_fixture_max = 1.17
|   Time   V(typ)   V(min)   V(max)
0s        504.5mV    495mV      518.9mV
57ps      501.5mV    490.8mV    530.9mV
65ps      510mV      488.9mV    580.4mV
79ps      584.9mV    504.9mV    747mV
95ps      737.1mV    596.3mV    889.2mV
113ps     862.5mV    741mV      991.9mV
133ps     951.8mV    854.7mV    1.063V
155ps     1.012V     933.9mV    1.109V
227ps     1.084V     1.035V     1.16V
419ps     1.1V       1.06V      1.17V
[Falling Waveform]
R_fixture = 50
V_fixture = 0.0
|   Time   V(typ)   V(min)   V(max)
0s        230.5mV    229.8mV    245.8mV
59ps      233.3mV    230.9mV    244.2mV
69ps      232.9mV    233.6mV    220.3mV
77ps      225.7mV    234.5mV    169mV
97ps      153.1mV    214.3mV    58.05mV
112ps     77.49mV    171.3mV    26.07mV
128ps     35.34mV    106.7mV    11.27mV
152ps     10.93mV    37.63mV    3.308mV
186ps     2.349mV    8.126mV    707.4uV
419ps     238.4uV    228.8uV    153.4uV
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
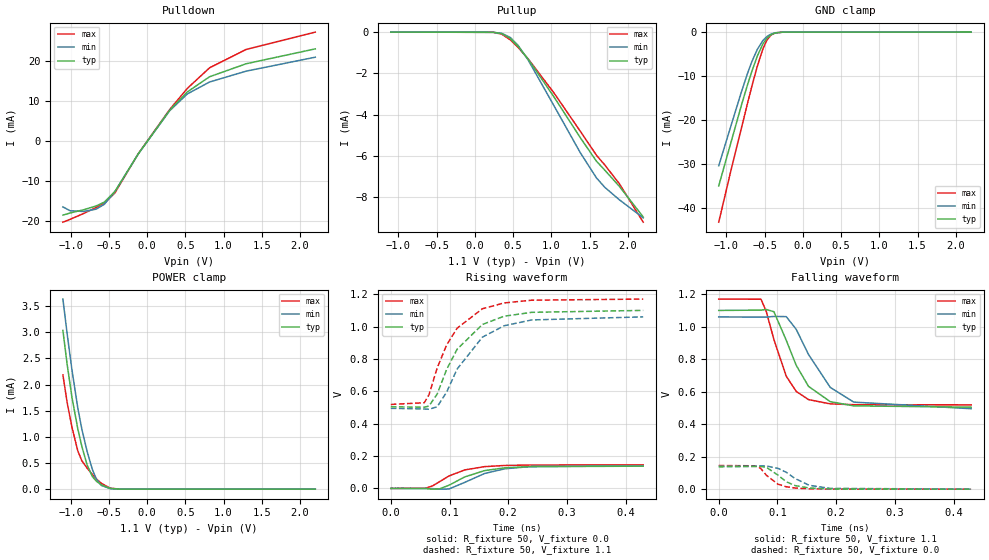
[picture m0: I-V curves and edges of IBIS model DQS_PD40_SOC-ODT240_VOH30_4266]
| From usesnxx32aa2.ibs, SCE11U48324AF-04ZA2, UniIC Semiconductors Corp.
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| DQS_PD40_SOC-ODT240_VOH30_4266
| (40 Ohm Pulldown, 240 Ohm System ODT Setting, VOH=VDDQ/3.0, 3200-4266Mbps)
[Model]   DQS_PD40_SOC-ODT240_VOH30_4266
Model_type   I/O
Vinl = 123.333mV
Vinh = 243.333mV
Vmeas = 183.333mV
Vref = 0.0mV
Cref = 0.0pF
Rref = 240.000Ohm
|   typ   min   max
|C_comp   0.838pF   0.788pF   0.888pF
C_comp_pullup   0.4190pF   0.3940pF   0.4440pF
C_comp_pulldown   0.4190pF   0.3940pF   0.4440pF
| Note: C_comp changes when the ODT circuit is enabled.
[Model Spec]
| Input threshold voltage corners
Vinl   0.1233V   0.1167V   0.1350V
Vinh   0.2433V   0.2367V   0.2550V
| Measurement voltage corners
Vmeas   0.1833V   0.1767V   0.1950V
| Timing spec test load voltage corners
Vref   0.0000V   0.0000V   0.0000V
| Dynamic Overshoot Parameters from LPDDR4 Specification
D_overshoot_ampl_h   0.30   NA   NA
D_overshoot_ampl_l   0.30   NA   NA
D_overshoot_area_h   0.1n   NA   NA
D_overshoot_area_l   0.1n   NA   NA
[Receiver Thresholds]
Vcross_low   = 123.3mV
Vcross_high  = 243.3mV
Vdiff_ac   = 120mV
Vdiff_dc   = 120mV
Tdiffslew_ac = 10.000ns |Not specified, so set to high value
[Voltage Range]   1.1000V   1.0600V   1.1700V
[Pullup Reference]   1.1000V   1.0600V   1.1700V
| Junction Temperature (Ambient temp is 35C typ 95C min -40C max)
[Temperature Range]   50.0   110.0   -40.0
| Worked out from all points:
|   slope of the pulldown table from 0 to 0.165 V, typ, clamps not added: 37 ohm
|   slope of the pullup table from 0 to 0.165 V, typ, clamps not added: 80.5 kohm
|   GND clamp passes 1 mA (typ) near -0.45 V on its own axis
|   POWER clamp passes 1 mA (typ) near -0.88 V on its own axis
|   rising waveform, R_fixture 50, V_fixture 0.0: 20-80 % time 56.7ps typ, 59.3ps min, 50.3ps max; typ from 0 V to 0.138 V
|   falling waveform, R_fixture 50, V_fixture 1.1: 20-80 % time 46.6ps typ, 58.2ps min, 36.7ps max; typ from 1.1 V to 0.505 V
|   rising waveform, R_fixture 50, V_fixture 1.1: 20-80 % time 59.3ps typ, 64ps min, 54.6ps max; typ from 0.505 V to 1.1 V
|   falling waveform, R_fixture 50, V_fixture 0.0: 20-80 % time 31.3ps typ, 39.3ps min, 27.4ps max; typ from 0.138 V to 0 V
[Pulldown]
|   Voltage   I(typ)   I(min)   I(max)
-1.1V     -18.63mA   -16.57mA   -20.4mA
-1.004V   -18.09mA   -17.55mA   -19.67mA
-829.4mV  -17.29mA   -17.71mA   -18.23mA
-667.7mV  -16.35mA   -17.15mA   -16.75mA
-558.8mV  -15.38mA   -15.93mA   -15.59mA
-420.2mV  -12.71mA   -12.75mA   -13.08mA
-113.3mV  -3.258mA   -3.277mA   -3.214mA
295.9mV   7.634mA    7.504mA    7.817mA
526.9mV   12.23mA    11.72mA    13.11mA
817.3mV   16.02mA    14.71mA    18.26mA
1.296V    19.28mA    17.43mA    22.86mA
2.2V      23.01mA    20.92mA    27.21mA
[GND Clamp]
|   Voltage   I(typ)   I(min)   I(max)
-1.1V     -34.88mA   -30.33mA   -43.13mA
-938.3mV  -24.92mA   -21.15mA   -31.24mA
-803mV    -16.57mA   -13.55mA   -21.76mA
-727.1mV  -12.16mA   -9.546mA   -16.41mA
-667.7mV  -8.939mA   -6.742mA   -12.34mA
-595.1mV  -5.415mA   -3.908mA   -7.721mA
-522.5mV  -2.672mA   -1.906mA   -3.823mA
-469.7mV  -1.36mA    -991.6uA   -1.79mA
-413.6mV  -565.6uA   -417.5uA   -621.3uA
-357.5mV  -191.4uA   -145.5uA   -173.5uA
-258.5mV  -16.16uA   -14.27uA   -9.827uA
2.2V      0A         0A         0A
[Pullup]
|   Voltage   I(typ)   I(min)   I(max)
-1.1V     1.047uA    1.615uA    471.8nA
239.8mV   -9.276uA   -9.187uA   -9.966uA
352mV     -74.44uA   -61.05uA   -102.7uA
464.2mV   -314.6uA   -264uA     -380.9uA
563.2mV   -685.4uA   -637.7uA   -737.4uA
698.5mV   -1.328mA   -1.371mA   -1.312mA
1.032V    -3.138mA   -3.566mA   -2.945mA
1.378V    -5.127mA   -5.857mA   -4.815mA
1.589V    -6.266mA   -7.078mA   -5.978mA
1.698V    -6.702mA   -7.534mA   -6.451mA
1.887V    -7.482mA   -8.134mA   -7.355mA
2.2V      -8.971mA   -9.016mA   -9.226mA
[POWER Clamp]
|   Voltage   I(typ)   I(min)   I(max)
-1.1V     3.036mA    3.636mA    2.186mA
-1.044V   2.383mA    2.969mA    1.654mA
-981.2mV  1.754mA    2.277mA    1.183mA
-905.3mV  1.155mA    1.554mA    732.6uA
-852.5mV  818.5uA    1.149mA    544uA
-783.2mV  462.1uA    720.1uA    402.5uA
-713.9mV  239.2uA    373.1uA    278.6uA
-661.1mV  151.1uA    187.6uA    195.5uA
-598.4mV  83.66uA    71.97uA    113.1uA
-482.9mV  15.72uA    9.5uA      19.49uA
-360.8mV  1.024uA    770.9nA    797nA
2.2V      0A         0A         0A
[Ramp]
|   typ   min   max
| 20% - 80%
dV/dt_r   82.52m/56.71p   84.30m/59.34p   87.29m/50.32p
dV/dt_f   357.20m/46.58p   338.86m/58.15p   390.61m/36.74p
| 25% - 75%
|dV/dt_r   68.77m/45.18p   70.25m/47.27p   72.74m/39.91p
|dV/dt_f   297.67m/37.16p   282.38m/46.49p   325.51m/29.25p
R_load = 50
[Rising Waveform]
R_fixture = 50
V_fixture = 0.0
|   Time   V(typ)   V(min)   V(max)
0s        58.08uV    26.64uV    44.12uV
59ps      -1.076mV   285.2uV    1.147mV
71ps      -4.588mV   -1.351mV   15.3mV
83ps      -2.763mV   -4.249mV   41.49mV
99ps      19.56mV    -3.516mV   76.8mV
126ps     71.21mV    37.47mV    114.4mV
160ps     110.3mV    92.66mV    134.7mV
194ps     127.2mV    121.1mV    141.8mV
237ps     134.6mV    134.8mV    144.6mV
430ps     137.6mV    140.5mV    145.5mV
[Falling Waveform]
R_fixture   = 50
V_fixture   = 1.1
V_fixture_min = 1.06
V_fixture_max = 1.17
|   Time   V(typ)   V(min)   V(max)
0s        1.1V       1.06V      1.17V
72ps      1.102V     1.059V     1.169V
81ps      1.106V     1.059V     1.093V
94ps      1.092V     1.063V     921.2mV
115ps     916.8mV    1.062V     695.6mV
132ps     762.4mV    983.7mV    601.9mV
153ps     632.5mV    828.8mV    551.2mV
190ps     538.6mV    626.3mV    525mV
230ps     512.7mV    535.9mV    520mV
430ps     504.6mV    495.2mV    519mV
[Rising Waveform]
R_fixture   = 50
V_fixture   = 1.1
V_fixture_min = 1.06
V_fixture_max = 1.17
|   Time   V(typ)   V(min)   V(max)
0s        504.5mV    495mV      518.9mV
57ps      501.5mV    490.9mV    529.5mV
65ps      509.3mV    489mV      578.2mV
79ps      582.8mV    504.5mV    743.8mV
95ps      734.5mV    594.4mV    886mV
113ps     860.2mV    737.8mV    990mV
156ps     1.013V     934.6mV    1.11V
193ps     1.064V     1.005V     1.146V
240ps     1.088V     1.041V     1.163V
430ps     1.1V       1.06V      1.17V
[Falling Waveform]
R_fixture = 50
V_fixture = 0.0
|   Time   V(typ)   V(min)   V(max)
0s        137.7mV    140.6mV    145.5mV
62ps      139.5mV    142mV      143.9mV
71ps      139.6mV    143.1mV    129.9mV
81ps      135.2mV    142.7mV    86.24mV
101ps     86.21mV    128.2mV    30.58mV
115ps     45.77mV    104.2mV    14.88mV
130ps     22.36mV    65.8mV     6.888mV
154ps     7.217mV    23.89mV    2.076mV
190ps     1.449mV    5.023mV    405.9uV
430ps     131.8uV    129.9uV    79.65uV
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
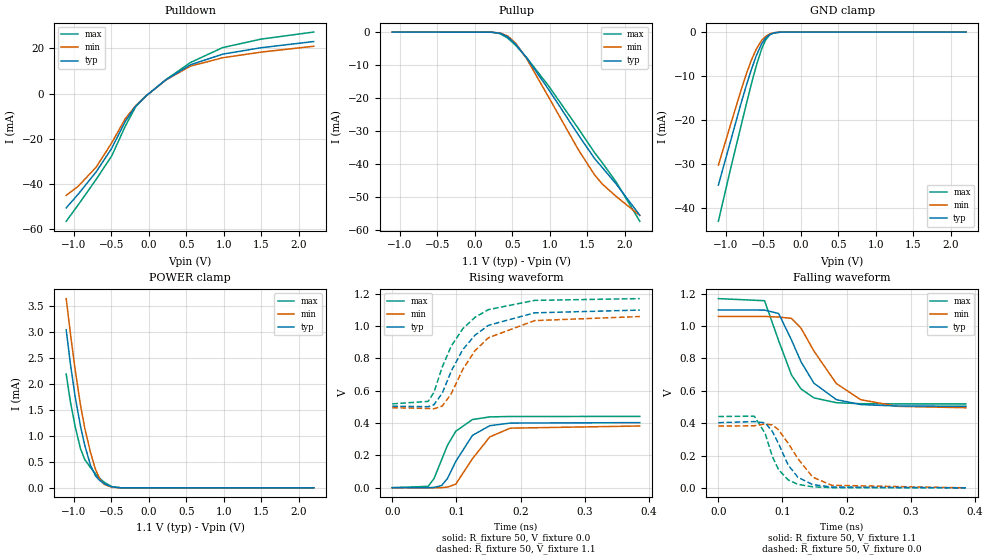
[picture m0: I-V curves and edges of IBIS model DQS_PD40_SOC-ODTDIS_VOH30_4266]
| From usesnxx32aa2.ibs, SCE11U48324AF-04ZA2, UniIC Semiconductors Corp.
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| DQS_PD40_SOC-ODTDIS_VOH30_4266
| (40 Ohm Pulldown, SOC ODT disabled setting, VOH=VDDQ/3.0 cal. point, 3200-4266Mbps)
[Model]   DQS_PD40_SOC-ODTDIS_VOH30_4266
Model_type   I/O
Vinl = 123.333mV
Vinh = 243.333mV
Vmeas = 183.333mV
Vref = 0.0mV
Cref = 0.0pF
|   typ   min   max
|C_comp   0.838pF   0.788pF   0.888pF
C_comp_pullup   0.4190pF   0.3940pF   0.4440pF
C_comp_pulldown   0.4190pF   0.3940pF   0.4440pF
| Note: C_comp changes when the ODT circuit is enabled.
[Model Spec]
| Input threshold voltage corners
Vinl   0.1233V   0.1167V   0.1350V
Vinh   0.2433V   0.2367V   0.2550V
| Measurement voltage corners
Vmeas   0.1833V   0.1767V   0.1950V
| Timing spec test load voltage corners
Vref   0.0000V   0.0000V   0.0000V
| Dynamic Overshoot Parameters from LPDDR4 Specification
D_overshoot_ampl_h   0.30   NA   NA
D_overshoot_ampl_l   0.30   NA   NA
D_overshoot_area_h   0.1n   NA   NA
D_overshoot_area_l   0.1n   NA   NA
[Receiver Thresholds]
Vcross_low   = 123.3mV
Vcross_high  = 243.3mV
Vdiff_ac   = 120mV
Vdiff_dc   = 120mV
Tdiffslew_ac = 10.000ns |Not specified, so set to high value
[Voltage Range]   1.1000V   1.0600V   1.1700V
[Pullup Reference]   1.1000V   1.0600V   1.1700V
| Junction Temperature (Ambient temp is 35C typ 95C min -40C max)
[Temperature Range]   50.0   110.0   -40.0
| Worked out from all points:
|   slope of the pulldown table from 0 to 0.165 V, typ, clamps not added: 36.9 ohm
|   slope of the pullup table from 0 to 0.165 V, typ, clamps not added: 13 kohm
|   GND clamp passes 1 mA (typ) near -0.45 V on its own axis
|   POWER clamp passes 1 mA (typ) near -0.88 V on its own axis
|   rising waveform, R_fixture 50, V_fixture 0.0: 20-80 % time 35.3ps typ, 39.1ps min, 30.9ps max; typ from 0.001 V to 0.403 V
|   falling waveform, R_fixture 50, V_fixture 1.1: 20-80 % time 47.2ps typ, 59ps min, 37.1ps max; typ from 1.1 V to 0.505 V
|   rising waveform, R_fixture 50, V_fixture 1.1: 20-80 % time 58.2ps typ, 61.4ps min, 54.2ps max; typ from 0.505 V to 1.1 V
|   falling waveform, R_fixture 50, V_fixture 0.0: 20-80 % time 32ps typ, 40.2ps min, 26.8ps max; typ from 0.403 V to 0.001 V
[Pulldown]
|   Voltage   I(typ)   I(min)   I(max)
-1.1V     -50.62mA   -45.08mA   -56.55mA
-938.3mV  -44.49mA   -41mA      -49.2mA
-700.7mV  -34.69mA   -32.61mA   -38.03mA
-492.8mV  -24.23mA   -21.84mA   -27.6mA
-314.6mV  -12.49mA   -11.27mA   -14.6mA
-172.7mV  -5.499mA   -5.344mA   -5.806mA
-44mV     -1.312mA   -1.304mA   -1.289mA
229.9mV   6.075mA    5.999mA    6.158mA
556.6mV   12.72mA    12.13mA    13.72mA
985.6mV   17.41mA    15.82mA    20.32mA
1.497V    20.26mA    18.32mA    24.07mA
2.2V      23.01mA    20.92mA    27.21mA
[GND Clamp]
|   Voltage   I(typ)   I(min)   I(max)
-1.1V     -34.88mA   -30.34mA   -43.13mA
-935mV    -24.71mA   -20.97mA   -31mA
-799.7mV  -16.37mA   -13.37mA   -21.52mA
-730.4mV  -12.35mA   -9.712mA   -16.64mA
-661.1mV  -8.597mA   -6.455mA   -11.9mA
-591.8mV  -5.271mA   -3.798mA   -7.524mA
-522.5mV  -2.671mA   -1.905mA   -3.824mA
-469.7mV  -1.359mA   -993.7uA   -1.79mA
-413.6mV  -565uA     -419uA     -621.3uA
-357.5mV  -191.7uA   -146uA     -173.7uA
-265.1mV  -19.39uA   -17.02uA   -12.35uA
2.2V      0A         0A         0A
[Pullup]
|   Voltage   I(typ)   I(min)   I(max)
-1.1V     6.284uA    9.684uA    2.832uA
226.6mV   -42.01uA   -43.23uA   -42.77uA
338.8mV   -360.8uA   -300.3uA   -496.4uA
437.8mV   -1.438mA   -1.181mA   -1.809mA
543.4mV   -3.636mA   -3.318mA   -3.984mA
688.6mV   -7.724mA   -7.945mA   -7.651mA
985.6mV   -17.42mA   -19.73mA   -16.35mA
1.378V    -31.03mA   -35.51mA   -29.11mA
1.596V    -38.25mA   -43.2mA    -36.46mA
1.698V    -40.96mA   -45.96mA   -39.5mA
1.887V    -46.05mA   -49.8mA    -45.45mA
2.2V      -55.46mA   -55.5mA    -57.28mA
[POWER Clamp]
|   Voltage   I(typ)   I(min)   I(max)
-1.1V     3.036mA    3.636mA    2.186mA
-1.044V   2.383mA    2.969mA    1.654mA
-981.2mV  1.754mA    2.277mA    1.183mA
-908.6mV  1.178mA    1.583mA    748.5uA
-852.5mV  818.6uA    1.149mA    543.6uA
-776.6mV  434.2uA    683.6uA    390.2uA
-710.6mV  232.3uA    359.1uA    273.1uA
-651.2mV  138.6uA    162.3uA    181.2uA
-591.8mV  77.92uA    64.88uA    105.5uA
-492.8mV  18.91uA    11.57uA    24.03uA
-377.3mV  1.489uA    1.071uA    1.229uA
2.2V      0A         0A         0A
[Ramp]
|   typ   min   max
| 20% - 80%
dV/dt_r   241.38m/35.31p   228.93m/39.10p   264.47m/30.86p
dV/dt_f   357.20m/47.15p   338.68m/58.98p   390.62m/37.17p
| 25% - 75%
|dV/dt_r   201.15m/28.12p   190.77m/31.16p   220.39m/24.50p
|dV/dt_f   297.67m/37.61p   282.23m/47.10p   325.52m/29.59p
R_load = 50
[Rising Waveform]
R_fixture = 50
V_fixture = 0.0
|   Time   V(typ)   V(min)   V(max)
0s        552.8uV    474.5uV    400.4uV
56ps      258.6uV    77.34uV    8.735mV
65ps      2.198mV    -528.4uV   56mV
77ps      13.87mV    932.1uV    173.7mV
86ps      57.05mV    3.892mV    261.7mV
99ps      162.8mV    21.92mV    349.5mV
125ps     323.9mV    179.7mV    421.9mV
152ps     383.9mV    314.4mV    438.2mV
184ps     400.1mV    368.6mV    440.9mV
386ps     402.9mV    382mV      441.2mV
[Falling Waveform]
R_fixture   = 50
V_fixture   = 1.1
V_fixture_min = 1.06
V_fixture_max = 1.17
|   Time   V(typ)   V(min)   V(max)
0s        1.1V       1.06V      1.17V
72ps      1.099V     1.06V      1.157V
94ps      1.078V     1.056V     910.1mV
114ps     914.3mV    1.048V     698.2mV
129ps     778.6mV    987mV      611.4mV
149ps     647.3mV    846mV      556.5mV
184ps     545.6mV    644.9mV    526.6mV
222ps     515.1mV    545.1mV    520.4mV
279ps     506mV      504.2mV    519.1mV
386ps     504.7mV    495.5mV    519mV
[Rising Waveform]
R_fixture   = 50
V_fixture   = 1.1
V_fixture_min = 1.06
V_fixture_max = 1.17
|   Time   V(typ)   V(min)   V(max)
0s        504.5mV    495.1mV    518.9mV
56ps      501.5mV    490.5mV    534.3mV
65ps      513.6mV    488.4mV    590.6mV
78ps      585.4mV    505.4mV    747.2mV
92ps      722.1mV    582.1mV    876.9mV
110ps     854.7mV    732.8mV    984.1mV
129ps     943.7mV    848.1mV    1.054V
150ps     1.005V     928.1mV    1.102V
222ps     1.082V     1.034V     1.159V
386ps     1.099V     1.059V     1.17V
[Falling Waveform]
R_fixture = 50
V_fixture = 0.0
|   Time   V(typ)   V(min)   V(max)
0s        403mV      382.2mV    441.3mV
56ps      409.9mV    383.9mV    443.3mV
73ps      402mV      395mV      336.2mV
84ps      350mV      389.3mV    195.9mV
94ps      271.9mV    358.5mV    112.1mV
109ps     140.4mV    275mV      49.05mV
124ps     65.67mV    181.5mV    21.9mV
147ps     20.62mV    66.94mV    6.654mV
177ps     5.121mV    16.1mV     1.719mV
386ps     607.7uV    554.5uV    426.3uV
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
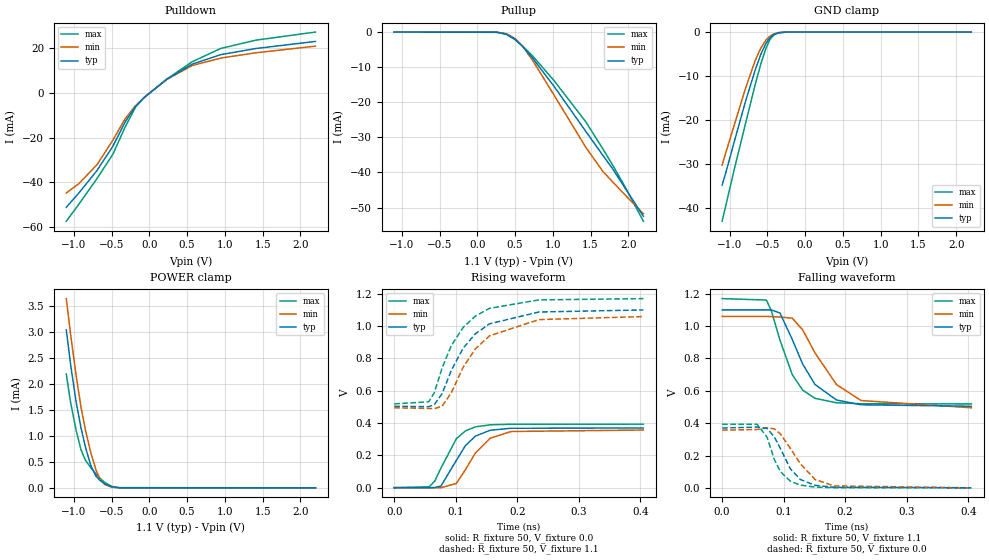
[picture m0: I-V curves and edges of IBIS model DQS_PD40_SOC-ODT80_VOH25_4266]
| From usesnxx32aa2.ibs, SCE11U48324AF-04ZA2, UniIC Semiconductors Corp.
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| DQS_PD40_SOC-ODT80_VOH25_4266
| (40 Ohm Pulldown, 80 Ohm System ODT Setting, VOH=VDDQ/2.5, 3200-4266Mbps)
[Model]   DQS_PD40_SOC-ODT80_VOH25_4266
Model_type   I/O
Vinl = 160.000mV
Vinh = 280.000mV
Vmeas = 220.000mV
Vref = 0.0mV
Cref = 0.0pF
Rref = 80.000Ohm
|   typ   min   max
|C_comp   0.838pF   0.788pF   0.888pF
C_comp_pullup   0.4190pF   0.3940pF   0.4440pF
C_comp_pulldown   0.4190pF   0.3940pF   0.4440pF
| Note: C_comp changes when the ODT circuit is enabled.
[Model Spec]
| Input threshold voltage corners
Vinl   0.1600V   0.1520V   0.1740V
Vinh   0.2800V   0.2720V   0.2940V
| Measurement voltage corners
Vmeas   0.2200V   0.2120V   0.2340V
| Timing spec test load voltage corners
Vref   0.0000V   0.0000V   0.0000V
| Dynamic Overshoot Parameters from LPDDR4 Specification
D_overshoot_ampl_h   0.30   NA   NA
D_overshoot_ampl_l   0.30   NA   NA
D_overshoot_area_h   0.1n   NA   NA
D_overshoot_area_l   0.1n   NA   NA
[Receiver Thresholds]
Vcross_low   = 160.0mV
Vcross_high  = 280.0mV
Vdiff_ac   = 120mV
Vdiff_dc   = 120mV
Tdiffslew_ac = 10.000ns |Not specified, so set to high value
[Voltage Range]   1.1000V   1.0600V   1.1700V
[Pullup Reference]   1.1000V   1.0600V   1.1700V
| Junction Temperature (Ambient temp is 35C typ 95C min -40C max)
[Temperature Range]   50.0   110.0   -40.0
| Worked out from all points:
|   slope of the pulldown table from 0 to 0.165 V, typ, clamps not added: 36.9 ohm
|   slope of the pullup table from 0 to 0.165 V, typ, clamps not added: 17.5 kohm
|   GND clamp passes 1 mA (typ) near -0.45 V on its own axis
|   POWER clamp passes 1 mA (typ) near -0.88 V on its own axis
|   rising waveform, R_fixture 50, V_fixture 0.0: 20-80 % time 35.5ps typ, 38.8ps min, 32.5ps max; typ from 0.001 V to 0.37 V
|   falling waveform, R_fixture 50, V_fixture 1.1: 20-80 % time 47ps typ, 59ps min, 37ps max; typ from 1.1 V to 0.505 V
|   rising waveform, R_fixture 50, V_fixture 1.1: 20-80 % time 58.7ps typ, 62.1ps min, 54.2ps max; typ from 0.505 V to 1.1 V
|   falling waveform, R_fixture 50, V_fixture 0.0: 20-80 % time 32.2ps typ, 40.3ps min, 26.2ps max; typ from 0.37 V to 0.001 V
[Pulldown]
|   Voltage   I(typ)   I(min)   I(max)
-1.1V     -51.08mA   -44.67mA   -57.33mA
-935mV    -44.77mA   -40.55mA   -49.76mA
-694.1mV  -34.69mA   -32.1mA    -38.29mA
-482.9mV  -23.8mA    -21.1mA    -27.39mA
-321.2mV  -12.98mA   -11.57mA   -15.28mA
-182.6mV  -5.895mA   -5.674mA   -6.313mA
-63.8mV   -1.905mA   -1.887mA   -1.882mA
229.9mV   6.074mA    5.998mA    6.158mA
566.5mV   12.87mA    12.26mA    13.92mA
949.3mV   17.14mA    15.6mA     19.93mA
1.411V    19.86mA    17.95mA    23.58mA
2.2V      23.01mA    20.92mA    27.21mA
[GND Clamp]
|   Voltage   I(typ)   I(min)   I(max)
-1.1V     -34.89mA   -30.33mA   -43.14mA
-1.05V    -32mA      -27.43mA   -39.48mA
-938.3mV  -24.93mA   -21.15mA   -31.25mA
-789.8mV  -15.79mA   -12.83mA   -20.84mA
-661.1mV  -8.6mA     -6.453mA   -11.91mA
-588.5mV  -5.13mA    -3.689mA   -7.336mA
-519.2mV  -2.574mA   -1.836mA   -3.676mA
-466.4mV  -1.298mA   -944.6uA   -1.695mA
-413.6mV  -568.2uA   -418.6uA   -621.4uA
-354.2mV  -178.5uA   -135.2uA   -160.3uA
-251.9mV  -13.31uA   -11.94uA   -7.942uA
2.2V      0A         0A         0A
[Pullup]
|   Voltage   I(typ)   I(min)   I(max)
-1.1V     4.112uA    7.441uA    1.363uA
259.6mV   -60.68uA   -59.84uA   -61.42uA
385mV     -550uA     -457uA     -658uA
500.5mV   -2.042mA   -1.832mA   -2.144mA
602.8mV   -4.15mA    -4.129mA   -4.001mA
738.1mV   -7.554mA   -8.212mA   -6.91mA
1.022V    -15.61mA   -18.14mA   -13.97mA
1.438V    -28.31mA   -32.85mA   -25.59mA
1.665V    -35.16mA   -39.75mA   -33.34mA
1.794V    -39mA      -42.7mA    -37.92mA
1.956V    -44.42mA   -46.36mA   -44.02mA
2.2V      -52.46mA   -51.74mA   -53.91mA
[POWER Clamp]
|   Voltage   I(typ)   I(min)   I(max)
-1.1V     3.036mA    3.636mA    2.186mA
-1.041V   2.347mA    2.931mA    1.626mA
-968mV    1.637mA    2.141mA    1.095mA
-905.3mV  1.155mA    1.555mA    732.4uA
-845.9mV  780.3uA    1.104mA    527.6uA
-773.3mV  421uA      665.6uA    384.1uA
-704mV    219uA      332uA      262.2uA
-647.9mV  134.6uA    154.5uA    176.6uA
-591.8mV  77.94uA    64.82uA    105.5uA
-496.1mV  20.16uA    12.38uA    25.75uA
-397.1mV  2.407uA    1.595uA    2.12uA
2.2V      0A         0A         0A
[Ramp]
|   typ   min   max
| 20% - 80%
dV/dt_r   221.58m/35.46p   213.94m/38.84p   235.64m/32.51p
dV/dt_f   357.21m/47.03p   338.76m/59.02p   390.62m/37.03p
| 25% - 75%
|dV/dt_r   184.65m/28.23p   178.28m/30.96p   196.37m/25.80p
|dV/dt_f   297.68m/37.52p   282.30m/47.13p   325.52m/29.47p
R_load = 50
[Rising Waveform]
R_fixture = 50
V_fixture = 0.0
|   Time   V(typ)   V(min)   V(max)
0s        573.8uV    458.3uV    421.6uV
57ps      300.3uV    93.59uV    6.125mV
66ps      1.634mV    -515.4uV   41.65mV
76ps      10.39mV    236.5uV    121.8mV
101ps     169.2mV    26.74mV    303.1mV
116ps     261.9mV    113mV      352.2mV
132ps     319.3mV    214.6mV    376.7mV
156ps     355.7mV    306.4mV    389.4mV
190ps     368mV      348mV      392.8mV
405ps     369.9mV    357mV      393.2mV
[Falling Waveform]
R_fixture   = 50
V_fixture   = 1.1
V_fixture_min = 1.06
V_fixture_max = 1.17
|   Time   V(typ)   V(min)   V(max)
0s        1.1V       1.06V      1.17V
72ps      1.1V       1.06V      1.161V
80ps      1.1V       1.059V     1.095V
94ps      1.081V     1.056V     913.8mV
114ps     917.7mV    1.049V     700mV
131ps     764.9mV    976.6mV    604.1mV
151ps     638.9mV    834.1mV    553.6mV
186ps     543.1mV    638.3mV    526.1mV
226ps     513.8mV    539.9mV    520.1mV
405ps     504.6mV    495.4mV    519mV
[Rising Waveform]
R_fixture   = 50
V_fixture   = 1.1
V_fixture_min = 1.06
V_fixture_max = 1.17
|   Time   V(typ)   V(min)   V(max)
0s        504.5mV    495.1mV    518.9mV
56ps      501.5mV    490.6mV    531.6mV
65ps      512.8mV    488.5mV    586.3mV
78ps      583mV      504.9mV    742.2mV
93ps      727.5mV    588.8mV    880.4mV
112ps     863.1mV    745.3mV    991.3mV
132ps     952.6mV    859.3mV    1.062V
155ps     1.014V     939.8mV    1.11V
235ps     1.087V     1.04V      1.162V
405ps     1.1V       1.059V     1.17V
[Falling Waveform]
R_fixture = 50
V_fixture = 0.0
|   Time   V(typ)   V(min)   V(max)
0s        370mV      357.1mV    393.2mV
57ps      375.8mV    360.9mV    393.1mV
73ps      368mV      371.6mV    313.8mV
85ps      314.9mV    364.7mV    173.7mV
95ps      241.2mV    331.9mV    99.38mV
111ps     117.4mV    243.9mV    41.3mV
127ps     52.46mV    150mV      17.5mV
151ps     15.89mV    51.83mV    5.16mV
182ps     3.944mV    12.44mV    1.388mV
405ps     624.2uV    532.9uV    447.3uV
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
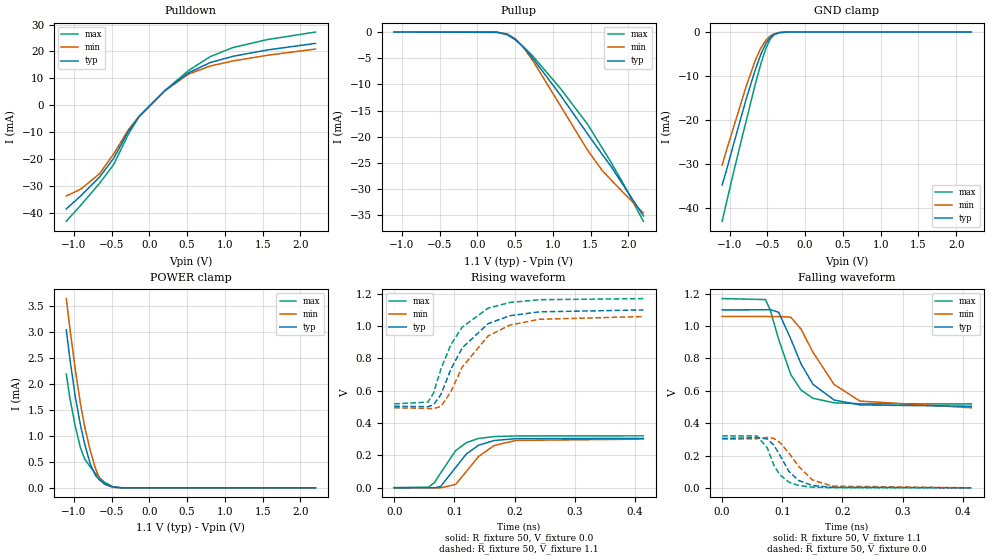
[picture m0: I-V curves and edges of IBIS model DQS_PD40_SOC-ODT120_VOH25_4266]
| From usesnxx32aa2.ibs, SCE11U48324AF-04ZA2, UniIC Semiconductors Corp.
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| DQS_PD40_SOC-ODT120_VOH25_4266
| (40 Ohm Pulldown, 120 Ohm System ODT Setting, VOH=VDDQ/2.5, 3200-4266Mbps)
[Model]   DQS_PD40_SOC-ODT120_VOH25_4266
Model_type   I/O
Vinl = 160.000mV
Vinh = 280.000mV
Vmeas = 220.000mV
Vref = 0.0mV
Cref = 0.0pF
Rref = 120.000Ohm
|   typ   min   max
|C_comp   0.838pF   0.788pF   0.888pF
C_comp_pullup   0.4190pF   0.3940pF   0.4440pF
C_comp_pulldown   0.4190pF   0.3940pF   0.4440pF
| Note: C_comp changes when the ODT circuit is enabled.
[Model Spec]
| Input threshold voltage corners
Vinl   0.1600V   0.1520V   0.1740V
Vinh   0.2800V   0.2720V   0.2940V
| Measurement voltage corners
Vmeas   0.2200V   0.2120V   0.2340V
| Timing spec test load voltage corners
Vref   0.0000V   0.0000V   0.0000V
| Dynamic Overshoot Parameters from LPDDR4 Specification
D_overshoot_ampl_h   0.30   NA   NA
D_overshoot_ampl_l   0.30   NA   NA
D_overshoot_area_h   0.1n   NA   NA
D_overshoot_area_l   0.1n   NA   NA
[Receiver Thresholds]
Vcross_low   = 160.0mV
Vcross_high  = 280.0mV
Vdiff_ac   = 120mV
Vdiff_dc   = 120mV
Tdiffslew_ac = 10.000ns |Not specified, so set to high value
[Voltage Range]   1.1000V   1.0600V   1.1700V
[Pullup Reference]   1.1000V   1.0600V   1.1700V
| Junction Temperature (Ambient temp is 35C typ 95C min -40C max)
[Temperature Range]   50.0   110.0   -40.0
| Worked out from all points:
|   slope of the pulldown table from 0 to 0.165 V, typ, clamps not added: 36.9 ohm
|   slope of the pullup table from 0 to 0.165 V, typ, clamps not added: 26.5 kohm
|   GND clamp passes 1 mA (typ) near -0.45 V on its own axis
|   POWER clamp passes 1 mA (typ) near -0.88 V on its own axis
|   rising waveform, R_fixture 50, V_fixture 0.0: 20-80 % time 40.6ps typ, 43.8ps min, 37.3ps max; typ from 0 V to 0.306 V
|   falling waveform, R_fixture 50, V_fixture 1.1: 20-80 % time 46.8ps typ, 58.7ps min, 36.9ps max; typ from 1.1 V to 0.505 V
|   rising waveform, R_fixture 50, V_fixture 1.1: 20-80 % time 59ps typ, 62.9ps min, 54.2ps max; typ from 0.505 V to 1.1 V
|   falling waveform, R_fixture 50, V_fixture 0.0: 20-80 % time 31.6ps typ, 39.9ps min, 26.1ps max; typ from 0.306 V to 0 V
[Pulldown]
|   Voltage   I(typ)   I(min)   I(max)
-1.1V     -38.36mA   -33.55mA   -42.94mA
-908.6mV  -33.54mA   -31.02mA   -37mA
-661.1mV  -26.62mA   -25.34mA   -28.93mA
-473mV    -19.6mA    -18.02mA   -21.92mA
-278.3mV  -9.59mA    -9.008mA   -10.68mA
-136.4mV  -4.103mA   -4.06mA    -4.148mA
206.8mV   5.507mA    5.446mA    5.565mA
517mV     12.06mA    11.58mA    12.9mA
807.4mV   15.92mA    14.64mA    18.12mA
1.111V    18.24mA    16.52mA    21.49mA
1.566V    20.58mA    18.61mA    24.44mA
2.2V      23.01mA    20.92mA    27.21mA
[GND Clamp]
|   Voltage   I(typ)   I(min)   I(max)
-1.1V     -34.88mA   -30.33mA   -43.14mA
-1.047V   -31.8mA    -27.25mA   -39.23mA
-941.6mV  -25.14mA   -21.33mA   -31.48mA
-786.5mV  -15.6mA    -12.65mA   -20.6mA
-661.1mV  -8.601mA   -6.453mA   -11.91mA
-588.5mV  -5.129mA   -3.689mA   -7.334mA
-519.2mV  -2.572mA   -1.836mA   -3.674mA
-463.1mV  -1.235mA   -899.6uA   -1.601mA
-413.6mV  -564.8uA   -417.1uA   -621.3uA
-344.3mV  -143.8uA   -109.5uA   -124.4uA
-238.7mV  -9.08uA    -8.383uA   -5.005uA
2.2V      0A         0A         0A
[Pullup]
|   Voltage   I(typ)   I(min)   I(max)
-1.1V     2.741uA    4.961uA    908.6nA
266.2mV   -46.36uA   -44.63uA   -47.92uA
398.2mV   -442uA     -366.7uA   -523.5uA
507.1mV   -1.445mA   -1.306mA   -1.506mA
606.1mV   -2.831mA   -2.827mA   -2.721mA
741.4mV   -5.122mA   -5.585mA   -4.678mA
1.098V    -11.99mA   -14.01mA   -10.72mA
1.461V    -19.48mA   -22.58mA   -17.63mA
1.655V    -23.39mA   -26.48mA   -22.16mA
1.771V    -25.67mA   -28.25mA   -24.89mA
1.933V    -29.26mA   -30.67mA   -28.95mA
2.2V      -35.14mA   -34.59mA   -36.18mA
[POWER Clamp]
|   Voltage   I(typ)   I(min)   I(max)
-1.1V     3.036mA    3.636mA    2.186mA
-1.054V   2.493mA    3.085mA    1.737mA
-981.2mV  1.754mA    2.277mA    1.183mA
-911.9mV  1.201mA    1.612mA    764.9uA
-855.8mV  837.9uA    1.172mA    552.3uA
-783.2mV  462uA      720.1uA    402.5uA
-713.9mV  239.3uA    373.1uA    278.6uA
-657.8mV  146.8uA    178.9uA    190.7uA
-595.1mV  80.8uA     68.31uA    109.2uA
-486.2mV  16.73uA    10.16uA    20.95uA
-367.4mV  1.185uA    872.9nA    944.8nA
2.2V      0A         0A         0A
[Ramp]
|   typ   min   max
| 20% - 80%
dV/dt_r   183.27m/40.61p   180.36m/43.75p   192.52m/37.30p
dV/dt_f   357.21m/46.82p   338.80m/58.67p   390.62m/36.90p
| 25% - 75%
|dV/dt_r   152.72m/32.33p   150.30m/34.89p   160.43m/29.65p
|dV/dt_f   297.68m/37.36p   282.33m/46.85p   325.51m/29.37p
R_load = 50
[Rising Waveform]
R_fixture = 50
V_fixture = 0.0
|   Time   V(typ)   V(min)   V(max)
0s        371.2uV    287.2uV    273.4uV
57ps      49.31uV    212uV      3.503mV
67ps      22.33uV    -443.6uV   32.38mV
77ps      7.047mV    -489.5uV   90.6mV
102ps     125mV      20.02mV    229.5mV
120ps     209.5mV    101.1mV    279.5mV
140ps     262.8mV    193.2mV    304.8mV
166ps     292.3mV    261.1mV    316.6mV
202ps     303.5mV    292.8mV    320.4mV
414ps     305.8mV    300.9mV    321.1mV
[Falling Waveform]
R_fixture   = 50
V_fixture   = 1.1
V_fixture_min = 1.06
V_fixture_max = 1.17
|   Time   V(typ)   V(min)   V(max)
0s        1.1V       1.06V      1.17V
72ps      1.101V     1.06V      1.164V
80ps      1.102V     1.059V     1.099V
94ps      1.085V     1.059V     916.9mV
114ps     921.2mV    1.055V     701.3mV
131ps     767.2mV    982.2mV    604.8mV
151ps     640.1mV    837.9mV    553.9mV
186ps     543.4mV    639.7mV    526.1mV
229ps     512.9mV    536.4mV    520mV
414ps     504.6mV    495.3mV    519mV
[Rising Waveform]
R_fixture   = 50
V_fixture   = 1.1
V_fixture_min = 1.06
V_fixture_max = 1.17
|   Time   V(typ)   V(min)   V(max)
0s        504.5mV    495.1mV    518.9mV
56ps      501.5mV    490.8mV    529.7mV
65ps      511.6mV    488.8mV    582.9mV
78ps      579.6mV    504mV      738.3mV
94ps      732mV      593mV      884.1mV
113ps     865.2mV    746.5mV    993.5mV
156ps     1.015V     939.2mV    1.111V
192ps     1.064V     1.006V     1.146V
241ps     1.088V     1.042V     1.163V
414ps     1.1V       1.059V     1.17V
[Falling Waveform]
R_fixture = 50
V_fixture = 0.0
|   Time   V(typ)   V(min)   V(max)
0s        305.9mV    301mV      321.2mV
58ps      310.3mV    304.3mV    321mV
75ps      302.2mV    311.9mV    247.2mV
86ps      264.3mV    305.7mV    139.8mV
96ps      202.1mV    280.4mV    80.31mV
111ps     102.2mV    215.2mV    35.5mV
127ps     46.06mV    133.7mV    15.1mV
150ps     14.71mV    48.97mV    4.669mV
183ps     3.288mV    10.85mV    1.094mV
414ps     439.5uV    382.5uV    307.1uV
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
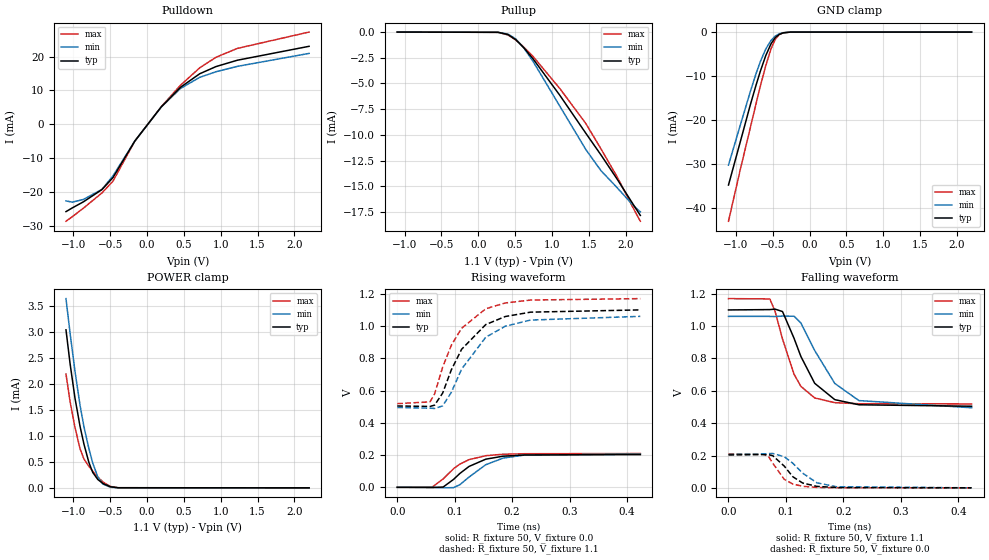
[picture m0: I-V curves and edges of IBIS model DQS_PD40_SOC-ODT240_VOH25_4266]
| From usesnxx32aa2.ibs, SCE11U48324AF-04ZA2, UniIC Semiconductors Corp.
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| DQS_PD40_SOC-ODT240_VOH25_4266
| (40 Ohm Pulldown, 240 Ohm System ODT Setting, VOH=VDDQ/2.5, 3200-4266Mbps)
[Model]   DQS_PD40_SOC-ODT240_VOH25_4266
Model_type   I/O
Vinl = 160.000mV
Vinh = 280.000mV
Vmeas = 220.000mV
Vref = 0.0mV
Cref = 0.0pF
Rref = 240.000Ohm
|   typ   min   max
|C_comp   0.838pF   0.788pF   0.888pF
C_comp_pullup   0.4190pF   0.3940pF   0.4440pF
C_comp_pulldown   0.4190pF   0.3940pF   0.4440pF
| Note: C_comp changes when the ODT circuit is enabled.
[Model Spec]
| Input threshold voltage corners
Vinl   0.1600V   0.1520V   0.1740V
Vinh   0.2800V   0.2720V   0.2940V
| Measurement voltage corners
Vmeas   0.2200V   0.2120V   0.2340V
| Timing spec test load voltage corners
Vref   0.0000V   0.0000V   0.0000V
| Dynamic Overshoot Parameters from LPDDR4 Specification
D_overshoot_ampl_h   0.30   NA   NA
D_overshoot_ampl_l   0.30   NA   NA
D_overshoot_area_h   0.1n   NA   NA
D_overshoot_area_l   0.1n   NA   NA
[Receiver Thresholds]
Vcross_low   = 160.0mV
Vcross_high  = 280.0mV
Vdiff_ac   = 120mV
Vdiff_dc   = 120mV
Tdiffslew_ac = 10.000ns |Not specified, so set to high value
[Voltage Range]   1.1000V   1.0600V   1.1700V
[Pullup Reference]   1.1000V   1.0600V   1.1700V
| Junction Temperature (Ambient temp is 35C typ 95C min -40C max)
[Temperature Range]   50.0   110.0   -40.0
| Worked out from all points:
|   slope of the pulldown table from 0 to 0.165 V, typ, clamps not added: 37 ohm
|   slope of the pullup table from 0 to 0.165 V, typ, clamps not added: 54 kohm
|   GND clamp passes 1 mA (typ) near -0.45 V on its own axis
|   POWER clamp passes 1 mA (typ) near -0.88 V on its own axis
|   rising waveform, R_fixture 50, V_fixture 0.0: 20-80 % time 48.1ps typ, 51.8ps min, 44.7ps max; typ from 0 V to 0.203 V
|   falling waveform, R_fixture 50, V_fixture 1.1: 20-80 % time 46.6ps typ, 58.3ps min, 36.8ps max; typ from 1.1 V to 0.505 V
|   rising waveform, R_fixture 50, V_fixture 1.1: 20-80 % time 59.2ps typ, 63.7ps min, 54.5ps max; typ from 0.505 V to 1.1 V
|   falling waveform, R_fixture 50, V_fixture 0.0: 20-80 % time 31.5ps typ, 40ps min, 26.4ps max; typ from 0.203 V to 0 V
[Pulldown]
|   Voltage   I(typ)   I(min)   I(max)
-1.1V     -25.68mA   -22.53mA   -28.52mA
-1.014V   -24.58mA   -22.89mA   -27.17mA
-862.4mV  -22.78mA   -22.08mA   -24.64mA
-611.6mV  -19.18mA   -19.12mA   -20.17mA
-463.1mV  -15.68mA   -15.18mA   -16.74mA
-166.1mV  -4.908mA   -4.896mA   -4.943mA
193.6mV   5.178mA    5.123mA    5.223mA
454.3mV   10.94mA    10.59mA    11.54mA
715mV     14.92mA    13.87mA    16.67mA
936.1mV   17.04mA    15.52mA    19.78mA
1.226V    18.91mA    17.1mA     22.39mA
2.2V      23.01mA    20.92mA    27.21mA
[GND Clamp]
|   Voltage   I(typ)   I(min)   I(max)
-1.1V     -34.88mA   -30.33mA   -43.14mA
-941.6mV  -25.14mA   -21.33mA   -31.48mA
-803mV    -16.57mA   -13.55mA   -21.77mA
-727.1mV  -12.17mA   -9.543mA   -16.42mA
-667.7mV  -8.943mA   -6.74mA    -12.35mA
-595.1mV  -5.418mA   -3.907mA   -7.728mA
-522.5mV  -2.673mA   -1.908mA   -3.826mA
-466.4mV  -1.297mA   -945.2uA   -1.694mA
-413.6mV  -565.7uA   -419.4uA   -621.5uA
-357.5mV  -191.6uA   -144.1uA   -173.8uA
-261.8mV  -17.63uA   -15.46uA   -10.98uA
2.2V      0A         0A         0A
[Pullup]
|   Voltage   I(typ)   I(min)   I(max)
-1.1V     1.371uA    2.481uA    454.5nA
269.5mV   -24.65uA   -23.68uA   -25.92uA
404.8mV   -242.8uA   -201.7uA   -285.4uA
510.4mV   -747.7uA   -678.3uA   -775.9uA
622.6mV   -1.56mA    -1.582mA   -1.483mA
748mV     -2.647mA   -2.903mA   -2.409mA
1.108V    -6.162mA   -7.223mA   -5.503mA
1.461V    -9.856mA   -11.44mA   -8.909mA
1.665V    -11.95mA   -13.48mA   -11.36mA
1.887V    -14.33mA   -15.16mA   -14.11mA
2.114V    -16.89mA   -16.95mA   -17.27mA
2.2V      -17.84mA   -17.49mA   -18.41mA
[POWER Clamp]
|   Voltage   I(typ)   I(min)   I(max)
-1.1V     3.036mA    3.636mA    2.186mA
-1.044V   2.383mA    2.969mA    1.654mA
-977.9mV  1.724mA    2.242mA    1.161mA
-908.6mV  1.178mA    1.582mA    748.4uA
-855.8mV  838uA      1.172mA    552.9uA
-789.8mV  491.1uA    757.2uA    414.8uA
-737mV    296.6uA    478.4uA    318.4uA
-667.7mV  159.9uA    206.1uA    205.2uA
-598.4mV  83.65uA    71.98uA    113.1uA
-499.4mV  21.31uA    13.18uA    27.45uA
-393.8mV  2.21uA     1.495uA    1.93uA
2.2V      0A         0A         0A
[Ramp]
|   typ   min   max
| 20% - 80%
dV/dt_r   121.84m/48.12p   124.19m/51.77p   125.61m/44.66p
dV/dt_f   357.21m/46.62p   338.82m/58.28p   390.61m/36.78p
| 25% - 75%
|dV/dt_r   101.54m/38.32p   103.49m/41.35p   104.68m/35.49p
|dV/dt_f   297.68m/37.19p   282.35m/46.57p   325.51m/29.27p
R_load = 50
[Rising Waveform]
R_fixture = 50
V_fixture = 0.0
|   Time   V(typ)   V(min)   V(max)
0s        167uV      114uV      125uV
61ps      -1.276mV   53.32uV    1.788mV
80ps      2.067mV    -2.998mV   52.33mV
98ps      49.37mV    -1.656mV   115.9mV
109ps     86.27mV    16.64mV    144.2mV
125ps     129.7mV    63.83mV    171.8mV
154ps     174.6mV    140.2mV    196.2mV
184ps     193.1mV    181.2mV    205.1mV
221ps     200.6mV    200mV      208.4mV
423ps     203.2mV    207.1mV    209.5mV
[Falling Waveform]
R_fixture   = 50
V_fixture   = 1.1
V_fixture_min = 1.06
V_fixture_max = 1.17
|   Time   V(typ)   V(min)   V(max)
0s        1.1V       1.06V      1.17V
72ps      1.102V     1.06V      1.168V
81ps      1.105V     1.059V     1.092V
94ps      1.09V      1.062V     920.4mV
114ps     925.4mV    1.061V     703.1mV
126ps     812.2mV    1.019V     627.4mV
150ps     646.4mV    849.3mV    555.8mV
185ps     545.3mV    645.4mV    526.6mV
227ps     513.6mV    539.5mV    520.1mV
423ps     504.6mV    495.3mV    519mV
[Rising Waveform]
R_fixture   = 50
V_fixture   = 1.1
V_fixture_min = 1.06
V_fixture_max = 1.17
|   Time   V(typ)   V(min)   V(max)
0s        504.5mV    495mV      518.9mV
57ps      501.5mV    490.8mV    529.8mV
65ps      509.7mV    488.9mV    579mV
79ps      584mV      504.8mV    744.7mV
94ps      727.4mV    587.9mV    879.9mV
112ps     855.9mV    733.1mV    986.2mV
154ps     1.009V     930.3mV    1.107V
188ps     1.059V     999mV      1.143V
232ps     1.086V     1.037V     1.161V
423ps     1.1V       1.06V      1.17V
[Falling Waveform]
R_fixture = 50
V_fixture = 0.0
|   Time   V(typ)   V(min)   V(max)
0s        203.3mV    207.2mV    209.5mV
61ps      205.6mV    209.6mV    208.1mV
70ps      204.9mV    212mV      191.9mV
77ps      199.1mV    212.7mV    152.6mV
97ps      134.6mV    192.6mV    52.62mV
112ps     68.63mV    152mV      23.73mV
129ps     30.03mV    91.02mV    9.758mV
154ps     9.005mV    30.88mV    2.756mV
188ps     1.995mV    6.839mV    622.1uV
423ps     240.7uV    218uV      159.4uV
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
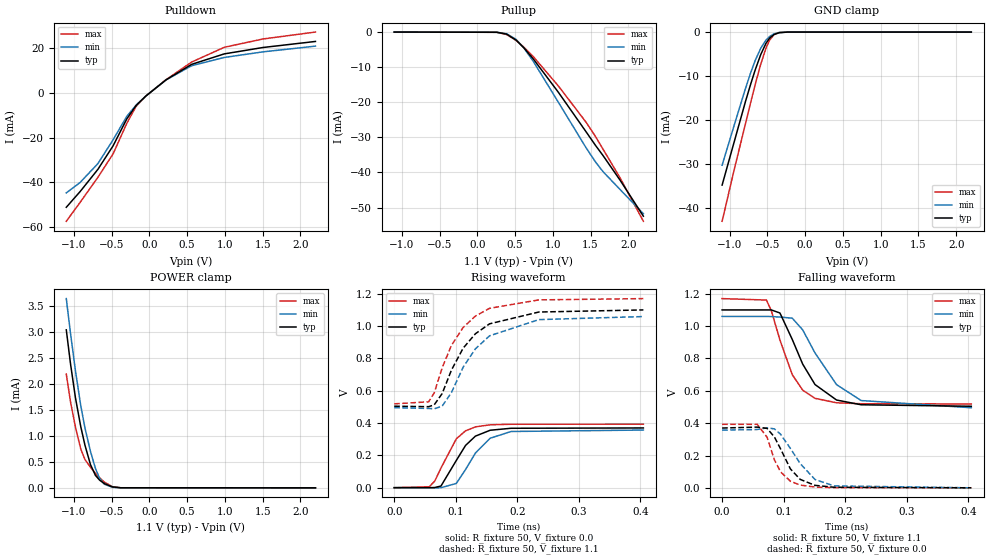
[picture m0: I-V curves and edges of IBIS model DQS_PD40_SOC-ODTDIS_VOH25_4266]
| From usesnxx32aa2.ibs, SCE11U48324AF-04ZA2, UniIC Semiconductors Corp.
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| DQS_PD40_SOC-ODTDIS_VOH25_4266
| (40 Ohm Pulldown, SOC ODT disabled setting, VOH=VDDQ/2.5 cal. point, 3200-4266Mbps)
[Model]   DQS_PD40_SOC-ODTDIS_VOH25_4266
Model_type   I/O
Vinl = 160.000mV
Vinh = 280.000mV
Vmeas = 220.000mV
Vref = 0.0mV
Cref = 0.0pF
|   typ   min   max
|C_comp   0.838pF   0.788pF   0.888pF
C_comp_pullup   0.4190pF   0.3940pF   0.4440pF
C_comp_pulldown   0.4190pF   0.3940pF   0.4440pF
| Note: C_comp changes when the ODT circuit is enabled.
[Model Spec]
| Input threshold voltage corners
Vinl   0.1600V   0.1520V   0.1740V
Vinh   0.2800V   0.2720V   0.2940V
| Measurement voltage corners
Vmeas   0.2200V   0.2120V   0.2340V
| Timing spec test load voltage corners
Vref   0.0000V   0.0000V   0.0000V
| Dynamic Overshoot Parameters from LPDDR4 Specification
D_overshoot_ampl_h   0.30   NA   NA
D_overshoot_ampl_l   0.30   NA   NA
D_overshoot_area_h   0.1n   NA   NA
D_overshoot_area_l   0.1n   NA   NA
[Receiver Thresholds]
Vcross_low   = 160.0mV
Vcross_high  = 280.0mV
Vdiff_ac   = 120mV
Vdiff_dc   = 120mV
Tdiffslew_ac = 10.000ns |Not specified, so set to high value
[Voltage Range]   1.1000V   1.0600V   1.1700V
[Pullup Reference]   1.1000V   1.0600V   1.1700V
| Junction Temperature (Ambient temp is 35C typ 95C min -40C max)
[Temperature Range]   50.0   110.0   -40.0
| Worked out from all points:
|   slope of the pulldown table from 0 to 0.165 V, typ, clamps not added: 36.8 ohm
|   slope of the pullup table from 0 to 0.165 V, typ, clamps not added: 17.4 kohm
|   GND clamp passes 1 mA (typ) near -0.45 V on its own axis
|   POWER clamp passes 1 mA (typ) near -0.88 V on its own axis
|   rising waveform, R_fixture 50, V_fixture 0.0: 20-80 % time 35.5ps typ, 38.8ps min, 32.5ps max; typ from 0.001 V to 0.37 V
|   falling waveform, R_fixture 50, V_fixture 1.1: 20-80 % time 47ps typ, 59ps min, 37ps max; typ from 1.1 V to 0.505 V
|   rising waveform, R_fixture 50, V_fixture 1.1: 20-80 % time 58.7ps typ, 62.1ps min, 54.2ps max; typ from 0.505 V to 1.1 V
|   falling waveform, R_fixture 50, V_fixture 0.0: 20-80 % time 32.2ps typ, 40.3ps min, 26.2ps max; typ from 0.37 V to 0.001 V
[Pulldown]
|   Voltage   I(typ)   I(min)   I(max)
-1.1V     -51.08mA   -44.66mA   -57.33mA
-915.2mV  -43.99mA   -39.94mA   -48.81mA
-680.9mV  -34.11mA   -31.54mA   -37.67mA
-479.6mV  -23.59mA   -20.9mA    -27.18mA
-298.1mV  -11.57mA   -10.41mA   -13.54mA
-176mV    -5.64mA    -5.443mA   -5.998mA
-44mV     -1.314mA   -1.301mA   -1.292mA
223.3mV   5.913mA    5.841mA    5.989mA
559.9mV   12.77mA    12.17mA    13.79mA
992.2mV   17.45mA    15.86mA    20.39mA
1.504V    20.3mA     18.35mA    24.11mA
2.2V      23.01mA    20.92mA    27.21mA
[GND Clamp]
|   Voltage   I(typ)   I(min)   I(max)
-1.1V     -34.89mA   -30.35mA   -43.14mA
-935mV    -24.72mA   -20.96mA   -31.01mA
-789.8mV  -15.79mA   -12.83mA   -20.84mA
-720.5mV  -11.8mA    -9.214mA   -15.96mA
-661.1mV  -8.6mA     -6.453mA   -11.91mA
-588.5mV  -5.13mA    -3.689mA   -7.335mA
-519.2mV  -2.573mA   -1.839mA   -3.674mA
-469.7mV  -1.36mA    -990.4uA   -1.791mA
-413.6mV  -566.5uA   -417.1uA   -622.6uA
-344.3mV  -143.9uA   -110.1uA   -124.3uA
-228.8mV  -6.701uA   -6.589uA   -3.536uA
2.2V      0A         0A         0A
[Pullup]
|   Voltage   I(typ)   I(min)   I(max)
-1.1V     4.112uA    7.441uA    1.363uA
259.6mV   -60.43uA   -59.44uA   -61.41uA
388.3mV   -575.6uA   -478.1uA   -688.8uA
513.7mV   -2.281mA   -2.075mA   -2.361mA
616mV     -4.459mA   -4.485mA   -4.266mA
744.7mV   -7.731mA   -8.43mA    -7.062mA
1.075V    -17.18mA   -20.03mA   -15.38mA
1.441V    -28.41mA   -32.96mA   -25.69mA
1.566V    -32.29mA   -37.01mA   -29.76mA
1.665V    -35.16mA   -39.75mA   -33.34mA
1.89V     -42.15mA   -44.83mA   -41.48mA
2.2V      -52.46mA   -51.75mA   -53.91mA
[POWER Clamp]
|   Voltage   I(typ)   I(min)   I(max)
-1.1V     3.036mA    3.636mA    2.186mA
-1.044V   2.383mA    2.969mA    1.654mA
-977.9mV  1.724mA    2.242mA    1.161mA
-908.6mV  1.178mA    1.583mA    748.4uA
-852.5mV  818.5uA    1.149mA    543.8uA
-779.9mV  448uA      701.8uA    396.3uA
-713.9mV  239.2uA    373.1uA    278.6uA
-657.8mV  146.8uA    178.8uA    190.7uA
-595.1mV  80.75uA    68.31uA    109.2uA
-489.5mV  17.8uA     10.88uA    22.46uA
-380.6mV  1.613uA    1.129uA    1.341uA
2.2V      0A         0A         0A
[Ramp]
|   typ   min   max
| 20% - 80%
dV/dt_r   221.58m/35.46p   213.94m/38.84p   235.64m/32.51p
dV/dt_f   357.21m/47.03p   338.76m/59.02p   390.62m/37.03p
| 25% - 75%
|dV/dt_r   184.65m/28.23p   178.28m/30.96p   196.37m/25.80p
|dV/dt_f   297.68m/37.52p   282.30m/47.13p   325.52m/29.47p
R_load = 50
[Rising Waveform]
R_fixture = 50
V_fixture = 0.0
|   Time   V(typ)   V(min)   V(max)
0s        573.8uV    458.3uV    421.6uV
57ps      300.3uV    93.59uV    6.125mV
66ps      1.634mV    -515.4uV   41.65mV
76ps      10.39mV    236.5uV    121.8mV
101ps     169.2mV    26.74mV    303.1mV
116ps     261.9mV    113mV      352.2mV
132ps     319.3mV    214.6mV    376.7mV
156ps     355.7mV    306.4mV    389.4mV
190ps     368mV      348mV      392.8mV
405ps     369.9mV    357mV      393.2mV
[Falling Waveform]
R_fixture   = 50
V_fixture   = 1.1
V_fixture_min = 1.06
V_fixture_max = 1.17
|   Time   V(typ)   V(min)   V(max)
0s        1.1V       1.06V      1.17V
72ps      1.1V       1.06V      1.161V
80ps      1.1V       1.059V     1.095V
94ps      1.081V     1.056V     913.8mV
114ps     917.7mV    1.049V     700mV
131ps     764.9mV    976.6mV    604.1mV
151ps     638.9mV    834.1mV    553.6mV
186ps     543.1mV    638.3mV    526.1mV
226ps     513.8mV    539.9mV    520.1mV
405ps     504.6mV    495.4mV    519mV
[Rising Waveform]
R_fixture   = 50
V_fixture   = 1.1
V_fixture_min = 1.06
V_fixture_max = 1.17
|   Time   V(typ)   V(min)   V(max)
0s        504.5mV    495.1mV    518.9mV
56ps      501.5mV    490.6mV    531.6mV
65ps      512.8mV    488.5mV    586.3mV
78ps      583mV      504.9mV    742.2mV
93ps      727.5mV    588.8mV    880.4mV
112ps     863.1mV    745.3mV    991.3mV
132ps     952.6mV    859.3mV    1.062V
155ps     1.014V     939.8mV    1.11V
235ps     1.087V     1.04V      1.162V
405ps     1.1V       1.059V     1.17V
[Falling Waveform]
R_fixture = 50
V_fixture = 0.0
|   Time   V(typ)   V(min)   V(max)
0s        370mV      357.1mV    393.2mV
57ps      375.8mV    360.9mV    393.1mV
73ps      368mV      371.6mV    313.8mV
85ps      314.9mV    364.7mV    173.7mV
95ps      241.2mV    331.9mV    99.38mV
111ps     117.4mV    243.9mV    41.3mV
127ps     52.46mV    150mV      17.5mV
151ps     15.89mV    51.83mV    5.16mV
182ps     3.944mV    12.44mV    1.388mV
405ps     624.2uV    532.9uV    447.3uV
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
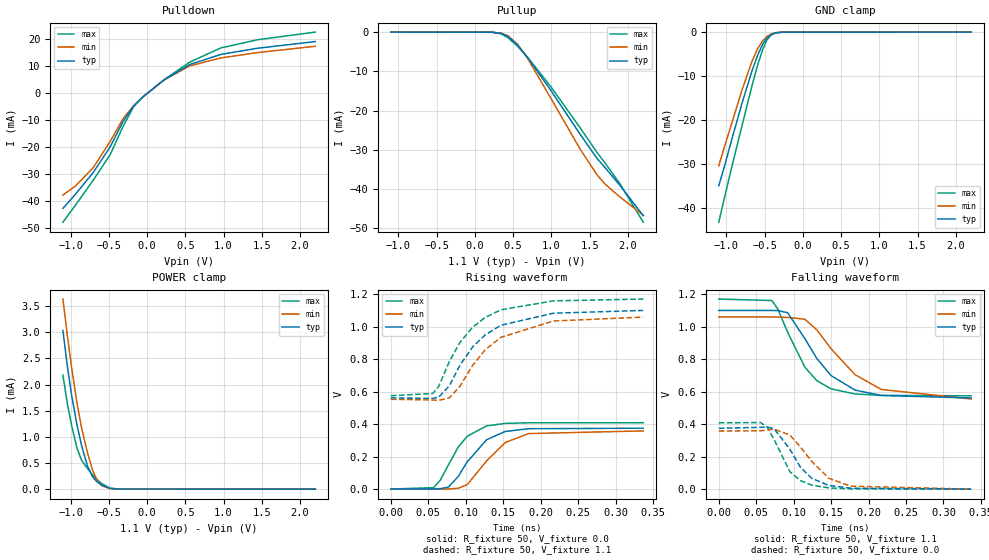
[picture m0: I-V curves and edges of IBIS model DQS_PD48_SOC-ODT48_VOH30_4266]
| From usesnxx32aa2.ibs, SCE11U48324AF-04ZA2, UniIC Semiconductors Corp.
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| DQS_PD48_SOC-ODT48_VOH30_4266
| (48 Ohm Pulldown, 48 Ohm System ODT Setting, VOH=VDDQ/3.0, 3200-4266Mbps)
[Model]   DQS_PD48_SOC-ODT48_VOH30_4266
Model_type   I/O
Vinl = 123.333mV
Vinh = 243.333mV
Vmeas = 183.333mV
Vref = 0.0mV
Cref = 0.0pF
Rref = 48.000Ohm
|   typ   min   max
|C_comp   0.838pF   0.788pF   0.888pF
C_comp_pullup   0.4190pF   0.3940pF   0.4440pF
C_comp_pulldown   0.4190pF   0.3940pF   0.4440pF
| Note: C_comp changes when the ODT circuit is enabled.
[Model Spec]
| Input threshold voltage corners
Vinl   0.1233V   0.1167V   0.1350V
Vinh   0.2433V   0.2367V   0.2550V
| Measurement voltage corners
Vmeas   0.1833V   0.1767V   0.1950V
| Timing spec test load voltage corners
Vref   0.0000V   0.0000V   0.0000V
| Dynamic Overshoot Parameters from LPDDR4 Specification
D_overshoot_ampl_h   0.30   NA   NA
D_overshoot_ampl_l   0.30   NA   NA
D_overshoot_area_h   0.1n   NA   NA
D_overshoot_area_l   0.1n   NA   NA
[Receiver Thresholds]
Vcross_low   = 123.3mV
Vcross_high  = 243.3mV
Vdiff_ac   = 120mV
Vdiff_dc   = 120mV
Tdiffslew_ac = 10.000ns |Not specified, so set to high value
[Voltage Range]   1.1000V   1.0600V   1.1700V
[Pullup Reference]   1.1000V   1.0600V   1.1700V
| Junction Temperature (Ambient temp is 35C typ 95C min -40C max)
[Temperature Range]   50.0   110.0   -40.0
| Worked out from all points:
|   slope of the pulldown table from 0 to 0.165 V, typ, clamps not added: 43.8 ohm
|   slope of the pullup table from 0 to 0.165 V, typ, clamps not added: 15.5 kohm
|   GND clamp passes 1 mA (typ) near -0.45 V on its own axis
|   POWER clamp passes 1 mA (typ) near -0.88 V on its own axis
|   rising waveform, R_fixture 50, V_fixture 0.0: 20-80 % time 37ps typ, 41.3ps min, 32.8ps max; typ from 0.001 V to 0.375 V
|   falling waveform, R_fixture 50, V_fixture 1.1: 20-80 % time 50.7ps typ, 62.6ps min, 40.5ps max; typ from 1.1 V to 0.562 V
|   rising waveform, R_fixture 50, V_fixture 1.1: 20-80 % time 58.1ps typ, 61ps min, 54.1ps max; typ from 0.561 V to 1.1 V
|   falling waveform, R_fixture 50, V_fixture 0.0: 20-80 % time 33.4ps typ, 41ps min, 28.5ps max; typ from 0.375 V to 0.001 V
[Pulldown]
|   Voltage   I(typ)   I(min)   I(max)
-1.1V     -42.75mA   -37.8mA    -47.88mA
-935mV    -37.48mA   -34.43mA   -41.54mA
-700.7mV  -29.32mA   -27.52mA   -32.18mA
-479.6mV  -19.79mA   -17.77mA   -22.68mA
-317.9mV  -10.72mA   -9.649mA   -12.56mA
-176mV    -4.739mA   -4.594mA   -5.024mA
-53.9mV   -1.352mA   -1.343mA   -1.333mA
223.3mV   4.975mA    4.912mA    5.047mA
556.6mV   10.67mA    10.16mA    11.54mA
965.8mV   14.43mA    13.12mA    16.85mA
1.444V    16.72mA    15.1mA     19.87mA
2.2V      19.2mA     17.45mA    22.72mA
[GND Clamp]
|   Voltage   I(typ)   I(min)   I(max)
-1.1V     -34.88mA   -30.35mA   -43.13mA
-1.027V   -30.57mA   -26.14mA   -37.76mA
-935mV    -24.71mA   -20.97mA   -31mA
-796.4mV  -16.18mA   -13.19mA   -21.29mA
-667.7mV  -8.939mA   -6.743mA   -12.34mA
-591.8mV  -5.271mA   -3.798mA   -7.524mA
-525.8mV  -2.772mA   -1.979mA   -3.977mA
-469.7mV  -1.358mA   -988.1uA   -1.794mA
-416.9mV  -599.8uA   -441.5uA   -666.2uA
-357.5mV  -193.2uA   -144.8uA   -173.4uA
-265.1mV  -19.58uA   -16.71uA   -12.27uA
2.2V      0A         0A         0A
[Pullup]
|   Voltage   I(typ)   I(min)   I(max)
-1.1V     5.237uA    8.07uA     2.361uA
226.6mV   -35.36uA   -35.86uA   -35.66uA
342.1mV   -317.6uA   -262.2uA   -438.6uA
434.5mV   -1.159mA   -947.9uA   -1.466mA
556.6mV   -3.33mA    -3.082mA   -3.598mA
688.6mV   -6.489mA   -6.687mA   -6.42mA
985.6mV   -14.65mA   -16.63mA   -13.73mA
1.375V    -26.01mA   -29.8mA    -24.37mA
1.596V    -32.18mA   -36.36mA   -30.67mA
1.698V    -34.46mA   -38.65mA   -33.26mA
1.893V    -38.98mA   -41.97mA   -38.57mA
2.2V      -46.77mA   -46.63mA   -48.43mA
[POWER Clamp]
|   Voltage   I(typ)   I(min)   I(max)
-1.1V     3.036mA    3.636mA    2.186mA
-1.041V   2.347mA    2.931mA    1.626mA
-984.5mV  1.783mA    2.311mA    1.206mA
-915.2mV  1.224mA    1.64mA     782uA
-855.8mV  838.2uA    1.172mA    552.3uA
-779.9mV  448.1uA    701.7uA    396.3uA
-713.9mV  239.3uA    373.1uA    278.6uA
-657.8mV  146.8uA    178.9uA    190.7uA
-595.1mV  80.79uA    68.3uA     109.3uA
-486.2mV  16.71uA    10.13uA    20.94uA
-367.4mV  1.19uA     875.5nA    943.7nA
2.2V      0A         0A         0A
[Ramp]
|   typ   min   max
| 20% - 80%
dV/dt_r   224.60m/37.00p   214.57m/41.28p   244.89m/32.77p
dV/dt_f   323.03m/50.68p   302.94m/62.56p   357.15m/40.44p
| 25% - 75%
|dV/dt_r   187.17m/29.51p   178.81m/32.92p   204.08m/26.03p
|dV/dt_f   269.19m/40.39p   252.45m/49.97p   297.62m/32.19p
R_load = 50
[Rising Waveform]
R_fixture = 50
V_fixture = 0.0
|   Time   V(typ)   V(min)   V(max)
0s        513.4uV    443uV      371.4uV
57ps      634.7uV    116.5uV    9.18mV
66ps      2.487mV    -179.8uV   54.54mV
77ps      12.65mV    1.081mV    150mV
90ps      77.64mV    5.487mV    258.6mV
102ps     167.7mV    27.42mV    325.2mV
128ps     304.4mV    174.5mV    389mV
153ps     354.9mV    287.2mV    404.4mV
184ps     371.6mV    341.7mV    408mV
337ps     374.8mV    358.1mV    408.5mV
[Falling Waveform]
R_fixture   = 50
V_fixture   = 1.1
V_fixture_min = 1.06
V_fixture_max = 1.17
|   Time   V(typ)   V(min)   V(max)
0s        1.1V       1.06V      1.17V
71ps      1.1V       1.06V      1.161V
79ps      1.099V     1.059V     1.108V
92ps      1.086V     1.057V     965.9mV
115ps     926.5mV    1.046V     751mV
131ps     804.4mV    980.7mV    667.8mV
150ps     699.2mV    863.9mV    617.5mV
182ps     610mV      704.7mV    586.1mV
217ps     576.9mV    613.9mV    577.4mV
337ps     561.6mV    555.1mV    574.8mV
[Rising Waveform]
R_fixture   = 50
V_fixture   = 1.1
V_fixture_min = 1.06
V_fixture_max = 1.17
|   Time   V(typ)   V(min)   V(max)
0s        561.2mV    552.6mV    574.7mV
56ps      557.8mV    548.4mV    588.2mV
64ps      566mV      546.1mV    631.8mV
78ps      634.6mV    560.8mV    783.3mV
92ps      759.2mV    630.7mV    900.5mV
109ps     873.3mV    760mV      994.6mV
126ps     948.6mV    856.8mV    1.056V
147ps     1.008V     933.6mV    1.103V
217ps     1.082V     1.034V     1.158V
337ps     1.099V     1.058V     1.169V
[Falling Waveform]
R_fixture = 50
V_fixture = 0.0
|   Time   V(typ)   V(min)   V(max)
0s        375mV      358.2mV    408.6mV
56ps      380.8mV    359.5mV    410.4mV
65ps      383mV      365mV      380.5mV
74ps      371.5mV    369.4mV    305mV
95ps      246.5mV    333.4mV    107.9mV
109ps     136mV      261mV      53.23mV
124ps     67.52mV    172.1mV    25.24mV
147ps     23.27mV    67.3mV     8.318mV
176ps     6.501mV    18.87mV    2.316mV
337ps     585.8uV    566.7uV    399uV
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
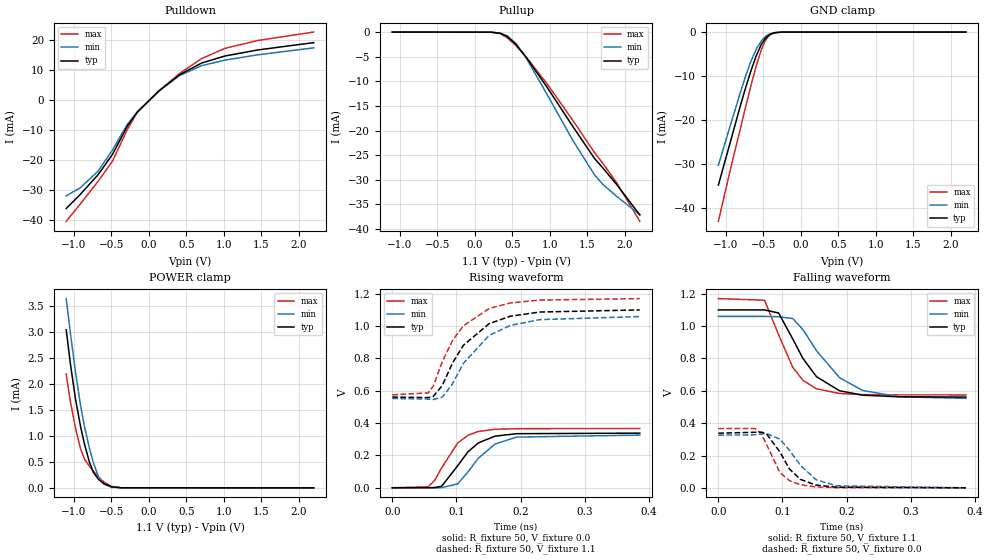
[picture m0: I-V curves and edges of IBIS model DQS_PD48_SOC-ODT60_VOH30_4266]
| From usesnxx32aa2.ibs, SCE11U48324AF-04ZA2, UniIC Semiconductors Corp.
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| DQS_PD48_SOC-ODT60_VOH30_4266
| (48 Ohm Pulldown, 60 Ohm System ODT Setting, VOH=VDDQ/3.0, 3200-4266Mbps)
[Model]   DQS_PD48_SOC-ODT60_VOH30_4266
Model_type   I/O
Vinl = 123.333mV
Vinh = 243.333mV
Vmeas = 183.333mV
Vref = 0.0mV
Cref = 0.0pF
Rref = 60.000Ohm
|   typ   min   max
|C_comp   0.838pF   0.788pF   0.888pF
C_comp_pullup   0.4190pF   0.3940pF   0.4440pF
C_comp_pulldown   0.4190pF   0.3940pF   0.4440pF
| Note: C_comp changes when the ODT circuit is enabled.
[Model Spec]
| Input threshold voltage corners
Vinl   0.1233V   0.1167V   0.1350V
Vinh   0.2433V   0.2367V   0.2550V
| Measurement voltage corners
Vmeas   0.1833V   0.1767V   0.1950V
| Timing spec test load voltage corners
Vref   0.0000V   0.0000V   0.0000V
| Dynamic Overshoot Parameters from LPDDR4 Specification
D_overshoot_ampl_h   0.30   NA   NA
D_overshoot_ampl_l   0.30   NA   NA
D_overshoot_area_h   0.1n   NA   NA
D_overshoot_area_l   0.1n   NA   NA
[Receiver Thresholds]
Vcross_low   = 123.3mV
Vcross_high  = 243.3mV
Vdiff_ac   = 120mV
Vdiff_dc   = 120mV
Tdiffslew_ac = 10.000ns |Not specified, so set to high value
[Voltage Range]   1.1000V   1.0600V   1.1700V
[Pullup Reference]   1.1000V   1.0600V   1.1700V
| Junction Temperature (Ambient temp is 35C typ 95C min -40C max)
[Temperature Range]   50.0   110.0   -40.0
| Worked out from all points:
|   slope of the pulldown table from 0 to 0.165 V, typ, clamps not added: 43.8 ohm
|   slope of the pullup table from 0 to 0.165 V, typ, clamps not added: 19.6 kohm
|   GND clamp passes 1 mA (typ) near -0.45 V on its own axis
|   POWER clamp passes 1 mA (typ) near -0.88 V on its own axis
|   rising waveform, R_fixture 50, V_fixture 0.0: 20-80 % time 40.5ps typ, 44.2ps min, 35.7ps max; typ from 0 V to 0.338 V
|   falling waveform, R_fixture 50, V_fixture 1.1: 20-80 % time 50.6ps typ, 62.7ps min, 40.3ps max; typ from 1.1 V to 0.561 V
|   rising waveform, R_fixture 50, V_fixture 1.1: 20-80 % time 58.7ps typ, 61.9ps min, 54.5ps max; typ from 0.561 V to 1.1 V
|   falling waveform, R_fixture 50, V_fixture 0.0: 20-80 % time 33.1ps typ, 41.1ps min, 28.3ps max; typ from 0.338 V to 0 V
[Pulldown]
|   Voltage   I(typ)   I(min)   I(max)
-1.1V     -36.05mA   -31.84mA   -40.29mA
-915.2mV  -31.42mA   -29.19mA   -34.65mA
-674.3mV  -24.77mA   -23.6mA    -26.97mA
-482.9mV  -18.02mA   -16.53mA   -20.26mA
-288.2mV  -8.747mA   -8.13mA    -9.916mA
-152.9mV  -3.951mA   -3.891mA   -4.057mA
134.2mV   3.076mA    3.052mA    3.086mA
408.1mV   8.436mA    8.203mA    8.84mA
705.1mV   12.4mA     11.52mA    13.87mA
1.015V    14.73mA    13.36mA    17.27mA
1.444V    16.72mA    15.1mA     19.87mA
2.2V      19.2mA     17.45mA    22.72mA
[GND Clamp]
|   Voltage   I(typ)   I(min)   I(max)
-1.1V     -34.88mA   -30.35mA   -43.13mA
-944.9mV  -25.34mA   -21.53mA   -31.71mA
-799.7mV  -16.37mA   -13.37mA   -21.52mA
-727.1mV  -12.16mA   -9.546mA   -16.41mA
-664.4mV  -8.768mA   -6.598mA   -12.12mA
-591.8mV  -5.272mA   -3.798mA   -7.524mA
-525.8mV  -2.773mA   -1.979mA   -3.976mA
-473mV    -1.424mA   -1.034mA   -1.893mA
-416.9mV  -597.8uA   -441.8uA   -667.2uA
-354.2mV  -179uA     -135.6uA   -160.9uA
-255.2mV  -14.63uA   -13.07uA   -8.91uA
2.2V      0A         0A         0A
[Pullup]
|   Voltage   I(typ)   I(min)   I(max)
-1.1V     4.189uA    6.459uA    1.888uA
223.3mV   -26.24uA   -27.36uA   -26.24uA
338.8mV   -240.6uA   -199.3uA   -331.6uA
434.5mV   -926.2uA   -757.2uA   -1.172mA
546.7mV   -2.491mA   -2.282mA   -2.719mA
678.7mV   -4.978mA   -5.096mA   -4.948mA
962.5mV   -11.17mA   -12.63mA   -10.48mA
1.312V    -19.28mA   -22.13mA   -18.05mA
1.596V    -25.66mA   -28.99mA   -24.47mA
1.708V    -27.61mA   -30.94mA   -26.67mA
1.887V    -30.87mA   -33.32mA   -30.49mA
2.2V      -37.14mA   -37.08mA   -38.43mA
[POWER Clamp]
|   Voltage   I(typ)   I(min)   I(max)
-1.1V     3.036mA    3.636mA    2.186mA
-1.044V   2.383mA    2.969mA    1.654mA
-977.9mV  1.724mA    2.242mA    1.161mA
-908.6mV  1.178mA    1.583mA    747.7uA
-855.8mV  838uA      1.172mA    552.1uA
-789.8mV  491.2uA    757.5uA    414.8uA
-737mV    296.6uA    478.5uA    318.4uA
-667.7mV  159.9uA    206.1uA    205.2uA
-598.4mV  83.69uA    71.97uA    113.1uA
-496.1mV  20.06uA    12.37uA    25.78uA
-364.1mV  1.103uA    822.4nA    870.4nA
2.2V      0A         0A         0A
[Ramp]
|   typ   min   max
| 20% - 80%
dV/dt_r   202.62m/40.49p   195.39m/44.19p   219.70m/35.75p
dV/dt_f   323.18m/50.60p   304.00m/62.72p   357.15m/40.33p
| 25% - 75%
|dV/dt_r   168.85m/32.25p   162.82m/35.26p   183.08m/28.39p
|dV/dt_f   269.32m/40.33p   253.33m/50.04p   297.63m/32.11p
R_load = 50
[Rising Waveform]
R_fixture = 50
V_fixture = 0.0
|   Time   V(typ)   V(min)   V(max)
0s        404uV      343.7uV    292.3uV
56ps      466.6uV    200.9uV    6.372mV
66ps      1.671mV    -102.5uV   45.27mV
77ps      9.719mV    790uV      123.4mV
102ps     136.7mV    24.56mV    277.4mV
118ps     222.4mV    98.19mV    324.9mV
134ps     277.2mV    181.8mV    348.1mV
160ps     319.3mV    270.4mV    362mV
194ps     334.7mV    313.7mV    365.8mV
386ps     338.1mV    326mV      366.5mV
[Falling Waveform]
R_fixture   = 50
V_fixture   = 1.1
V_fixture_min = 1.06
V_fixture_max = 1.17
|   Time   V(typ)   V(min)   V(max)
0s        1.1V       1.06V      1.17V
72ps      1.1V       1.06V      1.16V
94ps      1.081V     1.058V     945.6mV
116ps     920.5mV    1.047V     745.2mV
132ps     799.4mV    978mV      664.6mV
153ps     687.5mV    848mV      612.7mV
189ps     600.2mV    681mV      583.3mV
225ps     573.1mV    602.3mV    576.7mV
281ps     563.2mV    563.5mV    574.9mV
386ps     561.4mV    553.3mV    574.7mV
[Rising Waveform]
R_fixture   = 50
V_fixture   = 1.1
V_fixture_min = 1.06
V_fixture_max = 1.17
|   Time   V(typ)   V(min)   V(max)
0s        561.2mV    552.6mV    574.7mV
56ps      557.9mV    548.5mV    587.1mV
64ps      565.5mV    546.2mV    629.7mV
78ps      632.6mV    560.6mV    780.7mV
94ps      772.6mV    643.6mV    911.7mV
111ps     881.6mV    770.5mV    1.002V
151ps     1.015V     942.2mV    1.109V
184ps     1.061V     1.004V     1.143V
230ps     1.087V     1.04V      1.161V
386ps     1.1V       1.059V     1.17V
[Falling Waveform]
R_fixture = 50
V_fixture = 0.0
|   Time   V(typ)   V(min)   V(max)
0s        338.2mV    326.1mV    366.5mV
57ps      343.7mV    328mV      367.3mV
67ps      344.7mV    333.2mV    334.1mV
75ps      334.5mV    336mV      269.4mV
96ps      221.9mV    301.4mV    94.51mV
111ps     116.1mV    231.9mV    44.49mV
128ps     52.6mV     139.2mV    19.21mV
152ps     17.45mV    51.07mV    6.076mV
184ps     4.395mV    12.82mV    1.529mV
386ps     476.4uV    443.9uV    321.9uV
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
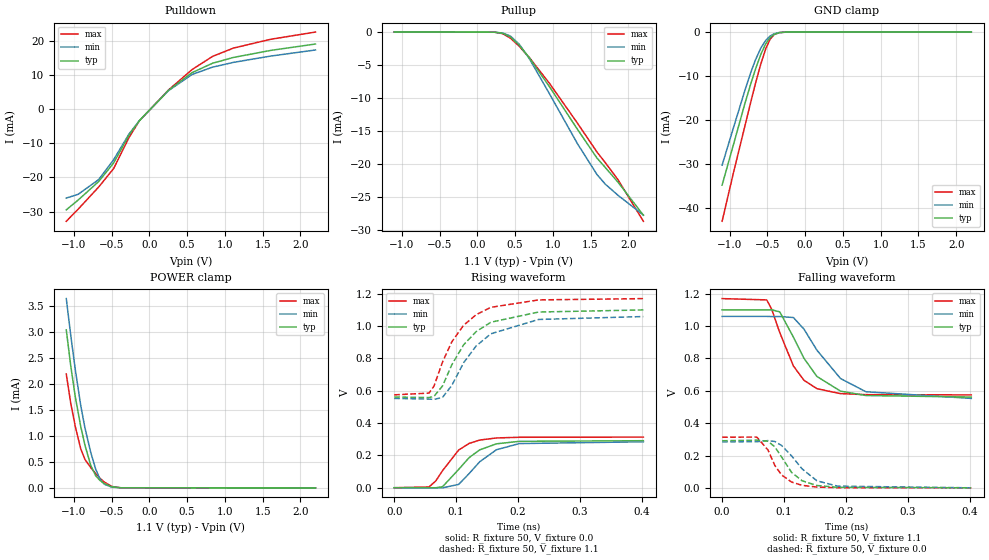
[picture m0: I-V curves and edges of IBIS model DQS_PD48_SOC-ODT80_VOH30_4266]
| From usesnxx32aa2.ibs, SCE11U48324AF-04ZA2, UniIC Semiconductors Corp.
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| DQS_PD48_SOC-ODT80_VOH30_4266
| (48 Ohm Pulldown, 80 Ohm System ODT Setting, VOH=VDDQ/3.0, 3200-4266Mbps)
[Model]   DQS_PD48_SOC-ODT80_VOH30_4266
Model_type   I/O
Vinl = 123.333mV
Vinh = 243.333mV
Vmeas = 183.333mV
Vref = 0.0mV
Cref = 0.0pF
Rref = 80.000Ohm
|   typ   min   max
|C_comp   0.838pF   0.788pF   0.888pF
C_comp_pullup   0.4190pF   0.3940pF   0.4440pF
C_comp_pulldown   0.4190pF   0.3940pF   0.4440pF
| Note: C_comp changes when the ODT circuit is enabled.
[Model Spec]
| Input threshold voltage corners
Vinl   0.1233V   0.1167V   0.1350V
Vinh   0.2433V   0.2367V   0.2550V
| Measurement voltage corners
Vmeas   0.1833V   0.1767V   0.1950V
| Timing spec test load voltage corners
Vref   0.0000V   0.0000V   0.0000V
| Dynamic Overshoot Parameters from LPDDR4 Specification
D_overshoot_ampl_h   0.30   NA   NA
D_overshoot_ampl_l   0.30   NA   NA
D_overshoot_area_h   0.1n   NA   NA
D_overshoot_area_l   0.1n   NA   NA
[Receiver Thresholds]
Vcross_low   = 123.3mV
Vcross_high  = 243.3mV
Vdiff_ac   = 120mV
Vdiff_dc   = 120mV
Tdiffslew_ac = 10.000ns |Not specified, so set to high value
[Voltage Range]   1.1000V   1.0600V   1.1700V
[Pullup Reference]   1.1000V   1.0600V   1.1700V
| Junction Temperature (Ambient temp is 35C typ 95C min -40C max)
[Temperature Range]   50.0   110.0   -40.0
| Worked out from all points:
|   slope of the pulldown table from 0 to 0.165 V, typ, clamps not added: 43.9 ohm
|   slope of the pullup table from 0 to 0.165 V, typ, clamps not added: 25.8 kohm
|   GND clamp passes 1 mA (typ) near -0.45 V on its own axis
|   POWER clamp passes 1 mA (typ) near -0.88 V on its own axis
|   rising waveform, R_fixture 50, V_fixture 0.0: 20-80 % time 44.1ps typ, 47ps min, 38.8ps max; typ from 0 V to 0.291 V
|   falling waveform, R_fixture 50, V_fixture 1.1: 20-80 % time 50.5ps typ, 62.7ps min, 40.3ps max; typ from 1.1 V to 0.561 V
|   rising waveform, R_fixture 50, V_fixture 1.1: 20-80 % time 58.9ps typ, 62.5ps min, 54.5ps max; typ from 0.561 V to 1.1 V
|   falling waveform, R_fixture 50, V_fixture 0.0: 20-80 % time 33.6ps typ, 41.6ps min, 28.9ps max; typ from 0.291 V to 0 V
[Pulldown]
|   Voltage   I(typ)   I(min)   I(max)
-1.1V     -29.51mA   -26.05mA   -32.86mA
-941.6mV  -26.6mA    -24.92mA   -29.28mA
-671mV    -21.19mA   -20.61mA   -22.8mA
-473mV    -15.74mA   -14.78mA   -17.36mA
-268.4mV  -7.537mA   -7.202mA   -8.239mA
-133.1mV  -3.344mA   -3.325mA   -3.363mA
253mV     5.577mA    5.496mA    5.683mA
566.5mV   10.8mA     10.26mA    11.71mA
837.1mV   13.56mA    12.41mA    15.56mA
1.114V    15.26mA    13.81mA    18.01mA
1.603V    17.31mA    15.65mA    20.58mA
2.2V      19.2mA     17.45mA    22.72mA
[GND Clamp]
|   Voltage   I(typ)   I(min)   I(max)
-1.1V     -34.88mA   -30.34mA   -43.13mA
-948.2mV  -25.55mA   -21.71mA   -31.95mA
-796.4mV  -16.18mA   -13.19mA   -21.29mA
-723.8mV  -11.98mA   -9.382mA   -16.18mA
-661.1mV  -8.597mA   -6.455mA   -11.9mA
-588.5mV  -5.128mA   -3.689mA   -7.329mA
-522.5mV  -2.672mA   -1.906mA   -3.822mA
-466.4mV  -1.296mA   -943.6uA   -1.695mA
-413.6mV  -565.2uA   -416.7uA   -622.2uA
-344.3mV  -145.2uA   -109.1uA   -124uA
-248.6mV  -12.15uA   -10.93uA   -7.038uA
2.2V      0A         0A         0A
[Pullup]
|   Voltage   I(typ)   I(min)   I(max)
-1.1V     3.142uA    4.844uA    1.416uA
229.9mV   -22.65uA   -22.9uA    -23.35uA
335.5mV   -170.6uA   -141.7uA   -234.7uA
437.8mV   -720.4uA   -590.6uA   -907.3uA
556.6mV   -1.993mA   -1.844mA   -2.153mA
688.6mV   -3.881mA   -3.997mA   -3.841mA
955.9mV   -8.251mA   -9.322mA   -7.75mA
1.325V    -14.67mA   -16.84mA   -13.74mA
1.586V    -19.06mA   -21.55mA   -18.15mA
1.695V    -20.47mA   -22.99mA   -19.73mA
1.867V    -22.74mA   -24.71mA   -22.38mA
2.2V      -27.69mA   -27.67mA   -28.61mA
[POWER Clamp]
|   Voltage   I(typ)   I(min)   I(max)
-1.1V     3.036mA    3.636mA    2.186mA
-1.041V   2.347mA    2.932mA    1.626mA
-981.2mV  1.754mA    2.277mA    1.183mA
-908.6mV  1.178mA    1.583mA    748.3uA
-852.5mV  818.7uA    1.149mA    543.7uA
-776.6mV  434.3uA    683.6uA    390.2uA
-710.6mV  232.2uA    359.1uA    273.1uA
-654.5mV  142.7uA    170.4uA    185.9uA
-595.1mV  80.75uA    68.33uA    109.3uA
-496.1mV  20.08uA    12.34uA    25.73uA
-380.6mV  1.618uA    1.133uA    1.341uA
2.2V      0A         0A         0A
[Ramp]
|   typ   min   max
| 20% - 80%
dV/dt_r   174.49m/44.09p   170.48m/47.00p   187.90m/38.79p
dV/dt_f   323.18m/50.46p   304.13m/62.65p   357.16m/40.30p
| 25% - 75%
|dV/dt_r   145.41m/35.21p   142.07m/37.52p   156.58m/30.79p
|dV/dt_f   269.31m/40.23p   253.44m/50.02p   297.63m/32.07p
R_load = 50
[Rising Waveform]
R_fixture = 50
V_fixture = 0.0
|   Time   V(typ)   V(min)   V(max)
0s        295.5uV    244.1uV    215.1uV
56ps      228.4uV    325.2uV    4.923mV
67ps      186.1uV    -243.8uV   41.67mV
78ps      6.575mV    -405.8uV   105.7mV
104ps     113.6mV    20.74mV    233.4mV
121ps     186.9mV    88.28mV    274.4mV
138ps     234.6mV    161.1mV    295.2mV
165ps     271.8mV    235.3mV    308.1mV
202ps     287.3mV    273.4mV    312.4mV
402ps     291.1mV    284.4mV    313.4mV
[Falling Waveform]
R_fixture   = 50
V_fixture   = 1.1
V_fixture_min = 1.06
V_fixture_max = 1.17
|   Time   V(typ)   V(min)   V(max)
0s        1.1V       1.06V      1.17V
72ps      1.1V       1.06V      1.162V
80ps      1.101V     1.059V     1.104V
93ps      1.088V     1.059V     959.8mV
115ps     931.8mV    1.053V     753.5mV
132ps     801.5mV    981.6mV    665.4mV
153ps     688.5mV    850.8mV    613.1mV
191ps     598.1mV    676mV      582.7mV
232ps     570.8mV    594.2mV    576.2mV
402ps     561.4mV    553.1mV    574.7mV
[Rising Waveform]
R_fixture   = 50
V_fixture   = 1.1
V_fixture_min = 1.06
V_fixture_max = 1.17
|   Time   V(typ)   V(min)   V(max)
0s        561.2mV    552.6mV    574.7mV
56ps      557.8mV    548.7mV    585.5mV
64ps      564.5mV    546.3mV    627mV
78ps      629.9mV    559.4mV    778mV
93ps      761.4mV    633.3mV    902.9mV
112ps     884.1mV    773.2mV    1.005V
132ps     965.3mV    876.4mV    1.07V
156ps     1.024V     952.5mV    1.116V
233ps     1.087V     1.041V     1.162V
402ps     1.1V       1.059V     1.17V
[Falling Waveform]
R_fixture = 50
V_fixture = 0.0
|   Time   V(typ)   V(min)   V(max)
0s        291.2mV    284.5mV    313.4mV
56ps      295.1mV    285.5mV    313.8mV
74ps      288.1mV    292.2mV    234.1mV
85ps      253.8mV    286.8mV    139mV
96ps      190.6mV    261.8mV    80.01mV
112ps     96.09mV    198.2mV    36.19mV
129ps     43.91mV    117.6mV    15.73mV
153ps     14.72mV    43.64mV    5.013mV
186ps     3.591mV    10.74mV    1.231mV
402ps     373.2uV    350.3uV    246.3uV
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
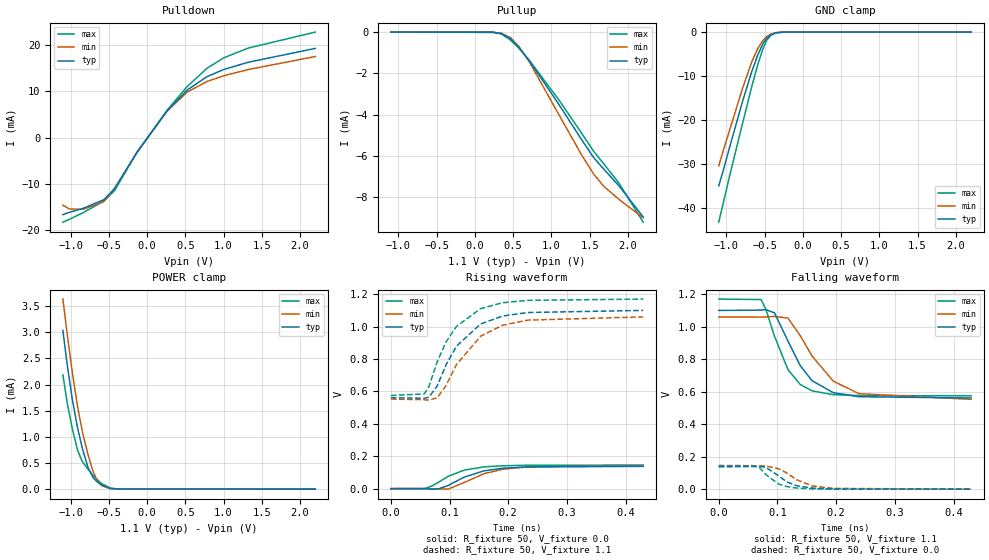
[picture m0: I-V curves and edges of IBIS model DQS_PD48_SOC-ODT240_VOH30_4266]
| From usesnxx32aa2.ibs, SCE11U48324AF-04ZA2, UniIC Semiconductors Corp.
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| DQS_PD48_SOC-ODT240_VOH30_4266
| (48 Ohm Pulldown, 240 Ohm System ODT Setting, VOH=VDDQ/3.0, 3200-4266Mbps)
[Model]   DQS_PD48_SOC-ODT240_VOH30_4266
Model_type   I/O
Vinl = 123.333mV
Vinh = 243.333mV
Vmeas = 183.333mV
Vref = 0.0mV
Cref = 0.0pF
Rref = 240.000Ohm
|   typ   min   max
|C_comp   0.838pF   0.788pF   0.888pF
C_comp_pullup   0.4190pF   0.3940pF   0.4440pF
C_comp_pulldown   0.4190pF   0.3940pF   0.4440pF
| Note: C_comp changes when the ODT circuit is enabled.
[Model Spec]
| Input threshold voltage corners
Vinl   0.1233V   0.1167V   0.1350V
Vinh   0.2433V   0.2367V   0.2550V
| Measurement voltage corners
Vmeas   0.1833V   0.1767V   0.1950V
| Timing spec test load voltage corners
Vref   0.0000V   0.0000V   0.0000V
| Dynamic Overshoot Parameters from LPDDR4 Specification
D_overshoot_ampl_h   0.30   NA   NA
D_overshoot_ampl_l   0.30   NA   NA
D_overshoot_area_h   0.1n   NA   NA
D_overshoot_area_l   0.1n   NA   NA
[Receiver Thresholds]
Vcross_low   = 123.3mV
Vcross_high  = 243.3mV
Vdiff_ac   = 120mV
Vdiff_dc   = 120mV
Tdiffslew_ac = 10.000ns |Not specified, so set to high value
[Voltage Range]   1.1000V   1.0600V   1.1700V
[Pullup Reference]   1.1000V   1.0600V   1.1700V
| Junction Temperature (Ambient temp is 35C typ 95C min -40C max)
[Temperature Range]   50.0   110.0   -40.0
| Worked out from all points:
|   slope of the pulldown table from 0 to 0.165 V, typ, clamps not added: 44 ohm
|   slope of the pullup table from 0 to 0.165 V, typ, clamps not added: 80.3 kohm
|   GND clamp passes 1 mA (typ) near -0.45 V on its own axis
|   POWER clamp passes 1 mA (typ) near -0.88 V on its own axis
|   rising waveform, R_fixture 50, V_fixture 0.0: 20-80 % time 57.2ps typ, 59.8ps min, 50.7ps max; typ from 0 V to 0.138 V
|   falling waveform, R_fixture 50, V_fixture 1.1: 20-80 % time 50.2ps typ, 62.3ps min, 40.1ps max; typ from 1.1 V to 0.561 V
|   rising waveform, R_fixture 50, V_fixture 1.1: 20-80 % time 59.2ps typ, 63.8ps min, 54.7ps max; typ from 0.561 V to 1.1 V
|   falling waveform, R_fixture 50, V_fixture 0.0: 20-80 % time 33.5ps typ, 41.1ps min, 29.5ps max; typ from 0.138 V to 0 V
[Pulldown]
|   Voltage   I(typ)   I(min)   I(max)
-1.1V     -16.6mA    -14.59mA   -18.24mA
-1.014V   -16.11mA   -15.4mA    -17.61mA
-832.7mV  -15.24mA   -15.45mA   -16.16mA
-565.4mV  -13.4mA    -13.8mA    -13.69mA
-423.5mV  -10.99mA   -10.97mA   -11.41mA
-133.1mV  -3.241mA   -3.259mA   -3.21mA
262.9mV   5.775mA    5.687mA    5.893mA
523.6mV   10.22mA    9.779mA    10.97mA
784.3mV   13.13mA    12.08mA    14.93mA
1.005V    14.67mA    13.31mA    17.19mA
1.325V    16.23mA    14.66mA    19.28mA
2.2V      19.2mA     17.45mA    22.72mA
[GND Clamp]
|   Voltage   I(typ)   I(min)   I(max)
-1.1V     -34.88mA   -30.35mA   -43.13mA
-1.047V   -31.79mA   -27.25mA   -39.23mA
-941.6mV  -25.13mA   -21.34mA   -31.48mA
-786.5mV  -15.59mA   -12.65mA   -20.59mA
-667.7mV  -8.94mA    -6.742mA   -12.34mA
-591.8mV  -5.273mA   -3.798mA   -7.523mA
-525.8mV  -2.772mA   -1.977mA   -3.977mA
-473mV    -1.425mA   -1.032mA   -1.891mA
-416.9mV  -597.5uA   -441.6uA   -665.5uA
-354.2mV  -179.1uA   -135.1uA   -159.7uA
-251.9mV  -13.26uA   -12.18uA   -7.885uA
2.2V      0A         0A         0A
[Pullup]
|   Voltage   I(typ)   I(min)   I(max)
-1.1V     1.047uA    1.615uA    471.8nA
239.8mV   -9.315uA   -9.231uA   -9.968uA
345.4mV   -66.89uA   -55.15uA   -92.21uA
464.2mV   -314.7uA   -264uA     -380.9uA
569.8mV   -714uA     -668.3uA   -763.5uA
711.7mV   -1.395mA   -1.451mA   -1.372mA
1.108V    -3.568mA   -4.077mA   -3.344mA
1.388V    -5.184mA   -5.92mA    -4.87mA
1.556V    -6.109mA   -6.911mA   -5.805mA
1.682V    -6.64mA    -7.474mA   -6.383mA
1.887V    -7.482mA   -8.134mA   -7.355mA
2.2V      -8.971mA   -9.014mA   -9.226mA
[POWER Clamp]
|   Voltage   I(typ)   I(min)   I(max)
-1.1V     3.036mA    3.636mA    2.186mA
-1.044V   2.383mA    2.97mA     1.654mA
-974.6mV  1.695mA    2.208mA    1.139mA
-908.6mV  1.178mA    1.583mA    747.8uA
-849.2mV  799.3uA    1.126mA    535.5uA
-773.3mV  420.8uA    665.6uA    384.1uA
-710.6mV  232.3uA    359.1uA    273.1uA
-657.8mV  146.8uA    178.8uA    190.7uA
-595.1mV  80.8uA     68.3uA     109.2uA
-482.9mV  15.75uA    9.494uA    19.52uA
-360.8mV  1.024uA    769.9nA    793.9nA
2.2V      0A         0A         0A
[Ramp]
|   typ   min   max
| 20% - 80%
dV/dt_r   82.51m/57.19p   84.29m/59.80p   87.28m/50.68p
dV/dt_f   323.19m/50.22p   304.28m/62.26p   357.15m/40.08p
| 25% - 75%
|dV/dt_r   68.76m/45.52p   70.24m/47.73p   72.73m/40.15p
|dV/dt_f   269.33m/40.03p   253.57m/49.65p   297.63m/31.89p
R_load = 50
[Rising Waveform]
R_fixture = 50
V_fixture = 0.0
|   Time   V(typ)   V(min)   V(max)
0s        75.34uV    45.31uV    56.14uV
58ps      -405uV     387.9uV    1.506mV
70ps      -3.151mV   -703uV     15.98mV
81ps      -1.774mV   -2.716mV   39.21mV
98ps      20.12mV    -1.947mV   76.6mV
125ps     71.07mV    37.91mV    114.3mV
159ps     110.1mV    92.59mV    134.6mV
190ps     126.1mV    119.3mV    141.3mV
233ps     134.3mV    134.3mV    144.4mV
430ps     137.6mV    140.5mV    145.5mV
[Falling Waveform]
R_fixture   = 50
V_fixture   = 1.1
V_fixture_min = 1.06
V_fixture_max = 1.17
|   Time   V(typ)   V(min)   V(max)
0s        1.1V       1.06V      1.17V
72ps      1.102V     1.059V     1.167V
80ps      1.105V     1.06V      1.11V
95ps      1.085V     1.063V     941.4mV
118ps     911.3mV    1.053V     735.5mV
139ps     759.7mV    944.2mV    643.7mV
159ps     667.7mV    819.5mV    605mV
195ps     594.1mV    665.3mV    581.7mV
239ps     569mV      587.4mV    575.9mV
430ps     561.3mV    552.9mV    574.7mV
[Rising Waveform]
R_fixture   = 50
V_fixture   = 1.1
V_fixture_min = 1.06
V_fixture_max = 1.17
|   Time   V(typ)   V(min)   V(max)
0s        561.2mV    552.6mV    574.7mV
57ps      557.8mV    548.6mV    584.9mV
65ps      564.7mV    546.5mV    630.6mV
79ps      633.4mV    560.4mV    782.5mV
94ps      764mV      635.9mV    905.1mV
112ps     879.8mV    766.6mV    1.002V
153ps     1.016V     940.9mV    1.111V
190ps     1.065V     1.008V     1.147V
233ps     1.087V     1.04V      1.162V
430ps     1.1V       1.06V      1.17V
[Falling Waveform]
R_fixture = 50
V_fixture = 0.0
|   Time   V(typ)   V(min)   V(max)
0s        137.7mV    140.6mV    145.5mV
60ps      139.4mV    141.8mV    144.7mV
70ps      139.6mV    143.1mV    130.9mV
80ps      135.1mV    143.1mV    90.68mV
102ps     81.94mV    125.8mV    31.6mV
116ps     45.02mV    99.45mV    16.13mV
133ps     21.17mV    57.61mV    7.188mV
159ps     6.774mV    20.26mV    2.128mV
195ps     1.517mV    4.708mV    465.9uV
430ps     145.7uV    143.8uV    87.86uV
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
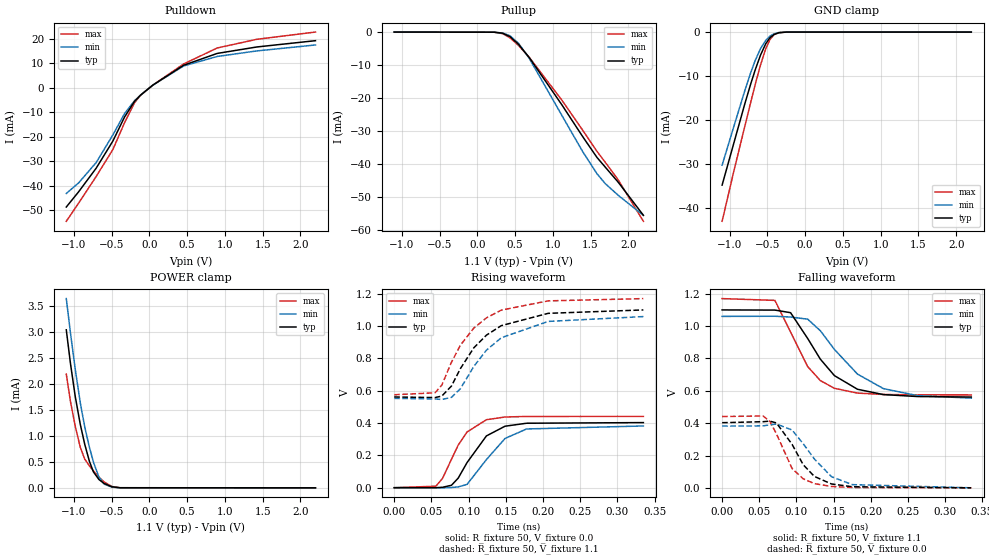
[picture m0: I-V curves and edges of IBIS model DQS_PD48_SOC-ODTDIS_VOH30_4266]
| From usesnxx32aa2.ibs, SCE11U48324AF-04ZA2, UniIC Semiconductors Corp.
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| DQS_PD48_SOC-ODTDIS_VOH30_4266
| (48 Ohm Pulldown, SOC ODT disabled setting, VOH=VDDQ/3.0 cal. point, 3200-4266Mbps)
[Model]   DQS_PD48_SOC-ODTDIS_VOH30_4266
Model_type   I/O
Vinl = 123.333mV
Vinh = 243.333mV
Vmeas = 183.333mV
Vref = 0.0mV
Cref = 0.0pF
|   typ   min   max
|C_comp   0.838pF   0.788pF   0.888pF
C_comp_pullup   0.4190pF   0.3940pF   0.4440pF
C_comp_pulldown   0.4190pF   0.3940pF   0.4440pF
| Note: C_comp changes when the ODT circuit is enabled.
[Model Spec]
| Input threshold voltage corners
Vinl   0.1233V   0.1167V   0.1350V
Vinh   0.2433V   0.2367V   0.2550V
| Measurement voltage corners
Vmeas   0.1833V   0.1767V   0.1950V
| Timing spec test load voltage corners
Vref   0.0000V   0.0000V   0.0000V
| Dynamic Overshoot Parameters from LPDDR4 Specification
D_overshoot_ampl_h   0.30   NA   NA
D_overshoot_ampl_l   0.30   NA   NA
D_overshoot_area_h   0.1n   NA   NA
D_overshoot_area_l   0.1n   NA   NA
[Receiver Thresholds]
Vcross_low   = 123.3mV
Vcross_high  = 243.3mV
Vdiff_ac   = 120mV
Vdiff_dc   = 120mV
Tdiffslew_ac = 10.000ns |Not specified, so set to high value
[Voltage Range]   1.1000V   1.0600V   1.1700V
[Pullup Reference]   1.1000V   1.0600V   1.1700V
| Junction Temperature (Ambient temp is 35C typ 95C min -40C max)
[Temperature Range]   50.0   110.0   -40.0
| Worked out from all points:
|   slope of the pulldown table from 0 to 0.165 V, typ, clamps not added: 43.8 ohm
|   slope of the pullup table from 0 to 0.165 V, typ, clamps not added: 13.1 kohm
|   GND clamp passes 1 mA (typ) near -0.45 V on its own axis
|   POWER clamp passes 1 mA (typ) near -0.88 V on its own axis
|   rising waveform, R_fixture 50, V_fixture 0.0: 20-80 % time 35.5ps typ, 39.3ps min, 31ps max; typ from 0.001 V to 0.403 V
|   falling waveform, R_fixture 50, V_fixture 1.1: 20-80 % time 50.8ps typ, 62.7ps min, 40.6ps max; typ from 1.1 V to 0.562 V
|   rising waveform, R_fixture 50, V_fixture 1.1: 20-80 % time 57.9ps typ, 60.4ps min, 54.3ps max; typ from 0.561 V to 1.1 V
|   falling waveform, R_fixture 50, V_fixture 0.0: 20-80 % time 33.5ps typ, 41.1ps min, 28.6ps max; typ from 0.403 V to 0.001 V
[Pulldown]
|   Voltage   I(typ)   I(min)   I(max)
-1.1V     -48.63mA   -43.11mA   -54.44mA
-938.3mV  -42.49mA   -38.85mA   -47.12mA
-704mV    -32.79mA   -30.49mA   -36.17mA
-482.9mV  -21.72mA   -19.22mA   -25.17mA
-327.8mV  -11.9mA    -10.49mA   -14.22mA
-195.8mV  -5.533mA   -5.265mA   -6.079mA
-116.6mV  -3.025mA   -2.977mA   -3.066mA
45.1mV    1.049mA    1.046mA    1.047mA
454.3mV   9.185mA    8.882mA    9.718mA
899.8mV   14.01mA    12.77mA    16.23mA
1.425V    16.64mA    15.03mA    19.77mA
2.2V      19.2mA     17.45mA    22.72mA
[GND Clamp]
|   Voltage   I(typ)   I(min)   I(max)
-1.1V     -34.88mA   -30.34mA   -43.13mA
-935mV    -24.71mA   -20.97mA   -31mA
-796.4mV  -16.18mA   -13.19mA   -21.29mA
-720.5mV  -11.79mA   -9.217mA   -15.95mA
-661.1mV  -8.596mA   -6.454mA   -11.9mA
-591.8mV  -5.271mA   -3.797mA   -7.525mA
-522.5mV  -2.67mA    -1.906mA   -3.824mA
-466.4mV  -1.297mA   -942.9uA   -1.696mA
-413.6mV  -564.8uA   -417.3uA   -623.3uA
-347.6mV  -154.3uA   -117.7uA   -134.7uA
-248.6mV  -12.11uA   -10.87uA   -6.998uA
2.2V      0A         0A         0A
[Pullup]
|   Voltage   I(typ)   I(min)   I(max)
-1.1V     6.284uA    9.684uA    2.832uA
223.3mV   -39.19uA   -40.62uA   -39.36uA
335.5mV   -341uA     -283.4uA   -469.1uA
434.5mV   -1.386mA   -1.133mA   -1.752mA
546.7mV   -3.719mA   -3.404mA   -4.061mA
688.6mV   -7.724mA   -7.946mA   -7.651mA
1.118V    -21.94mA   -25.13mA   -20.53mA
1.395V    -31.61mA   -36.14mA   -29.67mA
1.586V    -37.97mA   -42.9mA    -36.14mA
1.695V    -40.88mA   -45.88mA   -39.4mA
1.867V    -45.46mA   -49.42mA   -44.76mA
2.2V      -55.46mA   -55.5mA    -57.28mA
[POWER Clamp]
|   Voltage   I(typ)   I(min)   I(max)
-1.1V     3.036mA    3.636mA    2.186mA
-1.044V   2.383mA    2.969mA    1.654mA
-981.2mV  1.754mA    2.277mA    1.183mA
-915.2mV  1.224mA    1.64mA     781.7uA
-855.8mV  838.1uA    1.172mA    552.5uA
-793.1mV  506.4uA    776.1uA    421uA
-740.3mV  306.1uA    494.5uA    324.3uA
-667.7mV  159.9uA    206.1uA    205.2uA
-598.4mV  83.68uA    71.96uA    113.1uA
-496.1mV  20.06uA    12.36uA    25.74uA
-390.5mV  2.036uA    1.387uA    1.776uA
2.2V      0A         0A         0A
[Ramp]
|   typ   min   max
| 20% - 80%
dV/dt_r   241.34m/35.46p   228.89m/39.34p   264.44m/30.98p
dV/dt_f   323.03m/50.82p   302.91m/62.69p   357.15m/40.58p
| 25% - 75%
|dV/dt_r   201.11m/28.26p   190.74m/31.36p   220.36m/24.58p
|dV/dt_f   269.19m/40.51p   252.43m/50.02p   297.63m/32.28p
R_load = 50
[Rising Waveform]
R_fixture = 50
V_fixture = 0.0
|   Time   V(typ)   V(min)   V(max)
0s        619.2uV    537.3uV    447.4uV
56ps      626.6uV    84.71uV    9.803mV
65ps      3.145mV    -285.4uV   58.04mV
77ps      15.67mV    1.769mV    176.3mV
86ps      59.4mV     5.385mV    263.4mV
98ps      156.2mV    21.26mV    345.1mV
124ps     320.6mV    174.3mV    420.7mV
149ps     380.5mV    304.8mV    437.4mV
178ps     398.9mV    363.5mV    440.8mV
335ps     402.8mV    382mV      441.2mV
[Falling Waveform]
R_fixture   = 50
V_fixture   = 1.1
V_fixture_min = 1.06
V_fixture_max = 1.17
|   Time   V(typ)   V(min)   V(max)
0s        1.1V       1.06V      1.17V
71ps      1.099V     1.061V     1.159V
92ps      1.083V     1.056V     963.6mV
115ps     923.9mV    1.043V     750mV
132ps     796.1mV    971.7mV    663.6mV
151ps     693.9mV    855.6mV    615.5mV
182ps     609.7mV    703.4mV    586.1mV
217ps     576.7mV    613.4mV    577.4mV
263ps     564.7mV    570.1mV    575.1mV
335ps     561.6mV    555.1mV    574.8mV
[Rising Waveform]
R_fixture   = 50
V_fixture   = 1.1
V_fixture_min = 1.06
V_fixture_max = 1.17
|   Time   V(typ)   V(min)   V(max)
0s        561.2mV    552.6mV    574.7mV
55ps      557.5mV    548.7mV    587.1mV
64ps      566.7mV    545.8mV    634.4mV
77ps      628.8mV    558.8mV    775.8mV
89ps      736.5mV    612.5mV    881.2mV
107ps     864.7mV    749.4mV    986.8mV
124ps     943.1mV    850.6mV    1.05V
144ps     1.002V     927.2mV    1.098V
207ps     1.078V     1.028V     1.155V
335ps     1.099V     1.058V     1.169V
[Falling Waveform]
R_fixture = 50
V_fixture = 0.0
|   Time   V(typ)   V(min)   V(max)
0s        403mV      382.2mV    441.3mV
55ps      409.3mV    383.4mV    444.6mV
64ps      412.8mV    389.5mV    413.3mV
73ps      401.7mV    395.1mV    334.6mV
94ps      269.8mV    358mV      120.2mV
109ps     143.5mV    273.2mV    56.18mV
124ps     71.06mV    179.1mV    26.69mV
147ps     24.41mV    69.61mV    8.826mV
175ps     7.149mV    20.26mV    2.6mV
335ps     681.2uV    649.2uV    472.5uV
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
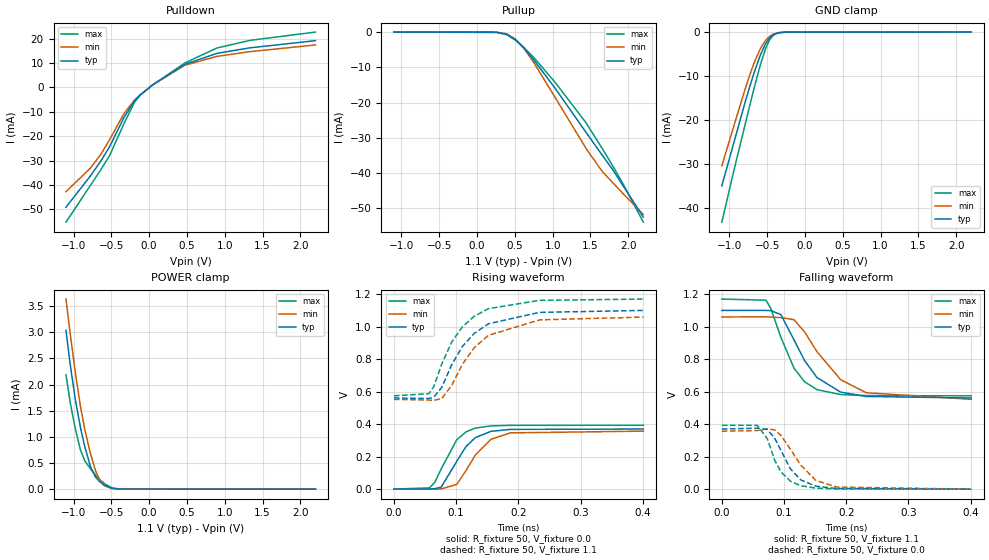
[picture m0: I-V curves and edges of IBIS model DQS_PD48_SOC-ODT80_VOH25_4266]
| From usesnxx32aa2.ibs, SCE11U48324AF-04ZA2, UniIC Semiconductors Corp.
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| DQS_PD48_SOC-ODT80_VOH25_4266
| (48 Ohm Pulldown, 80 Ohm System ODT Setting, VOH=VDDQ/2.5, 3200-4266Mbps)
[Model]   DQS_PD48_SOC-ODT80_VOH25_4266
Model_type   I/O
Vinl = 160.000mV
Vinh = 280.000mV
Vmeas = 220.000mV
Vref = 0.0mV
Cref = 0.0pF
Rref = 80.000Ohm
|   typ   min   max
|C_comp   0.838pF   0.788pF   0.888pF
C_comp_pullup   0.4190pF   0.3940pF   0.4440pF
C_comp_pulldown   0.4190pF   0.3940pF   0.4440pF
| Note: C_comp changes when the ODT circuit is enabled.
[Model Spec]
| Input threshold voltage corners
Vinl   0.1600V   0.1520V   0.1740V
Vinh   0.2800V   0.2720V   0.2940V
| Measurement voltage corners
Vmeas   0.2200V   0.2120V   0.2340V
| Timing spec test load voltage corners
Vref   0.0000V   0.0000V   0.0000V
| Dynamic Overshoot Parameters from LPDDR4 Specification
D_overshoot_ampl_h   0.30   NA   NA
D_overshoot_ampl_l   0.30   NA   NA
D_overshoot_area_h   0.1n   NA   NA
D_overshoot_area_l   0.1n   NA   NA
[Receiver Thresholds]
Vcross_low   = 160.0mV
Vcross_high  = 280.0mV
Vdiff_ac   = 120mV
Vdiff_dc   = 120mV
Tdiffslew_ac = 10.000ns |Not specified, so set to high value
[Voltage Range]   1.1000V   1.0600V   1.1700V
[Pullup Reference]   1.1000V   1.0600V   1.1700V
| Junction Temperature (Ambient temp is 35C typ 95C min -40C max)
[Temperature Range]   50.0   110.0   -40.0
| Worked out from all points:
|   slope of the pulldown table from 0 to 0.165 V, typ, clamps not added: 43.8 ohm
|   slope of the pullup table from 0 to 0.165 V, typ, clamps not added: 17.1 kohm
|   GND clamp passes 1 mA (typ) near -0.45 V on its own axis
|   POWER clamp passes 1 mA (typ) near -0.88 V on its own axis
|   rising waveform, R_fixture 50, V_fixture 0.0: 20-80 % time 35.6ps typ, 39.1ps min, 32.6ps max; typ from 0.001 V to 0.37 V
|   falling waveform, R_fixture 50, V_fixture 1.1: 20-80 % time 50.7ps typ, 63.3ps min, 40.5ps max; typ from 1.1 V to 0.561 V
|   rising waveform, R_fixture 50, V_fixture 1.1: 20-80 % time 58.6ps typ, 61.6ps min, 54.2ps max; typ from 0.561 V to 1.1 V
|   falling waveform, R_fixture 50, V_fixture 0.0: 20-80 % time 33.8ps typ, 41.2ps min, 28.2ps max; typ from 0.37 V to 0.001 V
[Pulldown]
|   Voltage   I(typ)   I(min)   I(max)
-1.1V     -49.08mA   -42.7mA    -55.23mA
-776.6mV  -36.24mA   -33.06mA   -40.12mA
-638mV    -30.11mA   -27.36mA   -33.66mA
-522.5mV  -24.24mA   -21.38mA   -27.85mA
-334.4mV  -12.38mA   -10.76mA   -14.9mA
-195.8mV  -5.557mA   -5.256mA   -6.129mA
-116.6mV  -3.032mA   -2.973mA   -3.076mA
45.1mV    1.049mA    1.046mA    1.047mA
474.1mV   9.491mA    9.153mA    10.08mA
896.5mV   13.98mA    12.75mA    16.19mA
1.335V    16.27mA    14.7mA     19.33mA
2.2V      19.2mA     17.45mA    22.72mA
[GND Clamp]
|   Voltage   I(typ)   I(min)   I(max)
-1.1V     -34.89mA   -30.33mA   -43.14mA
-944.9mV  -25.34mA   -21.52mA   -31.72mA
-799.7mV  -16.38mA   -13.37mA   -21.53mA
-733.7mV  -12.54mA   -9.877mA   -16.88mA
-667.7mV  -8.943mA   -6.741mA   -12.35mA
-591.8mV  -5.275mA   -3.797mA   -7.53mA
-522.5mV  -2.673mA   -1.907mA   -3.826mA
-469.7mV  -1.361mA   -988.9uA   -1.791mA
-416.9mV  -597.6uA   -442.1uA   -665.5uA
-354.2mV  -179.1uA   -135.4uA   -160.3uA
-255.2mV  -14.69uA   -13.18uA   -8.81uA
2.2V      0A         0A         0A
[Pullup]
|   Voltage   I(typ)   I(min)   I(max)
-1.1V     4.112uA    7.441uA    1.363uA
259.6mV   -61.43uA   -59.36uA   -61.49uA
391.6mV   -603.2uA   -502uA     -719.1uA
507.1mV   -2.161mA   -1.951mA   -2.252mA
616mV     -4.459mA   -4.485mA   -4.266mA
748mV     -7.819mA   -8.539mA   -7.138mA
1.032V    -15.9mA    -18.5mA    -14.23mA
1.444V    -28.51mA   -33.07mA   -25.79mA
1.655V    -34.88mA   -39.5mA    -32.99mA
1.801V    -39.21mA   -42.84mA   -38.16mA
1.943V    -43.96mA   -46.05mA   -43.51mA
2.2V      -52.46mA   -51.74mA   -53.91mA
[POWER Clamp]
|   Voltage   I(typ)   I(min)   I(max)
-1.1V     3.036mA    3.636mA    2.186mA
-1.044V   2.383mA    2.969mA    1.654mA
-977.9mV  1.724mA    2.242mA    1.161mA
-908.6mV  1.178mA    1.583mA    748.4uA
-852.5mV  818.5uA    1.149mA    543.8uA
-776.6mV  434.3uA    683.6uA    390.2uA
-710.6mV  232.2uA    359.3uA    273.1uA
-651.2mV  138.6uA    162.3uA    181.2uA
-591.8mV  78uA       64.8uA     105.5uA
-489.5mV  17.77uA    10.83uA    22.44uA
-380.6mV  1.61uA     1.14uA     1.336uA
2.2V      0A         0A         0A
[Ramp]
|   typ   min   max
| 20% - 80%
dV/dt_r   221.54m/35.61p   213.90m/39.07p   235.61m/32.63p
dV/dt_f   323.18m/50.74p   304.15m/63.27p   357.16m/40.47p
| 25% - 75%
|dV/dt_r   184.62m/28.35p   178.25m/31.15p   196.35m/25.90p
|dV/dt_f   269.32m/40.42p   253.46m/50.47p   297.63m/32.15p
R_load = 50
[Rising Waveform]
R_fixture = 50
V_fixture = 0.0
|   Time   V(typ)   V(min)   V(max)
0s        642.3uV    519.4uV    470.7uV
57ps      735.3uV    120.2uV    7.266mV
66ps      2.659mV    -230.8uV   43.72mV
76ps      12.15mV    1.01mV     124.4mV
101ps     171mV      29.03mV    303.9mV
116ps     262.9mV    115mV      352.6mV
131ps     317.2mV    210.2mV    375.8mV
156ps     355.7mV    306.7mV    389.4mV
187ps     367.6mV    346.4mV    392.7mV
401ps     369.9mV    357mV      393.2mV
[Falling Waveform]
R_fixture   = 50
V_fixture   = 1.1
V_fixture_min = 1.06
V_fixture_max = 1.17
|   Time   V(typ)   V(min)   V(max)
0s        1.1V       1.06V      1.17V
71ps      1.1V       1.061V     1.163V
79ps      1.099V     1.059V     1.11V
95ps      1.074V     1.056V     933.9mV
116ps     919.1mV    1.043V     745mV
133ps     791.8mV    968.3mV    661mV
153ps     687.1mV    846mV      612.7mV
191ps     597.6mV    674.2mV    582.6mV
232ps     570.8mV    593.6mV    576.2mV
401ps     561.4mV    553.1mV    574.7mV
[Rising Waveform]
R_fixture   = 50
V_fixture   = 1.1
V_fixture_min = 1.06
V_fixture_max = 1.17
|   Time   V(typ)   V(min)   V(max)
0s        561.2mV    552.6mV    574.7mV
56ps      557.8mV    548.4mV    587mV
64ps      566mV      545.9mV    630.1mV
77ps      626.5mV    558.4mV    771.2mV
93ps      766.6mV    639mV      906.2mV
110ps     877.9mV    768.2mV    998.7mV
129ps     958.5mV    870.6mV    1.064V
152ps     1.018V     946.8mV    1.111V
234ps     1.088V     1.042V     1.162V
401ps     1.1V       1.059V     1.17V
[Falling Waveform]
R_fixture = 50
V_fixture = 0.0
|   Time   V(typ)   V(min)   V(max)
0s        370mV      357.1mV    393.2mV
57ps      375.9mV    360.9mV    392.9mV
73ps      367.8mV    371.7mV    312.2mV
85ps      313.7mV    364.7mV    178.7mV
95ps      239.1mV    331.4mV    107mV
110ps     126.4mV    247.8mV    50.15mV
127ps     57.29mV    148.2mV    21.56mV
151ps     19.01mV    54.72mV    6.917mV
184ps     4.685mV    13.39mV    1.764mV
401ps     689.7uV    589uV      492.7uV
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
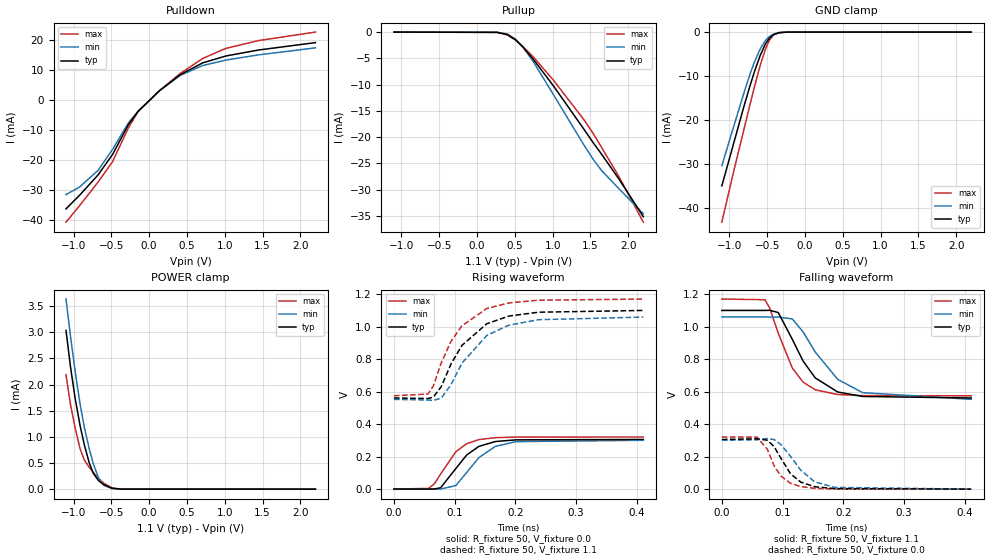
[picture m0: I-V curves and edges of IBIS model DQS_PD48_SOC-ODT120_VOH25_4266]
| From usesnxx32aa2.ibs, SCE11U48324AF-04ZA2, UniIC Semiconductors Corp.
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| DQS_PD48_SOC-ODT120_VOH25_4266
| (48 Ohm Pulldown, 120 Ohm System ODT Setting, VOH=VDDQ/2.5, 3200-4266Mbps)
[Model]   DQS_PD48_SOC-ODT120_VOH25_4266
Model_type   I/O
Vinl = 160.000mV
Vinh = 280.000mV
Vmeas = 220.000mV
Vref = 0.0mV
Cref = 0.0pF
Rref = 120.000Ohm
|   typ   min   max
|C_comp   0.838pF   0.788pF   0.888pF
C_comp_pullup   0.4190pF   0.3940pF   0.4440pF
C_comp_pulldown   0.4190pF   0.3940pF   0.4440pF
| Note: C_comp changes when the ODT circuit is enabled.
[Model Spec]
| Input threshold voltage corners
Vinl   0.1600V   0.1520V   0.1740V
Vinh   0.2800V   0.2720V   0.2940V
| Measurement voltage corners
Vmeas   0.2200V   0.2120V   0.2340V
| Timing spec test load voltage corners
Vref   0.0000V   0.0000V   0.0000V
| Dynamic Overshoot Parameters from LPDDR4 Specification
D_overshoot_ampl_h   0.30   NA   NA
D_overshoot_ampl_l   0.30   NA   NA
D_overshoot_area_h   0.1n   NA   NA
D_overshoot_area_l   0.1n   NA   NA
[Receiver Thresholds]
Vcross_low   = 160.0mV
Vcross_high  = 280.0mV
Vdiff_ac   = 120mV
Vdiff_dc   = 120mV
Tdiffslew_ac = 10.000ns |Not specified, so set to high value
[Voltage Range]   1.1000V   1.0600V   1.1700V
[Pullup Reference]   1.1000V   1.0600V   1.1700V
| Junction Temperature (Ambient temp is 35C typ 95C min -40C max)
[Temperature Range]   50.0   110.0   -40.0
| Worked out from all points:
|   slope of the pulldown table from 0 to 0.165 V, typ, clamps not added: 43.9 ohm
|   slope of the pullup table from 0 to 0.165 V, typ, clamps not added: 26.7 kohm
|   GND clamp passes 1 mA (typ) near -0.45 V on its own axis
|   POWER clamp passes 1 mA (typ) near -0.88 V on its own axis
|   rising waveform, R_fixture 50, V_fixture 0.0: 20-80 % time 40.8ps typ, 44.1ps min, 37.5ps max; typ from 0 V to 0.306 V
|   falling waveform, R_fixture 50, V_fixture 1.1: 20-80 % time 50.5ps typ, 62.9ps min, 40.3ps max; typ from 1.1 V to 0.561 V
|   rising waveform, R_fixture 50, V_fixture 1.1: 20-80 % time 58.8ps typ, 62.5ps min, 54.5ps max; typ from 0.561 V to 1.1 V
|   falling waveform, R_fixture 50, V_fixture 0.0: 20-80 % time 33.3ps typ, 41ps min, 28.1ps max; typ from 0.306 V to 0 V
[Pulldown]
|   Voltage   I(typ)   I(min)   I(max)
-1.1V     -36.35mA   -31.58mA   -40.81mA
-921.8mV  -31.85mA   -29.09mA   -35.33mA
-677.6mV  -25.06mA   -23.54mA   -27.46mA
-482.9mV  -18.15mA   -16.45mA   -20.53mA
-275mV    -8.221mA   -7.631mA   -9.314mA
-146.3mV  -3.77mA    -3.708mA   -3.861mA
137.5mV   3.149mA    3.124mA    3.16mA
408.1mV   8.436mA    8.203mA    8.84mA
708.4mV   12.43mA    11.55mA    13.91mA
1.015V    14.73mA    13.36mA    17.27mA
1.444V    16.72mA    15.1mA     19.87mA
2.2V      19.2mA     17.45mA    22.72mA
[GND Clamp]
|   Voltage   I(typ)   I(min)   I(max)
-1.1V     -34.89mA   -30.33mA   -43.14mA
-938.3mV  -24.93mA   -21.15mA   -31.25mA
-803mV    -16.58mA   -13.55mA   -21.77mA
-727.1mV  -12.17mA   -9.543mA   -16.42mA
-667.7mV  -8.943mA   -6.74mA    -12.35mA
-591.8mV  -5.273mA   -3.797mA   -7.531mA
-522.5mV  -2.675mA   -1.905mA   -3.827mA
-469.7mV  -1.359mA   -987.7uA   -1.792mA
-413.6mV  -565.2uA   -416.4uA   -622uA
-344.3mV  -143.7uA   -109.4uA   -124.9uA
-238.7mV  -9.047uA   -8.466uA   -5.015uA
2.2V      0A         0A         0A
[Pullup]
|   Voltage   I(typ)   I(min)   I(max)
-1.1V     2.741uA    4.961uA    908.5nA
266.2mV   -46.12uA   -44.97uA   -47.89uA
398.2mV   -441.6uA   -368.3uA   -523.4uA
507.1mV   -1.446mA   -1.305mA   -1.506mA
606.1mV   -2.831mA   -2.826mA   -2.722mA
744.7mV   -5.181mA   -5.658mA   -4.729mA
1.009V    -10.21mA   -11.87mA   -9.127mA
1.415V    -18.51mA   -21.52mA   -16.7mA
1.543V    -21.19mA   -24.36mA   -19.43mA
1.649V    -23.27mA   -26.37mA   -22mA
1.877V    -27.97mA   -29.81mA   -27.5mA
2.2V      -35.14mA   -34.58mA   -36.18mA
[POWER Clamp]
|   Voltage   I(typ)   I(min)   I(max)
-1.1V     3.036mA    3.636mA    2.186mA
-1.041V   2.347mA    2.931mA    1.626mA
-981.2mV  1.754mA    2.277mA    1.183mA
-911.9mV  1.201mA    1.611mA    763.8uA
-855.8mV  838.1uA    1.172mA    552.3uA
-793.1mV  506.1uA    776uA      421uA
-740.3mV  306.2uA    494.4uA    324.2uA
-667.7mV  159.9uA    206.1uA    205.2uA
-598.4mV  83.66uA    71.98uA    113uA
-489.5mV  17.85uA    10.89uA    22.49uA
-374mV    1.383uA    994nA      1.124uA
2.2V      0A         0A         0A
[Ramp]
|   typ   min   max
| 20% - 80%
dV/dt_r   183.24m/40.80p   180.34m/44.06p   192.50m/37.46p
dV/dt_f   323.20m/50.52p   304.18m/62.89p   357.16m/40.31p
| 25% - 75%
|dV/dt_r   152.70m/32.47p   150.28m/35.12p   160.42m/29.79p
|dV/dt_f   269.33m/40.26p   253.48m/50.20p   297.63m/32.03p
R_load = 50
[Rising Waveform]
R_fixture = 50
V_fixture = 0.0
|   Time   V(typ)   V(min)   V(max)
0s        419.6uV    331.7uV    308uV
57ps      472.7uV    227.8uV    4.558mV
67ps      1.086mV    -117.2uV   34.46mV
77ps      8.796mV    346.8uV    93.14mV
102ps     126.9mV    22.27mV    230.5mV
120ps     210.5mV    103.1mV    280mV
140ps     263.2mV    194.3mV    305mV
167ps     293mV      263mV      316.9mV
201ps     303.4mV    292.4mV    320.4mV
411ps     305.8mV    300.9mV    321.1mV
[Falling Waveform]
R_fixture   = 50
V_fixture   = 1.1
V_fixture_min = 1.06
V_fixture_max = 1.17
|   Time   V(typ)   V(min)   V(max)
0s        1.1V       1.06V      1.17V
71ps      1.1V       1.06V      1.166V
79ps      1.101V     1.059V     1.114V
93ps      1.087V     1.059V     959.5mV
116ps     922.8mV    1.048V     746.5mV
134ps     787.7mV    967.6mV    658.2mV
154ps     684.7mV    843.6mV    611.5mV
191ps     598.1mV    675.6mV    582.7mV
232ps     570.8mV    594.1mV    576.2mV
411ps     561.3mV    553mV      574.7mV
[Rising Waveform]
R_fixture   = 50
V_fixture   = 1.1
V_fixture_min = 1.06
V_fixture_max = 1.17
|   Time   V(typ)   V(min)   V(max)
0s        561.2mV    552.6mV    574.7mV
56ps      557.8mV    548.6mV    585.2mV
65ps      566.9mV    546.2mV    635.6mV
78ps      630.8mV    560.1mV    777.7mV
94ps      770.1mV    642.6mV    909.7mV
112ps     884.6mV    775.4mV    1.005V
153ps     1.018V     945.8mV    1.112V
189ps     1.065V     1.009V     1.146V
238ps     1.089V     1.043V     1.163V
411ps     1.1V       1.059V     1.17V
[Falling Waveform]
R_fixture = 50
V_fixture = 0.0
|   Time   V(typ)   V(min)   V(max)
0s        305.9mV    301mV      321.2mV
58ps      310.4mV    304.3mV    320.7mV
75ps      301.7mV    312mV      245.8mV
86ps      262.8mV    305.7mV    144.5mV
97ps      192.7mV    276.1mV    82.43mV
113ps     95.95mV    203.3mV    36.99mV
130ps     43.83mV    117.7mV    16.06mV
153ps     15.33mV    45.23mV    5.368mV
186ps     3.808mV    11.21mV    1.364mV
411ps     485.3uV    423.2uV    338.6uV
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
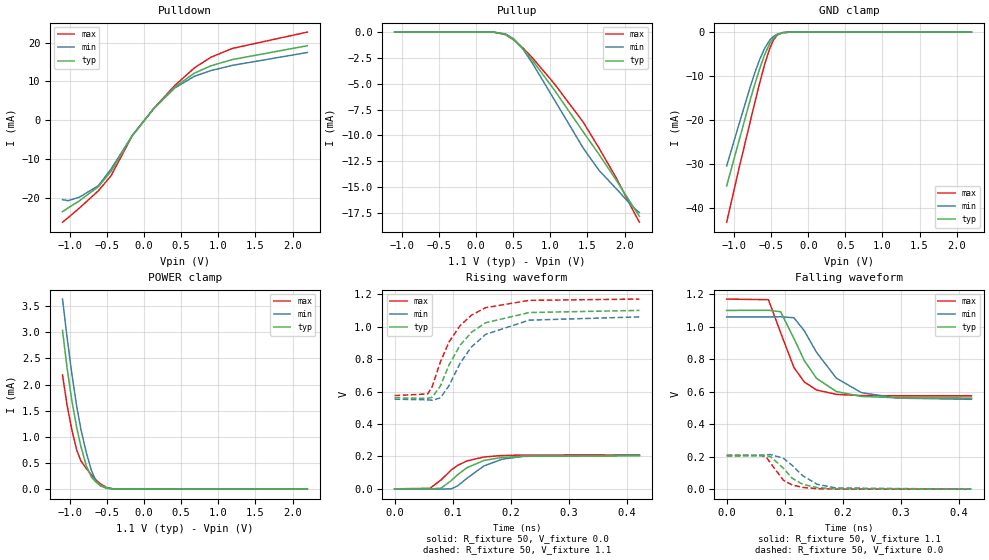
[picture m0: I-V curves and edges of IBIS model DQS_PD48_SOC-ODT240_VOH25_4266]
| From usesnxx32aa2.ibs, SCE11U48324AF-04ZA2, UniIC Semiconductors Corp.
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| DQS_PD48_SOC-ODT240_VOH25_4266
| (48 Ohm Pulldown, 240 Ohm System ODT Setting, VOH=VDDQ/2.5, 3200-4266Mbps)
[Model]   DQS_PD48_SOC-ODT240_VOH25_4266
Model_type   I/O
Vinl = 160.000mV
Vinh = 280.000mV
Vmeas = 220.000mV
Vref = 0.0mV
Cref = 0.0pF
Rref = 240.000Ohm
|   typ   min   max
|C_comp   0.838pF   0.788pF   0.888pF
C_comp_pullup   0.4190pF   0.3940pF   0.4440pF
C_comp_pulldown   0.4190pF   0.3940pF   0.4440pF
| Note: C_comp changes when the ODT circuit is enabled.
[Model Spec]
| Input threshold voltage corners
Vinl   0.1600V   0.1520V   0.1740V
Vinh   0.2800V   0.2720V   0.2940V
| Measurement voltage corners
Vmeas   0.2200V   0.2120V   0.2340V
| Timing spec test load voltage corners
Vref   0.0000V   0.0000V   0.0000V
| Dynamic Overshoot Parameters from LPDDR4 Specification
D_overshoot_ampl_h   0.30   NA   NA
D_overshoot_ampl_l   0.30   NA   NA
D_overshoot_area_h   0.1n   NA   NA
D_overshoot_area_l   0.1n   NA   NA
[Receiver Thresholds]
Vcross_low   = 160.0mV
Vcross_high  = 280.0mV
Vdiff_ac   = 120mV
Vdiff_dc   = 120mV
Tdiffslew_ac = 10.000ns |Not specified, so set to high value
[Voltage Range]   1.1000V   1.0600V   1.1700V
[Pullup Reference]   1.1000V   1.0600V   1.1700V
| Junction Temperature (Ambient temp is 35C typ 95C min -40C max)
[Temperature Range]   50.0   110.0   -40.0
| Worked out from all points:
|   slope of the pulldown table from 0 to 0.165 V, typ, clamps not added: 43.9 ohm
|   slope of the pullup table from 0 to 0.165 V, typ, clamps not added: 56.2 kohm
|   GND clamp passes 1 mA (typ) near -0.45 V on its own axis
|   POWER clamp passes 1 mA (typ) near -0.88 V on its own axis
|   rising waveform, R_fixture 50, V_fixture 0.0: 20-80 % time 48.5ps typ, 52.1ps min, 44.9ps max; typ from 0 V to 0.203 V
|   falling waveform, R_fixture 50, V_fixture 1.1: 20-80 % time 50.3ps typ, 62.5ps min, 40.2ps max; typ from 1.1 V to 0.561 V
|   rising waveform, R_fixture 50, V_fixture 1.1: 20-80 % time 59.2ps typ, 63.4ps min, 54.5ps max; typ from 0.561 V to 1.1 V
|   falling waveform, R_fixture 50, V_fixture 0.0: 20-80 % time 33.5ps typ, 41.3ps min, 28.6ps max; typ from 0.203 V to 0 V
[Pulldown]
|   Voltage   I(typ)   I(min)   I(max)
-1.1V     -23.65mA   -20.55mA   -26.37mA
-1.024V   -22.68mA   -20.81mA   -25.2mA
-872.3mV  -20.85mA   -19.92mA   -22.71mA
-614.9mV  -17.17mA   -16.92mA   -18.23mA
-443.3mV  -13.17mA   -12.57mA   -14.3mA
-159.5mV  -3.987mA   -3.972mA   -4.027mA
127.6mV   2.931mA    2.91mA     2.937mA
414.7mV   8.546mA    8.304mA    8.967mA
678.7mV   12.13mA    11.32mA    13.49mA
899.8mV   14.01mA    12.77mA    16.23mA
1.19V     15.63mA    14.13mA    18.5mA
2.2V      19.2mA     17.45mA    22.72mA
[GND Clamp]
|   Voltage   I(typ)   I(min)   I(max)
-1.1V     -34.89mA   -30.35mA   -43.14mA
-938.3mV  -24.93mA   -21.15mA   -31.25mA
-793.1mV  -15.99mA   -13.01mA   -21.07mA
-723.8mV  -11.98mA   -9.379mA   -16.19mA
-664.4mV  -8.771mA   -6.596mA   -12.13mA
-588.5mV  -5.131mA   -3.688mA   -7.335mA
-519.2mV  -2.57mA    -1.835mA   -3.675mA
-466.4mV  -1.296mA   -943.1uA   -1.696mA
-413.6mV  -565.1uA   -416.3uA   -621.9uA
-344.3mV  -143.2uA   -110.1uA   -124.3uA
-242mV    -9.996uA   -9.424uA   -5.61uA
2.2V      0A         0A         0A
[Pullup]
|   Voltage   I(typ)   I(min)   I(max)
-1.1V     1.371uA    2.481uA    454.4nA
246.4mV   -15.54uA   -15.59uA   -14.91uA
394.9mV   -211.7uA   -175.7uA   -251.7uA
510.4mV   -747.6uA   -678.5uA   -775.6uA
625.9mV   -1.587mA   -1.613mA   -1.506mA
757.9mV   -2.738mA   -3.016mA   -2.487mA
1.052V    -5.592mA   -6.54mA    -4.991mA
1.444V    -9.68mA    -11.25mA   -8.737mA
1.659V    -11.88mA   -13.42mA   -11.28mA
1.887V    -14.33mA   -15.16mA   -14.11mA
2.114V    -16.89mA   -16.95mA   -17.27mA
2.2V      -17.84mA   -17.48mA   -18.41mA
[POWER Clamp]
|   Voltage   I(typ)   I(min)   I(max)
-1.1V     3.036mA    3.636mA    2.186mA
-1.041V   2.347mA    2.931mA    1.626mA
-974.6mV  1.695mA    2.208mA    1.139mA
-908.6mV  1.178mA    1.583mA    747.9uA
-852.5mV  818.6uA    1.149mA    543.8uA
-779.9mV  448uA      701.7uA    396.3uA
-710.6mV  232.2uA    359.3uA    273.1uA
-651.2mV  138.6uA    162.3uA    181.2uA
-591.8mV  77.92uA    64.82uA    105.6uA
-502.7mV  22.59uA    13.96uA    29.26uA
-397.1mV  2.383uA    1.584uA    2.118uA
2.2V      0A         0A         0A
[Ramp]
|   typ   min   max
| 20% - 80%
dV/dt_r   121.83m/48.45p   124.17m/52.15p   125.60m/44.89p
dV/dt_f   323.21m/50.28p   304.22m/62.49p   357.15m/40.13p
| 25% - 75%
|dV/dt_r   101.52m/38.50p   103.47m/41.55p   104.67m/35.64p
|dV/dt_f   269.34m/40.09p   253.51m/49.85p   297.63m/31.93p
R_load = 50
[Rising Waveform]
R_fixture = 50
V_fixture = 0.0
|   Time   V(typ)   V(min)   V(max)
0s        194.9uV    141uV      144.8uV
61ps      -641.6uV   157.5uV    3.121mV
80ps      3.963mV    -2.015mV   54.82mV
98ps      51.8mV     416.5uV    117.5mV
109ps     88.23mV    19.14mV    145.3mV
125ps     131mV      65.99mV    172.4mV
154ps     175mV      141.2mV    196.4mV
185ps     193.6mV    182.4mV    205.3mV
222ps     200.7mV    200.3mV    208.4mV
422ps     203.2mV    207.1mV    209.5mV
[Falling Waveform]
R_fixture   = 50
V_fixture   = 1.1
V_fixture_min = 1.06
V_fixture_max = 1.17
|   Time   V(typ)   V(min)   V(max)
0s        1.1V       1.06V      1.17V
72ps      1.101V     1.06V      1.166V
93ps      1.092V     1.061V     963.3mV
116ps     926.8mV    1.055V     748.2mV
134ps     790.2mV    973.6mV    659mV
155ps     681.8mV    841.7mV    610.4mV
189ps     601mV      683.5mV    583.6mV
232ps     570.9mV    594.5mV    576.2mV
294ps     562.5mV    560.4mV    574.9mV
422ps     561.3mV    553mV      574.7mV
[Rising Waveform]
R_fixture   = 50
V_fixture   = 1.1
V_fixture_min = 1.06
V_fixture_max = 1.17
|   Time   V(typ)   V(min)   V(max)
0s        561.2mV    552.6mV    574.7mV
57ps      557.8mV    548.6mV    585.1mV
65ps      565.1mV    546.4mV    631.6mV
79ps      634.8mV    560.7mV    783.6mV
94ps      765.6mV    637.5mV    906.2mV
113ps     886.1mV    775.4mV    1.007V
133ps     966.6mV    876.8mV    1.072V
157ps     1.024V     952.3mV    1.117V
232ps     1.087V     1.04V      1.162V
422ps     1.1V       1.06V      1.17V
[Falling Waveform]
R_fixture = 50
V_fixture = 0.0
|   Time   V(typ)   V(min)   V(max)
0s        203.3mV    207.2mV    209.5mV
60ps      205.6mV    209.3mV    208.3mV
69ps      205.1mV    211.9mV    193.5mV
76ps      199.8mV    212.9mV    158.6mV
98ps      127.7mV    189.6mV    54.07mV
113ps     67.35mV    146.6mV    25.9mV
131ps     29.91mV    83.12mV    10.86mV
156ps     9.811mV    29.95mV    3.346mV
189ps     2.452mV    7.648mV    833uV
422ps     265.8uV    241.3uV    175.7uV
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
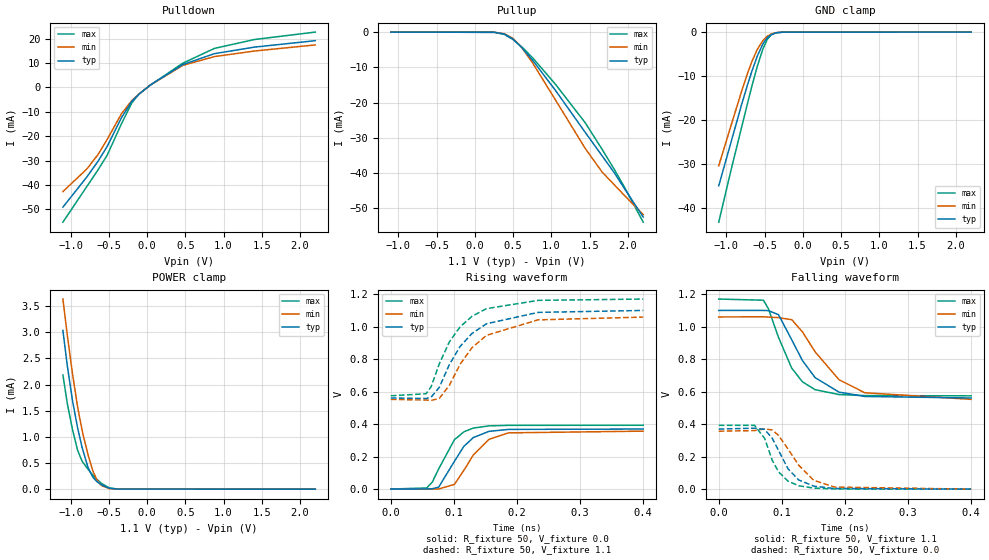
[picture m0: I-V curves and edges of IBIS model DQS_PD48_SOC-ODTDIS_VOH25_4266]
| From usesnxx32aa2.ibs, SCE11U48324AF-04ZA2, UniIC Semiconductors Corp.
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| DQS_PD48_SOC-ODTDIS_VOH25_4266
| (48 Ohm Pulldown, SOC ODT disabled setting, VOH=VDDQ/2.5 cal. point, 3200-4266Mbps)
[Model]   DQS_PD48_SOC-ODTDIS_VOH25_4266
Model_type   I/O
Vinl = 160.000mV
Vinh = 280.000mV
Vmeas = 220.000mV
Vref = 0.0mV
Cref = 0.0pF
|   typ   min   max
|C_comp   0.838pF   0.788pF   0.888pF
C_comp_pullup   0.4190pF   0.3940pF   0.4440pF
C_comp_pulldown   0.4190pF   0.3940pF   0.4440pF
| Note: C_comp changes when the ODT circuit is enabled.
[Model Spec]
| Input threshold voltage corners
Vinl   0.1600V   0.1520V   0.1740V
Vinh   0.2800V   0.2720V   0.2940V
| Measurement voltage corners
Vmeas   0.2200V   0.2120V   0.2340V
| Timing spec test load voltage corners
Vref   0.0000V   0.0000V   0.0000V
| Dynamic Overshoot Parameters from LPDDR4 Specification
D_overshoot_ampl_h   0.30   NA   NA
D_overshoot_ampl_l   0.30   NA   NA
D_overshoot_area_h   0.1n   NA   NA
D_overshoot_area_l   0.1n   NA   NA
[Receiver Thresholds]
Vcross_low   = 160.0mV
Vcross_high  = 280.0mV
Vdiff_ac   = 120mV
Vdiff_dc   = 120mV
Tdiffslew_ac = 10.000ns |Not specified, so set to high value
[Voltage Range]   1.1000V   1.0600V   1.1700V
[Pullup Reference]   1.1000V   1.0600V   1.1700V
| Junction Temperature (Ambient temp is 35C typ 95C min -40C max)
[Temperature Range]   50.0   110.0   -40.0
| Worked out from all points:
|   slope of the pulldown table from 0 to 0.165 V, typ, clamps not added: 43.7 ohm
|   slope of the pullup table from 0 to 0.165 V, typ, clamps not added: 18.1 kohm
|   GND clamp passes 1 mA (typ) near -0.45 V on its own axis
|   POWER clamp passes 1 mA (typ) near -0.88 V on its own axis
|   rising waveform, R_fixture 50, V_fixture 0.0: 20-80 % time 35.6ps typ, 39.1ps min, 32.6ps max; typ from 0.001 V to 0.37 V
|   falling waveform, R_fixture 50, V_fixture 1.1: 20-80 % time 50.7ps typ, 63.3ps min, 40.5ps max; typ from 1.1 V to 0.561 V
|   rising waveform, R_fixture 50, V_fixture 1.1: 20-80 % time 58.6ps typ, 61.6ps min, 54.2ps max; typ from 0.561 V to 1.1 V
|   falling waveform, R_fixture 50, V_fixture 0.0: 20-80 % time 33.8ps typ, 41.2ps min, 28.2ps max; typ from 0.37 V to 0.001 V
[Pulldown]
|   Voltage   I(typ)   I(min)   I(max)
-1.1V     -49.08mA   -42.68mA   -55.23mA
-786.5mV  -36.67mA   -33.42mA   -40.58mA
-641.3mV  -30.26mA   -27.51mA   -33.81mA
-522.5mV  -24.24mA   -21.38mA   -27.85mA
-334.4mV  -12.38mA   -10.77mA   -14.9mA
-199.1mV  -5.68mA    -5.361mA   -6.295mA
-103.4mV  -2.668mA   -2.622mA   -2.685mA
45.1mV    1.049mA    1.046mA    1.047mA
467.5mV   9.39mA     9.064mA    9.963mA
880mV     13.87mA    12.66mA    16.02mA
1.405V    16.56mA    14.96mA    19.68mA
2.2V      19.2mA     17.45mA    22.72mA
[GND Clamp]
|   Voltage   I(typ)   I(min)   I(max)
-1.1V     -34.89mA   -30.35mA   -43.14mA
-938.3mV  -24.93mA   -21.15mA   -31.25mA
-803mV    -16.57mA   -13.55mA   -21.77mA
-727.1mV  -12.17mA   -9.543mA   -16.42mA
-667.7mV  -8.943mA   -6.741mA   -12.35mA
-595.1mV  -5.418mA   -3.907mA   -7.727mA
-522.5mV  -2.67mA    -1.908mA   -3.825mA
-466.4mV  -1.296mA   -945uA     -1.697mA
-413.6mV  -565uA     -418.7uA   -622.8uA
-350.9mV  -167.2uA   -126.1uA   -147.1uA
-251.9mV  -13.55uA   -12.1uA    -8.035uA
2.2V      0A         0A         0A
[Pullup]
|   Voltage   I(typ)   I(min)   I(max)
-1.1V     4.112uA    7.441uA    1.363uA
256.3mV   -56.73uA   -56.34uA   -56.81uA
385mV     -549.6uA   -458.8uA   -658.1uA
497.2mV   -1.985mA   -1.773mA   -2.091mA
609.4mV   -4.304mA   -4.305mA   -4.133mA
751.3mV   -7.908mA   -8.649mA   -7.214mA
1.055V    -16.59mA   -19.32mA   -14.85mA
1.441V    -28.41mA   -32.96mA   -25.69mA
1.662V    -35.07mA   -39.67mA   -33.22mA
1.824V    -39.95mA   -43.35mA   -39.01mA
1.956V    -44.42mA   -46.36mA   -44.02mA
2.2V      -52.46mA   -51.75mA   -53.91mA
[POWER Clamp]
|   Voltage   I(typ)   I(min)   I(max)
-1.1V     3.036mA    3.636mA    2.186mA
-1.041V   2.347mA    2.931mA    1.626mA
-974.6mV  1.695mA    2.208mA    1.139mA
-908.6mV  1.178mA    1.582mA    748uA
-849.2mV  799.4uA    1.126mA    535.6uA
-773.3mV  421uA      665.7uA    384.1uA
-710.6mV  232.2uA    359.1uA    273.1uA
-654.5mV  142.7uA    170.4uA    185.9uA
-595.1mV  80.76uA    68.31uA    109.2uA
-492.8mV  18.9uA     11.62uA    24.03uA
-383.9mV  1.747uA    1.216uA    1.478uA
2.2V      0A         0A         0A
[Ramp]
|   typ   min   max
| 20% - 80%
dV/dt_r   221.54m/35.61p   213.90m/39.07p   235.61m/32.63p
dV/dt_f   323.18m/50.74p   304.15m/63.27p   357.16m/40.47p
| 25% - 75%
|dV/dt_r   184.62m/28.35p   178.25m/31.15p   196.35m/25.90p
|dV/dt_f   269.32m/40.42p   253.46m/50.47p   297.63m/32.15p
R_load = 50
[Rising Waveform]
R_fixture = 50
V_fixture = 0.0
|   Time   V(typ)   V(min)   V(max)
0s        642.3uV    519.4uV    470.7uV
57ps      735.3uV    120.2uV    7.266mV
66ps      2.659mV    -230.8uV   43.72mV
76ps      12.15mV    1.01mV     124.4mV
101ps     171mV      29.03mV    303.9mV
116ps     262.9mV    115mV      352.6mV
131ps     317.2mV    210.2mV    375.8mV
156ps     355.7mV    306.7mV    389.4mV
187ps     367.6mV    346.4mV    392.7mV
401ps     369.9mV    357mV      393.2mV
[Falling Waveform]
R_fixture   = 50
V_fixture   = 1.1
V_fixture_min = 1.06
V_fixture_max = 1.17
|   Time   V(typ)   V(min)   V(max)
0s        1.1V       1.06V      1.17V
71ps      1.1V       1.061V     1.163V
79ps      1.099V     1.059V     1.11V
95ps      1.074V     1.056V     933.9mV
116ps     919.1mV    1.043V     745mV
133ps     791.8mV    968.3mV    661mV
153ps     687.1mV    846mV      612.7mV
191ps     597.6mV    674.2mV    582.6mV
232ps     570.8mV    593.6mV    576.2mV
401ps     561.4mV    553.1mV    574.7mV
[Rising Waveform]
R_fixture   = 50
V_fixture   = 1.1
V_fixture_min = 1.06
V_fixture_max = 1.17
|   Time   V(typ)   V(min)   V(max)
0s        561.2mV    552.6mV    574.7mV
56ps      557.8mV    548.4mV    587mV
64ps      566mV      545.9mV    630.1mV
77ps      626.5mV    558.4mV    771.2mV
93ps      766.6mV    639mV      906.2mV
110ps     877.9mV    768.2mV    998.7mV
129ps     958.5mV    870.6mV    1.064V
152ps     1.018V     946.8mV    1.111V
234ps     1.088V     1.042V     1.162V
401ps     1.1V       1.059V     1.17V
[Falling Waveform]
R_fixture = 50
V_fixture = 0.0
|   Time   V(typ)   V(min)   V(max)
0s        370mV      357.1mV    393.2mV
57ps      375.9mV    360.9mV    392.9mV
73ps      367.8mV    371.7mV    312.2mV
85ps      313.7mV    364.7mV    178.7mV
95ps      239.1mV    331.4mV    107mV
110ps     126.4mV    247.8mV    50.15mV
127ps     57.29mV    148.2mV    21.56mV
151ps     19.01mV    54.72mV    6.917mV
184ps     4.685mV    13.39mV    1.764mV
401ps     689.7uV    589uV      492.7uV
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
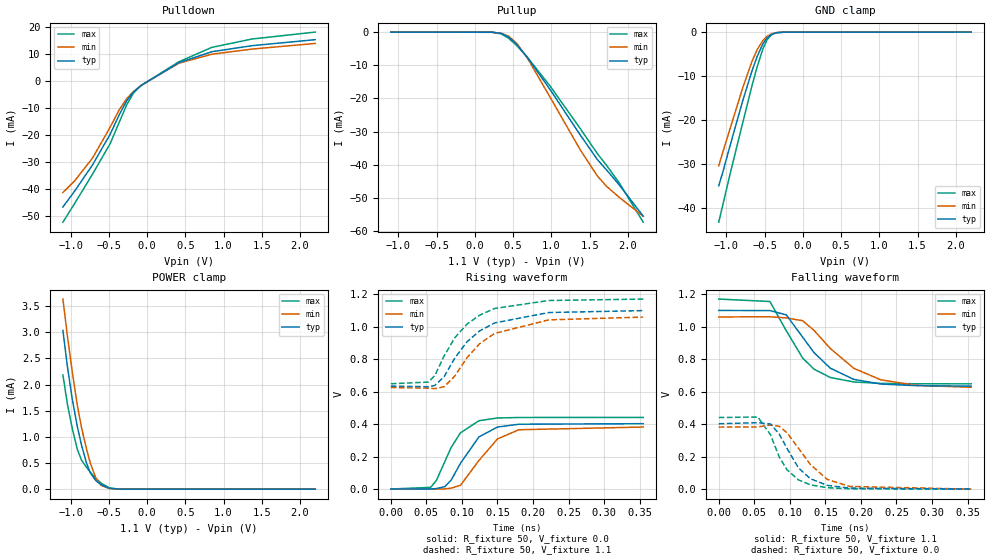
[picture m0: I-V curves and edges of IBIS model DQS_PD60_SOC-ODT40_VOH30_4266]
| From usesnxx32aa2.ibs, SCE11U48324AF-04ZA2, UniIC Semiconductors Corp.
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| DQS_PD60_SOC-ODT40_VOH30_4266
| (60 Ohm Pulldown, 40 Ohm System ODT Setting, VOH=VDDQ/3.0, 3200-4266Mbps)
[Model]   DQS_PD60_SOC-ODT40_VOH30_4266
Model_type   I/O
Vinl = 123.333mV
Vinh = 243.333mV
Vmeas = 183.333mV
Vref = 0.0mV
Cref = 0.0pF
Rref = 40.000Ohm
|   typ   min   max
|C_comp   0.838pF   0.788pF   0.888pF
C_comp_pullup   0.4190pF   0.3940pF   0.4440pF
C_comp_pulldown   0.4190pF   0.3940pF   0.4440pF
| Note: C_comp changes when the ODT circuit is enabled.
[Model Spec]
| Input threshold voltage corners
Vinl   0.1233V   0.1167V   0.1350V
Vinh   0.2433V   0.2367V   0.2550V
| Measurement voltage corners
Vmeas   0.1833V   0.1767V   0.1950V
| Timing spec test load voltage corners
Vref   0.0000V   0.0000V   0.0000V
| Dynamic Overshoot Parameters from LPDDR4 Specification
D_overshoot_ampl_h   0.30   NA   NA
D_overshoot_ampl_l   0.30   NA   NA
D_overshoot_area_h   0.1n   NA   NA
D_overshoot_area_l   0.1n   NA   NA
[Receiver Thresholds]
Vcross_low   = 123.3mV
Vcross_high  = 243.3mV
Vdiff_ac   = 120mV
Vdiff_dc   = 120mV
Tdiffslew_ac = 10.000ns |Not specified, so set to high value
[Voltage Range]   1.1000V   1.0600V   1.1700V
[Pullup Reference]   1.1000V   1.0600V   1.1700V
| Junction Temperature (Ambient temp is 35C typ 95C min -40C max)
[Temperature Range]   50.0   110.0   -40.0
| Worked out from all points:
|   slope of the pulldown table from 0 to 0.165 V, typ, clamps not added: 54.7 ohm
|   slope of the pullup table from 0 to 0.165 V, typ, clamps not added: 13 kohm
|   GND clamp passes 1 mA (typ) near -0.45 V on its own axis
|   POWER clamp passes 1 mA (typ) near -0.88 V on its own axis
|   rising waveform, R_fixture 50, V_fixture 0.0: 20-80 % time 35.7ps typ, 39.6ps min, 31.1ps max; typ from 0.001 V to 0.403 V
|   falling waveform, R_fixture 50, V_fixture 1.1: 20-80 % time 55.7ps typ, 67.7ps min, 45.1ps max; typ from 1.1 V to 0.634 V
|   rising waveform, R_fixture 50, V_fixture 1.1: 20-80 % time 57.7ps typ, 59.8ps min, 54.8ps max; typ from 0.634 V to 1.1 V
|   falling waveform, R_fixture 50, V_fixture 0.0: 20-80 % time 36.1ps typ, 43.3ps min, 31.4ps max; typ from 0.403 V to 0.001 V
[Pulldown]
|   Voltage   I(typ)   I(min)   I(max)
-1.1V     -46.55mA   -41.2mA    -52.18mA
-948.2mV  -40.75mA   -36.95mA   -45.34mA
-713.9mV  -31.04mA   -28.5mA    -34.44mA
-482.9mV  -19.69mA   -17.06mA   -23.17mA
-364.1mV  -12.46mA   -10.62mA   -15.25mA
-265.1mV  -7.232mA   -6.429mA   -8.721mA
-176mV    -3.995mA   -3.802mA   -4.37mA
-77mV     -1.588mA   -1.568mA   -1.58mA
414.7mV   6.827mA    6.638mA    7.153mA
847mV     10.89mA    9.975mA    12.5mA
1.375V    13.14mA    11.88mA    15.61mA
2.2V      15.36mA    13.96mA    18.16mA
[GND Clamp]
|   Voltage   I(typ)   I(min)   I(max)
-1.1V     -34.88mA   -30.35mA   -43.13mA
-1.047V   -31.79mA   -27.25mA   -39.23mA
-944.9mV  -25.34mA   -21.53mA   -31.71mA
-786.5mV  -15.59mA   -12.65mA   -20.59mA
-664.4mV  -8.768mA   -6.598mA   -12.12mA
-595.1mV  -5.418mA   -3.908mA   -7.72mA
-522.5mV  -2.674mA   -1.908mA   -3.823mA
-469.7mV  -1.362mA   -986.7uA   -1.79mA
-413.6mV  -567uA     -418uA     -620.7uA
-350.9mV  -166.9uA   -125.9uA   -146.9uA
-238.7mV  -9.051uA   -8.516uA   -4.978uA
2.2V      0A         0A         0A
[Pullup]
|   Voltage   I(typ)   I(min)   I(max)
-1.1V     6.284uA    9.684uA    2.832uA
226.6mV   -42.29uA   -43.33uA   -42.8uA
342.1mV   -380.9uA   -314.4uA   -525uA
441.1mV   -1.491mA   -1.225mA   -1.868mA
546.7mV   -3.719mA   -3.405mA   -4.061mA
685.3mV   -7.623mA   -7.826mA   -7.562mA
982.3mV   -17.31mA   -19.6mA    -16.25mA
1.378V    -31.03mA   -35.51mA   -29.11mA
1.599V    -38.35mA   -43.31mA   -36.57mA
1.718V    -41.46mA   -46.41mA   -40.06mA
1.88V     -45.85mA   -49.67mA   -45.22mA
2.2V      -55.46mA   -55.5mA    -57.28mA
[POWER Clamp]
|   Voltage   I(typ)   I(min)   I(max)
-1.1V     3.036mA    3.636mA    2.186mA
-1.041V   2.347mA    2.931mA    1.626mA
-977.9mV  1.724mA    2.242mA    1.161mA
-911.9mV  1.201mA    1.611mA    764.3uA
-855.8mV  838.1uA    1.172mA    552.2uA
-789.8mV  491.1uA    757.2uA    414.8uA
-740.3mV  306.1uA    494.4uA    324.3uA
-667.7mV  159.9uA    206.1uA    205.2uA
-598.4mV  83.68uA    71.99uA    113uA
-492.8mV  18.93uA    11.63uA    24.06uA
-374mV    1.394uA    1.002uA    1.122uA
2.2V      0A         0A         0A
[Ramp]
|   typ   min   max
| 20% - 80%
dV/dt_r   241.29m/35.69p   228.84m/39.62p   264.40m/31.13p
dV/dt_f   279.40m/55.69p   259.56m/67.75p   312.93m/45.10p
| 25% - 75%
|dV/dt_r   201.07m/28.48p   190.70m/31.58p   220.33m/24.70p
|dV/dt_f   232.84m/44.38p   216.30m/54.05p   260.77m/35.84p
R_load = 50
[Rising Waveform]
R_fixture = 50
V_fixture = 0.0
|   Time   V(typ)   V(min)   V(max)
0s        704.3uV    616.3uV    509.3uV
56ps      487.3uV    -55.95uV   10.57mV
64ps      3.079mV    -518.3uV   52.55mV
76ps      14.94mV    1.57mV     169.5mV
85ps      55.96mV    5.7mV      257.6mV
98ps      159mV      23.5mV     346.5mV
124ps     321.4mV    176.3mV    420.9mV
150ps     381.8mV    308.8mV    437.8mV
180ps     399.3mV    365.4mV    440.8mV
355ps     402.8mV    382mV      441.2mV
[Falling Waveform]
R_fixture   = 50
V_fixture   = 1.1
V_fixture_min = 1.06
V_fixture_max = 1.17
|   Time   V(typ)   V(min)   V(max)
0s        1.1V       1.06V      1.17V
72ps      1.099V     1.061V     1.155V
95ps      1.073V     1.054V     975.2mV
118ps     935.9mV    1.037V     807.4mV
134ps     840.9mV    977.4mV    738.7mV
157ps     744.5mV    865.6mV    687.4mV
190ps     675.8mV    744.1mV    660mV
228ps     647.3mV    673.1mV    651.3mV
278ps     637.1mV    639mV      648.9mV
355ps     634.3mV    627.4mV    648.5mV
[Rising Waveform]
R_fixture   = 50
V_fixture   = 1.1
V_fixture_min = 1.06
V_fixture_max = 1.17
|   Time   V(typ)   V(min)   V(max)
0s        634mV      625.3mV    648.4mV
53ps      630.2mV    621.5mV    658.9mV
62ps      638.4mV    618.5mV    700mV
75ps      692.3mV    630.3mV    819.8mV
90ps      806.8mV    695.9mV    932mV
107ps     906.4mV    808.3mV    1.015V
125ps     974.1mV    895.6mV    1.071V
146ps     1.023V     958.6mV    1.112V
222ps     1.087V     1.042V     1.161V
355ps     1.099V     1.059V     1.17V
[Falling Waveform]
R_fixture = 50
V_fixture = 0.0
|   Time   V(typ)   V(min)   V(max)
0s        403mV      382.2mV    441.3mV
55ps      409.4mV    383.4mV    444.4mV
73ps      401.2mV    395.2mV    334mV
85ps      340.4mV    387.4mV    199.3mV
96ps      251.6mV    347.7mV    120mV
112ps     132.3mV    253mV      58.01mV
129ps     64.28mV    151.3mV    27.08mV
153ps     23.68mV    59.74mV    9.571mV
184ps     6.948mV    17.46mV    2.797mV
355ps     760uV      722.7uV    529.1uV
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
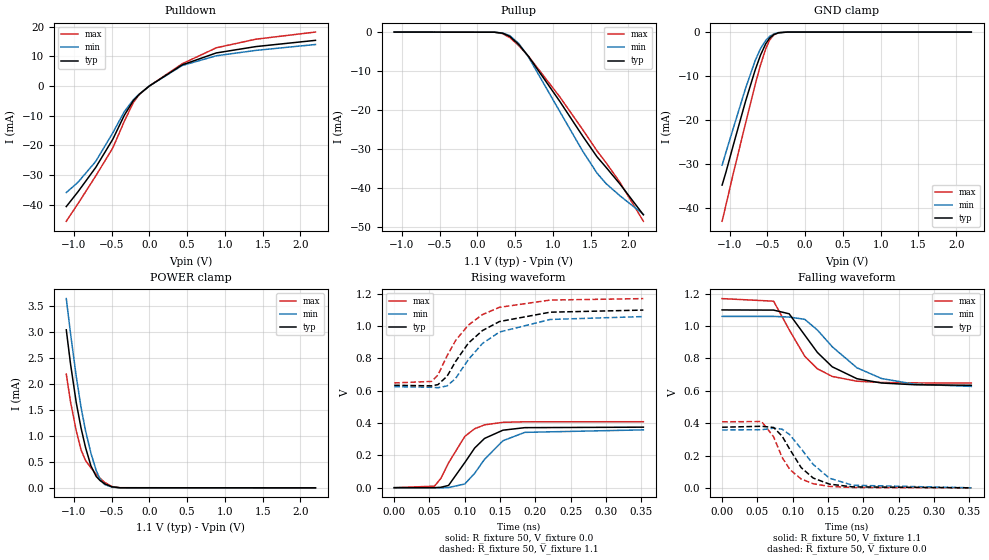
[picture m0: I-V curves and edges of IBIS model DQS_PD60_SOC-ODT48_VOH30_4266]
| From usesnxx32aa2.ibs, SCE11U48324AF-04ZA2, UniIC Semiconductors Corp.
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| DQS_PD60_SOC-ODT48_VOH30_4266
| (60 Ohm Pulldown, 48 Ohm System ODT Setting, VOH=VDDQ/3.0, 3200-4266Mbps)
[Model]   DQS_PD60_SOC-ODT48_VOH30_4266
Model_type   I/O
Vinl = 123.333mV
Vinh = 243.333mV
Vmeas = 183.333mV
Vref = 0.0mV
Cref = 0.0pF
Rref = 48.000Ohm
|   typ   min   max
|C_comp   0.838pF   0.788pF   0.888pF
C_comp_pullup   0.4190pF   0.3940pF   0.4440pF
C_comp_pulldown   0.4190pF   0.3940pF   0.4440pF
| Note: C_comp changes when the ODT circuit is enabled.
[Model Spec]
| Input threshold voltage corners
Vinl   0.1233V   0.1167V   0.1350V
Vinh   0.2433V   0.2367V   0.2550V
| Measurement voltage corners
Vmeas   0.1833V   0.1767V   0.1950V
| Timing spec test load voltage corners
Vref   0.0000V   0.0000V   0.0000V
| Dynamic Overshoot Parameters from LPDDR4 Specification
D_overshoot_ampl_h   0.30   NA   NA
D_overshoot_ampl_l   0.30   NA   NA
D_overshoot_area_h   0.1n   NA   NA
D_overshoot_area_l   0.1n   NA   NA
[Receiver Thresholds]
Vcross_low   = 123.3mV
Vcross_high  = 243.3mV
Vdiff_ac   = 120mV
Vdiff_dc   = 120mV
Tdiffslew_ac = 10.000ns |Not specified, so set to high value
[Voltage Range]   1.1000V   1.0600V   1.1700V
[Pullup Reference]   1.1000V   1.0600V   1.1700V
| Junction Temperature (Ambient temp is 35C typ 95C min -40C max)
[Temperature Range]   50.0   110.0   -40.0
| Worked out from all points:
|   slope of the pulldown table from 0 to 0.165 V, typ, clamps not added: 54.8 ohm
|   slope of the pullup table from 0 to 0.165 V, typ, clamps not added: 15.4 kohm
|   GND clamp passes 1 mA (typ) near -0.45 V on its own axis
|   POWER clamp passes 1 mA (typ) near -0.88 V on its own axis
|   rising waveform, R_fixture 50, V_fixture 0.0: 20-80 % time 37.2ps typ, 41.5ps min, 32.9ps max; typ from 0.001 V to 0.375 V
|   falling waveform, R_fixture 50, V_fixture 1.1: 20-80 % time 55.5ps typ, 67.4ps min, 44.9ps max; typ from 1.1 V to 0.634 V
|   rising waveform, R_fixture 50, V_fixture 1.1: 20-80 % time 57.9ps typ, 60.5ps min, 54.8ps max; typ from 0.634 V to 1.1 V
|   falling waveform, R_fixture 50, V_fixture 0.0: 20-80 % time 36ps typ, 43.3ps min, 31.3ps max; typ from 0.375 V to 0.001 V
[Pulldown]
|   Voltage   I(typ)   I(min)   I(max)
-1.1V     -40.65mA   -35.93mA   -45.61mA
-944.9mV  -35.66mA   -32.47mA   -39.67mA
-710.6mV  -27.49mA   -25.45mA   -30.37mA
-482.9mV  -17.92mA   -15.77mA   -20.85mA
-331.1mV  -9.879mA   -8.642mA   -11.9mA
-212.3mV  -4.968mA   -4.669mA   -5.599mA
-133.1mV  -2.807mA   -2.748mA   -2.886mA
0V        -23.83uA   -21.04uA   -16.99uA
434.5mV   7.085mA    6.873mA    7.455mA
886.6mV   11.12mA    10.16mA    12.85mA
1.411V    13.26mA    11.98mA    15.75mA
2.2V      15.36mA    13.96mA    18.16mA
[GND Clamp]
|   Voltage   I(typ)   I(min)   I(max)
-1.1V     -34.88mA   -30.34mA   -43.13mA
-1.05V    -31.99mA   -27.44mA   -39.47mA
-948.2mV  -25.55mA   -21.71mA   -31.95mA
-789.8mV  -15.79mA   -12.83mA   -20.82mA
-661.1mV  -8.597mA   -6.455mA   -11.9mA
-591.8mV  -5.272mA   -3.798mA   -7.524mA
-522.5mV  -2.672mA   -1.906mA   -3.823mA
-469.7mV  -1.359mA   -993.7uA   -1.79mA
-416.9mV  -597.2uA   -441.2uA   -665.6uA
-354.2mV  -178.5uA   -135uA     -159.7uA
-238.7mV  -9.075uA   -8.646uA   -5.057uA
2.2V      0A         0A         0A
[Pullup]
|   Voltage   I(typ)   I(min)   I(max)
-1.1V     5.237uA    8.07uA     2.361uA
229.9mV   -38.08uA   -38.22uA   -38.8uA
335.5mV   -286.3uA   -237.2uA   -391.7uA
431.2mV   -1.119mA   -911.6uA   -1.419mA
550mV     -3.189mA   -2.931mA   -3.468mA
678.7mV   -6.235mA   -6.386mA   -6.196mA
1.091V    -17.68mA   -20.27mA   -16.53mA
1.395V    -26.59mA   -30.44mA   -24.93mA
1.586V    -31.93mA   -36.1mA    -30.4mA
1.702V    -34.53mA   -38.71mA   -33.34mA
1.89V     -38.9mA    -41.91mA   -38.47mA
2.2V      -46.77mA   -46.65mA   -48.43mA
[POWER Clamp]
|   Voltage   I(typ)   I(min)   I(max)
-1.1V     3.036mA    3.636mA    2.186mA
-1.044V   2.383mA    2.969mA    1.654mA
-968mV    1.637mA    2.141mA    1.095mA
-905.3mV  1.155mA    1.554mA    732.7uA
-845.9mV  780.3uA    1.103mA    527.5uA
-773.3mV  420.8uA    665.5uA    384.1uA
-704mV    218.9uA    332uA      262.2uA
-651.2mV  138.6uA    162.3uA    181.2uA
-591.8mV  77.94uA    64.85uA    105.5uA
-496.1mV  20.07uA    12.34uA    25.69uA
-390.5mV  2.043uA    1.408uA    1.76uA
2.2V      0A         0A         0A
[Ramp]
|   typ   min   max
| 20% - 80%
dV/dt_r   224.56m/37.22p   214.53m/41.53p   244.86m/32.90p
dV/dt_f   279.41m/55.48p   259.57m/67.44p   312.91m/44.90p
| 25% - 75%
|dV/dt_r   187.13m/29.68p   178.78m/33.12p   204.05m/26.15p
|dV/dt_f   232.84m/44.18p   216.31m/53.79p   260.76m/35.71p
R_load = 50
[Rising Waveform]
R_fixture = 50
V_fixture = 0.0
|   Time   V(typ)   V(min)   V(max)
0s        585.6uV    510.6uV    424uV
57ps      514.5uV    -45.65uV   9.948mV
66ps      2.971mV    -396.3uV   57.12mV
77ps      14.48mV    1.247mV    153.7mV
100ps     155.7mV    23.42mV    317.7mV
114ps     245.8mV    89.39mV    365.3mV
128ps     305.3mV    176.3mV    389.2mV
154ps     356.1mV    290.8mV    404.8mV
185ps     371.8mV    342.7mV    408.1mV
353ps     374.9mV    358.1mV    408.5mV
[Falling Waveform]
R_fixture   = 50
V_fixture   = 1.1
V_fixture_min = 1.06
V_fixture_max = 1.17
|   Time   V(typ)   V(min)   V(max)
0s        1.1V       1.06V      1.17V
73ps      1.099V     1.06V      1.154V
95ps      1.076V     1.056V     977.6mV
117ps     944.8mV    1.042V     814mV
135ps     837.1mV    975.9mV    736.1mV
156ps     748.5mV    872.4mV    689mV
191ps     674.9mV    742.4mV    659.5mV
226ps     648.3mV    675.9mV    651.5mV
273ps     637.5mV    640.9mV    649mV
353ps     634.3mV    627.4mV    648.5mV
[Rising Waveform]
R_fixture   = 50
V_fixture   = 1.1
V_fixture_min = 1.06
V_fixture_max = 1.17
|   Time   V(typ)   V(min)   V(max)
0s        634mV      625.3mV    648.4mV
53ps      630.4mV    621.7mV    657.7mV
62ps      638mV      618.8mV    697.6mV
75ps      690.3mV    630mV      817mV
87ps      781.4mV    676.4mV    911mV
105ps     894.3mV    792.6mV    1.006V
125ps     972.3mV    892.3mV    1.071V
149ps     1.028V     963.1mV    1.116V
221ps     1.086V     1.041V     1.161V
353ps     1.099V     1.059V     1.17V
[Falling Waveform]
R_fixture = 50
V_fixture = 0.0
|   Time   V(typ)   V(min)   V(max)
0s        375mV      358.2mV    408.6mV
56ps      380.9mV    359.6mV    410.2mV
73ps      373.5mV    369.2mV    315.5mV
85ps      319.9mV    362.7mV    188.5mV
96ps      237.8mV    328.2mV    113.5mV
112ps     125.4mV    242mV      54.95mV
129ps     61.04mV    145.6mV    25.63mV
152ps     23.35mV    60.19mV    9.364mV
185ps     6.344mV    16.34mV    2.516mV
353ps     655uV      624.7uV    448.4uV
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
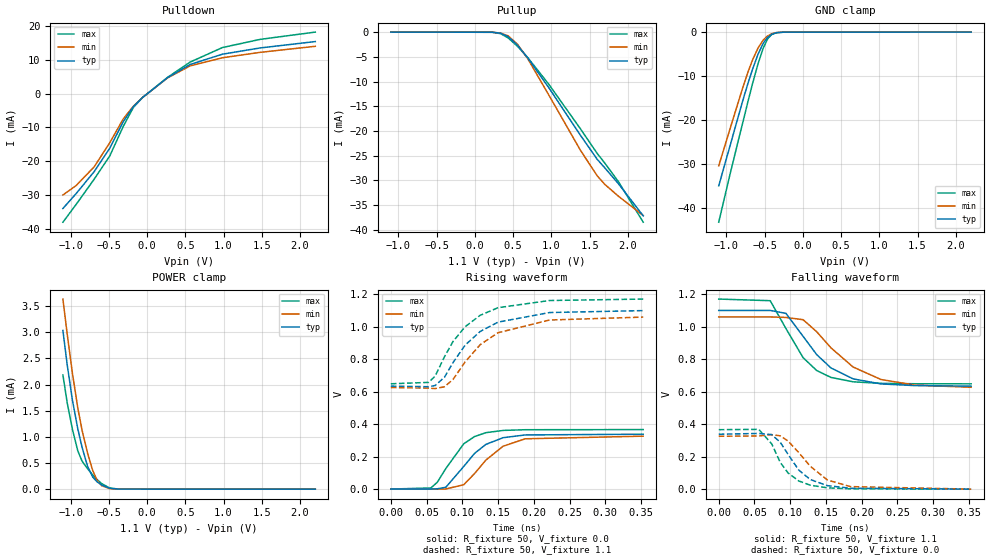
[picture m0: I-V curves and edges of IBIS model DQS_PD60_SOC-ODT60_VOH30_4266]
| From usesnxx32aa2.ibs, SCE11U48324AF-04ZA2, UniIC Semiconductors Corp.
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| DQS_PD60_SOC-ODT60_VOH30_4266
| (60 Ohm Pulldown, 60 Ohm System ODT Setting, VOH=VDDQ/3.0, 3200-4266Mbps)
[Model]   DQS_PD60_SOC-ODT60_VOH30_4266
Model_type   I/O
Vinl = 123.333mV
Vinh = 243.333mV
Vmeas = 183.333mV
Vref = 0.0mV
Cref = 0.0pF
Rref = 60.000Ohm
|   typ   min   max
|C_comp   0.838pF   0.788pF   0.888pF
C_comp_pullup   0.4190pF   0.3940pF   0.4440pF
C_comp_pulldown   0.4190pF   0.3940pF   0.4440pF
| Note: C_comp changes when the ODT circuit is enabled.
[Model Spec]
| Input threshold voltage corners
Vinl   0.1233V   0.1167V   0.1350V
Vinh   0.2433V   0.2367V   0.2550V
| Measurement voltage corners
Vmeas   0.1833V   0.1767V   0.1950V
| Timing spec test load voltage corners
Vref   0.0000V   0.0000V   0.0000V
| Dynamic Overshoot Parameters from LPDDR4 Specification
D_overshoot_ampl_h   0.30   NA   NA
D_overshoot_ampl_l   0.30   NA   NA
D_overshoot_area_h   0.1n   NA   NA
D_overshoot_area_l   0.1n   NA   NA
[Receiver Thresholds]
Vcross_low   = 123.3mV
Vcross_high  = 243.3mV
Vdiff_ac   = 120mV
Vdiff_dc   = 120mV
Tdiffslew_ac = 10.000ns |Not specified, so set to high value
[Voltage Range]   1.1000V   1.0600V   1.1700V
[Pullup Reference]   1.1000V   1.0600V   1.1700V
| Junction Temperature (Ambient temp is 35C typ 95C min -40C max)
[Temperature Range]   50.0   110.0   -40.0
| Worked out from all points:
|   slope of the pulldown table from 0 to 0.165 V, typ, clamps not added: 54.8 ohm
|   slope of the pullup table from 0 to 0.165 V, typ, clamps not added: 19.5 kohm
|   GND clamp passes 1 mA (typ) near -0.45 V on its own axis
|   POWER clamp passes 1 mA (typ) near -0.88 V on its own axis
|   rising waveform, R_fixture 50, V_fixture 0.0: 20-80 % time 40.7ps typ, 44.5ps min, 35.9ps max; typ from 0 V to 0.338 V
|   falling waveform, R_fixture 50, V_fixture 1.1: 20-80 % time 55.3ps typ, 67.2ps min, 44.8ps max; typ from 1.1 V to 0.634 V
|   rising waveform, R_fixture 50, V_fixture 1.1: 20-80 % time 58.1ps typ, 61.4ps min, 54.7ps max; typ from 0.634 V to 1.1 V
|   falling waveform, R_fixture 50, V_fixture 0.0: 20-80 % time 35.8ps typ, 43.5ps min, 31.2ps max; typ from 0.338 V to 0.001 V
[Pulldown]
|   Voltage   I(typ)   I(min)   I(max)
-1.1V     -33.95mA   -29.97mA   -38mA
-928.4mV  -29.6mA    -27.2mA    -32.8mA
-690.8mV  -23.05mA   -21.64mA   -25.29mA
-486.2mV  -16.1mA    -14.49mA   -18.38mA
-311.3mV  -8.311mA   -7.498mA   -9.723mA
-179.3mV  -3.875mA   -3.754mA   -4.123mA
-57.2mV   -1.146mA   -1.14mA    -1.128mA
266.2mV   4.665mA    4.595mA    4.757mA
563.2mV   8.593mA    8.177mA    9.297mA
985.6mV   11.63mA    10.57mA    13.59mA
1.477V    13.47mA    12.17mA    16mA
2.2V      15.36mA    13.96mA    18.16mA
[GND Clamp]
|   Voltage   I(typ)   I(min)   I(max)
-1.1V     -34.88mA   -30.34mA   -43.13mA
-944.9mV  -25.34mA   -21.53mA   -31.71mA
-786.5mV  -15.59mA   -12.65mA   -20.59mA
-717.2mV  -11.61mA   -9.055mA   -15.72mA
-657.8mV  -8.426mA   -6.313mA   -11.68mA
-585.2mV  -4.986mA   -3.582mA   -7.135mA
-519.2mV  -2.57mA    -1.836mA   -3.672mA
-463.1mV  -1.236mA   -903.7uA   -1.602mA
-410.3mV  -534.5uA   -396.6uA   -581uA
-347.6mV  -155.1uA   -117.2uA   -137uA
-242mV    -10.02uA   -9.32uA    -5.698uA
2.2V      0A         0A         0A
[Pullup]
|   Voltage   I(typ)   I(min)   I(max)
-1.1V     4.189uA    6.456uA    1.888uA
229.9mV   -30.09uA   -30.6uA    -31.02uA
335.5mV   -227.6uA   -188.8uA   -313.1uA
434.5mV   -926.3uA   -757.4uA   -1.172mA
556.6mV   -2.66mA    -2.46mA    -2.874mA
691.9mV   -5.249mA   -5.417mA   -5.187mA
965.8mV   -11.24mA   -12.72mA   -10.55mA
1.378V    -20.83mA   -23.86mA   -19.53mA
1.599V    -25.73mA   -29.06mA   -24.54mA
1.698V    -27.45mA   -30.79mA   -26.48mA
1.877V    -30.67mA   -33.19mA   -30.26mA
2.2V      -37.14mA   -37.09mA   -38.43mA
[POWER Clamp]
|   Voltage   I(typ)   I(min)   I(max)
-1.1V     3.036mA    3.636mA    2.186mA
-1.044V   2.383mA    2.969mA    1.654mA
-974.6mV  1.695mA    2.208mA    1.139mA
-905.3mV  1.155mA    1.554mA    732.7uA
-849.2mV  799.4uA    1.126mA    535.6uA
-776.6mV  434.2uA    683.6uA    390.2uA
-710.6mV  232.2uA    359.2uA    273.1uA
-651.2mV  138.6uA    162.4uA    181.2uA
-591.8mV  77.91uA    64.83uA    105.5uA
-489.5mV  17.77uA    10.9uA     22.46uA
-370.7mV  1.284uA    942.5nA    1.033uA
2.2V      0A         0A         0A
[Ramp]
|   typ   min   max
| 20% - 80%
dV/dt_r   202.58m/40.70p   195.35m/44.49p   219.67m/35.94p
dV/dt_f   279.40m/55.37p   259.55m/67.16p   312.91m/44.85p
| 25% - 75%
|dV/dt_r   168.82m/32.45p   162.79m/35.51p   183.06m/28.53p
|dV/dt_f   232.83m/44.05p   216.30m/53.55p   260.76m/35.62p
R_load = 50
[Rising Waveform]
R_fixture = 50
V_fixture = 0.0
|   Time   V(typ)   V(min)   V(max)
0s        463.4uV    399.8uV    335.8uV
56ps      316.2uV    41.91uV    7.084mV
65ps      1.896mV    -339.1uV   42.07mV
77ps      11.46mV    949.5uV    127.2mV
102ps     139.5mV    26.97mV    278.9mV
117ps     219.6mV    95.32mV    323.4mV
133ps     275.3mV    178.8mV    347.4mV
157ps     316.6mV    263.9mV    361.3mV
188ps     333.5mV    309.8mV    365.6mV
353ps     338.1mV    326mV      366.5mV
[Falling Waveform]
R_fixture   = 50
V_fixture   = 1.1
V_fixture_min = 1.06
V_fixture_max = 1.17
|   Time   V(typ)   V(min)   V(max)
0s        1.1V       1.06V      1.17V
72ps      1.1V       1.06V      1.16V
94ps      1.082V     1.057V     988.7mV
118ps     940.5mV    1.043V     809.5mV
137ps     828.3mV    969.1mV    730.4mV
157ps     746mV      869.7mV    687.8mV
188ps     678.9mV    751.7mV    660.9mV
227ps     647.9mV    675mV      651.4mV
275ps     637.4mV    640.3mV    648.9mV
353ps     634.3mV    627.4mV    648.5mV
[Rising Waveform]
R_fixture   = 50
V_fixture   = 1.1
V_fixture_min = 1.06
V_fixture_max = 1.17
|   Time   V(typ)   V(min)   V(max)
0s        633.9mV    625.3mV    648.4mV
53ps      630.5mV    621.8mV    657.1mV
62ps      637.7mV    618.9mV    695.6mV
75ps      688.6mV    630mV      814.4mV
87ps      778.8mV    675.3mV    908.7mV
104ps     886.7mV    783.4mV    1V
125ps     970.6mV    889mV      1.07V
150ps     1.028V     962.8mV    1.117V
222ps     1.087V     1.041V     1.161V
353ps     1.099V     1.059V     1.17V
[Falling Waveform]
R_fixture = 50
V_fixture = 0.0
|   Time   V(typ)   V(min)   V(max)
0s        338.2mV    326.1mV    366.5mV
56ps      343.3mV    327.6mV    368.2mV
74ps      336.1mV    335.9mV    279.7mV
86ps      289.2mV    328.4mV    165.6mV
97ps      214.3mV    296.6mV    99.89mV
112ps     117.5mV    225mV      50.75mV
128ps     59.82mV    141.3mV    24.77mV
152ps     21.98mV    56.83mV    8.693mV
184ps     6.157mV    16.14mV    2.382mV
353ps     544.7uV    527.2uV    365.1uV
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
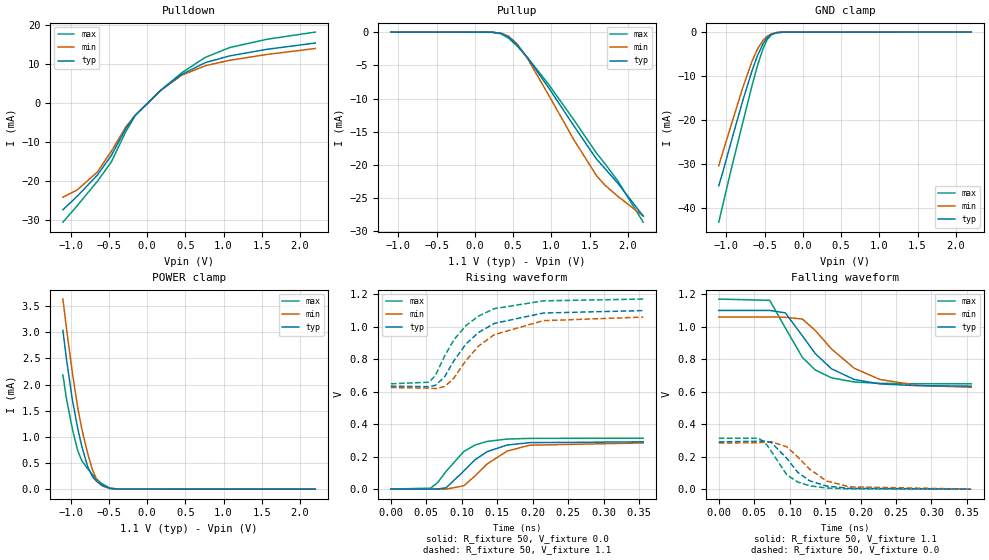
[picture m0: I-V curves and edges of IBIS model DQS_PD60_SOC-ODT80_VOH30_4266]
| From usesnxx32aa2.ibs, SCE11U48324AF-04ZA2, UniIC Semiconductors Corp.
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| DQS_PD60_SOC-ODT80_VOH30_4266
| (60 Ohm Pulldown, 80 Ohm System ODT Setting, VOH=VDDQ/3.0, 3200-4266Mbps)
[Model]   DQS_PD60_SOC-ODT80_VOH30_4266
Model_type   I/O
Vinl = 123.333mV
Vinh = 243.333mV
Vmeas = 183.333mV
Vref = 0.0mV
Cref = 0.0pF
Rref = 80.000Ohm
|   typ   min   max
|C_comp   0.838pF   0.788pF   0.888pF
C_comp_pullup   0.4190pF   0.3940pF   0.4440pF
C_comp_pulldown   0.4190pF   0.3940pF   0.4440pF
| Note: C_comp changes when the ODT circuit is enabled.
[Model Spec]
| Input threshold voltage corners
Vinl   0.1233V   0.1167V   0.1350V
Vinh   0.2433V   0.2367V   0.2550V
| Measurement voltage corners
Vmeas   0.1833V   0.1767V   0.1950V
| Timing spec test load voltage corners
Vref   0.0000V   0.0000V   0.0000V
| Dynamic Overshoot Parameters from LPDDR4 Specification
D_overshoot_ampl_h   0.30   NA   NA
D_overshoot_ampl_l   0.30   NA   NA
D_overshoot_area_h   0.1n   NA   NA
D_overshoot_area_l   0.1n   NA   NA
[Receiver Thresholds]
Vcross_low   = 123.3mV
Vcross_high  = 243.3mV
Vdiff_ac   = 120mV
Vdiff_dc   = 120mV
Tdiffslew_ac = 10.000ns |Not specified, so set to high value
[Voltage Range]   1.1000V   1.0600V   1.1700V
[Pullup Reference]   1.1000V   1.0600V   1.1700V
| Junction Temperature (Ambient temp is 35C typ 95C min -40C max)
[Temperature Range]   50.0   110.0   -40.0
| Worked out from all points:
|   slope of the pulldown table from 0 to 0.165 V, typ, clamps not added: 54.9 ohm
|   slope of the pullup table from 0 to 0.165 V, typ, clamps not added: 26 kohm
|   GND clamp passes 1 mA (typ) near -0.45 V on its own axis
|   POWER clamp passes 1 mA (typ) near -0.88 V on its own axis
|   rising waveform, R_fixture 50, V_fixture 0.0: 20-80 % time 44.4ps typ, 47.4ps min, 38.9ps max; typ from 0 V to 0.291 V
|   falling waveform, R_fixture 50, V_fixture 1.1: 20-80 % time 55.1ps typ, 66.9ps min, 44.7ps max; typ from 1.1 V to 0.634 V
|   rising waveform, R_fixture 50, V_fixture 1.1: 20-80 % time 58.2ps typ, 62.1ps min, 54.9ps max; typ from 0.634 V to 1.1 V
|   falling waveform, R_fixture 50, V_fixture 0.0: 20-80 % time 36.4ps typ, 44.1ps min, 31.8ps max; typ from 0.291 V to 0 V
[Pulldown]
|   Voltage   I(typ)   I(min)   I(max)
-1.1V     -27.4mA    -24.16mA   -30.57mA
-915.2mV  -23.96mA   -22.33mA   -26.39mA
-651.2mV  -18.54mA   -17.74mA   -20.12mA
-466.4mV  -13.46mA   -12.39mA   -15.12mA
-278.3mV  -6.578mA   -6.17mA    -7.377mA
-152.9mV  -3.144mA   -3.103mA   -3.218mA
180.4mV   3.257mA    3.226mA    3.281mA
451mV     7.295mA    7.062mA    7.703mA
761.2mV   10.33mA    9.539mA    11.67mA
1.081V    12.06mA    10.93mA    14.2mA
1.573V    13.76mA    12.44mA    16.34mA
2.2V      15.36mA    13.96mA    18.16mA
[GND Clamp]
|   Voltage   I(typ)   I(min)   I(max)
-1.1V     -34.88mA   -30.35mA   -43.13mA
-1.047V   -31.79mA   -27.25mA   -39.23mA
-938.3mV  -24.92mA   -21.15mA   -31.24mA
-786.5mV  -15.59mA   -12.65mA   -20.59mA
-664.4mV  -8.768mA   -6.598mA   -12.12mA
-591.8mV  -5.271mA   -3.798mA   -7.523mA
-519.2mV  -2.571mA   -1.839mA   -3.672mA
-466.4mV  -1.297mA   -942.7uA   -1.694mA
-410.3mV  -534.1uA   -395.9uA   -581.4uA
-344.3mV  -143.4uA   -109.5uA   -125.1uA
-251.9mV  -13.34uA   -12.06uA   -7.921uA
2.2V      0A         0A         0A
[Pullup]
|   Voltage   I(typ)   I(min)   I(max)
-1.1V     3.142uA    4.844uA    1.416uA
229.9mV   -22.58uA   -23.09uA   -23.3uA
342.1mV   -190.6uA   -157.8uA   -262.8uA
441.1mV   -747.9uA   -614.3uA   -936.2uA
550mV     -1.908mA   -1.754mA   -2.076mA
688.6mV   -3.881mA   -3.997mA   -3.841mA
962.5mV   -8.363mA   -9.458mA   -7.852mA
1.292V    -14.09mA   -16.18mA   -13.19mA
1.589V    -19.11mA   -21.6mA    -18.21mA
1.695V    -20.47mA   -22.99mA   -19.73mA
1.867V    -22.74mA   -24.71mA   -22.38mA
2.2V      -27.69mA   -27.68mA   -28.61mA
[POWER Clamp]
|   Voltage   I(typ)   I(min)   I(max)
-1.1V     3.036mA    3.636mA    2.186mA
-1.054V   2.493mA    3.084mA    1.737mA
-977.9mV  1.724mA    2.242mA    1.161mA
-905.3mV  1.155mA    1.554mA    732.9uA
-852.5mV  818.5uA    1.149mA    543.7uA
-776.6mV  434.2uA    683.5uA    390.2uA
-713.9mV  239.2uA    373.1uA    278.6uA
-657.8mV  146.8uA    178.8uA    190.7uA
-595.1mV  80.79uA    68.31uA    109.2uA
-486.2mV  16.73uA    10.22uA    21.06uA
-374mV    1.381uA    990.6nA    1.129uA
2.2V      0A         0A         0A
[Ramp]
|   typ   min   max
| 20% - 80%
dV/dt_r   174.46m/44.40p   170.45m/47.41p   187.87m/38.94p
dV/dt_f   279.41m/55.15p   259.56m/66.88p   312.91m/44.71p
| 25% - 75%
|dV/dt_r   145.39m/35.38p   142.04m/37.76p   156.56m/30.93p
|dV/dt_f   232.84m/43.90p   216.30m/53.32p   260.76m/35.53p
R_load = 50
[Rising Waveform]
R_fixture = 50
V_fixture = 0.0
|   Time   V(typ)   V(min)   V(max)
0s        341.8uV    288.9uV    249uV
56ps      71.23uV    163.2uV    5.551mV
66ps      602.8uV    -427.7uV   39.44mV
78ps      8.326mV    -211uV     109.3mV
103ps     111.4mV    20.44mV    231.8mV
119ps     181.3mV    81.77mV    271.8mV
136ps     231mV      155.1mV    293.8mV
164ps     271.2mV    234mV      308mV
196ps     286.1mV    270.3mV    312.2mV
356ps     291.1mV    284.4mV    313.4mV
[Falling Waveform]
R_fixture   = 50
V_fixture   = 1.1
V_fixture_min = 1.06
V_fixture_max = 1.17
|   Time   V(typ)   V(min)   V(max)
0s        1.1V       1.06V      1.17V
72ps      1.1V       1.06V      1.162V
94ps      1.085V     1.058V     991.8mV
118ps     943.5mV    1.047V     811mV
136ps     835.4mV    977.7mV    734.3mV
159ps     741.1mV    863.2mV    685.4mV
191ps     675.3mV    744.7mV    659.9mV
227ps     648mV      675.6mV    651.5mV
280ps     636.9mV    638.8mV    648.9mV
356ps     634.3mV    627.4mV    648.5mV
[Rising Waveform]
R_fixture   = 50
V_fixture   = 1.1
V_fixture_min = 1.06
V_fixture_max = 1.17
|   Time   V(typ)   V(min)   V(max)
0s        633.9mV    625.3mV    648.4mV
54ps      630.7mV    621.6mV    658.1mV
63ps      638.7mV    619mV      700.1mV
76ps      692.5mV    631.3mV    820.5mV
89ps      790.6mV    683.9mV    919.2mV
106ps     893.7mV    792.1mV    1.007V
124ps     965.4mV    881.6mV    1.066V
146ps     1.02V      951mV      1.111V
215ps     1.084V     1.037V     1.159V
356ps     1.099V     1.059V     1.17V
[Falling Waveform]
R_fixture = 50
V_fixture = 0.0
|   Time   V(typ)   V(min)   V(max)
0s        291.2mV    284.5mV    313.4mV
56ps      295.2mV    285.6mV    313.6mV
65ps      296.2mV    289.5mV    289.4mV
74ps      287.5mV    292.3mV    233.8mV
96ps      190.3mV    261mV      88.41mV
111ps     105.9mV    200.8mV    45.16mV
128ps     52.19mV    124mV      21.25mV
152ps     19.42mV    50.6mV     7.417mV
184ps     5.422mV    14.65mV    2.01mV
356ps     427.1uV    424.7uV    279.5uV
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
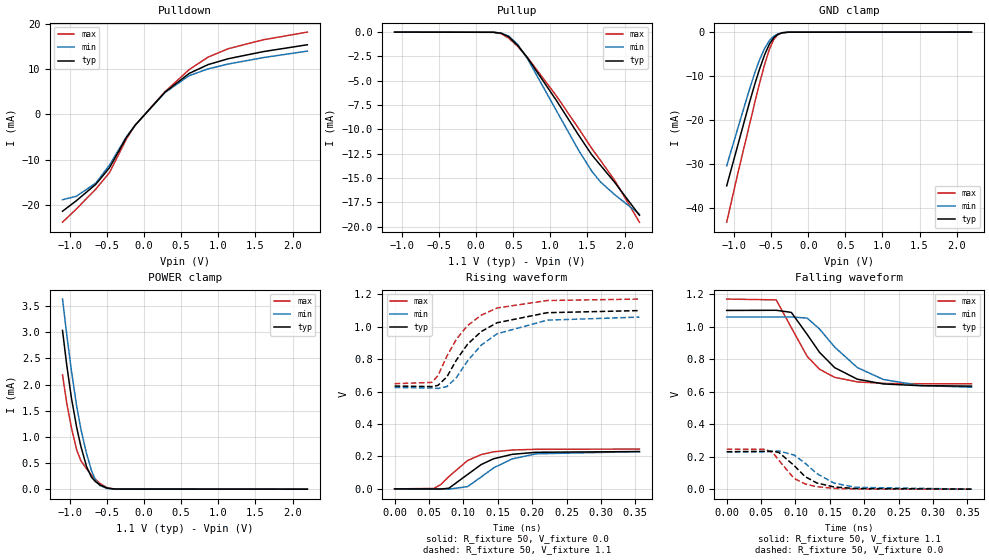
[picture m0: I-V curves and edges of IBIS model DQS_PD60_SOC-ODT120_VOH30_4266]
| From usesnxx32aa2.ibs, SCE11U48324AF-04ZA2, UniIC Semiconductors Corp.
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| DQS_PD60_SOC-ODT120_VOH30_4266
| (60 Ohm Pulldown, 120 Ohm System ODT Setting, VOH=VDDQ/3.0, 3200-4266Mbps)
[Model]   DQS_PD60_SOC-ODT120_VOH30_4266
Model_type   I/O
Vinl = 123.333mV
Vinh = 243.333mV
Vmeas = 183.333mV
Vref = 0.0mV
Cref = 0.0pF
Rref = 120.000Ohm
|   typ   min   max
|C_comp   0.838pF   0.788pF   0.888pF
C_comp_pullup   0.4190pF   0.3940pF   0.4440pF
C_comp_pulldown   0.4190pF   0.3940pF   0.4440pF
| Note: C_comp changes when the ODT circuit is enabled.
[Model Spec]
| Input threshold voltage corners
Vinl   0.1233V   0.1167V   0.1350V
Vinh   0.2433V   0.2367V   0.2550V
| Measurement voltage corners
Vmeas   0.1833V   0.1767V   0.1950V
| Timing spec test load voltage corners
Vref   0.0000V   0.0000V   0.0000V
| Dynamic Overshoot Parameters from LPDDR4 Specification
D_overshoot_ampl_h   0.30   NA   NA
D_overshoot_ampl_l   0.30   NA   NA
D_overshoot_area_h   0.1n   NA   NA
D_overshoot_area_l   0.1n   NA   NA
[Receiver Thresholds]
Vcross_low   = 123.3mV
Vcross_high  = 243.3mV
Vdiff_ac   = 120mV
Vdiff_dc   = 120mV
Tdiffslew_ac = 10.000ns |Not specified, so set to high value
[Voltage Range]   1.1000V   1.0600V   1.1700V
[Pullup Reference]   1.1000V   1.0600V   1.1700V
| Junction Temperature (Ambient temp is 35C typ 95C min -40C max)
[Temperature Range]   50.0   110.0   -40.0
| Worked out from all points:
|   slope of the pulldown table from 0 to 0.165 V, typ, clamps not added: 55 ohm
|   slope of the pullup table from 0 to 0.165 V, typ, clamps not added: 39.2 kohm
|   GND clamp passes 1 mA (typ) near -0.45 V on its own axis
|   POWER clamp passes 1 mA (typ) near -0.88 V on its own axis
|   rising waveform, R_fixture 50, V_fixture 0.0: 20-80 % time 48.4ps typ, 52.4ps min, 43.2ps max; typ from 0 V to 0.23 V
|   falling waveform, R_fixture 50, V_fixture 1.1: 20-80 % time 54.9ps typ, 66.6ps min, 44.5ps max; typ from 1.1 V to 0.634 V
|   rising waveform, R_fixture 50, V_fixture 1.1: 20-80 % time 58.5ps typ, 62.6ps min, 54.6ps max; typ from 0.634 V to 1.1 V
|   falling waveform, R_fixture 50, V_fixture 0.0: 20-80 % time 36.2ps typ, 43.6ps min, 31.6ps max; typ from 0.231 V to 0 V
[Pulldown]
|   Voltage   I(typ)   I(min)   I(max)
-1.1V     -21.38mA   -18.84mA   -23.8mA
-915.2mV  -19.08mA   -18.08mA   -20.91mA
-651.2mV  -15.44mA   -15.17mA   -16.49mA
-466.4mV  -11.77mA   -11.18mA   -12.85mA
-238.7mV  -5.091mA   -4.958mA   -5.414mA
-119.9mV  -2.378mA   -2.374mA   -2.368mA
279.4mV   4.872mA    4.795mA    4.979mA
606.1mV   9.029mA    8.529mA    9.862mA
863.5mV   10.99mA    10.05mA    12.65mA
1.134V    12.28mA    11.11mA    14.49mA
1.606V    13.85mA    12.53mA    16.46mA
2.2V      15.36mA    13.96mA    18.16mA
[GND Clamp]
|   Voltage   I(typ)   I(min)   I(max)
-1.1V     -34.88mA   -30.34mA   -43.13mA
-944.9mV  -25.34mA   -21.53mA   -31.71mA
-799.7mV  -16.37mA   -13.37mA   -21.52mA
-720.5mV  -11.79mA   -9.217mA   -15.95mA
-661.1mV  -8.596mA   -6.454mA   -11.9mA
-588.5mV  -5.128mA   -3.689mA   -7.329mA
-522.5mV  -2.671mA   -1.907mA   -3.823mA
-466.4mV  -1.296mA   -943.7uA   -1.693mA
-413.6mV  -564uA     -416.5uA   -622.2uA
-354.2mV  -178uA     -134.9uA   -160.1uA
-265.1mV  -19.36uA   -16.78uA   -12.28uA
2.2V      0A         0A         0A
[Pullup]
|   Voltage   I(typ)   I(min)   I(max)
-1.1V     2.095uA    3.229uA    944.4nA
233.2mV   -16.25uA   -16.28uA   -16.91uA
335.5mV   -114uA     -94.74uA   -157uA
437.8mV   -483.5uA   -396.4uA   -608.9uA
559.9mV   -1.371mA   -1.275mA   -1.475mA
695.2mV   -2.689mA   -2.789mA   -2.648mA
1.078V    -6.994mA   -8.033mA   -6.53mA
1.378V    -10.56mA   -12.12mA   -9.881mA
1.556V    -12.6mA    -14.28mA   -11.94mA
1.675V    -13.69mA   -15.4mA    -13.19mA
1.867V    -15.45mA   -16.71mA   -15.25mA
2.2V      -18.83mA   -18.72mA   -19.54mA
[POWER Clamp]
|   Voltage   I(typ)   I(min)   I(max)
-1.1V     3.036mA    3.636mA    2.186mA
-1.044V   2.383mA    2.97mA     1.654mA
-981.2mV  1.754mA    2.277mA    1.184mA
-908.6mV  1.178mA    1.583mA    748.4uA
-852.5mV  818.6uA    1.149mA    543.8uA
-776.6mV  434.3uA    683.6uA    390.2uA
-710.6mV  232.2uA    359.2uA    273.1uA
-657.8mV  146.8uA    178.8uA    190.7uA
-595.1mV  80.75uA    68.33uA    109.3uA
-499.4mV  21.28uA    13.16uA    27.48uA
-397.1mV  2.365uA    1.593uA    2.116uA
2.2V      0A         0A         0A
[Ramp]
|   typ   min   max
| 20% - 80%
dV/dt_r   138.12m/48.41p   137.72m/52.42p   147.33m/43.23p
dV/dt_f   279.37m/54.89p   259.55m/66.64p   312.90m/44.50p
| 25% - 75%
|dV/dt_r   115.10m/38.61p   114.77m/41.87p   122.77m/34.33p
|dV/dt_f   232.81m/43.76p   216.29m/53.23p   260.75m/35.43p
R_load = 50
[Rising Waveform]
R_fixture = 50
V_fixture = 0.0
|   Time   V(typ)   V(min)   V(max)
0s        220.3uV    180.1uV    161.5uV
57ps      -262.1uV   211.4uV    2.944mV
67ps      -886.1uV   -580.3uV   26.71mV
79ps      4.39mV     -1.506mV   76.39mV
106ps     88.62mV    14.03mV    174.6mV
126ps     150.4mV    73.8mV     211.7mV
144ps     185.9mV    129.7mV    228.7mV
171ps     213.2mV    185.1mV    239.8mV
206ps     225.8mV    216.4mV    244.2mV
356ps     230.4mV    229.7mV    245.7mV
[Falling Waveform]
R_fixture   = 50
V_fixture   = 1.1
V_fixture_min = 1.06
V_fixture_max = 1.17
|   Time   V(typ)   V(min)   V(max)
0s        1.1V       1.06V      1.17V
72ps      1.101V     1.06V      1.165V
94ps      1.088V     1.06V      994.1mV
117ps     952.5mV    1.053V     817.7mV
135ps     842mV      985.7mV    738mV
157ps     748mV      874.6mV    688.4mV
190ps     676.9mV    748.4mV    660.3mV
228ps     647.7mV    674.7mV    651.3mV
281ps     637mV      638.5mV    648.8mV
356ps     634.4mV    627.4mV    648.5mV
[Rising Waveform]
R_fixture   = 50
V_fixture   = 1.1
V_fixture_min = 1.06
V_fixture_max = 1.17
|   Time   V(typ)   V(min)   V(max)
0s        633.9mV    625.2mV    648.4mV
54ps      630.7mV    621.7mV    656.4mV
63ps      637.9mV    619.2mV    697.5mV
76ps      690.3mV    630.5mV    817.9mV
90ps      795.1mV    687.2mV    923.5mV
106ps     891.4mV    788.5mV    1.006V
126ps     970mV      886.3mV    1.071V
149ps     1.024V     955.9mV    1.115V
222ps     1.086V     1.04V      1.161V
356ps     1.099V     1.059V     1.17V
[Falling Waveform]
R_fixture = 50
V_fixture = 0.0
|   Time   V(typ)   V(min)   V(max)
0s        230.5mV    229.8mV    245.8mV
57ps      233.1mV    230.5mV    245.4mV
68ps      233.1mV    233.6mV    221.1mV
76ps      225.7mV    234.8mV    176.6mV
98ps      145.9mV    210.3mV    66.32mV
114ps     77.51mV    160.1mV    32.56mV
131ps     38.4mV     96.2mV     15.33mV
156ps     13.78mV    37.62mV    5.184mV
187ps     4.032mV    11.45mV    1.486mV
356ps     305.3uV    314uV      193.5uV
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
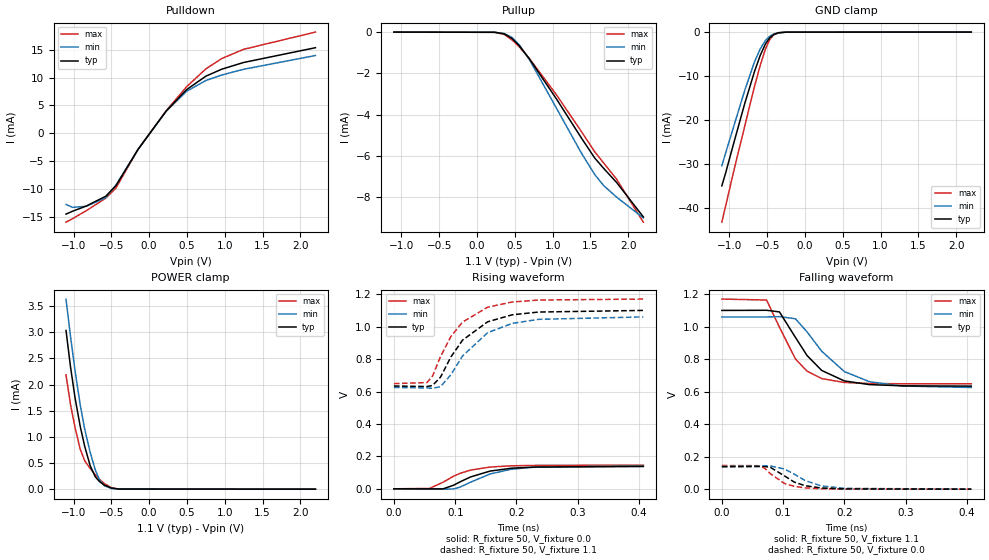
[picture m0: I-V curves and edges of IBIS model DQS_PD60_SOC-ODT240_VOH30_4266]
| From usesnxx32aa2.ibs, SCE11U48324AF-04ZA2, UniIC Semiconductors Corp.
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| DQS_PD60_SOC-ODT240_VOH30_4266
| (60 Ohm Pulldown, 240 Ohm System ODT Setting, VOH=VDDQ/3.0, 3200-4266Mbps)
[Model]   DQS_PD60_SOC-ODT240_VOH30_4266
Model_type   I/O
Vinl = 123.333mV
Vinh = 243.333mV
Vmeas = 183.333mV
Vref = 0.0mV
Cref = 0.0pF
Rref = 240.000Ohm
|   typ   min   max
|C_comp   0.838pF   0.788pF   0.888pF
C_comp_pullup   0.4190pF   0.3940pF   0.4440pF
C_comp_pulldown   0.4190pF   0.3940pF   0.4440pF
| Note: C_comp changes when the ODT circuit is enabled.
[Model Spec]
| Input threshold voltage corners
Vinl   0.1233V   0.1167V   0.1350V
Vinh   0.2433V   0.2367V   0.2550V
| Measurement voltage corners
Vmeas   0.1833V   0.1767V   0.1950V
| Timing spec test load voltage corners
Vref   0.0000V   0.0000V   0.0000V
| Dynamic Overshoot Parameters from LPDDR4 Specification
D_overshoot_ampl_h   0.30   NA   NA
D_overshoot_ampl_l   0.30   NA   NA
D_overshoot_area_h   0.1n   NA   NA
D_overshoot_area_l   0.1n   NA   NA
[Receiver Thresholds]
Vcross_low   = 123.3mV
Vcross_high  = 243.3mV
Vdiff_ac   = 120mV
Vdiff_dc   = 120mV
Tdiffslew_ac = 10.000ns |Not specified, so set to high value
[Voltage Range]   1.1000V   1.0600V   1.1700V
[Pullup Reference]   1.1000V   1.0600V   1.1700V
| Junction Temperature (Ambient temp is 35C typ 95C min -40C max)
[Temperature Range]   50.0   110.0   -40.0
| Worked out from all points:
|   slope of the pulldown table from 0 to 0.165 V, typ, clamps not added: 55.1 ohm
|   slope of the pullup table from 0 to 0.165 V, typ, clamps not added: 77.7 kohm
|   GND clamp passes 1 mA (typ) near -0.45 V on its own axis
|   POWER clamp passes 1 mA (typ) near -0.88 V on its own axis
|   rising waveform, R_fixture 50, V_fixture 0.0: 20-80 % time 57.8ps typ, 60.2ps min, 51ps max; typ from 0 V to 0.138 V
|   falling waveform, R_fixture 50, V_fixture 1.1: 20-80 % time 54.8ps typ, 66.9ps min, 44.4ps max; typ from 1.1 V to 0.634 V
|   rising waveform, R_fixture 50, V_fixture 1.1: 20-80 % time 59.1ps typ, 63.7ps min, 54.7ps max; typ from 0.634 V to 1.1 V
|   falling waveform, R_fixture 50, V_fixture 0.0: 20-80 % time 36.5ps typ, 44.3ps min, 32.5ps max; typ from 0.138 V to 0 V
[Pulldown]
|   Voltage   I(typ)   I(min)   I(max)
-1.1V     -14.48mA   -12.74mA   -15.93mA
-1.014V   -13.97mA   -13.27mA   -15.3mA
-829.4mV  -13.02mA   -13.07mA   -13.85mA
-575.3mV  -11.29mA   -11.53mA   -11.63mA
-440mV    -9.389mA   -9.306mA   -9.828mA
-146.3mV  -2.865mA   -2.877mA   -2.849mA
226.6mV   4.028mA    3.978mA    4.083mA
497.2mV   7.857mA    7.557mA    8.379mA
751.3mV   10.26mA    9.484mA    11.57mA
959.2mV   11.5mA     10.46mA    13.41mA
1.25V     12.71mA    11.49mA    15.07mA
2.2V      15.36mA    13.96mA    18.16mA
[GND Clamp]
|   Voltage   I(typ)   I(min)   I(max)
-1.1V     -34.88mA   -30.33mA   -43.13mA
-1.05V    -31.99mA   -27.44mA   -39.47mA
-948.2mV  -25.55mA   -21.71mA   -31.95mA
-796.4mV  -16.18mA   -13.19mA   -21.29mA
-667.7mV  -8.94mA    -6.742mA   -12.34mA
-591.8mV  -5.271mA   -3.798mA   -7.524mA
-522.5mV  -2.672mA   -1.906mA   -3.823mA
-466.4mV  -1.298mA   -945.2uA   -1.694mA
-413.6mV  -566.8uA   -418.4uA   -620.7uA
-350.9mV  -167uA     -126.8uA   -146.8uA
-242mV    -10.02uA   -9.164uA   -5.606uA
2.2V      0A         0A         0A
[Pullup]
|   Voltage   I(typ)   I(min)   I(max)
-1.1V     1.047uA    1.615uA    471.8nA
233.2mV   -8.147uA   -8.219uA   -8.43uA
358.6mV   -82.65uA   -67.24uA   -113.8uA
464.2mV   -314.5uA   -264uA     -381uA
559.9mV   -671.3uA   -622.3uA   -724.5uA
691.9mV   -1.294mA   -1.331mA   -1.282mA
1.048V    -3.231mA   -3.677mA   -3.031mA
1.378V    -5.127mA   -5.857mA   -4.815mA
1.556V    -6.109mA   -6.911mA   -5.805mA
1.675V    -6.614mA   -7.448mA   -6.356mA
1.847V    -7.302mA   -8.014mA   -7.145mA
2.2V      -8.971mA   -9.018mA   -9.226mA
[POWER Clamp]
|   Voltage   I(typ)   I(min)   I(max)
-1.1V     3.036mA    3.636mA    2.186mA
-1.041V   2.347mA    2.931mA    1.626mA
-981.2mV  1.754mA    2.277mA    1.183mA
-911.9mV  1.201mA    1.611mA    764.9uA
-852.5mV  818.5uA    1.149mA    543.6uA
-779.9mV  448.2uA    701.7uA    396.3uA
-713.9mV  239.3uA    373.1uA    278.6uA
-657.8mV  146.8uA    178.9uA    190.7uA
-595.1mV  80.76uA    68.32uA    109.3uA
-499.4mV  21.34uA    13.22uA    27.44uA
-400.4mV  2.587uA    1.704uA    2.312uA
2.2V      0A         0A         0A
[Ramp]
|   typ   min   max
| 20% - 80%
dV/dt_r   82.48m/57.79p   84.27m/60.19p   87.27m/50.96p
dV/dt_f   279.50m/54.79p   260.44m/66.85p   312.92m/44.42p
| 25% - 75%
|dV/dt_r   68.74m/46.05p   70.22m/47.98p   72.73m/40.45p
|dV/dt_f   232.91m/43.73p   217.03m/53.37p   260.77m/35.34p
R_load = 50
[Rising Waveform]
R_fixture = 50
V_fixture = 0.0
|   Time   V(typ)   V(min)   V(max)
0s        95.34uV    66.69uV    71.21uV
58ps      -533.6uV   192.4uV    2.226mV
80ps      -425.8uV   -2.251mV   40.11mV
97ps      21.49mV    -940.2uV   77.11mV
108ps     42.97mV    10.37mV    95.46mV
125ps     73.07mV    40.66mV    115.3mV
157ps     109.3mV    91.61mV    134.3mV
192ps     127.1mV    121mV      141.8mV
230ps     134.1mV    133.9mV    144.4mV
407ps     137.6mV    140.5mV    145.5mV
[Falling Waveform]
R_fixture   = 50
V_fixture   = 1.1
V_fixture_min = 1.06
V_fixture_max = 1.17
|   Time   V(typ)   V(min)   V(max)
0s        1.1V       1.06V      1.17V
73ps      1.101V     1.06V      1.164V
94ps      1.091V     1.062V     996.3mV
120ps     934.5mV    1.049V     802.2mV
139ps     822.7mV    968.4mV    726.3mV
163ps     730.5mV    848.6mV    680.6mV
200ps     666.1mV    723.5mV    656.7mV
241ps     643.5mV    661.3mV    650.3mV
295ps     636mV      634.7mV    648.7mV
407ps     634.2mV    625.9mV    648.5mV
[Rising Waveform]
R_fixture   = 50
V_fixture   = 1.1
V_fixture_min = 1.06
V_fixture_max = 1.17
|   Time   V(typ)   V(min)   V(max)
0s        633.9mV    625.2mV    648.4mV
54ps      630.7mV    621.8mV    655.4mV
63ps      637.3mV    619.4mV    695.3mV
76ps      688.3mV    630.2mV    815.2mV
93ps      813.3mV    703.4mV    939.5mV
112ps     916.8mV    819.3mV    1.028V
153ps     1.03V      962.6mV    1.12V
193ps     1.073V     1.02V      1.152V
236ps     1.09V      1.045V     1.164V
407ps     1.1V       1.06V      1.17V
[Falling Waveform]
R_fixture = 50
V_fixture = 0.0
|   Time   V(typ)   V(min)   V(max)
0s        137.7mV    140.6mV    145.5mV
59ps      139.4mV    141.7mV    144.7mV
70ps      139.3mV    143.3mV    129mV
79ps      134.8mV    143.2mV    95.78mV
102ps     82.39mV    124.3mV    35.3mV
118ps     44mV       93.02mV    17.69mV
136ps     21.28mV    52.88mV    8.04mV
162ps     7.508mV    20.28mV    2.653mV
200ps     1.744mV    4.975mV    593.8uV
407ps     166.9uV    166.3uV    99.07uV
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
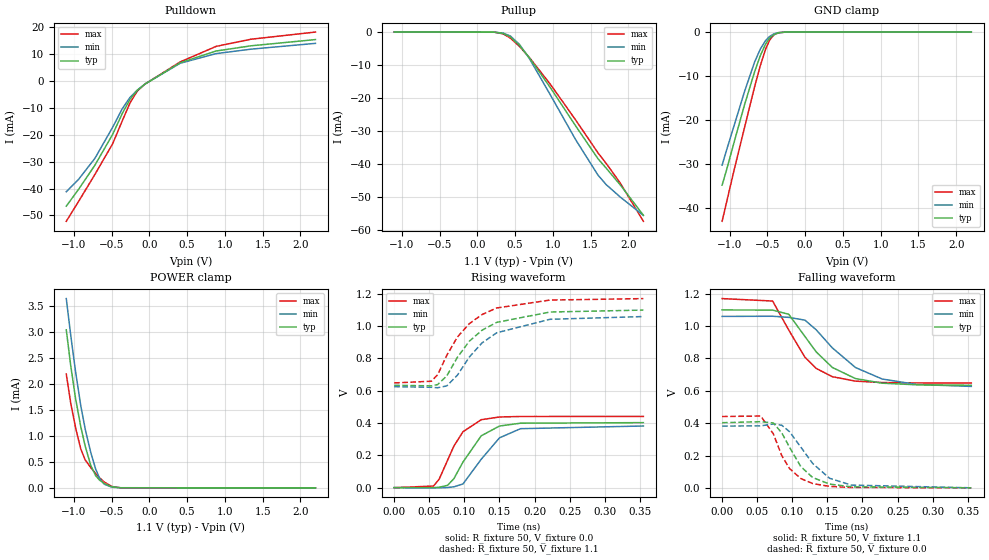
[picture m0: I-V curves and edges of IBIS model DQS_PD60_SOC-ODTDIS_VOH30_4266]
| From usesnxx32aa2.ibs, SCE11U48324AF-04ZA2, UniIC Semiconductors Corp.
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| DQS_PD60_SOC-ODTDIS_VOH30_4266
| (60 Ohm Pulldown, SOC ODT disabled setting, VOH=VDDQ/3.0 cal. point, 3200-4266Mbps)
[Model]   DQS_PD60_SOC-ODTDIS_VOH30_4266
Model_type   I/O
Vinl = 123.333mV
Vinh = 243.333mV
Vmeas = 183.333mV
Vref = 0.0mV
Cref = 0.0pF
|   typ   min   max
|C_comp   0.838pF   0.788pF   0.888pF
C_comp_pullup   0.4190pF   0.3940pF   0.4440pF
C_comp_pulldown   0.4190pF   0.3940pF   0.4440pF
| Note: C_comp changes when the ODT circuit is enabled.
[Model Spec]
| Input threshold voltage corners
Vinl   0.1233V   0.1167V   0.1350V
Vinh   0.2433V   0.2367V   0.2550V
| Measurement voltage corners
Vmeas   0.1833V   0.1767V   0.1950V
| Timing spec test load voltage corners
Vref   0.0000V   0.0000V   0.0000V
| Dynamic Overshoot Parameters from LPDDR4 Specification
D_overshoot_ampl_h   0.30   NA   NA
D_overshoot_ampl_l   0.30   NA   NA
D_overshoot_area_h   0.1n   NA   NA
D_overshoot_area_l   0.1n   NA   NA
[Receiver Thresholds]
Vcross_low   = 123.3mV
Vcross_high  = 243.3mV
Vdiff_ac   = 120mV
Vdiff_dc   = 120mV
Tdiffslew_ac = 10.000ns |Not specified, so set to high value
[Voltage Range]   1.1000V   1.0600V   1.1700V
[Pullup Reference]   1.1000V   1.0600V   1.1700V
| Junction Temperature (Ambient temp is 35C typ 95C min -40C max)
[Temperature Range]   50.0   110.0   -40.0
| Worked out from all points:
|   slope of the pulldown table from 0 to 0.165 V, typ, clamps not added: 54.7 ohm
|   slope of the pullup table from 0 to 0.165 V, typ, clamps not added: 13 kohm
|   GND clamp passes 1 mA (typ) near -0.45 V on its own axis
|   POWER clamp passes 1 mA (typ) near -0.88 V on its own axis
|   rising waveform, R_fixture 50, V_fixture 0.0: 20-80 % time 35.7ps typ, 39.6ps min, 31.1ps max; typ from 0.001 V to 0.403 V
|   falling waveform, R_fixture 50, V_fixture 1.1: 20-80 % time 55.7ps typ, 67.7ps min, 45.1ps max; typ from 1.1 V to 0.634 V
|   rising waveform, R_fixture 50, V_fixture 1.1: 20-80 % time 57.7ps typ, 59.8ps min, 54.8ps max; typ from 0.634 V to 1.1 V
|   falling waveform, R_fixture 50, V_fixture 0.0: 20-80 % time 36.1ps typ, 43.3ps min, 31.4ps max; typ from 0.403 V to 0.001 V
[Pulldown]
|   Voltage   I(typ)   I(min)   I(max)
-1.1V     -46.55mA   -41.21mA   -52.18mA
-935mV    -40.23mA   -36.52mA   -44.72mA
-720.5mV  -31.32mA   -28.77mA   -34.74mA
-486.2mV  -19.88mA   -17.25mA   -23.37mA
-357.5mV  -12.07mA   -10.3mA    -14.78mA
-255.2mV  -6.8mA     -6.091mA   -8.146mA
-159.5mV  -3.535mA   -3.397mA   -3.777mA
-57.2mV   -1.174mA   -1.161mA   -1.157mA
408.1mV   6.739mA    6.556mA    7.052mA
883.3mV   11.1mA     10.14mA    12.82mA
1.345V    13.04mA    11.79mA    15.49mA
2.2V      15.36mA    13.96mA    18.16mA
[GND Clamp]
|   Voltage   I(typ)   I(min)   I(max)
-1.1V     -34.88mA   -30.34mA   -43.13mA
-1.047V   -31.79mA   -27.25mA   -39.23mA
-938.3mV  -24.92mA   -21.15mA   -31.24mA
-803mV    -16.57mA   -13.55mA   -21.76mA
-671mV    -9.112mA   -6.888mA   -12.56mA
-595.1mV  -5.416mA   -3.908mA   -7.72mA
-525.8mV  -2.773mA   -1.978mA   -3.977mA
-473mV    -1.425mA   -1.032mA   -1.891mA
-416.9mV  -597.4uA   -440.8uA   -665uA
-350.9mV  -166.1uA   -125.6uA   -146.4uA
-261.8mV  -17.7uA    -15.44uA   -10.91uA
2.2V      0A         0A         0A
[Pullup]
|   Voltage   I(typ)   I(min)   I(max)
-1.1V     6.284uA    9.684uA    2.832uA
229.9mV   -45.24uA   -45.95uA   -46.56uA
342.1mV   -380.8uA   -315.5uA   -525.1uA
437.8mV   -1.438mA   -1.179mA   -1.81mA
559.9mV   -4.055mA   -3.762mA   -4.37mA
691.9mV   -7.825mA   -8.065mA   -7.74mA
969.1mV   -16.86mA   -19.06mA   -15.84mA
1.302V    -28.37mA   -32.54mA   -26.58mA
1.599V    -38.35mA   -43.31mA   -36.57mA
1.708V    -41.21mA   -46.19mA   -39.78mA
1.893V    -46.24mA   -49.93mA   -45.68mA
2.2V      -55.46mA   -55.5mA    -57.28mA
[POWER Clamp]
|   Voltage   I(typ)   I(min)   I(max)
-1.1V     3.036mA    3.636mA    2.186mA
-1.041V   2.347mA    2.931mA    1.626mA
-977.9mV  1.724mA    2.242mA    1.161mA
-908.6mV  1.178mA    1.583mA    748.8uA
-849.2mV  799.4uA    1.126mA    535.5uA
-776.6mV  434.2uA    683.5uA    390.2uA
-710.6mV  232.2uA    359.1uA    273.1uA
-657.8mV  146.8uA    178.8uA    190.7uA
-595.1mV  80.77uA    68.32uA    109.2uA
-496.1mV  20.04uA    12.32uA    25.73uA
-383.9mV  1.757uA    1.209uA    1.465uA
2.2V      0A         0A         0A
[Ramp]
|   typ   min   max
| 20% - 80%
dV/dt_r   241.29m/35.69p   228.84m/39.62p   264.40m/31.13p
dV/dt_f   279.40m/55.69p   259.56m/67.75p   312.93m/45.10p
| 25% - 75%
|dV/dt_r   201.07m/28.48p   190.70m/31.58p   220.33m/24.70p
|dV/dt_f   232.84m/44.38p   216.30m/54.05p   260.77m/35.84p
R_load = 50
[Rising Waveform]
R_fixture = 50
V_fixture = 0.0
|   Time   V(typ)   V(min)   V(max)
0s        704.3uV    616.3uV    509.3uV
56ps      487.3uV    -55.95uV   10.57mV
64ps      3.079mV    -518.3uV   52.55mV
76ps      14.94mV    1.57mV     169.5mV
85ps      55.96mV    5.7mV      257.6mV
98ps      159mV      23.5mV     346.5mV
124ps     321.4mV    176.3mV    420.9mV
150ps     381.8mV    308.8mV    437.8mV
180ps     399.3mV    365.4mV    440.8mV
355ps     402.8mV    382mV      441.2mV
[Falling Waveform]
R_fixture   = 50
V_fixture   = 1.1
V_fixture_min = 1.06
V_fixture_max = 1.17
|   Time   V(typ)   V(min)   V(max)
0s        1.1V       1.06V      1.17V
72ps      1.099V     1.061V     1.155V
95ps      1.073V     1.054V     975.2mV
118ps     935.9mV    1.037V     807.4mV
134ps     840.9mV    977.4mV    738.7mV
157ps     744.5mV    865.6mV    687.4mV
190ps     675.8mV    744.1mV    660mV
228ps     647.3mV    673.1mV    651.3mV
278ps     637.1mV    639mV      648.9mV
355ps     634.3mV    627.4mV    648.5mV
[Rising Waveform]
R_fixture   = 50
V_fixture   = 1.1
V_fixture_min = 1.06
V_fixture_max = 1.17
|   Time   V(typ)   V(min)   V(max)
0s        634mV      625.3mV    648.4mV
53ps      630.2mV    621.5mV    658.9mV
62ps      638.4mV    618.5mV    700mV
75ps      692.3mV    630.3mV    819.8mV
90ps      806.8mV    695.9mV    932mV
107ps     906.4mV    808.3mV    1.015V
125ps     974.1mV    895.6mV    1.071V
146ps     1.023V     958.6mV    1.112V
222ps     1.087V     1.042V     1.161V
355ps     1.099V     1.059V     1.17V
[Falling Waveform]
R_fixture = 50
V_fixture = 0.0
|   Time   V(typ)   V(min)   V(max)
0s        403mV      382.2mV    441.3mV
55ps      409.4mV    383.4mV    444.4mV
73ps      401.2mV    395.2mV    334mV
85ps      340.4mV    387.4mV    199.3mV
96ps      251.6mV    347.7mV    120mV
112ps     132.3mV    253mV      58.01mV
129ps     64.28mV    151.3mV    27.08mV
153ps     23.68mV    59.74mV    9.571mV
184ps     6.948mV    17.46mV    2.797mV
355ps     760uV      722.7uV    529.1uV
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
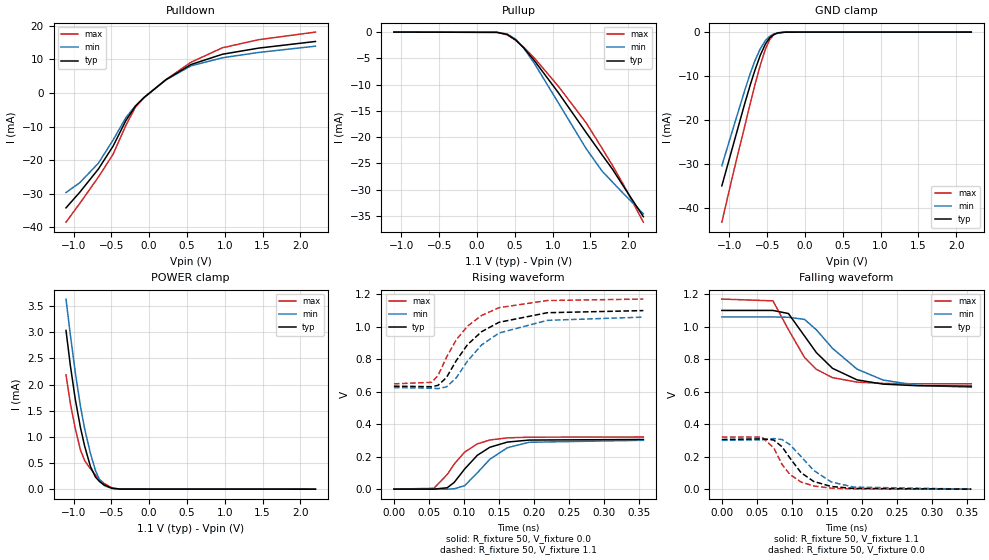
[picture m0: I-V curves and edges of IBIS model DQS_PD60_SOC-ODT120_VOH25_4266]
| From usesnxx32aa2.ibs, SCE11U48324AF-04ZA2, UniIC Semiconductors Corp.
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| DQS_PD60_SOC-ODT120_VOH25_4266
| (60 Ohm Pulldown, 120 Ohm System ODT Setting, VOH=VDDQ/2.5, 3200-4266Mbps)
[Model]   DQS_PD60_SOC-ODT120_VOH25_4266
Model_type   I/O
Vinl = 160.000mV
Vinh = 280.000mV
Vmeas = 220.000mV
Vref = 0.0mV
Cref = 0.0pF
Rref = 120.000Ohm
|   typ   min   max
|C_comp   0.838pF   0.788pF   0.888pF
C_comp_pullup   0.4190pF   0.3940pF   0.4440pF
C_comp_pulldown   0.4190pF   0.3940pF   0.4440pF
| Note: C_comp changes when the ODT circuit is enabled.
[Model Spec]
| Input threshold voltage corners
Vinl   0.1600V   0.1520V   0.1740V
Vinh   0.2800V   0.2720V   0.2940V
| Measurement voltage corners
Vmeas   0.2200V   0.2120V   0.2340V
| Timing spec test load voltage corners
Vref   0.0000V   0.0000V   0.0000V
| Dynamic Overshoot Parameters from LPDDR4 Specification
D_overshoot_ampl_h   0.30   NA   NA
D_overshoot_ampl_l   0.30   NA   NA
D_overshoot_area_h   0.1n   NA   NA
D_overshoot_area_l   0.1n   NA   NA
[Receiver Thresholds]
Vcross_low   = 160.0mV
Vcross_high  = 280.0mV
Vdiff_ac   = 120mV
Vdiff_dc   = 120mV
Tdiffslew_ac = 10.000ns |Not specified, so set to high value
[Voltage Range]   1.1000V   1.0600V   1.1700V
[Pullup Reference]   1.1000V   1.0600V   1.1700V
| Junction Temperature (Ambient temp is 35C typ 95C min -40C max)
[Temperature Range]   50.0   110.0   -40.0
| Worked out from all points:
|   slope of the pulldown table from 0 to 0.165 V, typ, clamps not added: 54.8 ohm
|   slope of the pullup table from 0 to 0.165 V, typ, clamps not added: 26.3 kohm
|   GND clamp passes 1 mA (typ) near -0.45 V on its own axis
|   POWER clamp passes 1 mA (typ) near -0.88 V on its own axis
|   rising waveform, R_fixture 50, V_fixture 0.0: 20-80 % time 41ps typ, 44.3ps min, 37.6ps max; typ from 0 V to 0.306 V
|   falling waveform, R_fixture 50, V_fixture 1.1: 20-80 % time 55.3ps typ, 67.3ps min, 44.6ps max; typ from 1.1 V to 0.634 V
|   rising waveform, R_fixture 50, V_fixture 1.1: 20-80 % time 58.3ps typ, 62ps min, 54.6ps max; typ from 0.634 V to 1.1 V
|   falling waveform, R_fixture 50, V_fixture 0.0: 20-80 % time 36ps typ, 43.4ps min, 31ps max; typ from 0.306 V to 0.001 V
[Pulldown]
|   Voltage   I(typ)   I(min)   I(max)
-1.1V     -34.25mA   -29.68mA   -38.53mA
-918.5mV  -29.62mA   -26.77mA   -32.96mA
-671mV    -22.66mA   -20.92mA   -25.05mA
-476.3mV  -15.81mA   -14mA      -18.23mA
-308mV    -8.225mA   -7.355mA   -9.672mA
-182.6mV  -3.974mA   -3.823mA   -4.259mA
-67.1mV   -1.349mA   -1.337mA   -1.333mA
223.3mV   3.974mA    3.926mA    4.026mA
553.3mV   8.488mA    8.09mA     9.162mA
969.1mV   11.55mA    10.5mA     13.48mA
1.448V    13.38mA    12.09mA    15.89mA
2.2V      15.36mA    13.96mA    18.16mA
[GND Clamp]
|   Voltage   I(typ)   I(min)   I(max)
-1.1V     -34.89mA   -30.35mA   -43.14mA
-944.9mV  -25.34mA   -21.52mA   -31.72mA
-793.1mV  -15.99mA   -13.01mA   -21.07mA
-723.8mV  -11.98mA   -9.378mA   -16.19mA
-664.4mV  -8.772mA   -6.596mA   -12.13mA
-591.8mV  -5.274mA   -3.797mA   -7.531mA
-522.5mV  -2.671mA   -1.905mA   -3.825mA
-466.4mV  -1.297mA   -942.2uA   -1.694mA
-413.6mV  -565.5uA   -417.2uA   -621.5uA
-357.5mV  -191.9uA   -144.5uA   -174.1uA
-258.5mV  -16.12uA   -14.14uA   -9.884uA
2.2V      0A         0A         0A
[Pullup]
|   Voltage   I(typ)   I(min)   I(max)
-1.1V     2.741uA    4.96uA     908.5nA
262.9mV   -43.02uA   -42.45uA   -44.32uA
398.2mV   -442.3uA   -366.6uA   -523.4uA
510.4mV   -1.485mA   -1.346mA   -1.542mA
616mV     -2.987mA   -3.007mA   -2.855mA
761.2mV   -5.48mA    -6.027mA   -4.984mA
1.075V    -11.52mA   -13.45mA   -10.3mA
1.444V    -19.13mA   -22.2mA    -17.29mA
1.652V    -23.33mA   -26.42mA   -22.08mA
1.788V    -26.02mA   -28.49mA   -25.29mA
1.933V    -29.26mA   -30.67mA   -28.95mA
2.2V      -35.14mA   -34.59mA   -36.18mA
[POWER Clamp]
|   Voltage   I(typ)   I(min)   I(max)
-1.1V     3.036mA    3.636mA    2.186mA
-1.044V   2.383mA    2.97mA     1.654mA
-977.9mV  1.724mA    2.243mA    1.161mA
-908.6mV  1.178mA    1.583mA    747.6uA
-852.5mV  818.6uA    1.149mA    544uA
-776.6mV  434.2uA    683.6uA    390.2uA
-710.6mV  232.2uA    359.1uA    273.1uA
-654.5mV  142.7uA    170.4uA    185.9uA
-598.4mV  83.68uA    71.96uA    113.1uA
-492.8mV  18.87uA    11.55uA    24.07uA
-383.9mV  1.745uA    1.209uA    1.464uA
2.2V      0A         0A         0A
[Ramp]
|   typ   min   max
| 20% - 80%
dV/dt_r   183.20m/41.01p   180.30m/44.29p   192.47m/37.63p
dV/dt_f   279.42m/55.25p   259.55m/67.26p   312.91m/44.64p
| 25% - 75%
|dV/dt_r   152.67m/32.64p   150.25m/35.28p   160.39m/29.92p
|dV/dt_f   232.85m/43.94p   216.29m/53.60p   260.76m/35.55p
R_load = 50
[Rising Waveform]
R_fixture = 50
V_fixture = 0.0
|   Time   V(typ)   V(min)   V(max)
0s        480.8uV    386.3uV    353.3uV
57ps      351.5uV    58.58uV    5.255mV
76ps      8.579mV    353.6uV    89.92mV
86ps      41.59mV    2.36mV     154.5mV
101ps     124.3mV    21.64mV    228.4mV
119ps     208.4mV    100.6mV    278.7mV
137ps     258.2mV    184.3mV    302.8mV
162ps     289.9mV    255mV      315.8mV
193ps     302.3mV    288.8mV    320mV
356ps     305.8mV    300.9mV    321.1mV
[Falling Waveform]
R_fixture   = 50
V_fixture   = 1.1
V_fixture_min = 1.06
V_fixture_max = 1.17
|   Time   V(typ)   V(min)   V(max)
0s        1.1V       1.06V      1.17V
73ps      1.1V       1.06V      1.159V
95ps      1.081V     1.058V     982.3mV
118ps     942.8mV    1.045V     810.8mV
135ps     840.2mV    980.5mV    737.3mV
158ps     743.6mV    866.7mV    686.6mV
193ps     672.8mV    738.9mV    659mV
230ps     646.8mV    671.9mV    651.2mV
278ps     637mV      639.5mV    648.9mV
356ps     634.3mV    627.4mV    648.5mV
[Rising Waveform]
R_fixture   = 50
V_fixture   = 1.1
V_fixture_min = 1.06
V_fixture_max = 1.17
|   Time   V(typ)   V(min)   V(max)
0s        633.9mV    625.3mV    648.4mV
54ps      630.7mV    621.4mV    657.7mV
63ps      639.1mV    619mV      700mV
75ps      687.1mV    629.6mV    811.4mV
89ps      791.4mV    685.6mV    919.5mV
105ps     889.4mV    788.3mV    1.003V
125ps     968.9mV    887.3mV    1.069V
150ps     1.027V     961.2mV    1.117V
219ps     1.086V     1.039V     1.161V
356ps     1.099V     1.059V     1.17V
[Falling Waveform]
R_fixture = 50
V_fixture = 0.0
|   Time   V(typ)   V(min)   V(max)
0s        305.9mV    301mV      321.2mV
57ps      310.1mV    303.8mV    321.2mV
74ps      303mV      312mV      254.8mV
86ps      261mV      305.4mV    152mV
97ps      193mV      275.1mV    91.68mV
113ps     102mV      201.6mV    44.5mV
131ps     48.06mV    115.9mV    19.95mV
156ps     17.06mV    44.91mV    6.775mV
188ps     4.88mV     13.18mV    1.91mV
356ps     553.6uV    511.7uV    383.5uV
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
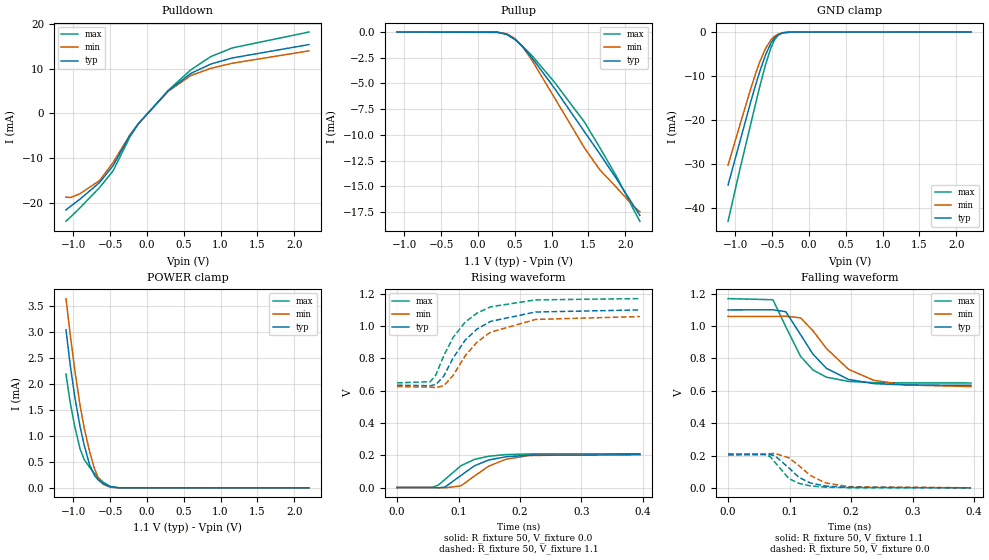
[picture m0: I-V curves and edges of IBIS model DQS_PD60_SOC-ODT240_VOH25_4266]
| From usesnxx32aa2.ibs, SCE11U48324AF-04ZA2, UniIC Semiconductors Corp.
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| DQS_PD60_SOC-ODT240_VOH25_4266
| (60 Ohm Pulldown, 240 Ohm System ODT Setting, VOH=VDDQ/2.5, 3200-4266Mbps)
[Model]   DQS_PD60_SOC-ODT240_VOH25_4266
Model_type   I/O
Vinl = 160.000mV
Vinh = 280.000mV
Vmeas = 220.000mV
Vref = 0.0mV
Cref = 0.0pF
Rref = 240.000Ohm
|   typ   min   max
|C_comp   0.838pF   0.788pF   0.888pF
C_comp_pullup   0.4190pF   0.3940pF   0.4440pF
C_comp_pulldown   0.4190pF   0.3940pF   0.4440pF
| Note: C_comp changes when the ODT circuit is enabled.
[Model Spec]
| Input threshold voltage corners
Vinl   0.1600V   0.1520V   0.1740V
Vinh   0.2800V   0.2720V   0.2940V
| Measurement voltage corners
Vmeas   0.2200V   0.2120V   0.2340V
| Timing spec test load voltage corners
Vref   0.0000V   0.0000V   0.0000V
| Dynamic Overshoot Parameters from LPDDR4 Specification
D_overshoot_ampl_h   0.30   NA   NA
D_overshoot_ampl_l   0.30   NA   NA
D_overshoot_area_h   0.1n   NA   NA
D_overshoot_area_l   0.1n   NA   NA
[Receiver Thresholds]
Vcross_low   = 160.0mV
Vcross_high  = 280.0mV
Vdiff_ac   = 120mV
Vdiff_dc   = 120mV
Tdiffslew_ac = 10.000ns |Not specified, so set to high value
[Voltage Range]   1.1000V   1.0600V   1.1700V
[Pullup Reference]   1.1000V   1.0600V   1.1700V
| Junction Temperature (Ambient temp is 35C typ 95C min -40C max)
[Temperature Range]   50.0   110.0   -40.0
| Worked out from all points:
|   slope of the pulldown table from 0 to 0.165 V, typ, clamps not added: 55 ohm
|   slope of the pullup table from 0 to 0.165 V, typ, clamps not added: 53.3 kohm
|   GND clamp passes 1 mA (typ) near -0.45 V on its own axis
|   POWER clamp passes 1 mA (typ) near -0.88 V on its own axis
|   rising waveform, R_fixture 50, V_fixture 0.0: 20-80 % time 48.6ps typ, 52.4ps min, 45.1ps max; typ from 0 V to 0.203 V
|   falling waveform, R_fixture 50, V_fixture 1.1: 20-80 % time 54.8ps typ, 67ps min, 44.5ps max; typ from 1.1 V to 0.634 V
|   rising waveform, R_fixture 50, V_fixture 1.1: 20-80 % time 59.1ps typ, 62.9ps min, 54.8ps max; typ from 0.634 V to 1.1 V
|   falling waveform, R_fixture 50, V_fixture 0.0: 20-80 % time 36.4ps typ, 44.1ps min, 31.5ps max; typ from 0.203 V to 0 V
[Pulldown]
|   Voltage   I(typ)   I(min)   I(max)
-1.1V     -21.54mA   -18.69mA   -24.07mA
-1.034V   -20.67mA   -18.75mA   -23.06mA
-911.9mV  -19.17mA   -17.94mA   -21.1mA
-644.6mV  -15.43mA   -14.99mA   -16.57mA
-459.8mV  -11.65mA   -10.95mA   -12.81mA
-232.1mV  -4.935mA   -4.797mA   -5.245mA
-113.3mV  -2.244mA   -2.239mA   -2.234mA
289.3mV   5.026mA    4.942mA    5.144mA
596.2mV   8.931mA    8.451mA    9.734mA
870.1mV   11.03mA    10.08mA    12.71mA
1.157V    12.37mA    11.19mA    14.61mA
2.2V      15.36mA    13.96mA    18.16mA
[GND Clamp]
|   Voltage   I(typ)   I(min)   I(max)
-1.1V     -34.89mA   -30.35mA   -43.14mA
-941.6mV  -25.14mA   -21.33mA   -31.48mA
-793.1mV  -15.99mA   -13.01mA   -21.07mA
-723.8mV  -11.98mA   -9.379mA   -16.19mA
-664.4mV  -8.771mA   -6.596mA   -12.13mA
-591.8mV  -5.273mA   -3.797mA   -7.531mA
-519.2mV  -2.573mA   -1.835mA   -3.675mA
-469.7mV  -1.358mA   -990.4uA   -1.792mA
-413.6mV  -564.1uA   -419.8uA   -621.1uA
-354.2mV  -178.9uA   -136.7uA   -159.7uA
-245.3mV  -11.05uA   -10.31uA   -6.361uA
2.2V      0A         0A         0A
[Pullup]
|   Voltage   I(typ)   I(min)   I(max)
-1.1V     1.371uA    2.481uA    454.5nA
266.2mV   -23.11uA   -22.31uA   -23.98uA
388.3mV   -192.7uA   -159.9uA   -230.6uA
503.8mV   -707.5uA   -637uA     -739.2uA
602.8mV   -1.402mA   -1.398mA   -1.348mA
734.8mV   -2.527mA   -2.755mA   -2.306mA
1.032V    -5.393mA   -6.298mA   -4.813mA
1.448V    -9.715mA   -11.29mA   -8.771mA
1.655V    -11.85mA   -13.4mA    -11.24mA
1.887V    -14.33mA   -15.16mA   -14.11mA
2.114V    -16.89mA   -16.95mA   -17.27mA
2.2V      -17.84mA   -17.49mA   -18.41mA
[POWER Clamp]
|   Voltage   I(typ)   I(min)   I(max)
-1.1V     3.036mA    3.636mA    2.186mA
-1.041V   2.347mA    2.931mA    1.626mA
-977.9mV  1.724mA    2.242mA    1.161mA
-908.6mV  1.178mA    1.583mA    748.7uA
-852.5mV  818.6uA    1.149mA    543.7uA
-779.9mV  448.2uA    701.7uA    396.3uA
-713.9mV  239.2uA    373.3uA    278.6uA
-657.8mV  146.8uA    178.8uA    190.7uA
-598.4mV  83.72uA    71.96uA    113.1uA
-499.4mV  21.32uA    13.27uA    27.46uA
-387.2mV  1.89uA     1.309uA    1.609uA
2.2V      0A         0A         0A
[Ramp]
|   typ   min   max
| 20% - 80%
dV/dt_r   121.81m/48.63p   124.15m/52.42p   125.58m/45.06p
dV/dt_f   279.54m/54.90p   260.32m/67.03p   312.92m/44.54p
| 25% - 75%
|dV/dt_r   101.50m/38.69p   103.46m/41.87p   104.65m/35.80p
|dV/dt_f   232.95m/43.77p   216.94m/53.43p   260.77m/35.44p
R_load = 50
[Rising Waveform]
R_fixture = 50
V_fixture = 0.0
|   Time   V(typ)   V(min)   V(max)
0s        229.1uV    173.4uV    170.3uV
58ps      -376.3uV   178uV      1.073mV
68ps      -1.273mV   -683.3uV   17.64mV
78ps      3.102mV    -1.6mV     50.37mV
104ps     75.13mV    10.81mV    135.4mV
126ps     134.8mV    71.6mV     174.4mV
149ps     170.6mV    132.4mV    194.2mV
177ps     190.8mV    175.5mV    204mV
215ps     200.1mV    198.5mV    208.1mV
395ps     203.2mV    207.1mV    209.5mV
[Falling Waveform]
R_fixture   = 50
V_fixture   = 1.1
V_fixture_min = 1.06
V_fixture_max = 1.17
|   Time   V(typ)   V(min)   V(max)
0s        1.1V       1.06V      1.17V
73ps      1.101V     1.06V      1.163V
94ps      1.089V     1.061V     995.3mV
118ps     946.8mV    1.051V     812.6mV
138ps     827.1mV    971.5mV    729.1mV
160ps     738.9mV    861.3mV    684.3mV
196ps     670.1mV    732.7mV    658mV
237ps     644.5mV    665mV      650.6mV
290ps     636.2mV    635.9mV    648.8mV
395ps     634.1mV    626.1mV    648.5mV
[Rising Waveform]
R_fixture   = 50
V_fixture   = 1.1
V_fixture_min = 1.06
V_fixture_max = 1.17
|   Time   V(typ)   V(min)   V(max)
0s        633.9mV    625.2mV    648.4mV
54ps      630.7mV    621.8mV    655.5mV
63ps      637.6mV    619.2mV    696mV
76ps      689.5mV    630.4mV    816.4mV
91ps      801mV      692.7mV    928.6mV
111ps     913.6mV    816.5mV    1.025V
130ps     981mV      900.2mV    1.08V
152ps     1.029V     961.9mV    1.119V
225ps     1.087V     1.041V     1.162V
395ps     1.1V       1.059V     1.17V
[Falling Waveform]
R_fixture = 50
V_fixture = 0.0
|   Time   V(typ)   V(min)   V(max)
0s        203.3mV    207.2mV    209.5mV
59ps      205.6mV    209.1mV    208.3mV
69ps      204.9mV    212mV      191.8mV
76ps      199mV      212.9mV    159.1mV
99ps      123.2mV    186mV      57.45mV
115ps     65.54mV    138mV      28.23mV
134ps     30.1mV     76.31mV    12.24mV
158ps     11.38mV    31.17mV    4.384mV
196ps     2.639mV    7.464mV    984.2uV
395ps     300.5uV    278.6uV    198.3uV
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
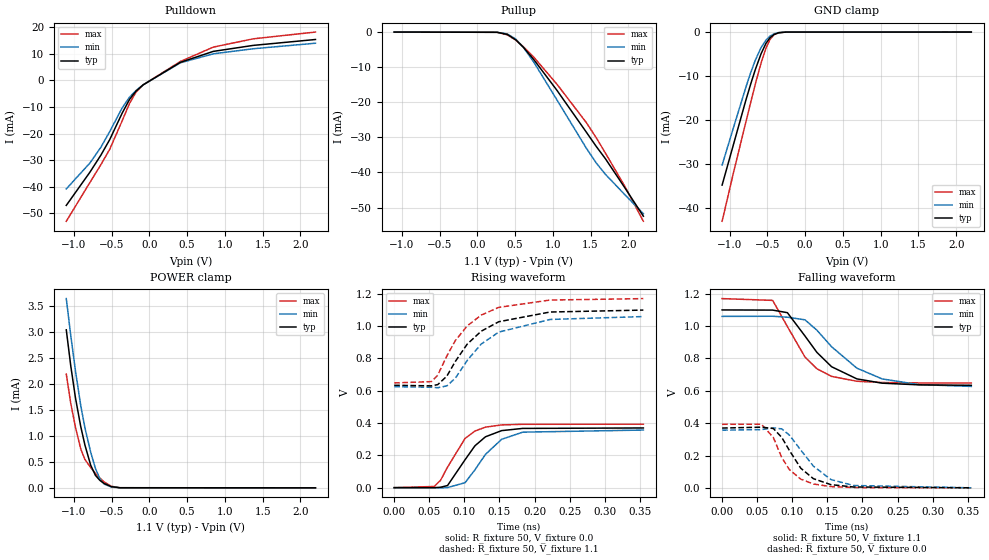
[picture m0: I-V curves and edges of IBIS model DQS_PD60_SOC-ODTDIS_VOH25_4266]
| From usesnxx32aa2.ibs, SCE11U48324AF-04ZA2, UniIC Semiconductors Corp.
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| DQS_PD60_SOC-ODTDIS_VOH25_4266
| (60 Ohm Pulldown, SOC ODT disabled setting, VOH=VDDQ/2.5 cal. point, 3200-4266Mbps)
[Model]   DQS_PD60_SOC-ODTDIS_VOH25_4266
Model_type   I/O
Vinl = 160.000mV
Vinh = 280.000mV
Vmeas = 220.000mV
Vref = 0.0mV
Cref = 0.0pF
|   typ   min   max
|C_comp   0.838pF   0.788pF   0.888pF
C_comp_pullup   0.4190pF   0.3940pF   0.4440pF
C_comp_pulldown   0.4190pF   0.3940pF   0.4440pF
| Note: C_comp changes when the ODT circuit is enabled.
[Model Spec]
| Input threshold voltage corners
Vinl   0.1600V   0.1520V   0.1740V
Vinh   0.2800V   0.2720V   0.2940V
| Measurement voltage corners
Vmeas   0.2200V   0.2120V   0.2340V
| Timing spec test load voltage corners
Vref   0.0000V   0.0000V   0.0000V
| Dynamic Overshoot Parameters from LPDDR4 Specification
D_overshoot_ampl_h   0.30   NA   NA
D_overshoot_ampl_l   0.30   NA   NA
D_overshoot_area_h   0.1n   NA   NA
D_overshoot_area_l   0.1n   NA   NA
[Receiver Thresholds]
Vcross_low   = 160.0mV
Vcross_high  = 280.0mV
Vdiff_ac   = 120mV
Vdiff_dc   = 120mV
Tdiffslew_ac = 10.000ns |Not specified, so set to high value
[Voltage Range]   1.1000V   1.0600V   1.1700V
[Pullup Reference]   1.1000V   1.0600V   1.1700V
| Junction Temperature (Ambient temp is 35C typ 95C min -40C max)
[Temperature Range]   50.0   110.0   -40.0
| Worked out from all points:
|   slope of the pulldown table from 0 to 0.165 V, typ, clamps not added: 54.7 ohm
|   slope of the pullup table from 0 to 0.165 V, typ, clamps not added: 17.2 kohm
|   GND clamp passes 1 mA (typ) near -0.45 V on its own axis
|   POWER clamp passes 1 mA (typ) near -0.88 V on its own axis
|   rising waveform, R_fixture 50, V_fixture 0.0: 20-80 % time 35.8ps typ, 39.3ps min, 32.8ps max; typ from 0.001 V to 0.37 V
|   falling waveform, R_fixture 50, V_fixture 1.1: 20-80 % time 55.5ps typ, 67.8ps min, 44.8ps max; typ from 1.1 V to 0.634 V
|   rising waveform, R_fixture 50, V_fixture 1.1: 20-80 % time 57.8ps typ, 60.8ps min, 54.6ps max; typ from 0.634 V to 1.1 V
|   falling waveform, R_fixture 50, V_fixture 0.0: 20-80 % time 36.3ps typ, 43.3ps min, 31.1ps max; typ from 0.37 V to 0.001 V
[Pulldown]
|   Voltage   I(typ)   I(min)   I(max)
-1.1V     -46.99mA   -40.8mA    -52.96mA
-786.5mV  -34.49mA   -31.05mA   -38.36mA
-641.3mV  -28.08mA   -25.11mA   -31.66mA
-525.8mV  -22.32mA   -19.3mA    -25.97mA
-360.8mV  -12.37mA   -10.39mA   -15.26mA
-261.8mV  -7.137mA   -6.288mA   -8.642mA
-176mV    -4.016mA   -3.794mA   -4.406mA
-80.3mV   -1.664mA   -1.635mA   -1.657mA
411.4mV   6.783mA    6.597mA    7.102mA
847mV     10.89mA    9.975mA    12.5mA
1.375V    13.14mA    11.88mA    15.61mA
2.2V      15.36mA    13.96mA    18.16mA
[GND Clamp]
|   Voltage   I(typ)   I(min)   I(max)
-1.1V     -34.89mA   -30.34mA   -43.14mA
-941.6mV  -25.14mA   -21.33mA   -31.48mA
-786.5mV  -15.6mA    -12.65mA   -20.6mA
-720.5mV  -11.8mA    -9.214mA   -15.96mA
-661.1mV  -8.6mA     -6.453mA   -11.91mA
-585.2mV  -4.992mA   -3.582mA   -7.141mA
-519.2mV  -2.574mA   -1.836mA   -3.675mA
-466.4mV  -1.312mA   -948.2uA   -1.694mA
-413.6mV  -570.8uA   -419.7uA   -620.3uA
-350.9mV  -170.2uA   -127.7uA   -146.8uA
-258.5mV  -16.58uA   -14.44uA   -9.815uA
2.2V      0A         0A         0A
[Pullup]
|   Voltage   I(typ)   I(min)   I(max)
-1.1V     4.112uA    7.441uA    1.363uA
262.9mV   -64.84uA   -63.6uA    -66.39uA
398.2mV   -661.4uA   -551.1uA   -783.7uA
510.4mV   -2.22mA    -2.012mA   -2.306mA
612.7mV   -4.381mA   -4.395mA   -4.2mA
751.3mV   -7.908mA   -8.649mA   -7.214mA
1.055V    -16.59mA   -19.32mA   -14.85mA
1.441V    -28.41mA   -32.96mA   -25.69mA
1.576V    -32.59mA   -37.31mA   -30.11mA
1.698V    -36.11mA   -40.55mA   -34.5mA
1.956V    -44.42mA   -46.36mA   -44.02mA
2.2V      -52.46mA   -51.75mA   -53.91mA
[POWER Clamp]
|   Voltage   I(typ)   I(min)   I(max)
-1.1V     3.036mA    3.636mA    2.186mA
-1.041V   2.347mA    2.931mA    1.626mA
-977.9mV  1.724mA    2.242mA    1.161mA
-908.6mV  1.178mA    1.582mA    748.3uA
-852.5mV  818.5uA    1.149mA    543.8uA
-776.6mV  434.4uA    683.6uA    390.2uA
-713.9mV  239.2uA    373.1uA    278.6uA
-654.5mV  142.7uA    170.4uA    185.9uA
-598.4mV  83.67uA    71.97uA    113uA
-502.7mV  22.64uA    14.15uA    29.28uA
-390.5mV  2.096uA    1.409uA    1.763uA
2.2V      0A         0A         0A
[Ramp]
|   typ   min   max
| 20% - 80%
dV/dt_r   221.49m/35.79p   213.85m/39.28p   235.57m/32.78p
dV/dt_f   279.40m/55.49p   259.55m/67.76p   312.92m/44.82p
| 25% - 75%
|dV/dt_r   184.57m/28.53p   178.21m/31.31p   196.31m/26.01p
|dV/dt_f   232.84m/44.18p   216.29m/54.01p   260.77m/35.67p
R_load = 50
[Rising Waveform]
R_fixture = 50
V_fixture = 0.0
|   Time   V(typ)   V(min)   V(max)
0s        730.2uV    596.2uV    535.4uV
57ps      628uV      -32uV      8.022mV
66ps      3.145mV    -449.5uV   46.06mV
76ps      13.79mV    1.109mV    127.9mV
101ps     173.6mV    31.4mV     305.2mV
115ps     259.4mV    110.8mV    350.8mV
130ps     315.2mV    206.2mV    375mV
153ps     353.4mV    299.6mV    388.7mV
183ps     367.1mV    343.9mV    392.6mV
355ps     369.9mV    357mV      393.2mV
[Falling Waveform]
R_fixture   = 50
V_fixture   = 1.1
V_fixture_min = 1.06
V_fixture_max = 1.17
|   Time   V(typ)   V(min)   V(max)
0s        1.1V       1.06V      1.17V
72ps      1.099V     1.061V     1.159V
93ps      1.083V     1.055V     997.2mV
118ps     939.2mV    1.039V     809.2mV
135ps     837.9mV    975.1mV    736.5mV
156ps     748.9mV    872.5mV    689.2mV
192ps     673.9mV    740.1mV    659.2mV
228ps     647.4mV    673.7mV    651.3mV
280ps     637mV      638.6mV    648.9mV
355ps     634.3mV    627.4mV    648.5mV
[Rising Waveform]
R_fixture   = 50
V_fixture   = 1.1
V_fixture_min = 1.06
V_fixture_max = 1.17
|   Time   V(typ)   V(min)   V(max)
0s        634mV      625.3mV    648.4mV
53ps      630.3mV    621.7mV    656.8mV
62ps      637.9mV    618.7mV    696mV
75ps      690.1mV    630mV      815.2mV
87ps      780.8mV    677.2mV    909.7mV
104ps     888.4mV    787.7mV    1.001V
124ps     968.6mV    889.1mV    1.068V
149ps     1.027V     962.8mV    1.116V
222ps     1.087V     1.041V     1.161V
355ps     1.099V     1.059V     1.17V
[Falling Waveform]
R_fixture = 50
V_fixture = 0.0
|   Time   V(typ)   V(min)   V(max)
0s        370mV      357.1mV    393.3mV
56ps      375.5mV    360.3mV    393.7mV
73ps      367.3mV    371.8mV    311.6mV
85ps      312mV      364.5mV    187.2mV
96ps      230.6mV    325.8mV    112.5mV
112ps     122.1mV    234.3mV    54.41mV
130ps     57.18mV    134.8mV    24.25mV
155ps     20.24mV    51.87mV    8.198mV
187ps     5.845mV    15.11mV    2.38mV
355ps     781uV      700uV      555.2uV
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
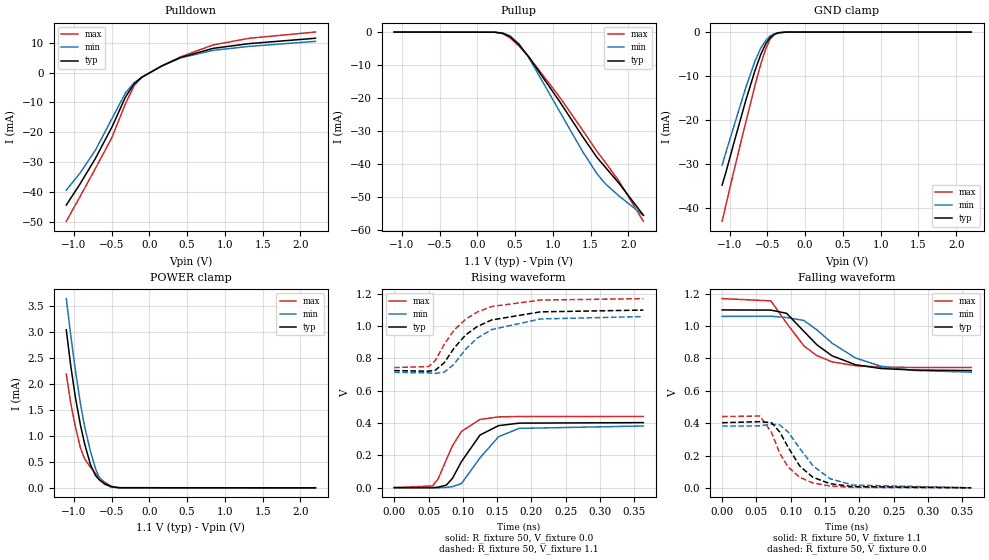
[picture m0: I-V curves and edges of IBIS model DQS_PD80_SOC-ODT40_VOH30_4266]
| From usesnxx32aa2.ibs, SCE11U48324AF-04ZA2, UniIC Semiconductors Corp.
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| DQS_PD80_SOC-ODT40_VOH30_4266
| (80 Ohm Pulldown, 40 Ohm System ODT Setting, VOH=VDDQ/3.0, 3200-4266Mbps)
[Model]   DQS_PD80_SOC-ODT40_VOH30_4266
Model_type   I/O
Vinl = 123.333mV
Vinh = 243.333mV
Vmeas = 183.333mV
Vref = 0.0mV
Cref = 0.0pF
Rref = 40.000Ohm
|   typ   min   max
|C_comp   0.838pF   0.788pF   0.888pF
C_comp_pullup   0.4190pF   0.3940pF   0.4440pF
C_comp_pulldown   0.4190pF   0.3940pF   0.4440pF
| Note: C_comp changes when the ODT circuit is enabled.
[Model Spec]
| Input threshold voltage corners
Vinl   0.1233V   0.1167V   0.1350V
Vinh   0.2433V   0.2367V   0.2550V
| Measurement voltage corners
Vmeas   0.1833V   0.1767V   0.1950V
| Timing spec test load voltage corners
Vref   0.0000V   0.0000V   0.0000V
| Dynamic Overshoot Parameters from LPDDR4 Specification
D_overshoot_ampl_h   0.30   NA   NA
D_overshoot_ampl_l   0.30   NA   NA
D_overshoot_area_h   0.1n   NA   NA
D_overshoot_area_l   0.1n   NA   NA
[Receiver Thresholds]
Vcross_low   = 123.3mV
Vcross_high  = 243.3mV
Vdiff_ac   = 120mV
Vdiff_dc   = 120mV
Tdiffslew_ac = 10.000ns |Not specified, so set to high value
[Voltage Range]   1.1000V   1.0600V   1.1700V
[Pullup Reference]   1.1000V   1.0600V   1.1700V
| Junction Temperature (Ambient temp is 35C typ 95C min -40C max)
[Temperature Range]   50.0   110.0   -40.0
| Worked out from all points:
|   slope of the pulldown table from 0 to 0.165 V, typ, clamps not added: 73.8 ohm
|   slope of the pullup table from 0 to 0.165 V, typ, clamps not added: 13 kohm
|   GND clamp passes 1 mA (typ) near -0.45 V on its own axis
|   POWER clamp passes 1 mA (typ) near -0.88 V on its own axis
|   rising waveform, R_fixture 50, V_fixture 0.0: 20-80 % time 35.9ps typ, 39.9ps min, 31.1ps max; typ from 0.001 V to 0.403 V
|   falling waveform, R_fixture 50, V_fixture 1.1: 20-80 % time 60ps typ, 70.8ps min, 49.1ps max; typ from 1.1 V to 0.725 V
|   rising waveform, R_fixture 50, V_fixture 1.1: 20-80 % time 56.2ps typ, 57.8ps min, 54.5ps max; typ from 0.725 V to 1.1 V
|   falling waveform, R_fixture 50, V_fixture 0.0: 20-80 % time 39.4ps typ, 45.6ps min, 34.5ps max; typ from 0.403 V to 0.001 V
[Pulldown]
|   Voltage   I(typ)   I(min)   I(max)
-1.1V     -44.43mA   -39.42mA   -49.86mA
-921.8mV  -37.52mA   -33.82mA   -41.78mA
-717.2mV  -28.93mA   -26.17mA   -32.3mA
-492.8mV  -18.13mA   -15.35mA   -21.65mA
-314.6mV  -8.133mA   -6.758mA   -10.35mA
-202.4mV  -3.803mA   -3.466mA   -4.465mA
-100.1mV  -1.589mA   -1.549mA   -1.61mA
160.6mV   2.153mA    2.137mA    2.157mA
411.4mV   5.021mA    4.895mA    5.234mA
843.7mV   8.104mA    7.438mA    9.251mA
1.329V    9.708mA    8.779mA    11.5mA
2.2V      11.49mA    10.45mA    13.57mA
[GND Clamp]
|   Voltage   I(typ)   I(min)   I(max)
-1.1V     -34.88mA   -30.35mA   -43.13mA
-1.047V   -31.79mA   -27.25mA   -39.23mA
-938.3mV  -24.92mA   -21.15mA   -31.24mA
-786.5mV  -15.59mA   -12.65mA   -20.59mA
-664.4mV  -8.768mA   -6.598mA   -12.12mA
-588.5mV  -5.129mA   -3.689mA   -7.328mA
-522.5mV  -2.677mA   -1.906mA   -3.822mA
-466.4mV  -1.302mA   -943.2uA   -1.695mA
-413.6mV  -567.6uA   -419.6uA   -620.4uA
-357.5mV  -191.9uA   -146.1uA   -173.2uA
-255.2mV  -14.58uA   -13.27uA   -8.748uA
2.2V      0A         0A         0A
[Pullup]
|   Voltage   I(typ)   I(min)   I(max)
-1.1V     6.284uA    9.684uA    2.833uA
229.9mV   -45.24uA   -45.98uA   -46.7uA
335.5mV   -340.6uA   -284.5uA   -469uA
434.5mV   -1.385mA   -1.133mA   -1.752mA
553.3mV   -3.885mA   -3.581mA   -4.215mA
678.7mV   -7.423mA   -7.588mA   -7.385mA
1.091V    -21.03mA   -24.05mA   -19.68mA
1.398V    -31.73mA   -36.27mA   -29.78mA
1.586V    -37.97mA   -42.9mA    -36.14mA
1.698V    -40.96mA   -45.96mA   -39.5mA
1.88V     -45.85mA   -49.67mA   -45.22mA
2.2V      -55.46mA   -55.5mA    -57.28mA
[POWER Clamp]
|   Voltage   I(typ)   I(min)   I(max)
-1.1V     3.036mA    3.636mA    2.186mA
-1.041V   2.347mA    2.931mA    1.626mA
-981.2mV  1.754mA    2.277mA    1.183mA
-911.9mV  1.201mA    1.612mA    764.7uA
-855.8mV  838.1uA    1.172mA    552.3uA
-779.9mV  448uA      701.7uA    396.3uA
-713.9mV  239.3uA    373.2uA    278.6uA
-661.1mV  151.1uA    187.6uA    195.5uA
-595.1mV  80.77uA    68.33uA    109.2uA
-499.4mV  21.4uA     13.13uA    27.45uA
-400.4mV  2.614uA    1.705uA    2.313uA
2.2V      0A         0A         0A
[Ramp]
|   typ   min   max
| 20% - 80%
dV/dt_r   241.22m/35.89p   228.79m/39.87p   264.35m/31.15p
dV/dt_f   224.80m/60.01p   206.68m/70.76p   255.68m/49.18p
| 25% - 75%
|dV/dt_r   201.02m/28.61p   190.65m/31.75p   220.29m/24.77p
|dV/dt_f   187.34m/47.79p   172.24m/56.27p   213.07m/39.10p
R_load = 50
[Rising Waveform]
R_fixture = 50
V_fixture = 0.0
|   Time   V(typ)   V(min)   V(max)
0s        810.2uV    712.3uV    585.4uV
56ps      475.4uV    -111.4uV   11.33mV
64ps      3.486mV    -518.4uV   54.83mV
76ps      16.68mV    2.187mV    174.1mV
85ps      58.94mV    7.151mV    260.8mV
98ps      161.8mV    26.07mV    348.3mV
125ps     326.1mV    184.8mV    422.6mV
152ps     384.2mV    315.7mV    438.2mV
182ps     399.7mV    367.2mV    440.9mV
363ps     402.8mV    382mV      441.2mV
[Falling Waveform]
R_fixture   = 50
V_fixture   = 1.1
V_fixture_min = 1.06
V_fixture_max = 1.17
|   Time   V(typ)   V(min)   V(max)
0s        1.1V       1.06V      1.17V
71ps      1.099V     1.061V     1.156V
94ps      1.079V     1.053V     1.018V
119ps     968.4mV    1.035V     878.4mV
138ps     884.7mV    977mV      817.4mV
160ps     816.9mV    895.3mV    779.5mV
194ps     761.7mV    803.7mV    755.3mV
231ps     738mV      752.5mV    747.1mV
280ps     728.3mV    726mV      744.4mV
363ps     725.3mV    715.5mV    743.9mV
[Rising Waveform]
R_fixture   = 50
V_fixture   = 1.1
V_fixture_min = 1.06
V_fixture_max = 1.17
|   Time   V(typ)   V(min)   V(max)
0s        724.9mV    713.8mV    743.8mV
50ps      720.9mV    710.8mV    749.3mV
60ps      727.4mV    707.1mV    787.5mV
73ps      773.7mV    715.6mV    888.2mV
87ps      862.5mV    763.6mV    974.2mV
104ps     945mV      856.4mV    1.042V
121ps     997.3mV    926.1mV    1.087V
142ps     1.038V     978.5mV    1.121V
213ps     1.088V     1.044V     1.161V
363ps     1.099V     1.059V     1.17V
[Falling Waveform]
R_fixture = 50
V_fixture = 0.0
|   Time   V(typ)   V(min)   V(max)
0s        403mV      382.2mV    441.3mV
55ps      409.5mV    383.4mV    444.4mV
72ps      403.3mV    395mV      343mV
84ps      345.7mV    389mV      214mV
96ps      252.4mV    346.5mV    130.5mV
113ps     135.8mV    244.8mV    65.79mV
132ps     66.45mV    138.5mV    30.96mV
157ps     26.38mV    57.26mV    11.8mV
190ps     8.323mV    17.9mV     3.605mV
363ps     877.8uV    835.8uV    612.4uV
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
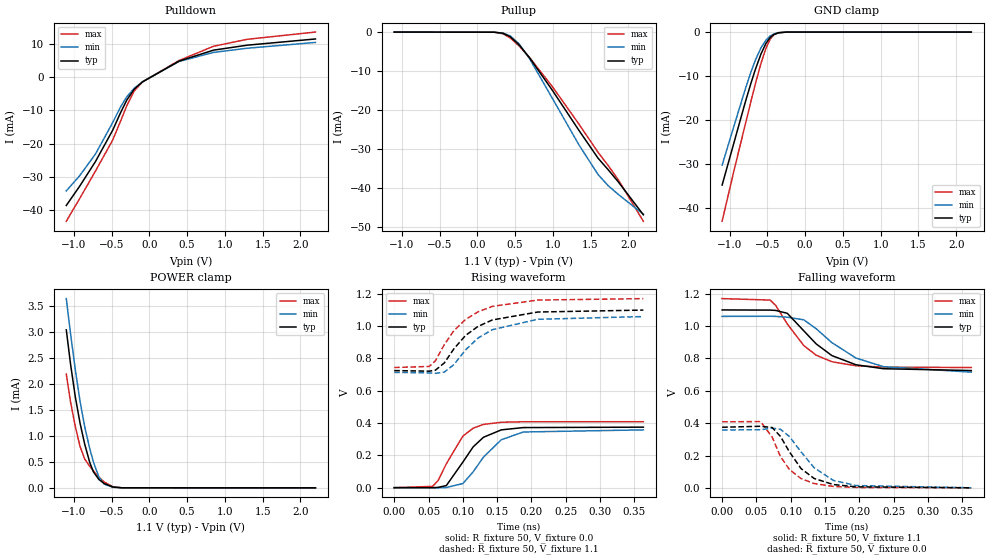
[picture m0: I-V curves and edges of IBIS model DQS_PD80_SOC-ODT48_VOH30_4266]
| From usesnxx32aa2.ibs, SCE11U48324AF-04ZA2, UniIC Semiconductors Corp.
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| DQS_PD80_SOC-ODT48_VOH30_4266
| (80 Ohm Pulldown, 48 Ohm System ODT Setting, VOH=VDDQ/3.0, 3200-4266Mbps)
[Model]   DQS_PD80_SOC-ODT48_VOH30_4266
Model_type   I/O
Vinl = 123.333mV
Vinh = 243.333mV
Vmeas = 183.333mV
Vref = 0.0mV
Cref = 0.0pF
Rref = 48.000Ohm
|   typ   min   max
|C_comp   0.838pF   0.788pF   0.888pF
C_comp_pullup   0.4190pF   0.3940pF   0.4440pF
C_comp_pulldown   0.4190pF   0.3940pF   0.4440pF
| Note: C_comp changes when the ODT circuit is enabled.
[Model Spec]
| Input threshold voltage corners
Vinl   0.1233V   0.1167V   0.1350V
Vinh   0.2433V   0.2367V   0.2550V
| Measurement voltage corners
Vmeas   0.1833V   0.1767V   0.1950V
| Timing spec test load voltage corners
Vref   0.0000V   0.0000V   0.0000V
| Dynamic Overshoot Parameters from LPDDR4 Specification
D_overshoot_ampl_h   0.30   NA   NA
D_overshoot_ampl_l   0.30   NA   NA
D_overshoot_area_h   0.1n   NA   NA
D_overshoot_area_l   0.1n   NA   NA
[Receiver Thresholds]
Vcross_low   = 123.3mV
Vcross_high  = 243.3mV
Vdiff_ac   = 120mV
Vdiff_dc   = 120mV
Tdiffslew_ac = 10.000ns |Not specified, so set to high value
[Voltage Range]   1.1000V   1.0600V   1.1700V
[Pullup Reference]   1.1000V   1.0600V   1.1700V
| Junction Temperature (Ambient temp is 35C typ 95C min -40C max)
[Temperature Range]   50.0   110.0   -40.0
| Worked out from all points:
|   slope of the pulldown table from 0 to 0.165 V, typ, clamps not added: 73.9 ohm
|   slope of the pullup table from 0 to 0.165 V, typ, clamps not added: 15.6 kohm
|   GND clamp passes 1 mA (typ) near -0.45 V on its own axis
|   POWER clamp passes 1 mA (typ) near -0.88 V on its own axis
|   rising waveform, R_fixture 50, V_fixture 0.0: 20-80 % time 37.4ps typ, 41.8ps min, 33ps max; typ from 0.001 V to 0.375 V
|   falling waveform, R_fixture 50, V_fixture 1.1: 20-80 % time 59.8ps typ, 70.2ps min, 48.9ps max; typ from 1.1 V to 0.725 V
|   rising waveform, R_fixture 50, V_fixture 1.1: 20-80 % time 56.9ps typ, 58.8ps min, 54.3ps max; typ from 0.725 V to 1.1 V
|   falling waveform, R_fixture 50, V_fixture 0.0: 20-80 % time 39.5ps typ, 45.8ps min, 34.5ps max; typ from 0.375 V to 0.001 V
[Pulldown]
|   Voltage   I(typ)   I(min)   I(max)
-1.1V     -38.53mA   -34.15mA   -43.28mA
-925.1mV  -32.82mA   -29.67mA   -36.55mA
-713.9mV  -25.35mA   -23.09mA   -28.21mA
-486.2mV  -15.96mA   -13.67mA   -18.92mA
-380.6mV  -10.64mA   -8.91mA    -13.17mA
-298.1mV  -6.842mA   -5.853mA   -8.518mA
-199.1mV  -3.563mA   -3.302mA   -4.081mA
-90.2mV   -1.396mA   -1.37mA    -1.397mA
394.9mV   4.856mA    4.742mA    5.045mA
850.3mV   8.134mA    7.462mA    9.296mA
1.296V    9.622mA    8.703mA    11.39mA
2.2V      11.49mA    10.45mA    13.57mA
[GND Clamp]
|   Voltage   I(typ)   I(min)   I(max)
-1.1V     -34.88mA   -30.35mA   -43.13mA
-941.6mV  -25.13mA   -21.34mA   -31.48mA
-793.1mV  -15.98mA   -13.01mA   -21.06mA
-717.2mV  -11.61mA   -9.056mA   -15.72mA
-661.1mV  -8.597mA   -6.455mA   -11.9mA
-585.2mV  -4.99mA    -3.583mA   -7.136mA
-519.2mV  -2.57mA    -1.835mA   -3.672mA
-463.1mV  -1.239mA   -901.9uA   -1.601mA
-413.6mV  -565.8uA   -418.1uA   -622.4uA
-354.2mV  -179.3uA   -135.3uA   -160.7uA
-248.6mV  -12.12uA   -10.94uA   -7.138uA
2.2V      0A         0A         0A
[Pullup]
|   Voltage   I(typ)   I(min)   I(max)
-1.1V     5.237uA    8.07uA     2.361uA
226.6mV   -35.36uA   -35.94uA   -35.68uA
342.1mV   -317.5uA   -261.3uA   -439.1uA
437.8mV   -1.204mA   -986.3uA   -1.515mA
556.6mV   -3.33mA    -3.082mA   -3.599mA
695.2mV   -6.659mA   -6.89mA    -6.57mA
998.8mV   -15.02mA   -17.09mA   -14.08mA
1.349V    -25.23mA   -28.94mA   -23.63mA
1.599V    -32.26mA   -36.44mA   -30.76mA
1.731V    -35.17mA   -39.27mA   -34.08mA
1.867V    -38.32mA   -41.54mA   -37.79mA
2.2V      -46.77mA   -46.65mA   -48.43mA
[POWER Clamp]
|   Voltage   I(typ)   I(min)   I(max)
-1.1V     3.036mA    3.636mA    2.186mA
-1.044V   2.383mA    2.969mA    1.654mA
-981.2mV  1.754mA    2.277mA    1.183mA
-918.5mV  1.248mA    1.669mA    798.5uA
-855.8mV  838uA      1.173mA    552.3uA
-789.8mV  491.2uA    757.6uA    414.8uA
-740.3mV  306.2uA    494.6uA    324.3uA
-667.7mV  159.9uA    206.2uA    205.2uA
-598.4mV  83.65uA    71.96uA    113.1uA
-482.9mV  15.79uA    9.506uA    19.54uA
-364.1mV  1.112uA    824.5nA    869.8nA
2.2V      0A         0A         0A
[Ramp]
|   typ   min   max
| 20% - 80%
dV/dt_r   224.51m/37.40p   214.49m/41.83p   244.82m/32.98p
dV/dt_f   224.80m/59.74p   206.69m/70.23p   255.68m/48.97p
| 25% - 75%
|dV/dt_r   187.09m/29.85p   178.74m/33.35p   204.02m/26.23p
|dV/dt_f   187.33m/47.53p   172.24m/55.90p   213.07m/38.96p
R_load = 50
[Rising Waveform]
R_fixture = 50
V_fixture = 0.0
|   Time   V(typ)   V(min)   V(max)
0s        674.4uV    591.2uV    487.8uV
56ps      357uV      -41.62uV   8.69mV
64ps      2.666mV    -412.1uV   45.23mV
76ps      13.81mV    1.593mV    148.7mV
100ps     158.5mV    26.07mV    319.3mV
115ps     252.8mV    98.03mV    368.4mV
130ps     312.3mV    189.5mV    391.7mV
156ps     358.1mV    296.9mV    405.2mV
188ps     372.3mV    345mV      408.2mV
363ps     374.9mV    358.1mV    408.5mV
[Falling Waveform]
R_fixture   = 50
V_fixture   = 1.1
V_fixture_min = 1.06
V_fixture_max = 1.17
|   Time   V(typ)   V(min)   V(max)
0s        1.1V       1.06V      1.17V
70ps      1.099V     1.061V     1.161V
78ps      1.097V     1.06V      1.128V
95ps      1.079V     1.055V     1.013V
119ps     970.8mV    1.039V     879.5mV
137ps     890.1mV    983.9mV    820.4mV
160ps     817.6mV    897.6mV    779.8mV
195ps     761.1mV    802.6mV    754.9mV
235ps     736.7mV    749.4mV    746.7mV
363ps     725.3mV    715.5mV    743.9mV
[Rising Waveform]
R_fixture   = 50
V_fixture   = 1.1
V_fixture_min = 1.06
V_fixture_max = 1.17
|   Time   V(typ)   V(min)   V(max)
0s        724.9mV    713.8mV    743.8mV
51ps      721.1mV    710.4mV    750.5mV
60ps      727.2mV    707.4mV    785.3mV
73ps      772mV      715.4mV    885.3mV
87ps      859.6mV    761.8mV    972mV
104ps     942.3mV    853mV      1.041V
122ps     997.8mV    925.8mV    1.088V
143ps     1.038V     977.8mV    1.122V
209ps     1.087V     1.042V     1.161V
363ps     1.099V     1.059V     1.17V
[Falling Waveform]
R_fixture = 50
V_fixture = 0.0
|   Time   V(typ)   V(min)   V(max)
0s        375mV      358.2mV    408.6mV
56ps      381mV      359.6mV    410.1mV
73ps      372.9mV    369.4mV    313.6mV
85ps      318.3mV    362.5mV    194.1mV
98ps      223.2mV    317.6mV    113.9mV
115ps     119.5mV    223mV      57.56mV
134ps     58.55mV    124.8mV    27.08mV
162ps     20.96mV    46.46mV    9.218mV
195ps     6.68mV     14.66mV    2.838mV
363ps     755.7uV    726.1uV    517.5uV
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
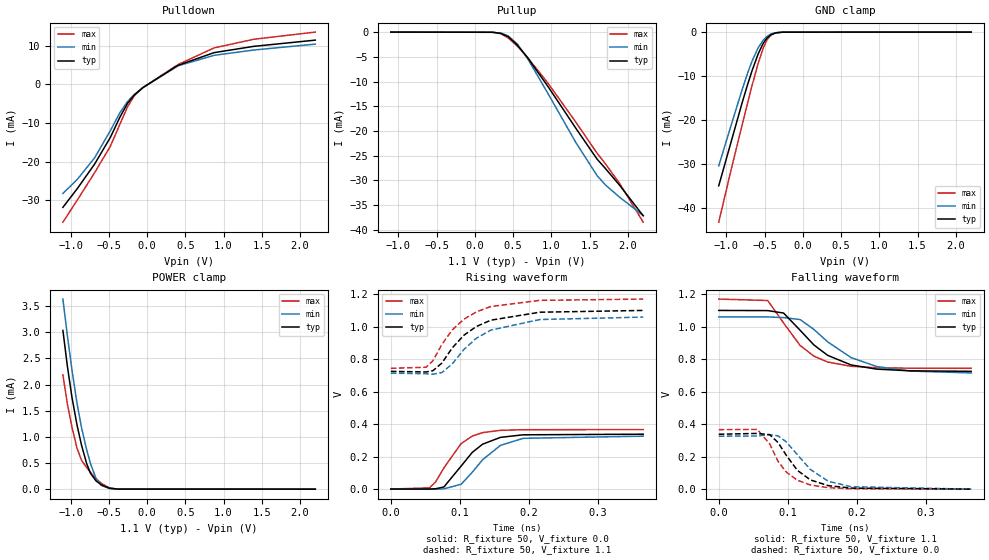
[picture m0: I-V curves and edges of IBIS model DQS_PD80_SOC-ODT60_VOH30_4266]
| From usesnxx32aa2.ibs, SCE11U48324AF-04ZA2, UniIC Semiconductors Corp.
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| DQS_PD80_SOC-ODT60_VOH30_4266
| (80 Ohm Pulldown, 60 Ohm System ODT Setting, VOH=VDDQ/3.0, 3200-4266Mbps)
[Model]   DQS_PD80_SOC-ODT60_VOH30_4266
Model_type   I/O
Vinl = 123.333mV
Vinh = 243.333mV
Vmeas = 183.333mV
Vref = 0.0mV
Cref = 0.0pF
Rref = 60.000Ohm
|   typ   min   max
|C_comp   0.838pF   0.788pF   0.888pF
C_comp_pullup   0.4190pF   0.3940pF   0.4440pF
C_comp_pulldown   0.4190pF   0.3940pF   0.4440pF
| Note: C_comp changes when the ODT circuit is enabled.
[Model Spec]
| Input threshold voltage corners
Vinl   0.1233V   0.1167V   0.1350V
Vinh   0.2433V   0.2367V   0.2550V
| Measurement voltage corners
Vmeas   0.1833V   0.1767V   0.1950V
| Timing spec test load voltage corners
Vref   0.0000V   0.0000V   0.0000V
| Dynamic Overshoot Parameters from LPDDR4 Specification
D_overshoot_ampl_h   0.30   NA   NA
D_overshoot_ampl_l   0.30   NA   NA
D_overshoot_area_h   0.1n   NA   NA
D_overshoot_area_l   0.1n   NA   NA
[Receiver Thresholds]
Vcross_low   = 123.3mV
Vcross_high  = 243.3mV
Vdiff_ac   = 120mV
Vdiff_dc   = 120mV
Tdiffslew_ac = 10.000ns |Not specified, so set to high value
[Voltage Range]   1.1000V   1.0600V   1.1700V
[Pullup Reference]   1.1000V   1.0600V   1.1700V
| Junction Temperature (Ambient temp is 35C typ 95C min -40C max)
[Temperature Range]   50.0   110.0   -40.0
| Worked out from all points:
|   slope of the pulldown table from 0 to 0.165 V, typ, clamps not added: 74.1 ohm
|   slope of the pullup table from 0 to 0.165 V, typ, clamps not added: 19.3 kohm
|   GND clamp passes 1 mA (typ) near -0.45 V on its own axis
|   POWER clamp passes 1 mA (typ) near -0.88 V on its own axis
|   rising waveform, R_fixture 50, V_fixture 0.0: 20-80 % time 40.9ps typ, 44.8ps min, 36ps max; typ from 0.001 V to 0.338 V
|   falling waveform, R_fixture 50, V_fixture 1.1: 20-80 % time 59.5ps typ, 69.9ps min, 48.8ps max; typ from 1.1 V to 0.725 V
|   rising waveform, R_fixture 50, V_fixture 1.1: 20-80 % time 57.9ps typ, 60ps min, 54.5ps max; typ from 0.725 V to 1.1 V
|   falling waveform, R_fixture 50, V_fixture 0.0: 20-80 % time 39.4ps typ, 46.2ps min, 34.5ps max; typ from 0.338 V to 0.001 V
[Pulldown]
|   Voltage   I(typ)   I(min)   I(max)
-1.1V     -31.82mA   -28.22mA   -35.66mA
-911.9mV  -26.97mA   -24.58mA   -29.93mA
-684.2mV  -20.58mA   -18.96mA   -22.8mA
-479.6mV  -13.7mA    -11.96mA   -16.01mA
-354.2mV  -8.452mA   -7.282mA   -10.26mA
-255.2mV  -4.899mA   -4.423mA   -5.802mA
-169.4mV  -2.773mA   -2.658mA   -2.979mA
-53.9mV   -810.7uA   -802.3uA   -796.1uA
404.8mV   4.955mA    4.835mA    5.159mA
876.7mV   8.251mA    7.554mA    9.471mA
1.395V    9.872mA    8.928mA    11.71mA
2.2V      11.49mA    10.45mA    13.57mA
[GND Clamp]
|   Voltage   I(typ)   I(min)   I(max)
-1.1V     -34.88mA   -30.34mA   -43.13mA
-935mV    -24.71mA   -20.97mA   -31mA
-793.1mV  -15.98mA   -13.01mA   -21.06mA
-720.5mV  -11.79mA   -9.217mA   -15.95mA
-661.1mV  -8.597mA   -6.454mA   -11.9mA
-585.2mV  -4.987mA   -3.583mA   -7.136mA
-519.2mV  -2.57mA    -1.838mA   -3.672mA
-469.7mV  -1.359mA   -986.6uA   -1.794mA
-416.9mV  -597.1uA   -442uA     -666.7uA
-357.5mV  -191.5uA   -144.1uA   -174.1uA
-265.1mV  -19.5uA    -17uA      -12.35uA
2.2V      0A         0A         0A
[Pullup]
|   Voltage   I(typ)   I(min)   I(max)
-1.1V     4.189uA    6.456uA    1.888uA
229.9mV   -30.49uA   -30.57uA   -31.15uA
342.1mV   -255.9uA   -210.1uA   -350.4uA
437.8mV   -961.1uA   -787.8uA   -1.21mA
553.3mV   -2.604mA   -2.4mA     -2.822mA
685.3mV   -5.113mA   -5.256mA   -5.067mA
949.3mV   -10.87mA   -12.27mA   -10.21mA
1.319V    -19.44mA   -22.31mA   -18.2mA
1.596V    -25.66mA   -28.99mA   -24.47mA
1.705V    -27.56mA   -30.89mA   -26.61mA
1.89V     -30.93mA   -33.36mA   -30.56mA
2.2V      -37.14mA   -37.08mA   -38.43mA
[POWER Clamp]
|   Voltage   I(typ)   I(min)   I(max)
-1.1V     3.036mA    3.636mA    2.186mA
-1.041V   2.347mA    2.931mA    1.626mA
-981.2mV  1.754mA    2.277mA    1.183mA
-915.2mV  1.224mA    1.64mA     781.4uA
-855.8mV  838uA      1.173mA    552.1uA
-789.8mV  491.1uA    757.5uA    414.8uA
-740.3mV  306.2uA    494.6uA    324.3uA
-667.7mV  159.9uA    206.2uA    205.2uA
-598.4mV  83.65uA    71.98uA    113.1uA
-492.8mV  18.9uA     11.62uA    24.07uA
-383.9mV  1.737uA    1.212uA    1.469uA
2.2V      0A         0A         0A
[Ramp]
|   typ   min   max
| 20% - 80%
dV/dt_r   202.54m/40.89p   195.31m/44.78p   219.64m/36.00p
dV/dt_f   224.80m/59.49p   206.67m/69.91p   255.68m/48.83p
| 25% - 75%
|dV/dt_r   168.78m/32.61p   162.76m/35.72p   183.03m/28.61p
|dV/dt_f   187.33m/47.42p   172.23m/55.74p   213.07m/38.80p
R_load = 50
[Rising Waveform]
R_fixture = 50
V_fixture = 0.0
|   Time   V(typ)   V(min)   V(max)
0s        535uV      465uV      387.2uV
56ps      280.8uV    -40.93uV   7.75mV
65ps      2.346mV    -326.7uV   44.21mV
77ps      13.19mV    1.636mV    131.2mV
102ps     142.2mV    29.72mV    280.6mV
118ps     225.6mV    103.3mV    326.4mV
133ps     276.4mV    180.4mV    347.8mV
159ps     318.6mV    269.3mV    361.9mV
192ps     334.3mV    312.7mV    365.8mV
366ps     338.1mV    326mV      366.5mV
[Falling Waveform]
R_fixture   = 50
V_fixture   = 1.1
V_fixture_min = 1.06
V_fixture_max = 1.17
|   Time   V(typ)   V(min)   V(max)
0s        1.1V       1.06V      1.17V
71ps      1.099V     1.06V      1.161V
94ps      1.084V     1.056V     1.023V
118ps     978.1mV    1.044V     884.9mV
138ps     887.7mV    983.2mV    818.6mV
158ps     823.6mV    906.7mV    782.5mV
192ps     764.6mV    809.7mV    756.3mV
229ps     739mV      755.2mV    747.5mV
278ps     728.5mV    726.8mV    744.6mV
366ps     725.3mV    715.5mV    743.9mV
[Rising Waveform]
R_fixture   = 50
V_fixture   = 1.1
V_fixture_min = 1.06
V_fixture_max = 1.17
|   Time   V(typ)   V(min)   V(max)
0s        724.9mV    713.8mV    743.8mV
51ps      721.2mV    710.5mV    750.2mV
61ps      728.7mV    707.4mV    789.6mV
74ps      775.9mV    717.3mV    890.1mV
89ps      868.7mV    770.4mV    979.7mV
106ps     947.3mV    859.9mV    1.046V
124ps     1.001V     928.7mV    1.091V
145ps     1.04V      978.9mV    1.124V
216ps     1.089V     1.044V     1.162V
366ps     1.1V       1.059V     1.17V
[Falling Waveform]
R_fixture = 50
V_fixture = 0.0
|   Time   V(typ)   V(min)   V(max)
0s        338.2mV    326.1mV    366.5mV
56ps      343.4mV    327.6mV    368.1mV
74ps      335.4mV    336.1mV    278mV
86ps      287.5mV    328.1mV    171.6mV
98ps      208.4mV    291.1mV    105mV
114ps     116.3mV    212.6mV    55.36mV
133ps     57.06mV    121.2mV    26.01mV
159ps     22mV       48.85mV    9.483mV
192ps     6.911mV    15.42mV    2.864mV
366ps     630.2uV    619.8uV    420.3uV
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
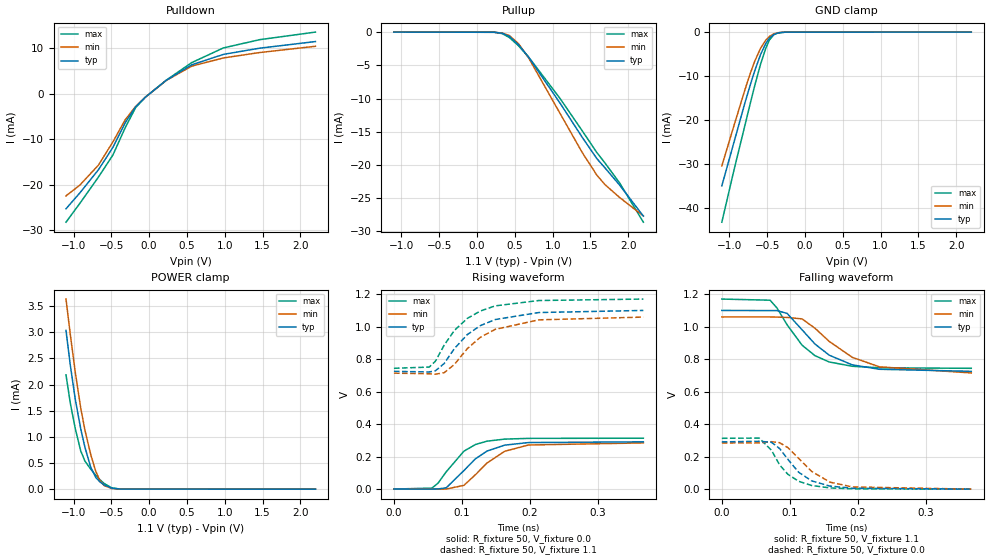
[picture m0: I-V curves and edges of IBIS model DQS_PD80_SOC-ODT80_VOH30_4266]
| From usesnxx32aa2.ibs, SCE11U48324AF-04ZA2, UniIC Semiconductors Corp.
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| DQS_PD80_SOC-ODT80_VOH30_4266
| (80 Ohm Pulldown, 80 Ohm System ODT Setting, VOH=VDDQ/3.0, 3200-4266Mbps)
[Model]   DQS_PD80_SOC-ODT80_VOH30_4266
Model_type   I/O
Vinl = 123.333mV
Vinh = 243.333mV
Vmeas = 183.333mV
Vref = 0.0mV
Cref = 0.0pF
Rref = 80.000Ohm
|   typ   min   max
|C_comp   0.838pF   0.788pF   0.888pF
C_comp_pullup   0.4190pF   0.3940pF   0.4440pF
C_comp_pulldown   0.4190pF   0.3940pF   0.4440pF
| Note: C_comp changes when the ODT circuit is enabled.
[Model Spec]
| Input threshold voltage corners
Vinl   0.1233V   0.1167V   0.1350V
Vinh   0.2433V   0.2367V   0.2550V
| Measurement voltage corners
Vmeas   0.1833V   0.1767V   0.1950V
| Timing spec test load voltage corners
Vref   0.0000V   0.0000V   0.0000V
| Dynamic Overshoot Parameters from LPDDR4 Specification
D_overshoot_ampl_h   0.30   NA   NA
D_overshoot_ampl_l   0.30   NA   NA
D_overshoot_area_h   0.1n   NA   NA
D_overshoot_area_l   0.1n   NA   NA
[Receiver Thresholds]
Vcross_low   = 123.3mV
Vcross_high  = 243.3mV
Vdiff_ac   = 120mV
Vdiff_dc   = 120mV
Tdiffslew_ac = 10.000ns |Not specified, so set to high value
[Voltage Range]   1.1000V   1.0600V   1.1700V
[Pullup Reference]   1.1000V   1.0600V   1.1700V
| Junction Temperature (Ambient temp is 35C typ 95C min -40C max)
[Temperature Range]   50.0   110.0   -40.0
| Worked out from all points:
|   slope of the pulldown table from 0 to 0.165 V, typ, clamps not added: 74.3 ohm
|   slope of the pullup table from 0 to 0.165 V, typ, clamps not added: 25.9 kohm
|   GND clamp passes 1 mA (typ) near -0.45 V on its own axis
|   POWER clamp passes 1 mA (typ) near -0.88 V on its own axis
|   rising waveform, R_fixture 50, V_fixture 0.0: 20-80 % time 44.6ps typ, 47.6ps min, 38.9ps max; typ from 0 V to 0.291 V
|   falling waveform, R_fixture 50, V_fixture 1.1: 20-80 % time 59.2ps typ, 69.5ps min, 48.7ps max; typ from 1.1 V to 0.725 V
|   rising waveform, R_fixture 50, V_fixture 1.1: 20-80 % time 58.5ps typ, 61ps min, 54.6ps max; typ from 0.725 V to 1.1 V
|   falling waveform, R_fixture 50, V_fixture 0.0: 20-80 % time 40ps typ, 46.9ps min, 35.1ps max; typ from 0.291 V to 0 V
[Pulldown]
|   Voltage   I(typ)   I(min)   I(max)
-1.1V     -25.26mA   -22.43mA   -28.21mA
-918.5mV  -21.81mA   -20.09mA   -24.11mA
-671mV    -16.69mA   -15.67mA   -18.3mA
-479.6mV  -11.77mA   -10.57mA   -13.45mA
-317.9mV  -6.38mA    -5.728mA   -7.478mA
-179.3mV  -2.865mA   -2.772mA   -3.048mA
-50.6mV   -748.6uA   -743.9uA   -734.9uA
226.6mV   2.976mA    2.943mA    3.006mA
563.2mV   6.375mA    6.087mA    6.861mA
982.3mV   8.669mA    7.889mA    10.09mA
1.461V    10.03mA    9.072mA    11.9mA
2.2V      11.49mA    10.45mA    13.57mA
[GND Clamp]
|   Voltage   I(typ)   I(min)   I(max)
-1.1V     -34.88mA   -30.35mA   -43.13mA
-938.3mV  -24.92mA   -21.15mA   -31.24mA
-793.1mV  -15.98mA   -13.01mA   -21.06mA
-720.5mV  -11.8mA    -9.217mA   -15.95mA
-664.4mV  -8.768mA   -6.598mA   -12.12mA
-588.5mV  -5.127mA   -3.689mA   -7.328mA
-519.2mV  -2.578mA   -1.836mA   -3.672mA
-469.7mV  -1.364mA   -986.6uA   -1.79mA
-413.6mV  -569.2uA   -417.2uA   -621.2uA
-354.2mV  -178.3uA   -134.7uA   -160uA
-255.2mV  -14.67uA   -13.01uA   -8.795uA
2.2V      0A         0A         0A
[Pullup]
|   Voltage   I(typ)   I(min)   I(max)
-1.1V     3.142uA    4.844uA    1.416uA
229.9mV   -22.59uA   -22.99uA   -23.3uA
335.5mV   -170.6uA   -141.9uA   -234.8uA
427.9mV   -643.3uA   -523.7uA   -821.8uA
546.7mV   -1.867mA   -1.71mA    -2.037mA
682mV     -3.779mA   -3.877mA   -3.751mA
1.098V    -10.69mA   -12.24mA   -9.991mA
1.391V    -15.83mA   -18.12mA   -14.85mA
1.586V    -19.06mA   -21.55mA   -18.15mA
1.692V    -20.43mA   -22.95mA   -19.69mA
1.887V    -23.04mA   -24.9mA    -22.72mA
2.2V      -27.69mA   -27.67mA   -28.61mA
[POWER Clamp]
|   Voltage   I(typ)   I(min)   I(max)
-1.1V     3.036mA    3.636mA    2.186mA
-1.044V   2.383mA    2.969mA    1.654mA
-977.9mV  1.724mA    2.242mA    1.161mA
-905.3mV  1.155mA    1.554mA    732.4uA
-849.2mV  799.4uA    1.126mA    535.5uA
-773.3mV  420.9uA    665.7uA    384.1uA
-707.3mV  225.5uA    345.5uA    267.6uA
-651.2mV  138.6uA    162.3uA    181.2uA
-595.1mV  80.78uA    68.3uA     109.2uA
-492.8mV  18.88uA    11.57uA    24.05uA
-377.3mV  1.518uA    1.061uA    1.226uA
2.2V      0A         0A         0A
[Ramp]
|   typ   min   max
| 20% - 80%
dV/dt_r   174.43m/44.59p   170.42m/47.61p   187.85m/38.95p
dV/dt_f   224.82m/59.27p   206.67m/69.53p   255.68m/48.74p
| 25% - 75%
|dV/dt_r   145.36m/35.59p   142.02m/37.95p   156.54m/30.97p
|dV/dt_f   187.35m/47.19p   172.23m/55.38p   213.07m/38.68p
R_load = 50
[Rising Waveform]
R_fixture = 50
V_fixture = 0.0
|   Time   V(typ)   V(min)   V(max)
0s        396uV      338.5uV    287.9uV
56ps      30.9uV     75.77uV    6.19mV
65ps      938.1uV    -371.4uV   36.98mV
77ps      8.274mV    377.2uV    107mV
103ps     114.2mV    23.16mV    233.6mV
120ps     186.7mV    88.84mV    274.6mV
137ps     234.3mV    160.6mV    295.2mV
163ps     270.7mV    232.9mV    307.8mV
198ps     286.6mV    271.6mV    312.3mV
367ps     291.1mV    284.4mV    313.4mV
[Falling Waveform]
R_fixture   = 50
V_fixture   = 1.1
V_fixture_min = 1.06
V_fixture_max = 1.17
|   Time   V(typ)   V(min)   V(max)
0s        1.1V       1.06V      1.17V
71ps      1.099V     1.06V      1.163V
81ps      1.099V     1.059V     1.116V
96ps      1.082V     1.057V     1.012V
118ps     981.1mV    1.048V     886.5mV
137ps     893.5mV    990.6mV    821.9mV
158ps     824.7mV    909.5mV    782.9mV
192ps     765mV      811.2mV    756.4mV
232ps     738mV      753mV      747.2mV
367ps     725.3mV    715.5mV    743.9mV
[Rising Waveform]
R_fixture   = 50
V_fixture   = 1.1
V_fixture_min = 1.06
V_fixture_max = 1.17
|   Time   V(typ)   V(min)   V(max)
0s        724.9mV    713.8mV    743.8mV
52ps      721.4mV    710.3mV    751.3mV
61ps      728.1mV    707.6mV    787.2mV
74ps      773.5mV    716.6mV    886.8mV
89ps      865.3mV    767.8mV    977mV
108ps     951.5mV    865.3mV    1.051V
127ps     1.006V     934mV      1.096V
149ps     1.044V     983.4mV    1.128V
213ps     1.087V     1.042V     1.161V
367ps     1.1V       1.059V     1.17V
[Falling Waveform]
R_fixture = 50
V_fixture = 0.0
|   Time   V(typ)   V(min)   V(max)
0s        291.2mV    284.5mV    313.4mV
55ps      295mV      285.2mV    314.6mV
73ps      288.7mV    292.4mV    239.8mV
85ps      250.4mV    286.3mV    149.8mV
97ps      184.7mV    256.2mV    92.35mV
113ps     104.4mV    189.8mV    48.9mV
132ps     51.71mV    110mV      23.05mV
159ps     19.29mV    43.57mV    8.099mV
192ps     6.046mV    13.98mV    2.425mV
367ps     492uV      497.4uV    322.9uV
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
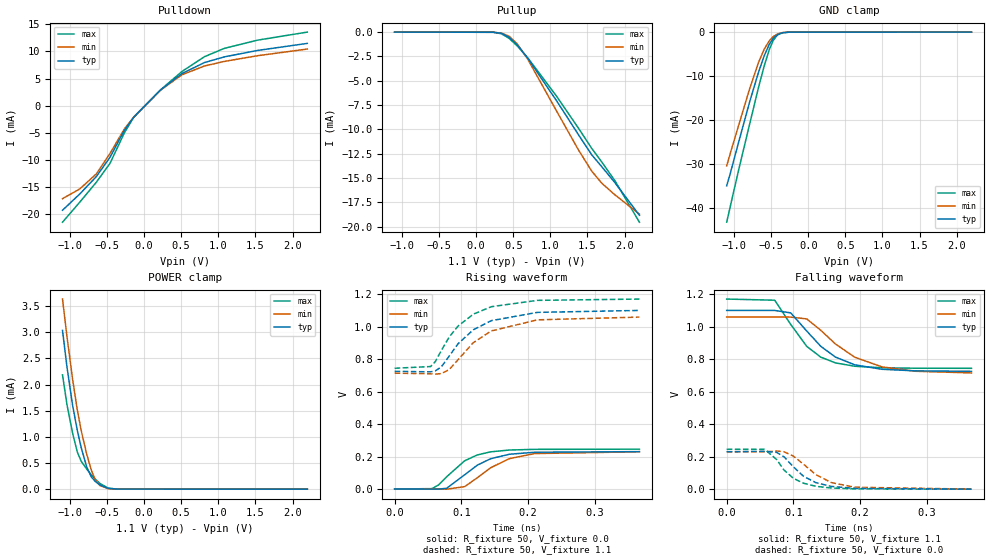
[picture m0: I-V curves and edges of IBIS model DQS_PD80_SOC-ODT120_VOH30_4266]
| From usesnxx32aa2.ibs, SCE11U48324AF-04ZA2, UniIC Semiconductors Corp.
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| DQS_PD80_SOC-ODT120_VOH30_4266
| (80 Ohm Pulldown, 120 Ohm System ODT Setting, VOH=VDDQ/3.0, 3200-4266Mbps)
[Model]   DQS_PD80_SOC-ODT120_VOH30_4266
Model_type   I/O
Vinl = 123.333mV
Vinh = 243.333mV
Vmeas = 183.333mV
Vref = 0.0mV
Cref = 0.0pF
Rref = 120.000Ohm
|   typ   min   max
|C_comp   0.838pF   0.788pF   0.888pF
C_comp_pullup   0.4190pF   0.3940pF   0.4440pF
C_comp_pulldown   0.4190pF   0.3940pF   0.4440pF
| Note: C_comp changes when the ODT circuit is enabled.
[Model Spec]
| Input threshold voltage corners
Vinl   0.1233V   0.1167V   0.1350V
Vinh   0.2433V   0.2367V   0.2550V
| Measurement voltage corners
Vmeas   0.1833V   0.1767V   0.1950V
| Timing spec test load voltage corners
Vref   0.0000V   0.0000V   0.0000V
| Dynamic Overshoot Parameters from LPDDR4 Specification
D_overshoot_ampl_h   0.30   NA   NA
D_overshoot_ampl_l   0.30   NA   NA
D_overshoot_area_h   0.1n   NA   NA
D_overshoot_area_l   0.1n   NA   NA
[Receiver Thresholds]
Vcross_low   = 123.3mV
Vcross_high  = 243.3mV
Vdiff_ac   = 120mV
Vdiff_dc   = 120mV
Tdiffslew_ac = 10.000ns |Not specified, so set to high value
[Voltage Range]   1.1000V   1.0600V   1.1700V
[Pullup Reference]   1.1000V   1.0600V   1.1700V
| Junction Temperature (Ambient temp is 35C typ 95C min -40C max)
[Temperature Range]   50.0   110.0   -40.0
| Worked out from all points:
|   slope of the pulldown table from 0 to 0.165 V, typ, clamps not added: 74.4 ohm
|   slope of the pullup table from 0 to 0.165 V, typ, clamps not added: 39 kohm
|   GND clamp passes 1 mA (typ) near -0.45 V on its own axis
|   POWER clamp passes 1 mA (typ) near -0.88 V on its own axis
|   rising waveform, R_fixture 50, V_fixture 0.0: 20-80 % time 48.6ps typ, 52.8ps min, 43.2ps max; typ from 0 V to 0.23 V
|   falling waveform, R_fixture 50, V_fixture 1.1: 20-80 % time 58.9ps typ, 69.2ps min, 48.5ps max; typ from 1.1 V to 0.725 V
|   rising waveform, R_fixture 50, V_fixture 1.1: 20-80 % time 58.6ps typ, 61.8ps min, 54.5ps max; typ from 0.725 V to 1.1 V
|   falling waveform, R_fixture 50, V_fixture 0.0: 20-80 % time 39.9ps typ, 46.7ps min, 35.1ps max; typ from 0.231 V to 0 V
[Pulldown]
|   Voltage   I(typ)   I(min)   I(max)
-1.1V     -19.24mA   -17.11mA   -21.44mA
-865.7mV  -16.22mA   -15.3mA    -17.72mA
-644.6mV  -13.04mA   -12.55mA   -14.09mA
-459.8mV  -9.488mA   -8.773mA   -10.6mA
-265.1mV  -4.476mA   -4.242mA   -4.946mA
-139.7mV  -2.089mA   -2.071mA   -2.11mA
220mV     2.896mA    2.865mA    2.922mA
510.4mV   5.938mA    5.717mA    6.318mA
814mV     7.963mA    7.329mA    9.042mA
1.081V    9.006mA    8.169mA    10.57mA
1.53V     10.19mA    9.219mA    12.09mA
2.2V      11.49mA    10.45mA    13.57mA
[GND Clamp]
|   Voltage   I(typ)   I(min)   I(max)
-1.1V     -34.88mA   -30.35mA   -43.13mA
-1.047V   -31.79mA   -27.25mA   -39.23mA
-941.6mV  -25.13mA   -21.34mA   -31.48mA
-789.8mV  -15.79mA   -12.83mA   -20.82mA
-671mV    -9.112mA   -6.888mA   -12.56mA
-595.1mV  -5.416mA   -3.908mA   -7.721mA
-525.8mV  -2.773mA   -1.979mA   -3.977mA
-473mV    -1.423mA   -1.034mA   -1.892mA
-416.9mV  -598uA     -440.6uA   -667uA
-350.9mV  -165.9uA   -125.6uA   -147.6uA
-255.2mV  -14.7uA    -13.08uA   -8.885uA
2.2V      0A         0A         0A
[Pullup]
|   Voltage   I(typ)   I(min)   I(max)
-1.1V     2.095uA    3.229uA    944.4nA
233.2mV   -16.29uA   -16.25uA   -16.91uA
338.8mV   -120.6uA   -99.95uA   -166.3uA
441.1mV   -503uA     -412.9uA   -628.7uA
553.3mV   -1.314mA   -1.213mA   -1.423mA
691.9mV   -2.655mA   -2.748mA   -2.618mA
1.081V    -7.033mA   -8.079mA   -6.566mA
1.382V    -10.59mA   -12.16mA   -9.919mA
1.556V    -12.6mA    -14.28mA   -11.94mA
1.695V    -13.86mA   -15.55mA   -13.38mA
1.867V    -15.45mA   -16.71mA   -15.25mA
2.2V      -18.83mA   -18.71mA   -19.54mA
[POWER Clamp]
|   Voltage   I(typ)   I(min)   I(max)
-1.1V     3.036mA    3.636mA    2.186mA
-1.041V   2.347mA    2.931mA    1.626mA
-964.7mV  1.61mA     2.107mA    1.073mA
-902mV    1.133mA    1.526mA    717.2uA
-849.2mV  799.4uA    1.127mA    535.7uA
-773.3mV  421.1uA    665.4uA    384.1uA
-710.6mV  232.2uA    359.1uA    273.1uA
-657.8mV  146.8uA    178.8uA    190.7uA
-595.1mV  80.76uA    68.3uA     109.3uA
-486.2mV  16.71uA    10.19uA    20.94uA
-367.4mV  1.184uA    877.8nA    953.8nA
2.2V      0A         0A         0A
[Ramp]
|   typ   min   max
| 20% - 80%
dV/dt_r   138.10m/48.60p   137.70m/52.77p   147.31m/43.22p
dV/dt_f   224.82m/58.98p   206.67m/69.19p   255.68m/48.51p
| 25% - 75%
|dV/dt_r   115.09m/38.81p   114.75m/42.11p   122.76m/34.36p
|dV/dt_f   187.35m/47.01p   172.23m/55.16p   213.06m/38.60p
R_load = 50
[Rising Waveform]
R_fixture = 50
V_fixture = 0.0
|   Time   V(typ)   V(min)   V(max)
0s        257uV      214.2uV    187.6uV
56ps      -252.1uV   170.3uV    2.586mV
66ps      -371.5uV   -456.2uV   25.49mV
78ps      4.685mV    -743uV     75.35mV
105ps     87.76mV    14.73mV    174mV
124ps     147.1mV    69.54mV    210.1mV
144ps     186.8mV    131.3mV    229.2mV
172ps     214.2mV    187.2mV    240.2mV
210ps     226.6mV    218.4mV    244.5mV
367ps     230.4mV    229.7mV    245.7mV
[Falling Waveform]
R_fixture   = 50
V_fixture   = 1.1
V_fixture_min = 1.06
V_fixture_max = 1.17
|   Time   V(typ)   V(min)   V(max)
0s        1.1V       1.06V      1.17V
72ps      1.1V       1.06V      1.163V
96ps      1.085V     1.059V     1.014V
120ps     973.3mV    1.048V     879mV
141ps     879.4mV    978mV      812.8mV
163ps     813mV      893.6mV    777.2mV
192ps     765.3mV    812.1mV    756.6mV
233ps     737.8mV    752.4mV    747.1mV
283ps     728.2mV    725.7mV    744.5mV
367ps     725.3mV    715.5mV    743.9mV
[Rising Waveform]
R_fixture   = 50
V_fixture   = 1.1
V_fixture_min = 1.06
V_fixture_max = 1.17
|   Time   V(typ)   V(min)   V(max)
0s        724.9mV    713.8mV    743.8mV
54ps      721.8mV    709.7mV    754.4mV
61ps      727.5mV    707.8mV    784.6mV
70ps      752.4mV    710.9mV    852.8mV
82ps      819.5mV    736.4mV    937.2mV
95ps      894.3mV    795.9mV    1.003V
118ps     981mV      901.8mV    1.077V
145ps     1.037V     973.8mV    1.123V
214ps     1.088V     1.042V     1.162V
367ps     1.1V       1.059V     1.17V
[Falling Waveform]
R_fixture = 50
V_fixture = 0.0
|   Time   V(typ)   V(min)   V(max)
0s        230.5mV    229.8mV    245.8mV
57ps      233.2mV    230.5mV    245.3mV
75ps      226.5mV    234.9mV    182.1mV
86ps      199.3mV    230.4mV    117.6mV
100ps     137.3mV    203.5mV    67.14mV
115ps     80.13mV    154.4mV    37.05mV
134ps     39.85mV    88.71mV    17.54mV
157ps     17.2mV     40.51mV    7.18mV
192ps     5.013mV    12.17mV    1.995mV
367ps     350.8uV    367.2uV    223.4uV
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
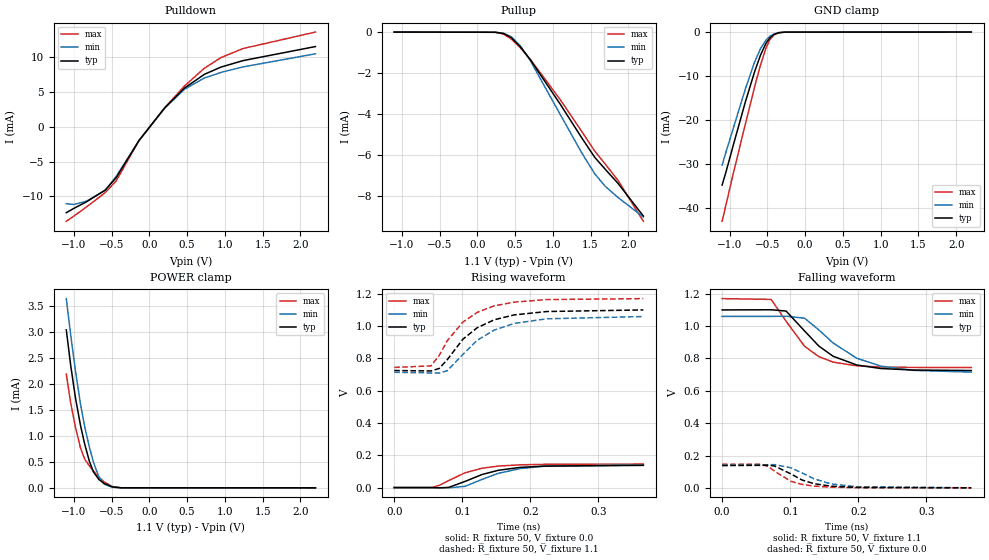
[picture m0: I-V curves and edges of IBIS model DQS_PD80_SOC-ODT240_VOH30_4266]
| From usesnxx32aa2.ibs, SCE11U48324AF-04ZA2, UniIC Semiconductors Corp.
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| DQS_PD80_SOC-ODT240_VOH30_4266
| (80 Ohm Pulldown, 240 Ohm System ODT Setting, VOH=VDDQ/3.0, 3200-4266Mbps)
[Model]   DQS_PD80_SOC-ODT240_VOH30_4266
Model_type   I/O
Vinl = 123.333mV
Vinh = 243.333mV
Vmeas = 183.333mV
Vref = 0.0mV
Cref = 0.0pF
Rref = 240.000Ohm
|   typ   min   max
|C_comp   0.838pF   0.788pF   0.888pF
C_comp_pullup   0.4190pF   0.3940pF   0.4440pF
C_comp_pulldown   0.4190pF   0.3940pF   0.4440pF
| Note: C_comp changes when the ODT circuit is enabled.
[Model Spec]
| Input threshold voltage corners
Vinl   0.1233V   0.1167V   0.1350V
Vinh   0.2433V   0.2367V   0.2550V
| Measurement voltage corners
Vmeas   0.1833V   0.1767V   0.1950V
| Timing spec test load voltage corners
Vref   0.0000V   0.0000V   0.0000V
| Dynamic Overshoot Parameters from LPDDR4 Specification
D_overshoot_ampl_h   0.30   NA   NA
D_overshoot_ampl_l   0.30   NA   NA
D_overshoot_area_h   0.1n   NA   NA
D_overshoot_area_l   0.1n   NA   NA
[Receiver Thresholds]
Vcross_low   = 123.3mV
Vcross_high  = 243.3mV
Vdiff_ac   = 120mV
Vdiff_dc   = 120mV
Tdiffslew_ac = 10.000ns |Not specified, so set to high value
[Voltage Range]   1.1000V   1.0600V   1.1700V
[Pullup Reference]   1.1000V   1.0600V   1.1700V
| Junction Temperature (Ambient temp is 35C typ 95C min -40C max)
[Temperature Range]   50.0   110.0   -40.0
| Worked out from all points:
|   slope of the pulldown table from 0 to 0.165 V, typ, clamps not added: 74.5 ohm
|   slope of the pullup table from 0 to 0.165 V, typ, clamps not added: 78.1 kohm
|   GND clamp passes 1 mA (typ) near -0.45 V on its own axis
|   POWER clamp passes 1 mA (typ) near -0.88 V on its own axis
|   rising waveform, R_fixture 50, V_fixture 0.0: 20-80 % time 58.1ps typ, 60.4ps min, 50.9ps max; typ from 0 V to 0.138 V
|   falling waveform, R_fixture 50, V_fixture 1.1: 20-80 % time 58.8ps typ, 68.8ps min, 48.3ps max; typ from 1.1 V to 0.725 V
|   rising waveform, R_fixture 50, V_fixture 1.1: 20-80 % time 58.7ps typ, 62.8ps min, 54.5ps max; typ from 0.725 V to 1.1 V
|   falling waveform, R_fixture 50, V_fixture 0.0: 20-80 % time 40.5ps typ, 47.9ps min, 36ps max; typ from 0.138 V to 0 V
[Pulldown]
|   Voltage   I(typ)   I(min)   I(max)
-1.1V     -12.33mA   -11.04mA   -13.56mA
-1.001V   -11.72mA   -11.16mA   -12.83mA
-832.7mV  -10.77mA   -10.68mA   -11.51mA
-585.2mV  -9.089mA   -9.146mA   -9.464mA
-440mV    -7.326mA   -7.142mA   -7.785mA
-136.4mV  -1.98mA    -1.983mA   -1.968mA
203.5mV   2.693mA    2.667mA    2.712mA
464.2mV   5.526mA    5.355mA    5.823mA
728.2mV   7.506mA    6.978mA    8.376mA
949.3mV   8.546mA    7.789mA    9.909mA
1.24V     9.472mA    8.571mA    11.2mA
2.2V      11.49mA    10.45mA    13.57mA
[GND Clamp]
|   Voltage   I(typ)   I(min)   I(max)
-1.1V     -34.88mA   -30.34mA   -43.13mA
-1.047V   -31.79mA   -27.25mA   -39.23mA
-944.9mV  -25.34mA   -21.53mA   -31.71mA
-789.8mV  -15.79mA   -12.83mA   -20.82mA
-667.7mV  -8.939mA   -6.742mA   -12.34mA
-591.8mV  -5.272mA   -3.798mA   -7.524mA
-519.2mV  -2.575mA   -1.835mA   -3.671mA
-469.7mV  -1.363mA   -988.1uA   -1.791mA
-413.6mV  -567.6uA   -417.6uA   -621uA
-350.9mV  -168uA     -125.9uA   -147.2uA
-265.1mV  -19.28uA   -16.78uA   -12.22uA
2.2V      0A         0A         0A
[Pullup]
|   Voltage   I(typ)   I(min)   I(max)
-1.1V     1.047uA    1.615uA    471.9nA
239.8mV   -9.375uA   -9.202uA   -9.98uA
348.7mV   -70.59uA   -58.02uA   -97.33uA
454.3mV   -284.8uA   -236.9uA   -350uA
569.8mV   -714uA     -668.5uA   -763.5uA
705.1mV   -1.361mA   -1.411mA   -1.342mA
1.098V    -3.512mA   -4.011mA   -3.291mA
1.385V    -5.165mA   -5.899mA   -4.852mA
1.556V    -6.109mA   -6.911mA   -5.805mA
1.695V    -6.689mA   -7.522mA   -6.437mA
1.867V    -7.391mA   -8.074mA   -7.248mA
2.2V      -8.971mA   -9.018mA   -9.226mA
[POWER Clamp]
|   Voltage   I(typ)   I(min)   I(max)
-1.1V     3.036mA    3.636mA    2.186mA
-1.041V   2.347mA    2.931mA    1.626mA
-977.9mV  1.724mA    2.242mA    1.161mA
-911.9mV  1.201mA    1.612mA    764.4uA
-855.8mV  838uA      1.172mA    552.2uA
-793.1mV  506.2uA    776.1uA    421uA
-740.3mV  306.1uA    494.5uA    324.3uA
-667.7mV  159.9uA    206.1uA    205.2uA
-598.4mV  83.67uA    71.97uA    113.1uA
-489.5mV  17.78uA    10.85uA    22.46uA
-377.3mV  1.49uA     1.056uA    1.228uA
2.2V      0A         0A         0A
[Ramp]
|   typ   min   max
| 20% - 80%
dV/dt_r   82.46m/58.10p   84.21m/60.44p   87.25m/50.87p
dV/dt_f   224.81m/58.76p   206.67m/68.78p   255.67m/48.33p
| 25% - 75%
|dV/dt_r   68.72m/46.24p   70.17m/48.19p   72.71m/40.36p
|dV/dt_f   187.34m/46.79p   172.22m/54.87p   213.06m/38.41p
R_load = 50
[Rising Waveform]
R_fixture = 50
V_fixture = 0.0
|   Time   V(typ)   V(min)   V(max)
0s        114.5uV    84.96uV    84.63uV
56ps      -376.5uV   184.7uV    1.404mV
67ps      -1.502mV   -479.1uV   15.26mV
80ps      1.252mV    -1.409mV   43.36mV
104ps     38.07mV    7.726mV    91.56mV
129ps     80.96mV    50.68mV    119.9mV
153ps     107.2mV    88.21mV    133.3mV
185ps     125mV      117.6mV    141mV
220ps     133.1mV    131.9mV    144mV
366ps     137.6mV    140.4mV    145.5mV
[Falling Waveform]
R_fixture   = 50
V_fixture   = 1.1
V_fixture_min = 1.06
V_fixture_max = 1.17
|   Time   V(typ)   V(min)   V(max)
0s        1.1V       1.06V      1.17V
72ps      1.101V     1.06V      1.165V
94ps      1.093V     1.061V     1.03V
121ps     970.5mV    1.049V     875.8mV
142ps     876.9mV    976.8mV    811.2mV
163ps     813.6mV    895.7mV    777.4mV
198ps     759.3mV    800.8mV    754.3mV
233ps     737.8mV    752.7mV    747mV
281ps     728.3mV    726.4mV    744.5mV
366ps     725.3mV    715.5mV    743.9mV
[Rising Waveform]
R_fixture   = 50
V_fixture   = 1.1
V_fixture_min = 1.06
V_fixture_max = 1.17
|   Time   V(typ)   V(min)   V(max)
0s        724.9mV    713.8mV    743.8mV
54ps      721.9mV    709.8mV    753.5mV
66ps      737.5mV    708.5mV    817.6mV
78ps      792.1mV    724mV      909.4mV
101ps     919.1mV    825mV      1.025V
122ps     989.9mV    912.2mV    1.085V
147ps     1.039V     975.1mV    1.125V
176ps     1.069V     1.016V     1.148V
224ps     1.09V      1.045V     1.164V
366ps     1.1V       1.059V     1.17V
[Falling Waveform]
R_fixture = 50
V_fixture = 0.0
|   Time   V(typ)   V(min)   V(max)
0s        137.7mV    140.6mV    145.5mV
57ps      139.4mV    141.4mV    145.6mV
68ps      139.5mV    143.2mV    132mV
77ps      135.3mV    143.5mV    103mV
101ps     86.17mV    124mV      40.53mV
117ps     49.24mV    93.3mV     21.72mV
135ps     25.7mV     55.73mV    10.75mV
160ps     10.45mV    24.3mV     4.108mV
198ps     2.765mV    6.793mV    1.024mV
366ps     195.8uV    215.9uV    117uV
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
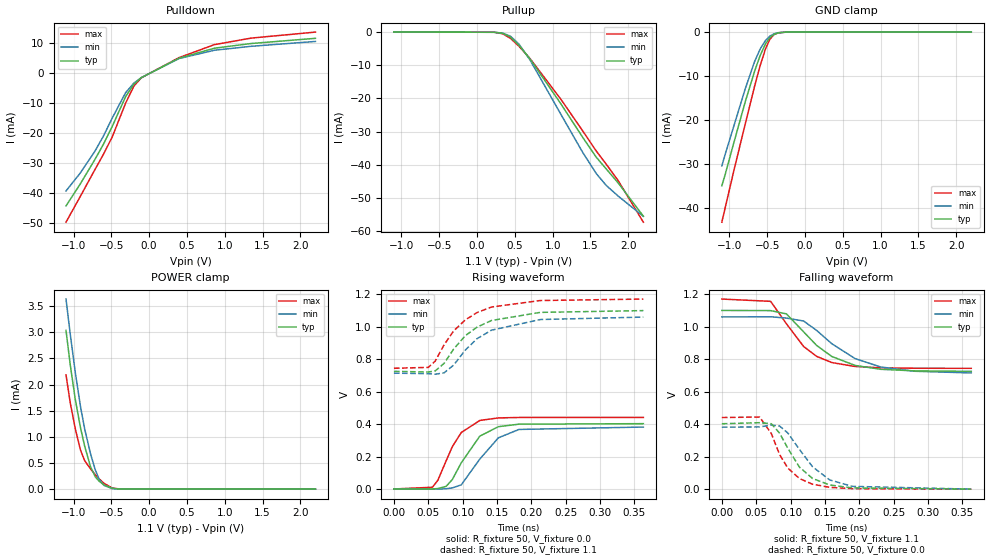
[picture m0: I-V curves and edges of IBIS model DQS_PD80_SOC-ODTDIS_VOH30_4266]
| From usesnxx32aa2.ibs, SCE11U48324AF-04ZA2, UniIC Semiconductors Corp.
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| DQS_PD80_SOC-ODTDIS_VOH30_4266
| (80 Ohm Pulldown, SOC ODT disabled setting, VOH=VDDQ/3.0 cal. point, 3200-4266Mbps)
[Model]   DQS_PD80_SOC-ODTDIS_VOH30_4266
Model_type   I/O
Vinl = 123.333mV
Vinh = 243.333mV
Vmeas = 183.333mV
Vref = 0.0mV
Cref = 0.0pF
|   typ   min   max
|C_comp   0.838pF   0.788pF   0.888pF
C_comp_pullup   0.4190pF   0.3940pF   0.4440pF
C_comp_pulldown   0.4190pF   0.3940pF   0.4440pF
| Note: C_comp changes when the ODT circuit is enabled.
[Model Spec]
| Input threshold voltage corners
Vinl   0.1233V   0.1167V   0.1350V
Vinh   0.2433V   0.2367V   0.2550V
| Measurement voltage corners
Vmeas   0.1833V   0.1767V   0.1950V
| Timing spec test load voltage corners
Vref   0.0000V   0.0000V   0.0000V
| Dynamic Overshoot Parameters from LPDDR4 Specification
D_overshoot_ampl_h   0.30   NA   NA
D_overshoot_ampl_l   0.30   NA   NA
D_overshoot_area_h   0.1n   NA   NA
D_overshoot_area_l   0.1n   NA   NA
[Receiver Thresholds]
Vcross_low   = 123.3mV
Vcross_high  = 243.3mV
Vdiff_ac   = 120mV
Vdiff_dc   = 120mV
Tdiffslew_ac = 10.000ns |Not specified, so set to high value
[Voltage Range]   1.1000V   1.0600V   1.1700V
[Pullup Reference]   1.1000V   1.0600V   1.1700V
| Junction Temperature (Ambient temp is 35C typ 95C min -40C max)
[Temperature Range]   50.0   110.0   -40.0
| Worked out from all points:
|   slope of the pulldown table from 0 to 0.165 V, typ, clamps not added: 73.8 ohm
|   slope of the pullup table from 0 to 0.165 V, typ, clamps not added: 13 kohm
|   GND clamp passes 1 mA (typ) near -0.45 V on its own axis
|   POWER clamp passes 1 mA (typ) near -0.88 V on its own axis
|   rising waveform, R_fixture 50, V_fixture 0.0: 20-80 % time 35.9ps typ, 39.9ps min, 31.1ps max; typ from 0.001 V to 0.403 V
|   falling waveform, R_fixture 50, V_fixture 1.1: 20-80 % time 60ps typ, 70.8ps min, 49.1ps max; typ from 1.1 V to 0.725 V
|   rising waveform, R_fixture 50, V_fixture 1.1: 20-80 % time 56.2ps typ, 57.8ps min, 54.5ps max; typ from 0.725 V to 1.1 V
|   falling waveform, R_fixture 50, V_fixture 0.0: 20-80 % time 39.4ps typ, 45.6ps min, 34.5ps max; typ from 0.403 V to 0.001 V
[Pulldown]
|   Voltage   I(typ)   I(min)   I(max)
-1.1V     -44.43mA   -39.43mA   -49.86mA
-915.2mV  -37.26mA   -33.59mA   -41.47mA
-717.2mV  -28.93mA   -26.17mA   -32.3mA
-605mV    -23.87mA   -21.13mA   -27.21mA
-489.5mV  -17.95mA   -15.17mA   -21.47mA
-311.3mV  -7.971mA   -6.634mA   -10.14mA
-202.4mV  -3.802mA   -3.463mA   -4.468mA
-103.4mV  -1.646mA   -1.602mA   -1.673mA
394.9mV   4.856mA    4.742mA    5.045mA
863.5mV   8.193mA    7.508mA    9.384mA
1.349V    9.758mA    8.824mA    11.56mA
2.2V      11.49mA    10.45mA    13.57mA
[GND Clamp]
|   Voltage   I(typ)   I(min)   I(max)
-1.1V     -34.88mA   -30.35mA   -43.13mA
-1.057V   -32.39mA   -27.81mA   -39.96mA
-938.3mV  -24.92mA   -21.15mA   -31.24mA
-789.8mV  -15.79mA   -12.83mA   -20.82mA
-667.7mV  -8.939mA   -6.743mA   -12.34mA
-595.1mV  -5.416mA   -3.908mA   -7.721mA
-522.5mV  -2.673mA   -1.905mA   -3.824mA
-466.4mV  -1.298mA   -943.6uA   -1.694mA
-413.6mV  -564.9uA   -417.5uA   -621.4uA
-354.2mV  -178.1uA   -134.6uA   -160.4uA
-248.6mV  -12.07uA   -10.97uA   -7.149uA
2.2V      0A         0A         0A
[Pullup]
|   Voltage   I(typ)   I(min)   I(max)
-1.1V     6.284uA    9.684uA    2.832uA
226.6mV   -42.1uA    -43.38uA   -42.76uA
338.8mV   -362.1uA   -299.2uA   -496.7uA
441.1mV   -1.492mA   -1.225mA   -1.867mA
553.3mV   -3.885mA   -3.58mA    -4.215mA
701.8mV   -8.13mA    -8.428mA   -8.01mA
1.108V    -21.59mA   -24.73mA   -20.21mA
1.398V    -31.73mA   -36.27mA   -29.78mA
1.576V    -37.67mA   -42.59mA   -35.81mA
1.708V    -41.21mA   -46.19mA   -39.78mA
1.867V    -45.46mA   -49.42mA   -44.76mA
2.2V      -55.46mA   -55.5mA    -57.28mA
[POWER Clamp]
|   Voltage   I(typ)   I(min)   I(max)
-1.1V     3.036mA    3.636mA    2.186mA
-1.044V   2.383mA    2.969mA    1.654mA
-977.9mV  1.724mA    2.242mA    1.161mA
-908.6mV  1.178mA    1.583mA    748.7uA
-852.5mV  818.6uA    1.149mA    543.7uA
-776.6mV  434.2uA    683.6uA    390.2uA
-713.9mV  239.3uA    373.1uA    278.6uA
-661.1mV  151.1uA    187.6uA    195.5uA
-598.4mV  83.65uA    71.97uA    113.1uA
-489.5mV  17.82uA    10.82uA    22.5uA
-377.3mV  1.486uA    1.061uA    1.229uA
2.2V      0A         0A         0A
[Ramp]
|   typ   min   max
| 20% - 80%
dV/dt_r   241.22m/35.89p   228.79m/39.87p   264.35m/31.15p
dV/dt_f   224.80m/60.01p   206.68m/70.76p   255.68m/49.18p
| 25% - 75%
|dV/dt_r   201.02m/28.61p   190.65m/31.75p   220.29m/24.77p
|dV/dt_f   187.34m/47.79p   172.24m/56.27p   213.07m/39.10p
R_load = 50
[Rising Waveform]
R_fixture = 50
V_fixture = 0.0
|   Time   V(typ)   V(min)   V(max)
0s        810.2uV    712.3uV    585.4uV
56ps      475.4uV    -111.4uV   11.33mV
64ps      3.486mV    -518.4uV   54.83mV
76ps      16.68mV    2.187mV    174.1mV
85ps      58.94mV    7.151mV    260.8mV
98ps      161.8mV    26.07mV    348.3mV
125ps     326.1mV    184.8mV    422.6mV
152ps     384.2mV    315.7mV    438.2mV
182ps     399.7mV    367.2mV    440.9mV
363ps     402.8mV    382mV      441.2mV
[Falling Waveform]
R_fixture   = 50
V_fixture   = 1.1
V_fixture_min = 1.06
V_fixture_max = 1.17
|   Time   V(typ)   V(min)   V(max)
0s        1.1V       1.06V      1.17V
71ps      1.099V     1.061V     1.156V
94ps      1.079V     1.053V     1.018V
119ps     968.4mV    1.035V     878.4mV
138ps     884.7mV    977mV      817.4mV
160ps     816.9mV    895.3mV    779.5mV
194ps     761.7mV    803.7mV    755.3mV
231ps     738mV      752.5mV    747.1mV
280ps     728.3mV    726mV      744.4mV
363ps     725.3mV    715.5mV    743.9mV
[Rising Waveform]
R_fixture   = 50
V_fixture   = 1.1
V_fixture_min = 1.06
V_fixture_max = 1.17
|   Time   V(typ)   V(min)   V(max)
0s        724.9mV    713.8mV    743.8mV
50ps      720.9mV    710.8mV    749.3mV
60ps      727.4mV    707.1mV    787.5mV
73ps      773.7mV    715.6mV    888.2mV
87ps      862.5mV    763.6mV    974.2mV
104ps     945mV      856.4mV    1.042V
121ps     997.3mV    926.1mV    1.087V
142ps     1.038V     978.5mV    1.121V
213ps     1.088V     1.044V     1.161V
363ps     1.099V     1.059V     1.17V
[Falling Waveform]
R_fixture = 50
V_fixture = 0.0
|   Time   V(typ)   V(min)   V(max)
0s        403mV      382.2mV    441.3mV
55ps      409.5mV    383.4mV    444.4mV
72ps      403.3mV    395mV      343mV
84ps      345.7mV    389mV      214mV
96ps      252.4mV    346.5mV    130.5mV
113ps     135.8mV    244.8mV    65.79mV
132ps     66.45mV    138.5mV    30.96mV
157ps     26.38mV    57.26mV    11.8mV
190ps     8.323mV    17.9mV     3.605mV
363ps     877.8uV    835.8uV    612.4uV
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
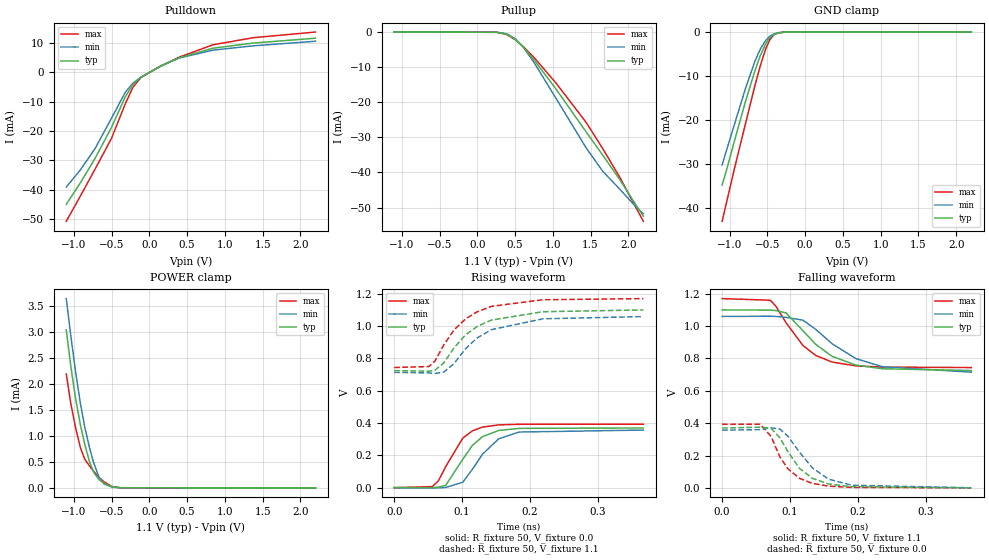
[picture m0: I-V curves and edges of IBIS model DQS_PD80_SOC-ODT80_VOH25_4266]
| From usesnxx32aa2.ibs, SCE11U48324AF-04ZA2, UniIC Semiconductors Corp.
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| DQS_PD80_SOC-ODT80_VOH25_4266
| (80 Ohm Pulldown, 80 Ohm System ODT Setting, VOH=VDDQ/2.5, 3200-4266Mbps)
[Model]   DQS_PD80_SOC-ODT80_VOH25_4266
Model_type   I/O
Vinl = 160.000mV
Vinh = 280.000mV
Vmeas = 220.000mV
Vref = 0.0mV
Cref = 0.0pF
Rref = 80.000Ohm
|   typ   min   max
|C_comp   0.838pF   0.788pF   0.888pF
C_comp_pullup   0.4190pF   0.3940pF   0.4440pF
C_comp_pulldown   0.4190pF   0.3940pF   0.4440pF
| Note: C_comp changes when the ODT circuit is enabled.
[Model Spec]
| Input threshold voltage corners
Vinl   0.1600V   0.1520V   0.1740V
Vinh   0.2800V   0.2720V   0.2940V
| Measurement voltage corners
Vmeas   0.2200V   0.2120V   0.2340V
| Timing spec test load voltage corners
Vref   0.0000V   0.0000V   0.0000V
| Dynamic Overshoot Parameters from LPDDR4 Specification
D_overshoot_ampl_h   0.30   NA   NA
D_overshoot_ampl_l   0.30   NA   NA
D_overshoot_area_h   0.1n   NA   NA
D_overshoot_area_l   0.1n   NA   NA
[Receiver Thresholds]
Vcross_low   = 160.0mV
Vcross_high  = 280.0mV
Vdiff_ac   = 120mV
Vdiff_dc   = 120mV
Tdiffslew_ac = 10.000ns |Not specified, so set to high value
[Voltage Range]   1.1000V   1.0600V   1.1700V
[Pullup Reference]   1.1000V   1.0600V   1.1700V
| Junction Temperature (Ambient temp is 35C typ 95C min -40C max)
[Temperature Range]   50.0   110.0   -40.0
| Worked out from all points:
|   slope of the pulldown table from 0 to 0.165 V, typ, clamps not added: 73.8 ohm
|   slope of the pullup table from 0 to 0.165 V, typ, clamps not added: 17.4 kohm
|   GND clamp passes 1 mA (typ) near -0.45 V on its own axis
|   POWER clamp passes 1 mA (typ) near -0.88 V on its own axis
|   rising waveform, R_fixture 50, V_fixture 0.0: 20-80 % time 35.9ps typ, 39.5ps min, 32.8ps max; typ from 0.001 V to 0.37 V
|   falling waveform, R_fixture 50, V_fixture 1.1: 20-80 % time 59.9ps typ, 70.7ps min, 48.8ps max; typ from 1.1 V to 0.725 V
|   rising waveform, R_fixture 50, V_fixture 1.1: 20-80 % time 57.7ps typ, 59.1ps min, 54.1ps max; typ from 0.725 V to 1.1 V
|   falling waveform, R_fixture 50, V_fixture 0.0: 20-80 % time 39.7ps typ, 45.7ps min, 34.3ps max; typ from 0.37 V to 0.001 V
[Pulldown]
|   Voltage   I(typ)   I(min)   I(max)
-1.1V     -44.88mA   -39.03mA   -50.64mA
-918.5mV  -37.79mA   -33.36mA   -42.33mA
-720.5mV  -29.38mA   -26.05mA   -33.04mA
-502.7mV  -18.88mA   -15.74mA   -22.6mA
-317.9mV  -8.372mA   -6.836mA   -10.74mA
-215.6mV  -4.22mA    -3.747mA   -5.086mA
-110mV    -1.769mA   -1.706mA   -1.818mA
150.7mV   2.026mA    2.012mA    2.028mA
391.6mV   4.822mA    4.711mA    5.007mA
843.7mV   8.104mA    7.438mA    9.251mA
1.378V    9.832mA    8.891mA    11.66mA
2.2V      11.49mA    10.45mA    13.57mA
[GND Clamp]
|   Voltage   I(typ)   I(min)   I(max)
-1.1V     -34.88mA   -30.33mA   -43.14mA
-1.05V    -32mA      -27.43mA   -39.48mA
-935mV    -24.72mA   -20.96mA   -31.01mA
-793.1mV  -15.99mA   -13.01mA   -21.07mA
-667.7mV  -8.943mA   -6.741mA   -12.35mA
-595.1mV  -5.417mA   -3.907mA   -7.727mA
-522.5mV  -2.672mA   -1.905mA   -3.827mA
-469.7mV  -1.359mA   -986.5uA   -1.792mA
-416.9mV  -598.5uA   -440.5uA   -665.6uA
-360.8mV  -205.1uA   -154.9uA   -188.3uA
-265.1mV  -19.43uA   -16.83uA   -12.58uA
2.2V      0A         0A         0A
[Pullup]
|   Voltage   I(typ)   I(min)   I(max)
-1.1V     4.112uA    7.441uA    1.363uA
259.6mV   -60.6uA    -59.72uA   -61.4uA
388.3mV   -575.8uA   -480uA     -688.1uA
500.5mV   -2.043mA   -1.831mA   -2.145mA
609.4mV   -4.304mA   -4.306mA   -4.133mA
751.3mV   -7.908mA   -8.648mA   -7.214mA
1.042V    -16.2mA    -18.85mA   -14.5mA
1.444V    -28.51mA   -33.07mA   -25.79mA
1.662V    -35.07mA   -39.67mA   -33.22mA
1.887V    -42.03mA   -44.75mA   -41.35mA
2.114V    -49.67mA   -50.08mA   -50.51mA
2.2V      -52.46mA   -51.75mA   -53.91mA
[POWER Clamp]
|   Voltage   I(typ)   I(min)   I(max)
-1.1V     3.036mA    3.636mA    2.186mA
-1.041V   2.347mA    2.931mA    1.626mA
-977.9mV  1.724mA    2.242mA    1.161mA
-911.9mV  1.201mA    1.612mA    765uA
-855.8mV  838.1uA    1.172mA    552.2uA
-793.1mV  506.1uA    776.1uA    421uA
-740.3mV  306.1uA    494.5uA    324.3uA
-667.7mV  159.9uA    206.1uA    205.2uA
-598.4mV  83.7uA     71.95uA    113.1uA
-489.5mV  17.77uA    10.84uA    22.48uA
-380.6mV  1.61uA     1.136uA    1.335uA
2.2V      0A         0A         0A
[Ramp]
|   typ   min   max
| 20% - 80%
dV/dt_r   221.42m/35.92p   213.80m/39.54p   235.53m/32.81p
dV/dt_f   224.81m/59.82p   206.68m/70.70p   255.68m/48.88p
| 25% - 75%
|dV/dt_r   184.52m/28.60p   178.17m/31.53p   196.27m/26.12p
|dV/dt_f   187.34m/47.52p   172.23m/56.29p   213.07m/38.85p
R_load = 50
[Rising Waveform]
R_fixture = 50
V_fixture = 0.0
|   Time   V(typ)   V(min)   V(max)
0s        839.9uV    689.3uV    615.3uV
56ps      493.7uV    -4.218uV   7.127mV
65ps      3.273mV    -430.5uV   42.08mV
76ps      15.49mV    1.724mV    131.9mV
101ps     176.3mV    34.14mV    306.8mV
115ps     261mV      113.3mV    351.6mV
130ps     316mV      207.7mV    375.3mV
154ps     354.4mV    302.8mV    389mV
184ps     367.2mV    344.7mV    392.6mV
367ps     369.9mV    357mV      393.2mV
[Falling Waveform]
R_fixture   = 50
V_fixture   = 1.1
V_fixture_min = 1.06
V_fixture_max = 1.17
|   Time   V(typ)   V(min)   V(max)
0s        1.1V       1.06V      1.17V
71ps      1.099V     1.061V     1.16V
79ps      1.096V     1.06V      1.124V
94ps      1.082V     1.054V     1.022V
119ps     971.7mV    1.037V     880.3mV
138ps     886.8mV    979.5mV    818.4mV
162ps     813.2mV    891mV      777.7mV
197ps     759.3mV    799.2mV    754.4mV
236ps     736.5mV    748.9mV    746.6mV
367ps     725.3mV    715.5mV    743.9mV
[Rising Waveform]
R_fixture   = 50
V_fixture   = 1.1
V_fixture_min = 1.06
V_fixture_max = 1.17
|   Time   V(typ)   V(min)   V(max)
0s        724.9mV    713.8mV    743.8mV
51ps      721mV      710.4mV    749.8mV
60ps      727.1mV    707.3mV    783.7mV
73ps      771.8mV    715.4mV    883.4mV
88ps      864.9mV    767.5mV    975.8mV
105ps     945.2mV    859.4mV    1.044V
122ps     997.1mV    926.6mV    1.088V
143ps     1.037V     977.8mV    1.122V
219ps     1.089V     1.045V     1.163V
367ps     1.1V       1.059V     1.17V
[Falling Waveform]
R_fixture = 50
V_fixture = 0.0
|   Time   V(typ)   V(min)   V(max)
0s        370mV      357.1mV    393.3mV
56ps      375.6mV    360.3mV    393.6mV
72ps      369.1mV    371.5mV    319.1mV
85ps      310.3mV    364.2mV    192.9mV
97ps      223.8mV    319.4mV    117.8mV
114ps     120.8mV    220.6mV    59.35mV
133ps     59.32mV    123.8mV    27.9mV
157ps     24.53mV    53.78mV    11.03mV
191ps     7.487mV    16.71mV    3.339mV
367ps     900.1uV    812.3uV    640.9uV
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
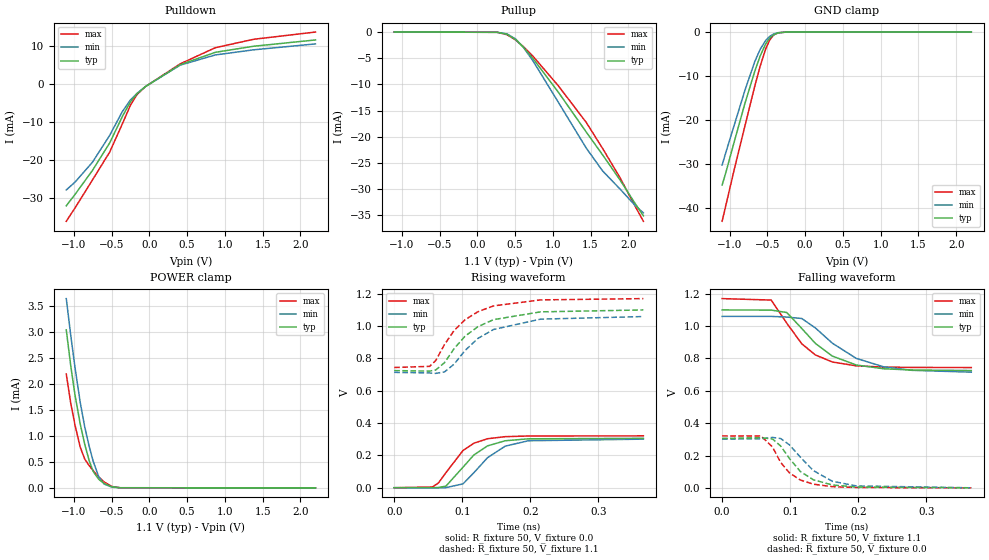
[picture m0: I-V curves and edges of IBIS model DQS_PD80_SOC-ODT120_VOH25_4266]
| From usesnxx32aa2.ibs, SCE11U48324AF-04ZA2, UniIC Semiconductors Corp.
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| DQS_PD80_SOC-ODT120_VOH25_4266
| (80 Ohm Pulldown, 120 Ohm System ODT Setting, VOH=VDDQ/2.5, 3200-4266Mbps)
[Model]   DQS_PD80_SOC-ODT120_VOH25_4266
Model_type   I/O
Vinl = 160.000mV
Vinh = 280.000mV
Vmeas = 220.000mV
Vref = 0.0mV
Cref = 0.0pF
Rref = 120.000Ohm
|   typ   min   max
|C_comp   0.838pF   0.788pF   0.888pF
C_comp_pullup   0.4190pF   0.3940pF   0.4440pF
C_comp_pulldown   0.4190pF   0.3940pF   0.4440pF
| Note: C_comp changes when the ODT circuit is enabled.
[Model Spec]
| Input threshold voltage corners
Vinl   0.1600V   0.1520V   0.1740V
Vinh   0.2800V   0.2720V   0.2940V
| Measurement voltage corners
Vmeas   0.2200V   0.2120V   0.2340V
| Timing spec test load voltage corners
Vref   0.0000V   0.0000V   0.0000V
| Dynamic Overshoot Parameters from LPDDR4 Specification
D_overshoot_ampl_h   0.30   NA   NA
D_overshoot_ampl_l   0.30   NA   NA
D_overshoot_area_h   0.1n   NA   NA
D_overshoot_area_l   0.1n   NA   NA
[Receiver Thresholds]
Vcross_low   = 160.0mV
Vcross_high  = 280.0mV
Vdiff_ac   = 120mV
Vdiff_dc   = 120mV
Tdiffslew_ac = 10.000ns |Not specified, so set to high value
[Voltage Range]   1.1000V   1.0600V   1.1700V
[Pullup Reference]   1.1000V   1.0600V   1.1700V
| Junction Temperature (Ambient temp is 35C typ 95C min -40C max)
[Temperature Range]   50.0   110.0   -40.0
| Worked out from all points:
|   slope of the pulldown table from 0 to 0.165 V, typ, clamps not added: 74.1 ohm
|   slope of the pullup table from 0 to 0.165 V, typ, clamps not added: 26.3 kohm
|   GND clamp passes 1 mA (typ) near -0.45 V on its own axis
|   POWER clamp passes 1 mA (typ) near -0.88 V on its own axis
|   rising waveform, R_fixture 50, V_fixture 0.0: 20-80 % time 41.1ps typ, 44.5ps min, 37.7ps max; typ from 0.001 V to 0.306 V
|   falling waveform, R_fixture 50, V_fixture 1.1: 20-80 % time 59.3ps typ, 69.9ps min, 48.6ps max; typ from 1.1 V to 0.725 V
|   rising waveform, R_fixture 50, V_fixture 1.1: 20-80 % time 58.2ps typ, 60.8ps min, 54.5ps max; typ from 0.725 V to 1.1 V
|   falling waveform, R_fixture 50, V_fixture 0.0: 20-80 % time 39.7ps typ, 46.1ps min, 34.5ps max; typ from 0.306 V to 0.001 V
[Pulldown]
|   Voltage   I(typ)   I(min)   I(max)
-1.1V     -32.12mA   -27.95mA   -36.19mA
-984.5mV  -29.13mA   -25.9mA    -32.69mA
-753.5mV  -22.82mA   -20.66mA   -25.33mA
-525.8mV  -15.61mA   -13.62mA   -18.02mA
-357.5mV  -8.657mA   -7.351mA   -10.57mA
-251.9mV  -4.83mA    -4.329mA   -5.74mA
-162.8mV  -2.65mA    -2.538mA   -2.836mA
-50.6mV   -762.4uA   -752uA     -748.7uA
408.1mV   4.988mA    4.865mA    5.197mA
873.4mV   8.237mA    7.542mA    9.449mA
1.382V    9.84mA     8.898mA    11.67mA
2.2V      11.49mA    10.45mA    13.57mA
[GND Clamp]
|   Voltage   I(typ)   I(min)   I(max)
-1.1V     -34.89mA   -30.33mA   -43.14mA
-1.05V    -32mA      -27.43mA   -39.48mA
-938.3mV  -24.93mA   -21.15mA   -31.25mA
-799.7mV  -16.38mA   -13.37mA   -21.53mA
-667.7mV  -8.943mA   -6.741mA   -12.35mA
-595.1mV  -5.418mA   -3.907mA   -7.725mA
-522.5mV  -2.675mA   -1.905mA   -3.826mA
-469.7mV  -1.362mA   -990.9uA   -1.792mA
-416.9mV  -600.1uA   -443.6uA   -665.9uA
-357.5mV  -191.2uA   -144.8uA   -174.2uA
-251.9mV  -13.33uA   -12.15uA   -7.885uA
2.2V      0A         0A         0A
[Pullup]
|   Voltage   I(typ)   I(min)   I(max)
-1.1V     2.741uA    4.961uA    908.6nA
262.9mV   -43.18uA   -41.87uA   -44.29uA
394.9mV   -422.2uA   -350.8uA   -502.1uA
510.4mV   -1.485mA   -1.346mA   -1.542mA
612.7mV   -2.934mA   -2.947mA   -2.81mA
738.1mV   -5.063mA   -5.512mA   -4.627mA
1.075V    -11.52mA   -13.45mA   -10.3mA
1.444V    -19.13mA   -22.2mA    -17.29mA
1.659V    -23.46mA   -26.53mA   -22.23mA
1.887V    -28.2mA    -29.96mA   -27.75mA
2.094V    -32.85mA   -33.2mA    -33.38mA
2.2V      -35.14mA   -34.58mA   -36.18mA
[POWER Clamp]
|   Voltage   I(typ)   I(min)   I(max)
-1.1V     3.036mA    3.636mA    2.186mA
-1.041V   2.347mA    2.931mA    1.626mA
-984.5mV  1.784mA    2.311mA    1.206mA
-915.2mV  1.224mA    1.64mA     781.3uA
-855.8mV  838.1uA    1.172mA    552.4uA
-796.4mV  521.3uA    795.3uA    427.2uA
-743.6mV  316uA      510.8uA    330.1uA
-671mV    164.5uA    215.9uA    210.2uA
-598.4mV  83.65uA    71.99uA    113uA
-496.1mV  20.14uA    12.33uA    25.74uA
-387.2mV  1.891uA    1.31uA     1.604uA
2.2V      0A         0A         0A
[Ramp]
|   typ   min   max
| 20% - 80%
dV/dt_r   183.16m/41.11p   180.26m/44.52p   192.44m/37.69p
dV/dt_f   224.78m/59.31p   206.67m/69.91p   255.68m/48.65p
| 25% - 75%
|dV/dt_r   152.63m/32.74p   150.22m/35.47p   160.37m/29.96p
|dV/dt_f   187.32m/47.20p   172.23m/55.66p   213.07m/38.68p
R_load = 50
[Rising Waveform]
R_fixture = 50
V_fixture = 0.0
|   Time   V(typ)   V(min)   V(max)
0s        555uV      449.5uV    407.3uV
56ps      266.9uV    39.41uV    4.751mV
65ps      1.742mV    -310.6uV   29.85mV
76ps      10.14mV    948.8uV    93.71mV
101ps     127.2mV    24.25mV    230.3mV
117ps     202.8mV    92.95mV    275.7mV
137ps     259.1mV    185.8mV    303.2mV
163ps     290.8mV    257.4mV    316.1mV
197ps     302.9mV    290.9mV    320.3mV
366ps     305.8mV    300.9mV    321.1mV
[Falling Waveform]
R_fixture   = 50
V_fixture   = 1.1
V_fixture_min = 1.06
V_fixture_max = 1.17
|   Time   V(typ)   V(min)   V(max)
0s        1.1V       1.06V      1.17V
72ps      1.099V     1.06V      1.161V
95ps      1.084V     1.056V     1.018V
117ps     985.4mV    1.047V     890.6mV
137ps     893.1mV    988.7mV    821.7mV
162ps     814.5mV    894.2mV    778.1mV
197ps     759.7mV    800.6mV    754.5mV
237ps     736.4mV    748.6mV    746.7mV
279ps     728.6mV    726.6mV    744.6mV
366ps     725.4mV    715.5mV    743.9mV
[Rising Waveform]
R_fixture   = 50
V_fixture   = 1.1
V_fixture_min = 1.06
V_fixture_max = 1.17
|   Time   V(typ)   V(min)   V(max)
0s        724.9mV    713.8mV    743.8mV
52ps      721.4mV    710.2mV    750.9mV
61ps      728.4mV    707.5mV    786.9mV
74ps      774.4mV    717mV      886.9mV
88ps      860.4mV    764.6mV    972.5mV
104ps     937.3mV    848.8mV    1.039V
123ps     996.6mV    923.9mV    1.089V
146ps     1.04V      979.1mV    1.125V
215ps     1.088V     1.043V     1.162V
366ps     1.1V       1.059V     1.17V
[Falling Waveform]
R_fixture = 50
V_fixture = 0.0
|   Time   V(typ)   V(min)   V(max)
0s        305.9mV    301mV      321.2mV
57ps      310.3mV    303.9mV    321.1mV
74ps      302.3mV    312.1mV    253mV
86ps      259.2mV    305.1mV    157.4mV
99ps      181.3mV    265.6mV    92.52mV
115ps     101.4mV    189.9mV    48.74mV
134ps     50.13mV    106.9mV    23mV
162ps     18mV       40.84mV    7.812mV
197ps     5.383mV    12.37mV    2.291mV
366ps     641.3uV    597.2uV    440.2uV
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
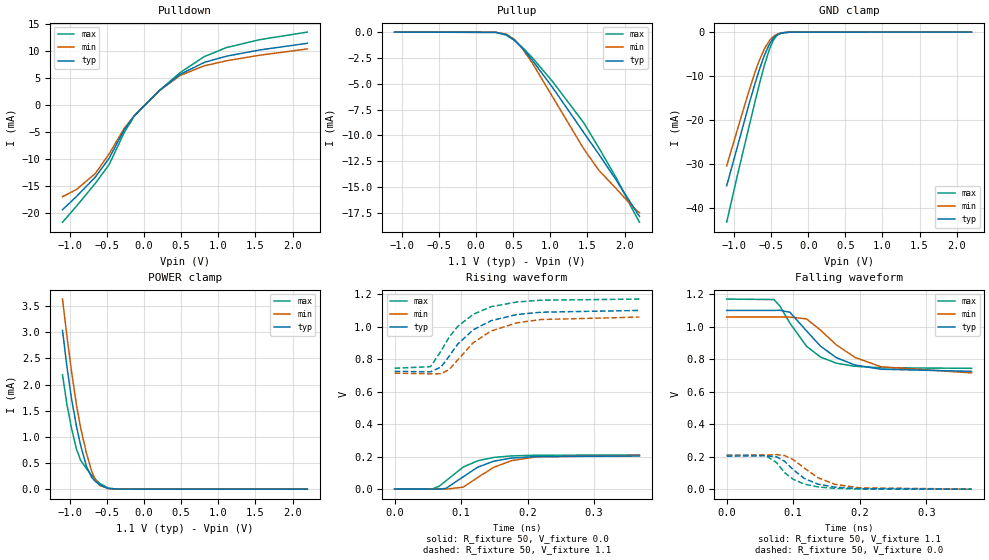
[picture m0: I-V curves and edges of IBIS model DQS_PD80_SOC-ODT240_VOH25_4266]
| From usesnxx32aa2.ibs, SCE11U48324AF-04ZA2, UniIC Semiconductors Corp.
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| DQS_PD80_SOC-ODT240_VOH25_4266
| (80 Ohm Pulldown, 240 Ohm System ODT Setting, VOH=VDDQ/2.5, 3200-4266Mbps)
[Model]   DQS_PD80_SOC-ODT240_VOH25_4266
Model_type   I/O
Vinl = 160.000mV
Vinh = 280.000mV
Vmeas = 220.000mV
Vref = 0.0mV
Cref = 0.0pF
Rref = 240.000Ohm
|   typ   min   max
|C_comp   0.838pF   0.788pF   0.888pF
C_comp_pullup   0.4190pF   0.3940pF   0.4440pF
C_comp_pulldown   0.4190pF   0.3940pF   0.4440pF
| Note: C_comp changes when the ODT circuit is enabled.
[Model Spec]
| Input threshold voltage corners
Vinl   0.1600V   0.1520V   0.1740V
Vinh   0.2800V   0.2720V   0.2940V
| Measurement voltage corners
Vmeas   0.2200V   0.2120V   0.2340V
| Timing spec test load voltage corners
Vref   0.0000V   0.0000V   0.0000V
| Dynamic Overshoot Parameters from LPDDR4 Specification
D_overshoot_ampl_h   0.30   NA   NA
D_overshoot_ampl_l   0.30   NA   NA
D_overshoot_area_h   0.1n   NA   NA
D_overshoot_area_l   0.1n   NA   NA
[Receiver Thresholds]
Vcross_low   = 160.0mV
Vcross_high  = 280.0mV
Vdiff_ac   = 120mV
Vdiff_dc   = 120mV
Tdiffslew_ac = 10.000ns |Not specified, so set to high value
[Voltage Range]   1.1000V   1.0600V   1.1700V
[Pullup Reference]   1.1000V   1.0600V   1.1700V
| Junction Temperature (Ambient temp is 35C typ 95C min -40C max)
[Temperature Range]   50.0   110.0   -40.0
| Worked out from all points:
|   slope of the pulldown table from 0 to 0.165 V, typ, clamps not added: 74.4 ohm
|   slope of the pullup table from 0 to 0.165 V, typ, clamps not added: 53 kohm
|   GND clamp passes 1 mA (typ) near -0.45 V on its own axis
|   POWER clamp passes 1 mA (typ) near -0.88 V on its own axis
|   rising waveform, R_fixture 50, V_fixture 0.0: 20-80 % time 48.7ps typ, 52.7ps min, 45.1ps max; typ from 0 V to 0.203 V
|   falling waveform, R_fixture 50, V_fixture 1.1: 20-80 % time 58.9ps typ, 69.1ps min, 48.5ps max; typ from 1.1 V to 0.725 V
|   rising waveform, R_fixture 50, V_fixture 1.1: 20-80 % time 58.9ps typ, 62.2ps min, 54.6ps max; typ from 0.725 V to 1.1 V
|   falling waveform, R_fixture 50, V_fixture 0.0: 20-80 % time 40.3ps typ, 47.1ps min, 35.1ps max; typ from 0.203 V to 0 V
[Pulldown]
|   Voltage   I(typ)   I(min)   I(max)
-1.1V     -19.4mA    -16.97mA   -21.71mA
-915.2mV  -16.99mA   -15.68mA   -18.79mA
-657.8mV  -13.34mA   -12.68mA   -14.5mA
-473mV    -9.87mA    -9.049mA   -11.04mA
-268.4mV  -4.569mA   -4.295mA   -5.081mA
-129.8mV  -1.932mA   -1.916mA   -1.945mA
210.1mV   2.774mA    2.746mA    2.796mA
487.3mV   5.736mA    5.541mA    6.073mA
810.7mV   7.947mA    7.317mA    9.018mA
1.111V    9.1mA      8.248mA    10.7mA
1.556V    10.25mA    9.273mA    12.16mA
2.2V      11.49mA    10.45mA    13.57mA
[GND Clamp]
|   Voltage   I(typ)   I(min)   I(max)
-1.1V     -34.89mA   -30.35mA   -43.14mA
-951.5mV  -25.76mA   -21.89mA   -32.2mA
-799.7mV  -16.38mA   -13.37mA   -21.53mA
-723.8mV  -11.99mA   -9.379mA   -16.19mA
-664.4mV  -8.772mA   -6.596mA   -12.13mA
-591.8mV  -5.274mA   -3.797mA   -7.53mA
-522.5mV  -2.671mA   -1.905mA   -3.826mA
-469.7mV  -1.36mA    -986.9uA   -1.791mA
-416.9mV  -597.8uA   -440.2uA   -665.5uA
-357.5mV  -191.7uA   -144.2uA   -173.3uA
-242mV    -10.02uA   -9.177uA   -5.633uA
2.2V      0A         0A         0A
[Pullup]
|   Voltage   I(typ)   I(min)   I(max)
-1.1V     1.371uA    2.481uA    454.4nA
266.2mV   -23.09uA   -22.26uA   -23.96uA
408.1mV   -253.3uA   -210.9uA   -297.2uA
513.7mV   -768.2uA   -699.3uA   -794.8uA
619.3mV   -1.533mA   -1.551mA   -1.46mA
761.2mV   -2.768mA   -3.054mA   -2.513mA
1.032V    -5.393mA   -6.298mA   -4.813mA
1.448V    -9.715mA   -11.29mA   -8.771mA
1.655V    -11.85mA   -13.4mA    -11.24mA
1.887V    -14.33mA   -15.16mA   -14.11mA
2.114V    -16.89mA   -16.95mA   -17.27mA
2.2V      -17.84mA   -17.49mA   -18.41mA
[POWER Clamp]
|   Voltage   I(typ)   I(min)   I(max)
-1.1V     3.036mA    3.636mA    2.186mA
-1.041V   2.347mA    2.931mA    1.626mA
-977.9mV  1.724mA    2.243mA    1.161mA
-911.9mV  1.201mA    1.612mA    765uA
-855.8mV  838uA      1.172mA    552.2uA
-776.6mV  434.2uA    683.6uA    390.2uA
-707.3mV  225.5uA    345.5uA    267.6uA
-651.2mV  138.6uA    162.4uA    181.2uA
-595.1mV  80.77uA    68.32uA    109.2uA
-482.9mV  15.68uA    9.499uA    19.5uA
-360.8mV  1.018uA    769nA      795.6nA
2.2V      0A         0A         0A
[Ramp]
|   typ   min   max
| 20% - 80%
dV/dt_r   121.78m/48.71p   124.11m/52.68p   125.56m/45.07p
dV/dt_f   224.80m/58.91p   206.68m/69.13p   255.68m/48.45p
| 25% - 75%
|dV/dt_r   101.48m/38.76p   103.43m/42.07p   104.64m/35.81p
|dV/dt_f   187.33m/46.91p   172.24m/55.18p   213.06m/38.50p
R_load = 50
[Rising Waveform]
R_fixture = 50
V_fixture = 0.0
|   Time   V(typ)   V(min)   V(max)
0s        267.1uV    206.4uV    197.8uV
57ps      -320.1uV   143.7uV    1.125mV
67ps      -673.4uV   -516.3uV   17.04mV
77ps      3.432mV    -893.8uV   49.79mV
103ps     74.79mV    11.52mV    135mV
125ps     134.6mV    71.01mV    174.2mV
149ps     171.4mV    133.9mV    194.6mV
176ps     190.7mV    175.1mV    204mV
213ps     199.9mV    198.1mV    208.1mV
368ps     203.2mV    207.1mV    209.5mV
[Falling Waveform]
R_fixture   = 50
V_fixture   = 1.1
V_fixture_min = 1.06
V_fixture_max = 1.17
|   Time   V(typ)   V(min)   V(max)
0s        1.1V       1.06V      1.17V
71ps      1.1V       1.06V      1.167V
80ps      1.101V     1.06V      1.127V
95ps      1.089V     1.059V     1.022V
120ps     974.3mV    1.048V     879.6mV
141ps     880mV      978.8mV    813.2mV
165ps     808.9mV    887.5mV    775.2mV
193ps     764.2mV    810.5mV    756.3mV
232ps     738.2mV    753.4mV    747.1mV
368ps     725.3mV    715.5mV    743.9mV
[Rising Waveform]
R_fixture   = 50
V_fixture   = 1.1
V_fixture_min = 1.06
V_fixture_max = 1.17
|   Time   V(typ)   V(min)   V(max)
0s        724.9mV    713.8mV    743.8mV
54ps      721.8mV    709.7mV    753.5mV
70ps      751.9mV    710.8mV    851.2mV
82ps      818.5mV    736.2mV    935.8mV
95ps      893mV      795.5mV    1.002V
118ps     980.1mV    901mV      1.076V
145ps     1.037V     973mV      1.123V
184ps     1.075V     1.024V     1.152V
220ps     1.089V     1.044V     1.163V
368ps     1.1V       1.059V     1.17V
[Falling Waveform]
R_fixture = 50
V_fixture = 0.0
|   Time   V(typ)   V(min)   V(max)
0s        203.3mV    207.2mV    209.5mV
58ps      205.6mV    208.9mV    208.7mV
75ps      199.5mV    213mV      163.5mV
87ps      171.9mV    207.3mV    102.1mV
100ps     120mV      181.8mV    60.72mV
117ps     65.55mV    129.4mV    31.01mV
137ps     31.52mV    70.78mV    14.16mV
163ps     12.3mV     29.37mV    5.238mV
200ps     3.414mV    8.415mV    1.39mV
368ps     353.7uV    349.7uV    231uV
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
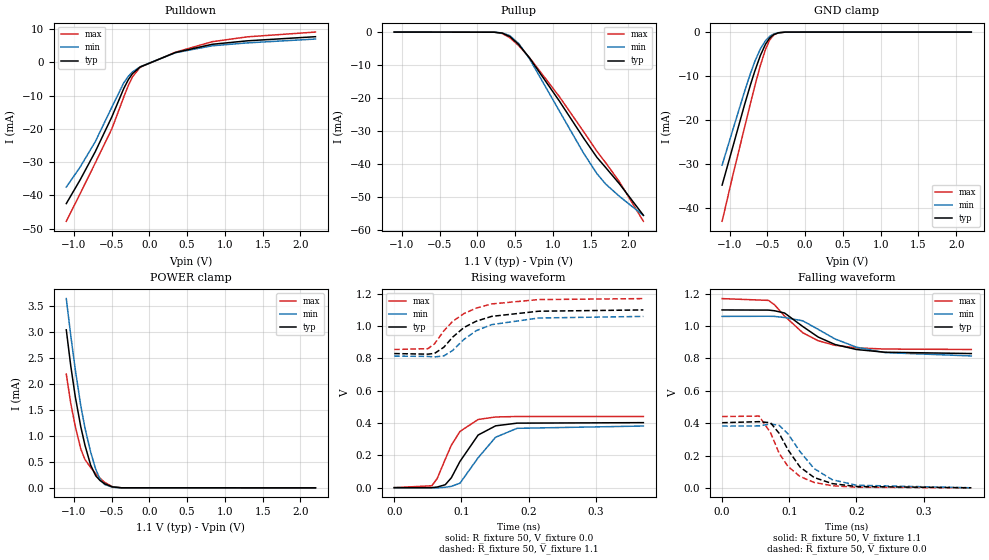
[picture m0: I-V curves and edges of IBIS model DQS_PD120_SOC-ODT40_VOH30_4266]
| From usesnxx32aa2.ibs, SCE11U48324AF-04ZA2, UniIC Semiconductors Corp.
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| DQS_PD120_SOC-ODT40_VOH30_4266
| (120 Ohm Pulldown, 40 Ohm System ODT Setting, VOH=VDDQ/3.0, 3200-4266Mbps)
[Model]   DQS_PD120_SOC-ODT40_VOH30_4266
Model_type   I/O
Vinl = 123.333mV
Vinh = 243.333mV
Vmeas = 183.333mV
Vref = 0.0mV
Cref = 0.0pF
Rref = 40.000Ohm
|   typ   min   max
|C_comp   0.838pF   0.788pF   0.888pF
C_comp_pullup   0.4190pF   0.3940pF   0.4440pF
C_comp_pulldown   0.4190pF   0.3940pF   0.4440pF
| Note: C_comp changes when the ODT circuit is enabled.
[Model Spec]
| Input threshold voltage corners
Vinl   0.1233V   0.1167V   0.1350V
Vinh   0.2433V   0.2367V   0.2550V
| Measurement voltage corners
Vmeas   0.1833V   0.1767V   0.1950V
| Timing spec test load voltage corners
Vref   0.0000V   0.0000V   0.0000V
| Dynamic Overshoot Parameters from LPDDR4 Specification
D_overshoot_ampl_h   0.30   NA   NA
D_overshoot_ampl_l   0.30   NA   NA
D_overshoot_area_h   0.1n   NA   NA
D_overshoot_area_l   0.1n   NA   NA
[Receiver Thresholds]
Vcross_low   = 123.3mV
Vcross_high  = 243.3mV
Vdiff_ac   = 120mV
Vdiff_dc   = 120mV
Tdiffslew_ac = 10.000ns |Not specified, so set to high value
[Voltage Range]   1.1000V   1.0600V   1.1700V
[Pullup Reference]   1.1000V   1.0600V   1.1700V
| Junction Temperature (Ambient temp is 35C typ 95C min -40C max)
[Temperature Range]   50.0   110.0   -40.0
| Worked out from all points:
|   slope of the pulldown table from 0 to 0.165 V, typ, clamps not added: 109 ohm
|   slope of the pullup table from 0 to 0.165 V, typ, clamps not added: 13 kohm
|   GND clamp passes 1 mA (typ) near -0.45 V on its own axis
|   POWER clamp passes 1 mA (typ) near -0.88 V on its own axis
|   rising waveform, R_fixture 50, V_fixture 0.0: 20-80 % time 36.1ps typ, 40.2ps min, 31.3ps max; typ from 0.001 V to 0.403 V
|   falling waveform, R_fixture 50, V_fixture 1.1: 20-80 % time 64ps typ, 74.1ps min, 54.3ps max; typ from 1.1 V to 0.83 V
|   rising waveform, R_fixture 50, V_fixture 1.1: 20-80 % time 55.8ps typ, 55.1ps min, 54.3ps max; typ from 0.83 V to 1.1 V
|   falling waveform, R_fixture 50, V_fixture 0.0: 20-80 % time 42.8ps typ, 47.9ps min, 38.5ps max; typ from 0.403 V to 0.001 V
[Pulldown]
|   Voltage   I(typ)   I(min)   I(max)
-1.1V     -42.44mA   -37.48mA   -47.75mA
-918.5mV  -35.39mA   -31.54mA   -39.55mA
-717.2mV  -26.89mA   -23.9mA    -30.29mA
-496.1mV  -16.38mA   -13.46mA   -19.96mA
-337.7mV  -7.822mA   -6.138mA   -10.38mA
-275mV    -5.103mA   -4.125mA   -6.813mA
-222.2mV  -3.395mA   -2.899mA   -4.341mA
-119.9mV  -1.395mA   -1.326mA   -1.477mA
345.4mV   2.928mA    2.867mA    3.023mA
833.8mV   5.403mA    4.954mA    6.183mA
1.299V    6.441mA    5.821mA    7.639mA
2.2V      7.677mA    6.979mA    9.076mA
[GND Clamp]
|   Voltage   I(typ)   I(min)   I(max)
-1.1V     -34.88mA   -30.34mA   -43.13mA
-944.9mV  -25.34mA   -21.53mA   -31.71mA
-803mV    -16.57mA   -13.55mA   -21.76mA
-723.8mV  -11.98mA   -9.382mA   -16.18mA
-667.7mV  -8.939mA   -6.742mA   -12.34mA
-595.1mV  -5.416mA   -3.908mA   -7.72mA
-525.8mV  -2.776mA   -1.978mA   -3.977mA
-469.7mV  -1.358mA   -987.6uA   -1.794mA
-416.9mV  -599.4uA   -441.4uA   -665.6uA
-357.5mV  -192.1uA   -144.7uA   -174uA
-261.8mV  -17.76uA   -15.5uA    -11.08uA
2.2V      0A         0A         0A
[Pullup]
|   Voltage   I(typ)   I(min)   I(max)
-1.1V     6.284uA    9.684uA    2.832uA
226.6mV   -42.23uA   -43.5uA    -42.78uA
328.9mV   -304.2uA   -255.9uA   -417uA
431.2mV   -1.334mA   -1.088mA   -1.696mA
550mV     -3.801mA   -3.492mA   -4.138mA
691.9mV   -7.825mA   -8.065mA   -7.741mA
1.088V    -20.91mA   -23.92mA   -19.57mA
1.411V    -32.18mA   -36.77mA   -30.22mA
1.586V    -37.97mA   -42.9mA    -36.14mA
1.702V    -41.04mA   -46.04mA   -39.59mA
1.883V    -45.95mA   -49.74mA   -45.33mA
2.2V      -55.46mA   -55.5mA    -57.28mA
[POWER Clamp]
|   Voltage   I(typ)   I(min)   I(max)
-1.1V     3.036mA    3.636mA    2.186mA
-1.041V   2.347mA    2.931mA    1.626mA
-981.2mV  1.754mA    2.277mA    1.183mA
-908.6mV  1.178mA    1.583mA    748.9uA
-852.5mV  818.5uA    1.149mA    543.6uA
-776.6mV  434.4uA    683.6uA    390.2uA
-710.6mV  232.2uA    359.1uA    273.1uA
-651.2mV  138.6uA    162.4uA    181.2uA
-591.8mV  77.93uA    64.83uA    105.5uA
-489.5mV  17.84uA    10.84uA    22.51uA
-370.7mV  1.283uA    931.4nA    1.034uA
2.2V      0A         0A         0A
[Ramp]
|   typ   min   max
| 20% - 80%
dV/dt_r   241.14m/36.10p   228.71m/40.22p   264.30m/31.33p
dV/dt_f   161.74m/64.04p   146.60m/74.06p   188.64m/54.26p
| 25% - 75%
|dV/dt_r   200.95m/28.76p   190.59m/32.05p   220.25m/24.90p
|dV/dt_f   134.79m/50.94p   122.16m/58.85p   157.20m/43.09p
R_load = 50
[Rising Waveform]
R_fixture = 50
V_fixture = 0.0
|   Time   V(typ)   V(min)   V(max)
0s        944.7uV    837.4uV    681uV
56ps      1.008mV    -47.56uV   12.76mV
64ps      4.693mV    -186.2uV   57.19mV
76ps      19.08mV    3.293mV    176.5mV
85ps      61.57mV    9.063mV    262.4mV
98ps      163.6mV    28.82mV    348.9mV
125ps     326.4mV    186mV      422.6mV
151ps     383.2mV    312.7mV    438mV
183ps     399.9mV    367.9mV    440.9mV
371ps     402.9mV    382mV      441.2mV
[Falling Waveform]
R_fixture   = 50
V_fixture   = 1.1
V_fixture_min = 1.06
V_fixture_max = 1.17
|   Time   V(typ)   V(min)   V(max)
0s        1.1V       1.06V      1.17V
69ps      1.099V     1.061V     1.159V
78ps      1.095V     1.06V      1.132V
93ps      1.081V     1.053V     1.062V
120ps     997.9mV    1.033V     959.3mV
143ps     932.5mV    980mV      909.7mV
168ps     886.5mV    920.9mV    881.6mV
200ps     855.4mV    869.8mV    865.6mV
242ps     838.7mV    836.5mV    858.4mV
371ps     830.4mV    815.7mV    855.6mV
[Rising Waveform]
R_fixture   = 50
V_fixture   = 1.1
V_fixture_min = 1.06
V_fixture_max = 1.17
|   Time   V(typ)   V(min)   V(max)
0s        830.1mV    814.5mV    855.5mV
50ps      826.5mV    812.5mV    860.1mV
60ps      831mV      809.3mV    890.3mV
74ps      869.6mV    815.8mV    971.1mV
87ps      931.6mV    849mV      1.029V
104ps     991.6mV    918.2mV    1.078V
122ps     1.03V      971.3mV    1.111V
145ps     1.06V      1.009V     1.137V
215ps     1.092V     1.05V      1.164V
371ps     1.1V       1.06V      1.17V
[Falling Waveform]
R_fixture = 50
V_fixture = 0.0
|   Time   V(typ)   V(min)   V(max)
0s        403mV      382.2mV    441.3mV
55ps      409.6mV    383.5mV    444.1mV
72ps      402.8mV    395.1mV    342.1mV
85ps      337.4mV    386.8mV    213.6mV
98ps      236.4mV    334.7mV    133.3mV
116ps     129.2mV    224.7mV    70.56mV
137ps     64.43mV    119.7mV    34.02mV
164ps     26.86mV    50.74mV    13.67mV
200ps     8.902mV    16.75mV    4.302mV
371ps     1.023mV    998.5uV    708.5uV
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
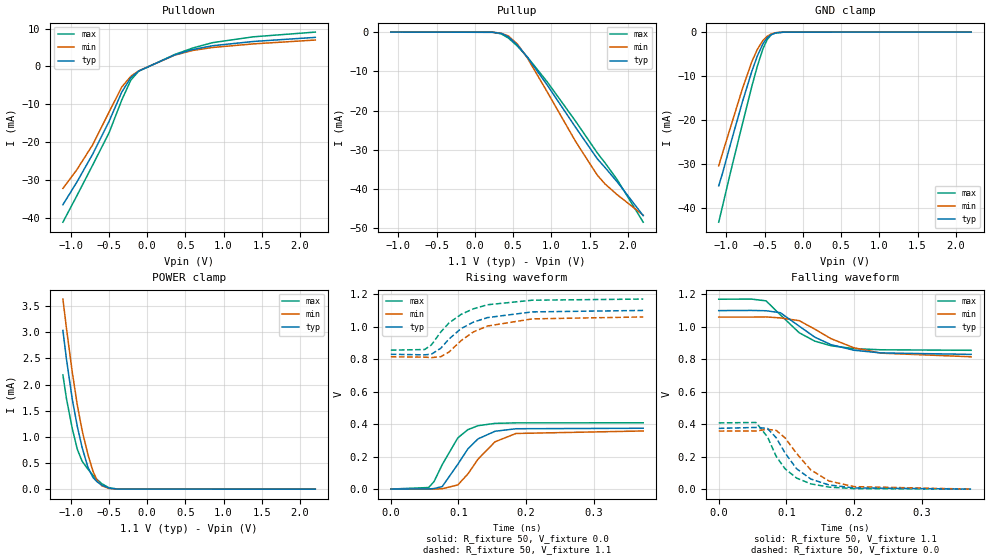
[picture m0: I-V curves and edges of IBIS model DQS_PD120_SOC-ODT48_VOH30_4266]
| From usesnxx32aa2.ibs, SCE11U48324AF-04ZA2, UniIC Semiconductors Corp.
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| DQS_PD120_SOC-ODT48_VOH30_4266
| (120 Ohm Pulldown, 48 Ohm System ODT Setting, VOH=VDDQ/3.0, 3200-4266Mbps)
[Model]   DQS_PD120_SOC-ODT48_VOH30_4266
Model_type   I/O
Vinl = 123.333mV
Vinh = 243.333mV
Vmeas = 183.333mV
Vref = 0.0mV
Cref = 0.0pF
Rref = 48.000Ohm
|   typ   min   max
|C_comp   0.838pF   0.788pF   0.888pF
C_comp_pullup   0.4190pF   0.3940pF   0.4440pF
C_comp_pulldown   0.4190pF   0.3940pF   0.4440pF
| Note: C_comp changes when the ODT circuit is enabled.
[Model Spec]
| Input threshold voltage corners
Vinl   0.1233V   0.1167V   0.1350V
Vinh   0.2433V   0.2367V   0.2550V
| Measurement voltage corners
Vmeas   0.1833V   0.1767V   0.1950V
| Timing spec test load voltage corners
Vref   0.0000V   0.0000V   0.0000V
| Dynamic Overshoot Parameters from LPDDR4 Specification
D_overshoot_ampl_h   0.30   NA   NA
D_overshoot_ampl_l   0.30   NA   NA
D_overshoot_area_h   0.1n   NA   NA
D_overshoot_area_l   0.1n   NA   NA
[Receiver Thresholds]
Vcross_low   = 123.3mV
Vcross_high  = 243.3mV
Vdiff_ac   = 120mV
Vdiff_dc   = 120mV
Tdiffslew_ac = 10.000ns |Not specified, so set to high value
[Voltage Range]   1.1000V   1.0600V   1.1700V
[Pullup Reference]   1.1000V   1.0600V   1.1700V
| Junction Temperature (Ambient temp is 35C typ 95C min -40C max)
[Temperature Range]   50.0   110.0   -40.0
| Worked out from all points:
|   slope of the pulldown table from 0 to 0.165 V, typ, clamps not added: 109 ohm
|   slope of the pullup table from 0 to 0.165 V, typ, clamps not added: 15.7 kohm
|   GND clamp passes 1 mA (typ) near -0.45 V on its own axis
|   POWER clamp passes 1 mA (typ) near -0.88 V on its own axis
|   rising waveform, R_fixture 50, V_fixture 0.0: 20-80 % time 37.6ps typ, 42.2ps min, 33.1ps max; typ from 0.001 V to 0.375 V
|   falling waveform, R_fixture 50, V_fixture 1.1: 20-80 % time 63.5ps typ, 73.6ps min, 54.1ps max; typ from 1.1 V to 0.83 V
|   rising waveform, R_fixture 50, V_fixture 1.1: 20-80 % time 56.4ps typ, 57.1ps min, 54.3ps max; typ from 0.83 V to 1.1 V
|   falling waveform, R_fixture 50, V_fixture 0.0: 20-80 % time 43ps typ, 48.2ps min, 38.6ps max; typ from 0.375 V to 0.001 V
[Pulldown]
|   Voltage   I(typ)   I(min)   I(max)
-1.1V     -36.53mA   -32.22mA   -41.15mA
-918.5mV  -30.59mA   -27.31mA   -34.21mA
-710.6mV  -23.18mA   -20.7mA    -26.06mA
-496.1mV  -14.5mA    -12.05mA   -17.51mA
-331.1mV  -6.813mA   -5.465mA   -8.908mA
-212.3mV  -2.95mA    -2.603mA   -3.634mA
-110mV    -1.227mA   -1.181mA   -1.268mA
361.9mV   3.046mA    2.979mA    3.155mA
596.2mV   4.46mA     4.223mA    4.855mA
856.9mV   5.472mA    5.009mA    6.287mA
1.391V    6.596mA    5.961mA    7.831mA
2.2V      7.677mA    6.979mA    9.076mA
[GND Clamp]
|   Voltage   I(typ)   I(min)   I(max)
-1.1V     -34.88mA   -30.33mA   -43.13mA
-1.05V    -31.99mA   -27.44mA   -39.47mA
-941.6mV  -25.13mA   -21.34mA   -31.48mA
-789.8mV  -15.79mA   -12.83mA   -20.82mA
-667.7mV  -8.939mA   -6.743mA   -12.34mA
-595.1mV  -5.416mA   -3.908mA   -7.719mA
-522.5mV  -2.671mA   -1.905mA   -3.822mA
-466.4mV  -1.297mA   -943.1uA   -1.694mA
-413.6mV  -565.4uA   -416.9uA   -621.8uA
-354.2mV  -178.2uA   -134.6uA   -160.2uA
-242mV    -10.03uA   -9.194uA   -5.69uA
2.2V      0A         0A         0A
[Pullup]
|   Voltage   I(typ)   I(min)   I(max)
-1.1V     5.237uA    8.07uA     2.361uA
233.2mV   -40.28uA   -41.14uA   -42.31uA
342.1mV   -318.3uA   -262.7uA   -438.8uA
437.8mV   -1.205mA   -986uA     -1.515mA
556.6mV   -3.33mA    -3.082mA   -3.598mA
685.3mV   -6.404mA   -6.586mA   -6.345mA
949.3mV   -13.61mA   -15.38mA   -12.79mA
1.319V    -24.35mA   -27.96mA   -22.79mA
1.599V    -32.26mA   -36.44mA   -30.76mA
1.702V    -34.53mA   -38.71mA   -33.34mA
1.86V     -38.15mA   -41.43mA   -37.6mA
2.2V      -46.77mA   -46.64mA   -48.43mA
[POWER Clamp]
|   Voltage   I(typ)   I(min)   I(max)
-1.1V     3.036mA    3.636mA    2.186mA
-1.054V   2.493mA    3.084mA    1.737mA
-977.9mV  1.724mA    2.242mA    1.161mA
-911.9mV  1.201mA    1.612mA    764.8uA
-849.2mV  799.3uA    1.126mA    535.5uA
-773.3mV  420.8uA    665.5uA    384.1uA
-707.3mV  225.5uA    345.5uA    267.6uA
-654.5mV  142.7uA    170.4uA    185.9uA
-591.8mV  77.94uA    64.83uA    105.5uA
-496.1mV  20.09uA    12.31uA    25.71uA
-380.6mV  1.606uA    1.129uA    1.34uA
2.2V      0A         0A         0A
[Ramp]
|   typ   min   max
| 20% - 80%
dV/dt_r   224.44m/37.63p   214.42m/42.17p   244.77m/33.14p
dV/dt_f   161.74m/63.63p   146.60m/73.43p   188.63m/54.09p
| 25% - 75%
|dV/dt_r   187.03m/29.99p   178.69m/33.60p   203.98m/26.35p
|dV/dt_f   134.78m/50.56p   122.17m/58.36p   157.19m/42.88p
R_load = 50
[Rising Waveform]
R_fixture = 50
V_fixture = 0.0
|   Time   V(typ)   V(min)   V(max)
0s        788.7uV    698.1uV    568.8uV
56ps      870.4uV    6.026uV    10.06mV
64ps      3.847mV    -94.17uV   47.51mV
76ps      16.08mV    2.694mV    151.1mV
99ps      153mV      25.95mV    315.6mV
114ps     248.5mV    94.15mV    366.5mV
129ps     309.7mV    185mV      390.7mV
154ps     356.3mV    291.6mV    404.8mV
185ps     371.8mV    342.7mV    408mV
373ps     374.9mV    358.1mV    408.5mV
[Falling Waveform]
R_fixture   = 50
V_fixture   = 1.1
V_fixture_min = 1.06
V_fixture_max = 1.17
|   Time   V(typ)   V(min)   V(max)
0s        1.1V       1.06V      1.17V
48ps      1.101V     1.06V      1.171V
70ps      1.099V     1.061V     1.16V
91ps      1.087V     1.055V     1.074V
119ps     1.004V     1.038V     963.5mV
142ps     936.4mV    985.6mV    911.9mV
166ps     890.2mV    927mV      883.4mV
200ps     855.8mV    870.8mV    865.8mV
240ps     839.3mV    837.9mV    858.7mV
373ps     830.4mV    815.7mV    855.6mV
[Rising Waveform]
R_fixture   = 50
V_fixture   = 1.1
V_fixture_min = 1.06
V_fixture_max = 1.17
|   Time   V(typ)   V(min)   V(max)
0s        830.1mV    814.5mV    855.5mV
50ps      826.7mV    812.6mV    859.4mV
60ps      830.8mV    809.6mV    888mV
74ps      867.7mV    815.6mV    968.2mV
86ps      924.2mV    843.8mV    1.023V
104ps     988.8mV    914.7mV    1.076V
122ps     1.028V     967.8mV    1.11V
143ps     1.056V     1.004V     1.135V
209ps     1.091V     1.048V     1.163V
373ps     1.1V       1.06V      1.17V
[Falling Waveform]
R_fixture = 50
V_fixture = 0.0
|   Time   V(typ)   V(min)   V(max)
0s        375mV      358.2mV    408.6mV
55ps      380.5mV    359.1mV    411.1mV
72ps      374.7mV    369.1mV    322.6mV
85ps      316.9mV    362.2mV    202mV
98ps      223.5mV    316.5mV    126.1mV
115ps     126.7mV    220.9mV    69.23mV
136ps     63.14mV    119.2mV    33.28mV
163ps     26.34mV    50.81mV    13.24mV
200ps     8.409mV    16.28mV    4.117mV
373ps     883.7uV    867.2uV    602.3uV
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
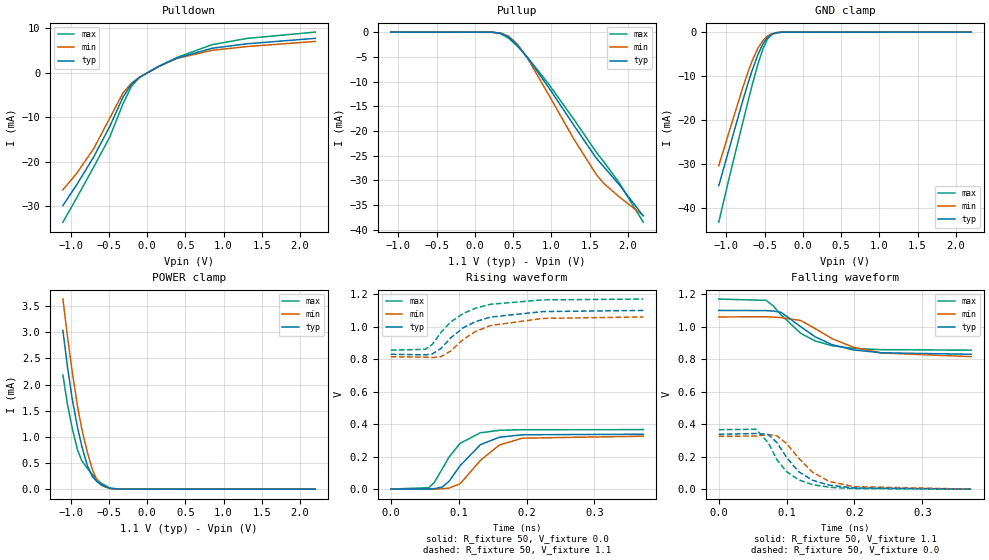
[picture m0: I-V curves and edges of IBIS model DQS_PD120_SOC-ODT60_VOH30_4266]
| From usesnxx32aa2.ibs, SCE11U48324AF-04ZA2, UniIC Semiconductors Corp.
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| DQS_PD120_SOC-ODT60_VOH30_4266
| (120 Ohm Pulldown, 60 Ohm System ODT Setting, VOH=VDDQ/3.0, 3200-4266Mbps)
[Model]   DQS_PD120_SOC-ODT60_VOH30_4266
Model_type   I/O
Vinl = 123.333mV
Vinh = 243.333mV
Vmeas = 183.333mV
Vref = 0.0mV
Cref = 0.0pF
Rref = 60.000Ohm
|   typ   min   max
|C_comp   0.838pF   0.788pF   0.888pF
C_comp_pullup   0.4190pF   0.3940pF   0.4440pF
C_comp_pulldown   0.4190pF   0.3940pF   0.4440pF
| Note: C_comp changes when the ODT circuit is enabled.
[Model Spec]
| Input threshold voltage corners
Vinl   0.1233V   0.1167V   0.1350V
Vinh   0.2433V   0.2367V   0.2550V
| Measurement voltage corners
Vmeas   0.1833V   0.1767V   0.1950V
| Timing spec test load voltage corners
Vref   0.0000V   0.0000V   0.0000V
| Dynamic Overshoot Parameters from LPDDR4 Specification
D_overshoot_ampl_h   0.30   NA   NA
D_overshoot_ampl_l   0.30   NA   NA
D_overshoot_area_h   0.1n   NA   NA
D_overshoot_area_l   0.1n   NA   NA
[Receiver Thresholds]
Vcross_low   = 123.3mV
Vcross_high  = 243.3mV
Vdiff_ac   = 120mV
Vdiff_dc   = 120mV
Tdiffslew_ac = 10.000ns |Not specified, so set to high value
[Voltage Range]   1.1000V   1.0600V   1.1700V
[Pullup Reference]   1.1000V   1.0600V   1.1700V
| Junction Temperature (Ambient temp is 35C typ 95C min -40C max)
[Temperature Range]   50.0   110.0   -40.0
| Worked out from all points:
|   slope of the pulldown table from 0 to 0.165 V, typ, clamps not added: 109 ohm
|   slope of the pullup table from 0 to 0.165 V, typ, clamps not added: 19.3 kohm
|   GND clamp passes 1 mA (typ) near -0.45 V on its own axis
|   POWER clamp passes 1 mA (typ) near -0.88 V on its own axis
|   rising waveform, R_fixture 50, V_fixture 0.0: 20-80 % time 41.2ps typ, 45.2ps min, 36.2ps max; typ from 0.001 V to 0.338 V
|   falling waveform, R_fixture 50, V_fixture 1.1: 20-80 % time 63.4ps typ, 72.8ps min, 53.8ps max; typ from 1.1 V to 0.83 V
|   rising waveform, R_fixture 50, V_fixture 1.1: 20-80 % time 56.9ps typ, 59.1ps min, 54.4ps max; typ from 0.83 V to 1.1 V
|   falling waveform, R_fixture 50, V_fixture 0.0: 20-80 % time 43.2ps typ, 48.8ps min, 38.7ps max; typ from 0.338 V to 0.001 V
[Pulldown]
|   Voltage   I(typ)   I(min)   I(max)
-1.1V     -29.81mA   -26.27mA   -33.53mA
-921.8mV  -25.21mA   -22.63mA   -28.15mA
-697.4mV  -18.91mA   -17.05mA   -21.18mA
-489.5mV  -12.15mA   -10.27mA   -14.52mA
-314.6mV  -5.506mA   -4.574mA   -7.019mA
-205.7mV  -2.636mA   -2.392mA   -3.114mA
-100.1mV  -1.074mA   -1.047mA   -1.09mA
154mV     1.398mA    1.387mA    1.403mA
391.6mV   3.252mA    3.172mA    3.388mA
850.3mV   5.453mA    4.993mA    6.257mA
1.309V    6.458mA    5.837mA    7.66mA
2.2V      7.677mA    6.979mA    9.076mA
[GND Clamp]
|   Voltage   I(typ)   I(min)   I(max)
-1.1V     -34.88mA   -30.34mA   -43.13mA
-941.6mV  -25.13mA   -21.34mA   -31.48mA
-789.8mV  -15.79mA   -12.83mA   -20.82mA
-717.2mV  -11.61mA   -9.055mA   -15.72mA
-661.1mV  -8.596mA   -6.455mA   -11.9mA
-588.5mV  -5.128mA   -3.689mA   -7.329mA
-522.5mV  -2.673mA   -1.907mA   -3.823mA
-466.4mV  -1.296mA   -942.9uA   -1.693mA
-413.6mV  -566.4uA   -417.7uA   -621.8uA
-350.9mV  -165.9uA   -125.8uA   -147.4uA
-261.8mV  -17.68uA   -15.49uA   -11.04uA
2.2V      0A         0A         0A
[Pullup]
|   Voltage   I(typ)   I(min)   I(max)
-1.1V     4.189uA    6.456uA    1.888uA
229.9mV   -30.39uA   -30.49uA   -31.09uA
335.5mV   -227.7uA   -189uA     -313.1uA
441.1mV   -997.2uA   -819.6uA   -1.249mA
556.6mV   -2.66mA    -2.461mA   -2.874mA
691.9mV   -5.249mA   -5.417mA   -5.187mA
965.8mV   -11.24mA   -12.72mA   -10.55mA
1.292V    -18.81mA   -21.61mA   -17.61mA
1.589V    -25.54mA   -28.86mA   -24.33mA
1.688V    -27.28mA   -30.64mA   -26.3mA
1.89V     -30.93mA   -33.36mA   -30.56mA
2.2V      -37.14mA   -37.09mA   -38.43mA
[POWER Clamp]
|   Voltage   I(typ)   I(min)   I(max)
-1.1V     3.036mA    3.636mA    2.186mA
-1.041V   2.347mA    2.931mA    1.626mA
-977.9mV  1.724mA    2.243mA    1.161mA
-908.6mV  1.178mA    1.583mA    748.3uA
-852.5mV  818.6uA    1.149mA    543.7uA
-779.9mV  447.9uA    701.7uA    396.3uA
-713.9mV  239.2uA    373.2uA    278.6uA
-654.5mV  142.7uA    170.4uA    185.9uA
-598.4mV  83.65uA    72.04uA    113.1uA
-486.2mV  16.76uA    10.18uA    20.93uA
-367.4mV  1.193uA    876.9nA    944.7nA
2.2V      0A         0A         0A
[Ramp]
|   typ   min   max
| 20% - 80%
dV/dt_r   202.48m/41.19p   195.26m/45.19p   219.60m/36.18p
dV/dt_f   161.74m/63.32p   146.59m/72.86p   188.63m/53.77p
| 25% - 75%
|dV/dt_r   168.74m/32.80p   162.72m/36.05p   183.00m/28.75p
|dV/dt_f   134.79m/50.32p   122.16m/57.94p   157.19m/42.69p
R_load = 50
[Rising Waveform]
R_fixture = 50
V_fixture = 0.0
|   Time   V(typ)   V(min)   V(max)
0s        628.8uV    553.5uV    453.6uV
56ps      781.3uV    -13.18uV   9.092mV
64ps      3.197mV    -42.07uV   40.74mV
76ps      13.39mV    2.459mV    126mV
86ps      49.08mV    6.757mV    198.7mV
102ps     144mV      32.52mV    281.6mV
132ps     273.9mV    177mV      347mV
160ps     319.6mV    271.8mV    362.2mV
194ps     334.7mV    313.9mV    365.9mV
372ps     338.1mV    326mV      366.5mV
[Falling Waveform]
R_fixture   = 50
V_fixture   = 1.1
V_fixture_min = 1.06
V_fixture_max = 1.17
|   Time   V(typ)   V(min)   V(max)
0s        1.1V       1.06V      1.17V
70ps      1.099V     1.061V     1.162V
81ps      1.096V     1.059V     1.125V
92ps      1.088V     1.056V     1.072V
121ps     999.5mV    1.038V     958.9mV
142ps     937.9mV    988.6mV    912.5mV
167ps     889.5mV    926.8mV    882.9mV
199ps     856.8mV    872.9mV    866.1mV
240ps     839.5mV    838.3mV    858.6mV
372ps     830.4mV    815.7mV    855.6mV
[Rising Waveform]
R_fixture   = 50
V_fixture   = 1.1
V_fixture_min = 1.06
V_fixture_max = 1.17
|   Time   V(typ)   V(min)   V(max)
0s        830.1mV    814.5mV    855.5mV
51ps      826.7mV    812.3mV    860.6mV
61ps      831.9mV    809.6mV    890.7mV
74ps      866.1mV    815.6mV    965.4mV
88ps      930.3mV    849.5mV    1.028V
107ps     994.2mV    922.5mV    1.082V
125ps     1.031V     971mV      1.114V
147ps     1.059V     1.007V     1.138V
224ps     1.093V     1.051V     1.165V
372ps     1.1V       1.06V      1.17V
[Falling Waveform]
R_fixture = 50
V_fixture = 0.0
|   Time   V(typ)   V(min)   V(max)
0s        338.2mV    326.1mV    366.5mV
55ps      343mV      327.2mV    368.8mV
73ps      336.9mV    336mV      286.5mV
86ps      285.9mV    327.8mV    179.4mV
100ps     195.6mV    281.1mV    108.3mV
118ps     107.5mV    190.2mV    57.56mV
138ps     55.64mV    105.2mV    28.67mV
163ps     24.82mV    47.98mV    12.28mV
199ps     8.155mV    15.88mV    3.788mV
372ps     733.4uV    742.5uV    489.3uV
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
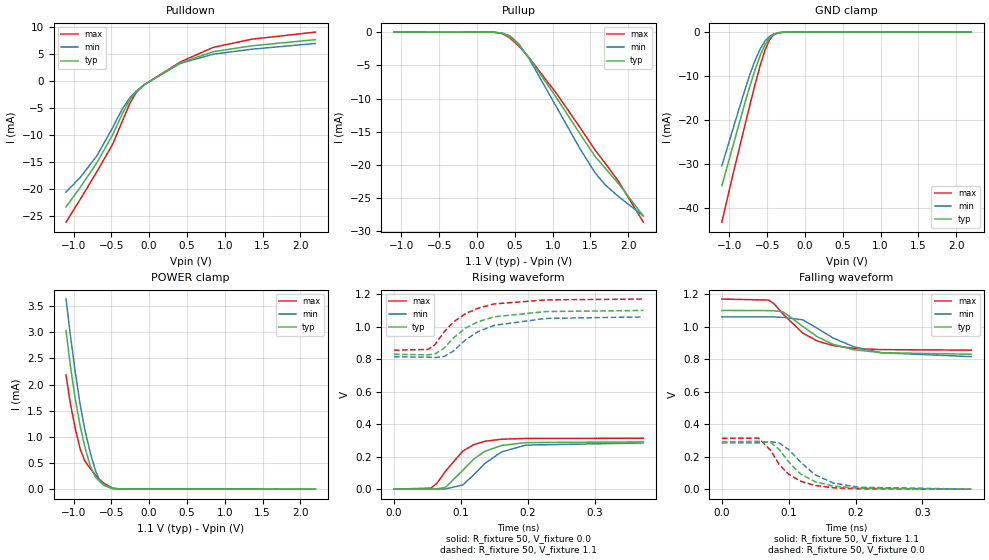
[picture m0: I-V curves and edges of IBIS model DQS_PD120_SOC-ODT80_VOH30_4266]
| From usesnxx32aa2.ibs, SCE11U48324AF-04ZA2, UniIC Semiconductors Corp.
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| DQS_PD120_SOC-ODT80_VOH30_4266
| (120 Ohm Pulldown, 80 Ohm System ODT Setting, VOH=VDDQ/3.0, 3200-4266Mbps)
[Model]   DQS_PD120_SOC-ODT80_VOH30_4266
Model_type   I/O
Vinl = 123.333mV
Vinh = 243.333mV
Vmeas = 183.333mV
Vref = 0.0mV
Cref = 0.0pF
Rref = 80.000Ohm
|   typ   min   max
|C_comp   0.838pF   0.788pF   0.888pF
C_comp_pullup   0.4190pF   0.3940pF   0.4440pF
C_comp_pulldown   0.4190pF   0.3940pF   0.4440pF
| Note: C_comp changes when the ODT circuit is enabled.
[Model Spec]
| Input threshold voltage corners
Vinl   0.1233V   0.1167V   0.1350V
Vinh   0.2433V   0.2367V   0.2550V
| Measurement voltage corners
Vmeas   0.1833V   0.1767V   0.1950V
| Timing spec test load voltage corners
Vref   0.0000V   0.0000V   0.0000V
| Dynamic Overshoot Parameters from LPDDR4 Specification
D_overshoot_ampl_h   0.30   NA   NA
D_overshoot_ampl_l   0.30   NA   NA
D_overshoot_area_h   0.1n   NA   NA
D_overshoot_area_l   0.1n   NA   NA
[Receiver Thresholds]
Vcross_low   = 123.3mV
Vcross_high  = 243.3mV
Vdiff_ac   = 120mV
Vdiff_dc   = 120mV
Tdiffslew_ac = 10.000ns |Not specified, so set to high value
[Voltage Range]   1.1000V   1.0600V   1.1700V
[Pullup Reference]   1.1000V   1.0600V   1.1700V
| Junction Temperature (Ambient temp is 35C typ 95C min -40C max)
[Temperature Range]   50.0   110.0   -40.0
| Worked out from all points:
|   slope of the pulldown table from 0 to 0.165 V, typ, clamps not added: 110 ohm
|   slope of the pullup table from 0 to 0.165 V, typ, clamps not added: 25.8 kohm
|   GND clamp passes 1 mA (typ) near -0.45 V on its own axis
|   POWER clamp passes 1 mA (typ) near -0.88 V on its own axis
|   rising waveform, R_fixture 50, V_fixture 0.0: 20-80 % time 44.9ps typ, 48ps min, 39.1ps max; typ from 0 V to 0.291 V
|   falling waveform, R_fixture 50, V_fixture 1.1: 20-80 % time 63ps typ, 72.4ps min, 53.5ps max; typ from 1.1 V to 0.83 V
|   rising waveform, R_fixture 50, V_fixture 1.1: 20-80 % time 57.3ps typ, 60.3ps min, 54.5ps max; typ from 0.83 V to 1.1 V
|   falling waveform, R_fixture 50, V_fixture 0.0: 20-80 % time 43.9ps typ, 49.6ps min, 39.3ps max; typ from 0.291 V to 0.001 V
[Pulldown]
|   Voltage   I(typ)   I(min)   I(max)
-1.1V     -23.24mA   -20.49mA   -26.08mA
-915.2mV  -19.72mA   -17.86mA   -21.93mA
-687.5mV  -14.99mA   -13.72mA   -16.65mA
-479.6mV  -9.837mA   -8.514mA   -11.58mA
-354.2mV  -5.997mA   -5.106mA   -7.363mA
-251.9mV  -3.347mA   -2.996mA   -4.013mA
-169.4mV  -1.906mA   -1.817mA   -2.065mA
-63.8mV   -654.6uA   -646.8uA   -646.6uA
411.4mV   3.386mA    3.295mA    3.541mA
847mV     5.443mA    4.985mA    6.243mA
1.359V    6.542mA    5.912mA    7.765mA
2.2V      7.677mA    6.979mA    9.076mA
[GND Clamp]
|   Voltage   I(typ)   I(min)   I(max)
-1.1V     -34.88mA   -30.34mA   -43.13mA
-944.9mV  -25.34mA   -21.53mA   -31.71mA
-799.7mV  -16.37mA   -13.37mA   -21.52mA
-727.1mV  -12.16mA   -9.546mA   -16.41mA
-664.4mV  -8.768mA   -6.598mA   -12.12mA
-595.1mV  -5.416mA   -3.908mA   -7.72mA
-525.8mV  -2.776mA   -1.977mA   -3.976mA
-469.7mV  -1.36mA    -986.9uA   -1.791mA
-416.9mV  -597.9uA   -441.2uA   -665.6uA
-354.2mV  -178.7uA   -135.3uA   -159.2uA
-265.1mV  -19.44uA   -16.69uA   -12.19uA
2.2V      0A         0A         0A
[Pullup]
|   Voltage   I(typ)   I(min)   I(max)
-1.1V     3.142uA    4.844uA    1.416uA
229.9mV   -22.65uA   -22.95uA   -23.28uA
332.2mV   -161.3uA   -134.8uA   -221.6uA
431.2mV   -668.7uA   -545.4uA   -849.8uA
546.7mV   -1.867mA   -1.71mA    -2.037mA
685.3mV   -3.83mA    -3.936mA   -3.796mA
1.055V    -9.944mA   -11.36mA   -9.304mA
1.368V    -15.43mA   -17.68mA   -14.46mA
1.566V    -18.77mA   -21.24mA   -17.83mA
1.698V    -20.51mA   -23.02mA   -19.78mA
1.87V     -22.79mA   -24.74mA   -22.44mA
2.2V      -27.69mA   -27.68mA   -28.61mA
[POWER Clamp]
|   Voltage   I(typ)   I(min)   I(max)
-1.1V     3.036mA    3.636mA    2.186mA
-1.044V   2.383mA    2.969mA    1.653mA
-981.2mV  1.754mA    2.277mA    1.183mA
-911.9mV  1.201mA    1.611mA    764.9uA
-852.5mV  818.6uA    1.149mA    543.8uA
-779.9mV  448.1uA    701.7uA    396.3uA
-710.6mV  232.2uA    359.2uA    273.1uA
-654.5mV  142.7uA    170.4uA    185.9uA
-598.4mV  83.65uA    71.97uA    113uA
-482.9mV  15.74uA    9.492uA    19.5uA
-360.8mV  1.027uA    771.1nA    792.4nA
2.2V      0A         0A         0A
[Ramp]
|   typ   min   max
| 20% - 80%
dV/dt_r   174.39m/44.88p   170.39m/47.98p   187.82m/39.12p
dV/dt_f   161.71m/63.03p   146.59m/72.43p   188.59m/53.53p
| 25% - 75%
|dV/dt_r   145.32m/35.78p   141.99m/38.26p   156.51m/31.09p
|dV/dt_f   134.76m/49.98p   122.16m/57.58p   157.16m/42.51p
R_load = 50
[Rising Waveform]
R_fixture = 50
V_fixture = 0.0
|   Time   V(typ)   V(min)   V(max)
0s        468.9uV    408.6uV    339.6uV
55ps      429.5uV    131.3uV    6.073mV
64ps      1.931mV    -48.05uV   34.56mV
77ps      10.59mV    1.53mV     109.7mV
103ps     116.2mV    25.87mV    234.7mV
119ps     184.3mV    86.46mV    273.3mV
136ps     232.7mV    158.1mV    294.5mV
161ps     269.1mV    229.3mV    307.4mV
197ps     286.5mV    271.1mV    312.3mV
373ps     291.1mV    284.4mV    313.4mV
[Falling Waveform]
R_fixture   = 50
V_fixture   = 1.1
V_fixture_min = 1.06
V_fixture_max = 1.17
|   Time   V(typ)   V(min)   V(max)
0s        1.1V       1.06V      1.17V
70ps      1.099V     1.06V      1.164V
78ps      1.098V     1.06V      1.141V
92ps      1.091V     1.057V     1.076V
121ps     1.002V     1.042V     960.5mV
143ps     937.4mV    989.4mV    911.7mV
166ps     892mV      931.4mV    884.2mV
197ps     858.6mV    876.8mV    867mV
238ps     840.1mV    839.9mV    859mV
373ps     830.5mV    815.7mV    855.7mV
[Rising Waveform]
R_fixture   = 50
V_fixture   = 1.1
V_fixture_min = 1.06
V_fixture_max = 1.17
|   Time   V(typ)   V(min)   V(max)
0s        830.1mV    814.4mV    855.5mV
51ps      826.9mV    812.5mV    859.9mV
61ps      831.2mV    809.8mV    888.3mV
75ps      867.7mV    816.1mV    967.5mV
89ps      931.2mV    850.4mV    1.029V
107ps     991.3mV    918.6mV    1.08V
126ps     1.031V     969.4mV    1.114V
150ps     1.061V     1.008V     1.14V
227ps     1.093V     1.051V     1.165V
373ps     1.1V       1.06V      1.17V
[Falling Waveform]
R_fixture = 50
V_fixture = 0.0
|   Time   V(typ)   V(min)   V(max)
0s        291.2mV    284.5mV    313.4mV
55ps      295.1mV    285.3mV    314.3mV
73ps      288.1mV    292.5mV    239mV
86ps      244.1mV    284.6mV    150.4mV
100ps     167.8mV    243.8mV    91.47mV
117ps     96.19mV    170.1mV    50.52mV
139ps     46.84mV    89.66mV    23.53mV
166ps     19.62mV    38.96mV    9.379mV
204ps     6.058mV    12.34mV    2.795mV
373ps     586uV      589.9uV    392.5uV
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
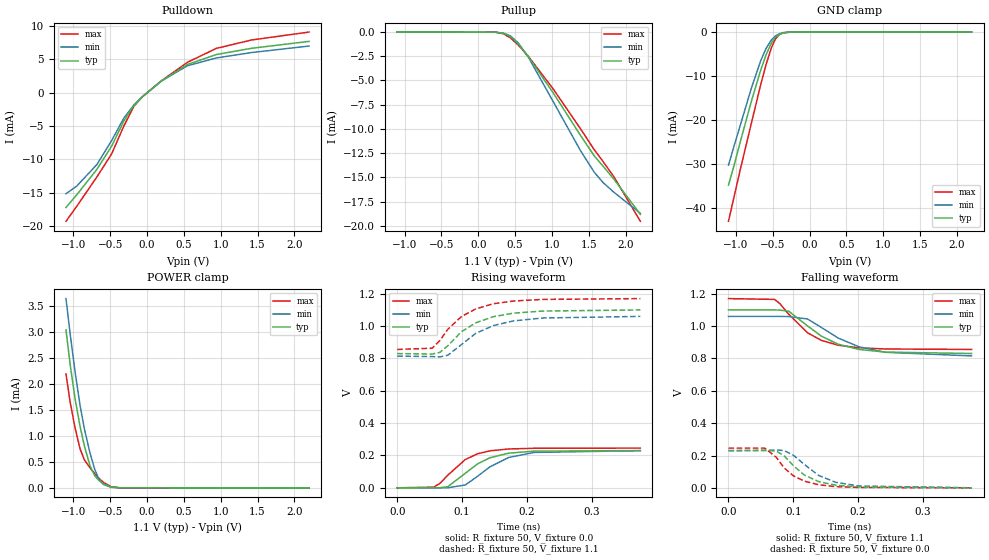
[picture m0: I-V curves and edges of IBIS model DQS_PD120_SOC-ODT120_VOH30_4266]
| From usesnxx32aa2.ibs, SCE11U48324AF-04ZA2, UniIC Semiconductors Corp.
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| DQS_PD120_SOC-ODT120_VOH30_4266
| (120 Ohm Pulldown, 120 Ohm System ODT Setting, VOH=VDDQ/3.0, 3200-4266Mbps)
[Model]   DQS_PD120_SOC-ODT120_VOH30_4266
Model_type   I/O
Vinl = 123.333mV
Vinh = 243.333mV
Vmeas = 183.333mV
Vref = 0.0mV
Cref = 0.0pF
Rref = 120.000Ohm
|   typ   min   max
|C_comp   0.838pF   0.788pF   0.888pF
C_comp_pullup   0.4190pF   0.3940pF   0.4440pF
C_comp_pulldown   0.4190pF   0.3940pF   0.4440pF
| Note: C_comp changes when the ODT circuit is enabled.
[Model Spec]
| Input threshold voltage corners
Vinl   0.1233V   0.1167V   0.1350V
Vinh   0.2433V   0.2367V   0.2550V
| Measurement voltage corners
Vmeas   0.1833V   0.1767V   0.1950V
| Timing spec test load voltage corners
Vref   0.0000V   0.0000V   0.0000V
| Dynamic Overshoot Parameters from LPDDR4 Specification
D_overshoot_ampl_h   0.30   NA   NA
D_overshoot_ampl_l   0.30   NA   NA
D_overshoot_area_h   0.1n   NA   NA
D_overshoot_area_l   0.1n   NA   NA
[Receiver Thresholds]
Vcross_low   = 123.3mV
Vcross_high  = 243.3mV
Vdiff_ac   = 120mV
Vdiff_dc   = 120mV
Tdiffslew_ac = 10.000ns |Not specified, so set to high value
[Voltage Range]   1.1000V   1.0600V   1.1700V
[Pullup Reference]   1.1000V   1.0600V   1.1700V
| Junction Temperature (Ambient temp is 35C typ 95C min -40C max)
[Temperature Range]   50.0   110.0   -40.0
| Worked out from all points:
|   slope of the pulldown table from 0 to 0.165 V, typ, clamps not added: 110 ohm
|   slope of the pullup table from 0 to 0.165 V, typ, clamps not added: 39.3 kohm
|   GND clamp passes 1 mA (typ) near -0.45 V on its own axis
|   POWER clamp passes 1 mA (typ) near -0.88 V on its own axis
|   rising waveform, R_fixture 50, V_fixture 0.0: 20-80 % time 48.9ps typ, 53.2ps min, 43.4ps max; typ from 0 V to 0.23 V
|   falling waveform, R_fixture 50, V_fixture 1.1: 20-80 % time 62.5ps typ, 72ps min, 53.2ps max; typ from 1.1 V to 0.83 V
|   rising waveform, R_fixture 50, V_fixture 1.1: 20-80 % time 58ps typ, 61.6ps min, 54.4ps max; typ from 0.83 V to 1.1 V
|   falling waveform, R_fixture 50, V_fixture 0.0: 20-80 % time 44ps typ, 49.8ps min, 39.4ps max; typ from 0.231 V to 0 V
[Pulldown]
|   Voltage   I(typ)   I(min)   I(max)
-1.1V     -17.22mA   -15.17mA   -19.29mA
-951.5mV  -15.29mA   -13.99mA   -17.01mA
-680.9mV  -11.52mA   -10.79mA   -12.65mA
-479.6mV  -8.015mA   -7.184mA   -9.175mA
-314.6mV  -4.26mA    -3.822mA   -5.007mA
-179.3mV  -1.94mA    -1.875mA   -2.067mA
-60.5mV   -606uA     -602uA     -596.1uA
193.6mV   1.737mA    1.719mA    1.751mA
546.7mV   4.202mA    4.013mA    4.524mA
939.4mV   5.699mA    5.189mA    6.623mA
1.418V    6.638mA    6mA        7.883mA
2.2V      7.677mA    6.979mA    9.076mA
[GND Clamp]
|   Voltage   I(typ)   I(min)   I(max)
-1.1V     -34.88mA   -30.34mA   -43.13mA
-1.027V   -30.57mA   -26.14mA   -37.76mA
-941.6mV  -25.13mA   -21.34mA   -31.48mA
-789.8mV  -15.79mA   -12.83mA   -20.82mA
-664.4mV  -8.768mA   -6.598mA   -12.12mA
-588.5mV  -5.129mA   -3.689mA   -7.328mA
-519.2mV  -2.57mA    -1.835mA   -3.672mA
-463.1mV  -1.235mA   -900.7uA   -1.601mA
-410.3mV  -533.9uA   -394.1uA   -581.6uA
-354.2mV  -177.4uA   -135uA     -161.5uA
-258.5mV  -16.16uA   -14.33uA   -9.97uA
2.2V      0A         0A         0A
[Pullup]
|   Voltage   I(typ)   I(min)   I(max)
-1.1V     2.095uA    3.229uA    944.4nA
236.5mV   -17.43uA   -17.3uA    -18.36uA
342.1mV   -127.5uA   -105.3uA   -176uA
437.8mV   -483.9uA   -396.3uA   -608.9uA
543.4mV   -1.23mA    -1.123mA   -1.345mA
682mV     -2.552mA   -2.625mA   -2.527mA
1.022V    -6.34mA    -7.25mA    -5.926mA
1.391V    -10.71mA   -12.29mA   -10.03mA
1.576V    -12.8mA    -14.49mA   -12.17mA
1.695V    -13.86mA   -15.55mA   -13.38mA
1.844V    -15.22mA   -16.56mA   -14.98mA
2.2V      -18.83mA   -18.72mA   -19.54mA
[POWER Clamp]
|   Voltage   I(typ)   I(min)   I(max)
-1.1V     3.036mA    3.636mA    2.186mA
-1.041V   2.347mA    2.931mA    1.626mA
-974.6mV  1.695mA    2.208mA    1.139mA
-908.6mV  1.178mA    1.583mA    748.5uA
-849.2mV  799.3uA    1.126mA    535.4uA
-773.3mV  420.8uA    665.5uA    384.1uA
-707.3mV  225.6uA    345.6uA    267.6uA
-651.2mV  138.6uA    162.3uA    181.2uA
-591.8mV  77.96uA    64.82uA    105.5uA
-489.5mV  17.79uA    10.84uA    22.53uA
-374mV    1.384uA    993.6nA    1.129uA
2.2V      0A         0A         0A
[Ramp]
|   typ   min   max
| 20% - 80%
dV/dt_r   138.07m/48.95p   137.67m/53.24p   147.29m/43.44p
dV/dt_f   161.72m/62.55p   146.59m/71.85p   188.59m/53.28p
| 25% - 75%
|dV/dt_r   115.06m/39.02p   114.72m/42.48p   122.74m/34.53p
|dV/dt_f   134.76m/49.69p   122.16m/57.20p   157.16m/42.33p
R_load = 50
[Rising Waveform]
R_fixture = 50
V_fixture = 0.0
|   Time   V(typ)   V(min)   V(max)
0s        308.8uV    265.5uV    224.3uV
56ps      228.9uV    171.2uV    3.854mV
66ps      928.7uV    -52.89uV   27.88mV
78ps      7.006mV    475.6uV    78mV
105ps     89.89mV    17.59mV    175.1mV
124ps     148.3mV    71.75mV    210.5mV
143ps     185.8mV    129.9mV    228.8mV
172ps     214.4mV    187.7mV    240.3mV
211ps     226.7mV    218.9mV    244.5mV
375ps     230.4mV    229.7mV    245.7mV
[Falling Waveform]
R_fixture   = 50
V_fixture   = 1.1
V_fixture_min = 1.06
V_fixture_max = 1.17
|   Time   V(typ)   V(min)   V(max)
0s        1.1V       1.06V      1.17V
71ps      1.1V       1.06V      1.165V
79ps      1.099V     1.06V      1.14V
93ps      1.092V     1.059V     1.073V
122ps     1.001V     1.044V     958.8mV
143ps     938.7mV    992.3mV    912.2mV
169ps     888.4mV    926.6mV    882mV
201ps     856mV      872.5mV    865.8mV
242ps     839.3mV    838.1mV    858.6mV
375ps     830.5mV    815.7mV    855.7mV
[Rising Waveform]
R_fixture   = 50
V_fixture   = 1.1
V_fixture_min = 1.06
V_fixture_max = 1.17
|   Time   V(typ)   V(min)   V(max)
0s        830.1mV    814.4mV    855.5mV
54ps      827.1mV    811.7mV    863.4mV
66ps      838.1mV    809.9mV    911.6mV
78ps      878.2mV    819.8mV    980.1mV
99ps      965.2mV    885.7mV    1.059V
121ps     1.02V      955mV      1.106V
148ps     1.058V     1.003V     1.138V
179ps     1.08V      1.032V     1.155V
224ps     1.093V     1.05V      1.165V
375ps     1.1V       1.06V      1.17V
[Falling Waveform]
R_fixture = 50
V_fixture = 0.0
|   Time   V(typ)   V(min)   V(max)
0s        230.5mV    229.8mV    245.8mV
56ps      233.1mV    230.3mV    245.7mV
74ps      227.2mV    235mV      187.9mV
86ps      197.6mV    230.2mV    122.8mV
100ps     137.7mV    202.3mV    74.8mV
117ps     79.32mV    145mV      41.35mV
139ps     38.89mV    77.21mV    19.29mV
165ps     16.85mV    34.78mV    7.964mV
201ps     5.456mV    11.68mV    2.463mV
375ps     419uV      449uV      272.4uV
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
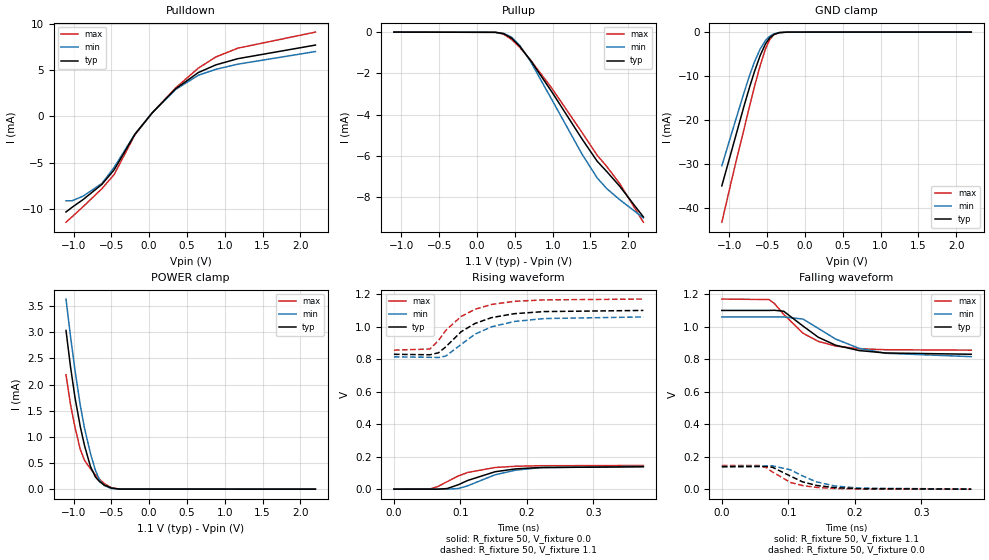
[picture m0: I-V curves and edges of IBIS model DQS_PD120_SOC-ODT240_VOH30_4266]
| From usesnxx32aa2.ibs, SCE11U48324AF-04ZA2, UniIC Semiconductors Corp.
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| DQS_PD120_SOC-ODT240_VOH30_4266
| (120 Ohm Pulldown, 240 Ohm System ODT Setting, VOH=VDDQ/3.0, 3200-4266Mbps)
[Model]   DQS_PD120_SOC-ODT240_VOH30_4266
Model_type   I/O
Vinl = 123.333mV
Vinh = 243.333mV
Vmeas = 183.333mV
Vref = 0.0mV
Cref = 0.0pF
Rref = 240.000Ohm
|   typ   min   max
|C_comp   0.838pF   0.788pF   0.888pF
C_comp_pullup   0.4190pF   0.3940pF   0.4440pF
C_comp_pulldown   0.4190pF   0.3940pF   0.4440pF
| Note: C_comp changes when the ODT circuit is enabled.
[Model Spec]
| Input threshold voltage corners
Vinl   0.1233V   0.1167V   0.1350V
Vinh   0.2433V   0.2367V   0.2550V
| Measurement voltage corners
Vmeas   0.1833V   0.1767V   0.1950V
| Timing spec test load voltage corners
Vref   0.0000V   0.0000V   0.0000V
| Dynamic Overshoot Parameters from LPDDR4 Specification
D_overshoot_ampl_h   0.30   NA   NA
D_overshoot_ampl_l   0.30   NA   NA
D_overshoot_area_h   0.1n   NA   NA
D_overshoot_area_l   0.1n   NA   NA
[Receiver Thresholds]
Vcross_low   = 123.3mV
Vcross_high  = 243.3mV
Vdiff_ac   = 120mV
Vdiff_dc   = 120mV
Tdiffslew_ac = 10.000ns |Not specified, so set to high value
[Voltage Range]   1.1000V   1.0600V   1.1700V
[Pullup Reference]   1.1000V   1.0600V   1.1700V
| Junction Temperature (Ambient temp is 35C typ 95C min -40C max)
[Temperature Range]   50.0   110.0   -40.0
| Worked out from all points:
|   slope of the pulldown table from 0 to 0.165 V, typ, clamps not added: 110 ohm
|   slope of the pullup table from 0 to 0.165 V, typ, clamps not added: 80.8 kohm
|   GND clamp passes 1 mA (typ) near -0.45 V on its own axis
|   POWER clamp passes 1 mA (typ) near -0.88 V on its own axis
|   rising waveform, R_fixture 50, V_fixture 0.0: 20-80 % time 58.7ps typ, 61.1ps min, 51.3ps max; typ from 0 V to 0.138 V
|   falling waveform, R_fixture 50, V_fixture 1.1: 20-80 % time 62.3ps typ, 71.4ps min, 53.3ps max; typ from 1.1 V to 0.83 V
|   rising waveform, R_fixture 50, V_fixture 1.1: 20-80 % time 58.7ps typ, 63.1ps min, 54.5ps max; typ from 0.83 V to 1.1 V
|   falling waveform, R_fixture 50, V_fixture 0.0: 20-80 % time 44.8ps typ, 51.1ps min, 40.4ps max; typ from 0.138 V to 0 V
[Pulldown]
|   Voltage   I(typ)   I(min)   I(max)
-1.1V     -10.3mA    -9.096mA   -11.4mA
-1.021V   -9.804mA   -9.096mA   -10.83mA
-869mV    -8.932mA   -8.575mA   -9.693mA
-624.8mV  -7.325mA   -7.221mA   -7.789mA
-463.1mV  -5.763mA   -5.495mA   -6.266mA
-189.2mV  -1.938mA   -1.915mA   -1.998mA
41.8mV    390.2uA    389.2uA    387.4uA
348.7mV   2.951mA    2.889mA    3.049mA
649mV     4.711mA    4.421mA    5.188mA
883.3mV   5.548mA    5.069mA    6.4mA
1.174V    6.213mA    5.621mA    7.344mA
2.2V      7.677mA    6.979mA    9.076mA
[GND Clamp]
|   Voltage   I(typ)   I(min)   I(max)
-1.1V     -34.88mA   -30.34mA   -43.13mA
-941.6mV  -25.13mA   -21.34mA   -31.48mA
-803mV    -16.57mA   -13.55mA   -21.76mA
-730.4mV  -12.35mA   -9.712mA   -16.64mA
-667.7mV  -8.939mA   -6.742mA   -12.34mA
-591.8mV  -5.271mA   -3.798mA   -7.524mA
-522.5mV  -2.671mA   -1.906mA   -3.822mA
-466.4mV  -1.3mA     -942.9uA   -1.694mA
-413.6mV  -566uA     -416.5uA   -621.4uA
-341mV    -133.9uA   -101.9uA   -113.8uA
-232.1mV  -7.48uA    -7.211uA   -3.94uA
2.2V      0A         0A         0A
[Pullup]
|   Voltage   I(typ)   I(min)   I(max)
-1.1V     1.047uA    1.615uA    471.8nA
239.8mV   -9.309uA   -9.166uA   -9.951uA
348.7mV   -70.62uA   -58.36uA   -97.39uA
457.6mV   -294.6uA   -245.6uA   -360.1uA
566.5mV   -699.7uA   -652.8uA   -750.5uA
705.1mV   -1.361mA   -1.411mA   -1.342mA
992.2mV   -2.916mA   -3.298mA   -2.74mA
1.388V    -5.184mA   -5.919mA   -4.87mA
1.589V    -6.266mA   -7.078mA   -5.978mA
1.718V    -6.777mA   -7.604mA   -6.534mA
1.887V    -7.482mA   -8.134mA   -7.355mA
2.2V      -8.971mA   -9.018mA   -9.226mA
[POWER Clamp]
|   Voltage   I(typ)   I(min)   I(max)
-1.1V     3.036mA    3.636mA    2.186mA
-1.041V   2.347mA    2.931mA    1.626mA
-981.2mV  1.754mA    2.277mA    1.183mA
-911.9mV  1.202mA    1.611mA    765uA
-855.8mV  838.1uA    1.172mA    552.2uA
-776.6mV  434.2uA    683.6uA    390.2uA
-710.6mV  232.2uA    359.2uA    273.1uA
-654.5mV  142.7uA    170.4uA    185.9uA
-595.1mV  80.78uA    68.3uA     109.3uA
-499.4mV  21.4uA     13.11uA    27.46uA
-393.8mV  2.226uA    1.481uA    1.93uA
2.2V      0A         0A         0A
[Ramp]
|   typ   min   max
| 20% - 80%
dV/dt_r   82.45m/58.69p   84.21m/61.11p   87.25m/51.26p
dV/dt_f   161.73m/62.23p   146.59m/71.41p   188.63m/53.17p
| 25% - 75%
|dV/dt_r   68.71m/46.73p   70.17m/48.68p   72.70m/40.64p
|dV/dt_f   134.78m/49.49p   122.16m/56.84p   157.19m/42.28p
R_load = 50
[Rising Waveform]
R_fixture = 50
V_fixture = 0.0
|   Time   V(typ)   V(min)   V(max)
0s        145uV      117.3uV    106.2uV
55ps      98.47uV    188.1uV    2.011mV
66ps      -121.8uV   -19.64uV   16mV
80ps      3.744mV    -47.41uV   46.08mV
97ps      27.31mV    3.813mV    81.56mV
111ps     53.55mV    20.81mV    102.7mV
152ps     107.1mV    88.28mV    133.3mV
183ps     124.7mV    116.9mV    140.8mV
220ps     133.1mV    132.1mV    144.1mV
375ps     137.6mV    140.5mV    145.5mV
[Falling Waveform]
R_fixture   = 50
V_fixture   = 1.1
V_fixture_min = 1.06
V_fixture_max = 1.17
|   Time   V(typ)   V(min)   V(max)
0s        1.1V       1.06V      1.17V
71ps      1.1V       1.06V      1.167V
79ps      1.101V     1.06V      1.143V
93ps      1.095V     1.06V      1.076V
122ps     1.004V     1.047V     959.8mV
145ps     935mV      989.5mV    909.7mV
171ps     886.1mV    924mV      880.8mV
206ps     853.3mV    867.4mV    864.4mV
246ps     838.3mV    836.3mV    858.2mV
375ps     830.4mV    815.7mV    855.6mV
[Rising Waveform]
R_fixture   = 50
V_fixture   = 1.1
V_fixture_min = 1.06
V_fixture_max = 1.17
|   Time   V(typ)   V(min)   V(max)
0s        830.1mV    814.4mV    855.5mV
54ps      827.1mV    811.8mV    862.4mV
67ps      839.2mV    810.2mV    914.9mV
78ps      876mV      819.4mV    977.4mV
101ps     968.8mV    890.8mV    1.063V
122ps     1.02V      954.1mV    1.107V
147ps     1.056V     999.3mV    1.137V
181ps     1.08V      1.032V     1.156V
226ps     1.093V     1.05V      1.165V
375ps     1.1V       1.06V      1.17V
[Falling Waveform]
R_fixture = 50
V_fixture = 0.0
|   Time   V(typ)   V(min)   V(max)
0s        137.7mV    140.6mV    145.6mV
56ps      139.3mV    141.3mV    145.7mV
67ps      139.5mV    143.1mV    132.5mV
76ps      135.2mV    143.7mV    106.4mV
103ps     80.92mV    119.2mV    41.79mV
121ps     45.6mV     82.45mV    22.48mV
142ps     23.23mV    45.37mV    10.91mV
169ps     9.803mV    20.16mV    4.391mV
206ps     3.139mV    6.699mV    1.312mV
375ps     232.7uV    260.2uV    135.9uV
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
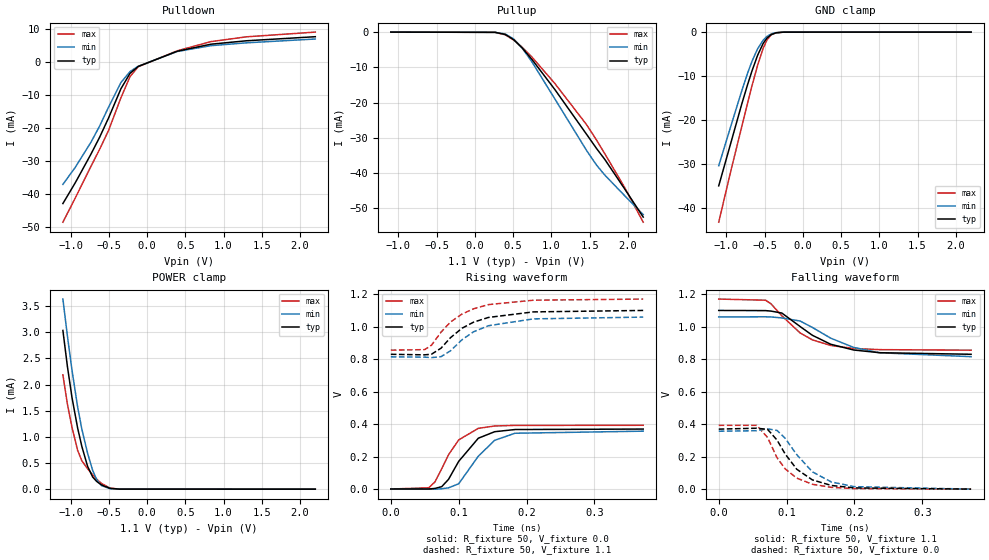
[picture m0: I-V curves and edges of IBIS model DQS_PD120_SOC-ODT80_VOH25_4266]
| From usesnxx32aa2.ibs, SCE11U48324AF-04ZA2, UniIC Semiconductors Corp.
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| DQS_PD120_SOC-ODT80_VOH25_4266
| (120 Ohm Pulldown, 80 Ohm System ODT Setting, VOH=VDDQ/2.5, 3200-4266Mbps)
[Model]   DQS_PD120_SOC-ODT80_VOH25_4266
Model_type   I/O
Vinl = 160.000mV
Vinh = 280.000mV
Vmeas = 220.000mV
Vref = 0.0mV
Cref = 0.0pF
Rref = 80.000Ohm
|   typ   min   max
|C_comp   0.838pF   0.788pF   0.888pF
C_comp_pullup   0.4190pF   0.3940pF   0.4440pF
C_comp_pulldown   0.4190pF   0.3940pF   0.4440pF
| Note: C_comp changes when the ODT circuit is enabled.
[Model Spec]
| Input threshold voltage corners
Vinl   0.1600V   0.1520V   0.1740V
Vinh   0.2800V   0.2720V   0.2940V
| Measurement voltage corners
Vmeas   0.2200V   0.2120V   0.2340V
| Timing spec test load voltage corners
Vref   0.0000V   0.0000V   0.0000V
| Dynamic Overshoot Parameters from LPDDR4 Specification
D_overshoot_ampl_h   0.30   NA   NA
D_overshoot_ampl_l   0.30   NA   NA
D_overshoot_area_h   0.1n   NA   NA
D_overshoot_area_l   0.1n   NA   NA
[Receiver Thresholds]
Vcross_low   = 160.0mV
Vcross_high  = 280.0mV
Vdiff_ac   = 120mV
Vdiff_dc   = 120mV
Tdiffslew_ac = 10.000ns |Not specified, so set to high value
[Voltage Range]   1.1000V   1.0600V   1.1700V
[Pullup Reference]   1.1000V   1.0600V   1.1700V
| Junction Temperature (Ambient temp is 35C typ 95C min -40C max)
[Temperature Range]   50.0   110.0   -40.0
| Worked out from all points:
|   slope of the pulldown table from 0 to 0.165 V, typ, clamps not added: 109 ohm
|   slope of the pullup table from 0 to 0.165 V, typ, clamps not added: 17.8 kohm
|   GND clamp passes 1 mA (typ) near -0.45 V on its own axis
|   POWER clamp passes 1 mA (typ) near -0.88 V on its own axis
|   rising waveform, R_fixture 50, V_fixture 0.0: 20-80 % time 36.1ps typ, 39.8ps min, 33ps max; typ from 0.001 V to 0.37 V
|   falling waveform, R_fixture 50, V_fixture 1.1: 20-80 % time 63.7ps typ, 74.2ps min, 53.8ps max; typ from 1.1 V to 0.83 V
|   rising waveform, R_fixture 50, V_fixture 1.1: 20-80 % time 56.3ps typ, 57ps min, 54ps max; typ from 0.83 V to 1.1 V
|   falling waveform, R_fixture 50, V_fixture 0.0: 20-80 % time 43.2ps typ, 48ps min, 38.5ps max; typ from 0.37 V to 0.001 V
[Pulldown]
|   Voltage   I(typ)   I(min)   I(max)
-1.1V     -42.88mA   -37.08mA   -48.53mA
-938.3mV  -36.58mA   -31.9mA    -41.19mA
-733.7mV  -27.93mA   -24.32mA   -31.62mA
-621.5mV  -22.87mA   -19.48mA   -26.52mA
-502.7mV  -16.93mA   -13.66mA   -20.72mA
-341mV    -8.078mA   -6.204mA   -10.8mA
-222.2mV  -3.426mA   -2.883mA   -4.417mA
-116.6mV  -1.358mA   -1.283mA   -1.434mA
394.9mV   3.275mA    3.192mA    3.414mA
833.8mV   5.403mA    4.954mA    6.183mA
1.299V    6.441mA    5.822mA    7.639mA
2.2V      7.677mA    6.979mA    9.076mA
[GND Clamp]
|   Voltage   I(typ)   I(min)   I(max)
-1.1V     -34.89mA   -30.33mA   -43.14mA
-941.6mV  -25.14mA   -21.33mA   -31.48mA
-799.7mV  -16.38mA   -13.37mA   -21.53mA
-723.8mV  -11.98mA   -9.379mA   -16.19mA
-664.4mV  -8.771mA   -6.596mA   -12.13mA
-591.8mV  -5.274mA   -3.797mA   -7.531mA
-519.2mV  -2.573mA   -1.835mA   -3.675mA
-469.7mV  -1.363mA   -986.3uA   -1.792mA
-413.6mV  -565uA     -420.4uA   -622.3uA
-354.2mV  -178.4uA   -136.7uA   -160uA
-251.9mV  -13.38uA   -12.39uA   -7.897uA
2.2V      0A         0A         0A
[Pullup]
|   Voltage   I(typ)   I(min)   I(max)
-1.1V     4.112uA    7.441uA    1.363uA
262.9mV   -64.74uA   -63.4uA    -66.46uA
398.2mV   -662.3uA   -549.9uA   -784uA
510.4mV   -2.219mA   -2.012mA   -2.306mA
616mV     -4.459mA   -4.485mA   -4.266mA
744.7mV   -7.731mA   -8.429mA   -7.062mA
1.042V    -16.2mA    -18.85mA   -14.5mA
1.461V    -29.03mA   -33.62mA   -26.29mA
1.589V    -32.98mA   -37.7mA    -30.6mA
1.698V    -36.11mA   -40.55mA   -34.5mA
1.956V    -44.42mA   -46.36mA   -44.02mA
2.2V      -52.46mA   -51.75mA   -53.91mA
[POWER Clamp]
|   Voltage   I(typ)   I(min)   I(max)
-1.1V     3.036mA    3.636mA    2.186mA
-1.041V   2.347mA    2.931mA    1.626mA
-981.2mV  1.754mA    2.277mA    1.183mA
-908.6mV  1.178mA    1.583mA    748.1uA
-852.5mV  818.6uA    1.149mA    543.7uA
-776.6mV  434.4uA    683.5uA    390.2uA
-710.6mV  232.3uA    359.2uA    273.1uA
-657.8mV  146.8uA    178.8uA    190.7uA
-595.1mV  80.77uA    68.29uA    109.3uA
-486.2mV  16.8uA     10.16uA    20.93uA
-360.8mV  1.033uA    770.7nA    794.6nA
2.2V      0A         0A         0A
[Ramp]
|   typ   min   max
| 20% - 80%
dV/dt_r   221.34m/36.12p   213.73m/39.80p   235.47m/32.99p
dV/dt_f   161.75m/63.65p   146.59m/74.17p   188.65m/53.86p
| 25% - 75%
|dV/dt_r   184.45m/28.77p   178.10m/31.74p   196.22m/26.25p
|dV/dt_f   134.79m/50.61p   122.16m/58.94p   157.20m/42.78p
R_load = 50
[Rising Waveform]
R_fixture = 50
V_fixture = 0.0
|   Time   V(typ)   V(min)   V(max)
0s        978.9uV    810.8uV    715.4uV
56ps      1.041mV    60.68uV    8.522mV
65ps      4.585mV    -47.03uV   44.42mV
75ps      15.35mV    2.381mV    125.3mV
85ps      59.99mV    7.972mV    211.4mV
100ps     170.8mV    33mV       303mV
129ps     313.7mV    203.1mV    374.4mV
153ps     353.5mV    300.5mV    388.8mV
183ps     367mV      344.1mV    392.5mV
372ps     369.9mV    357mV      393.2mV
[Falling Waveform]
R_fixture   = 50
V_fixture   = 1.1
V_fixture_min = 1.06
V_fixture_max = 1.17
|   Time   V(typ)   V(min)   V(max)
0s        1.1V       1.06V      1.17V
69ps      1.099V     1.061V     1.163V
77ps      1.096V     1.06V      1.141V
93ps      1.084V     1.054V     1.067V
120ps     1.001V     1.035V     961.4mV
138ps     947.2mV    995.4mV    919.2mV
165ps     892.1mV    929.5mV    884.5mV
199ps     856.6mV    872.4mV    866.1mV
237ps     840.1mV    839.7mV    858.9mV
372ps     830.4mV    815.7mV    855.6mV
[Rising Waveform]
R_fixture   = 50
V_fixture   = 1.1
V_fixture_min = 1.06
V_fixture_max = 1.17
|   Time   V(typ)   V(min)   V(max)
0s        830.1mV    814.5mV    855.5mV
50ps      826.7mV    812.6mV    858.8mV
60ps      830.7mV    809.5mV    886.5mV
74ps      867.6mV    815.5mV    966.4mV
88ps      932.5mV    851.6mV    1.029V
105ps     990.7mV    920mV      1.078V
122ps     1.028V     968.7mV    1.11V
144ps     1.057V     1.006V     1.136V
210ps     1.091V     1.048V     1.163V
372ps     1.1V       1.059V     1.17V
[Falling Waveform]
R_fixture = 50
V_fixture = 0.0
|   Time   V(typ)   V(min)   V(max)
0s        370mV      357.1mV    393.3mV
56ps      375.7mV    360.4mV    393.3mV
72ps      368.6mV    371.6mV    318.3mV
86ps      302.2mV    361.8mV    193.4mV
98ps      216.6mV    313mV      125.2mV
115ps     123.3mV    212.9mV    68.65mV
138ps     57.79mV    107.3mV    30.78mV
166ps     23.49mV    44.91mV    11.9mV
200ps     8.375mV    16.15mV    4.101mV
372ps     1.048mV    968.4uV    736.9uV
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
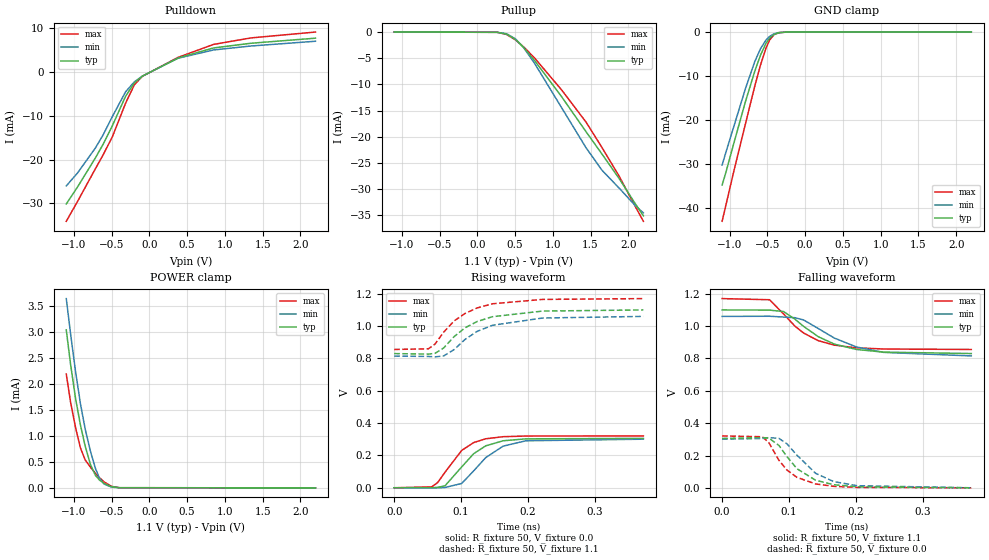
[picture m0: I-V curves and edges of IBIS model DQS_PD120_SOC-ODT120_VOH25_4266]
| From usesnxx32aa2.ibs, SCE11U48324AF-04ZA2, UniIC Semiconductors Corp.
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| DQS_PD120_SOC-ODT120_VOH25_4266
| (120 Ohm Pulldown, 120 Ohm System ODT Setting, VOH=VDDQ/2.5, 3200-4266Mbps)
[Model]   DQS_PD120_SOC-ODT120_VOH25_4266
Model_type   I/O
Vinl = 160.000mV
Vinh = 280.000mV
Vmeas = 220.000mV
Vref = 0.0mV
Cref = 0.0pF
Rref = 120.000Ohm
|   typ   min   max
|C_comp   0.838pF   0.788pF   0.888pF
C_comp_pullup   0.4190pF   0.3940pF   0.4440pF
C_comp_pulldown   0.4190pF   0.3940pF   0.4440pF
| Note: C_comp changes when the ODT circuit is enabled.
[Model Spec]
| Input threshold voltage corners
Vinl   0.1600V   0.1520V   0.1740V
Vinh   0.2800V   0.2720V   0.2940V
| Measurement voltage corners
Vmeas   0.2200V   0.2120V   0.2340V
| Timing spec test load voltage corners
Vref   0.0000V   0.0000V   0.0000V
| Dynamic Overshoot Parameters from LPDDR4 Specification
D_overshoot_ampl_h   0.30   NA   NA
D_overshoot_ampl_l   0.30   NA   NA
D_overshoot_area_h   0.1n   NA   NA
D_overshoot_area_l   0.1n   NA   NA
[Receiver Thresholds]
Vcross_low   = 160.0mV
Vcross_high  = 280.0mV
Vdiff_ac   = 120mV
Vdiff_dc   = 120mV
Tdiffslew_ac = 10.000ns |Not specified, so set to high value
[Voltage Range]   1.1000V   1.0600V   1.1700V
[Pullup Reference]   1.1000V   1.0600V   1.1700V
| Junction Temperature (Ambient temp is 35C typ 95C min -40C max)
[Temperature Range]   50.0   110.0   -40.0
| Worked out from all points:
|   slope of the pulldown table from 0 to 0.165 V, typ, clamps not added: 109 ohm
|   slope of the pullup table from 0 to 0.165 V, typ, clamps not added: 26.3 kohm
|   GND clamp passes 1 mA (typ) near -0.45 V on its own axis
|   POWER clamp passes 1 mA (typ) near -0.88 V on its own axis
|   rising waveform, R_fixture 50, V_fixture 0.0: 20-80 % time 41.4ps typ, 44.8ps min, 37.9ps max; typ from 0.001 V to 0.306 V
|   falling waveform, R_fixture 50, V_fixture 1.1: 20-80 % time 62.9ps typ, 73ps min, 53.6ps max; typ from 1.1 V to 0.83 V
|   rising waveform, R_fixture 50, V_fixture 1.1: 20-80 % time 57.5ps typ, 59.8ps min, 54.4ps max; typ from 0.83 V to 1.1 V
|   falling waveform, R_fixture 50, V_fixture 0.0: 20-80 % time 43.5ps typ, 48.7ps min, 38.8ps max; typ from 0.306 V to 0.001 V
[Pulldown]
|   Voltage   I(typ)   I(min)   I(max)
-1.1V     -30.11mA   -26mA      -34.06mA
-951.5mV  -26.26mA   -23.06mA   -29.56mA
-717.2mV  -19.7mA    -17.43mA   -22.17mA
-611.6mV  -16.49mA   -14.35mA   -18.91mA
-489.5mV  -12.27mA   -10.18mA   -14.79mA
-314.6mV  -5.562mA   -4.543mA   -7.142mA
-199.1mV  -2.525mA   -2.284mA   -2.976mA
-93.5mV   -1.001mA   -972.5uA   -1.012mA
381.7mV   3.184mA    3.109mA    3.311mA
850.3mV   5.453mA    4.993mA    6.257mA
1.345V    6.52mA     5.892mA    7.737mA
2.2V      7.677mA    6.979mA    9.076mA
[GND Clamp]
|   Voltage   I(typ)   I(min)   I(max)
-1.1V     -34.88mA   -30.33mA   -43.14mA
-1.05V    -32mA      -27.43mA   -39.48mA
-948.2mV  -25.55mA   -21.71mA   -31.96mA
-789.8mV  -15.79mA   -12.83mA   -20.84mA
-667.7mV  -8.943mA   -6.74mA    -12.35mA
-591.8mV  -5.273mA   -3.797mA   -7.531mA
-519.2mV  -2.57mA    -1.834mA   -3.675mA
-469.7mV  -1.364mA   -988uA     -1.791mA
-413.6mV  -565.9uA   -417.4uA   -619.8uA
-350.9mV  -166.1uA   -126.2uA   -147.5uA
-248.6mV  -12.38uA   -10.9uA    -7.11uA
2.2V      0A         0A         0A
[Pullup]
|   Voltage   I(typ)   I(min)   I(max)
-1.1V     2.741uA    4.961uA    908.6nA
262.9mV   -43.11uA   -42.51uA   -44.35uA
388.3mV   -384.2uA   -319uA     -459.6uA
507.1mV   -1.445mA   -1.305mA   -1.506mA
616mV     -2.987mA   -3.007mA   -2.855mA
757.9mV   -5.42mA    -5.953mA   -4.933mA
1.118V    -12.38mA   -14.48mA   -11.08mA
1.441V    -19.06mA   -22.13mA   -17.22mA
1.652V    -23.33mA   -26.42mA   -22.08mA
1.877V    -27.97mA   -29.81mA   -27.5mA
2.094V    -32.85mA   -33.2mA    -33.38mA
2.2V      -35.14mA   -34.58mA   -36.18mA
[POWER Clamp]
|   Voltage   I(typ)   I(min)   I(max)
-1.1V     3.036mA    3.636mA    2.186mA
-1.044V   2.383mA    2.969mA    1.654mA
-977.9mV  1.724mA    2.242mA    1.161mA
-911.9mV  1.201mA    1.611mA    764.5uA
-849.2mV  799.3uA    1.126mA    535.6uA
-779.9mV  447.9uA    701.9uA    396.3uA
-713.9mV  239.2uA    373.1uA    278.6uA
-661.1mV  151.1uA    187.5uA    195.5uA
-598.4mV  83.64uA    71.96uA    113.1uA
-502.7mV  22.68uA    14.02uA    29.27uA
-400.4mV  2.576uA    1.697uA    2.316uA
2.2V      0A         0A         0A
[Ramp]
|   typ   min   max
| 20% - 80%
dV/dt_r   183.10m/41.38p   180.21m/44.83p   192.40m/37.90p
dV/dt_f   161.71m/63.00p   146.60m/72.93p   188.63m/53.54p
| 25% - 75%
|dV/dt_r   152.58m/32.98p   150.18m/35.72p   160.33m/30.10p
|dV/dt_f   134.76m/50.06p   122.16m/58.01p   157.20m/42.55p
R_load = 50
[Rising Waveform]
R_fixture = 50
V_fixture = 0.0
|   Time   V(typ)   V(min)   V(max)
0s        651.8uV    535.7uV    476.8uV
56ps      778.4uV    69.15uV    6.091mV
65ps      3.003mV    54.49uV    32.17mV
76ps      12.38mV    2.043mV    96.3mV
101ps     129.2mV    26.96mV    231.3mV
119ps     211.2mV    105.1mV    280mV
137ps     259.6mV    186.9mV    303.3mV
163ps     291mV      257.7mV    316.2mV
197ps     302.9mV    291mV      320.3mV
373ps     305.8mV    300.9mV    321.1mV
[Falling Waveform]
R_fixture   = 50
V_fixture   = 1.1
V_fixture_min = 1.06
V_fixture_max = 1.17
|   Time   V(typ)   V(min)   V(max)
0s        1.1V       1.06V      1.17V
71ps      1.099V     1.061V     1.163V
92ps      1.09V      1.056V     1.075V
109ps     1.043V     1.052V     1V
122ps     998.3mV    1.038V     957.3mV
144ps     934.5mV    984.9mV    909.9mV
168ps     888.8mV    926.1mV    882.5mV
201ps     855.7mV    871.3mV    865.7mV
242ps     839.1mV    837.6mV    858.5mV
373ps     830.5mV    815.7mV    855.6mV
[Rising Waveform]
R_fixture   = 50
V_fixture   = 1.1
V_fixture_min = 1.06
V_fixture_max = 1.17
|   Time   V(typ)   V(min)   V(max)
0s        830.1mV    814.5mV    855.5mV
51ps      826.8mV    812.4mV    859.5mV
61ps      831.6mV    809.7mV    888mV
74ps      864.6mV    815.3mV    962.3mV
90ps      936.2mV    855.8mV    1.033V
106ps     989.3mV    917.6mV    1.078V
124ps     1.028V     967.1mV    1.112V
147ps     1.058V     1.005V     1.138V
222ps     1.093V     1.05V      1.165V
373ps     1.1V       1.06V      1.17V
[Falling Waveform]
R_fixture = 50
V_fixture = 0.0
|   Time   V(typ)   V(min)   V(max)
0s        305.9mV    301mV      321.2mV
60ps      311.2mV    305.5mV    316.4mV
70ps      307.9mV    310.9mV    279.8mV
85ps      262.7mV    306.4mV    170.8mV
97ps      193.7mV    272.8mV    110.6mV
112ps     118.7mV    202.3mV    65.13mV
140ps     47.29mV    90.22mV    24.57mV
167ps     19.84mV    39.25mV    9.858mV
202ps     6.798mV    13.71mV    3.279mV
373ps     752.8uV    714.3uV    511.4uV
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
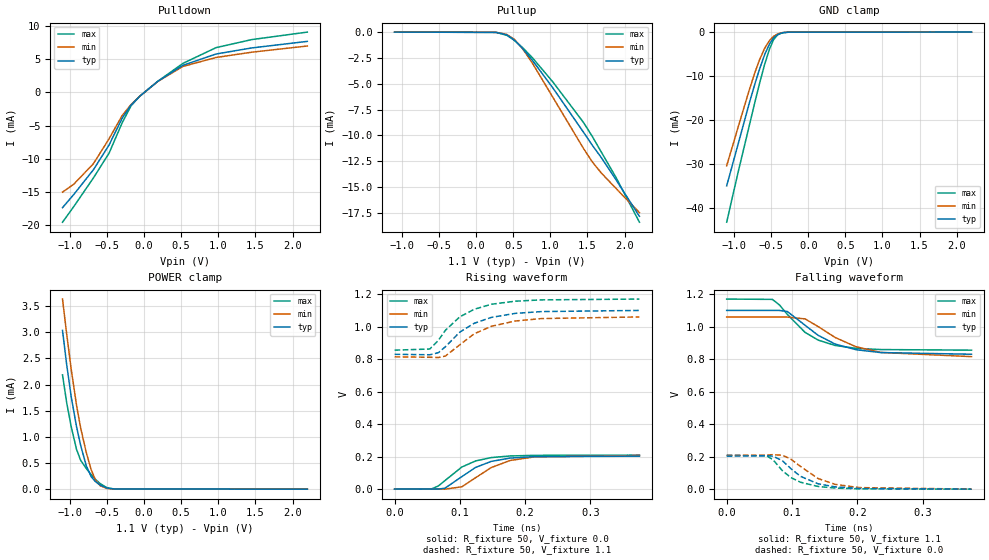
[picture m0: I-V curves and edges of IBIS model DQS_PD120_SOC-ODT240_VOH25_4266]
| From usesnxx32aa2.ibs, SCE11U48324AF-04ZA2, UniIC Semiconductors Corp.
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| DQS_PD120_SOC-ODT240_VOH25_4266
| (120 Ohm Pulldown, 240 Ohm System ODT Setting, VOH=VDDQ/2.5, 3200-4266Mbps)
[Model]   DQS_PD120_SOC-ODT240_VOH25_4266
Model_type   I/O
Vinl = 160.000mV
Vinh = 280.000mV
Vmeas = 220.000mV
Vref = 0.0mV
Cref = 0.0pF
Rref = 240.000Ohm
|   typ   min   max
|C_comp   0.838pF   0.788pF   0.888pF
C_comp_pullup   0.4190pF   0.3940pF   0.4440pF
C_comp_pulldown   0.4190pF   0.3940pF   0.4440pF
| Note: C_comp changes when the ODT circuit is enabled.
[Model Spec]
| Input threshold voltage corners
Vinl   0.1600V   0.1520V   0.1740V
Vinh   0.2800V   0.2720V   0.2940V
| Measurement voltage corners
Vmeas   0.2200V   0.2120V   0.2340V
| Timing spec test load voltage corners
Vref   0.0000V   0.0000V   0.0000V
| Dynamic Overshoot Parameters from LPDDR4 Specification
D_overshoot_ampl_h   0.30   NA   NA
D_overshoot_ampl_l   0.30   NA   NA
D_overshoot_area_h   0.1n   NA   NA
D_overshoot_area_l   0.1n   NA   NA
[Receiver Thresholds]
Vcross_low   = 160.0mV
Vcross_high  = 280.0mV
Vdiff_ac   = 120mV
Vdiff_dc   = 120mV
Tdiffslew_ac = 10.000ns |Not specified, so set to high value
[Voltage Range]   1.1000V   1.0600V   1.1700V
[Pullup Reference]   1.1000V   1.0600V   1.1700V
| Junction Temperature (Ambient temp is 35C typ 95C min -40C max)
[Temperature Range]   50.0   110.0   -40.0
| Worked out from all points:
|   slope of the pulldown table from 0 to 0.165 V, typ, clamps not added: 110 ohm
|   slope of the pullup table from 0 to 0.165 V, typ, clamps not added: 53.3 kohm
|   GND clamp passes 1 mA (typ) near -0.45 V on its own axis
|   POWER clamp passes 1 mA (typ) near -0.88 V on its own axis
|   rising waveform, R_fixture 50, V_fixture 0.0: 20-80 % time 49ps typ, 53.2ps min, 45.4ps max; typ from 0 V to 0.203 V
|   falling waveform, R_fixture 50, V_fixture 1.1: 20-80 % time 62.4ps typ, 71.9ps min, 53.2ps max; typ from 1.1 V to 0.83 V
|   rising waveform, R_fixture 50, V_fixture 1.1: 20-80 % time 58.5ps typ, 61.6ps min, 54.6ps max; typ from 0.83 V to 1.1 V
|   falling waveform, R_fixture 50, V_fixture 0.0: 20-80 % time 44.2ps typ, 50.1ps min, 39.4ps max; typ from 0.203 V to 0 V
[Pulldown]
|   Voltage   I(typ)   I(min)   I(max)
-1.1V     -17.37mA   -15.03mA   -19.56mA
-951.5mV  -15.43mA   -13.87mA   -17.26mA
-684.2mV  -11.67mA   -10.76mA   -12.9mA
-473mV    -7.935mA   -7.001mA   -9.171mA
-294.8mV  -3.872mA   -3.471mA   -4.556mA
-176mV    -1.902mA   -1.833mA   -2.028mA
-57.2mV   -573.4uA   -568.2uA   -564.8uA
183.7mV   1.653mA    1.637mA    1.664mA
523.6mV   4.075mA    3.906mA    4.365mA
969.1mV   5.773mA    5.25mA     6.731mA
1.448V    6.686mA    6.043mA    7.941mA
2.2V      7.677mA    6.979mA    9.076mA
[GND Clamp]
|   Voltage   I(typ)   I(min)   I(max)
-1.1V     -34.89mA   -30.33mA   -43.14mA
-948.2mV  -25.55mA   -21.71mA   -31.96mA
-796.4mV  -16.18mA   -13.19mA   -21.3mA
-720.5mV  -11.8mA    -9.215mA   -15.96mA
-661.1mV  -8.6mA     -6.453mA   -11.91mA
-588.5mV  -5.13mA    -3.689mA   -7.335mA
-522.5mV  -2.671mA   -1.906mA   -3.827mA
-469.7mV  -1.359mA   -987.4uA   -1.792mA
-413.6mV  -564uA     -418.3uA   -622.3uA
-350.9mV  -166.4uA   -126.2uA   -147.6uA
-261.8mV  -17.75uA   -15.44uA   -11.06uA
2.2V      0A         0A         0A
[Pullup]
|   Voltage   I(typ)   I(min)   I(max)
-1.1V     1.371uA    2.481uA    454.5nA
269.5mV   -24.65uA   -23.81uA   -25.87uA
411.4mV   -264.6uA   -220.2uA   -309.3uA
513.7mV   -768.1uA   -699.5uA   -794.3uA
625.9mV   -1.587mA   -1.614mA   -1.506mA
757.9mV   -2.738mA   -3.016mA   -2.487mA
1.032V    -5.393mA   -6.298mA   -4.813mA
1.448V    -9.715mA   -11.29mA   -8.771mA
1.566V    -10.97mA   -12.58mA   -10.12mA
1.688V    -12.17mA   -13.66mA   -11.64mA
1.887V    -14.33mA   -15.16mA   -14.11mA
2.2V      -17.84mA   -17.48mA   -18.41mA
[POWER Clamp]
|   Voltage   I(typ)   I(min)   I(max)
-1.1V     3.036mA    3.636mA    2.186mA
-1.044V   2.383mA    2.969mA    1.654mA
-981.2mV  1.754mA    2.277mA    1.183mA
-911.9mV  1.201mA    1.612mA    764.8uA
-855.8mV  838.1uA    1.172mA    552.2uA
-779.9mV  448.2uA    701.7uA    396.3uA
-713.9mV  239.3uA    373.1uA    278.6uA
-654.5mV  142.7uA    170.4uA    185.9uA
-591.8mV  77.91uA    64.89uA    105.5uA
-499.4mV  21.27uA    13.16uA    27.44uA
-397.1mV  2.388uA    1.591uA    2.114uA
2.2V      0A         0A         0A
[Ramp]
|   typ   min   max
| 20% - 80%
dV/dt_r   121.75m/49.05p   124.09m/53.16p   125.54m/45.36p
dV/dt_f   161.73m/62.46p   146.59m/71.79p   188.63m/53.19p
| 25% - 75%
|dV/dt_r   101.46m/39.03p   103.41m/42.39p   104.62m/36.01p
|dV/dt_f   134.78m/49.65p   122.16m/57.13p   157.20m/42.25p
R_load = 50
[Rising Waveform]
R_fixture = 50
V_fixture = 0.0
|   Time   V(typ)   V(min)   V(max)
0s        320.5uV    256.5uV    236.1uV
57ps      236.6uV    171.6uV    2.479mV
67ps      717.1uV    -51.3uV    19.45mV
77ps      5.704mV    251.5uV    52.46mV
103ps     77.06mV    14.4mV     136.3mV
124ps     133.7mV    70.29mV    173.7mV
148ps     170.9mV    133mV      194.3mV
177ps     191.3mV    176.6mV    204.3mV
214ps     200.1mV    198.5mV    208.1mV
375ps     203.2mV    207.1mV    209.5mV
[Falling Waveform]
R_fixture   = 50
V_fixture   = 1.1
V_fixture_min = 1.06
V_fixture_max = 1.17
|   Time   V(typ)   V(min)   V(max)
0s        1.1V       1.06V      1.17V
70ps      1.1V       1.06V      1.168V
81ps      1.1V       1.06V      1.133V
93ps      1.093V     1.059V     1.075V
120ps     1.009V     1.048V     965.2mV
140ps     947.1mV    1.001V     917.7mV
166ps     893.2mV    933.9mV    884.6mV
198ps     858.3mV    876.8mV    866.9mV
236ps     840.8mV    841.6mV    859.3mV
375ps     830.4mV    815.7mV    855.6mV
[Rising Waveform]
R_fixture   = 50
V_fixture   = 1.1
V_fixture_min = 1.06
V_fixture_max = 1.17
|   Time   V(typ)   V(min)   V(max)
0s        830.1mV    814.4mV    855.5mV
54ps      827.1mV    811.8mV    862.5mV
67ps      839.8mV    810.1mV    915.9mV
78ps      877.3mV    819.7mV    978.6mV
100ps     967.2mV    889.1mV    1.061V
122ps     1.021V     956.5mV    1.107V
148ps     1.057V     1.002V     1.138V
185ps     1.082V     1.035V     1.157V
225ps     1.093V     1.05V      1.165V
375ps     1.1V       1.06V      1.17V
[Falling Waveform]
R_fixture = 50
V_fixture = 0.0
|   Time   V(typ)   V(min)   V(max)
0s        203.3mV    207.2mV    209.5mV
61ps      206mV      209.8mV    205.3mV
71ps      203.1mV    212.7mV    181.5mV
85ps      176.4mV    209.2mV    115.1mV
98ps      127.9mV    185.9mV    72.46mV
113ps     79.23mV    140.2mV    42.94mV
140ps     33.08mV    65.79mV    16.83mV
166ps     14.43mV    29.92mV    6.957mV
203ps     4.614mV    9.886mV    2.157mV
375ps     415.8uV    424.1uV    267uV
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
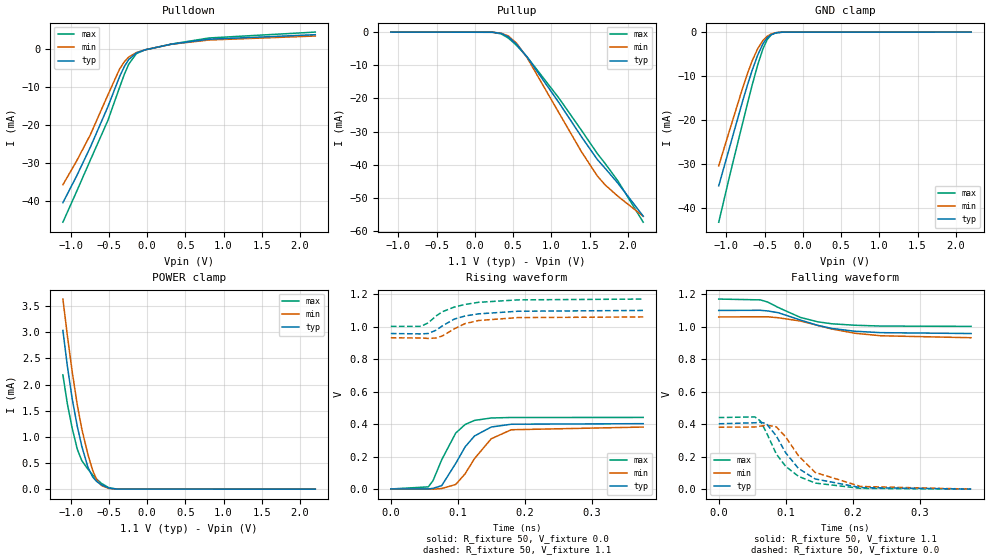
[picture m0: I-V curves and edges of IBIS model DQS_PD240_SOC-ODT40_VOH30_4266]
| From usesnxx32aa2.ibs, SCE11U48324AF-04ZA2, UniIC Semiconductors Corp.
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| DQS_PD240_SOC-ODT40_VOH30_4266
| (240 Ohm Pulldown, 40 Ohm System ODT Setting, VOH=VDDQ/3.0, 3200-4266Mbps)
[Model]   DQS_PD240_SOC-ODT40_VOH30_4266
Model_type   I/O
Vinl = 123.333mV
Vinh = 243.333mV
Vmeas = 183.333mV
Vref = 0.0mV
Cref = 0.0pF
Rref = 40.000Ohm
|   typ   min   max
|C_comp   0.838pF   0.788pF   0.888pF
C_comp_pullup   0.4190pF   0.3940pF   0.4440pF
C_comp_pulldown   0.4190pF   0.3940pF   0.4440pF
| Note: C_comp changes when the ODT circuit is enabled.
[Model Spec]
| Input threshold voltage corners
Vinl   0.1233V   0.1167V   0.1350V
Vinh   0.2433V   0.2367V   0.2550V
| Measurement voltage corners
Vmeas   0.1833V   0.1767V   0.1950V
| Timing spec test load voltage corners
Vref   0.0000V   0.0000V   0.0000V
| Dynamic Overshoot Parameters from LPDDR4 Specification
D_overshoot_ampl_h   0.30   NA   NA
D_overshoot_ampl_l   0.30   NA   NA
D_overshoot_area_h   0.1n   NA   NA
D_overshoot_area_l   0.1n   NA   NA
[Receiver Thresholds]
Vcross_low   = 123.3mV
Vcross_high  = 243.3mV
Vdiff_ac   = 120mV
Vdiff_dc   = 120mV
Tdiffslew_ac = 10.000ns |Not specified, so set to high value
[Voltage Range]   1.1000V   1.0600V   1.1700V
[Pullup Reference]   1.1000V   1.0600V   1.1700V
| Junction Temperature (Ambient temp is 35C typ 95C min -40C max)
[Temperature Range]   50.0   110.0   -40.0
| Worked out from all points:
|   slope of the pulldown table from 0 to 0.165 V, typ, clamps not added: 220 ohm
|   slope of the pullup table from 0 to 0.165 V, typ, clamps not added: 12.9 kohm
|   GND clamp passes 1 mA (typ) near -0.45 V on its own axis
|   POWER clamp passes 1 mA (typ) near -0.88 V on its own axis
|   rising waveform, R_fixture 50, V_fixture 0.0: 20-80 % time 36.4ps typ, 40.6ps min, 31.5ps max; typ from 0.001 V to 0.403 V
|   falling waveform, R_fixture 50, V_fixture 1.1: 20-80 % time 72.2ps typ, 84.8ps min, 61.1ps max; typ from 1.1 V to 0.958 V
|   rising waveform, R_fixture 50, V_fixture 1.1: 20-80 % time 47.9ps typ, 41.9ps min, 51ps max; typ from 0.958 V to 1.1 V
|   falling waveform, R_fixture 50, V_fixture 0.0: 20-80 % time 48.3ps typ, 52.1ps min, 44.7ps max; typ from 0.403 V to 0.001 V
[Pulldown]
|   Voltage   I(typ)   I(min)   I(max)
-1.1V     -40.35mA   -35.64mA   -45.48mA
-921.8mV  -33.39mA   -29.43mA   -37.46mA
-740.3mV  -25.71mA   -22.46mA   -29.11mA
-512.6mV  -15.16mA   -12.05mA   -18.76mA
-357.5mV  -7.13mA    -5.156mA   -9.962mA
-294.8mV  -4.474mA   -3.23mA    -6.501mA
-238.7mV  -2.706mA   -2.052mA   -3.915mA
-139.7mV  -997.4uA   -882.1uA   -1.173mA
-27.5mV   -174uA     -166.7uA   -164.7uA
322.3mV   1.34mA     1.32mA     1.366mA
807.4mV   2.622mA    2.422mA    2.952mA
2.2V      3.818mA    3.475mA    4.505mA
[GND Clamp]
|   Voltage   I(typ)   I(min)   I(max)
-1.1V     -34.88mA   -30.34mA   -43.13mA
-941.6mV  -25.13mA   -21.34mA   -31.48mA
-789.8mV  -15.79mA   -12.83mA   -20.82mA
-723.8mV  -11.98mA   -9.382mA   -16.18mA
-664.4mV  -8.768mA   -6.598mA   -12.12mA
-591.8mV  -5.271mA   -3.798mA   -7.524mA
-522.5mV  -2.671mA   -1.905mA   -3.823mA
-466.4mV  -1.297mA   -944.8uA   -1.693mA
-413.6mV  -564.2uA   -418.2uA   -620.5uA
-350.9mV  -166.6uA   -126.5uA   -146.9uA
-261.8mV  -17.7uA    -15.59uA   -11.06uA
2.2V      0A         0A         0A
[Pullup]
|   Voltage   I(typ)   I(min)   I(max)
-1.1V     6.284uA    9.684uA    2.832uA
229.9mV   -45.48uA   -45.76uA   -46.62uA
342.1mV   -382.7uA   -314.6uA   -525.1uA
437.8mV   -1.437mA   -1.179mA   -1.809mA
543.4mV   -3.636mA   -3.317mA   -3.984mA
682mV     -7.523mA   -7.707mA   -7.474mA
1.098V    -21.25mA   -24.32mA   -19.89mA
1.395V    -31.61mA   -36.14mA   -29.67mA
1.599V    -38.35mA   -43.31mA   -36.57mA
1.702V    -41.04mA   -46.04mA   -39.59mA
1.87V     -45.56mA   -49.48mA   -44.88mA
2.2V      -55.46mA   -55.5mA    -57.28mA
[POWER Clamp]
|   Voltage   I(typ)   I(min)   I(max)
-1.1V     3.036mA    3.636mA    2.186mA
-1.041V   2.347mA    2.931mA    1.626mA
-977.9mV  1.724mA    2.242mA    1.161mA
-911.9mV  1.201mA    1.611mA    764.7uA
-852.5mV  818.7uA    1.149mA    543.9uA
-773.3mV  420.8uA    665.7uA    384.1uA
-710.6mV  232.4uA    359.1uA    273.1uA
-657.8mV  146.8uA    178.8uA    190.7uA
-598.4mV  83.67uA    71.97uA    113.1uA
-499.4mV  21.3uA     13.14uA    27.45uA
-393.8mV  2.203uA    1.484uA    1.931uA
2.2V      0A         0A         0A
[Ramp]
|   typ   min   max
| 20% - 80%
dV/dt_r   241.03m/36.40p   228.61m/40.57p   264.21m/31.47p
dV/dt_f   85.18m/72.42p   76.67m/84.47p   100.85m/61.39p
| 25% - 75%
|dV/dt_r   200.86m/28.98p   190.50m/32.27p   220.18m/25.03p
|dV/dt_f   70.98m/57.60p   63.89m/66.49p   84.04m/48.91p
R_load = 50
[Rising Waveform]
R_fixture = 50
V_fixture = 0.0
|   Time   V(typ)   V(min)   V(max)
0s        1.138mV    1.014mV    820.3uV
56ps      937.4uV    -134.2uV   13.72mV
63ps      4.433mV    -419.1uV   51.49mV
76ps      21.33mV    3.524mV    180.5mV
97ps      158.5mV    28.64mV    345.4mV
111ps     260mV      94.34mV    397.7mV
125ps     327.2mV    187.9mV    422.9mV
150ps     382.2mV    310mV      437.9mV
180ps     399.4mV    365.4mV    440.9mV
377ps     402.9mV    382mV      441.2mV
[Falling Waveform]
R_fixture   = 50
V_fixture   = 1.1
V_fixture_min = 1.06
V_fixture_max = 1.17
|   Time   V(typ)   V(min)   V(max)
0s        1.1V       1.06V      1.17V
62ps      1.101V     1.061V     1.165V
73ps      1.097V     1.061V     1.152V
89ps      1.086V     1.055V     1.118V
122ps     1.041V     1.035V     1.057V
148ps     1.008V     1.008V     1.03V
169ps     989.4mV    985.8mV    1.018V
203ps     972.2mV    960mV      1.009V
242ps     963.4mV    944.3mV    1.004V
377ps     958mV      932.2mV    1.002V
[Rising Waveform]
R_fixture   = 50
V_fixture   = 1.1
V_fixture_min = 1.06
V_fixture_max = 1.17
|   Time   V(typ)   V(min)   V(max)
0s        957.9mV    931.6mV    1.002V
45ps      955.5mV    930.2mV    1.002V
56ps      958mV      927.7mV    1.024V
68ps      979.2mV    930.5mV    1.067V
77ps      1.005V     942.9mV    1.092V
95ps      1.047V     987.2mV    1.121V
111ps     1.066V     1.019V     1.137V
131ps     1.079V     1.038V     1.15V
190ps     1.095V     1.056V     1.165V
377ps     1.1V       1.06V      1.17V
[Falling Waveform]
R_fixture = 50
V_fixture = 0.0
|   Time   V(typ)   V(min)   V(max)
0s        403mV      382.2mV    441.3mV
54ps      409mV      383mV      445.2mV
62ps      413mV      388.3mV    421mV
71ps      404.7mV    394.7mV    351.3mV
86ps      328.4mV    384.3mV    217.2mV
100ps     224.5mV    322.1mV    141.1mV
119ps     128.6mV    206.8mV    80.1mV
144ps     63.7mV     104mV      38.42mV
212ps     10.48mV    17.4mV     5.772mV
377ps     1.284mV    1.287mV    873.3uV
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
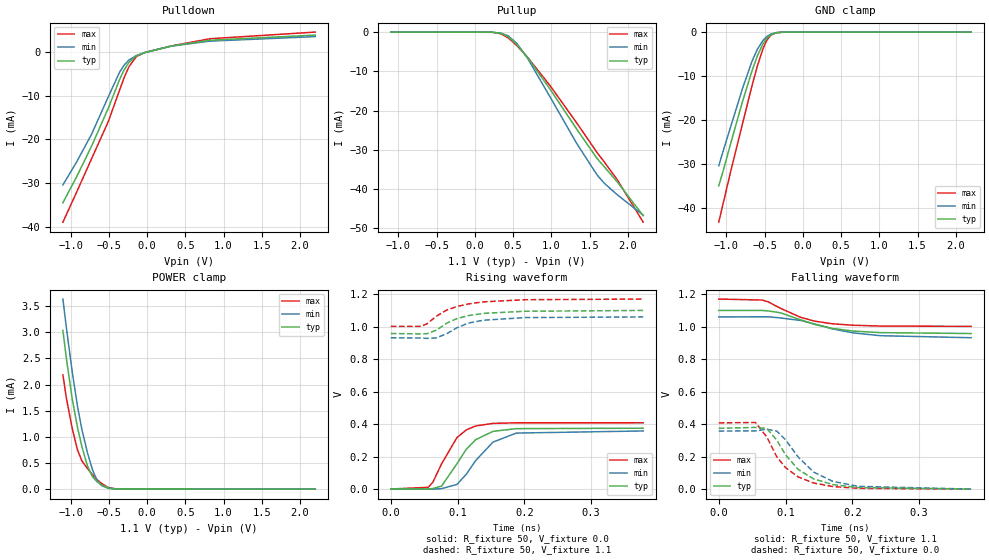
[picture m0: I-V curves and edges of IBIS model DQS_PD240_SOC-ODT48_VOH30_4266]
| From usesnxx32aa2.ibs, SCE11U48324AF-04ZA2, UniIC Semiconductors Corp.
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| DQS_PD240_SOC-ODT48_VOH30_4266
| (240 Ohm Pulldown, 48 Ohm System ODT Setting, VOH=VDDQ/3.0, 3200-4266Mbps)
[Model]   DQS_PD240_SOC-ODT48_VOH30_4266
Model_type   I/O
Vinl = 123.333mV
Vinh = 243.333mV
Vmeas = 183.333mV
Vref = 0.0mV
Cref = 0.0pF
Rref = 48.000Ohm
|   typ   min   max
|C_comp   0.838pF   0.788pF   0.888pF
C_comp_pullup   0.4190pF   0.3940pF   0.4440pF
C_comp_pulldown   0.4190pF   0.3940pF   0.4440pF
| Note: C_comp changes when the ODT circuit is enabled.
[Model Spec]
| Input threshold voltage corners
Vinl   0.1233V   0.1167V   0.1350V
Vinh   0.2433V   0.2367V   0.2550V
| Measurement voltage corners
Vmeas   0.1833V   0.1767V   0.1950V
| Timing spec test load voltage corners
Vref   0.0000V   0.0000V   0.0000V
| Dynamic Overshoot Parameters from LPDDR4 Specification
D_overshoot_ampl_h   0.30   NA   NA
D_overshoot_ampl_l   0.30   NA   NA
D_overshoot_area_h   0.1n   NA   NA
D_overshoot_area_l   0.1n   NA   NA
[Receiver Thresholds]
Vcross_low   = 123.3mV
Vcross_high  = 243.3mV
Vdiff_ac   = 120mV
Vdiff_dc   = 120mV
Tdiffslew_ac = 10.000ns |Not specified, so set to high value
[Voltage Range]   1.1000V   1.0600V   1.1700V
[Pullup Reference]   1.1000V   1.0600V   1.1700V
| Junction Temperature (Ambient temp is 35C typ 95C min -40C max)
[Temperature Range]   50.0   110.0   -40.0
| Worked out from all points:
|   slope of the pulldown table from 0 to 0.165 V, typ, clamps not added: 221 ohm
|   slope of the pullup table from 0 to 0.165 V, typ, clamps not added: 15.5 kohm
|   GND clamp passes 1 mA (typ) near -0.45 V on its own axis
|   POWER clamp passes 1 mA (typ) near -0.88 V on its own axis
|   rising waveform, R_fixture 50, V_fixture 0.0: 20-80 % time 37.9ps typ, 42.6ps min, 33.3ps max; typ from 0.001 V to 0.375 V
|   falling waveform, R_fixture 50, V_fixture 1.1: 20-80 % time 71.3ps typ, 82.2ps min, 60.6ps max; typ from 1.1 V to 0.958 V
|   rising waveform, R_fixture 50, V_fixture 1.1: 20-80 % time 50.4ps typ, 45.3ps min, 52.5ps max; typ from 0.958 V to 1.1 V
|   falling waveform, R_fixture 50, V_fixture 0.0: 20-80 % time 48.7ps typ, 52.7ps min, 44.8ps max; typ from 0.375 V to 0.001 V
[Pulldown]
|   Voltage   I(typ)   I(min)   I(max)
-1.1V     -34.43mA   -30.37mA   -38.88mA
-918.5mV  -28.45mA   -25.08mA   -31.95mA
-723.8mV  -21.48mA   -18.76mA   -24.35mA
-506mV    -12.84mA   -10.24mA   -15.89mA
-357.5mV  -6.264mA   -4.601mA   -8.662mA
-298.1mV  -4.083mA   -3.007mA   -5.834mA
-238.7mV  -2.452mA   -1.899mA   -3.46mA
-139.7mV  -941.2uA   -844.2uA   -1.083mA
-27.5mV   -166.6uA   -159.8uA   -157.8uA
315.7mV   1.316mA    1.297mA    1.34mA
823.9mV   2.649mA    2.443mA    2.993mA
2.2V      3.818mA    3.475mA    4.505mA
[GND Clamp]
|   Voltage   I(typ)   I(min)   I(max)
-1.1V     -34.88mA   -30.34mA   -43.13mA
-1.047V   -31.79mA   -27.25mA   -39.23mA
-941.6mV  -25.13mA   -21.34mA   -31.48mA
-789.8mV  -15.79mA   -12.83mA   -20.82mA
-667.7mV  -8.939mA   -6.743mA   -12.34mA
-595.1mV  -5.415mA   -3.908mA   -7.72mA
-522.5mV  -2.671mA   -1.907mA   -3.824mA
-469.7mV  -1.36mA    -988uA     -1.791mA
-413.6mV  -565.2uA   -417.9uA   -621.4uA
-347.6mV  -154.8uA   -117.8uA   -135uA
-251.9mV  -13.35uA   -12.01uA   -7.85uA
2.2V      0A         0A         0A
[Pullup]
|   Voltage   I(typ)   I(min)   I(max)
-1.1V     5.237uA    8.07uA     2.361uA
226.6mV   -35.33uA   -36.24uA   -35.78uA
342.1mV   -317.8uA   -263.3uA   -438.5uA
437.8mV   -1.204mA   -986.9uA   -1.515mA
546.7mV   -3.119mA   -2.858mA   -3.404mA
685.3mV   -6.404mA   -6.586mA   -6.345mA
979mV     -14.46mA   -16.4mA    -13.56mA
1.335V    -24.84mA   -28.51mA   -23.26mA
1.596V    -32.18mA   -36.36mA   -30.67mA
1.688V    -34.25mA   -38.45mA   -33.01mA
1.86V     -38.15mA   -41.43mA   -37.6mA
2.2V      -46.77mA   -46.64mA   -48.43mA
[POWER Clamp]
|   Voltage   I(typ)   I(min)   I(max)
-1.1V     3.036mA    3.636mA    2.186mA
-1.054V   2.493mA    3.084mA    1.737mA
-977.9mV  1.724mA    2.242mA    1.161mA
-908.6mV  1.178mA    1.582mA    747.9uA
-852.5mV  818.9uA    1.148mA    543.8uA
-779.9mV  447.9uA    701.7uA    396.3uA
-713.9mV  239.2uA    373.2uA    278.6uA
-654.5mV  142.7uA    170.4uA    185.9uA
-595.1mV  80.75uA    68.3uA     109.2uA
-502.7mV  22.54uA    13.98uA    29.25uA
-397.1mV  2.384uA    1.595uA    2.115uA
2.2V      0A         0A         0A
[Ramp]
|   typ   min   max
| 20% - 80%
dV/dt_r   224.34m/37.93p   214.33m/42.55p   244.70m/33.25p
dV/dt_f   85.18m/71.31p   76.67m/81.91p   100.84m/60.80p
| 25% - 75%
|dV/dt_r   186.95m/30.22p   178.61m/33.88p   203.92m/26.50p
|dV/dt_f   70.98m/56.68p   63.89m/64.82p   84.03m/48.37p
R_load = 50
[Rising Waveform]
R_fixture = 50
V_fixture = 0.0
|   Time   V(typ)   V(min)   V(max)
0s        952.1uV    848.1uV    686.5uV
56ps      789.9uV    -106.3uV   10.98mV
63ps      3.694mV    -330.5uV   42.85mV
76ps      18.3mV     2.905mV    155.2mV
99ps      156.1mV    28.62mV    317mV
113ps     244.9mV    91.13mV    364.6mV
127ps     304.2mV    175.3mV    388.8mV
153ps     355.5mV    289.3mV    404.6mV
188ps     372.3mV    345mV      408.2mV
378ps     374.9mV    358.1mV    408.5mV
[Falling Waveform]
R_fixture   = 50
V_fixture   = 1.1
V_fixture_min = 1.06
V_fixture_max = 1.17
|   Time   V(typ)   V(min)   V(max)
0s        1.1V       1.06V      1.17V
65ps      1.1V       1.061V     1.164V
74ps      1.097V     1.061V     1.153V
92ps      1.086V     1.054V     1.114V
123ps     1.042V     1.038V     1.057V
144ps     1.014V     1.016V     1.034V
170ps     989.5mV    986.8mV    1.018V
201ps     973.2mV    962.2mV    1.009V
242ps     963.6mV    944.7mV    1.004V
378ps     958mV      932.2mV    1.002V
[Rising Waveform]
R_fixture   = 50
V_fixture   = 1.1
V_fixture_min = 1.06
V_fixture_max = 1.17
|   Time   V(typ)   V(min)   V(max)
0s        957.9mV    931.6mV    1.002V
45ps      955.7mV    930.2mV    1.002V
54ps      956.8mV    928.1mV    1.017V
68ps      978mV      930.7mV    1.064V
84ps      1.022V     957.3mV    1.103V
99ps      1.05V      993.6mV    1.124V
116ps     1.068V     1.022V     1.14V
139ps     1.082V     1.04V      1.153V
201ps     1.095V     1.056V     1.166V
378ps     1.1V       1.06V      1.17V
[Falling Waveform]
R_fixture = 50
V_fixture = 0.0
|   Time   V(typ)   V(min)   V(max)
0s        375mV      358.2mV    408.6mV
55ps      380.6mV    359.2mV    410.8mV
72ps      374.2mV    369.2mV    321.9mV
87ps      301.8mV    357.7mV    199.3mV
100ps     212.3mV    304.9mV    133.7mV
119ps     122mV      198.3mV    75.91mV
142ps     63.98mV    106.2mV    38.59mV
171ps     28.99mV    48.52mV    16.74mV
209ps     10.69mV    18.17mV    5.888mV
378ps     1.113mV    1.135mV    747.1uV
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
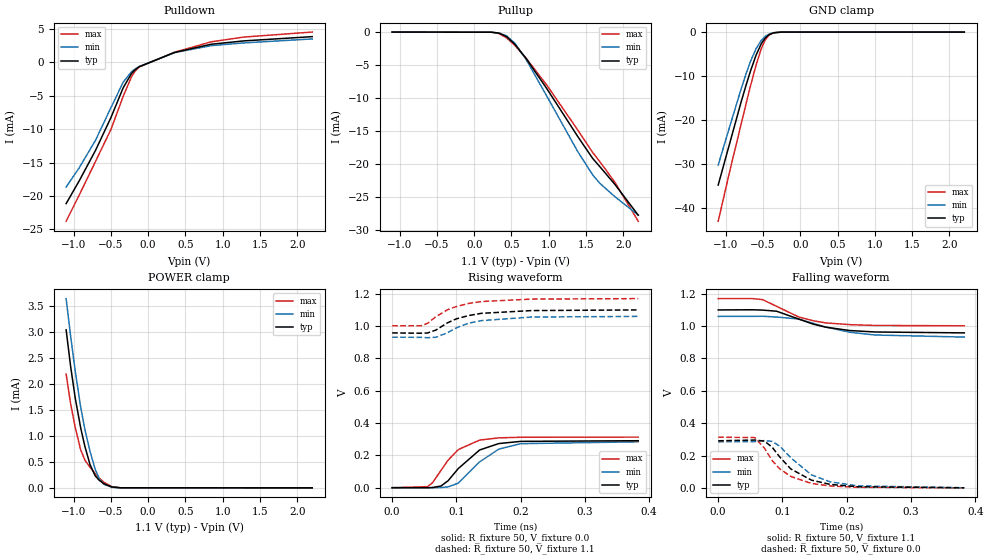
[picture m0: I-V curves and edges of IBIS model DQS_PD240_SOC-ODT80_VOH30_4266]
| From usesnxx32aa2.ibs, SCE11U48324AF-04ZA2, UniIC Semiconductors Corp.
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| DQS_PD240_SOC-ODT80_VOH30_4266
| (240 Ohm Pulldown, 80 Ohm System ODT Setting, VOH=VDDQ/3.0, 3200-4266Mbps)
[Model]   DQS_PD240_SOC-ODT80_VOH30_4266
Model_type   I/O
Vinl = 123.333mV
Vinh = 243.333mV
Vmeas = 183.333mV
Vref = 0.0mV
Cref = 0.0pF
Rref = 80.000Ohm
|   typ   min   max
|C_comp   0.838pF   0.788pF   0.888pF
C_comp_pullup   0.4190pF   0.3940pF   0.4440pF
C_comp_pulldown   0.4190pF   0.3940pF   0.4440pF
| Note: C_comp changes when the ODT circuit is enabled.
[Model Spec]
| Input threshold voltage corners
Vinl   0.1233V   0.1167V   0.1350V
Vinh   0.2433V   0.2367V   0.2550V
| Measurement voltage corners
Vmeas   0.1833V   0.1767V   0.1950V
| Timing spec test load voltage corners
Vref   0.0000V   0.0000V   0.0000V
| Dynamic Overshoot Parameters from LPDDR4 Specification
D_overshoot_ampl_h   0.30   NA   NA
D_overshoot_ampl_l   0.30   NA   NA
D_overshoot_area_h   0.1n   NA   NA
D_overshoot_area_l   0.1n   NA   NA
[Receiver Thresholds]
Vcross_low   = 123.3mV
Vcross_high  = 243.3mV
Vdiff_ac   = 120mV
Vdiff_dc   = 120mV
Tdiffslew_ac = 10.000ns |Not specified, so set to high value
[Voltage Range]   1.1000V   1.0600V   1.1700V
[Pullup Reference]   1.1000V   1.0600V   1.1700V
| Junction Temperature (Ambient temp is 35C typ 95C min -40C max)
[Temperature Range]   50.0   110.0   -40.0
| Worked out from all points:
|   slope of the pulldown table from 0 to 0.165 V, typ, clamps not added: 224 ohm
|   slope of the pullup table from 0 to 0.165 V, typ, clamps not added: 25.5 kohm
|   GND clamp passes 1 mA (typ) near -0.45 V on its own axis
|   POWER clamp passes 1 mA (typ) near -0.88 V on its own axis
|   rising waveform, R_fixture 50, V_fixture 0.0: 20-80 % time 45.3ps typ, 48.5ps min, 39.2ps max; typ from 0.001 V to 0.291 V
|   falling waveform, R_fixture 50, V_fixture 1.1: 20-80 % time 69.3ps typ, 78.7ps min, 59.6ps max; typ from 1.1 V to 0.958 V
|   rising waveform, R_fixture 50, V_fixture 1.1: 20-80 % time 55ps typ, 54ps min, 54.2ps max; typ from 0.958 V to 1.1 V
|   falling waveform, R_fixture 50, V_fixture 0.0: 20-80 % time 49.8ps typ, 54.5ps min, 45.7ps max; typ from 0.291 V to 0.001 V
[Pulldown]
|   Voltage   I(typ)   I(min)   I(max)
-1.1V     -21.14mA   -18.67mA   -23.78mA
-925.1mV  -17.75mA   -15.79mA   -19.88mA
-707.3mV  -13.21mA   -11.7mA    -14.87mA
-499.4mV  -8.288mA   -6.808mA   -10.06mA
-334.4mV  -3.815mA   -2.975mA   -5.09mA
-222.2mV  -1.668mA   -1.418mA   -2.148mA
-176mV    -1.135mA   -1.021mA   -1.342mA
-119.9mV  -679.6uA   -644.8uA   -718.5uA
352mV     1.447mA    1.422mA    1.482mA
843.7mV   2.68mA     2.468mA    3.039mA
1.283V    3.182mA    2.882mA    3.756mA
2.2V      3.818mA    3.475mA    4.505mA
[GND Clamp]
|   Voltage   I(typ)   I(min)   I(max)
-1.1V     -34.88mA   -30.34mA   -43.13mA
-938.3mV  -24.92mA   -21.15mA   -31.24mA
-793.1mV  -15.98mA   -13.01mA   -21.06mA
-723.8mV  -11.98mA   -9.381mA   -16.18mA
-664.4mV  -8.768mA   -6.598mA   -12.12mA
-591.8mV  -5.271mA   -3.798mA   -7.523mA
-522.5mV  -2.673mA   -1.906mA   -3.823mA
-469.7mV  -1.36mA    -986.7uA   -1.792mA
-413.6mV  -566.4uA   -417.2uA   -621.7uA
-357.5mV  -191.6uA   -144.3uA   -174uA
-258.5mV  -16.3uA    -14.32uA   -9.912uA
2.2V      0A         0A         0A
[Pullup]
|   Voltage   I(typ)   I(min)   I(max)
-1.1V     3.142uA    4.844uA    1.416uA
233.2mV   -24.2uA    -24.4uA    -25.34uA
332.2mV   -161.4uA   -134.8uA   -221.7uA
434.5mV   -694.4uA   -568.1uA   -878.7uA
543.4mV   -1.825mA   -1.666mA   -1.999mA
691.9mV   -3.931mA   -4.057mA   -3.885mA
975.7mV   -8.587mA   -9.731mA   -8.057mA
1.388V    -15.78mA   -18.06mA   -14.8mA
1.589V    -19.11mA   -21.6mA    -18.21mA
1.685V    -20.35mA   -22.87mA   -19.6mA
1.887V    -23.04mA   -24.9mA    -22.72mA
2.2V      -27.69mA   -27.67mA   -28.61mA
[POWER Clamp]
|   Voltage   I(typ)   I(min)   I(max)
-1.1V     3.036mA    3.636mA    2.186mA
-1.041V   2.347mA    2.931mA    1.626mA
-977.9mV  1.724mA    2.242mA    1.161mA
-905.3mV  1.155mA    1.554mA    731.9uA
-849.2mV  799.6uA    1.126mA    535.5uA
-779.9mV  448uA      701.9uA    396.3uA
-710.6mV  232.2uA    359.1uA    273.1uA
-657.8mV  146.8uA    178.9uA    190.7uA
-595.1mV  80.77uA    68.33uA    109.3uA
-489.5mV  17.79uA    10.82uA    22.47uA
-374mV    1.388uA    992.4nA    1.121uA
2.2V      0A         0A         0A
[Ramp]
|   typ   min   max
| 20% - 80%
dV/dt_r   174.33m/45.26p   170.33m/48.45p   187.78m/39.25p
dV/dt_f   85.16m/69.42p   76.66m/78.39p   100.85m/59.75p
| 25% - 75%
|dV/dt_r   145.27m/36.08p   141.94m/38.61p   156.48m/31.23p
|dV/dt_f   70.97m/55.05p   63.88m/62.33p   84.04m/47.45p
R_load = 50
[Rising Waveform]
R_fixture = 50
V_fixture = 0.0
|   Time   V(typ)   V(min)   V(max)
0s        571.1uV    503.7uV    413.3uV
55ps      278.1uV    -10.23uV   6.752mV
63ps      1.972mV    -288.5uV   32.04mV
76ps      10.99mV    1.484mV    107.5mV
87ps      43.39mV    5.593mV    170.7mV
103ps     119.2mV    28.76mV    236.4mV
136ps     233.5mV    159.9mV    294.9mV
166ps     273.5mV    239.2mV    308.8mV
200ps     287.1mV    272.8mV    312.5mV
383ps     291.1mV    284.4mV    313.4mV
[Falling Waveform]
R_fixture   = 50
V_fixture   = 1.1
V_fixture_min = 1.06
V_fixture_max = 1.17
|   Time   V(typ)   V(min)   V(max)
0s        1.1V       1.06V      1.17V
53ps      1.101V     1.06V      1.17V
69ps      1.099V     1.061V     1.164V
91ps      1.092V     1.056V     1.122V
125ps     1.044V     1.044V     1.057V
148ps     1.012V     1.017V     1.033V
167ps     993.7mV    994.4mV    1.02V
205ps     972.6mV    962mV      1.009V
244ps     963.7mV    945mV      1.004V
383ps     958.1mV    932.2mV    1.002V
[Rising Waveform]
R_fixture   = 50
V_fixture   = 1.1
V_fixture_min = 1.06
V_fixture_max = 1.17
|   Time   V(typ)   V(min)   V(max)
0s        957.9mV    931.6mV    1.002V
45ps      955.9mV    930.3mV    1.002V
55ps      957.4mV    928.3mV    1.017V
68ps      975.4mV    930.8mV    1.058V
86ps      1.02V      958.8mV    1.101V
100ps     1.045V     989.5mV    1.121V
119ps     1.065V     1.018V     1.14V
139ps     1.079V     1.034V     1.152V
217ps     1.096V     1.056V     1.167V
383ps     1.1V       1.06V      1.17V
[Falling Waveform]
R_fixture = 50
V_fixture = 0.0
|   Time   V(typ)   V(min)   V(max)
0s        291.2mV    284.5mV    313.4mV
57ps      295.9mV    286.1mV    311.2mV
72ps      289.3mV    292.4mV    245.3mV
84ps      251.6mV    287.3mV    169mV
96ps      190.3mV    257.7mV    117.2mV
113ps     117.3mV    186mV      70.78mV
145ps     48.23mV    81.18mV    27.65mV
174ps     21.93mV    37.8mV     11.97mV
217ps     7.153mV    12.62mV    3.696mV
383ps     750.9uV    786.5uV    460.6uV
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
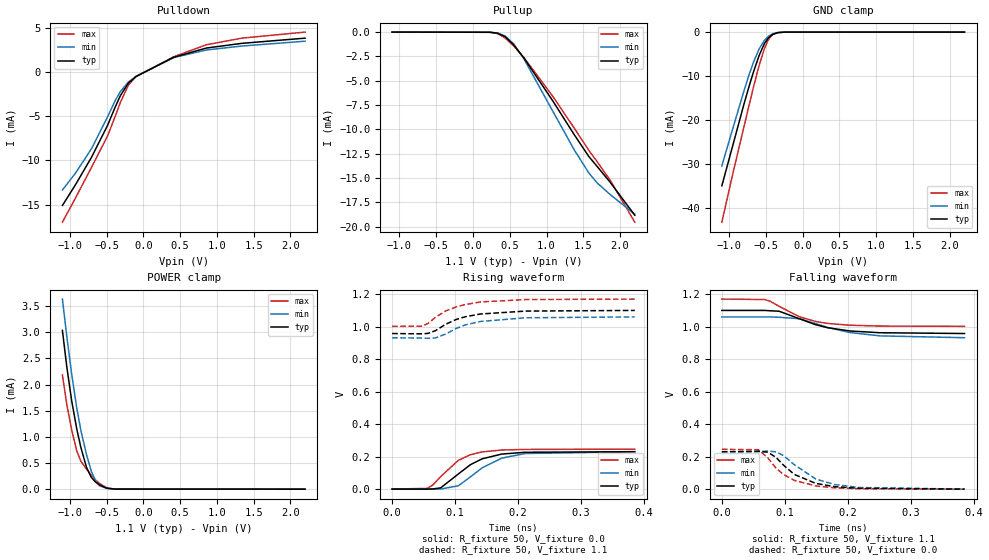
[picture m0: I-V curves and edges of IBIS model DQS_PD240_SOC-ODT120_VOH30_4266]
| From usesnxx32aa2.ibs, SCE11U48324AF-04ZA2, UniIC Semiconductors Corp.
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| DQS_PD240_SOC-ODT120_VOH30_4266
| (240 Ohm Pulldown, 120 Ohm System ODT Setting, VOH=VDDQ/3.0, 3200-4266Mbps)
[Model]   DQS_PD240_SOC-ODT120_VOH30_4266
Model_type   I/O
Vinl = 123.333mV
Vinh = 243.333mV
Vmeas = 183.333mV
Vref = 0.0mV
Cref = 0.0pF
Rref = 120.000Ohm
|   typ   min   max
|C_comp   0.838pF   0.788pF   0.888pF
C_comp_pullup   0.4190pF   0.3940pF   0.4440pF
C_comp_pulldown   0.4190pF   0.3940pF   0.4440pF
| Note: C_comp changes when the ODT circuit is enabled.
[Model Spec]
| Input threshold voltage corners
Vinl   0.1233V   0.1167V   0.1350V
Vinh   0.2433V   0.2367V   0.2550V
| Measurement voltage corners
Vmeas   0.1833V   0.1767V   0.1950V
| Timing spec test load voltage corners
Vref   0.0000V   0.0000V   0.0000V
| Dynamic Overshoot Parameters from LPDDR4 Specification
D_overshoot_ampl_h   0.30   NA   NA
D_overshoot_ampl_l   0.30   NA   NA
D_overshoot_area_h   0.1n   NA   NA
D_overshoot_area_l   0.1n   NA   NA
[Receiver Thresholds]
Vcross_low   = 123.3mV
Vcross_high  = 243.3mV
Vdiff_ac   = 120mV
Vdiff_dc   = 120mV
Tdiffslew_ac = 10.000ns |Not specified, so set to high value
[Voltage Range]   1.1000V   1.0600V   1.1700V
[Pullup Reference]   1.1000V   1.0600V   1.1700V
| Junction Temperature (Ambient temp is 35C typ 95C min -40C max)
[Temperature Range]   50.0   110.0   -40.0
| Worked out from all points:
|   slope of the pulldown table from 0 to 0.165 V, typ, clamps not added: 225 ohm
|   slope of the pullup table from 0 to 0.165 V, typ, clamps not added: 39 kohm
|   GND clamp passes 1 mA (typ) near -0.45 V on its own axis
|   POWER clamp passes 1 mA (typ) near -0.88 V on its own axis
|   rising waveform, R_fixture 50, V_fixture 0.0: 20-80 % time 49.4ps typ, 53.7ps min, 43.7ps max; typ from 0 V to 0.23 V
|   falling waveform, R_fixture 50, V_fixture 1.1: 20-80 % time 68.4ps typ, 77.1ps min, 59.2ps max; typ from 1.1 V to 0.958 V
|   rising waveform, R_fixture 50, V_fixture 1.1: 20-80 % time 56.2ps typ, 57.4ps min, 54.2ps max; typ from 0.958 V to 1.1 V
|   falling waveform, R_fixture 50, V_fixture 0.0: 20-80 % time 50.2ps typ, 55.2ps min, 46.1ps max; typ from 0.231 V to 0.001 V
[Pulldown]
|   Voltage   I(typ)   I(min)   I(max)
-1.1V     -15.1mA    -13.35mA   -16.99mA
-921.8mV  -12.75mA   -11.44mA   -14.25mA
-700.7mV  -9.595mA   -8.632mA   -10.73mA
-486.2mV  -6.044mA   -5.079mA   -7.243mA
-383.9mV  -4.009mA   -3.269mA   -5.062mA
-311.3mV  -2.678mA   -2.21mA    -3.436mA
-202.4mV  -1.258mA   -1.14mA    -1.488mA
-100.1mV  -521.3uA   -507.7uA   -527.5uA
414.7mV   1.659mA    1.622mA    1.72mA
856.9mV   2.701mA    2.483mA    3.07mA
1.342V    3.234mA    2.928mA    3.822mA
2.2V      3.818mA    3.475mA    4.505mA
[GND Clamp]
|   Voltage   I(typ)   I(min)   I(max)
-1.1V     -34.88mA   -30.35mA   -43.13mA
-944.9mV  -25.34mA   -21.53mA   -31.71mA
-793.1mV  -15.98mA   -13.01mA   -21.06mA
-723.8mV  -11.98mA   -9.381mA   -16.18mA
-664.4mV  -8.768mA   -6.598mA   -12.12mA
-591.8mV  -5.271mA   -3.798mA   -7.525mA
-522.5mV  -2.67mA    -1.909mA   -3.823mA
-469.7mV  -1.359mA   -987.9uA   -1.791mA
-413.6mV  -564.7uA   -417.3uA   -621.3uA
-347.6mV  -155uA     -118.1uA   -135.6uA
-251.9mV  -13.3uA    -12.08uA   -8.062uA
2.2V      0A         0A         0A
[Pullup]
|   Voltage   I(typ)   I(min)   I(max)
-1.1V     2.095uA    3.229uA    944.4nA
229.9mV   -15.22uA   -15.27uA   -15.54uA
332.2mV   -107.8uA   -90.07uA   -148.2uA
434.5mV   -465.8uA   -380.7uA   -589.4uA
550mV     -1.286mA   -1.183mA   -1.397mA
691.9mV   -2.655mA   -2.748mA   -2.618mA
1.078V    -6.994mA   -8.033mA   -6.53mA
1.378V    -10.56mA   -12.12mA   -9.881mA
1.576V    -12.8mA    -14.49mA   -12.17mA
1.688V    -13.81mA   -15.5mA    -13.32mA
1.867V    -15.45mA   -16.71mA   -15.25mA
2.2V      -18.83mA   -18.71mA   -19.54mA
[POWER Clamp]
|   Voltage   I(typ)   I(min)   I(max)
-1.1V     3.036mA    3.636mA    2.186mA
-1.041V   2.347mA    2.931mA    1.626mA
-974.6mV  1.695mA    2.208mA    1.139mA
-905.3mV  1.155mA    1.554mA    732.5uA
-849.2mV  799.3uA    1.126mA    535.5uA
-773.3mV  420.9uA    665.5uA    384.1uA
-707.3mV  225.5uA    345.5uA    267.6uA
-651.2mV  138.6uA    162.3uA    181.2uA
-591.8mV  77.91uA    64.82uA    105.6uA
-496.1mV  20.09uA    12.4uA     25.73uA
-387.2mV  1.888uA    1.305uA    1.608uA
2.2V      0A         0A         0A
[Ramp]
|   typ   min   max
| 20% - 80%
dV/dt_r   138.03m/49.38p   137.64m/53.72p   147.26m/43.66p
dV/dt_f   85.18m/68.32p   76.66m/76.99p   100.81m/59.21p
| 25% - 75%
|dV/dt_r   115.03m/39.36p   114.70m/42.84p   122.71m/34.68p
|dV/dt_f   70.99m/54.33p   63.88m/61.20p   84.01m/47.01p
R_load = 50
[Rising Waveform]
R_fixture = 50
V_fixture = 0.0
|   Time   V(typ)   V(min)   V(max)
0s        379.9uV    332.9uV    275.6uV
56ps      65.9uV     -7.424uV   4.605mV
65ps      1.242mV    -292.7uV   26.74mV
77ps      7.727mV    589.1uV    77.27mV
105ps     92.88mV    20.42mV    176.9mV
124ps     150mV      74.46mV    211.5mV
143ps     186.8mV    131.5mV    229.2mV
174ps     215.8mV    190.9mV    240.8mV
211ps     226.8mV    219mV      244.5mV
385ps     230.4mV    229.7mV    245.7mV
[Falling Waveform]
R_fixture   = 50
V_fixture   = 1.1
V_fixture_min = 1.06
V_fixture_max = 1.17
|   Time   V(typ)   V(min)   V(max)
0s        1.1V       1.06V      1.17V
68ps      1.1V       1.06V      1.167V
77ps      1.098V     1.06V      1.156V
91ps      1.095V     1.058V     1.125V
123ps     1.049V     1.049V     1.061V
149ps     1.012V     1.019V     1.032V
168ps     993.6mV    995.2mV    1.02V
203ps     973.7mV    964.1mV    1.009V
251ps     962.8mV    943.4mV    1.004V
385ps     958mV      932.2mV    1.002V
[Rising Waveform]
R_fixture   = 50
V_fixture   = 1.1
V_fixture_min = 1.06
V_fixture_max = 1.17
|   Time   V(typ)   V(min)   V(max)
0s        957.8mV    931.6mV    1.002V
47ps      955.9mV    930mV      1.003V
57ps      958.6mV    928.3mV    1.02V
69ps      976mV      931.4mV    1.058V
85ps      1.015V     954.6mV    1.097V
102ps     1.045V     989.7mV    1.122V
116ps     1.061V     1.011V     1.136V
140ps     1.078V     1.032V     1.152V
212ps     1.096V     1.055V     1.167V
385ps     1.1V       1.06V      1.17V
[Falling Waveform]
R_fixture = 50
V_fixture = 0.0
|   Time   V(typ)   V(min)   V(max)
0s        230.5mV    229.8mV    245.8mV
58ps      233.6mV    230.9mV    243.1mV
73ps      227.8mV    235mV      193.1mV
86ps      195.7mV    229.8mV    129.6mV
98ps      147.4mV    206.5mV    90.1mV
115ps     91.18mV    150.7mV    54.54mV
149ps     35.68mV    62.83mV    20.14mV
179ps     15.75mV    28.68mV    8.555mV
218ps     5.683mV    10.65mV    2.974mV
385ps     525uV      596.4uV    357.2uV
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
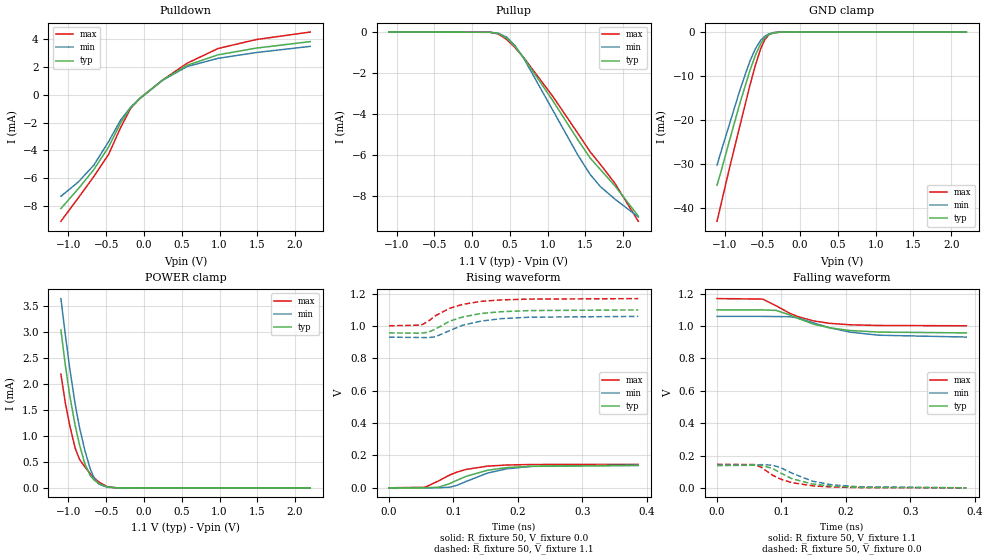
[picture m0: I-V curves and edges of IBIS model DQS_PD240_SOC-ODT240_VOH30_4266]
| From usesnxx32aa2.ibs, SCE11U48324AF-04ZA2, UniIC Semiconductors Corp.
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| DQS_PD240_SOC-ODT240_VOH30_4266
| (240 Ohm Pulldown, 240 Ohm System ODT Setting, VOH=VDDQ/3.0, 3200-4266Mbps)
[Model]   DQS_PD240_SOC-ODT240_VOH30_4266
Model_type   I/O
Vinl = 123.333mV
Vinh = 243.333mV
Vmeas = 183.333mV
Vref = 0.0mV
Cref = 0.0pF
Rref = 240.000Ohm
|   typ   min   max
|C_comp   0.838pF   0.788pF   0.888pF
C_comp_pullup   0.4190pF   0.3940pF   0.4440pF
C_comp_pulldown   0.4190pF   0.3940pF   0.4440pF
| Note: C_comp changes when the ODT circuit is enabled.
[Model Spec]
| Input threshold voltage corners
Vinl   0.1233V   0.1167V   0.1350V
Vinh   0.2433V   0.2367V   0.2550V
| Measurement voltage corners
Vmeas   0.1833V   0.1767V   0.1950V
| Timing spec test load voltage corners
Vref   0.0000V   0.0000V   0.0000V
| Dynamic Overshoot Parameters from LPDDR4 Specification
D_overshoot_ampl_h   0.30   NA   NA
D_overshoot_ampl_l   0.30   NA   NA
D_overshoot_area_h   0.1n   NA   NA
D_overshoot_area_l   0.1n   NA   NA
[Receiver Thresholds]
Vcross_low   = 123.3mV
Vcross_high  = 243.3mV
Vdiff_ac   = 120mV
Vdiff_dc   = 120mV
Tdiffslew_ac = 10.000ns |Not specified, so set to high value
[Voltage Range]   1.1000V   1.0600V   1.1700V
[Pullup Reference]   1.1000V   1.0600V   1.1700V
| Junction Temperature (Ambient temp is 35C typ 95C min -40C max)
[Temperature Range]   50.0   110.0   -40.0
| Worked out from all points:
|   slope of the pulldown table from 0 to 0.165 V, typ, clamps not added: 227 ohm
|   slope of the pullup table from 0 to 0.165 V, typ, clamps not added: 80.7 kohm
|   GND clamp passes 1 mA (typ) near -0.45 V on its own axis
|   POWER clamp passes 1 mA (typ) near -0.88 V on its own axis
|   rising waveform, R_fixture 50, V_fixture 0.0: 20-80 % time 59.6ps typ, 61.7ps min, 51.4ps max; typ from 0 V to 0.138 V
|   falling waveform, R_fixture 50, V_fixture 1.1: 20-80 % time 67.5ps typ, 75.6ps min, 58.8ps max; typ from 1.1 V to 0.958 V
|   rising waveform, R_fixture 50, V_fixture 1.1: 20-80 % time 57.4ps typ, 61.5ps min, 54.5ps max; typ from 0.958 V to 1.1 V
|   falling waveform, R_fixture 50, V_fixture 0.0: 20-80 % time 51.4ps typ, 56.8ps min, 46.9ps max; typ from 0.138 V to 0 V
[Pulldown]
|   Voltage   I(typ)   I(min)   I(max)
-1.1V     -8.17mA    -7.293mA   -9.087mA
-869mV    -6.746mA   -6.261mA   -7.4mA
-664.4mV  -5.376mA   -5.058mA   -5.876mA
-469.7mV  -3.757mA   -3.371mA   -4.293mA
-308mV    -2.001mA   -1.801mA   -2.335mA
-176mV    -919.6uA   -889.4uA   -974.2uA
-50.6mV   -245.1uA   -243.6uA   -239.1uA
246.4mV   1.053mA    1.042mA    1.061mA
569.8mV   2.115mA    2.026mA    2.264mA
979mV     2.868mA    2.616mA    3.32mA
1.484V    3.349mA    3.032mA    3.965mA
2.2V      3.818mA    3.475mA    4.505mA
[GND Clamp]
|   Voltage   I(typ)   I(min)   I(max)
-1.1V     -34.88mA   -30.34mA   -43.13mA
-1.047V   -31.79mA   -27.25mA   -39.23mA
-938.3mV  -24.92mA   -21.15mA   -31.24mA
-796.4mV  -16.18mA   -13.19mA   -21.29mA
-667.7mV  -8.939mA   -6.742mA   -12.34mA
-591.8mV  -5.271mA   -3.798mA   -7.523mA
-522.5mV  -2.673mA   -1.905mA   -3.822mA
-469.7mV  -1.361mA   -986.7uA   -1.791mA
-416.9mV  -601.5uA   -440.8uA   -665.5uA
-350.9mV  -167.8uA   -126.1uA   -148.2uA
-248.6mV  -12.24uA   -10.96uA   -7.123uA
2.2V      0A         0A         0A
[Pullup]
|   Voltage   I(typ)   I(min)   I(max)
-1.1V     1.047uA    1.615uA    471.8nA
239.8mV   -9.287uA   -9.208uA   -9.959uA
348.7mV   -70.57uA   -57.98uA   -97.34uA
457.6mV   -294.6uA   -245.6uA   -360.3uA
569.8mV   -714uA     -668.3uA   -763.6uA
688.6mV   -1.278mA   -1.312mA   -1.267mA
1.065V    -3.325mA   -3.788mA   -3.117mA
1.398V    -5.241mA   -5.982mA   -4.926mA
1.563V    -6.142mA   -6.945mA   -5.84mA
1.698V    -6.702mA   -7.534mA   -6.451mA
1.887V    -7.482mA   -8.134mA   -7.355mA
2.2V      -8.971mA   -9.017mA   -9.226mA
[POWER Clamp]
|   Voltage   I(typ)   I(min)   I(max)
-1.1V     3.036mA    3.636mA    2.186mA
-1.044V   2.383mA    2.969mA    1.654mA
-984.5mV  1.784mA    2.311mA    1.206mA
-911.9mV  1.201mA    1.611mA    764.9uA
-855.8mV  838uA      1.172mA    552.1uA
-783.2mV  462.1uA    720.1uA    402.5uA
-710.6mV  232.2uA    359.1uA    273.1uA
-657.8mV  146.8uA    178.8uA    190.7uA
-595.1mV  80.78uA    68.31uA    109.2uA
-482.9mV  15.79uA    9.506uA    19.51uA
-360.8mV  1.019uA    775nA      799.8nA
2.2V      0A         0A         0A
[Ramp]
|   typ   min   max
| 20% - 80%
dV/dt_r   82.44m/59.64p   84.20m/61.72p   87.23m/51.40p
dV/dt_f   85.19m/67.55p   76.66m/75.70p   100.85m/58.64p
| 25% - 75%
|dV/dt_r   68.70m/47.36p   70.17m/49.17p   72.69m/40.83p
|dV/dt_f   70.99m/53.78p   63.89m/60.40p   84.04m/46.55p
R_load = 50
[Rising Waveform]
R_fixture = 50
V_fixture = 0.0
|   Time   V(typ)   V(min)   V(max)
0s        184.4uV    156.8uV    134.8uV
56ps      -100.1uV   -39.43uV   3.322mV
77ps      3.702mV    124.3uV    42.72mV
94ps      25.5mV     3.718mV    78.76mV
105ps     45.66mV    14.69mV    96.52mV
120ps     71.27mV    39.68mV    114.1mV
153ps     108.7mV    91.18mV    134.2mV
183ps     125mV      117.7mV    141.1mV
222ps     133.5mV    132.8mV    144.2mV
387ps     137.6mV    140.5mV    145.5mV
[Falling Waveform]
R_fixture   = 50
V_fixture   = 1.1
V_fixture_min = 1.06
V_fixture_max = 1.17
|   Time   V(typ)   V(min)   V(max)
0s        1.1V       1.06V      1.17V
71ps      1.1V       1.06V      1.167V
92ps      1.097V     1.059V     1.125V
113ps     1.069V     1.058V     1.079V
126ps     1.047V     1.05V      1.058V
150ps     1.012V     1.02V      1.032V
175ps     989mV      989.3mV    1.017V
207ps     972.6mV    962.4mV    1.008V
251ps     963mV      943.7mV    1.004V
387ps     958mV      932.2mV    1.002V
[Rising Waveform]
R_fixture   = 50
V_fixture   = 1.1
V_fixture_min = 1.06
V_fixture_max = 1.17
|   Time   V(typ)   V(min)   V(max)
0s        957.8mV    931.6mV    1.002V
50ps      956.1mV    929.4mV    1.006V
61ps      962.1mV    928.6mV    1.03V
72ps      981.3mV    934mV      1.064V
94ps      1.03V      971.9mV    1.11V
114ps     1.056V     1.005V     1.134V
143ps     1.078V     1.031V     1.153V
174ps     1.089V     1.046V     1.162V
218ps     1.096V     1.055V     1.167V
387ps     1.1V       1.06V      1.17V
[Falling Waveform]
R_fixture = 50
V_fixture = 0.0
|   Time   V(typ)   V(min)   V(max)
0s        137.7mV    140.6mV    145.6mV
58ps      139.7mV    141.7mV    143.9mV
69ps      138.7mV    143.5mV    126.3mV
86ps      120.3mV    140.1mV    78.73mV
98ps      93.55mV    126.2mV    55.07mV
116ps     57.16mV    91.54mV    32.48mV
148ps     23.77mV    41.16mV    12.74mV
179ps     10.29mV    18.52mV    5.226mV
221ps     3.462mV    6.413mV    1.643mV
387ps     295.1uV    351.3uV    168.1uV
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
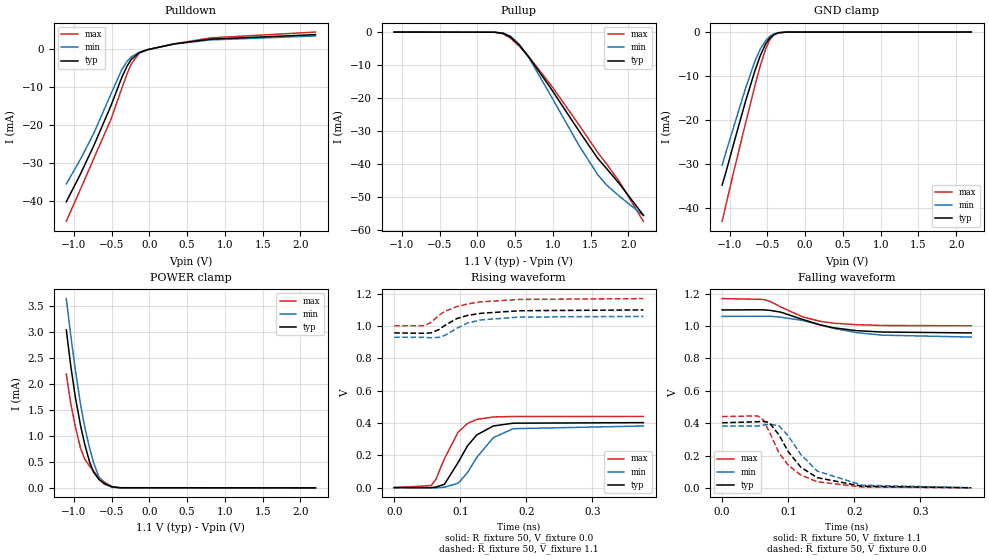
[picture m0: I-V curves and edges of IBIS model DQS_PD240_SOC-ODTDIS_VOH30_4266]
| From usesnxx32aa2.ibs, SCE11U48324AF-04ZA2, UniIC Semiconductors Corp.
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| DQS_PD240_SOC-ODTDIS_VOH30_4266
| (240 Ohm Pulldown, SOC ODT disabled setting, VOH=VDDQ/3.0 cal. point, 3200-4266Mbps)
[Model]   DQS_PD240_SOC-ODTDIS_VOH30_4266
Model_type   I/O
Vinl = 123.333mV
Vinh = 243.333mV
Vmeas = 183.333mV
Vref = 0.0mV
Cref = 0.0pF
|   typ   min   max
|C_comp   0.838pF   0.788pF   0.888pF
C_comp_pullup   0.4190pF   0.3940pF   0.4440pF
C_comp_pulldown   0.4190pF   0.3940pF   0.4440pF
| Note: C_comp changes when the ODT circuit is enabled.
[Model Spec]
| Input threshold voltage corners
Vinl   0.1233V   0.1167V   0.1350V
Vinh   0.2433V   0.2367V   0.2550V
| Measurement voltage corners
Vmeas   0.1833V   0.1767V   0.1950V
| Timing spec test load voltage corners
Vref   0.0000V   0.0000V   0.0000V
| Dynamic Overshoot Parameters from LPDDR4 Specification
D_overshoot_ampl_h   0.30   NA   NA
D_overshoot_ampl_l   0.30   NA   NA
D_overshoot_area_h   0.1n   NA   NA
D_overshoot_area_l   0.1n   NA   NA
[Receiver Thresholds]
Vcross_low   = 123.3mV
Vcross_high  = 243.3mV
Vdiff_ac   = 120mV
Vdiff_dc   = 120mV
Tdiffslew_ac = 10.000ns |Not specified, so set to high value
[Voltage Range]   1.1000V   1.0600V   1.1700V
[Pullup Reference]   1.1000V   1.0600V   1.1700V
| Junction Temperature (Ambient temp is 35C typ 95C min -40C max)
[Temperature Range]   50.0   110.0   -40.0
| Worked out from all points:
|   slope of the pulldown table from 0 to 0.165 V, typ, clamps not added: 220 ohm
|   slope of the pullup table from 0 to 0.165 V, typ, clamps not added: 12.9 kohm
|   GND clamp passes 1 mA (typ) near -0.45 V on its own axis
|   POWER clamp passes 1 mA (typ) near -0.88 V on its own axis
|   rising waveform, R_fixture 50, V_fixture 0.0: 20-80 % time 36.4ps typ, 40.6ps min, 31.5ps max; typ from 0.001 V to 0.403 V
|   falling waveform, R_fixture 50, V_fixture 1.1: 20-80 % time 72.2ps typ, 84.8ps min, 61.1ps max; typ from 1.1 V to 0.958 V
|   rising waveform, R_fixture 50, V_fixture 1.1: 20-80 % time 47.9ps typ, 41.9ps min, 51ps max; typ from 0.958 V to 1.1 V
|   falling waveform, R_fixture 50, V_fixture 0.0: 20-80 % time 48.3ps typ, 52.1ps min, 44.7ps max; typ from 0.403 V to 0.001 V
[Pulldown]
|   Voltage   I(typ)   I(min)   I(max)
-1.1V     -40.34mA   -35.62mA   -45.48mA
-921.8mV  -33.39mA   -29.43mA   -37.46mA
-737mV    -25.57mA   -22.32mA   -28.97mA
-509.3mV  -14.99mA   -11.88mA   -18.6mA
-364.1mV  -7.443mA   -5.397mA   -10.35mA
-294.8mV  -4.472mA   -3.229mA   -6.501mA
-238.7mV  -2.708mA   -2.052mA   -3.916mA
-136.4mV  -964.9uA   -856.7uA   -1.123mA
-24.2mV   -156.3uA   -149.3uA   -146.4uA
325.6mV   1.352mA    1.331mA    1.379mA
807.4mV   2.622mA    2.422mA    2.952mA
2.2V      3.818mA    3.475mA    4.505mA
[GND Clamp]
|   Voltage   I(typ)   I(min)   I(max)
-1.1V     -34.88mA   -30.35mA   -43.13mA
-1.047V   -31.79mA   -27.25mA   -39.23mA
-938.3mV  -24.92mA   -21.15mA   -31.24mA
-789.8mV  -15.79mA   -12.83mA   -20.82mA
-667.7mV  -8.94mA    -6.743mA   -12.34mA
-595.1mV  -5.419mA   -3.908mA   -7.721mA
-525.8mV  -2.776mA   -1.977mA   -3.977mA
-473mV    -1.426mA   -1.033mA   -1.891mA
-413.6mV  -565.1uA   -417.1uA   -621.3uA
-354.2mV  -179.7uA   -134.8uA   -160.1uA
-251.9mV  -13.31uA   -11.89uA   -7.929uA
2.2V      0A         0A         0A
[Pullup]
|   Voltage   I(typ)   I(min)   I(max)
-1.1V     6.284uA    9.684uA    2.832uA
229.9mV   -45.54uA   -46.48uA   -46.57uA
345.4mV   -402uA     -331.8uA   -555.7uA
441.1mV   -1.491mA   -1.229mA   -1.868mA
559.9mV   -4.054mA   -3.762mA   -4.37mA
688.6mV   -7.724mA   -7.945mA   -7.651mA
965.8mV   -16.75mA   -18.92mA   -15.73mA
1.345V    -29.87mA   -34.23mA   -28.01mA
1.596V    -38.26mA   -43.21mA   -36.46mA
1.718V    -41.46mA   -46.41mA   -40.06mA
1.887V    -46.05mA   -49.8mA    -45.44mA
2.2V      -55.46mA   -55.5mA    -57.28mA
[POWER Clamp]
|   Voltage   I(typ)   I(min)   I(max)
-1.1V     3.036mA    3.636mA    2.186mA
-1.041V   2.347mA    2.931mA    1.626mA
-981.2mV  1.754mA    2.277mA    1.183mA
-911.9mV  1.201mA    1.611mA    764.5uA
-855.8mV  838.1uA    1.172mA    552.2uA
-793.1mV  506.1uA    776.1uA    421uA
-740.3mV  306.2uA    494.5uA    324.3uA
-667.7mV  159.9uA    206.2uA    205.2uA
-598.4mV  83.71uA    71.96uA    113uA
-496.1mV  20.1uA     12.32uA    25.72uA
-390.5mV  2.041uA    1.385uA    1.76uA
2.2V      0A         0A         0A
[Ramp]
|   typ   min   max
| 20% - 80%
dV/dt_r   241.03m/36.40p   228.61m/40.57p   264.21m/31.47p
dV/dt_f   85.18m/72.42p   76.67m/84.47p   100.85m/61.39p
| 25% - 75%
|dV/dt_r   200.86m/28.98p   190.50m/32.27p   220.18m/25.03p
|dV/dt_f   70.98m/57.60p   63.89m/66.49p   84.04m/48.91p
R_load = 50
[Rising Waveform]
R_fixture = 50
V_fixture = 0.0
|   Time   V(typ)   V(min)   V(max)
0s        1.138mV    1.014mV    820.3uV
56ps      937.4uV    -134.2uV   13.72mV
63ps      4.433mV    -419.1uV   51.49mV
76ps      21.33mV    3.524mV    180.5mV
97ps      158.5mV    28.64mV    345.4mV
111ps     260mV      94.34mV    397.7mV
125ps     327.2mV    187.9mV    422.9mV
150ps     382.2mV    310mV      437.9mV
180ps     399.4mV    365.4mV    440.9mV
377ps     402.9mV    382mV      441.2mV
[Falling Waveform]
R_fixture   = 50
V_fixture   = 1.1
V_fixture_min = 1.06
V_fixture_max = 1.17
|   Time   V(typ)   V(min)   V(max)
0s        1.1V       1.06V      1.17V
62ps      1.101V     1.061V     1.165V
73ps      1.097V     1.061V     1.152V
89ps      1.086V     1.055V     1.118V
122ps     1.041V     1.035V     1.057V
148ps     1.008V     1.008V     1.03V
169ps     989.4mV    985.8mV    1.018V
203ps     972.2mV    960mV      1.009V
242ps     963.4mV    944.3mV    1.004V
377ps     958mV      932.2mV    1.002V
[Rising Waveform]
R_fixture   = 50
V_fixture   = 1.1
V_fixture_min = 1.06
V_fixture_max = 1.17
|   Time   V(typ)   V(min)   V(max)
0s        957.9mV    931.6mV    1.002V
45ps      955.5mV    930.2mV    1.002V
56ps      958mV      927.7mV    1.024V
68ps      979.2mV    930.5mV    1.067V
77ps      1.005V     942.9mV    1.092V
95ps      1.047V     987.2mV    1.121V
111ps     1.066V     1.019V     1.137V
131ps     1.079V     1.038V     1.15V
190ps     1.095V     1.056V     1.165V
377ps     1.1V       1.06V      1.17V
[Falling Waveform]
R_fixture = 50
V_fixture = 0.0
|   Time   V(typ)   V(min)   V(max)
0s        403mV      382.2mV    441.3mV
54ps      409mV      383mV      445.2mV
62ps      413mV      388.3mV    421mV
71ps      404.7mV    394.7mV    351.3mV
86ps      328.4mV    384.3mV    217.2mV
100ps     224.5mV    322.1mV    141.1mV
119ps     128.6mV    206.8mV    80.1mV
144ps     63.7mV     104mV      38.42mV
212ps     10.48mV    17.4mV     5.772mV
377ps     1.284mV    1.287mV    873.3uV
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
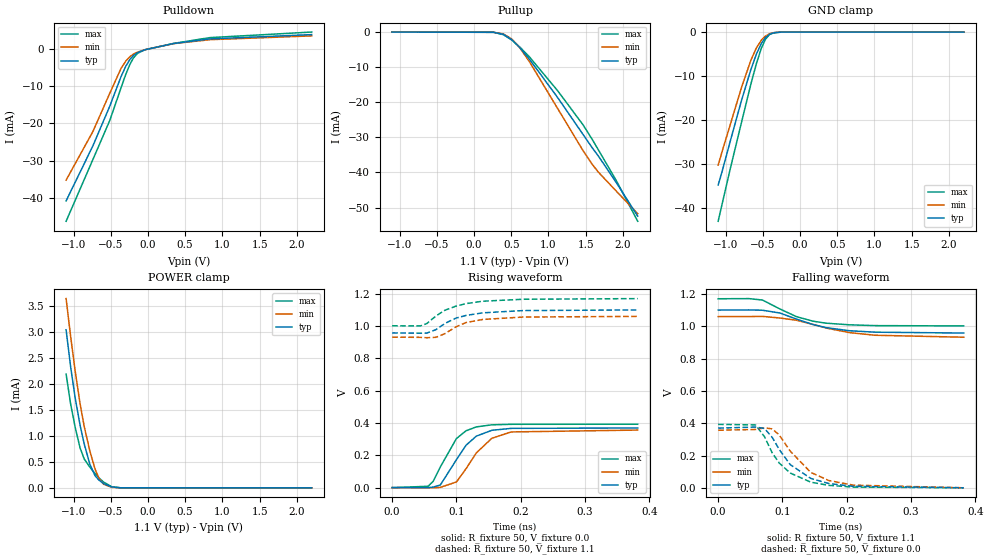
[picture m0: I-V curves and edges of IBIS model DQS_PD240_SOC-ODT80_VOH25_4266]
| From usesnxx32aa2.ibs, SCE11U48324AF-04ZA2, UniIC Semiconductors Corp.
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| DQS_PD240_SOC-ODT80_VOH25_4266
| (240 Ohm Pulldown, 80 Ohm System ODT Setting, VOH=VDDQ/2.5, 3200-4266Mbps)
[Model]   DQS_PD240_SOC-ODT80_VOH25_4266
Model_type   I/O
Vinl = 160.000mV
Vinh = 280.000mV
Vmeas = 220.000mV
Vref = 0.0mV
Cref = 0.0pF
Rref = 80.000Ohm
|   typ   min   max
|C_comp   0.838pF   0.788pF   0.888pF
C_comp_pullup   0.4190pF   0.3940pF   0.4440pF
C_comp_pulldown   0.4190pF   0.3940pF   0.4440pF
| Note: C_comp changes when the ODT circuit is enabled.
[Model Spec]
| Input threshold voltage corners
Vinl   0.1600V   0.1520V   0.1740V
Vinh   0.2800V   0.2720V   0.2940V
| Measurement voltage corners
Vmeas   0.2200V   0.2120V   0.2340V
| Timing spec test load voltage corners
Vref   0.0000V   0.0000V   0.0000V
| Dynamic Overshoot Parameters from LPDDR4 Specification
D_overshoot_ampl_h   0.30   NA   NA
D_overshoot_ampl_l   0.30   NA   NA
D_overshoot_area_h   0.1n   NA   NA
D_overshoot_area_l   0.1n   NA   NA
[Receiver Thresholds]
Vcross_low   = 160.0mV
Vcross_high  = 280.0mV
Vdiff_ac   = 120mV
Vdiff_dc   = 120mV
Tdiffslew_ac = 10.000ns |Not specified, so set to high value
[Voltage Range]   1.1000V   1.0600V   1.1700V
[Pullup Reference]   1.1000V   1.0600V   1.1700V
| Junction Temperature (Ambient temp is 35C typ 95C min -40C max)
[Temperature Range]   50.0   110.0   -40.0
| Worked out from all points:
|   slope of the pulldown table from 0 to 0.165 V, typ, clamps not added: 220 ohm
|   slope of the pullup table from 0 to 0.165 V, typ, clamps not added: 17.6 kohm
|   GND clamp passes 1 mA (typ) near -0.45 V on its own axis
|   POWER clamp passes 1 mA (typ) near -0.88 V on its own axis
|   rising waveform, R_fixture 50, V_fixture 0.0: 20-80 % time 36.4ps typ, 40.1ps min, 33.1ps max; typ from 0.001 V to 0.37 V
|   falling waveform, R_fixture 50, V_fixture 1.1: 20-80 % time 71.3ps typ, 83.9ps min, 60.6ps max; typ from 1.1 V to 0.958 V
|   rising waveform, R_fixture 50, V_fixture 1.1: 20-80 % time 51.3ps typ, 45.5ps min, 51.9ps max; typ from 0.958 V to 1.1 V
|   falling waveform, R_fixture 50, V_fixture 0.0: 20-80 % time 48.8ps typ, 52.3ps min, 44.9ps max; typ from 0.37 V to 0.001 V
[Pulldown]
|   Voltage   I(typ)   I(min)   I(max)
-1.1V     -40.8mA    -35.23mA   -46.27mA
-740.3mV  -26.04mA   -22.2mA    -29.72mA
-512.6mV  -15.36mA   -11.9mA    -19.19mA
-360.8mV  -7.395mA   -5.211mA   -10.4mA
-298.1mV  -4.666mA   -3.278mA   -6.834mA
-242mV    -2.834mA   -2.085mA   -4.146mA
-195.8mV  -1.801mA   -1.425mA   -2.472mA
-139.7mV  -1.012mA   -877.1uA   -1.195mA
-37.4mV   -231.8uA   -217.8uA   -222.9uA
345.4mV   1.423mA    1.4mA      1.457mA
830.5mV   2.659mA    2.451mA    3.008mA
2.2V      3.818mA    3.475mA    4.505mA
[GND Clamp]
|   Voltage   I(typ)   I(min)   I(max)
-1.1V     -34.88mA   -30.33mA   -43.14mA
-1.047V   -31.8mA    -27.25mA   -39.23mA
-938.3mV  -24.93mA   -21.15mA   -31.25mA
-786.5mV  -15.6mA    -12.65mA   -20.6mA
-661.1mV  -8.6mA     -6.453mA   -11.91mA
-585.2mV  -4.988mA   -3.582mA   -7.142mA
-519.2mV  -2.574mA   -1.836mA   -3.675mA
-466.4mV  -1.296mA   -945.5uA   -1.695mA
-410.3mV  -534.8uA   -393.7uA   -580.4uA
-354.2mV  -179.1uA   -135.8uA   -160.8uA
-248.6mV  -12.21uA   -11.14uA   -7.144uA
2.2V      0A         0A         0A
[Pullup]
|   Voltage   I(typ)   I(min)   I(max)
-1.1V     4.112uA    7.441uA    1.363uA
262.9mV   -65.04uA   -63.31uA   -66.39uA
394.9mV   -631.7uA   -525uA     -751.7uA
510.4mV   -2.22mA    -2.012mA   -2.307mA
616mV     -4.459mA   -4.485mA   -4.266mA
748mV     -7.819mA   -8.539mA   -7.138mA
1.121V    -18.57mA   -21.68mA   -16.63mA
1.464V    -29.13mA   -33.73mA   -26.39mA
1.589V    -32.98mA   -37.7mA    -30.6mA
1.675V    -35.44mA   -40mA      -33.69mA
1.91V     -42.82mA   -45.28mA   -42.24mA
2.2V      -52.46mA   -51.75mA   -53.91mA
[POWER Clamp]
|   Voltage   I(typ)   I(min)   I(max)
-1.1V     3.036mA    3.636mA    2.186mA
-1.041V   2.347mA    2.931mA    1.626mA
-977.9mV  1.724mA    2.242mA    1.161mA
-911.9mV  1.201mA    1.611mA    764.6uA
-855.8mV  838uA      1.172mA    552.2uA
-779.9mV  448.1uA    702.1uA    396.3uA
-710.6mV  232.3uA    359.2uA    273.1uA
-657.8mV  146.8uA    178.9uA    190.7uA
-595.1mV  80.81uA    68.31uA    109.3uA
-486.2mV  16.75uA    10.14uA    20.98uA
-374mV    1.39uA     1.002uA    1.123uA
2.2V      0A         0A         0A
[Ramp]
|   typ   min   max
| 20% - 80%
dV/dt_r   221.22m/36.40p   213.62m/40.11p   235.38m/33.15p
dV/dt_f   85.18m/71.31p   76.66m/83.98p   100.84m/60.39p
| 25% - 75%
|dV/dt_r   184.35m/28.97p   178.02m/31.94p   196.15m/26.38p
|dV/dt_f   70.98m/56.62p   63.89m/66.35p   84.03m/48.03p
R_load = 50
[Rising Waveform]
R_fixture = 50
V_fixture = 0.0
|   Time   V(typ)   V(min)   V(max)
0s        1.179mV    982.5uV    861.3uV
56ps      992.8uV    -24.53uV   9.408mV
64ps      4.531mV    -287.5uV   40.73mV
75ps      17.42mV    2.546mV    129.2mV
100ps     173.6mV    35.86mV    304.4mV
115ps     263.4mV    118mV      352.6mV
131ps     319.5mV    215.8mV    376.6mV
155ps     355.5mV    305.9mV    389.3mV
185ps     367.4mV    345.4mV    392.6mV
382ps     369.9mV    357mV      393.2mV
[Falling Waveform]
R_fixture   = 50
V_fixture   = 1.1
V_fixture_min = 1.06
V_fixture_max = 1.17
|   Time   V(typ)   V(min)   V(max)
0s        1.1V       1.06V      1.17V
48ps      1.101V     1.06V      1.171V
69ps      1.099V     1.061V     1.162V
96ps      1.082V     1.051V     1.107V
122ps     1.044V     1.037V     1.059V
148ps     1.01V      1.011V     1.031V
168ps     991.4mV    989mV      1.019V
204ps     972.4mV    960.8mV    1.009V
244ps     963.4mV    944.4mV    1.004V
382ps     958mV      932.2mV    1.002V
[Rising Waveform]
R_fixture   = 50
V_fixture   = 1.1
V_fixture_min = 1.06
V_fixture_max = 1.17
|   Time   V(typ)   V(min)   V(max)
0s        957.9mV    931.6mV    1.002V
44ps      955.9mV    930.5mV    1.001V
54ps      956.7mV    928.1mV    1.016V
68ps      977.9mV    930.6mV    1.062V
82ps      1.016V     953mV      1.098V
99ps      1.049V     995mV      1.123V
115ps     1.066V     1.022V     1.139V
141ps     1.082V     1.041V     1.154V
204ps     1.096V     1.056V     1.166V
382ps     1.1V       1.06V      1.17V
[Falling Waveform]
R_fixture = 50
V_fixture = 0.0
|   Time   V(typ)   V(min)   V(max)
0s        370mV      357.1mV    393.3mV
58ps      376.8mV    361.7mV    389.8mV
72ps      368.1mV    371.7mV    317.5mV
84ps      313.7mV    365.7mV    217.7mV
95ps      237.9mV    327.8mV    154.4mV
112ps     145.1mV    228.5mV    92.56mV
144ps     59.11mV    96.56mV    36.11mV
172ps     27.65mV    46.04mV    16.17mV
210ps     10.36mV    17.6mV     5.792mV
382ps     1.312mV    1.251mV    919.1uV
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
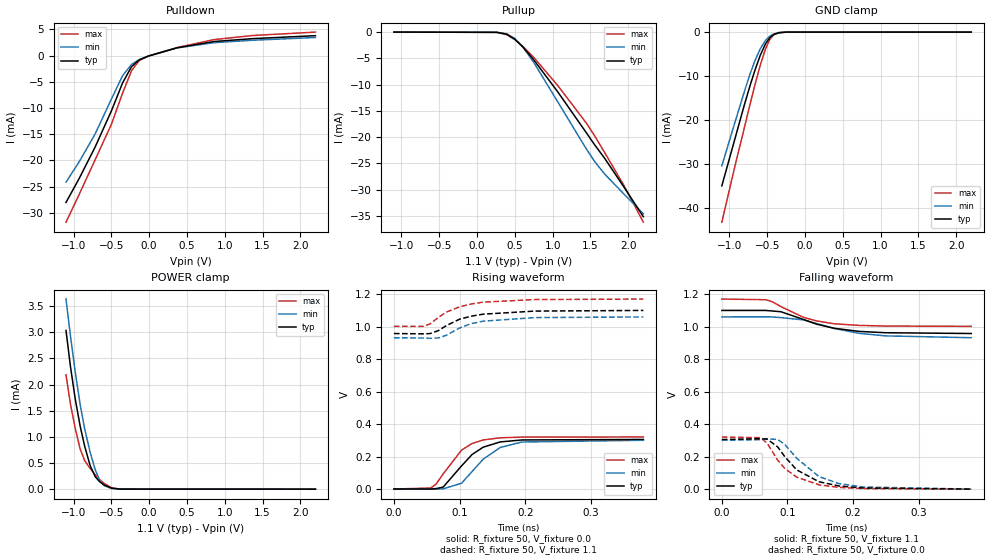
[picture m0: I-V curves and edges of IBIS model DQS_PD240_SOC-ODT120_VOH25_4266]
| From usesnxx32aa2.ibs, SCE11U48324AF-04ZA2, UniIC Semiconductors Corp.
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| DQS_PD240_SOC-ODT120_VOH25_4266
| (240 Ohm Pulldown, 120 Ohm System ODT Setting, VOH=VDDQ/2.5, 3200-4266Mbps)
[Model]   DQS_PD240_SOC-ODT120_VOH25_4266
Model_type   I/O
Vinl = 160.000mV
Vinh = 280.000mV
Vmeas = 220.000mV
Vref = 0.0mV
Cref = 0.0pF
Rref = 120.000Ohm
|   typ   min   max
|C_comp   0.838pF   0.788pF   0.888pF
C_comp_pullup   0.4190pF   0.3940pF   0.4440pF
C_comp_pulldown   0.4190pF   0.3940pF   0.4440pF
| Note: C_comp changes when the ODT circuit is enabled.
[Model Spec]
| Input threshold voltage corners
Vinl   0.1600V   0.1520V   0.1740V
Vinh   0.2800V   0.2720V   0.2940V
| Measurement voltage corners
Vmeas   0.2200V   0.2120V   0.2340V
| Timing spec test load voltage corners
Vref   0.0000V   0.0000V   0.0000V
| Dynamic Overshoot Parameters from LPDDR4 Specification
D_overshoot_ampl_h   0.30   NA   NA
D_overshoot_ampl_l   0.30   NA   NA
D_overshoot_area_h   0.1n   NA   NA
D_overshoot_area_l   0.1n   NA   NA
[Receiver Thresholds]
Vcross_low   = 160.0mV
Vcross_high  = 280.0mV
Vdiff_ac   = 120mV
Vdiff_dc   = 120mV
Tdiffslew_ac = 10.000ns |Not specified, so set to high value
[Voltage Range]   1.1000V   1.0600V   1.1700V
[Pullup Reference]   1.1000V   1.0600V   1.1700V
| Junction Temperature (Ambient temp is 35C typ 95C min -40C max)
[Temperature Range]   50.0   110.0   -40.0
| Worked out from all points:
|   slope of the pulldown table from 0 to 0.165 V, typ, clamps not added: 222 ohm
|   slope of the pullup table from 0 to 0.165 V, typ, clamps not added: 26.4 kohm
|   GND clamp passes 1 mA (typ) near -0.45 V on its own axis
|   POWER clamp passes 1 mA (typ) near -0.88 V on its own axis
|   rising waveform, R_fixture 50, V_fixture 0.0: 20-80 % time 41.7ps typ, 45.2ps min, 38.1ps max; typ from 0.001 V to 0.306 V
|   falling waveform, R_fixture 50, V_fixture 1.1: 20-80 % time 69.4ps typ, 80.3ps min, 59.6ps max; typ from 1.1 V to 0.958 V
|   rising waveform, R_fixture 50, V_fixture 1.1: 20-80 % time 54.4ps typ, 52.6ps min, 53ps max; typ from 0.958 V to 1.1 V
|   falling waveform, R_fixture 50, V_fixture 0.0: 20-80 % time 49.3ps typ, 53.5ps min, 45.4ps max; typ from 0.306 V to 0.001 V
[Pulldown]
|   Voltage   I(typ)   I(min)   I(max)
-1.1V     -28.01mA   -24.15mA   -31.78mA
-921.8mV  -23.33mA   -20.16mA   -26.36mA
-713.9mV  -17.41mA   -14.92mA   -19.85mA
-499.4mV  -10.54mA   -8.281mA   -13.1mA
-350.9mV  -5.177mA   -3.801mA   -7.118mA
-232.1mV  -2.078mA   -1.646mA   -2.853mA
-133.1mV  -833.1uA   -756.2uA   -927.7uA
-14.3mV   -91.58uA   -86.5uA    -84.72uA
368.5mV   1.504mA    1.477mA    1.546mA
856.9mV   2.701mA    2.483mA    3.07mA
1.372V    3.259mA    2.95mA     3.853mA
2.2V      3.818mA    3.475mA    4.505mA
[GND Clamp]
|   Voltage   I(typ)   I(min)   I(max)
-1.1V     -34.89mA   -30.35mA   -43.14mA
-935mV    -24.72mA   -20.96mA   -31.01mA
-799.7mV  -16.38mA   -13.37mA   -21.53mA
-723.8mV  -11.98mA   -9.378mA   -16.19mA
-664.4mV  -8.771mA   -6.596mA   -12.13mA
-591.8mV  -5.275mA   -3.797mA   -7.53mA
-522.5mV  -2.67mA    -1.905mA   -3.825mA
-466.4mV  -1.296mA   -943.6uA   -1.694mA
-413.6mV  -564.3uA   -416.5uA   -620.8uA
-347.6mV  -154.3uA   -117.6uA   -135.2uA
-248.6mV  -12.13uA   -10.9uA    -7.04uA
2.2V      0A         0A         0A
[Pullup]
|   Voltage   I(typ)   I(min)   I(max)
-1.1V     2.741uA    4.96uA     908.5nA
262.9mV   -43.26uA   -41.96uA   -44.33uA
391.6mV   -402.7uA   -334.2uA   -480.6uA
500.5mV   -1.366mA   -1.225mA   -1.434mA
609.4mV   -2.883mA   -2.886mA   -2.766mA
754.6mV   -5.36mA    -5.879mA   -4.882mA
1.065V    -11.32mA   -13.21mA   -10.13mA
1.441V    -19.06mA   -22.13mA   -17.22mA
1.556V    -21.46mA   -24.64mA   -19.74mA
1.688V    -24.02mA   -27.01mA   -22.93mA
1.943V    -29.49mA   -30.82mA   -29.2mA
2.2V      -35.14mA   -34.59mA   -36.18mA
[POWER Clamp]
|   Voltage   I(typ)   I(min)   I(max)
-1.1V     3.036mA    3.636mA    2.186mA
-1.041V   2.347mA    2.931mA    1.626mA
-977.9mV  1.724mA    2.242mA    1.161mA
-911.9mV  1.201mA    1.611mA    764.8uA
-852.5mV  818.5uA    1.149mA    543.7uA
-779.9mV  448uA      701.8uA    396.3uA
-713.9mV  239.2uA    373.2uA    278.6uA
-654.5mV  142.7uA    170.4uA    185.9uA
-595.1mV  80.81uA    68.33uA    109.2uA
-496.1mV  20.1uA     12.34uA    25.7uA
-387.2mV  1.89uA     1.297uA    1.609uA
2.2V      0A         0A         0A
[Ramp]
|   typ   min   max
| 20% - 80%
dV/dt_r   183.02m/41.67p   180.14m/45.21p   192.34m/38.06p
dV/dt_f   85.17m/69.60p   76.67m/80.00p   100.83m/59.62p
| 25% - 75%
|dV/dt_r   152.51m/33.14p   150.12m/36.06p   160.28m/30.27p
|dV/dt_f   70.98m/55.27p   63.89m/63.55p   84.03m/47.34p
R_load = 50
[Rising Waveform]
R_fixture = 50
V_fixture = 0.0
|   Time   V(typ)   V(min)   V(max)
0s        789.4uV    654.9uV    577.2uV
56ps      682.5uV    -69.45uV   6.898mV
64ps      3.102mV    -214.2uV   30.01mV
75ps      12.47mV    1.884mV    93.58mV
103ps     142.9mV    36.35mV    240mV
119ps     212.8mV    107.8mV    280.7mV
136ps     258.4mV    184.6mV    302.8mV
162ps     290.6mV    256.5mV    316mV
195ps     302.7mV    290.1mV    320.2mV
380ps     305.8mV    300.9mV    321.1mV
[Falling Waveform]
R_fixture   = 50
V_fixture   = 1.1
V_fixture_min = 1.06
V_fixture_max = 1.17
|   Time   V(typ)   V(min)   V(max)
0s        1.1V       1.06V      1.17V
67ps      1.1V       1.061V     1.166V
76ps      1.097V     1.06V      1.155V
90ps      1.092V     1.056V     1.124V
124ps     1.045V     1.042V     1.058V
144ps     1.016V     1.02V      1.036V
171ps     990.3mV    989.2mV    1.018V
209ps     971.1mV    959.3mV    1.008V
249ps     962.9mV    943.5mV    1.004V
380ps     958.1mV    932.2mV    1.002V
[Rising Waveform]
R_fixture   = 50
V_fixture   = 1.1
V_fixture_min = 1.06
V_fixture_max = 1.17
|   Time   V(typ)   V(min)   V(max)
0s        957.9mV    931.6mV    1.002V
45ps      955.9mV    930.2mV    1.002V
55ps      957.5mV    928.2mV    1.017V
68ps      976.2mV    930.8mV    1.058V
80ps      1.007V     947.3mV    1.09V
100ps     1.046V     991.9mV    1.122V
117ps     1.064V     1.018V     1.139V
136ps     1.077V     1.034V     1.151V
215ps     1.096V     1.056V     1.167V
380ps     1.1V       1.06V      1.17V
[Falling Waveform]
R_fixture = 50
V_fixture = 0.0
|   Time   V(typ)   V(min)   V(max)
0s        305.9mV    301mV      321.2mV
59ps      311.1mV    305mV      317.4mV
69ps      308.6mV    310.6mV    283.8mV
85ps      260.9mV    306.1mV    179.6mV
96ps      200.1mV    275.7mV    127.7mV
114ps     119.4mV    191mV      74.6mV
148ps     46.34mV    77.85mV    27.44mV
178ps     20.62mV    35.49mV    11.63mV
215ps     7.882mV    13.93mV    4.221mV
380ps     944.5uV    924.7uV    647.9uV
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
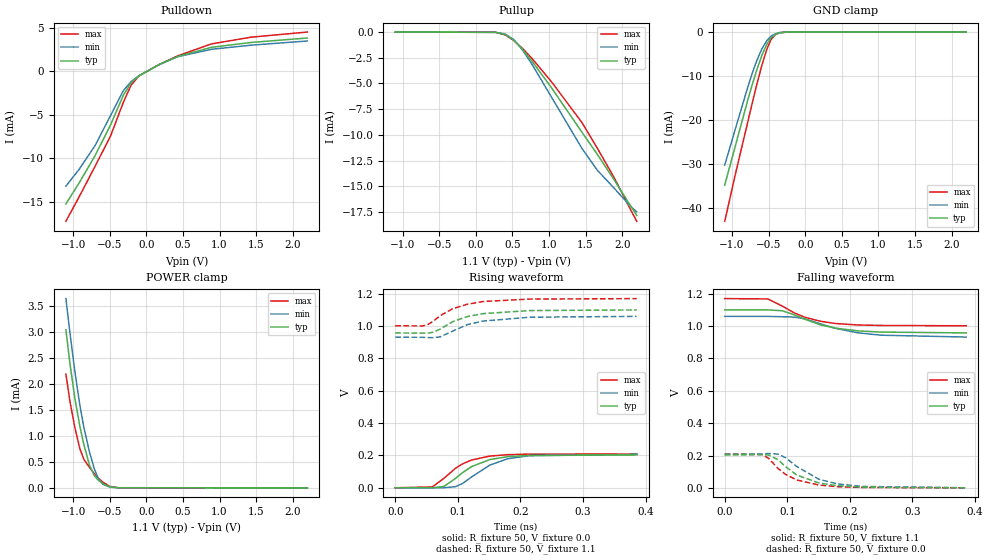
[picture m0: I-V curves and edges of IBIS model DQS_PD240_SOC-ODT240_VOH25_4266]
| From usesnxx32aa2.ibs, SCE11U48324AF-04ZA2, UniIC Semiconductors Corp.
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| DQS_PD240_SOC-ODT240_VOH25_4266
| (240 Ohm Pulldown, 240 Ohm System ODT Setting, VOH=VDDQ/2.5, 3200-4266Mbps)
[Model]   DQS_PD240_SOC-ODT240_VOH25_4266
Model_type   I/O
Vinl = 160.000mV
Vinh = 280.000mV
Vmeas = 220.000mV
Vref = 0.0mV
Cref = 0.0pF
Rref = 240.000Ohm
|   typ   min   max
|C_comp   0.838pF   0.788pF   0.888pF
C_comp_pullup   0.4190pF   0.3940pF   0.4440pF
C_comp_pulldown   0.4190pF   0.3940pF   0.4440pF
| Note: C_comp changes when the ODT circuit is enabled.
[Model Spec]
| Input threshold voltage corners
Vinl   0.1600V   0.1520V   0.1740V
Vinh   0.2800V   0.2720V   0.2940V
| Measurement voltage corners
Vmeas   0.2200V   0.2120V   0.2340V
| Timing spec test load voltage corners
Vref   0.0000V   0.0000V   0.0000V
| Dynamic Overshoot Parameters from LPDDR4 Specification
D_overshoot_ampl_h   0.30   NA   NA
D_overshoot_ampl_l   0.30   NA   NA
D_overshoot_area_h   0.1n   NA   NA
D_overshoot_area_l   0.1n   NA   NA
[Receiver Thresholds]
Vcross_low   = 160.0mV
Vcross_high  = 280.0mV
Vdiff_ac   = 120mV
Vdiff_dc   = 120mV
Tdiffslew_ac = 10.000ns |Not specified, so set to high value
[Voltage Range]   1.1000V   1.0600V   1.1700V
[Pullup Reference]   1.1000V   1.0600V   1.1700V
| Junction Temperature (Ambient temp is 35C typ 95C min -40C max)
[Temperature Range]   50.0   110.0   -40.0
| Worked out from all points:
|   slope of the pulldown table from 0 to 0.165 V, typ, clamps not added: 225 ohm
|   slope of the pullup table from 0 to 0.165 V, typ, clamps not added: 53.3 kohm
|   GND clamp passes 1 mA (typ) near -0.45 V on its own axis
|   POWER clamp passes 1 mA (typ) near -0.88 V on its own axis
|   rising waveform, R_fixture 50, V_fixture 0.0: 20-80 % time 49.4ps typ, 53.6ps min, 45.6ps max; typ from 0 V to 0.203 V
|   falling waveform, R_fixture 50, V_fixture 1.1: 20-80 % time 68.1ps typ, 76.6ps min, 58.8ps max; typ from 1.1 V to 0.958 V
|   rising waveform, R_fixture 50, V_fixture 1.1: 20-80 % time 56.9ps typ, 58.9ps min, 53.9ps max; typ from 0.958 V to 1.1 V
|   falling waveform, R_fixture 50, V_fixture 0.0: 20-80 % time 50.4ps typ, 55.3ps min, 46.1ps max; typ from 0.203 V to 0.001 V
[Pulldown]
|   Voltage   I(typ)   I(min)   I(max)
-1.1V     -15.26mA   -13.22mA   -17.26mA
-915.2mV  -12.8mA    -11.24mA   -14.39mA
-700.7mV  -9.701mA   -8.547mA   -10.93mA
-489.5mV  -6.173mA   -5.093mA   -7.445mA
-314.6mV  -2.761mA   -2.235mA   -3.572mA
-209mV    -1.332mA   -1.185mA   -1.601mA
-100.1mV  -523.2uA   -506.5uA   -530.7uA
170.5mV   746.3uA    741.4uA    745uA
427.9mV   1.702mA    1.662mA    1.769mA
889.9mV   2.749mA    2.521mA    3.143mA
1.434V    3.31mA     2.996mA    3.917mA
2.2V      3.818mA    3.475mA    4.505mA
[GND Clamp]
|   Voltage   I(typ)   I(min)   I(max)
-1.1V     -34.89mA   -30.33mA   -43.14mA
-944.9mV  -25.34mA   -21.52mA   -31.72mA
-793.1mV  -15.99mA   -13.01mA   -21.07mA
-723.8mV  -11.98mA   -9.379mA   -16.19mA
-664.4mV  -8.772mA   -6.596mA   -12.13mA
-591.8mV  -5.273mA   -3.797mA   -7.531mA
-522.5mV  -2.679mA   -1.904mA   -3.826mA
-469.7mV  -1.366mA   -988.3uA   -1.793mA
-413.6mV  -570.1uA   -416.8uA   -623.3uA
-347.6mV  -154.3uA   -117.7uA   -135.1uA
-238.7mV  -9.037uA   -8.394uA   -5.027uA
2.2V      0A         0A         0A
[Pullup]
|   Voltage   I(typ)   I(min)   I(max)
-1.1V     1.371uA    2.481uA    454.5nA
269.5mV   -24.58uA   -23.65uA   -25.87uA
401.5mV   -232.2uA   -192.7uA   -274uA
517mV     -788.9uA   -720.9uA   -813.2uA
629.2mV   -1.613mA   -1.645mA   -1.529mA
761.2mV   -2.768mA   -3.054mA   -2.513mA
1.032V    -5.393mA   -6.298mA   -4.813mA
1.448V    -9.715mA   -11.29mA   -8.771mA
1.662V    -11.91mA   -13.45mA   -11.32mA
1.887V    -14.33mA   -15.16mA   -14.11mA
2.114V    -16.89mA   -16.95mA   -17.27mA
2.2V      -17.84mA   -17.49mA   -18.41mA
[POWER Clamp]
|   Voltage   I(typ)   I(min)   I(max)
-1.1V     3.036mA    3.636mA    2.186mA
-1.044V   2.383mA    2.969mA    1.654mA
-977.9mV  1.724mA    2.242mA    1.161mA
-908.6mV  1.178mA    1.583mA    748.1uA
-852.5mV  818.4uA    1.149mA    543.8uA
-776.6mV  434.5uA    683.8uA    390.2uA
-710.6mV  232.3uA    359.2uA    273.1uA
-657.8mV  146.8uA    178.8uA    190.7uA
-595.1mV  80.8uA     68.3uA     109.2uA
-502.7mV  22.71uA    14.04uA    29.29uA
-387.2mV  1.893uA    1.293uA    1.618uA
2.2V      0A         0A         0A
[Ramp]
|   typ   min   max
| 20% - 80%
dV/dt_r   121.70m/49.37p   124.06m/53.57p   125.51m/45.62p
dV/dt_f   85.19m/68.04p   76.66m/76.74p   100.85m/58.97p
| 25% - 75%
|dV/dt_r   101.42m/39.28p   103.38m/42.76p   104.59m/36.19p
|dV/dt_f   70.99m/54.15p   63.88m/61.15p   84.04m/46.74p
R_load = 50
[Rising Waveform]
R_fixture = 50
V_fixture = 0.0
|   Time   V(typ)   V(min)   V(max)
0s        393.8uV    322.1uV    289.7uV
59ps      231.1uV    -105.2uV   5.269mV
78ps      9.052mV    587.2uV    59.72mV
96ps      57.63mV    7.027mV    120.2mV
107ps     92.52mV    25.58mV    147mV
122ps     131.3mV    67.07mV    172mV
151ps     174.7mV    140.4mV    196.2mV
180ps     192.8mV    180mV      205mV
214ps     200.1mV    198.6mV    208.2mV
386ps     203.2mV    207.1mV    209.5mV
[Falling Waveform]
R_fixture   = 50
V_fixture   = 1.1
V_fixture_min = 1.06
V_fixture_max = 1.17
|   Time   V(typ)   V(min)   V(max)
0s        1.1V       1.06V      1.17V
69ps      1.1V       1.06V      1.168V
92ps      1.095V     1.058V     1.124V
111ps     1.07V      1.056V     1.082V
127ps     1.044V     1.046V     1.056V
153ps     1.008V     1.014V     1.03V
177ps     987.3mV    986.2mV    1.016V
213ps     970.4mV    958.4mV    1.007V
250ps     963mV      943.8mV    1.004V
386ps     958mV      932.2mV    1.002V
[Rising Waveform]
R_fixture   = 50
V_fixture   = 1.1
V_fixture_min = 1.06
V_fixture_max = 1.17
|   Time   V(typ)   V(min)   V(max)
0s        957.8mV    931.6mV    1.002V
44ps      956.3mV    930.6mV    1.001V
51ps      956.1mV    929.2mV    1.007V
61ps      962.3mV    928.4mV    1.031V
72ps      982.3mV    933.9mV    1.065V
92ps      1.028V     969.3mV    1.108V
115ps     1.059V     1.009V     1.135V
140ps     1.077V     1.031V     1.152V
215ps     1.096V     1.055V     1.167V
386ps     1.1V       1.06V      1.17V
[Falling Waveform]
R_fixture = 50
V_fixture = 0.0
|   Time   V(typ)   V(min)   V(max)
0s        203.3mV    207.2mV    209.5mV
59ps      205.9mV    209.3mV    206.7mV
70ps      203.5mV    212.6mV    183.6mV
85ps      174.6mV    208.9mV    120.7mV
97ps      132mV      187.3mV    83.83mV
115ps     79.71mV    132.2mV    49.09mV
151ps     29.71mV    52.42mV    17.13mV
180ps     13.54mV    24.77mV    7.414mV
220ps     4.837mV    9.043mV    2.495mV
386ps     521.9uV    560uV      331.5uV
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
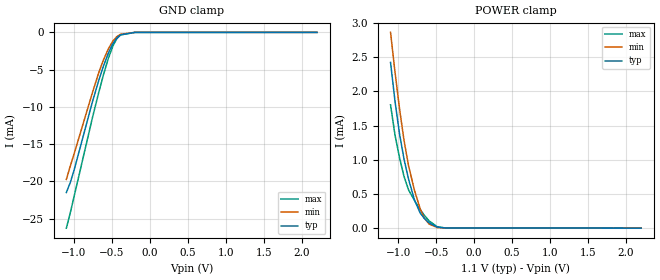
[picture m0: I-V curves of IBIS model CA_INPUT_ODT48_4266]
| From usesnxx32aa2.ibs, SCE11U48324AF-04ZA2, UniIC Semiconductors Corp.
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| CA_INPUT_ODT48_4266 (with 48ohm ODT, 3200-4266Mbps)
[Model]   CA_INPUT_ODT48_4266
Model_type   Input
Vinl = 110.833mV
Vinh = 255.833mV
|   typ   min   max
|C_comp   0.562pF   0.508pF   0.628pF
C_comp_power_clamp   0.2810pF   0.2540pF   0.3140pF
C_comp_gnd_clamp   0.2810pF   0.2540pF   0.3140pF
| Note: C_comp changes when the ODT circuit is enabled.
[Model Spec]
| Input threshold voltage corners
Vinl   0.1108V   0.1042V   0.1225V
Vinh   0.2558V   0.2492V   0.2675V
| Dynamic Overshoot Parameters from LPDDR4 Specification
D_overshoot_ampl_h   0.30   NA   NA
D_overshoot_ampl_l   0.30   NA   NA
D_overshoot_area_h   0.1n   NA   NA
D_overshoot_area_l   0.1n   NA   NA
[Receiver Thresholds]
Vth   = 0.1833V
Vth_min  = 0.1800V
Vth_max  = 0.1866V
Vinh_ac  = 0.072V
Vinh_dc  = 0.072V
Vinl_ac  = -0.072V
Vinl_dc  = -0.072V
Tslew_ac = 5.000ns |Not specified, so set to high value
Threshold_sensitivity = 0.1667
Reference_supply Power_clamp_ref
[Voltage Range]   1.1000V   1.0600V   1.1700V
[POWER Clamp Reference]   1.1000V   1.0600V   1.1700V
| Junction Temperature (Ambient temp is 35C typ 95C min -40C max)
[Temperature Range]   50.0   110.0   -40.0
[Add Submodel]
| Submodel Name   Mode
48ohm_ODT_4266   Non-Driving
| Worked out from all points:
|   GND clamp passes 1 mA (typ) near -0.45 V on its own axis
|   POWER clamp passes 1 mA (typ) near -0.92 V on its own axis
[GND Clamp]
|   Voltage   I(typ)   I(min)   I(max)
-1.1V     -21.5mA    -19.74mA   -26.28mA
-1.05V    -20.21mA   -18mA      -24.3mA
-1.001V   -18.6mA    -16.41mA   -22.15mA
-756.8mV  -9.324mA   -8.096mA   -11.46mA
-674.3mV  -6.48mA    -5.435mA   -8.091mA
-611.6mV  -4.527mA   -3.692mA   -5.689mA
-545.6mV  -2.746mA   -2.177mA   -3.434mA
-486.2mV  -1.497mA   -1.155mA   -1.803mA
-436.7mV  -775.7uA   -585.7uA   -864uA
-387.2mV  -339.6uA   -253.2uA   -334.1uA
-199.1mV  -2.761uA   -2.971uA   -1.176uA
2.2V      0A         0A         0A
[POWER Clamp]
|   Voltage   I(typ)   I(min)   I(max)
-1.1V     2.422mA    2.862mA    1.802mA
-1.041V   1.852mA    2.278mA    1.359mA
-981.2mV  1.374mA    1.741mA    1.027mA
-921.8mV  1.005mA    1.277mA    751.6uA
-862.4mV  713uA      909uA      558.8uA
-783.2mV  406.4uA    545.8uA    401.7uA
-710.6mV  222.9uA    283.8uA    272.7uA
-657.8mV  145uA      149.1uA    190.2uA
-591.8mV  77.53uA    58.55uA    105.1uA
-486.2mV  16.52uA    9.628uA    20.62uA
-370.7mV  1.13uA     773.1nA    818.4nA
2.2V      0A         0A         0A
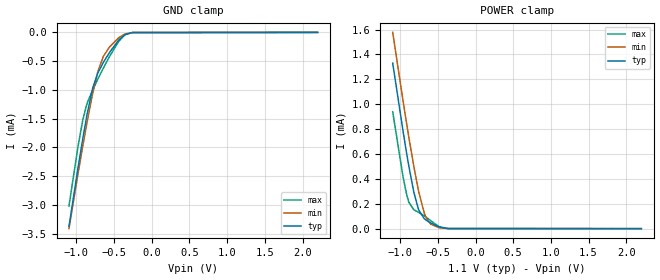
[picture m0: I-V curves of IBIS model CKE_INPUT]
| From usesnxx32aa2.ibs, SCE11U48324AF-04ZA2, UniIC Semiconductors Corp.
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| CKE_INPUT
[Model]   CKE_INPUT
Model_type   Input
Vinl = 275.000mV
Vinh = 825.000mV
|   typ   min   max
|C_comp   0.590pF   0.540pF   0.640pF
C_comp_power_clamp   0.2950pF   0.2700pF   0.3200pF
C_comp_gnd_clamp   0.2950pF   0.2700pF   0.3200pF
[Model Spec]
| Input threshold voltage corners
Vinl   0.2750V   0.2650V   0.2925V
Vinh   0.8250V   0.7950V   0.8775V
| Dynamic Overshoot Parameters from LPDDR4 Specification
D_overshoot_ampl_h   0.35   NA   NA
D_overshoot_ampl_l   0.35   NA   NA
D_overshoot_area_h   0.8n   NA   NA
D_overshoot_area_l   0.8n   NA   NA
[Voltage Range]   1.1000V   1.0600V   1.1700V
| Junction Temperature (Ambient temp is 35C typ 95C min -40C max)
[Temperature Range]   50.0   110.0   -40.0
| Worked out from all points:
|   GND clamp passes 1 mA (typ) near -0.79 V on its own axis
|   POWER clamp passes 1 mA (typ) near -1.02 V on its own axis
[GND Clamp]
|   Voltage   I(typ)   I(min)   I(max)
-1.1V     -3.375mA   -3.413mA   -3.022mA
-981.2mV  -2.368mA   -2.47mA    -1.995mA
-915.2mV  -1.839mA   -1.966mA   -1.514mA
-859.1mV  -1.422mA   -1.556mA   -1.231mA
-786.5mV  -977.9uA   -1.069mA   -1.003mA
-717.2mV  -705.7uA   -684.3uA   -814.1uA
-644.6mV  -523.9uA   -420uA     -624.1uA
-562.1mV  -350.1uA   -254.2uA   -419.8uA
-440mV    -133.3uA   -92.72uA   -156.9uA
-357.5mV  -39.37uA   -28.57uA   -39.78uA
-258.5mV  -3.465uA   -3.32uA    -1.719uA
2.2V      0A         0A         0A
[POWER Clamp]
|   Voltage   I(typ)   I(min)   I(max)
-1.1V     1.33mA     1.577mA    938.9uA
-964.7mV  791.3uA    1.034mA    423.3uA
-915.2mV  606.5uA    844.3uA    274.7uA
-885.5mV  501.3uA    733.2uA    211.6uA
-819.5mV  292.6uA    498.9uA    152uA
-756.8mV  152.2uA    301.6uA    131.2uA
-680.9mV  79.63uA    124uA      102.8uA
-644.6mV  63.86uA    72.95uA    86.66uA
-595.1mV  46.15uA    35.79uA    63.22uA
-482.9mV  12.79uA    7.328uA    15.76uA
-367.4mV  975.3nA    623.2nA    735.4nA
2.2V      0A         0A         0A
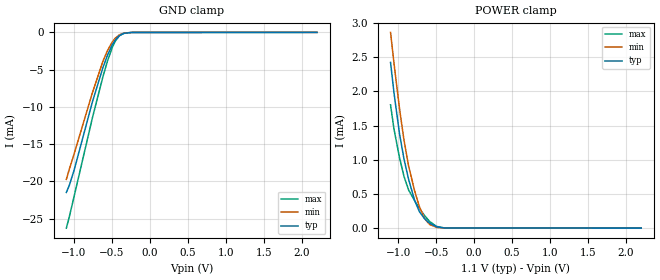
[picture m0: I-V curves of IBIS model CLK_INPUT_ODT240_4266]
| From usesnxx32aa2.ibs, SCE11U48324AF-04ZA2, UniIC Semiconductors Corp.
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| CLK_INPUT_ODT240_4266 (with 240ohm ODT, 3200-4266Mbps)
[Model]   CLK_INPUT_ODT240_4266
Model_type   Input
Vinl = 110.833mV
Vinh = 255.833mV
|   typ   min   max
|C_comp   0.584pF   0.535pF   0.634pF
C_comp_power_clamp   0.2920pF   0.2675pF   0.3170pF
C_comp_gnd_clamp   0.2920pF   0.2675pF   0.3170pF
| Note: C_comp changes when the ODT circuit is enabled.
[Model Spec]
| Input threshold voltage corners
Vinl   0.1108V   0.1042V   0.1225V
Vinh   0.2558V   0.2492V   0.2675V
| Dynamic Overshoot Parameters from LPDDR4 Specification
D_overshoot_ampl_h   0.30   NA   NA
D_overshoot_ampl_l   0.30   NA   NA
D_overshoot_area_h   0.1n   NA   NA
D_overshoot_area_l   0.1n   NA   NA
[Receiver Thresholds]
Vcross_low   = 110.8mV
Vcross_high  = 255.8mV
Vdiff_ac   = 145mV
Vdiff_dc   = 145mV
Tdiffslew_ac = 10.000ns |Not specified, so set to high value
[Voltage Range]   1.1000V   1.0600V   1.1700V
[POWER Clamp Reference]   1.1000V   1.0600V   1.1700V
| Junction Temperature (Ambient temp is 35C typ 95C min -40C max)
[Temperature Range]   50.0   110.0   -40.0
[Add Submodel]
| Submodel Name   Mode
240ohm_ODT_4266   Non-Driving
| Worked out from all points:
|   GND clamp passes 1 mA (typ) near -0.45 V on its own axis
|   POWER clamp passes 1 mA (typ) near -0.92 V on its own axis
[GND Clamp]
|   Voltage   I(typ)   I(min)   I(max)
-1.1V     -21.49mA   -19.74mA   -26.28mA
-1.06V    -20.5mA    -18.33mA   -24.72mA
-997.7mV  -18.49mA   -16.31mA   -22mA
-756.8mV  -9.322mA   -8.097mA   -11.46mA
-618.2mV  -4.723mA   -3.864mA   -5.933mA
-558.8mV  -3.074mA   -2.451mA   -3.855mA
-496.1mV  -1.677mA   -1.3mA     -2.041mA
-456.5mV  -1.029mA   -782.1uA   -1.19mA
-400.4mV  -428.1uA   -321.9uA   -441.2uA
-341mV    -132.5uA   -99.94uA   -112.2uA
-238.7mV  -8.833uA   -8.469uA   -5.263uA
2.2V      0A         0A         0A
[POWER Clamp]
|   Voltage   I(typ)   I(min)   I(max)
-1.1V     2.422mA    2.862mA    1.802mA
-1.054V   1.972mA    2.404mA    1.445mA
-981.2mV  1.374mA    1.741mA    1.026mA
-921.8mV  1.005mA    1.277mA    751.6uA
-862.4mV  713.8uA    909.1uA    558.4uA
-783.2mV  406.1uA    545.8uA    401.7uA
-720.5mV  241.6uA    314uA      289.4uA
-651.2mV  136.9uA    138.7uA    180.8uA
-585.2mV  72.12uA    53.01uA    97.86uA
-496.1mV  19.87uA    11.7uA     25.4uA
-383.9mV  1.596uA    1.034uA    1.266uA
2.2V      0A         0A         0A
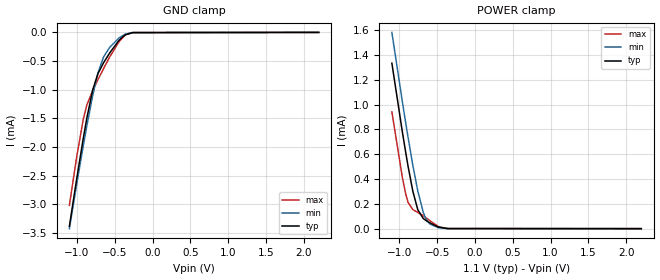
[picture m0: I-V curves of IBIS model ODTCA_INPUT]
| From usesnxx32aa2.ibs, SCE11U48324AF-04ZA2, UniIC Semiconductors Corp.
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| ODTCA_INPUT
[Model]   ODTCA_INPUT
Model_type   Input
Vinl = 275.000mV
Vinh = 825.000mV
|   typ   min   max
|C_comp   0.548pF   0.498pF   0.598pF
C_comp_power_clamp   0.2740pF   0.2490pF   0.2990pF
C_comp_gnd_clamp   0.2740pF   0.2490pF   0.2990pF
[Model Spec]
| Input threshold voltage corners
Vinl   0.2750V   0.2650V   0.2925V
Vinh   0.8250V   0.7950V   0.8775V
| Dynamic Overshoot Parameters from LPDDR4 Specification
[Voltage Range]   1.1000V   1.0600V   1.1700V
| Junction Temperature (Ambient temp is 35C typ 95C min -40C max)
[Temperature Range]   50.0   110.0   -40.0
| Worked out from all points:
|   GND clamp passes 1 mA (typ) near -0.79 V on its own axis
|   POWER clamp passes 1 mA (typ) near -1.02 V on its own axis
[GND Clamp]
|   Voltage   I(typ)   I(min)   I(max)
-1.1V     -3.387mA   -3.428mA   -3.022mA
-1.001V   -2.541mA   -2.637mA   -2.156mA
-915.2mV  -1.845mA   -1.975mA   -1.512mA
-869mV    -1.498mA   -1.634mA   -1.268mA
-789.8mV  -996.4uA   -1.094mA   -1.01mA
-720.5mV  -716uA     -702uA     -822.2uA
-647.9mV  -531.6uA   -429.6uA   -632.5uA
-565.4mV  -357uA     -259.7uA   -427.7uA
-443.3mV  -138.3uA   -96.09uA   -163.1uA
-360.8mV  -41.98uA   -30.28uA   -42.9uA
-261.8mV  -3.814uA   -3.599uA   -1.947uA
2.2V      0A         0A         0A
[POWER Clamp]
|   Voltage   I(typ)   I(min)   I(max)
-1.1V     1.334mA    1.582mA    941.4uA
-961.4mV  780.5uA    1.024mA    413uA
-915.2mV  607.9uA    846.4uA    275.4uA
-885.5mV  502.3uA    735uA      211.6uA
-822.8mV  302.2uA    511.1uA    153.4uA
-756.8mV  152.1uA    302.1uA    131.2uA
-684.2mV  81.39uA    129.9uA    104.2uA
-647.9mV  65.14uA    76.7uA     88.16uA
-598.4mV  47.3uA     37.48uA    64.82uA
-482.9mV  12.83uA    7.361uA    15.77uA
-364.1mV  880.4nA    591nA      652.2nA
2.2V      0A         0A         0A
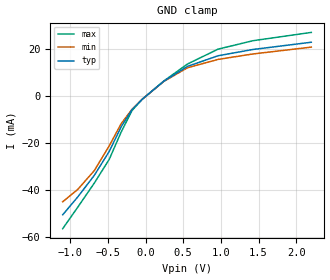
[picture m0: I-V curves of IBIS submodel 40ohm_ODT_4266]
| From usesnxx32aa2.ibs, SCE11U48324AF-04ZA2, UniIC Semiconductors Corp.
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| SUBMODEL 40ohm_ODT_4266
[Submodel]   40ohm_ODT_4266
Submodel_type   Dynamic_clamp
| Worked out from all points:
|   GND clamp passes 1 mA (typ) near -0.03 V on its own axis
[GND Clamp]
|   Voltage   I(typ)   I(min)   I(max)
-1.1V     -50.63mA   -45.07mA   -56.55mA
-898.7mV  -42.96mA   -39.76mA   -47.32mA
-680.9mV  -33.81mA   -31.77mA   -37.11mA
-482.9mV  -23.62mA   -21.23mA   -26.99mA
-324.5mV  -13.11mA   -11.78mA   -15.35mA
-179.3mV  -5.754mA   -5.57mA    -6.113mA
-44mV     -1.311mA   -1.303mA   -1.289mA
243.1mV   6.393mA    6.309mA    6.494mA
556.6mV   12.72mA    12.13mA    13.72mA
962.5mV   17.24mA    15.68mA    20.07mA
1.425V    19.92mA    18.01mA    23.66mA
2.2V      23.01mA    20.92mA    27.21mA
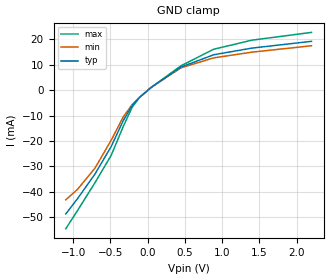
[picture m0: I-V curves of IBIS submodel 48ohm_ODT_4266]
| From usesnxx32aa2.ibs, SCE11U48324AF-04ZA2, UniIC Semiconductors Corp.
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| SUBMODEL 48ohm_ODT_4266
[Submodel]   48ohm_ODT_4266
Submodel_type   Dynamic_clamp
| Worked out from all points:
|   GND clamp passes 1 mA (typ) near -0.04 V on its own axis
[GND Clamp]
|   Voltage   I(typ)   I(min)   I(max)
-1.1V     -48.63mA   -43.09mA   -54.44mA
-944.9mV  -42.74mA   -39.06mA   -47.43mA
-707.3mV  -32.93mA   -30.62mA   -36.33mA
-489.5mV  -22.1mA    -19.61mA   -25.56mA
-327.8mV  -11.92mA   -10.49mA   -14.23mA
-209mV    -6.028mA   -5.692mA   -6.739mA
-110mV    -2.842mA   -2.801mA   -2.871mA
48.4mV    1.126mA    1.122mA    1.124mA
447.7mV   9.081mA    8.787mA    9.594mA
886.6mV   13.92mA    12.7mA     16.09mA
1.398V    16.53mA    14.93mA    19.64mA
2.2V      19.2mA     17.46mA    22.71mA
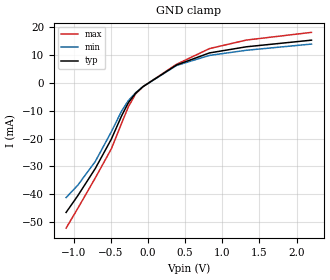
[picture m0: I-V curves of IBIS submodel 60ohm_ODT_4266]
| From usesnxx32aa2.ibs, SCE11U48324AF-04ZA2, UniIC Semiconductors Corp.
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| SUBMODEL 60ohm_ODT_4266
[Submodel]   60ohm_ODT_4266
Submodel_type   Dynamic_clamp
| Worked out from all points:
|   GND clamp passes 1 mA (typ) near -0.05 V on its own axis
[GND Clamp]
|   Voltage   I(typ)   I(min)   I(max)
-1.1V     -46.54mA   -41.2mA    -52.18mA
-944.9mV  -40.62mA   -36.84mA   -45.18mA
-707.3mV  -30.75mA   -28.22mA   -34.14mA
-492.8mV  -20.26mA   -17.62mA   -23.74mA
-350.9mV  -11.69mA   -9.98mA    -14.33mA
-261.8mV  -7.084mA   -6.324mA   -8.533mA
-166.1mV  -3.715mA   -3.555mA   -4.008mA
-63.8mV   -1.311mA   -1.296mA   -1.296mA
385mV     6.425mA    6.267mA    6.692mA
827.2mV   10.77mA    9.879mA    12.32mA
1.325V    12.98mA    11.73mA    15.4mA
2.2V      15.36mA    13.96mA    18.16mA
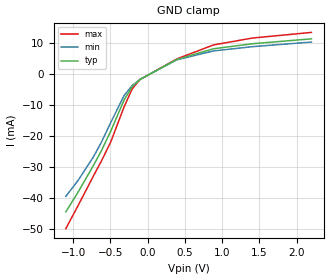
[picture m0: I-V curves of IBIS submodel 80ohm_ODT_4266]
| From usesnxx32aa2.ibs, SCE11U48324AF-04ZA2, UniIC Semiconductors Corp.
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| SUBMODEL 80ohm_ODT_4266
[Submodel]   80ohm_ODT_4266
Submodel_type   Dynamic_clamp
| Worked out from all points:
|   GND clamp passes 1 mA (typ) near -0.06 V on its own axis
[GND Clamp]
|   Voltage   I(typ)   I(min)   I(max)
-1.1V     -44.43mA   -39.42mA   -49.86mA
-935mV    -38.05mA   -34.27mA   -42.39mA
-727.1mV  -29.36mA   -26.58mA   -32.75mA
-621.5mV  -24.64mA   -21.92mA   -27.98mA
-496.1mV  -18.32mA   -15.52mA   -21.83mA
-314.6mV  -8.147mA   -6.757mA   -10.35mA
-209mV    -3.994mA   -3.615mA   -4.737mA
-103.4mV  -1.651mA   -1.603mA   -1.672mA
391.6mV   4.822mA    4.711mA    5.007mA
883.3mV   8.277mA    7.574mA    9.511mA
1.408V    9.904mA    8.957mA    11.75mA
2.2V      11.49mA    10.45mA    13.57mA
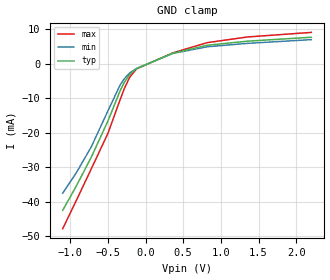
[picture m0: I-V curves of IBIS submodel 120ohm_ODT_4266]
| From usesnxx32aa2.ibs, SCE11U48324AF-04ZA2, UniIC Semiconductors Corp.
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| SUBMODEL 120ohm_ODT_4266
[Submodel]   120ohm_ODT_4266
Submodel_type   Dynamic_clamp
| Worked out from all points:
|   GND clamp passes 1 mA (typ) near -0.09 V on its own axis
[GND Clamp]
|   Voltage   I(typ)   I(min)   I(max)
-1.1V     -42.43mA   -37.47mA   -47.75mA
-921.8mV  -35.52mA   -31.66mA   -39.7mA
-720.5mV  -27.03mA   -24.04mA   -30.43mA
-499.4mV  -16.56mA   -13.63mA   -20.14mA
-337.7mV  -7.828mA   -6.137mA   -10.39mA
-284.9mV  -5.488mA   -4.4mA     -7.344mA
-215.6mV  -3.216mA   -2.772mA   -4.079mA
-123.2mV  -1.444mA   -1.369mA   -1.534mA
358.6mV   3.022mA    2.957mA    3.128mA
817.3mV   5.348mA    4.913mA    6.104mA
1.352V    6.53mA     5.901mA    7.75mA
2.2V      7.677mA    6.979mA    9.076mA
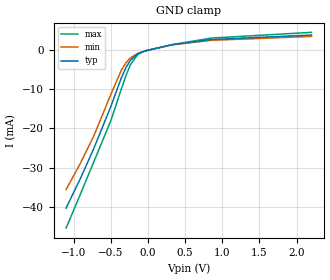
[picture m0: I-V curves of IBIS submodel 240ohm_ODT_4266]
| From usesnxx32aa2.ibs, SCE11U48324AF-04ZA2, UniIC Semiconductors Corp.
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| SUBMODEL 240ohm_ODT_4266
[Submodel]   240ohm_ODT_4266
Submodel_type   Dynamic_clamp
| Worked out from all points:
|   GND clamp passes 1 mA (typ) near -0.14 V on its own axis
[GND Clamp]
|   Voltage   I(typ)   I(min)   I(max)
-1.1V     -40.35mA   -35.62mA   -45.48mA
-915.2mV  -33.12mA   -29.19mA   -37.15mA
-727.1mV  -25.13mA   -21.92mA   -28.53mA
-499.4mV  -14.47mA   -11.4mA    -18.1mA
-357.5mV  -7.138mA   -5.158mA   -9.962mA
-294.8mV  -4.475mA   -3.244mA   -6.504mA
-235.4mV  -2.637mA   -2.004mA   -3.786mA
-136.4mV  -971.8uA   -862.2uA   -1.123mA
-37.4mV   -231.3uA   -219.3uA   -220.6uA
322.3mV   1.34mA     1.32mA     1.366mA
847mV     2.685mA    2.471mA    3.047mA
2.2V      3.818mA    3.475mA    4.505mA
